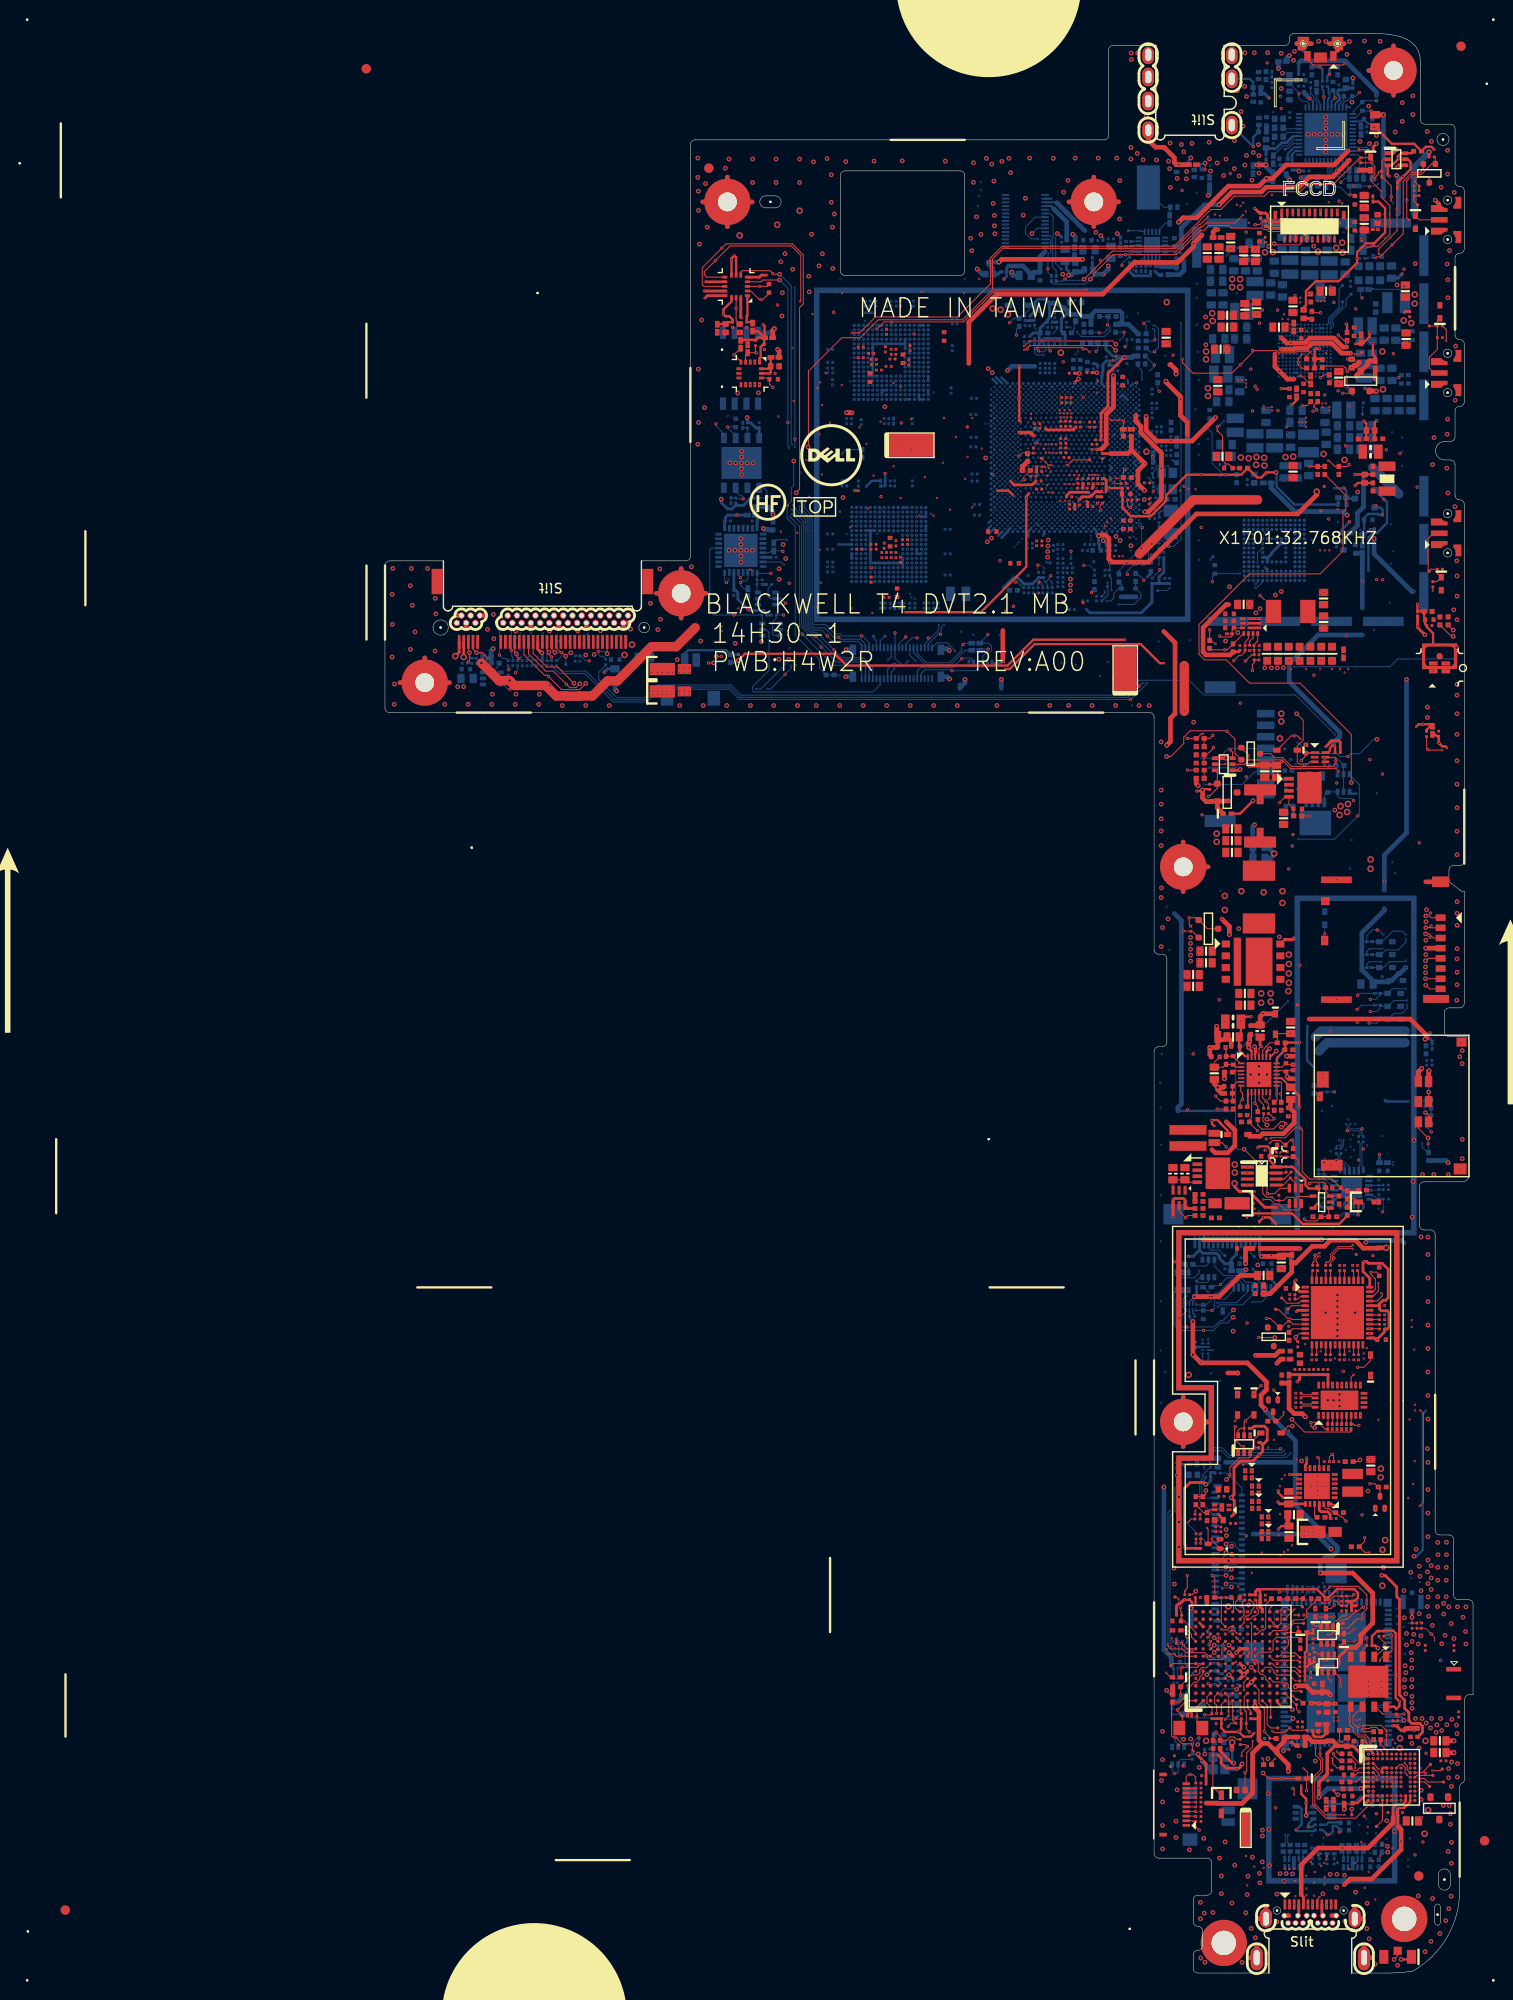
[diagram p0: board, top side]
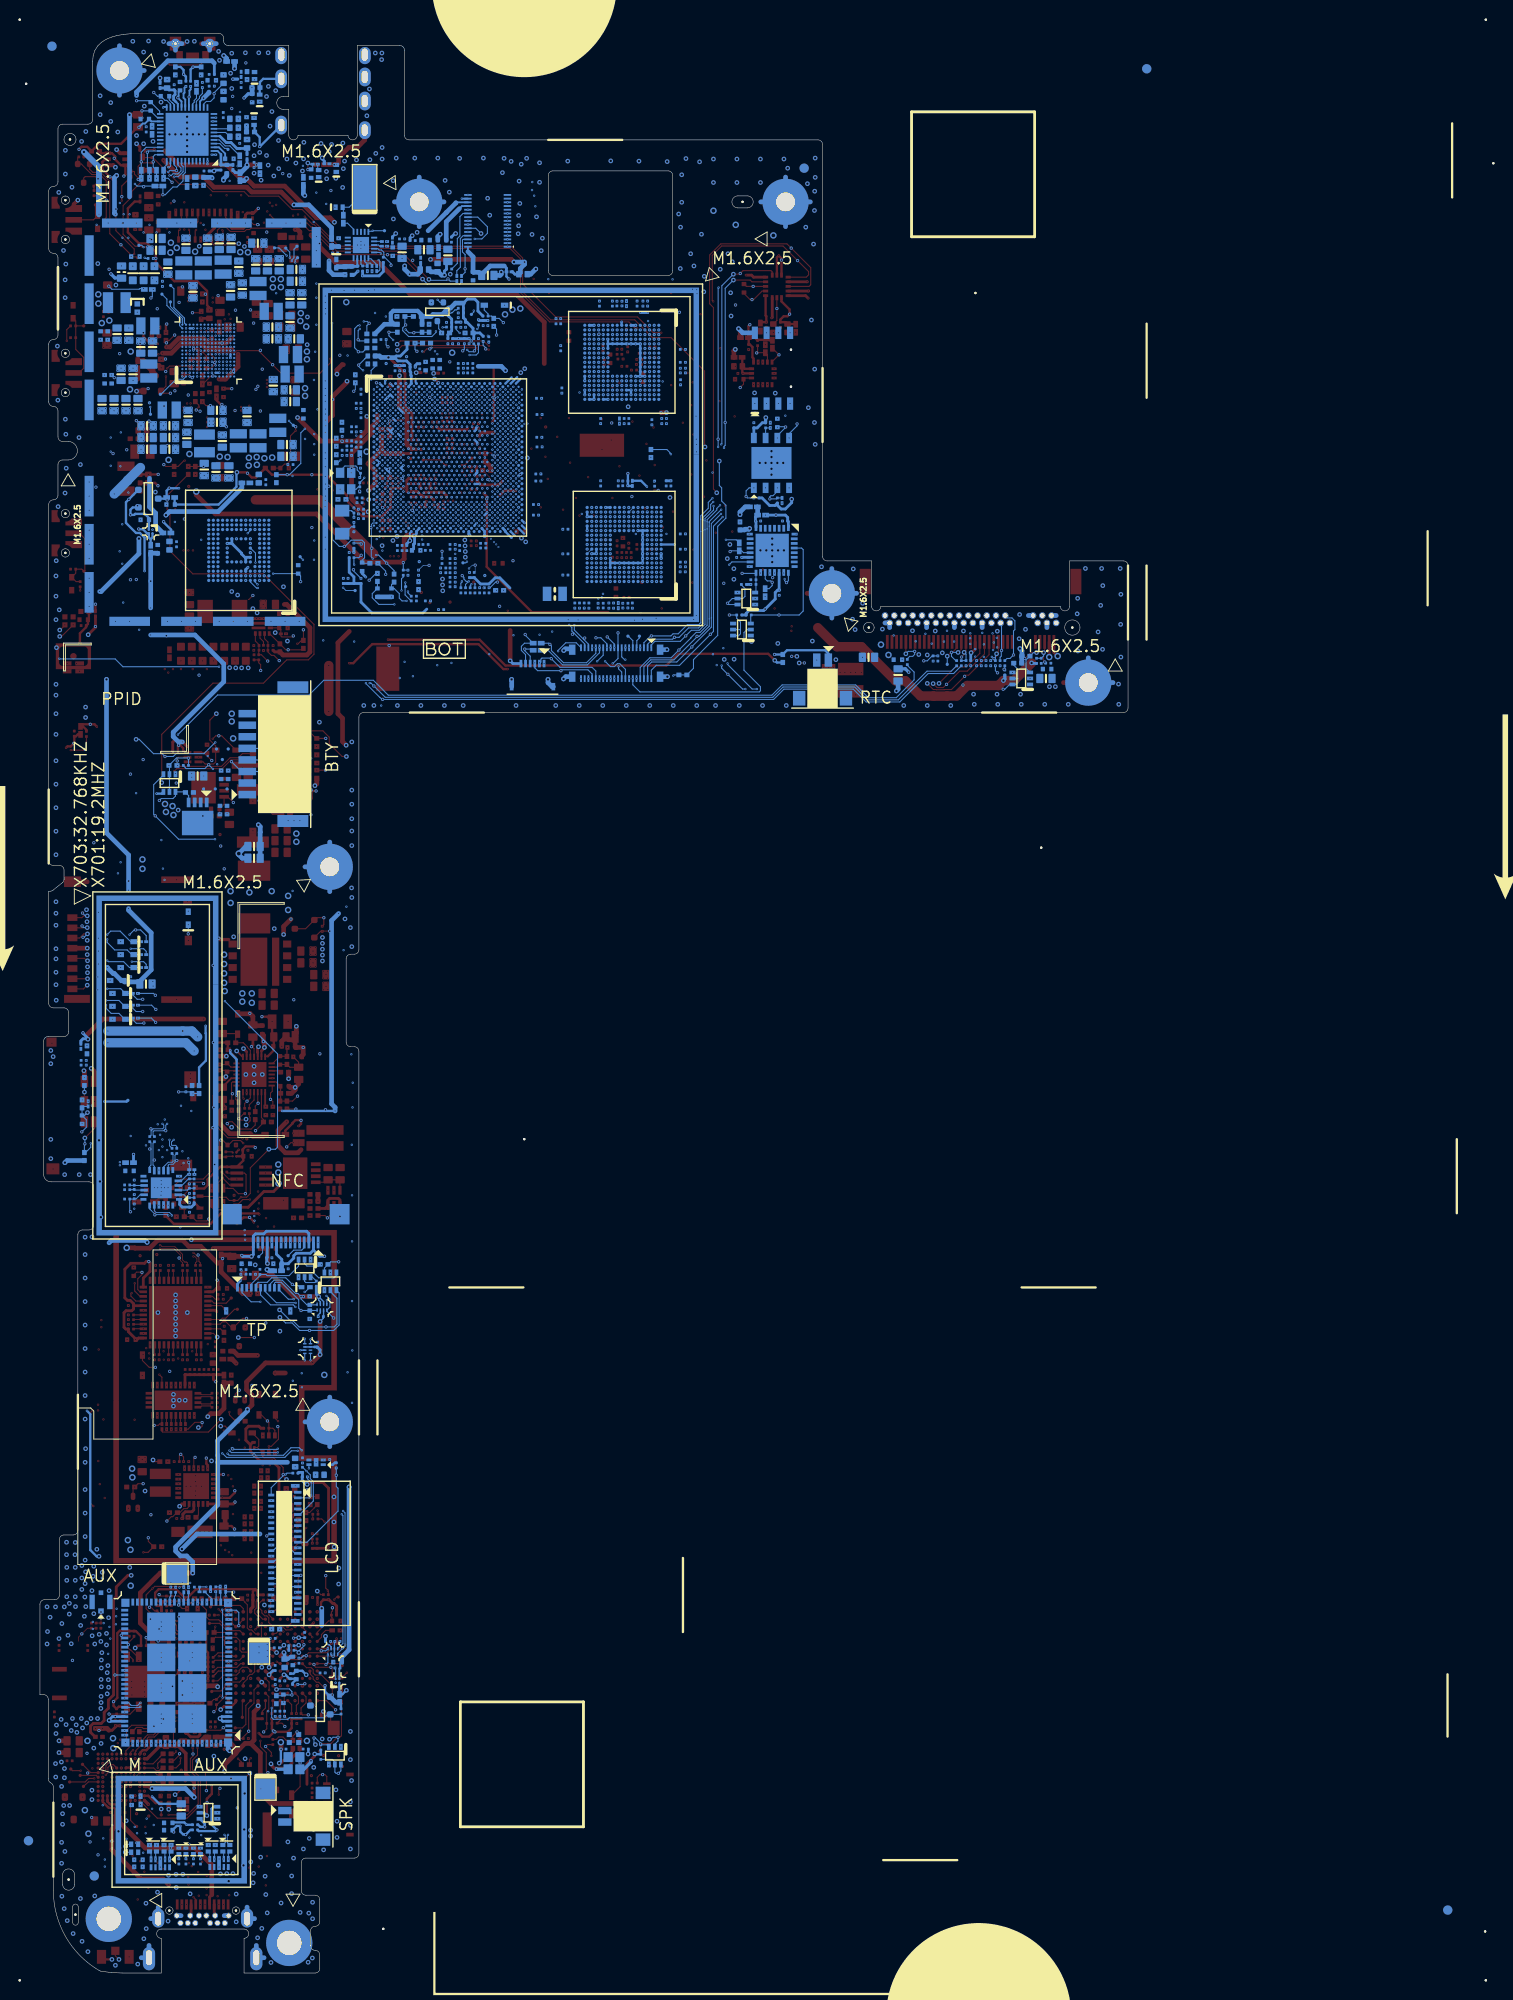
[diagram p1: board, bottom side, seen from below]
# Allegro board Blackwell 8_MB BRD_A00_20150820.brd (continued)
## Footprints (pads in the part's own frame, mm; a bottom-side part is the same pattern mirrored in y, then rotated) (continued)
QFN24G4-G2D8H32
  rect 0.305x0.635 smd: 1(1.25,1.93) 2(0.75,1.93) 3(0.25,1.93) 4(-0.25,1.93) 5(-0.75,1.93) 6(-1.25,1.93) 13(-1.25,-1.93) 14(-0.75,-1.93) 15(-0.25,-1.93) 16(0.25,-1.93) 17(0.75,-1.93) 18(1.25,-1.93)
  rect 0.635x0.305 smd: 7(-1.93,1.25) 8(-1.93,0.75) 9(-1.93,0.25) 10(-1.93,-0.25) 11(-1.93,-0.75) 12(-1.93,-1.25) 19(1.93,-1.25) 20(1.93,-0.75) 21(1.93,-0.25) 22(1.93,0.25) 23(1.93,0.75) 24(1.93,1.25)
  rect 2.794x2.794 smd: 25(0,0)
QFN28-G2D7H32
  rect 0.203x0.686 smd: 1(1.2,1.968) 2(0.8,1.968) 3(0.4,1.968) 4(0,1.968) 5(-0.4,1.968) 6(-0.8,1.968) 7(-1.2,1.968) 15(-1.2,-1.968) 16(-0.8,-1.968) 17(-0.4,-1.968) 18(0,-1.968) 19(0.4,-1.968) 20(0.8,-1.968) 21(1.2,-1.968)
  rect 0.686x0.203 smd: 8(-1.968,1.2) 9(-1.968,0.8) 10(-1.968,0.4) 11(-1.968,0) 12(-1.968,-0.4) 13(-1.968,-0.8) 14(-1.968,-1.2) 22(1.968,-1.2) 23(1.968,-0.8) 24(1.968,-0.4) 25(1.968,0) 26(1.968,0.4) 27(1.968,0.8) 28(1.968,1.2)
  rect 2.692x2.692 smd: 29(0,0)
QFN28-G4121H32
  rect 0.305x0.737 smd: 1(2.25,1.638) 2(1.75,1.638) 3(1.25,1.638) 4(0.75,1.638) 5(0.25,1.638) 6(-0.25,1.638) 7(-0.75,1.638) 8(-1.25,1.638) 9(-1.75,1.638) 10(-2.25,1.638) 15(-2.25,-1.638) 16(-1.75,-1.638) 17(-1.25,-1.638) 18(-0.75,-1.638) 19(-0.25,-1.638) 20(0.25,-1.638) 21(0.75,-1.638) 22(1.25,-1.638) 23(1.75,-1.638) 24(2.25,-1.638)
  rect 0.737x0.305 smd: 11(-2.642,0.75) 12(-2.642,0.25) 13(-2.642,-0.25) 14(-2.642,-0.75) 25(2.642,-0.75) 26(2.642,-0.25) 27(2.642,0.25) 28(2.642,0.75)
  rect 4.089x2.108 smd: 29(0,0)
QFN32G5-G3D6H32
  rect 0.305x0.66 smd: 1(1.75,2.487) 8(-1.75,2.487) 17(-1.75,-2.487) 24(1.75,-2.487)
  rect 0.305x0.737 smd: 2(1.25,2.449) 3(0.75,2.449) 4(0.25,2.449) 5(-0.25,2.449) 6(-0.75,2.449) 7(-1.25,2.449) 18(-1.25,-2.449) 19(-0.75,-2.449) 20(-0.25,-2.449) 21(0.25,-2.449) 22(0.75,-2.449) 23(1.25,-2.449)
  rect 0.66x0.305 smd: 9(-2.487,1.75) 16(-2.487,-1.75) 25(2.487,-1.75) 32(2.487,1.75)
  rect 0.737x0.305 smd: 10(-2.449,1.25) 11(-2.449,0.75) 12(-2.449,0.25) 13(-2.449,-0.25) 14(-2.449,-0.75) 15(-2.449,-1.25) 26(2.449,-1.25) 27(2.449,-0.75) 28(2.449,-0.25) 29(2.449,0.25) 30(2.449,0.75) 31(2.449,1.25)
  rect 3.607x3.607 smd: 33(0,0)
QFN48-G5D8H40
  rect 0.305x0.787 smd: 1(2.75,3.487) 2(2.25,3.487) 3(1.75,3.487) 4(1.25,3.487) 5(0.75,3.487) 6(0.25,3.487) 7(-0.25,3.487) 8(-0.75,3.487) 9(-1.25,3.487) 10(-1.75,3.487) 11(-2.25,3.487) 12(-2.75,3.487) 25(-2.75,-3.487) 26(-2.25,-3.487) 27(-1.75,-3.487) 28(-1.25,-3.487) 29(-0.75,-3.487) 30(-0.25,-3.487) 31(0.25,-3.487) 32(0.75,-3.487) 33(1.25,-3.487) 34(1.75,-3.487) 35(2.25,-3.487) 36(2.75,-3.487)
  rect 0.787x0.305 smd: 13(-3.487,2.75) 14(-3.487,2.25) 15(-3.487,1.75) 16(-3.487,1.25) 17(-3.487,0.75) 18(-3.487,0.25) 19(-3.487,-0.25) 20(-3.487,-0.75) 21(-3.487,-1.25) 22(-3.487,-1.75) 23(-3.487,-2.25) 24(-3.487,-2.75) 37(3.487,-2.75) 38(3.487,-2.25) 39(3.487,-1.75) 40(3.487,-1.25) 41(3.487,-0.75) 42(3.487,-0.25) 43(3.487,0.25) 44(3.487,0.75) 45(3.487,1.25) 46(3.487,1.75) 47(3.487,2.25) 48(3.487,2.75)
  rect 5.74x5.74 smd: 49(0,0)
QFN48J6-G465H40
  rect 0.203x0.711 smd: 1(2.2,2.962) 2(1.8,2.962) 3(1.4,2.962) 4(1,2.962) 5(0.6,2.962) 6(0.2,2.962) 7(-0.2,2.962) 8(-0.6,2.962) 9(-1,2.962) 10(-1.4,2.962) 11(-1.8,2.962) 12(-2.2,2.962) 25(-2.2,-2.962) 26(-1.8,-2.962) 27(-1.4,-2.962) 28(-1,-2.962) 29(-0.6,-2.962) 30(-0.2,-2.962) 31(0.2,-2.962) 32(0.6,-2.962) 33(1,-2.962) 34(1.4,-2.962) 35(1.8,-2.962) 36(2.2,-2.962)
  rect 0.711x0.203 smd: 13(-2.962,2.2) 14(-2.962,1.8) 15(-2.962,1.4) 16(-2.962,1) 17(-2.962,0.6) 18(-2.962,0.2) 19(-2.962,-0.2) 20(-2.962,-0.6) 21(-2.962,-1) 22(-2.962,-1.4) 23(-2.962,-1.8) 24(-2.962,-2.2) 37(2.962,-2.2) 38(2.962,-1.8) 39(2.962,-1.4) 40(2.962,-1) 41(2.962,-0.6) 42(2.962,-0.2) 43(2.962,0.2) 44(2.962,0.6) 45(2.962,1) 46(2.962,1.4) 47(2.962,1.8) 48(2.962,2.2)
  rect 4.648x4.648 smd: 49(0,0)
R0201H11
  custom 0.076x0.076 smd: 1(0,0.279) 2(0,-0.279)
R0201H12
  custom 0.076x0.076 smd: 1(0,0.279) 2(0,-0.279)
R402H14
  custom 0.127x0.127 smd: 1(0,0.432) 2(0,-0.432)
R402H16
  custom 0.127x0.127 smd: 1(0,0.432) 2(0,-0.432)
R603H22
  custom 0.197x0.197 smd: 1(0,0.66) 2(0,-0.66)
R805H24
  rect 1.549x0.94 smd: 1(0,0.838) 2(0,-0.838)
R1206H32
  rect 1.854x1.016 smd: 1(0,1.346) 2(0,-1.346)
R2512H32
  rect 3.454x1.219 smd: 1(0,2.819) 2(0,-2.819)
R3720H40
  rect 4.013x1.041 smd: 1(0,0.867) 2(0,-0.867)
S-OSC4-2520-3H40
  rect 1.092x0.914 smd: 1(-0.888,-0.6) 2(0.888,-0.6) 3(0.888,0.6) 4(-0.888,0.6)
SC70-5H44
  rect 0.356x0.762 smd: 1(0.65,0.935) 2(0,0.935) 3(-0.65,0.935) 4(-0.65,-0.935) 5(0.65,-0.935)
SC70-6H44
  rect 0.406x0.66 smd: 1(-0.65,-0.95) 2(0,-0.95) 3(0.65,-0.95) 4(0.65,0.95) 5(0,0.95) 6(-0.65,0.95)
SC75-1D6-312H24
  custom 0.127x0.127 smd: 1(-0.508,-0.648) 2(0.508,-0.648) 3(0,0.648)
SF56S006V4AR2000
  rect 1.194x0.813 smd: 1(2.66,-11.44) 2(0.47,-11.44) 3(-1.72,-11.44) 5(2.66,-10.34) 6(0.47,-10.34) 7(-1.72,-10.34)
  rect 1.194x1.397 smd: 8(-6.8,-14.85)
  rect 1.194x2.362 smd: 9(-6.4,-0.975)
  rect 0.991x0.66 smd: 10(1,0.325)
  rect 1.753x1.295 smd: 11(2.87,0)
  rect 0.991x1.092 smd: 12(6.9,-15)
SKRTLAE010-U
  round 0.254 hole 0.914 unplated: (-2.125,0) (2.125,0)
  custom 0.191x0.191 smd: 1(-1.225,0.902) 3(1.225,0.902)
  rect 0.61x1.803 smd: 2(0,0.902)
  custom 0.222x0.222 smd: 6(-1.85,-1.05) 7(1.85,-1.05)
SKT520X1447-24
  rect 0.025x0.025 smd: 1(-0.089,18.11) 2(6.299,10.173) 3(6.274,-10.033) 4(-6.312,-14.77) 5(-6.287,5.093)
SKT560X460-24
  rect 0.025x0.025 smd: 1(-3.518,5.524) 2(6.782,5.474) 3(6.731,-5.448) 4(-3.404,-5.55) 5(-6.82,1.232)
SKT951X1419-24-S
  rect 0.025x0.025 smd: 1(-11.748,17.604) 2(-8.343,-6.612) 3(-11.721,-17.712) 4(11.766,-17.658) 5(11.697,17.611)
SKT1603X1424-24
  rect 0.025x0.025 smd: 1(-19.988,17.725) 2(4.226,17.75) 3(19.988,2.138) 4(0.05,-17.8) 5(-20.087,2.138)
SKT-SOIC8-2-UH121
  round 0.254 hole 1.067 unplated: (-2,0)
  round 0.254 hole 0.864 unplated: (2,0)
  rect 1.346x0.66 smd: 1(3.825,-3.905) 2(3.825,-2.635) 3(3.825,-1.365) 4(3.825,-0.095) 5(-3.825,-0.095) 6(-3.825,-1.365) 7(-3.825,-2.635) 8(-3.825,-3.905)
SKT-USB30-118098-U1
  round 0.254 hole 0.813 unplated: (-3.6,5.1) (3.6,5.1)
  oval 1.321x2.057 hole 0.61x1.473: 13(-4.8,4.225) 14(4.8,4.225)
  oval 1.321x2.515 hole 0.61x1.6: 15(-5.8,0) 16(5.8,0)
  rect 0.305x1.092 smd: A1(-2.75,5.76) A2(-2.25,5.76) A3(-1.75,5.76) A4(-1.25,5.76) A5(-0.75,5.76) A6(-0.25,5.76) A7(0.25,5.76) A8(0.75,5.76) A9(1.25,5.76) A10(1.75,5.76) A11(2.25,5.76) A12(2.75,5.76)
  round 0.635 hole 0.406: B1(2.8,4.55) B2(2.4,3.75) B3(1.6,3.75) B4(1.35,4.55) B5(0.8,3.75) B6(0.4,4.55) B7(-0.4,4.55) B8(-0.8,3.75) B9(-1.35,4.55) B10(-1.6,3.75) B11(-2.4,3.75) B12(-2.8,4.55)
SKTDLDE010
  rect 0.711x1.092 smd: 1(-1.4,1.35) 2(1.4,1.35)
  rect 1.397x1.092 smd: 3(0,1.5)
  custom 0.311x0.311 hole 0.711: 4(-1.85,0) 5(1.85,0)
SMD49-3215-0713H36
  rect 1.549x1.295 smd: 1(0,1.244) 2(0,-1.244)
SOD123AK-3719-UH40
  rect 1.092x1.448 smd: A(0,1.52)
  rect 1.346x2.743 smd: K(0,-0.872)
SOD323-2513AKH36
  rect 0.559x1.041 smd: A(0,0.987) K(0,-0.987)
SOD323AKH38
  rect 0.559x0.813 smd: A(0,1.1) K(0,-1.1)
SOD882-10D6-1H20
  rect 0.61x0.457 smd: 1(0,0.457) 2(0,-0.457)
SOD923-10D6AKH16
  rect 0.457x0.61 smd: A(0,0.451) K(0,-0.451)
SOD-523-4H28
  rect 0.559x0.711 smd: 1(0,0.702) 2(0,-0.702)
SOT23-2D4-312H48
  custom 0.171x0.171 smd: 1(-0.95,-1.069) 2(0.95,-1.069) 3(0,1.069)
SOT23-2D8-123H52
  custom 0.171x0.171 smd: 1(0,1.21) 2(-0.95,-1.21) 3(0.95,-1.21)
SOT23DGS2D4H45
  custom 0.171x0.171 smd: D(0,1.069) G(-0.95,-1.069) S(0.95,-1.069)
SOT-23-10H44
  custom 0.165x0.165 smd: 1(-0.95,-1.054) 2(0.95,-1.054) 3(0,1.054)
SOT-323H44
  custom 0.152x0.152 smd: 1(-0.65,-1.011) 2(0.65,-1.011) 3(0,1.011)
SOT-363H44
  rect 0.356x0.965 smd: 1(-0.65,-0.826) 2(0,-0.826) 3(0.65,-0.826) 4(0.65,0.826) 5(0,0.826) 6(-0.65,0.826)
SPR4013-1H75
  rect 3.683x0.991 smd: 1(-1.181,0)
SPR5128H111
  rect 4.801x2.489 smd: 1(-1.397,0)
SPR260243H68
  rect 2.286x2.134 smd: 1(-0.8,0)
SSOIC8H44
  rect 0.356x1.397 smd: 1(-0.975,-1.555) 2(-0.325,-1.555) 3(0.325,-1.555) 4(0.975,-1.555) 5(0.975,1.555) 6(0.325,1.555) 7(-0.325,1.555) 8(-0.975,1.555)
SUL-1315A1M
  rect 4.394x0.991 smd: 1(0,0)
TPAD14-OP
  round 0.356 smd: 1(0,0)
unnamed
  round 0.254 hole 2.184 unplated: (0,0)
VARISTOR-402-H19
  rect 0.559x0.559 smd: 1(0,0.432) 2(0,-0.432)
WM7211IMS-RV
  rect 0.94x0.457 smd: 1(0.675,0.425) 2(-0.675,0.425) 3(-0.675,-0.425) 4(0.675,-0.425)
  custom 0.699x0.699 smd: 5(0,-1.199)
XSON8-1410H20
  rect 0.152x0.381 smd: 1(0.525,0.31) 2(0.175,0.31) 3(-0.175,0.31) 4(-0.525,0.31) 5(-0.525,-0.31) 6(-0.175,-0.31) 7(0.175,-0.31) 8(0.525,-0.31)

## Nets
3V3_EC_EN: D5411.2 R1723.2 U1703.A2
3V3_EC_VIN: C1701.1 D1706.K Q1703.S R1719.2 R1723.1 R5412.2 U1703.B2
3V3_EC_VIN_ON#: Q1703.G R1719.1 U1706.6
5V_COMP: C5228.1 R5216.2
5V_EN: R5211.2 R5217.2 U5202.7
5V_FB: R5216.1 R5218.1 R5219.2 U5202.10
5V_LBI: R5212.2 R5213.2 U5202.8
5V_LBO: R5215.1 U5202.9
5V_LX: L5202.2 U5202.2
5V_SVOUT: C5224.1 R5214.1 U5202.6
+AVDD_CAM_FRONT: C2511.1 C2512.1 C2513.1 CAMF1.2 R2515.2
+AVDD_CAM_REAR: C2503.1 C2504.1 C2506.1 CAMR1.19 R2514.2
+V1P2_FRONT: C2519.1 C2521.1 CAMF1.11 R2511.2
+V1P2_REAR: C2518.1 C2520.1 R2510.2 R2517.1
+V1P2A: C1140.1 C1142.1 C1143.1 CPU1.A9 CPU1.A11 CPU1.AA1 CPU1.AB2 CPU1.AF18 CPU1.B10 PC4902.1 PC4910.1 PMIC1.H12 PMIC1.J13
+V1P2SX: PC4913.1 PMIC1.H13 R2510.1 R2511.1
+V1P05A: C1117.1 C1118.1 C1119.1 C1120.1 C1121.1 C1122.1 C1141.1 C1165.1 C1166.1 C1167.1 C1168.1 C1169.1 C1170.1 C1181.1 C1184.1 C1185.1 C1200.1 C1201.1 CPU1.A41 CPU1.A43 CPU1.AA42 CPU1.AD29 CPU1.AE1 CPU1.AF24 CPU1.AF26 CPU1.AG1 CPU1.AK1 CPU1.AU18 CPU1.AW17 CPU1.AW19 CPU1.AW42 CPU1.B40 CPU1.BA16 CPU1.BA18 CPU1.BF2 CPU1.BG1 CPU1.BV40 CPU1.BW41 CPU1.BW43 PC4715.1 PC4716.1 PC4730.1 PC4906.1 PL4705.2 PMIC1.D13 PMIC1.N5 R802.1 R806.1
+V1P05A_PCIE_STAT: CPU1.AU1 CPU1.AW1 R802.2
+V1P8_CODEC: R2002.1 R2015.2 R2018.2 R2019.2 R2020.2
+V1P8_REAR: C2501.1 C2502.1 C2505.1 CAMR1.18 R2512.2
+V1P8A: BIOS1.8 BSKT1.8 C1127.1 C1128.1 C1129.1 C1130.1 C1131.1 C1132.1 C1136.1 C1137.1 C1183.1 C1709.1 C1723.1 C1803.1 C3408.1 C3409.1 C4308.1 CPU1.A15 CPU1.AC18 CPU1.B14 CPU1.BB17 CPU1.BD28 CPU1.BD31 CPU1.BF29 CPU1.BV22 CPU1.BV26 CPU1.BV32 CPU1.BW21 CPU1.BW23 CPU1.BW25 CPU1.BW27 CPU1.BW33 DB2.6 PC4804.1 PC4818.1 PC4837.1 PC4908.1 PC4912.1 PC5003.1 PL4803.2 PMIC1.C7 PMIC1.C10 PMIC1.G5 PMIC1.M8 PMIC1.N11 PR4907.1 PR4908.1 PR4909.1 PR5106.2 R408.1 R410.1 R411.1 R417.1 R507.1 R508.1 R509.1 R511.1 R514.2 R604.1 R624.2 R625.2 R626.2 R627.2 R628.2 R629.2 R630.2 R631.2 R632.2 R633.2 R634.2 R635.2 R636.2 R637.2 R645.2 R647.2 R666.2 R667.2 R704.2 R705.1 R707.2 R713.2 R719.2 R720.2 R724.1 R731.2 R732.2 R733.2 R734.1 R735.1 R736.1 R740.1 R742.1 R751.1 R753.1 R1502.1 R1602.1 R1803.1 R1804.1 R1805.1 R2015.1 R2104.1 R3904.1 R4005.1 R4018.2 R4101.1 R4104.1 R4106.1 R4201.1 R5401.1 U1702.3 U1702.6 U1707.3 U1707.6 U3403.3 U4301.3 WR3706.2
+V1P8A_DE303_VDDIO: C4203.1 ECOMP3.1 ECOMP3.7 ECOMP3.8 R4204.2
+V1P8A_EMMC_VCCQ: C1601.1 C1605.1 EMMC1.C6 EMMC1.M4 EMMC1.N4 EMMC1.P3 EMMC1.P5 R1602.2
+V1P8A_MEM: C1505.1 C1506.1 C1507.1 C1508.1 C1514.1 C1515.1 C1516.1 C1517.1 R1502.2 RAM1.A15 RAM1.A16 RAM1.B2 RAM1.R1 RAM1.T1 RAM1.T16 RAM2.A15 RAM2.A16 RAM2.B2 RAM2.R1 RAM2.T1 RAM2.T16
+V1P8A_SENSOR: C4206.1 GYRO1.1 R4201.2 R4204.1 R4207.1 R4209.2
+V1P8A_WIFI: WC3705.1 WR3703.1 WR3706.1 WR3708.1
+V1P8DVDD_FRONT: C2510.1 C2514.1 CAMF1.10 R2504.2 R2513.2
+V1P8SX: C2516.1 C2517.1 PC4909.1 PMIC1.C8 R2512.1 R2513.1
+V1P15: C1156.1 C1157.1 C1158.1 C1159.1 C1160.1 C1161.1 C1162.1 C1163.1 C1164.1 CPU1.A30 CPU1.A33 CPU1.A35 CPU1.A37 CPU1.AA25 CPU1.AD40 CPU1.B36 CPU1.BV36 CPU1.BW35 CPU1.BW37 CPU1.W24 CPU1.W39 PC4801.1 PC4802.1 PC4803.1 PC4836.1 PL4802.2 PMIC1.K13
+V2P8_CAM_VCM: C2508.1 C2509.1 CAMR1.30 R2509.2
+V2P8SX: C2507.1 C2515.1 PC4915.1 PMIC1.C4 R2509.1 R2514.1 R2515.1
+V2P85S_EMMC_VCC: C1602.1 C1603.1 EMMC1.E6 EMMC1.F5 EMMC1.J10 EMMC1.K9 R1601.2
+V3P3_EC: C1704.1 C1708.1 C1713.1 C1714.1 C1718.1 C1719.1 C1721.1 C1727.1 C1728.1 C1729.1 C1730.1 C1731.1 C1732.1 LED1.1 Q1702.D R421.1 R422.1 R423.1 R1701.1 R1705.2 R1706.2 R1707.2 R1708.2 R1710.2 R1713.2 R1716.2 R1717.2 R1718.2 R1720.2 R1724.2 R1725.2 R1726.2 R1729.1 R1730.1 R1732.2 R1733.2 R1734.2 R1735.2 R1736.1 R1738.2 R1740.2 R1741.1 R1743.1 R1745.2 R1746.2 R1747.1 R1748.2 R1752.1 R1757.1 R1759.1 R1761.1 R1763.2 R1764.2 R1765.2 R1767.2 R1769.2 R1775.1 R1776.1 R1777.1 R1778.1 R1779.1 R1780.1 R1786.1 R1789.1 R2924.1 U1702.7 U1704.G6 U1704.G8 U1704.H3 U1704.H8 U1704.J1 U1704.J4 U1704.K13 U1707.7
+V3P3_EC_L: Q1702.S R1721.2 R1742.1
+V3P3_EC_VBAT: C1702.1 C1705.1 C1726.1 R1702.2 R1721.1 R1781.1 R1782.1 R1783.1 R1784.1 R1785.1 R2925.2 U1703.B1 U1704.F4
+V3P3_G601A31: R5412.1 U5401.6
+V3P3_MUX: C3102.1 C3103.1 C3104.1 C3105.1 C3106.1 C3107.1 C3108.1 C3127.1 R3101.1 U3101.22
+V3P3_SAR: C4101.1 C4102.1 D1708.K R4102.2 U4101.11
+V3P3_TPM: C5704.1 C5705.1 C5706.1 R5706.2 R5707.2 R5717.2 R5720.1 R5725.2 R5726.1 U5702.8 U5702.14 U5702.22
+V3P3_TPM_VSB: C5703.1 R5705.2 R5707.1 U5702.1
+V3P3_TPS65982: C2913.1 R2922.1 R2924.2 R2925.1 R3101.2 U2901.B1 U2901.H1
+V3P3A: C1126.1 C1133.1 C1134.1 C1135.1 C1182.1 C1188.1 C1190.1 CPU1.AU14 CPU1.BD14 CPU1.BF25 CPU1.BV18 CPU1.BW17 CPU1.N1 CPU1.P2 PC4822.1 PC4823.1 PC4824.1 PC4825.1 PC4826.1 PC4827.1 PC5001.1 PMIC1.C1 PMIC1.C2 PMIC1.D12 PMIC1.E3 R1601.1 R1709.1 R2021.1 R2922.2 R3019.1 R3146.1 R3902.1 R4102.1 R4202.1 R4301.1 R5706.1 WC3703.1 WR3707.2
+V3P3A_DE303_VDD: C4201.1 C4202.1 ECOMP3.14 R4203.2
+V3P3A_SENSOR: C4207.1 C4208.1 GYRO1.15 GYRO1.16 R3807.1 R4202.2 R4203.1 R4205.2
+V3P3SX: C3401.1 C3402.1 PC4828.1 PC4829.1 PC4830.1 PC4832.1 PC4833.1 PC4834.1 PC4905.1 PC4916.1 PMIC1.A3 PMIC1.B3 PMIC1.C5 PMIC1.D4 PQ4901.S R3020.1 R4302.1 R5705.1 U3401.3
+V3P3SX_SD: PC4917.1 PMIC1.D3 PQ4901.D PR4913.1
+V3P3SX_SD_CONN: C2301.1 C2302.1 D2305.1 MSD1.4 PR4913.2
+V5P0_BOOST: C2903.1 C2904.1 C2905.1 CLED1.A PC4919.1 PMIC1.C13 R2027.1 R2923.1 R3905.1 R4801.2 U2901.A11 U2901.B11 U2901.C11 U2901.D11 U2901.H10
+V5P0_BOOST_PMIC: PC4813.1 PC4815.1 PC4817.1 PMIC1.A13 PMIC1.B13 R4801.1
+V5P0_BOOST_R: C5216.1 C5217.1 C5220.1 C5221.1 C5222.1 C5225.1 C5226.1 C5228.2 R2923.2 R5214.2 R5215.2 R5218.2 U5202.1
+VBATA_CHARGER: PC4714.1 PC4717.1 PC4718.1 PC4719.1 PC4720.1 PC4721.1 PC4722.1 PC4811.1 PMIC1.J1 PMIC1.K1 PMIC1.K14 PMIC1.K15 PMIC1.L14 PMIC1.L15 PMIC1.M1 PMIC1.P5 PMIC1.P10 PMIC1.P11 PMIC1.R4 PMIC1.R5 PMIC1.R10 PMIC1.R11 PR4901.2 PR4905.2
+VBATA_CHARGER_R: PC4812.1 PC4814.1 PC4816.1 PC4820.1 PC4831.1 PC4918.1 PL4801.2 PMIC1.A7 PMIC1.A8 PMIC1.B7 PMIC1.B8 PMIC1.E14 PMIC1.E15 PMIC1.G1 PMIC1.G2 PMIC1.H9 PMIC1.L3 PR4901.1 PR4903.2 PR4904.2 PR4906.2 PR5001.1 PR5002.1 PR5105.1
+VBATT_SW: D4001.A D4002.A PC4617.1 PC4628.1 PD4605.A PR4605.1 PR5110.1 PU4602.5 PU4602.6 PU4602.7 PU4602.8 Q4501.5 Q4501.6 Q4501.7 Q4501.8
+VBATTERY: BATT1.1 BATT1.2 D1706.A PC4501.1 PC4502.1 PC4503.1 PC4504.1 PC4505.1 PC5103.1 PR5114.1 Q4501.1 Q4501.2 Q4501.3 R4501.1 TP4501.1 TP4502.1 TP4503.1
+VCC0_CPU: C1101.1 C1102.1 C1103.1 C1104.1 C1105.1 C1106.1 C1192.1 C1193.1 C1194.1 C1195.1 CPU1.A19 CPU1.A21 CPU1.B18 CPU1.B22 CPU1.P32 CPU1.P34 CPU1.P36 CPU1.P38 CPU1.T31 CPU1.T33 CPU1.T35 CPU1.T37 CPU1.V32 CPU1.V34 CPU1.V36 CPU1.W33 CPU1.W35 CPU1.W37 PC4701.1 PC4702.1 PC4703.1 PC4707.1 PC4723.1 PL4706.2
+VCC1_CPU: C1115.1 C1116.1 C1152.1 C1153.1 C1154.1 C1155.1 CPU1.A23 CPU1.A25 CPU1.AD32 CPU1.AD34 CPU1.AD36 CPU1.AD38 CPU1.AF33 CPU1.AF35 CPU1.AF37 CPU1.AH32 CPU1.AH34 CPU1.AH36 CPU1.AH38 CPU1.AK33 CPU1.AK35 CPU1.AK37 CPU1.B24 CPU1.B26 CPU1.C23 CPU1.D24 CPU1.E23 CPU1.F24 CPU1.G23 CPU1.H24 CPU1.J23 CPU1.J25 CPU1.K24 CPU1.L23 CPU1.L25 CPU1.M24 CPU1.M26 CPU1.M28 CPU1.P25 CPU1.P27 PC4704.1 PC4705.1 PC4706.1 PC4724.1 PC4725.1 PL4707.2
+VDD3V3_WIFI: WC3701.1 WC3702.1 WC3704.1 WC3715.1 WC3716.1 WC3717.1 WC3718.1 WR3707.1 WU3701.4 WU3701.5 WU3701.72 WU3701.73
+VDDQ_PMIC: C1113.1 C1114.1 C1123.1 C1124.1 C1125.1 C1171.1 C1172.1 C1173.1 C1174.1 C1175.1 C1176.1 C1177.1 C1178.1 C1179.1 C1180.1 C1186.1 C1187.1 C1202.1 C1203.1 C1204.1 C1501.1 C1502.1 C1503.1 C1504.1 C1509.1 C1510.1 C1511.1 C1512.1 C1513.1 C1519.1 C1520.1 C1523.1 C1525.1 C1526.1 C1531.1 C1532.1 C1533.1 C1534.1 C1539.1 C1540.1 C1541.1 C1542.1 C1547.1 C1553.1 CPU1.AA59 CPU1.AC41 CPU1.AC59 CPU1.AD42 CPU1.AE59 CPU1.AF14 CPU1.AK28 CPU1.AK31 CPU1.AR59 CPU1.AT42 CPU1.AU41 CPU1.AU59 CPU1.AW59 CPU1.BA59 CPU1.BB2 CPU1.BC1 CPU1.BG59 CPU1.BJ1 CPU1.BJ59 CPU1.BL59 CPU1.BN59 CPU1.G1 CPU1.G59 CPU1.J1 CPU1.J59 CPU1.L1 CPU1.L59 CPU1.M2 CPU1.N59 CPU1.U1 CPU1.V2 CPU1.W1 CPU1.W31 CPU1.W59 PC4805.1 PC4806.1 PC4807.1 PC4808.1 PC4809.1 PC4810.1 PC4819.1 PC4821.1 PC4839.1 PC4840.1 PC4841.1 PC4842.1 PC4907.1 PL4804.2 PL4805.2 PMIC1.G12 PMIC1.J12 R805.2 R1324.1 R1326.1 R1424.1 R1426.1 RAM1.A6 RAM1.A7 RAM1.A9 RAM1.A11 RAM1.A13 RAM1.B9 RAM1.B12 RAM1.B17 RAM1.C3 RAM1.C12 RAM1.C17 RAM1.E1 RAM1.E17 RAM1.G2 RAM1.G12 RAM1.G17 RAM1.H1 RAM1.H16 RAM1.K1 RAM1.K12 RAM1.K17 RAM1.L1 RAM1.L17 RAM1.M2 RAM1.M3 RAM1.M7 RAM1.M10 RAM1.M12 RAM1.N1 RAM1.P17 RAM1.R15 RAM1.T8 RAM1.U2 RAM1.U3 RAM1.U5 RAM1.U7 RAM1.U10 RAM1.U11 RAM1.U14 RAM2.A6 RAM2.A7 RAM2.A9 RAM2.A11 RAM2.A13 RAM2.B9 RAM2.B12 RAM2.B17 RAM2.C3 RAM2.C12 RAM2.C17 RAM2.E1 RAM2.E17 RAM2.G2 RAM2.G12 RAM2.G17 RAM2.H1 RAM2.H16 RAM2.K1 RAM2.K12 RAM2.K17 RAM2.L1 RAM2.L17 RAM2.M2 RAM2.M3 RAM2.M7 RAM2.M10 RAM2.M12 RAM2.N1 RAM2.P17 RAM2.R15 RAM2.T8 RAM2.U2 RAM2.U3 RAM2.U5 RAM2.U7 RAM2.U10 RAM2.U11 RAM2.U14
+VDDQ_VTT: C1312.1 C1313.1 C1314.1 C1402.1 C1403.1 C1404.1 C1405.1 C1406.1 C1407.1 C1408.1 C1409.1 PC4901.1 PMIC1.E13 R1309.2 R1310.2 R1311.2 R1312.2 R1313.2 R1314.2 R1315.2 R1316.2 R1317.2 R1318.2 R1409.2 R1410.2 R1411.2 R1412.2 R1413.2 R1414.2 R1415.2 R1416.2 R1417.2 R1418.2
+VDDR3_M0_OCAVREF: R310.1 R1324.2 R1325.1 RAM1.A10 RAM1.J1
+VDDR3_M0_ODQVREF: R309.1 R1326.2 R1327.1 RAM1.H17 RAM1.U8
+VDDR3_M1_OCAVREF: R312.1 R1424.2 R1425.1 RAM2.A10 RAM2.J1
+VDDR3_M1_OCAVREF_R: CPU1.BD48 R312.2
+VDDR3_M1_ODQVREF: R311.1 R1426.2 R1427.1 RAM2.H17 RAM2.U8
+VDDR3_M1_ODQVREF_R: CPU1.BD50 R311.2
+VIN_5V_19V: PR4619.2 PR4626.2 PR4633.1 PU4604.5 PU4604.6 PU4604.7 PU4604.8 R1727.1 U2901.A6 U2901.A7 U2901.A8 U2901.B7
DVDD_REAR: CAMR1.17 R2517.2
GND: ANT1.2 ANT1.3 ANT1.4 BATT1.6 BATT1.7 BATT1.8 BATT1.9 BATT1.10 BIOS1.4 BIOS1.9 BSKT1.4 C501.2 C701.1 C702.1 C706.2 C707.2 C708.2 C709.2 C710.2 C711.2 C712.2 C1101.2 C1102.2 C1103.2 C1104.2 C1105.2 C1106.2 C1107.2 C1108.2 C1109.2 C1110.2 C1111.2 C1112.2 C1113.2 C1114.2 C1115.2 C1116.2 C1117.2 C1118.2 C1119.2 C1120.2 C1121.2 C1122.2 C1123.2 C1124.2 C1125.2 C1126.2 C1127.2 C1128.2 C1129.2 C1130.2 C1131.2 C1132.2 C1133.2 C1134.2 C1135.2 C1136.2 C1137.2 C1138.2 C1139.2 C1140.2 C1141.2 C1142.2 C1143.2 C1144.2 C1145.2 C1146.2 C1147.2 C1148.2 C1149.2 C1150.2 C1151.2 C1152.2 C1153.2 C1154.2 C1155.2 C1156.2 C1157.2 C1158.2 C1159.2 C1160.2 C1161.2 C1162.2 C1163.2 C1164.2 C1165.2 C1166.2 C1167.2 C1168.2 C1169.2 C1170.2 C1171.2 C1172.2 C1173.2 C1174.2 C1175.2 C1176.2 C1177.2 C1178.2 C1179.2 C1180.2 C1181.2 C1182.2 C1183.2 C1184.2 C1185.2 C1186.2 C1187.2 C1188.2 C1189.2 C1190.2 C1191.2 C1192.2 C1193.2 C1194.2 C1195.2 C1196.2 C1197.2 C1198.2 C1199.2 C1200.2 C1201.2 C1202.2 C1203.2 C1204.2 C1312.2 C1313.2 C1314.2 C1402.2 C1403.2 C1404.2 C1405.2 C1406.2 C1407.2 C1408.2 C1409.2 C1501.2 C1502.2 C1503.2 C1504.2 C1505.2 C1506.2 C1507.2 C1508.2 C1509.2 C1510.2 C1511.2 C1512.2 C1513.2 C1514.2 C1515.2 C1516.2 C1517.2 C1519.2 C1520.2 C1523.2 C1525.2 C1526.2 C1531.2 C1532.2 C1533.2 C1534.2 C1539.2 C1540.2 C1541.2 C1542.2 C1547.2 C1553.2 C1601.2 C1602.2 C1603.2 C1605.2 C1606.1 C1701.2 C1702.2 C1703.1 C1704.2 C1705.2 C1706.2 C1708.2 C1709.2 C1710.2 C1711.2 C1712.2 C1713.2 C1714.2 C1717.2 C1718.2 C1719.2 C1720.2 C1721.2 C1722.2 C1723.2 C1726.2 C1727.2 C1728.2 C1729.2 C1730.2 C1731.2 C1732.2 C1802.1 C1803.2 C2014.2 C2015.2 C2020.2 C2021.2 C2022.2 C2101.2 C2102.2 C2103.2 C2104.2 C2204.1 C2205.1 C2301.2 C2302.2 C2401.1 C2402.2 C2403.2 C2404.2 C2501.2 C2502.2 C2503.2 C2504.2 C2505.2 C2506.2 C2507.2 C2508.2 C2509.2 C2510.2 C2511.2 C2512.2 C2513.2 C2514.2 C2515.2 C2516.2 C2517.2 C2518.2 C2519.2 C2520.2 C2521.2 C2902.1 C2903.2 C2904.2 C2905.2 C2906.2 C2907.2 C2908.2 C2909.2 C2910.2 C2911.2 C2912.2 C2913.2 C2914.2 C2915.2 C2916.2 C2917.2 C2918.2 C3024.2 C3025.2 C3031.2 C3032.2 C3033.2 C3102.2 C3103.2 C3104.2 C3105.2 C3106.2 C3107.2 C3108.2 C3127.2 C3132.2 C3133.2 C3401.2 C3402.2 C3403.2 C3404.2 C3405.2 C3406.2 C3407.2 C3408.2 C3409.2 C3410.2 C3901.2 C3902.2 C3903.2 C3904.2 C3905.2 C4001.2 C4002.2 C4006.2 C4007.2 C4008.2 C4009.2 C4010.2 C4101.2 C4102.2 C4103.2 C4104.2 C4201.2 C4202.2 C4203.2 C4206.2 C4207.2 C4208.2 C4209.2 C4210.2 C4301.2 C4302.2 C4303.2 C4304.2 C4305.2 C4306.2 C4308.2 C4309.2 C4401.2 C4402.2 C4404.2 C4405.2 C4406.2 C5215.2 C5216.2 C5217.2 C5218.2 C5219.2 C5220.2 C5221.2 C5222.2 C5223.2 C5224.2 C5225.2 C5226.2 C5227.2 C5401.2 C5402.1 C5403.1 C5404.1 C5405.1 C5406.2 C5703.2 C5704.2 C5705.2 C5706.2 C5707.2 C5710.2 C5711.2 C5712.2 C5713.2 C5714.2 CABLE1.1 CABLE2.1 CABLE3.1 CAMF1.7 CAMF1.9 CAMF1.12 CAMF1.15 CAMF1.18 CAMF1.21 CAMF1.22 CAMF1.23 CAMR1.1 CAMR1.4 CAMR1.7 CAMR1.10 CAMR1.13 CAMR1.16 CAMR1.20 CAMR1.23 CAMR1.24 CAMR1.26 CAMR1.29 CN1.1 CN2.1 CN3.1 CN4.1 CN5.1 CN6.1 CN7.1 CN8.1 CN9.1 CN10.1 CN11.1 CN12.1 CN13.1 CN14.1 CN15.1 CN16.1 CPU1.A3 CPU1.A5 CPU1.A7 CPU1.A13 CPU1.A17 CPU1.A27 CPU1.A39 CPU1.A45 CPU1.A47 CPU1.A49 CPU1.A51 CPU1.A53 CPU1.A55 CPU1.A57 CPU1.AA3 CPU1.AA11 CPU1.AA15 CPU1.AA17 CPU1.AA32 CPU1.AA38 CPU1.AA40 CPU1.AA44 CPU1.AA46 CPU1.AA49 CPU1.AB6 CPU1.AB58 CPU1.AC1 CPU1.AC7 CPU1.AC9 CPU1.AC11 CPU1.AC14 CPU1.AC16 CPU1.AC22 CPU1.AC35 CPU1.AC37 CPU1.AC39 CPU1.AC43 CPU1.AC45 CPU1.AC49 CPU1.AC51 CPU1.AC53 CPU1.AD6 CPU1.AD8 CPU1.AD15 CPU1.AD17 CPU1.AD23 CPU1.AD46 CPU1.AD52 CPU1.AD54 CPU1.AD56 CPU1.AE7 CPU1.AF2 CPU1.AF6 CPU1.AF12 CPU1.AF16 CPU1.AF31 CPU1.AF43 CPU1.AF54 CPU1.AF58 CPU1.AG5 CPU1.AG7 CPU1.AG11 CPU1.AG49 CPU1.AG51 CPU1.AG53 CPU1.AG59 CPU1.AH6 CPU1.AH8 CPU1.AH10 CPU1.AH12 CPU1.AH15 CPU1.AH17 CPU1.AH29 CPU1.AH40 CPU1.AH42 CPU1.AH44 CPU1.AH52 CPU1.AH54 CPU1.AH56 CPU1.AH58 CPU1.AK7 CPU1.AK11 CPU1.AK14 CPU1.AK26 CPU1.AK43 CPU1.AK45 CPU1.AK53 CPU1.AK55 CPU1.AK57 CPU1.AK59 CPU1.AM2 CPU1.AM6 CPU1.AM12 CPU1.AM15 CPU1.AM17 CPU1.AM23 CPU1.AM29 CPU1.AM32 CPU1.AM42 CPU1.AM44 CPU1.AM52 CPU1.AM54 CPU1.AM56 CPU1.AM58 CPU1.AN1 CPU1.AN3 CPU1.AN49 CPU1.AN51 CPU1.AN53 CPU1.AN59 CPU1.AP2 CPU1.AP8 CPU1.AP12 CPU1.AP14 CPU1.AP16 CPU1.AP18 CPU1.AP41 CPU1.AP54 CPU1.AP58 CPU1.AR1 CPU1.AR5 CPU1.AR7 CPU1.AR11 CPU1.AT6 CPU1.AT12 CPU1.AT15 CPU1.AT17 CPU1.AT25 CPU1.AT27 CPU1.AT34 CPU1.AT36 CPU1.AT44 CPU1.AT46 CPU1.AT52 CPU1.AT54 CPU1.AT56 CPU1.AU7 CPU1.AU16 CPU1.AU20 CPU1.AU43 CPU1.AU45 CPU1.AU49 CPU1.AU51 CPU1.AU53 CPU1.AV2 CPU1.AV6 CPU1.AV8 CPU1.AV58 CPU1.AW5 CPU1.AW7 CPU1.AW9 CPU1.AW11 CPU1.AW15 CPU1.AW44 CPU1.AW46 CPU1.AW49 CPU1.AY6 CPU1.AY10 CPU1.AY56 CPU1.B2 CPU1.B4 CPU1.B8 CPU1.B32 CPU1.B44 CPU1.B48 CPU1.B52 CPU1.B58 CPU1.BA1 CPU1.BA7 CPU1.BA11 CPU1.BA14 CPU1.BA26 CPU1.BA28 CPU1.BA35 CPU1.BA37 CPU1.BA41 CPU1.BA43 CPU1.BA45 CPU1.BA53 CPU1.BB6 CPU1.BB8 CPU1.BB10 CPU1.BB19 CPU1.BB42 CPU1.BB44 CPU1.BB46 CPU1.BB52 CPU1.BB54 CPU1.BB58 CPU1.BC5 CPU1.BC7 CPU1.BC11 CPU1.BC49 CPU1.BC51 CPU1.BC53 CPU1.BC59 CPU1.BD6 CPU1.BD12 CPU1.BD16 CPU1.BD18 CPU1.BD24 CPU1.BD41 CPU1.BD43 CPU1.BD45 CPU1.BD56 CPU1.BE1 CPU1.BE5 CPU1.BE7 CPU1.BE9 CPU1.BE11 CPU1.BE57 CPU1.BE59 CPU1.BF6 CPU1.BF12 CPU1.BF15 CPU1.BF17 CPU1.BF19 CPU1.BF21 CPU1.BF27 CPU1.BF32 CPU1.BF34 CPU1.BF36 CPU1.BF40 CPU1.BF42 CPU1.BF44 CPU1.BF46 CPU1.BF52 CPU1.BF58 CPU1.BG5 CPU1.BG7 CPU1.BG49 CPU1.BG53 CPU1.BH2 CPU1.BH8 CPU1.BH12 CPU1.BH20 CPU1.BH38 CPU1.BH42 CPU1.BH52 CPU1.BH56 CPU1.BH58 CPU1.BJ11 CPU1.BJ13 CPU1.BJ17 CPU1.BJ23 CPU1.BJ27 CPU1.BJ35 CPU1.BJ39 CPU1.BJ41 CPU1.BJ45 CPU1.BK2 CPU1.BK6 CPU1.BK24 CPU1.BK48 CPU1.BK50 CPU1.BK54 CPU1.BK58 CPU1.BL5 CPU1.BL7 CPU1.BL13 CPU1.BL23 CPU1.BL30 CPU1.BL41 CPU1.BM10 CPU1.BM16 CPU1.BM18 CPU1.BM22 CPU1.BM26 CPU1.BM28 CPU1.BM34 CPU1.BM36 CPU1.BM40 CPU1.BM44 CPU1.BM46 CPU1.BM56 CPU1.BN7 CPU1.BN13 CPU1.BN17 CPU1.BN21 CPU1.BN23 CPU1.BN27 CPU1.BN30 CPU1.BN35 CPU1.BN39 CPU1.BN41 CPU1.BN45 CPU1.BN53 CPU1.BP6 CPU1.BP10 CPU1.BP18 CPU1.BP26 CPU1.BP32 CPU1.BP40 CPU1.BP48 CPU1.BP58 CPU1.BR1 CPU1.BR5 CPU1.BR41 CPU1.BR53 CPU1.BR59 CPU1.BT8 CPU1.BT12 CPU1.BT16 CPU1.BT20 CPU1.BT24 CPU1.BT28 CPU1.BT34 CPU1.BT38 CPU1.BT42 CPU1.BT46 CPU1.BT50 CPU1.BT54 CPU1.BT56 CPU1.BU1 CPU1.BU3 CPU1.BU41 CPU1.BU59 CPU1.BV2 CPU1.BV6 CPU1.BV8 CPU1.BV12 CPU1.BV16 CPU1.BV20 CPU1.BV44 CPU1.BV48 CPU1.BV52 CPU1.BV58 CPU1.BW3 CPU1.BW5 CPU1.BW7 CPU1.BW19 CPU1.BW30 CPU1.BW39 CPU1.BW45 CPU1.BW47 CPU1.BW49 CPU1.BW51 CPU1.BW53 CPU1.BW55 CPU1.BW57 CPU1.C1 CPU1.C25 CPU1.C41 CPU1.C59 CPU1.D20 CPU1.D22 CPU1.D28 CPU1.D34 CPU1.D38 CPU1.D42 CPU1.D46 CPU1.D50 CPU1.D54 CPU1.D56 CPU1.E1 CPU1.E7 CPU1.E11 CPU1.E15 CPU1.E19 CPU1.E41 CPU1.E53 CPU1.E59 CPU1.F2 CPU1.F6 CPU1.F8 CPU1.F10 CPU1.F14 CPU1.F16 CPU1.F18 CPU1.F40 CPU1.F48 CPU1.F58 CPU1.G5 CPU1.G13 CPU1.G17 CPU1.G21 CPU1.G25 CPU1.G30 CPU1.G35 CPU1.G41 CPU1.G45 CPU1.G53 CPU1.H12 CPU1.H28 CPU1.H36 CPU1.H40 CPU1.H44 CPU1.H46 CPU1.H56 CPU1.J13 CPU1.J41 CPU1.K2 CPU1.K6 CPU1.K10 CPU1.K48 CPU1.K50 CPU1.K54 CPU1.K58 CPU1.L3 CPU1.L7 CPU1.L11 CPU1.L13 CPU1.L15 CPU1.L17 CPU1.L19 CPU1.L27 CPU1.L30 CPU1.L33 CPU1.L35 CPU1.L39 CPU1.L41 CPU1.L45 CPU1.M12 CPU1.M14 CPU1.M16 CPU1.M18 CPU1.M20 CPU1.M22 CPU1.M32 CPU1.M34 CPU1.M36 CPU1.M38 CPU1.M42 CPU1.M52 CPU1.M56 CPU1.M58 CPU1.N3 CPU1.N7 CPU1.N49 CPU1.N53 CPU1.P6 CPU1.P8 CPU1.P12 CPU1.P15 CPU1.P17 CPU1.P19 CPU1.P21 CPU1.P23 CPU1.P29 CPU1.P40 CPU1.P42 CPU1.P44 CPU1.P46 CPU1.P52 CPU1.P58 CPU1.R1 CPU1.R7 CPU1.R9 CPU1.R11 CPU1.R57 CPU1.R59 CPU1.T6 CPU1.T12 CPU1.T16 CPU1.T18 CPU1.T20 CPU1.T22 CPU1.T24 CPU1.T26 CPU1.T28 CPU1.T39 CPU1.T41 CPU1.T43 CPU1.T45 CPU1.T56 CPU1.U5 CPU1.U49 CPU1.U51 CPU1.U53 CPU1.U59 CPU1.V6 CPU1.V8 CPU1.V15 CPU1.V17 CPU1.V19 CPU1.V29 CPU1.V42 CPU1.V44 CPU1.V46 CPU1.V52 CPU1.V54 CPU1.V58 CPU1.W7 CPU1.W14 CPU1.W16 CPU1.W18 CPU1.W41 CPU1.W43 CPU1.W45 CPU1.W53 CPU1.Y2 CPU1.Y8 CPU1.Y10 CPU1.Y12 CPU1.Y56 D1709.A D2101.1 D2102.1 D2103.1 D2106.1 D2107.1 D2301.2 D2302.2 D2303.2 D2304.2 D2305.2 D2306.2 D2307.2 D2308.2 D2401.1 D2402.1 D2403.1 D2404.1 D2405.1 D4101.1 D4501.2 D4502.2 D4503.2 D5401.2 D5402.2 D5403.2 D5404.2 D5413.2 D5414.2 D5415.2 D5416.2 D5417.2 D5418.2 DB2.1 DB2.7 DB2.8 ECDBG1.1 ECDBG1.11 ECDBG1.12 ECOMP3.5 ECOMP3.10 ECOMP3.12 ECOMP3.13 ECOMP3.16 EMMC1.A6 EMMC1.C4 EMMC1.E7 EMMC1.G5 EMMC1.H10 EMMC1.J5 EMMC1.K8 EMMC1.N2 EMMC1.N5 EMMC1.P4 EMMC1.P6 GYRO1.8 GYRO1.9 GYRO1.10 GYRO1.11 GYRO1.12 GYRO1.13 H1.1 H3.1 H4.1 H5.1 H6.1 H7.1 H8.1 H9.1 H10.1 HALL1.1 HKEY1.1 HKEY1.3 HKEY1.6 HKEY1.7 JUSBC1.13 JUSBC1.14 JUSBC1.15 JUSBC1.16 JUSBC1.A1 JUSBC1.A12 JUSBC1.B1 JUSBC1.B12 LCD1.8 LCD1.11 LCD1.18 LCD1.21 LCD1.24 LCD1.27 LCD1.30 LCD1.33 LCD1.36 LCD1.46 LCD1.47 MIC1.2 MIC1.5 MSD1.6 MSD1.9 MSD1.10 MSD1.11 MSD1.13 MSD1.14 MSIM1.5 MSIM1.8 MSIM1.9 MSIM1.11 MSIM1.12 NFC1.1 NFC1.7 NFC1.14 NFC1.16 NFC1.17 NGFF1.3 NGFF1.5 NGFF1.11 NGFF1.27 NGFF1.33 NGFF1.39 NGFF1.45 NGFF1.57 NGFF1.71 NGFF1.73 NGFF1.76 NGFF1.77 PC4501.2 PC4502.2 PC4503.2 PC4504.2 PC4505.2 PC4603.2 PC4604.2 PC4605.2 PC4606.2 PC4608.2 PC4610.2 PC4611.2 PC4614.2 PC4616.2 PC4618.2 PC4619.2 PC4622.2 PC4625.2 PC4626.2 PC4627.2 PC4628.2 PC4629.2 PC4630.2 PC4631.2 PC4701.2 PC4702.2 PC4703.2 PC4704.2 PC4705.2 PC4706.2 PC4707.2 PC4708.2 PC4709.2 PC4710.2 PC4711.2 PC4712.2 PC4713.2 PC4714.2 PC4715.2 PC4716.2 PC4717.2 PC4718.2 PC4719.2 PC4720.2 PC4721.2 PC4722.2 PC4723.2 PC4724.2 PC4725.2 PC4726.2 PC4727.2 PC4728.2 PC4729.2 PC4730.2 PC4732.2 PC4801.2 PC4802.2 PC4803.2 PC4804.2 PC4805.2 PC4806.2 PC4807.2 PC4808.2 PC4809.2 PC4810.2 PC4811.2 PC4812.2 PC4813.2 PC4814.2 PC4815.2 PC4816.2 PC4817.2 PC4818.2 PC4819.2 PC4820.2 PC4821.2 PC4822.2 PC4823.2 PC4824.2 PC4825.2 PC4826.2 PC4827.2 PC4828.2 PC4829.2 PC4830.2 PC4831.2 PC4832.2 PC4833.2 PC4834.2 PC4836.2 PC4837.2 PC4839.2 PC4840.2 PC4841.2 PC4842.2 PC4901.2 PC4902.2 PC4905.2 PC4906.2 PC4907.2 PC4908.2 PC4909.2 PC4910.2 PC4912.2 PC4913.2 PC4914.2 PC4915.2 PC4916.2 PC4917.2 PC4918.2 PC4919.2 PC5001.2 PC5003.2 PC5004.2 PC5101.2 PC5102.2 PC5103.2 PC5104.2 PD4604.A PD4801.A PG4605.2 PKEY1.1 PKEY1.3 PKEY1.4 PKEY1.5 PMIC1.A5 PMIC1.B5 PMIC1.B9 PMIC1.B10 PMIC1.B11 PMIC1.B12 PMIC1.C14 PMIC1.D14 PMIC1.E1 PMIC1.E2 PMIC1.F13 PMIC1.F14 PMIC1.G6 PMIC1.G13 PMIC1.G14 PMIC1.H2 PMIC1.H8 PMIC1.H14 PMIC1.J2 PMIC1.J9 PMIC1.J14 PMIC1.K2 PMIC1.L2 PMIC1.M2 PMIC1.M14 PMIC1.N2 PMIC1.N14 PMIC1.P3 PMIC1.P4 PMIC1.P6 PMIC1.P7 PMIC1.P8 PMIC1.P9 PMIC1.P12 PMIC1.P13 PQ4601.1 PQ4603.1 PQ4603.4 PR4620.2 PR4624.1 PR4625.2 PR4629.2 PR4630.1 PR4632.2 PR4636.2 PR4650.2 PR4912.2 PR4914.2 PR5003.1 PR5101.2 PR5111.1 PR5113.1 PR5115.2 PU4601.22 PU4603.5 PU4603.6 PU4603.7 Q501.2 Q3001.2 R301.2 R302.2 R307.2 R308.2 R403.1 R404.2 R412.1 R418.1 R501.1 R504.1 R640.1 R643.1 R644.1 R703.2 R711.2 R714.2 R715.1 R721.1 R729.1 R737.1 R738.1 R741.1 R749.1 R754.1 R758.1 R1305.2 R1306.2 R1307.2 R1308.2 R1325.2 R1327.2 R1405.2 R1406.2 R1407.2 R1408.2 R1425.2 R1427.2 R1722.2 R1728.2 R1739.1 R1744.1 R1750.2 R1754.2 R1758.2 R1770.2 R1787.2 R1788.2 R2016.1 R2017.1 R2023.1 R2205.1 R2206.1 R2503.1 R2518.1 R2903.2 R2905.2 R3001.2 R3002.2 R3017.2 R3021.1 R3162.2 R3164.2 R3166.2 R3169.2 R3172.2 R3173.2 R3403.2 R3405.2 R4003.2 R4009.2 R4014.1 R4103.2 R4107.2 R4208.1 R4401.1 R4402.1 R4403.1 R4404.2 R4405.2 R5212.1 R5219.1 R5410.2 R5722.2 RAM1.A2 RAM1.A3 RAM1.A4 RAM1.A5 RAM1.A8 RAM1.A12 RAM1.A14 RAM1.B1 RAM1.B3 RAM1.B4 RAM1.C1 RAM1.C2 RAM1.C4 RAM1.D1 RAM1.D2 RAM1.D3 RAM1.D4 RAM1.D12 RAM1.D17 RAM1.E5 RAM1.E6 RAM1.E7 RAM1.E8 RAM1.E9 RAM1.E10 RAM1.E11 RAM1.E12 RAM1.F1 RAM1.F5 RAM1.F12 RAM1.F17 RAM1.G1 RAM1.G5 RAM1.G15 RAM1.G16 RAM1.H5 RAM1.H12 RAM1.H15 RAM1.J5 RAM1.J17 RAM1.K5 RAM1.L5 RAM1.L12 RAM1.M1 RAM1.M4 RAM1.M5 RAM1.M6 RAM1.M8 RAM1.M11 RAM1.M17 RAM1.N13 RAM1.N17 RAM1.P1 RAM1.P14 RAM1.R7 RAM1.R8 RAM1.R16 RAM1.R17 RAM1.T7 RAM1.T15 RAM1.T17 RAM1.U4 RAM1.U6 RAM1.U9 RAM1.U12 RAM1.U13 RAM1.U15 RAM1.U16 RAM2.A2 RAM2.A3 RAM2.A4 RAM2.A5 RAM2.A8 RAM2.A12 RAM2.A14 RAM2.B1 RAM2.B3 RAM2.B4 RAM2.C1 RAM2.C2 RAM2.C4 RAM2.D1 RAM2.D2 RAM2.D3 RAM2.D4 RAM2.D12 RAM2.D17 RAM2.E5 RAM2.E6 RAM2.E7 RAM2.E8 RAM2.E9 RAM2.E10 RAM2.E11 RAM2.E12 RAM2.F1 RAM2.F5 RAM2.F12 RAM2.F17 RAM2.G1 RAM2.G5 RAM2.G15 RAM2.G16 RAM2.H5 RAM2.H12 RAM2.H15 RAM2.J5 RAM2.J17 RAM2.K5 RAM2.L5 RAM2.L12 RAM2.M1 RAM2.M4 RAM2.M5 RAM2.M6 RAM2.M8 RAM2.M11 RAM2.M17 RAM2.N13 RAM2.N17 RAM2.P1 RAM2.P14 RAM2.R7 RAM2.R8 RAM2.R16 RAM2.R17 RAM2.T7 RAM2.T15 RAM2.T17 RAM2.U4 RAM2.U6 RAM2.U9 RAM2.U12 RAM2.U13 RAM2.U15 RAM2.U16 RT5101.1 RT5102.1 RT5103.1 RTC1.2 RTC1.3 RTC1.4 SH1.1 SH1.2 SH1.3 SH1.4 SH1.5 SH2.1 SH2.2 SH2.3 SH2.4 SH2.5 SH4.1 SH4.2 SH4.3 SH4.4 SH4.5 SH5.1 SH5.2 SH5.3 SH5.4 SH5.5 SPK1.3 SPK1.4 SPR2.1 SPR3.1 SPR4.1 TP1.1 TP1.11 TP1.12 TP4504.1 TP4505.1 TP4506.1 TP5405.1 U701.1 U701.5 U1702.2 U1703.A1 U1704.A2 U1704.A3 U1704.F7 U1704.G4 U1704.G5 U1704.H5 U1704.K4 U1704.L5 U1704.N6 U1705.A1 U1706.1 U1706.4 U1707.2 U1708.1 U1708.4 U1709.1 U1709.4 U1710.1 U1710.4 U2001.30 U2001.31 U2001.32 U2001.33 U2001.46 U2001.49 U2501.1 U2501.4 U2901.A1 U2901.B8 U2901.D6 U2901.D8 U2901.E5 U2901.E6 U2901.E7 U2901.E8 U2901.F5 U2901.F6 U2901.F7 U2901.F8 U2901.G5 U2901.G6 U2901.G7 U2901.G8 U2901.H4 U2901.H5 U2901.H8 U2901.L1 U2903.4 U2903.9 U3101.29 U3102.18 U3102.24 U3102.31 U3102.49 U3401.2 U3401.5 U3402.1 U3402.4 U3403.2 U3403.5 U4002.1 U4002.4 U4101.6 U4101.20 U4101.21 U4301.2 U4302.1 U4302.4 U4401.3 U4401.4 U4401.10 U4401.11 U4401.15 U4401.24 U4401.25 U4501.1 U4501.4 U4602.1 U4602.2 U4602.4 U4603.2 U4901.1 U4901.4 U5101.A1 U5202.3 U5202.4 U5401.2 U5407.6 U5407.10 U5407.18 U5407.21 U5407.25 U5702.9 U5702.16 U5702.23 U5702.32 U5702.33 U5706.1 U5706.4 U5707.3 U5707.8 U5708.3 U5708.8 U5709.1 U5709.4 VDKEY1.1 VDKEY1.3 VDKEY1.6 VDKEY1.7 VUKEY1.1 VUKEY1.3 VUKEY1.6 VUKEY1.7 WC3701.2 WC3702.2 WC3703.2 WC3704.2 WC3705.2 WC3706.2 WC3707.2 WC3708.2 WC3709.1 WC3710.2 WC3715.2 WC3716.2 WC3717.2 WC3718.2 WR3705.2 WU3701.6 WU3701.17 WU3701.26 WU3701.32 WU3701.35 WU3701.38 WU3701.41 WU3701.62 WU3701.68 WU3701.71 WU3701.74 WU3701.75 WU3701.76 WU3701.77 WU3701.78 WU3701.79 WU3701.80 WU3701.81 WU3701.82 WU3701.83 WU3701.84 WU3701.85 WU3701.86 WU3701.87 WU3701.88 WU3701.89 WU3701.90 WU3701.91 WU3701.92 WU3701.93 WU3701.94 WU3701.95 WU3701.96 WU3701.G1 WU3701.G2 WU3701.G3 WU3701.G4 WU3701.G5 WU3701.G6 WU3701.G7 WU3701.G8 WU3701.G9 WU3701.G10 WU3701.G11 WU3701.G12 X701.2 X701.4 XDP1.7 XDP1.10 XDP1.20 XDP1.23 XDP1.30 XDP1.33 XDP1.36 XDP1.41 XDP1.42 XDP1.43 XDP1.44
GND_L: LCD1.40 LCD1.44 R3405.1
V1P05A_LX: PL4705.1 PMIC1.R6 PMIC1.R7
V1P8A_LX: PL4803.1 PMIC1.A9 PMIC1.A10
V1P15_LX: PL4802.1 PMIC1.H15 PMIC1.J15
V3P3_SD_EN: PMIC1.C3 PQ4901.G
V3P3A_LX1: PL4806.1 PMIC1.F1 PMIC1.F2
V3P3A_LX2: PL4806.2 PMIC1.D1 PMIC1.D2
V3P3SX_LX1: PL4807.1 PMIC1.A6 PMIC1.B6
V3P3SX_LX2: PL4807.2 PMIC1.A4 PMIC1.B4
V5P0A_LX: PD4801.K PL4801.1 PMIC1.A11 PMIC1.A12
VBATL: PMIC1.H4 PR5111.2
VCC0_LX: PL4706.1 PMIC1.R12 PMIC1.R13
VCC0_SENSE: CPU1.V40 PMIC1.N12
VCC1_LX: PL4707.1 PMIC1.M15 PMIC1.N15
VCC1_SENSE: CPU1.AF39 PMIC1.M13
VCC_VSSSENSE: CPU1.AF41 CPU1.V38 PMIC1.N13
VCCDSIPLL_1P24_1P35: CPU1.T14 R805.1 R806.2
VDD_3G_LTE_3P3: C4002.1 C4006.1 C4007.1 C4008.1 C4009.1 C4010.1 D4001.K D4002.K NGFF1.2 NGFF1.4 NGFF1.70 NGFF1.72 NGFF1.74 R4017.2 R4020.1
VDD_IO_NFC: C3902.1 C3903.1 NFC1.2 NFC1.10 R3904.2
VDD_NFC_3P3: C3901.1 NFC1.3 NFC1.15 R3902.2
VDD_TP_3V3: C4301.1 C4302.1 C4303.1 C4304.1 C4309.1 R4301.2 R4302.2 R4310.2 R4311.1 TP1.3 U4301.6 U4301.7
VDDD_DREG: C3024.1 U3102.2
VDDQ_LX0: PL4804.1 PMIC1.F15 PMIC1.G15
VDDQ_LX1: PL4805.1 PMIC1.C15 PMIC1.D15
2_4_LANE: CPU1.G39 R748.1
2_4_LANE_DET: D5412.A R733.1 R748.2
+VGG: C1107.1 C1108.1 C1109.1 C1110.1 C1111.1 C1112.1 C1196.1 C1197.1 C1198.1 C1199.1 CPU1.AK22 CPU1.AK24 CPU1.AM21 CPU1.AM25 CPU1.AM27 CPU1.AM36 CPU1.AM38 CPU1.AM40 CPU1.AP22 CPU1.AP24 CPU1.AP26 CPU1.AP28 CPU1.AP31 CPU1.AP33 CPU1.AP35 CPU1.AP37 CPU1.AP39 CPU1.AT23 CPU1.AT29 CPU1.AT38 CPU1.AT40 CPU1.AU24 CPU1.AU26 CPU1.AU28 CPU1.AU31 CPU1.AU33 CPU1.AU35 CPU1.AU37 CPU1.AU39 CPU1.AW23 CPU1.AW27 CPU1.AW29 CPU1.AW32 CPU1.AW34 CPU1.AW36 CPU1.AW38 CPU1.AW40 CPU1.BA22 CPU1.BA31 CPU1.BA33 CPU1.BA39 CPU1.BB23 CPU1.BB25 CPU1.BB27 CPU1.BB29 CPU1.BB32 CPU1.BB34 CPU1.BB36 CPU1.BB38 CPU1.BB40 CPU1.BD22 CPU1.BD26 CPU1.BD33 CPU1.BD35 CPU1.BD37 CPU1.BD39 CPU1.BV10 CPU1.BV14 CPU1.BW9 CPU1.BW11 CPU1.BW13 PC4709.1 PC4710.1 PC4711.1 PC4712.1 PC4713.1 PC4726.1 PC4727.1 PC4728.1 PC4729.1 PL4701.2 PL4702.2 PL4703.2 PL4704.2
+VNN: C1144.1 C1145.1 C1146.1 C1147.1 C1148.1 C1149.1 C1150.1 C1151.1 CPU1.AA19 CPU1.AA21 CPU1.AA23 CPU1.AA27 CPU1.AA29 CPU1.AA34 CPU1.AA36 CPU1.AC20 CPU1.AC31 CPU1.AC33 CPU1.AD19 CPU1.AD21 CPU1.AD25 CPU1.AD27 CPU1.AF20 CPU1.AF22 CPU1.AH19 CPU1.AH21 CPU1.AH23 CPU1.AH25 CPU1.AK20 CPU1.AM19 CPU1.AP20 CPU1.AT19 CPU1.AT21 CPU1.AU22 CPU1.AW21 CPU1.BA20 CPU1.BB21 CPU1.BD20 CPU1.BL1 CPU1.BN1 CPU1.BP2 CPU1.V21 CPU1.V23 CPU1.V25 CPU1.W20 CPU1.W22 CPU1.W26 CPU1.W28 PC4708.1 PC4732.1 PL4708.2
+VREFB: PMIC1.E8 PR5109.1
+VREFT: PMIC1.E9 PR5102.1 PR5103.1 PR5104.1
+VRTC: C1189.1 C1191.1 CPU1.BB15 PC5005.1 PC5101.1 PR5112.2 R739.1
+VRTC_BAT: PD5101.3 PMIC1.J4 PR5112.1
+VRTC_BAT_R: PR5114.2 U5101.A2 U5101.B2
+VRTC_L: PR5117.1 RTC1.1
+VRTC_R: PD5101.1 PR5117.2
+VSDIO: C1138.1 C1139.1 CPU1.BF23 CPU1.BW15 PC4914.1 PMIC1.C6
+VSYS: C4401.1 C5215.1 C5218.1 C5219.1 C5223.1 C5227.1 L4401.1 L5202.1 PC4603.1 PC4605.1 PC4606.1 PC4622.1 PC4629.1 PC4630.1 PG4604.2 PL4601.2 PR4622.1 PR4902.2 PR4906.1 R5211.1 R5213.1 U5202.5
+VUSB_5V_19V: C2906.1 C2907.1 C2908.1 C2909.1 C2910.1 JUSBC1.A4 JUSBC1.A9 JUSBC1.B4 JUSBC1.B9 PD4607.A PR4634.1 PR4636.1 PR4637.1 U2901.A10 U2901.B10 U2901.H11 U2901.J10 U2901.J11 U2901.K11
+VUSB_5V_19V_R: PQ4601.4 PQ4601.6 PR4637.2
AC_PRESENT: CPU1.BK4 R704.1 U701.4
ACPI_INT#: CPU1.F22 D1701.A R719.1
AMBER_LED: C5713.1 LED1.3 R4902.2
AMBER_LED_EC: U1704.F5 U4901.2
AMBER_LED_R: R4902.1 U4901.6
ANT1_GND: ANT2.2 WC3710.1
AUD_AGND: C2001.1 C2002.1 C2003.1 C2006.2 C2007.2 C2010.1 C2011.1 C2012.2 C2013.2 C2016.2 C2017.2 C2018.2 C2019.2 C2201.2 C2202.2 C2203.2 C2204.2 C2205.2 D2201.1 D2202.1 D2203.1 D2204.1 D2205.1 R2012.1 R2013.1 R2014.1 R2016.2 R2017.2 R2204.2 R2205.2 R2206.2 R2211.2 U2001.10 U2001.24
AUD_AGND_1: AUDIO1.5 R2204.1
AUDIO_CODEC_IRQ: R503.2 R652.1 U2001.41
AUDIO_CODEC_IRQ_L: CPU1.BU39 R503.1
AUDIO_CODEC_IRQ_R: CPU1.BM24 R652.2
BATDRV#: PC4617.2 PR4606.2 PU4602.4
BATPRES#: PR4610.1 PU4601.15
BIOS_HOLD#: BIOS1.7 BSKT1.7 R1802.2 R1805.2
BIOS_WP#: BIOS1.3 BSKT1.3 R1801.2 R1803.2
BL_CIN: C4402.1 U4401.19
BL_FSET: R4401.2 U4401.21
BL_ISET: R4402.2 U4401.23
BL_SW: D4401.A L4401.2 U4401.1 U4401.2
BOARD_ID: C1703.2 R1759.2 U1704.G3
BPTHERM0: PMIC1.D6 TP5104.1
BQ24770_AGND: PC4601.2 PC4602.1 PC4607.2 PC4609.2 PC4612.1 PC4613.1 PC4623.2 PC4624.2 PG4605.1 PR4608.1 PU4601.29
BRTC_EXTPAD: C706.1 CPU1.BG11
BT_DEV_EN: CPU1.B38 R703.1 WU3701.63
C_SBU1: D5417.1 JUSBC1.A8 U2901.K8
C_SBU2: D5418.1 JUSBC1.B8 U2901.L8
C_USB_B_N: L3104.1 U2901.L7
C_USB_B_P: L3104.4 U2901.K7
C_USB_T_N: L3103.4 U2901.L6
C_USB_T_P: L3103.1 U2901.K6
CAM_1_PWRDWN: CAMR1.22 CPU1.J27 R2508.1
CAM_2_LSM: CAMF1.3 R2504.1
CAM_2_PWRDWN: CAMF1.4 CPU1.C27 R2502.2
CAMERA_1_RESET#_R: R2508.2 U2501.2
CAMERA_LED_R: R2502.1 U2501.5
CAMERA_LED_R1: R2501.2 U2501.3 U2501.6
CAMERA_LED_R2: CLED1.K R2501.1
CAMF_AGND: CAMF1.1 R2503.2
CC1: C2911.1 JUSBC1.A5 U2901.K9 U2901.L9
CC2: C2912.1 JUSBC1.B5 U2901.K10 U2901.L10
CLK_I2S_MCLK: C710.1 R728.1 U2001.38
CLK_I2S_MCLK_1: CPU1.BU9 R728.2
CMP_7V+: PR4624.2 PR4626.1 U4603.1
CMP_7V-: PR4630.2 PR4631.2 U4603.3
COCO_ID: CPU1.H38 R734.2 R741.2
CODEC_AVDD: C2012.1 C2013.1 R2018.1 U2001.6
CODEC_CPN1: C2008.2 U2001.23
CODEC_CPN2: C2009.2 U2001.26
CODEC_CPP1: C2008.1 U2001.22
CODEC_CPP2: C2009.1 U2001.25
CODEC_CPVDD: C2016.1 C2017.1 R2020.1 U2001.21
CODEC_CPVEE: C2001.2 U2001.27
CODEC_CPVPP: C2002.2 U2001.20
CODEC_CPVREF: R2014.2 U2001.17
CODEC_DACREF: C2003.2 U2001.7
CODEC_DBVDD: C2014.1 C2015.1 R2019.1 U2001.2
CODEC_DCVDD: C2020.1 U2001.3
CODEC_DMIC_1_DATA: R2005.1 U2001.5
CODEC_DMIC_SCL: R2001.2 U2001.42
CODEC_IN2P: TP2001.1 U2001.4
CODEC_MICVDD: C2018.1 C2019.1 R2021.2 U2001.15
CODEC_SPKVDD: C2021.1 C2022.1 R2023.2 R2027.2 U2001.43 U2001.47
CODEC_VREF2: C2007.1 U2001.8
CORE_PWROK: CPU1.BG3 PMIC1.H10 PR5003.2 XDP1.25
CPU_USB_OC#: CPU1.BP22 D2901.A R604.2
DBG_JTAG_CLK: ECDBG1.7 R1763.1 U1704.C10
DBG_JTAG_RST#: C1722.1 R1769.1 U1704.A10
DBG_JTAG_TDI: ECDBG1.9 R1726.1 U1704.C11
DBG_JTAG_TDO: ECDBG1.6 R1764.1 U1704.A11
DBG_JTAG_TMS: ECDBG1.8 R1735.1 U1704.B10
DBG_MSCLK: ECDBG1.5 R1765.1 U1704.E10
DBG_MSDAT: ECDBG1.4 R1770.1 U1704.D10
DBG_PIN1: ECDBG1.10 R1701.2
DBG_RESETBTN#: CPU1.BH24 TP702.1
DBG_UART_TX: ECDBG1.3 R1767.1 U1704.F9
DCIN_DROP_DET#: PR4645.2 PU4601.14 U1704.H11
DCIN_OFF: PQ4601.2 PR4619.1 PR4620.1
DCIN_OFF#: PQ4601.5 PR4634.2
DCIN_ON: PQ4601.3 PR4613.1 PR4615.1 PU4604.4
DCIN_OP_VCC: C5712.1 PR4631.1 PR4642.1 PR4643.1 PR4645.1 U1705.B1 U4602.8 U4603.5
DDI0_AUXN: C3010.2 CPU1.R3
DDI0_AUXP: C3009.2 CPU1.T4
DDI0_HDP#: CPU1.C21 Q3001.3 R410.2
DDI0_PLLOBS_N: CPU1.P4 R406.1
DDI0_PLLOBS_P: CPU1.R5 R406.2
DDI0_TX0_DN: C3002.1 CPU1.N11
DDI0_TX0_DN_ST: C3002.2 U3102.39
DDI0_TX0_DP: C3001.1 CPU1.P10
DDI0_TX0_DP_ST: C3001.2 U3102.38
DDI0_TX1_DN: C3004.1 CPU1.U3
DDI0_TX1_DN_ST: C3004.2 U3102.42
DDI0_TX1_DP: C3003.1 CPU1.T2
DDI0_TX1_DP_ST: C3003.2 U3102.41
DDI0_TX2_DN: C3006.1 CPU1.T10
DDI0_TX2_DN_ST: C3006.2 U3102.45
DDI0_TX2_DP: C3005.1 CPU1.U11
DDI0_TX2_DP_ST: C3005.2 U3102.44
DDI0_TX3_DN: C3008.1 CPU1.W5
DDI0_TX3_DN_ST: C3008.2 U3102.48
DDI0_TX3_DP: C3007.1 CPU1.V4
DDI0_TX3_DP_ST: C3007.2 U3102.47
DDI1_RCOMP_N: CPU1.J7 R402.2
DDI1_RCOMP_P: CPU1.K8 R402.1
DDR3_DRAM_PWROK: CPU1.AK49 PMIC1.J11 R307.1
DDR3_M0_OCAVREF: CPU1.T48 R310.2
DDR3_M0_ODQVREF: CPU1.T50 R309.2
DDR3_M0_RCOMPPD: CPU1.AD44 R301.1
DDR3_M1_RCOMPPD: CPU1.AP43 R302.1
DDR3_VCCA_PWROK: CPU1.AK51 PMIC1.K12 R308.1
DE303_INT1: CPU1.BR3 ECOMP3.11
DE303_INT2: CPU1.BN5 ECOMP3.9
DEBUB_CS: PMIC1.A2 PR5101.1
DEBUG_I2C_1_SCL: TP5602.1 XDP1.11
DEBUG_I2C_1_SDA: TP5601.1 XDP1.9
DMIC1_VDD: C2101.1 C2102.1 D2103.2 MIC1.1 R2104.2
DMIC_1_DATA: D2106.2 MIC1.4 R2005.2
DMIC_SCL: D2107.2 MIC1.3 R2001.1
DN1_DP4_EC: C1715.2 C1716.2 Q1701.2 U1704.F13
DOCK_DETECT#: R1761.2 U1704.H1
DP1_DN4_EC: C1715.1 C1716.1 Q1701.1 Q1701.3 U1704.G13
DP_REDRIVER_ADDR_EQ: R3016.2 R3017.1 U3102.3
DP_REDRIVER_CAD_SNK: R3002.1 U3102.10
DP_REDRIVER_CAD_SRC: TP3003.1 U3102.8
DP_REDRIVER_EN_C: D3001.A U3102.26
DP_REDRIVER_RST: C3025.1 U3102.35
DP_REDRIVER_SCL_CTL: TP3005.1 U3102.4
DP_REDRIVER_SCL_DDC: TP3001.1 U3102.33
DP_REDRIVER_SDA_CTL: TP3006.1 U3102.5
DP_REDRIVER_SDA_DDC: TP3002.1 U3102.34
DPR#: NGFF1.25 R4021.1
DPR_HPD_IN: R2918.1 R3026.2 U3102.11
DPR_HPD_OUT: Q3001.1 R3001.1 U3102.9
EC5048_TX: ECDBG1.2 R1733.1
EC_AC_IN: R1715.2 R1749.2 R1750.1 U1704.E2
EC_AC_IN_R: D1709.K R1727.2 R1749.1
EC_BATT_PRES#: PR4610.2 R1746.1 R4504.1 U1704.N10
EC_BATT_PRES#_R: BATT1.5 D4503.1 R4504.2
EC_BIST#: D1710.K U1704.J7
EC_FG_ALERT: D1702.K U1704.A9
EC_GPIO002: TP1712.1 U1704.L10
EC_GPIO034: TP1720.1 U1704.F6
EC_GPIO036: TP1719.1 U1704.A6
EC_GPIO043: TP1711.1 U1704.A12
EC_GPIO047: D1701.K U1704.B6
EC_GPIO132: TP1707.1 U1704.L13
EC_GPIO201: TP1713.1 U1704.K1
EC_GPIO204: TP1715.1 U1704.L4
EC_GPIO212: TP1717.1 U1704.L1
EC_LAD0: R1777.2 U1704.M6
EC_LAD1: R1778.2 U1704.M7
EC_LAD2: R1779.2 U1704.L7
EC_LAD3: R1780.2 U1704.K7
EC_LCD_RST: D3404.K U1704.L3
EC_LFRAME#: R1776.2 U1704.L6
EC_PROCHOT: Q501.1 R1728.1 U1704.H13
EC_PWRBTN#: C1706.1 PD4606.A R1702.1 R1731.2 U1704.D2
EC_RESETI#: R1713.1 U1704.F1
EC_SER_IRQ: R1775.2 U1704.N5
EC_SLP_S3#: R1741.2 U1704.J2 U1709.3
EC_SLP_S4#: R1747.2 U1704.D6 U1710.3
EC_SMI#: CPU1.C39 D1707.A R731.1
EC_SMI#_R: D1707.K U1704.N7
EC_SMI_REV#: CPU1.H22 TP401.1
EC_SYS_PWR_EN: R5409.1 U1704.D1
EC_VCC_PWRGD: R1709.2 U1704.F3
EC_VCI_IN1#: R1781.2 U1704.G1
EC_VCI_IN2#: R1782.2 U1704.C2
EC_VCI_IN3#: R1783.2 U1704.E1
EC_VCI_IN4#: R1784.2 U1704.C3
EC_VCI_IN5#: R1785.2 U1704.H2
EC_VR_CAP: C1712.1 U1704.H4
EC_VREF_ADC: C1720.1 R1757.2 U1704.J3
EC_XTAL1: C1710.1 U1704.A1 X1701.2
EC_XTAL2: C1711.1 U1704.B1 X1701.1
ECOMPASS_C1: C5710.1 ECOMP3.15
ECOMPASS_SETC: C5709.1 ECOMP3.2
ECOMPASS_SETP: C5709.2 ECOMP3.3
EMMC__RCLK: CPU1.BU13 EMMC1.H5
EMMC_CLK: CPU1.BN15 EMMC1.M6
EMMC_CMD: CPU1.BJ15 EMMC1.M5 R507.2 TP1601.1
EMMC_DATA_0: CPU1.BM12 EMMC1.A3
EMMC_DATA_1: CPU1.BK14 EMMC1.A4
EMMC_DATA_2: CPU1.BM14 EMMC1.A5
EMMC_DATA_3: CPU1.BK12 EMMC1.B2
EMMC_DATA_4: CPU1.BR13 EMMC1.B3
EMMC_DATA_5: CPU1.BU15 EMMC1.B4
EMMC_DATA_6: CPU1.BP14 EMMC1.B5
EMMC_DATA_7: CPU1.BT14 EMMC1.B6
EMMC_RCOMP: CPU1.BH14 R501.2
EMMC_RESET#: CPU1.BV38 EMMC1.K5 TP1602.1
EMMC_VDDI: C1606.2 EMMC1.C2
EN_19V_IN: PQ4603.5 PR4650.1 PR4911.2 R1760.2 R5724.2 U4603.4
EN_19V_IN#: PQ4603.3 PR4643.2 U4602.7
EN_19V_IN_L: R1760.1 U1704.N2
EN_19V_IN_R: PQ4603.2 R5723.2 U4602.5
EN_19V_IN_R#: PQ4603.6 PR4623.1
EN_DCIN_OP_VCC: PR4640.1 U1705.A2
EN_V3P3_EC: Q1702.G R1742.2 U4501.3
FG_ALERT_EC: CPU1.BU5 D1702.A R732.1
FSIN_REAR: CAMR1.21 R2518.2
FST_SPI_SOCK_D2: CPU1.BJ25 R1801.1
FST_SPI_SOCK_D3: CPU1.BL25 R1802.1
G601A31U_MRDLY: C5401.1 U5401.1
GNSS0: NGFF1.40 R4006.1 R4009.1
GNSS1: NGFF1.42 R4007.1
GNSS_DISABLE#: CPU1.BP4 R4004.2
GNSS_DISABLE#_R: NGFF1.26 R4004.1
GNSS_I2C_IRQ: NGFF1.44 TP4002.1
GPIO133: R1711.2 U1704.A13
GPIO151: R1786.2 R1787.1 U1704.N12
GPIO152: R1788.1 R1789.2 U1704.M11
GPIO166: R1708.1 U1704.K5
GPIO222: R1722.1 U1704.M8
GPIO223: R1712.1 R1736.2 U1704.H7
GPIO224: R1714.1 R1752.2 U1704.G7
GPIO_RCOMP: CPU1.M40 R749.2
GPIO_SUS2_C: CPU1.J37 R711.1
GPIO_SUS3_C: CPU1.C37 R707.1
GPIO_SUS7: CPU1.K36 R758.2
GYRO_CAP: C4209.1 GYRO1.14
GYRO_CS: GYRO1.5 R4207.2
GYRO_INT1: CPU1.BM4 GYRO1.7
GYRO_INT2: CPU1.BK8 GYRO1.6
GYRO_SA0: GYRO1.4 R4208.2 R4209.1
HALL_INT#: HALL1.3 R3807.2 U1704.J5
HALL_VDD: C4210.1 HALL1.2 R4205.1
HOME_BTN_EC#: D5405.2 R1716.1 U1704.H12
HOME_BTN_SOC#: CPU1.BT40 D5405.1 R5401.2
HOME_KEY: C5405.2 D5403.1 HKEY1.2 R5406.2 TP5404.1
HOME_KEY_R: C5406.1 D5405.3 R5406.1
HP_OUT_L: C2005.1 C2202.1 R2209.1 U2001.18
HP_OUT_L_1: AUDIO1.1 D2202.2 R2209.2
HP_OUT_R: C2004.1 C2203.1 R2210.1 U2001.19
HP_OUT_R_1: AUDIO1.2 D2203.2 R2210.2
HP_RING: R2202.2 R2208.1 U2001.11
HP_RING_1: AUDIO1.3 D2201.2 R2208.2 R2211.1
HP_SLEEVE: R2201.2 R2207.1 U2001.12
HP_SLEEVE_1: AUDIO1.4 D2205.2 R2207.2
HPO_L_RC: C2005.2 R2013.2
HPO_R_RC: C2004.2 R2012.2
HW_RST1: D5411.3 U5401.5
I2C0_SCL: CPU1.BT36 R625.1
I2C0_SDA: CPU1.BU35 R624.1
I2C1_SCL: CPU1.BP36 R627.1 U2001.39 U4401.6
I2C1_SDA: CPU1.BR35 R626.1 U2001.40 U4401.5
I2C2_SCL: CPU1.BL35 R629.1 R4006.2 U1702.5
I2C2_SDA: CPU1.BH36 R628.1 R4007.2 U1702.4
I2C3_SCL: CAMF1.6 CPU1.BV34 R631.1 R2506.1
I2C3_SDA: CAMF1.5 CPU1.BU33 R630.1 R2505.1
I2C4_SCL: CPU1.BP34 R633.1 U1707.5
I2C4_SDA: CPU1.BT32 R632.1 U1707.4
I2C5_SCL: CPU1.BK34 R635.1 U4301.5
I2C5_SDA: CPU1.BR33 R634.1 U4301.4
I2C6_SCL: CPU1.BH34 PMIC1.L5 R637.1
I2C6_SDA: CPU1.BL33 PMIC1.L6 R636.1
I2C_0_SCL_EC: U1702.8 U1704.A7
I2C_0_SDA_EC: U1702.1 U1704.E7
I2C_1_SCL_CAM_R: CAMR1.28 R2506.2
I2C_1_SCL_EC: R1706.1 R2909.2 R2917.2 U1704.C8
I2C_1_SDA_CAM_R: CAMR1.27 R2505.2
I2C_1_SDA_EC: R1705.1 R2908.2 R2916.2 U1704.D8
I2C_4_SCL_EC: PR4601.1 R1724.1 U1704.A8
I2C_4_SDA_EC: PR4602.1 R1725.1 U1704.C9
I2C_5_SCL_3P3: C4305.1 TP1.8 U4301.8
I2C_5_SCL_EC: U1704.B9 U1707.8
I2C_5_SDA_3P3: C4306.1 TP1.9 U4301.1
I2C_5_SDA_EC: U1704.E9 U1707.1
I2C_7_SCL_EC: R1710.1 U1704.K11 U2901.L2
I2C_7_SDA_EC: R1707.1 U1704.L12 U2901.K2
I2C_SEC_NFC_SCL: CPU1.BJ33 NFC1.8 R667.1 XDP1.35
I2C_SEC_NFC_SDA: CPU1.BN33 NFC1.9 R666.1 XDP1.37
I2CM_CLK: PMIC1.K4 PR5002.2
I2CM_DATA: PMIC1.K5 PR5001.2
I2S_2_CLK: CPU1.BK38 R2025.1 R2025.2 U2001.37
I2S_2_FS: CPU1.BH40 R2026.1 R2026.2 U2001.36
I2S_2_RXD: CPU1.BL39 R2024.1 R2024.2 U2001.35
I2S_2_TXD: CPU1.BK40 R2022.1 R2022.2 U2001.34
ICLK_ICOMP: CPU1.AV12 R715.2
ICLK_RCOMP: CPU1.BB12 R721.2
IPLTSENSEN: PC4903.2 PMIC1.F7 PR4903.1
IPLTSENSEP: PC4903.1 PMIC1.F6 PR4902.1
ISH_GPIO8: CPU1.BL9 TP601.1
ISH_I2C0_SCL: CPU1.BT6 DB2.3 XDP1.34
ISH_I2C0_SDA: CPU1.BR7 DB2.2 XDP1.32
ISH_I2C1_SCL: CPU1.BN3 ECOMP3.4 GYRO1.2 R647.1 R4109.2
ISH_I2C1_SCL_L: R4109.1 U4101.14
ISH_I2C1_SDA: CPU1.BM8 ECOMP3.6 GYRO1.3 R645.1 R4110.2
ISH_I2C1_SDA_L: R4110.1 U4101.15
ISOCSENSEN: PC4904.2 PMIC1.D10 PR4905.1
ISOCSENSEP: PC4904.1 PMIC1.D9 PR4904.1
JACK_DET#: C2201.1 R2002.2 R2203.1 U2001.16
JACK_DET#_R: AUDIO1.6 D2204.2 R2203.2
LCD_BIST: D3401.2 D4402.2 D4403.2 U1704.N8
LCD_BIST#: D1710.A LCD1.10
LCDBL_LED_A: C4403.1 D4401.K LCD1.41 LCD1.42 LCD1.43 U4401.20
LCDBL_LED_A_R: C4403.2 C4406.1
LCDBL_LED_C1: LCD1.39 U4401.12 U4401.16
LCDBL_LED_C2: LCD1.38 U4401.13 U4401.17
LCDBL_LED_C3: LCD1.37 U4401.14 U4401.18
LCM_HSYNC: LCD1.4 TP1.2
LCM_ID1: LCD1.3 R422.2 U1704.G10
LCM_ID2: LCD1.2 R423.2 U1704.G9
LCM_ID3: LCD1.9 R421.2 U1704.F11
LCM_RST#: CPU1.K22 U3402.2
LCM_VDD: C3403.1 C3404.1 C3405.1 C3406.1 C4404.1 LCD1.14 LCD1.15 LCD1.16 LCD1.17 R3401.1 R3402.1 R3407.1 U3401.1 U4401.22
LCM_VDD_EN: R3407.2 R3408.2 U3403.4
LCM_VDD_V1P8A: C3407.1 C3410.1 LCD1.12 LCD1.13 R3404.1 U3403.1
LCM_XRES: D3403.K D3405.K LCD1.20 R3401.2 U3402.3
LCM_XRES1: D3403.A LCD1.19 R3404.2
LCM_XRES_R: D3404.A R3402.2 U3402.5 U3402.6
LPC_AD0: CPU1.BU19 U5702.24 XDP1.13
LPC_AD1: CPU1.BR19 U5702.21 XDP1.15
LPC_AD2: CPU1.BP20 U5702.18 XDP1.16
LPC_AD3: CPU1.BR21 U5702.15 XDP1.17
LPC_CLKOUT_0: CPU1.BK20 R5712.1 XDP1.19
LPC_CLKRUN#: CPU1.BL21 R5704.2
LPC_CLKRUN#_L: R5704.1 U5702.13
LPC_FRAME#: CPU1.BJ19 U5702.20 XDP1.18
LPC_RCOMP: CPU1.BH22 R644.2
LPDDR3_M0_CA0: CPU1.L49 R1309.1 RAM1.B5 RAM1.L2
LPDDR3_M0_CA1: CPU1.M50 R1310.1 RAM1.C5 RAM1.L3
LPDDR3_M0_CA2: CPU1.P48 R1311.1 RAM1.D5 RAM1.L4
LPDDR3_M0_CA3: CPU1.L51 R1312.1 RAM1.B6 RAM1.K2
LPDDR3_M0_CA4: CPU1.M54 R1313.1 RAM1.C6 RAM1.K3
LPDDR3_M0_CA5: CPU1.L55 R1314.1 RAM1.C9 RAM1.G3
LPDDR3_M0_CA6: CPU1.N51 R1315.1 RAM1.D9 RAM1.G4
LPDDR3_M0_CA7: CPU1.L57 R1316.1 RAM1.B10 RAM1.F2
LPDDR3_M0_CA8: CPU1.T52 R1317.1 RAM1.C10 RAM1.F3
LPDDR3_M0_CA9: CPU1.R53 R1318.1 RAM1.D10 RAM1.F4
LPDDR3_M0_CKE0_A: CPU1.H58 RAM1.C7
LPDDR3_M0_CKE0_B: CPU1.K56 RAM1.J3
LPDDR3_M0_CKE1_A: CPU1.C57 RAM1.D7
LPDDR3_M0_CKE1_B: CPU1.D58 RAM1.J4
LPDDR3_M0_CLK_DN_A: CPU1.N55 R1322.2 RAM1.C8
LPDDR3_M0_CLK_DN_B: CPU1.P54 R1323.2 RAM1.H2
LPDDR3_M0_CLK_DP_A: CPU1.N57 R1322.1 RAM1.B8
LPDDR3_M0_CLK_DP_B: CPU1.P56 R1323.1 RAM1.H3
LPDDR3_M0_CS0_B: CPU1.J57 RAM1.D6 RAM1.K4
LPDDR3_M0_CS1_B: CPU1.B56 RAM1.B7 RAM1.J2
LPDDR3_M0_D0_A: CPU1.K42 RAM1.N4
LPDDR3_M0_D0_B: CPU1.T54 RAM1.L15
LPDDR3_M0_D1_A: CPU1.L43 RAM1.T5
LPDDR3_M0_D1_B: CPU1.U57 RAM1.L16
LPDDR3_M0_D2_A: CPU1.H42 RAM1.R5
LPDDR3_M0_D2_B: CPU1.R55 RAM1.K13
LPDDR3_M0_D3_A: CPU1.G43 RAM1.P5
LPDDR3_M0_D3_B: CPU1.T58 RAM1.K14
LPDDR3_M0_D4_A: CPU1.J43 RAM1.N5
LPDDR3_M0_D4_B: CPU1.Y54 RAM1.K15
LPDDR3_M0_D5_A: CPU1.K44 RAM1.T6
LPDDR3_M0_D5_B: CPU1.W57 RAM1.K16
LPDDR3_M0_D6_A: CPU1.M44 RAM1.R6
LPDDR3_M0_D6_B: CPU1.Y58 RAM1.J15
LPDDR3_M0_D7_A: CPU1.J45 RAM1.P6
LPDDR3_M0_D7_B: CPU1.AA55 RAM1.J16
LPDDR3_M0_D8_A: CPU1.L47 RAM1.T9
LPDDR3_M0_D8_B: CPU1.AA57 RAM1.F14
LPDDR3_M0_D9_A: CPU1.H48 RAM1.R9
LPDDR3_M0_D9_B: CPU1.AB56 RAM1.F15
LPDDR3_M0_D10_A: CPU1.G49 RAM1.T10
LPDDR3_M0_D10_B: CPU1.AB54 RAM1.F16
LPDDR3_M0_D11_A: CPU1.H52 RAM1.R10
LPDDR3_M0_D11_B: CPU1.AG55 RAM1.E13
LPDDR3_M0_D12_A: CPU1.K52 RAM1.P10
LPDDR3_M0_D12_B: CPU1.AE55 RAM1.E14
LPDDR3_M0_D13_A: CPU1.J53 RAM1.N10
LPDDR3_M0_D13_B: CPU1.AC57 RAM1.E15
LPDDR3_M0_D14_A: CPU1.J49 RAM1.T11
LPDDR3_M0_D14_B: CPU1.AC55 RAM1.E16
LPDDR3_M0_D15_A: CPU1.J51 RAM1.R11
LPDDR3_M0_D15_B: CPU1.AG57 RAM1.D13
LPDDR3_M0_D16_A: CPU1.F44 RAM1.T2
LPDDR3_M0_D16_B: CPU1.W49 RAM1.P15
LPDDR3_M0_D17_A: CPU1.B42 RAM1.R2
LPDDR3_M0_D17_B: CPU1.V48 RAM1.P16
LPDDR3_M0_D18_A: CPU1.E43 RAM1.P2
LPDDR3_M0_D18_B: CPU1.AA51 RAM1.N14
LPDDR3_M0_D19_A: CPU1.F42 RAM1.N2
LPDDR3_M0_D19_B: CPU1.V50 RAM1.N15
LPDDR3_M0_D20_A: CPU1.E45 RAM1.T3
LPDDR3_M0_D20_B: CPU1.Y48 RAM1.N16
LPDDR3_M0_D21_A: CPU1.D44 RAM1.R3
LPDDR3_M0_D21_B: CPU1.AA53 RAM1.M13
LPDDR3_M0_D22_A: CPU1.C43 RAM1.P3
LPDDR3_M0_D22_B: CPU1.Y52 RAM1.M14
LPDDR3_M0_D23_A: CPU1.C45 RAM1.N3
LPDDR3_M0_D23_B: CPU1.AB52 RAM1.L13
LPDDR3_M0_D24_A: CPU1.E47 RAM1.N11
LPDDR3_M0_D24_B: CPU1.AH50 RAM1.C13
LPDDR3_M0_D25_A: CPU1.C49 RAM1.N12
LPDDR3_M0_D25_B: CPU1.AD48 RAM1.C14
LPDDR3_M0_D26_A: CPU1.D48 RAM1.P12
LPDDR3_M0_D26_B: CPU1.AD50 RAM1.C15
LPDDR3_M0_D27_A: CPU1.D52 RAM1.T13
LPDDR3_M0_D27_B: CPU1.AE53 RAM1.C16
LPDDR3_M0_D28_A: CPU1.F50 RAM1.R13
LPDDR3_M0_D28_B: CPU1.AH48 RAM1.B13
LPDDR3_M0_D29_A: CPU1.E51 RAM1.P13
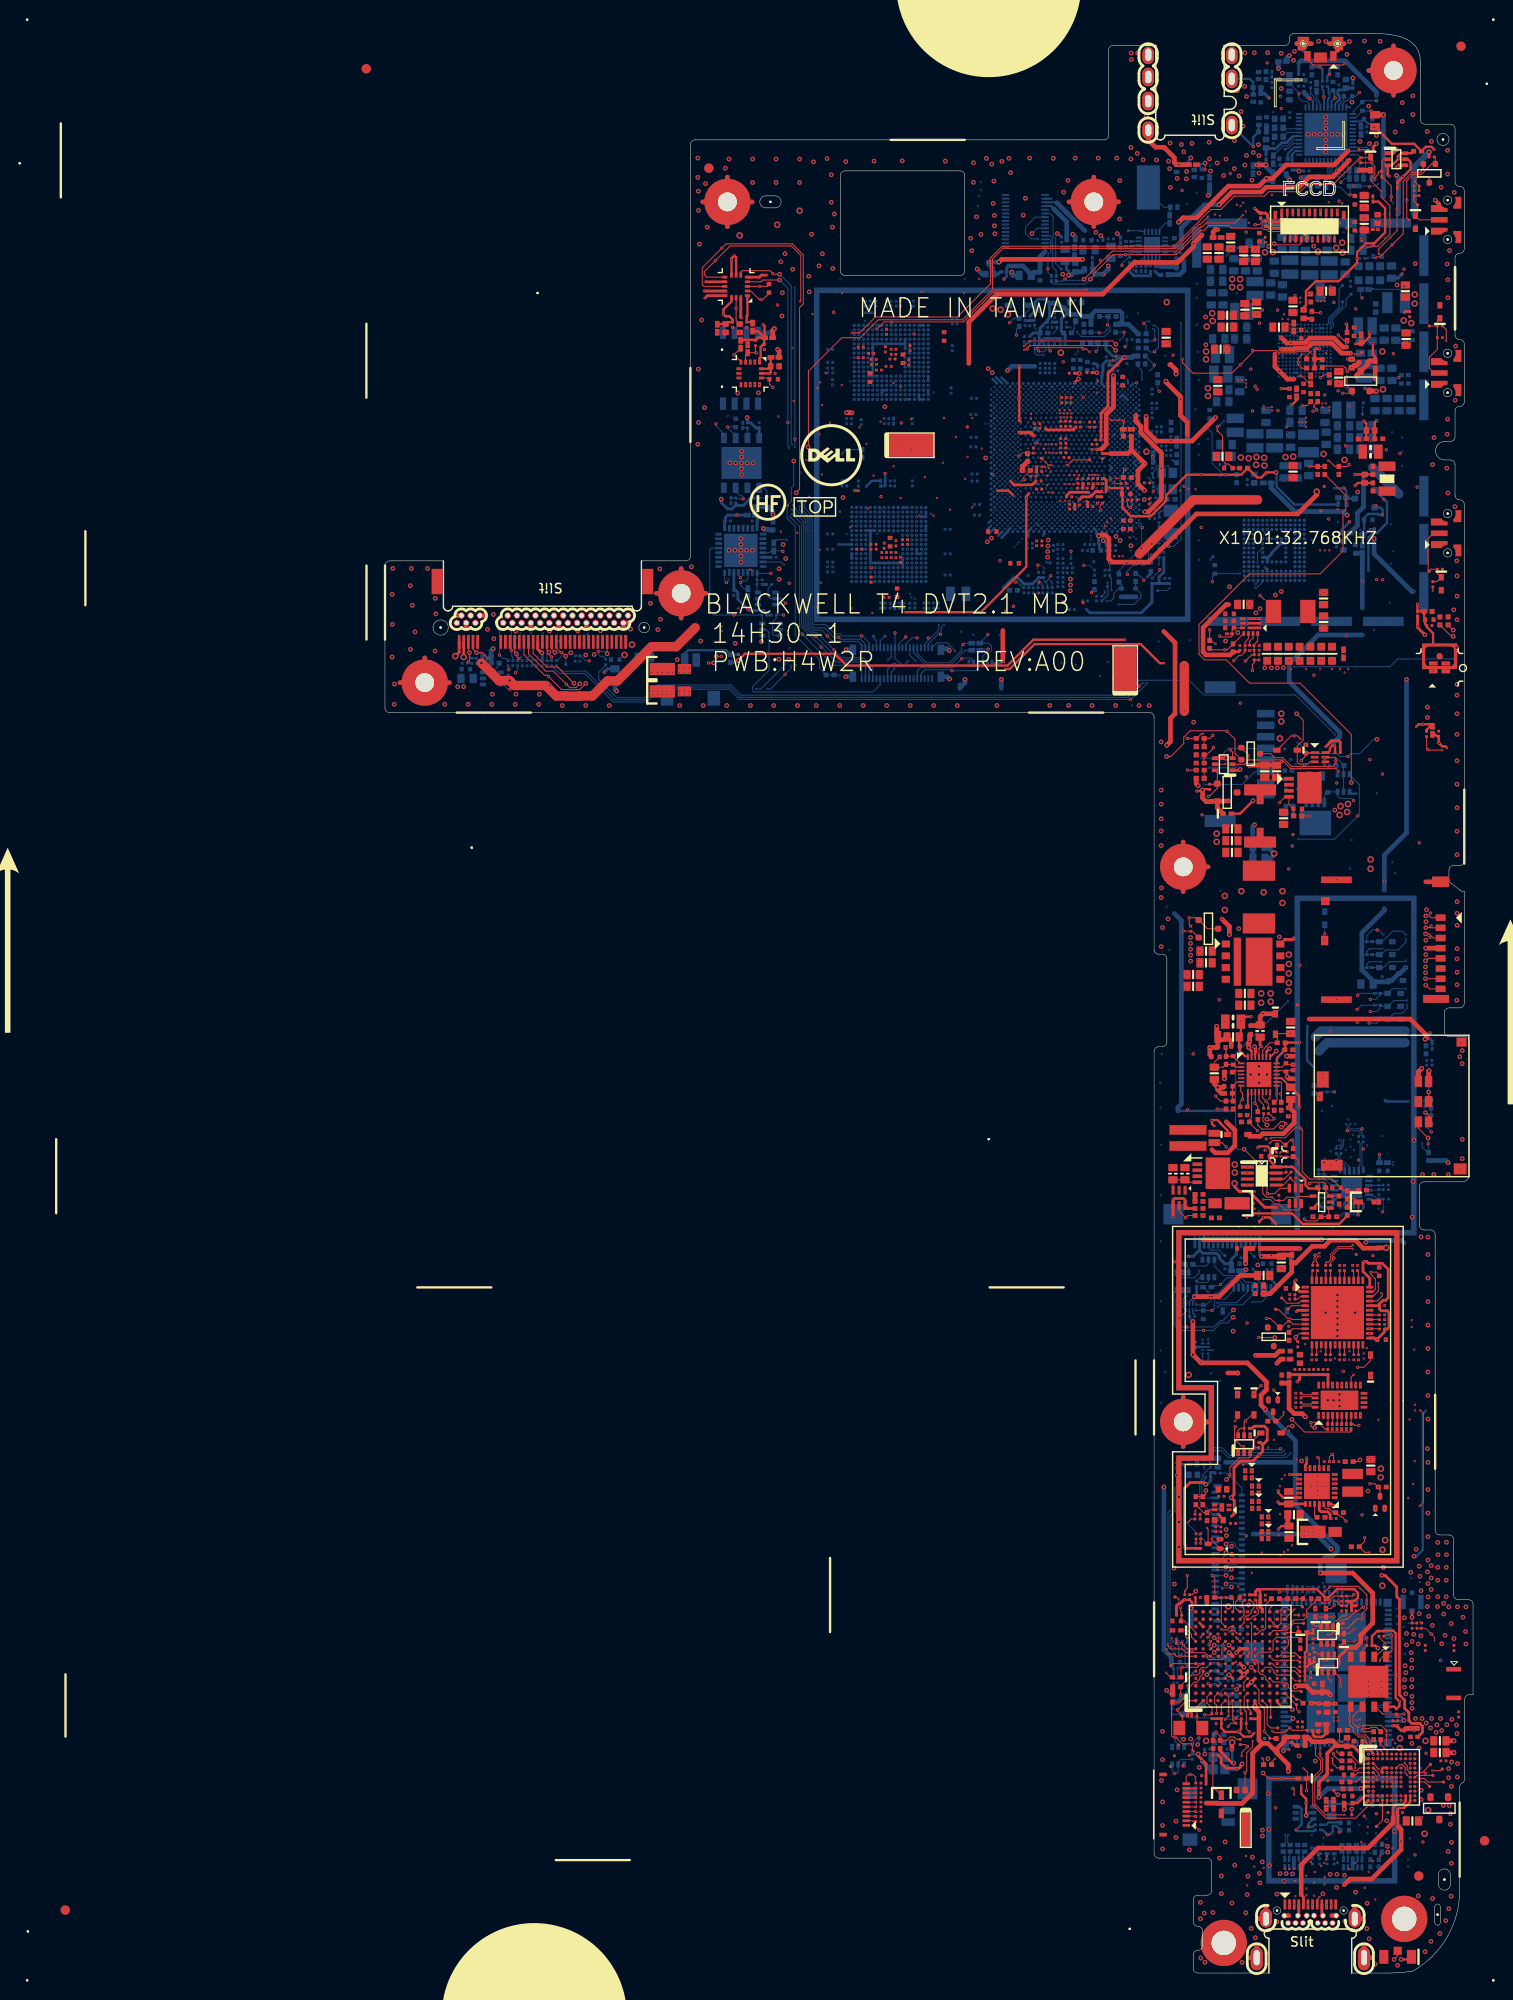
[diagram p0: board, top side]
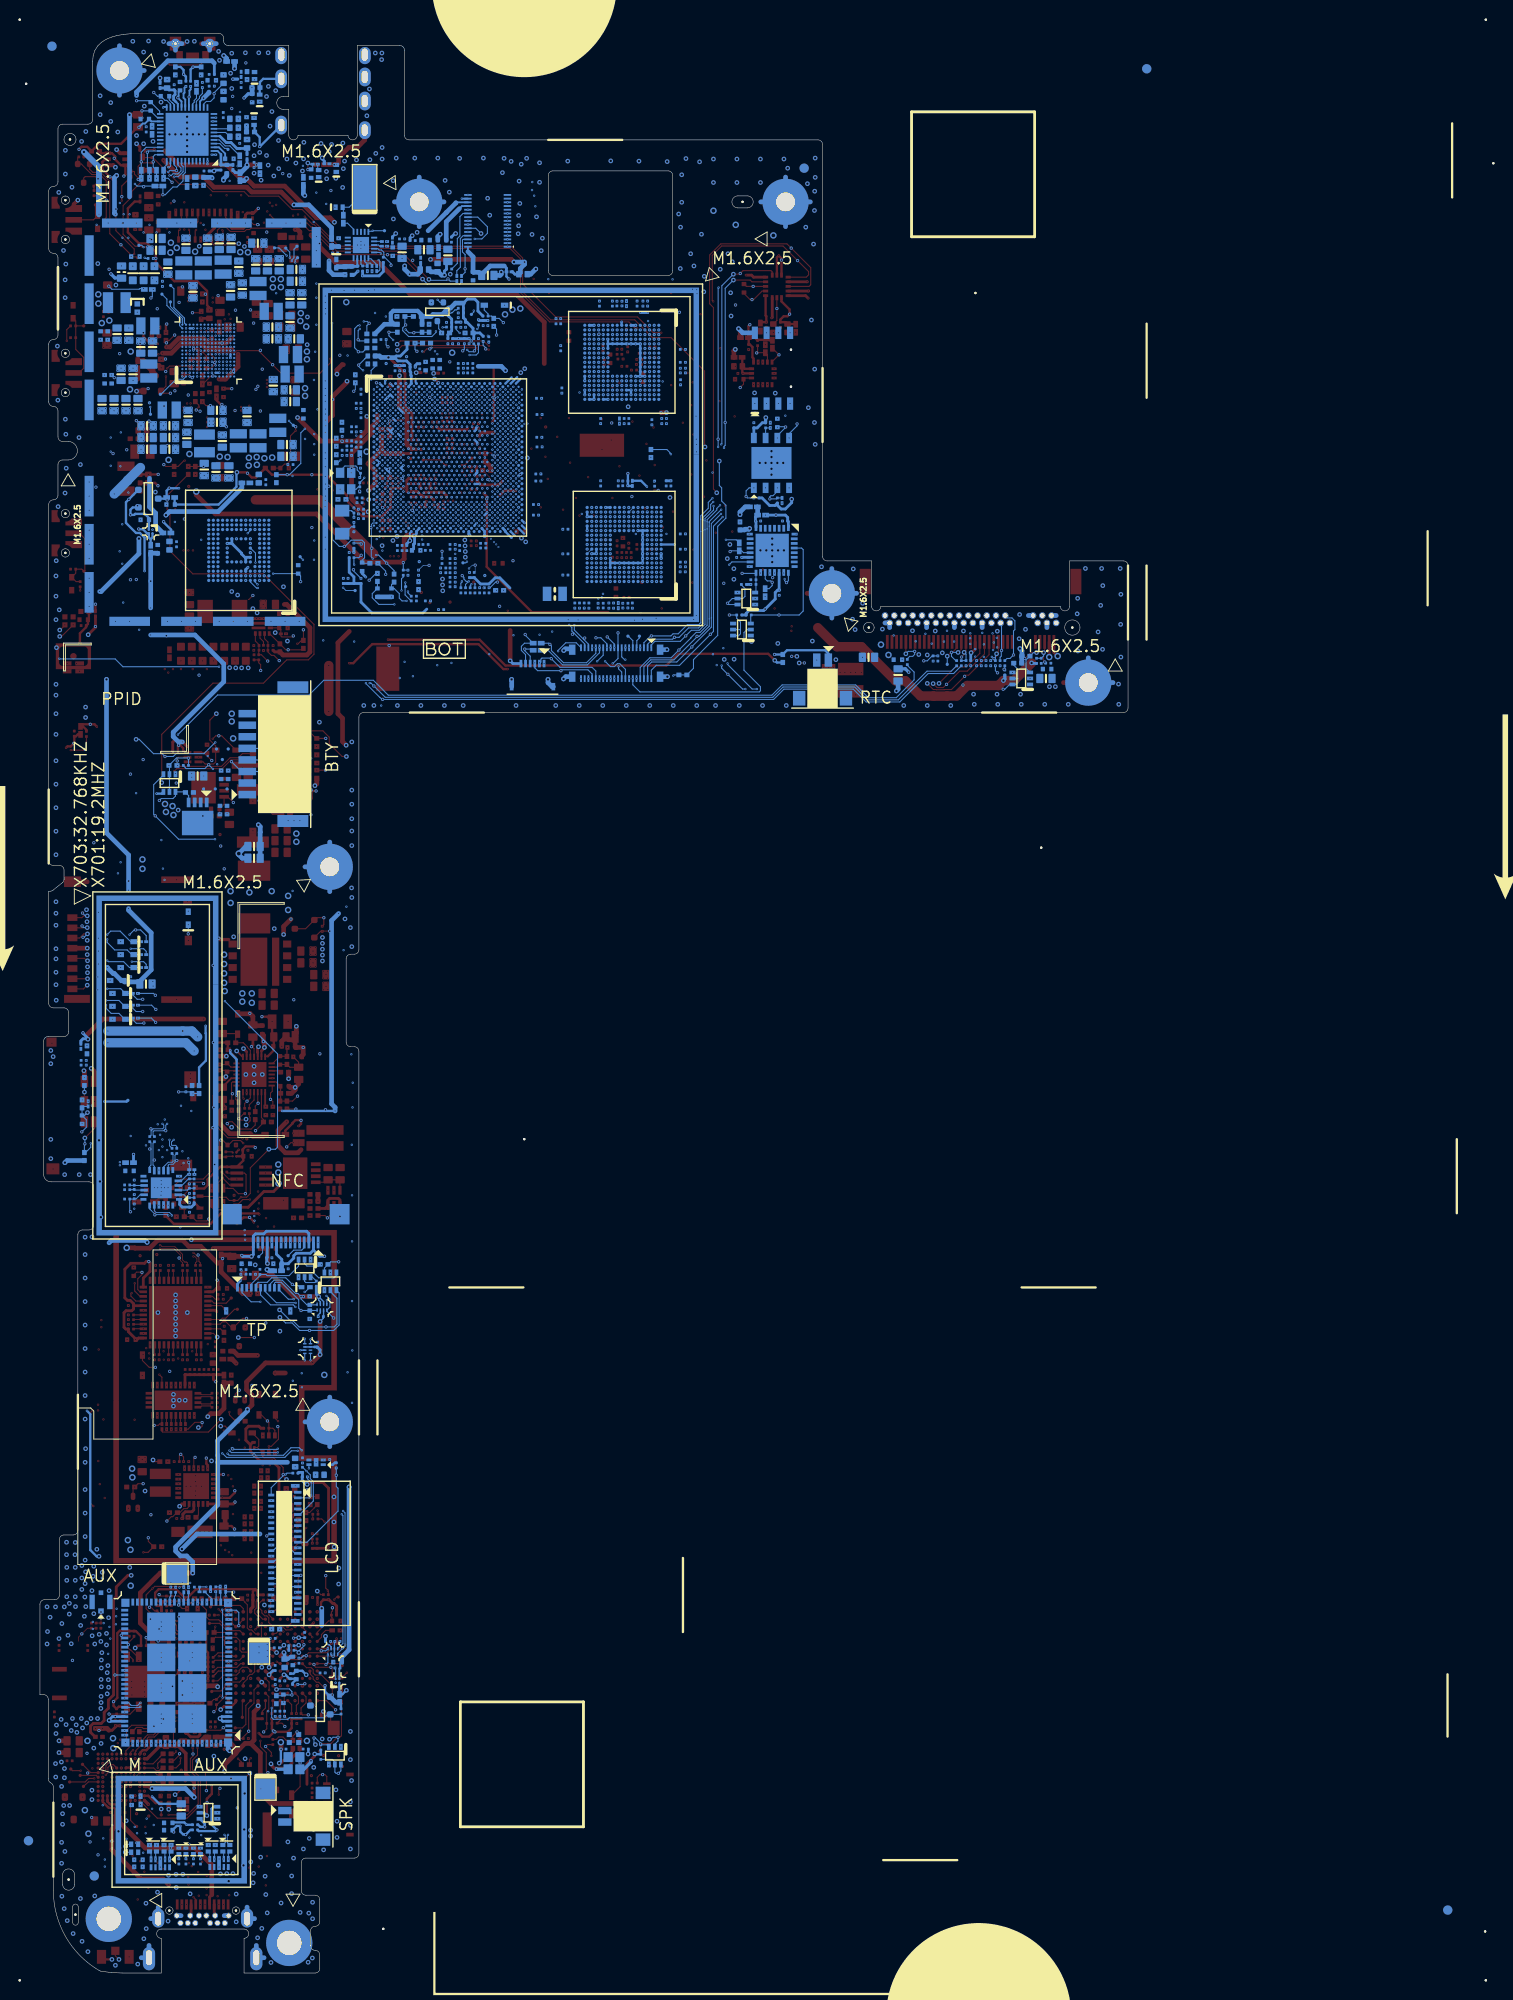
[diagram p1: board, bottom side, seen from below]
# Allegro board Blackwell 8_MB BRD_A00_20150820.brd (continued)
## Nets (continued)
LPDDR3_M0_D29_B: CPU1.AF48 RAM1.B14
LPDDR3_M0_D30_A: CPU1.C53 RAM1.T14
LPDDR3_M0_D30_B: CPU1.AE49 RAM1.B15
LPDDR3_M0_D31_A: CPU1.F52 RAM1.R14
LPDDR3_M0_D31_B: CPU1.AF52 RAM1.B16
LPDDR3_M0_DM0_A: CPU1.M46 RAM1.N6
LPDDR3_M0_DM0_B: CPU1.U55 RAM1.H14
LPDDR3_M0_DM1_A: CPU1.G47 RAM1.P8
LPDDR3_M0_DM1_B: CPU1.AF56 RAM1.F13
LPDDR3_M0_DM2_A: CPU1.F46 RAM1.P4
LPDDR3_M0_DM2_B: CPU1.AB50 RAM1.L14
LPDDR3_M0_DM3_A: CPU1.E49 RAM1.P11
LPDDR3_M0_DM3_B: CPU1.AB48 RAM1.D14
LPDDR3_M0_DQS0_N_A: CPU1.J47 RAM1.N7
LPDDR3_M0_DQS0_N_B: CPU1.V56 RAM1.J13
LPDDR3_M0_DQS0_P_A: CPU1.K46 RAM1.P7
LPDDR3_M0_DQS0_P_B: CPU1.W55 RAM1.J14
LPDDR3_M0_DQS1_N_A: CPU1.G51 RAM1.N9
LPDDR3_M0_DQS1_N_B: CPU1.AD58 RAM1.G13
LPDDR3_M0_DQS1_P_A: CPU1.H50 RAM1.P9
LPDDR3_M0_DQS1_P_B: CPU1.AE57 RAM1.G14
LPDDR3_M0_DQS2_N_A: CPU1.C47 RAM1.R4
LPDDR3_M0_DQS2_N_B: CPU1.W51 RAM1.M15
LPDDR3_M0_DQS2_P_A: CPU1.B46 RAM1.T4
LPDDR3_M0_DQS2_P_B: CPU1.Y50 RAM1.M16
LPDDR3_M0_DQS3_N_A: CPU1.C51 RAM1.R12
LPDDR3_M0_DQS3_N_B: CPU1.AE51 RAM1.D15
LPDDR3_M0_DQS3_P_A: CPU1.B50 RAM1.T12
LPDDR3_M0_DQS3_P_B: CPU1.AF50 RAM1.D16
LPDDR3_M0_ODT_A: CPU1.B54 RAM1.N8
LPDDR3_M0_ODT_B: CPU1.C55 RAM1.H13
LPDDR3_M1_CA0: CPU1.BJ49 R1409.1 RAM2.B5 RAM2.L2
LPDDR3_M1_CA1: CPU1.BH50 R1410.1 RAM2.C5 RAM2.L3
LPDDR3_M1_CA2: CPU1.BF48 R1411.1 RAM2.D5 RAM2.L4
LPDDR3_M1_CA3: CPU1.BJ51 R1412.1 RAM2.B6 RAM2.K2
LPDDR3_M1_CA4: CPU1.BH54 R1413.1 RAM2.C6 RAM2.K3
LPDDR3_M1_CA5: CPU1.BJ55 R1414.1 RAM2.C9 RAM2.G3
LPDDR3_M1_CA6: CPU1.BG51 R1415.1 RAM2.D9 RAM2.G4
LPDDR3_M1_CA7: CPU1.BJ57 R1416.1 RAM2.B10 RAM2.F2
LPDDR3_M1_CA8: CPU1.BD52 R1417.1 RAM2.C10 RAM2.F3
LPDDR3_M1_CA9: CPU1.BE53 R1418.1 RAM2.D10 RAM2.F4
LPDDR3_M1_CKE0_A: CPU1.BK56 RAM2.C7
LPDDR3_M1_CKE0_B: CPU1.BM58 RAM2.J3
LPDDR3_M1_CKE1_A: CPU1.BT58 RAM2.D7
LPDDR3_M1_CKE1_B: CPU1.BU57 RAM2.J4
LPDDR3_M1_CLK_DN_A: CPU1.BF54 R1422.2 RAM2.C8
LPDDR3_M1_CLK_DN_B: CPU1.BG55 R1423.2 RAM2.H2
LPDDR3_M1_CLK_DP_A: CPU1.BF56 R1422.1 RAM2.B8
LPDDR3_M1_CLK_DP_B: CPU1.BG57 R1423.1 RAM2.H3
LPDDR3_M1_CS0_B: CPU1.BL57 RAM2.D6 RAM2.K4
LPDDR3_M1_CS1_B: CPU1.BV56 RAM2.B7 RAM2.J2
LPDDR3_M1_D0_A: CPU1.AN57 RAM2.N4
LPDDR3_M1_D0_B: CPU1.BL51 RAM2.L15
LPDDR3_M1_D1_A: CPU1.AU55 RAM2.T5
LPDDR3_M1_D1_B: CPU1.BL49 RAM2.L16
LPDDR3_M1_D2_A: CPU1.AU57 RAM2.R5
LPDDR3_M1_D2_B: CPU1.BL53 RAM2.K13
LPDDR3_M1_D3_A: CPU1.AR55 RAM2.P5
LPDDR3_M1_D3_B: CPU1.BK52 RAM2.K14
LPDDR3_M1_D4_A: CPU1.AN55 RAM2.N5
LPDDR3_M1_D4_B: CPU1.BM52 RAM2.K15
LPDDR3_M1_D5_A: CPU1.AV54 RAM2.T6
LPDDR3_M1_D5_B: CPU1.BN49 RAM2.K16
LPDDR3_M1_D6_A: CPU1.AV56 RAM2.R6
LPDDR3_M1_D6_B: CPU1.BM48 RAM2.J15
LPDDR3_M1_D7_A: CPU1.AW57 RAM2.P6
LPDDR3_M1_D7_B: CPU1.BJ47 RAM2.J16
LPDDR3_M1_D8_A: CPU1.AW55 RAM2.T9
LPDDR3_M1_D8_B: CPU1.BL45 RAM2.F14
LPDDR3_M1_D9_A: CPU1.AY58 RAM2.R9
LPDDR3_M1_D9_B: CPU1.BH44 RAM2.F15
LPDDR3_M1_D10_A: CPU1.BA57 RAM2.T10
LPDDR3_M1_D10_B: CPU1.BK44 RAM2.F16
LPDDR3_M1_D11_A: CPU1.AY54 RAM2.R10
LPDDR3_M1_D11_B: CPU1.BL43 RAM2.E13
LPDDR3_M1_D12_A: CPU1.BD58 RAM2.P10
LPDDR3_M1_D12_B: CPU1.BN43 RAM2.E14
LPDDR3_M1_D13_A: CPU1.BE55 RAM2.N10
LPDDR3_M1_D13_B: CPU1.BM42 RAM2.E15
LPDDR3_M1_D14_A: CPU1.BC57 RAM2.T11
LPDDR3_M1_D14_B: CPU1.BJ43 RAM2.E16
LPDDR3_M1_D15_A: CPU1.BD54 RAM2.R11
LPDDR3_M1_D15_B: CPU1.BK42 RAM2.D13
LPDDR3_M1_D16_A: CPU1.AP52 RAM2.T2
LPDDR3_M1_D16_B: CPU1.BP52 RAM2.P15
LPDDR3_M1_D17_A: CPU1.AR49 RAM2.R2
LPDDR3_M1_D17_B: CPU1.BU53 RAM2.P16
LPDDR3_M1_D18_A: CPU1.AP48 RAM2.P2
LPDDR3_M1_D18_B: CPU1.BR51 RAM2.N14
LPDDR3_M1_D19_A: CPU1.AM48 RAM2.N2
LPDDR3_M1_D19_B: CPU1.BP50 RAM2.N15
LPDDR3_M1_D20_A: CPU1.AR53 RAM2.T3
LPDDR3_M1_D20_B: CPU1.BT52 RAM2.N16
LPDDR3_M1_D21_A: CPU1.AT50 RAM2.R3
LPDDR3_M1_D21_B: CPU1.BT48 RAM2.M13
LPDDR3_M1_D22_A: CPU1.AT48 RAM2.P3
LPDDR3_M1_D22_B: CPU1.BU49 RAM2.M14
LPDDR3_M1_D23_A: CPU1.AM50 RAM2.N3
LPDDR3_M1_D23_B: CPU1.BR47 RAM2.L13
LPDDR3_M1_D24_A: CPU1.AV52 RAM2.N11
LPDDR3_M1_D24_B: CPU1.BU45 RAM2.C13
LPDDR3_M1_D25_A: CPU1.AY52 RAM2.N12
LPDDR3_M1_D25_B: CPU1.BU43 RAM2.C14
LPDDR3_M1_D26_A: CPU1.AW53 RAM2.P12
LPDDR3_M1_D26_B: CPU1.BT44 RAM2.C15
LPDDR3_M1_D27_A: CPU1.AY48 RAM2.T13
LPDDR3_M1_D27_B: CPU1.BR45 RAM2.C16
LPDDR3_M1_D28_A: CPU1.BB50 RAM2.R13
LPDDR3_M1_D28_B: CPU1.BP42 RAM2.B13
LPDDR3_M1_D29_A: CPU1.AW51 RAM2.P13
LPDDR3_M1_D29_B: CPU1.BR43 RAM2.B14
LPDDR3_M1_D30_A: CPU1.BB48 RAM2.T14
LPDDR3_M1_D30_B: CPU1.BV42 RAM2.B15
LPDDR3_M1_D31_A: CPU1.BA49 RAM2.R14
LPDDR3_M1_D31_B: CPU1.BP44 RAM2.B16
LPDDR3_M1_DM0_A: CPU1.AP56 RAM2.N6
LPDDR3_M1_DM0_B: CPU1.BN47 RAM2.H14
LPDDR3_M1_DM1_A: CPU1.BC55 RAM2.P8
LPDDR3_M1_DM1_B: CPU1.BH46 RAM2.F13
LPDDR3_M1_DM2_A: CPU1.AV48 RAM2.P4
LPDDR3_M1_DM2_B: CPU1.BR49 RAM2.L14
LPDDR3_M1_DM3_A: CPU1.AV50 RAM2.P11
LPDDR3_M1_DM3_B: CPU1.BP46 RAM2.D14
LPDDR3_M1_DQS0_N_A: CPU1.AT58 RAM2.N7
LPDDR3_M1_DQS0_N_B: CPU1.BN51 RAM2.J13
LPDDR3_M1_DQS0_P_A: CPU1.AR57 RAM2.P7
LPDDR3_M1_DQS0_P_B: CPU1.BM50 RAM2.J14
LPDDR3_M1_DQS1_N_A: CPU1.BB56 RAM2.N9
LPDDR3_M1_DQS1_N_B: CPU1.BL47 RAM2.G13
LPDDR3_M1_DQS1_P_A: CPU1.BA55 RAM2.P9
LPDDR3_M1_DQS1_P_B: CPU1.BK46 RAM2.G14
LPDDR3_M1_DQS2_N_A: CPU1.AR51 RAM2.R4
LPDDR3_M1_DQS2_N_B: CPU1.BU51 RAM2.M15
LPDDR3_M1_DQS2_P_A: CPU1.AP50 RAM2.T4
LPDDR3_M1_DQS2_P_B: CPU1.BV50 RAM2.M16
LPDDR3_M1_DQS3_N_A: CPU1.BA51 RAM2.R12
LPDDR3_M1_DQS3_N_B: CPU1.BU47 RAM2.D15
LPDDR3_M1_DQS3_P_A: CPU1.AY50 RAM2.T12
LPDDR3_M1_DQS3_P_B: CPU1.BV46 RAM2.D16
LPDDR3_M1_ODT_A: CPU1.BU55 RAM2.N8
LPDDR3_M1_ODT_B: CPU1.BV54 RAM2.H13
LRESET#: R1739.2 U1704.M5
M0_ZQ0_A: R1306.1 RAM1.B11
M0_ZQ0_B: R1308.1 RAM1.E2
M0_ZQ1_A: R1305.1 RAM1.C11
M0_ZQ1_B: R1307.1 RAM1.E3
M1_ZQ0_A: R1406.1 RAM2.B11
M1_ZQ0_B: R1408.1 RAM2.E2
M1_ZQ1_A: R1405.1 RAM2.C11
M1_ZQ1_B: R1407.1 RAM2.E3
MC1CD#: D2308.1 MSD1.12 R510.2
MC1CK: CPU1.BL17 R2305.1
MC1CK_B: D2307.1 MSD1.5 R2305.2
MC1CM_B: D2306.1 MSD1.3 R2306.2
MC1CMD: CPU1.BR15 R2306.1
MC1DA0: CPU1.BK16 R2301.1
MC1DA0_B: D2301.1 MSD1.7 R2301.2
MC1DA1: CPU1.BP16 R2302.1
MC1DA1_B: D2302.1 MSD1.8 R2302.2
MC1DA2: CPU1.BH18 R2303.1
MC1DA2_B: D2303.1 MSD1.1 R2303.2
MC1DA3: CPU1.BL15 R2304.1
MC1DA3_B: D2304.1 MSD1.2 R2304.2
MCSI_1_CLK_DN: CAMR1.8 CPU1.D16
MCSI_1_CLK_DP: CAMR1.9 CPU1.C17
MCSI_1_DATA0_DN: CAMR1.5 CPU1.J19
MCSI_1_DATA0_DP: CAMR1.6 CPU1.H20
MCSI_1_DATA1_DN: CAMR1.2 CPU1.B20
MCSI_1_DATA1_DP: CAMR1.3 CPU1.C19
MCSI_2_CLK_DN: CAMF1.17 CPU1.J15
MCSI_2_CLK_DP: CAMF1.16 CPU1.H16
MCSI_2_DATA0_DN: CAMF1.14 CPU1.C15
MCSI_2_DATA0_DP: CAMF1.13 CPU1.B16
MCSI_2_DATA1_DN: CAMF1.20 CPU1.H14
MCSI_2_DATA1_DP: CAMF1.19 CPU1.G15
MCSI_COMP: CPU1.K18 R404.1
MDSI_A_CLKN_A: L3403.3 LCD1.29
MDSI_A_CLKP_A: L3403.2 LCD1.28
MDSI_A_DN_0_A: L3401.3 LCD1.23
MDSI_A_DN_1_A: L3402.3 LCD1.26
MDSI_A_DN_2_A: L3404.3 LCD1.32
MDSI_A_DN_3_A: L3405.3 LCD1.35
MDSI_A_DP_0_A: L3401.2 LCD1.22
MDSI_A_DP_1_A: L3402.2 LCD1.25
MDSI_A_DP_2_A: L3404.2 LCD1.31
MDSI_A_DP_3_A: L3405.2 LCD1.34
MDSI_C_CLK_DN: CPU1.C5 L3403.4
MDSI_C_CLK_DP: CPU1.B6 L3403.1
MDSI_C_DATA0_DN: CPU1.D8 L3401.4
MDSI_C_DATA0_DP: CPU1.C9 L3401.1
MDSI_C_DATA1_DN: CPU1.H6 L3402.4
MDSI_C_DATA1_DP: CPU1.G7 L3402.1
MDSI_C_DATA2_DN: CPU1.D6 L3404.4
MDSI_C_DATA2_DP: CPU1.C7 L3404.1
MDSI_C_DATA3_DN: CPU1.H8 L3405.4
MDSI_C_DATA3_DP: CPU1.J9 L3405.1
MDSI_COMP: CPU1.K14 R403.2
MIC_CAP: C2006.1 U2001.14
MICBIAS1: C2011.2 R2202.1 U2001.13
MICBIAS2: C2010.2 R2201.1 U2001.9
MIPI_BKLT_EN: PMIC1.E11 PR5108.2
MIPI_PANEL_EN: PMIC1.E10 PR5107.2
MODEM_PWR_ON: CPU1.D40 R4010.2
MODEM_PWR_ON_R: NGFF1.6 R4003.1 R4010.1 R4018.1
MODEM_SLPCLK: CPU1.D36 R754.2 XDP1.40
MUX_AUXN: R3022.2 U2901.J2 U3102.27
MUX_AUXN_ST: C3010.1 U3102.29
MUX_AUXP: R3021.2 U2901.J1 U3102.28
MUX_AUXP_ST: C3009.1 U3102.30
MUX_ML0N: C3012.1 U3101.15
MUX_ML0N_ST: C3012.2 U3102.22
MUX_ML0P: C3011.1 U3101.16
MUX_ML0P_ST: C3011.2 U3102.23
MUX_ML1N: C3014.1 U3101.18
MUX_ML1N_ST: C3014.2 U3102.19
MUX_ML1P: C3013.1 U3101.19
MUX_ML1P_ST: C3013.2 U3102.20
MUX_ML2N: C3016.1 U3101.20
MUX_ML2N_ST: C3016.2 U3102.16
MUX_ML2P: C3015.1 U3101.21
MUX_ML2P_ST: C3015.2 U3102.17
MUX_ML3N: C3018.1 U3101.23
MUX_ML3N_ST: C3018.2 U3102.13
MUX_ML3P: C3017.1 U3101.24
MUX_ML3P_ST: C3017.2 U3102.14
MUX_SSRXN: C3142.1 U3101.27
MUX_SSRXP: C3143.1 U3101.28
MUX_SSTXN: C3141.1 U3101.25
MUX_SSTXP: C3140.1 U3101.26
MUX_TX1N: R3126.1 U3101.5
MUX_TX1P: R3125.1 U3101.4
MUX_TX2N: R3128.1 U3101.7
MUX_TX2P: R3127.1 U3101.6
MUX_TYPE_C_RX1+: L3102.4 U3101.1
MUX_TYPE_C_RX1-: L3102.1 U3101.2
MUX_TYPE_C_RX2+: L3105.1 U3101.9
MUX_TYPE_C_RX2-: L3105.4 U3101.10
MUX_TYPE_C_TX1+: L3101.4 R3125.2
MUX_TYPE_C_TX1-: L3101.1 R3126.2
MUX_TYPE_C_TX2+: L3106.1 R3127.2
MUX_TYPE_C_TX2-: L3106.4 R3128.2
NCF_SIMVCC: NFC1.4 TP3902.1
NFC_DWL_REQ: CPU1.J35 NFC1.5 R705.2
NFC_EN_SEC: CPU1.K34 NFC1.6 R724.2
NFC_HOST_INT_SEC: CPU1.F36 NFC1.11 R729.2
NFC_SWP: NFC1.13 TP3901.1
NFC_VCC_BOOST: C3904.1 C3905.1 NFC1.12 R3905.2 TP3903.1
OTG_ID: D2902.K U2901.E10
P_RCOMP_N: CPU1.BA3 R502.1
P_RCOMP_P: CPU1.AY2 R502.2
PANEL_EN: D3401.1 PR5107.1 R1711.1 R4303.2
PANEL_EN_L: R4303.1 TP1.10
PANEL_EN_R: D3401.3 R3403.1 R3408.1 U3401.4
PCIE_CLKN0: CPU1.BB4 WU3701.33
PCIE_CLKP0: CPU1.BA5 WU3701.34
PCIE_CLKREQ0#: CPU1.BR39 WR3703.2 WU3701.30
PCIE_RXN0: CPU1.AW3 WR3713.2
PCIE_RXP0: CPU1.AY4 WR3712.2
PCIE_TXN0: CPU1.AV10 WC3713.1
PCIE_TXP0: CPU1.AU11 WC3714.1
PEWAKE#: WR3710.1 WU3701.29
PLT_CLK1_CAM1: C712.1 CAMR1.25 R723.1
PLT_CLK1_CAM1_1: CPU1.BP8 R723.2
PLT_CLK1_CAM2: C711.1 CAMF1.8 R722.1
PLT_CLK1_CAM2_1: CPU1.BR9 R722.2
PLTRST#: CPU1.BJ5 PMIC1.N6 U1706.5 U5706.2 WR3705.1 WR3711.2 XDP1.27
PLTRST_EC: R1748.1 U1704.N11 U1706.3
PLTRST_N_3P3: C5707.1 R5720.2 U5702.17 U5706.3
PLTRST_N_3P3_R: R5717.1 U5706.5 U5706.6
PMIC_5V_EN: PMIC1.D11 R5217.1
PMIC_AGND: PMIC1.C9 PMIC1.K3 PMIC1.L13 PMIC1.N7 PR5115.1
PMIC_BATID: PMIC1.D8 PR5109.2
PMIC_INT: CPU1.E37 PMIC1.L7
PMIC_LCM_BKLT_EN: C4405.1 D3405.A D4402.1 PR5108.1 R4403.2
PMIC_LCM_BKLT_EN_R: D4402.3 R4404.1 U4401.7
PMIC_PANEL_PWM0: D4403.1 PMIC1.E5
PMIC_PANEL_PWM0_R: D4403.3 R4405.1 U4401.9
PMIC_PWRBTN#: R1737.1 U1704.J10
PMIC_PWRBTN_R#: PMIC1.J5 R1731.1 R1737.2
PMIC_SYSTHERM0: PMIC1.D5 PR5102.2 RT5101.2
PMIC_SYSTHERM1: PMIC1.E6 PR5103.2 RT5102.2
PMIC_SYSTHERM2: PMIC1.E7 PR5104.2 RT5103.2
PMIC_VBATSENSE: PMIC1.F8 PR5110.2
PMIC_VBUS_IN: PMIC1.H6 PR4914.1
PMIC_VDCIN: PMIC1.H5 PR4911.1 PR4912.1
PMU_BATTLOW#: CPU1.BH4 PMIC1.N10
PMU_SLP_S0I3_N: CPU1.BH6 XDP1.14
POWER_BUTTON_N: C5404.2 D5404.1 PKEY1.2 R5403.2 R5603.1 R5603.2 TP5401.1 XDP1.24
PPMIC_DEBUG_I2C_CLK: PMIC1.A1 TP5101.1
PPMIC_DEBUG_I2C_DATA: PMIC1.B1 TP5102.1
PROCHOT#: CPU1.H32 PMIC1.K8 PR4627.1 Q501.3 R514.1
PROJECT_ID1: R1729.2 U1704.G11
PROJECT_ID2: R1744.2 U1704.G12
PROX_CX: R4105.2 U4101.5
PROX_CX_R: D4101.2 R4105.1 SPR1.1
PROX_DET#: CPU1.BT2 R4021.2
PS8713_3V3: C3132.1 C3133.1 R3146.2 R3161.1 R3163.1 R3167.1 R3168.1 R3170.1 R3171.1 U5407.1 U5407.13
PWR_AD: PG4603.1 PR4613.2 PR4615.2 PR4618.1 PR4621.1 PU4604.1 PU4604.2 PU4604.3
PWR_AD_B: PC4604.1 PC4608.1 PC4614.1 PC4618.1 PC4619.1 PC4625.1 PG4601.1 PR4618.2 PU4603.2 PU4603.3 PU4603.4 PU4603.10
PWR_BT_A: PC4610.1 PC4611.1 PG4602.2 PR4622.2 PU4602.1 PU4602.2 PU4602.3 Q1703.D
PWR_CHG_ACDET: PC4602.2 PR4608.2 PR4623.2 PR4633.2 PU4601.6
PWR_CHG_ACN: PC4612.2 PC4620.1 PG4601.2 PR4614.1 PU4601.1
PWR_CHG_ACOK: PR4642.2 PU4601.5 U701.3 U4602.6
PWR_CHG_ACP: PC4613.2 PC4620.2 PC4623.1 PG4603.2 PR4614.2 PU4601.2
PWR_CHG_BAT: PR4605.2 PU4601.17
PWR_CHG_BATDRV#: PR4606.1 PU4601.18
PWR_CHG_BTST: PR4617.1 PU4601.25
PWR_CHG_BTST_A: PC4615.1 PD4601.K PR4617.2
PWR_CHG_CELL: PR4625.1 PU4601.16
PWR_CHG_CLK: PR4601.2 PU4601.12
PWR_CHG_CMPIN: PC4631.1 PU4601.13 R5721.2 R5722.1
PWR_CHG_CMPIN_L: PD4604.K PR4646.2 R5721.1
PWR_CHG_CMSRC: PR4621.2 PU4601.3
PWR_CHG_DATA: PR4602.2 PU4601.11
PWR_CHG_HG: PU4601.26 PU4603.1
PWR_CHG_IADP: PC4626.1 PU4601.7 U1704.L2
PWR_CHG_IBAT: PC4627.1 PU4601.8 U1704.M1
PWR_CHG_ILIM: PR4628.2 PR4629.1 PU4601.21
PWR_CHG_LG: PU4601.23 PU4603.8
PWR_CHG_PH: PC4615.2 PL4601.1 PU4601.27 PU4603.9
PWR_CHG_PMON: PR4632.1 PU4601.9
PWR_CHG_PROCHOT#: PR4627.2 PU4601.10
PWR_CHG_REGN: C5711.1 PC4616.1 PD4601.A PR4628.1 PR4635.2 PU4601.24
PWR_CHG_REGN_R: PR4635.1 PR4640.2 U1705.B2
PWR_CHG_SRN: PC4609.1 PC4621.2 PG4602.1 PU4601.19
PWR_CHG_SRP: PC4601.1 PC4621.1 PG4604.1 PU4601.20
PWR_CHG_VCC: PC4607.1 PC4624.1 PR4603.2 PR4646.1 PU4601.28
PWR_CHG_VCC_A: PD4605.K PD4607.K PR4603.1
PWR_SW_IN#: PD4606.K R5403.1 U5401.3
R_OSC: R2903.1 U2901.G2
RF_LTE_SIM1_CLK: NGFF1.32 R2403.1
RF_LTE_SIM1_DATA: D2405.2 MSIM1.7 NGFF1.34
RF_LTE_SIM1_DET: C2401.2 D2402.2 MSIM1.10 PR5106.1 R4012.2
RF_LTE_SIM1_RST: D2403.2 MSIM1.2 NGFF1.30
RF_LTE_UIM_PWR: C4001.1 NGFF1.36 R2401.1
RF_W_DISABLE: R4017.1 U4002.5 U4002.6
RF_W_DISABLE#: NGFF1.8 R4020.2 U4002.3
RF_WIFI_ANT_AUX_1: ANT1.1 WC3706.1 WL3701.1
RF_WIFI_ANT_AUX_2: ANT2.1 WC3707.1 WC3709.2 WL3701.2
RF_WIFI_ANT_AUX_3: WC3708.1
RF_WWAN_DISABLE#_1P8: CPU1.J39 U4002.2 U4101.16
RSMRST#: CPU1.BE3 PMIC1.H11 R714.1 XDP1.21
RTC_CLK: WR3704.2 WU3701.27
RTC_XTAL_IN: C708.1 CPU1.BG9 R730.1 X703.1
RTC_XTAL_OUT: C707.1 CPU1.BF10 R730.2 X703.2
SAR_A0: R4107.1 U4101.19
SAR_A1: R4103.1 U4101.18
SAR_CSG: TP4101.1 U4101.1
SAR_INT: CPU1.BM2 R4108.1
SAR_INT_R: R4101.2 R4108.2 U4101.13
SAR_RST: R4106.2 U4101.17
SAR_SVDD_V1P8: C4103.1 C4104.1 D1708.A R4104.2 U4101.12
SD3_CD#: C501.1 CPU1.BU17 R510.1
SDIO3_RCOMP: CPU1.BH16 R504.2
SDIO_PWR_EN#: CPU1.BU23 PMIC1.L4
SDMMC3_1P8_EN: CPU1.BT22 PMIC1.K6
SIM1_CLK_C: C2404.1 D2404.2 MSIM1.3 R2403.2
SIM_DETECT: NGFF1.66 R4012.1
SLP_S0IX#: CPU1.BL3 PMIC1.M4 U1708.2 U5709.2 XDP1.12
SLP_S0IX#_EC: R1730.2 U1704.J11 U1708.3
SLP_S0IX#_EC_R: R1732.1 U1708.5 U1708.6
SLP_S3#: CPU1.BJ3 U1709.2
SLP_S3#_R: R1740.1 U1709.5 U1709.6
SLP_S4#: CPU1.BJ9 U1710.2
SLP_S4#_R: R1745.1 U1710.5 U1710.6
SMB3_CLK_BATT: R1717.1 R4502.1 U1704.F8
SMB3_CLK_BATT_R: BATT1.3 D4502.1 R4502.2
SMB3_DAT_BATT: R1718.1 R4503.1 U1704.D9
SMB3_DAT_BATT_R: BATT1.4 D4501.1 R4503.2
SND75DP130SS_3V3: C3031.1 C3032.1 C3033.1 R3016.1 R3019.2 R3020.2 R3022.1 R3026.1 U3102.1 U3102.6 U3102.12 U3102.25 U3102.32 U3102.36
SOC_PROJECT_ID1: CPU1.K32 R411.2 R412.2
SOC_PROJECT_ID2: CPU1.E30 R417.2 R418.2
SOC_PWRBTN#: CPU1.BH10 PMIC1.K7
SOC_RTEST#: CPU1.BD4 PC5004.1 PC5005.2 PMIC1.J6 XDP1.39
SOC_VBUSSNS: CPU1.T8 R408.2
SPI3_CS0_N: CPU1.BM38 R509.2
SPI_CLK: BIOS1.6 BSKT1.6 C1802.2 CPU1.BP24
SPI_CS#: BIOS1.1 BSKT1.1 CPU1.BU25 R1804.2
SPI_MISO: BIOS1.2 BSKT1.2 CPU1.BK26
SPI_MODE: CPU1.G37 R753.2
SPI_MOSI: BIOS1.5 BSKT1.5 CPU1.BN25
SPK_LN: C2104.1 D2102.2 R2108.1 U2001.48
SPK_LN_R: R2108.2 SPK1.2
SPK_LP: C2103.1 D2101.2 R2107.1 U2001.1
SPK_LP_R: R2107.2 SPK1.1
SRT_CRST#: C709.1 CPU1.BF4 R739.2 XDP1.22
SUS_CLK_WLAN: CPU1.BM6 WR3704.1
SUS_PWRDOWNACK: CPU1.BK22 PMIC1.L12
SVID_ALERT#: CPU1.C33 PMIC1.M5 PR4907.2
SVID_CLK: CPU1.F32 PMIC1.M7 PR4909.2
SVID_DATA: CPU1.D32 PMIC1.M6 PR4908.2
SX_OFF: PMIC1.F12 PR5113.2
SYS_PWR_ON: D5411.1 R5409.2 R5410.1 U1706.2 U4501.2 U4501.5
SYS_PWR_ON#: Q4501.4 R4501.2 U4501.6
T0: PMIC1.A14 TP5103.1
T1: PMIC1.A15 TP5105.1
T2: PMIC1.B14 TP5106.1
T3: PMIC1.B15 TP5107.1
T4: PMIC1.R14 TP5108.1
T5: PMIC1.R15 TP5109.1
T6: PMIC1.P14 TP5110.1
T7: PMIC1.P15 TP5111.1
T8: PMIC1.B2 TP5112.1
T9: PMIC1.P2 TP5113.1
TOUCH_INT#: CPU1.BJ21 D1705.A R713.1
TOUCH_INT#_3P3: D1705.K TP1.5
TOUCH_RESET#: CPU1.C35 R720.1 R750.1 U4302.2
TOUCH_RESET#_3P3: R4311.2 TP1.4 U4302.3
TOUCH_RESET#_R: R4310.1 U4302.5 U4302.6
TP_1P05_OBS: CPU1.BF38 TP801.1
TP_FUSE_PWRMON: CPU1.BF8 TP701.1
TP_ID1: R1712.2 TP1.7
TP_ID2: R1714.2 TP1.6
TP_VCCCORE2_OBS: CPU1.AM34 TP802.1
TP_VCCDDR_1P24_1P35_OBS: CPU1.L37 TP805.1
TP_VCCSRAMGEN_1P15_OBS: CPU1.AT32 TP804.1
TP_VCCSRAMSOC_1P15_OBS: CPU1.V27 TP803.1
TPM_GPIO0: R5726.2 U5702.29 U5709.3
TPM_GPIO0#: R5725.1 U5709.5 U5709.6
TPM_SCLK: R5712.2 U5702.19
TPS65982_DEBUG3: D5412.K R3130.1 U2901.L3
TPS65982_DEBUG3_R: R3130.2 U3101.8
TPS65982_DEBUG4: D3001.K R3129.1 R3165.1 U2901.K3
TPS65982_DEBUG4_R: R3129.2 R3165.2 U3101.17 U5407.5
TPS65982_GPIO0: R3131.1 U2901.B2
TPS65982_GPIO0_R: R3131.2 U3101.3
TPS65982_GPIO1: R5723.1 R5724.1 U2901.C2
TPS65982_GPIO2: R1715.1 U2901.D10
TPS65982_GPIO3: TP2913.1 U2901.G11
TPS65982_GPIO4_HPD: R2918.2 U2901.C10
TPS65982_GPIO6: TP2912.1 U2901.G10
TPS65982_GPIO7: TP2916.1 U2901.D7
TPS65982_GPIO8: D2901.K U2901.H6
TPS65982_I2C_ADDR: R2905.1 U2901.F1
TPS65982_I2C_IRQ1#: R2910.1 U2901.C1
TPS65982_I2C_IRQ2#: R2911.1 R2921.1 U2901.B6
TPS65982_I2C_IRQ2#_R: R1743.2 R2921.2 U1704.B5
TPS65982_I2C_SCL1: R2909.1 U2901.D2
TPS65982_I2C_SCL2: R2917.1 U2901.B5
TPS65982_I2C_SDA1: R2908.1 U2901.D1
TPS65982_I2C_SDA2: R2916.1 U2901.A5
TPS65982_LDO_1V8A: C2917.1 U2901.K1
TPS65982_LDO_1V8D: C2916.1 U2901.A2 U2901.F10
TPS65982_LDO_3V3: C2915.1 R2912.2 R2913.2 R2914.2 R2915.2 U2901.D5 U2901.E4 U2901.G1 U2903.8
TPS65982_LDO_BMC: C2918.1 U2901.E1
TPS65982_LSX_P2P: TP2905.1 U2901.L4
TPS65982_LSX_P2R: TP2906.1 U2901.K4
TPS65982_MRESET: TP2918.1 U2901.E11
TPS65982_RESET#: TP2919.1 U2901.F11
TPS65982_SPI_CLK: U2901.A3 U2903.6
TPS65982_SPI_HOLD: R2912.1 U2903.7
TPS65982_SPI_MISO: R2914.1 U2901.A4 U2903.2
TPS65982_SPI_MOSI: U2901.B4 U2903.5
TPS65982_SPI_SSZ: R2915.1 U2901.B3 U2903.1
TPS65982_SPI_WP: R2913.1 U2903.3
TPS65982_SS: C2902.2 U2901.H7
TPS65982_SWD_CLK: TP2908.1 U2901.G4
TPS65982_SWD_DATA: TP2907.1 U2901.F4
TPS65982_UART_RX: TP2910.1 U2901.F2
TPS65982_UART_TX: TP2909.1 U2901.E2
TPS65982_VOUT_3V3: C2914.1 U2901.H2
TXE_WP: U701.2 U1704.J6
TXE_WP#: R750.2 U701.6
TYPE_C_IRQ#: R1738.1 R2910.2 R2911.2 U1704.C6
TYPE_C_RX1+: JUSBC1.B11 L3102.3 U5707.4
TYPE_C_RX1-: JUSBC1.B10 L3102.2 U5707.5
TYPE_C_RX2+: JUSBC1.A11 L3105.2 U5708.5
TYPE_C_RX2-: JUSBC1.A10 L3105.3 U5708.4
TYPE_C_TX1+: JUSBC1.A2 L3101.3 U5707.1
TYPE_C_TX1-: JUSBC1.A3 L3101.2 U5707.2
TYPE_C_TX2+: JUSBC1.B2 L3106.2 U5708.2
TYPE_C_TX2-: JUSBC1.B3 L3106.3 U5708.1
UART0_DATAIN: CPU1.BJ37 R508.2
UART0_DBG_RXD: CPU1.F20 R5602.1 XDP1.31
UART0_DBG_TXD: CPU1.E21 R5601.1 XDP1.29
UART_3_RXD_R: DB2.5 R5602.2
UART_3_TXD_R: DB2.4 R5601.2
USB2_DEBUG_TYPE_A_DN: CPU1.V10 XDP1.28
USB2_DEBUG_TYPE_A_DP: CPU1.W9 XDP1.26
USB2_OTG_DN: CPU1.W11 R2920.2
USB2_OTG_DN_R: R2920.1 U2901.K5
USB2_OTG_DP: CPU1.V12 R2919.2
USB2_OTG_DP_R: R2919.1 U2901.L5
USB2_WIFI_DN: CPU1.AA5 WU3701.69
USB2_WIFI_DP: CPU1.Y6 WU3701.70
USB3_0_RX+: C3146.1 CPU1.AM8
USB3_0_RX+_L: C3146.2 NGFF1.37
USB3_0_RX-: C3145.1 CPU1.AN9
USB3_0_RX-_L: C3145.2 NGFF1.35
USB3_0_TX+: C3144.1 CPU1.AE5
USB3_0_TX+_L: C3144.2 NGFF1.31
USB3_0_TX-: C3147.1 CPU1.AF4
USB3_0_TX-_L: C3147.2 NGFF1.29
USB3_A_INN: C3139.1 U5407.8
USB3_A_INP: C3138.1 U5407.9
USB3_A_OUTN: C3141.2 U5407.23
USB3_A_OUTP: C3140.2 U5407.22
USB3_B_INN: C3142.2 U5407.20
USB3_B_INP: C3143.2 U5407.19
USB3_B_OUTN: C3149.1 U5407.11
USB3_B_OUTP: C3148.1 U5407.12
USB3_DE1: R3171.2 R3172.1 U5407.3
USB3_DE2: R3170.2 R3173.1 U5407.16
USB3_EQ1: R3161.2 R3162.1 U5407.2
USB3_EQ2: R3163.2 R3164.1 U5407.17
USB3_OS1: R3166.1 R3167.2 U5407.4
USB3_OS2: R3168.2 R3169.1 U5407.15
USB3_RCOMP_N: CPU1.AH4 R648.2
USB3_RCOMP_P: CPU1.AK3 R648.1
USB3_RXN0: C3149.2 CPU1.AP4
USB3_RXP0: C3148.2 CPU1.AN5
USB3_TXN0: C3139.2 CPU1.AP10
USB3_TXP0: C3138.2 CPU1.AN11
USB_B_N: D5416.1 JUSBC1.B7 L3104.2
USB_B_P: D5415.1 JUSBC1.B6 L3104.3
USB_HSIC_RCOMP: CPU1.AD12 R640.2
USB_MODEM_DN: CPU1.W3 NGFF1.9
USB_MODEM_DP: CPU1.Y4 NGFF1.7
USB_OTG_SOC_ID: CPU1.BR23 D2902.A R742.2
USB_RCOMP: CPU1.AB12 R643.2
USB_SSIC_RCOMP_N: CPU1.AG9 R603.1
USB_SSIC_RCOMP_P: CPU1.AF8 R603.2
USB_T_N: D5414.1 JUSBC1.A7 L3103.3
USB_T_P: D5413.1 JUSBC1.A6 L3103.2
VGG_LX0: PL4701.1 PMIC1.H1
VGG_LX1: PL4702.1 PMIC1.L1
VGG_LX2: PL4703.1 PMIC1.N1
VGG_LX3: PL4704.1 PMIC1.R3
VGG_SENSE: CPU1.AW25 PMIC1.N4
VGG_VSSSENSE: CPU1.BA24 PMIC1.N3
VNN_LX: PL4708.1 PMIC1.R8 PMIC1.R9
VNN_SENSE: CPU1.AC26 PMIC1.L9
VNN_VSSSENSE: CPU1.AC24 PMIC1.L10
VOLUME_DOWN: C5403.2 D5402.1 R5405.2 TP5403.1 VDKEY1.2
VOLUME_DOWN_EC_IN: R1734.1 R5405.1 U1704.E12
VOLUME_DOWN_EC_OUT: D1703.K U1704.H10
VOLUME_DOWN_SOC: CPU1.K40 D1703.A
VOLUME_UP: C5402.2 D5401.1 R5404.2 TP5402.1 VUKEY1.2
VOLUME_UP_EC_IN: R1720.1 R5404.1 U1704.D11
VOLUME_UP_EC_OUT: D1704.K U1704.H9
VOLUME_UP_SOC: CPU1.BP38 D1704.A
VOUT_3V3: PC5104.1 PD5101.2 U5101.B1
VPP: MSIM1.6 TP2401.1
VREF25: PC5102.1 PMIC1.M3
VREF_VTT: R1758.1 U1704.B11
VSET_EC: C1717.1 R1754.1 U1704.E11
VSIM1_PMU_R: C2402.1 C2403.1 D2401.2 MSIM1.1 R2401.2
VSYS_SENSE_PMIC: PMIC1.J3 PR5105.2
WHITE_LED: C5714.1 LED1.2 R4903.2
WHITE_LED_EC: U1704.A4 U4901.5
WHITE_LED_R: R4903.1 U4901.3
WIFI_HOST_WAKE#: CPU1.BJ7 WR3708.2 WR3710.2
WIFI_PCIE_RXN0: WR3713.1 WU3701.36
WIFI_PCIE_RXP0: WR3712.1 WU3701.37
WIFI_PCIE_TXN0: WC3713.2 WU3701.39
WIFI_PCIE_TXP0: WC3714.2 WU3701.40
WIFI_PERST#: WR3711.1 WU3701.31
WL_DEV_EN: CPU1.BU21 WU3701.28
WWAN_DETECT#: CPU1.BU37 R511.2 R4013.1
WWAN_DETECT#_L: NGFF1.51 R4013.2 R4014.2
WWAN_WAKE#: CPU1.BK10 R4005.2 R4008.1
WWAN_WAKE_HOST#: NGFF1.23 R4008.2
XDP_H_PRDY#: CPU1.G33 XDP1.8
XDP_H_PREQ#: CPU1.H34 R751.2 XDP1.6
XDP_H_TCK: CPU1.F34 R737.2 XDP1.5
XDP_H_TDI: CPU1.E33 R736.2 XDP1.1
XDP_H_TDO: CPU1.J33 R740.2 XDP1.2
XDP_H_TMS: CPU1.B34 R735.2 XDP1.3
XDP_H_TRST#: CPU1.E35 R738.2 XDP1.4
XTAL19_2_IN: C701.2 CPU1.AY8 R716.1 X701.1
XTAL19_2_OUT: C702.2 CPU1.BA9 R716.2 X701.3

Pads without a net: AUDIO1 MS; CAMR1 11 12 14 15; CPU1 AA7 AA9 AB4 AB8 AB10 AC3 AC5 AC28 AD2 AD4 AD10 AE3 AE9 AE11 AF10 AF28 AF45 AG3 AH2 AH27 AH46 AK5 AK9 AK16 AK18 AK39 AK41 AM4 AM10 AM46 AN7 AP6 AP45 AR3 AR9 AT2 AT4 AT8 AT10 AU3 AU5 AU9 AV4 AY12 B12 B28 BC3 BC9 BD2 BD8 BD10 BE49 BE51 BF50 BH26 BH28 BH32 BH48 BJ30 BJ53 BK18 BK28 BK32 BK36 BL11 BL19 BL27 BL37 BL55 BM20 BM32 BM54 BN9 BN11 BN19 BN37 BN55 BN57 BP12 BP28 BP54 BP56 BR11 BR17 BR25 BR27 BR30 BR37 BR55 BR57 BT4 BT10 BT18 BT26 BU7 BU11 BU27 BU30 BV4 BV24 BV28 C3 C11 C13 C30 D2 D4 D10 D12 D14 D18 D26 E3 E5 E9 E13 E17 E25 E27 E39 E55 E57 F4 F12 F26 F28 F38 F54 F56 G3 G9 G11 G19 G27 G55 G57 H2 H4 H10 H18 H26 H54 J3 J5 J11 J17 J21 J30 J55 K4 K12 K16 K20 K26 K28 K38 L5 L9 L21 L53 M4 M6 M8 M10 M48 N5 N9 P50 R49 R51 U7 U9; EMMC1 A1 A2 A7 A8 A9 A10 A11 A12 A13 A14 B1 B7 B8 B9 B10 B11 B12 B13 B14 C1 C3 C5 C7 C8 C9 C10 C11 C12 C13 C14 D1 D2 D3 D4 D12 D13 D14 E1 E2 E3 E5 E8 E9 E10 E12 E13 E14 F1 F2 F3 F10 F12 F13 F14 G1 G2 G3 G10 G12 G13 G14 H1 H2 H3 H12 H13 H14 J1 J2 J3 J12 J13 J14 K1 K2 K3 K6 K7 K10 K12 K13 K14 L1 L2 L3 L12 L13 L14 M1 M2 M3 M7 M8 M9 M10 M11 M12 M13 M14 N1 N3 N6 N7 N8 N9 N10 N11 N12 N13 N14 P1 P2 P7 P8 P9 P10 P11 P12 P13 P14; LCD1 1 5 6 7 45; NGFF1 1 10 20 21 22 24 28 38 41 43 46 47 48 49 50 52 53 54 55 56 58 59 60 61 62 63 64 65 67 68 69 75; PMIC1 C11 C12 D7 E4 E12 F3 F4 F5 F9 F10 F11 G3 G4 G8 G9 G10 G11 H3 H7 J7 J8 J10 K9 K10 K11 L8 L11 M9 M10 M11 M12 N8 N9 P1 R1 R2; PU4601 4; RAM1 A1 A17 D8 D11 E4 H4 J12 M9 U1 U17; RAM2 A1 A17 D8 D11 E4 H4 J12 M9 U1 U17; U1704 A5 B2 B3 B4 B7 B8 B12 B13 C1 C4 C5 C7 C12 C13 D3 D4 D5 D7 D12 D13 E3 E4 E5 E6 E8 E13 F2 F10 F12 G2 H6 J8 J9 J12 J13 K2 K3 K6 K8 K9 K10 K12 L8 L9 L11 M2 M3 M4 M9 M10 M12 M13 N1 N3 N4 N9 N13; U2001 28 29 44 45; U2901 A9 B9 L11; U3101 11 12 13 14; U3102 7 15 21 37 40 43 46; U4101 2 3 4 7 8 9 10; U4401 8; U4602 3; U5401 4; U5407 7 14 24; U5702 2 3 4 5 6 7 10 11 12 25 26 27 28 30 31; U5707 6 7 9 10; U5708 6 7 9 10; WU3701 1 2 3 7 8 9 10 11 12 13 14 15 16 18 19 20 21 22 23 24 25 42 43 44 45 46 47 48 49 50 51 52 53 54 55 56 57 58 59 60 61 64 65 66 67; XDP1 38

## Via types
v1: diameter 0.356, hole 0.178, TOP to BOTTOM, 493 vias
v2: diameter 0.508, hole 0.254, TOP to BOTTOM, 789 vias
v3: diameter 0.254, hole 0.102, L5 to L6SGND, 660 vias
v4: diameter 0.254, hole 0.102, L6SGND to L7, 1652 vias
v5: diameter 0.254, hole 0.102, L7 to BOTTOM, 1657 vias
v6: diameter 0.22, hole 0.102, L5 to L6SGND, 392 vias
v7: diameter 0.22, hole 0.102, L6SGND to L7, 897 vias
v8: diameter 0.22, hole 0.102, L7 to BOTTOM, 1308 vias
v9: diameter 0.254, hole 0.102, TOP to L2, 1222 vias
v10: diameter 0.254, hole 0.102, L2 to L3SGND, 1098 vias
v11: diameter 0.432, hole 0.203, L3SGND to L6SGND, 654 vias
v12: diameter 0.356, hole 0.102, TOP to L2, 19 vias
v13: diameter 0.711, hole 0.406, TOP to BOTTOM, 92 vias

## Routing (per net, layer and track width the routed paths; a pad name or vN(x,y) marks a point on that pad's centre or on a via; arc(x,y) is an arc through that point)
3V3_EC_EN: length 117.4
  TOP w0.114: D5411.2 91.88,131.81 91.88,133.32 v1(91.02,134.18) 90.96,134.24 87.03,134.24 86.35,133.55 86.35,132.86 84.95,131.47 v2(84.49,131.47)
  L7 w0.061: v5(85.71,32.96) 84.19,34.48 84.19,51.73 84.91,52.45 84.91,54.73 84.91,55.02 88.4,58.51 88.4,62.16 88.15,62.41 88.15,62.56 88.02,62.69 88.02,63.38 87.84,63.55 87.84,65.3 86.7,66.44 86.7,68.98 87.9,70.18 87.9,70.98 86.32,72.56 86.32,74.21 86.5,74.4 86.5,75.99 86.2,76.29 86.2,93.49 85.74,93.96 85.74,98.72 86.5,99.49 86.5,109.12 86.5,109.12 86.5,116.2 84.58,118.12 84.58,122.34 84.36,122.56 84.36,131.34 v2(84.49,131.47)
  BOTTOM w0.114: U1703.A2 85.66,32.83 85.74,32.91 R1723.2
3V3_EC_VIN: length 121.9
  TOP w0.254: v1(87.77,127.74) 88.28,127.74 v2(88.38,127.83) 88.48,127.93 89.11,127.93 R1719.2
  TOP w0.305: R5412.2 103.26,133.01 103.11,133.17 102.35,133.17 v9(101.71,132.53)
  TOP w0.508: Q1703.S 89.36,126.63 89.32,126.59 88.77,126.59 88.38,126.98 v2(88.38,127.83) ; Q1703.S v9(91.2,126.66) ; Q1703.S 89.98,125.91 D1706.K
  L2 w0.254: v9(91.2,126.66) 96.43,131.9 101.08,131.9 v9(101.71,132.53)
  L2 w0.508: v10(84.44,72.97) 84.44,57.32 84.26,57.14 84.26,55.85 84.2,55.79 v2(84.2,52.52) ; v10(85.58,105.63) 85.58,114.83 88.78,118.02 88.78,127.43 v2(88.38,127.83)
  L3SGND w0.508: v10(85.58,105.63) 85.58,105.61 85.3,105.33 85.3,100.07 83.9,98.67 83.9,73.51 v10(84.44,72.97)
  BOTTOM w0.203: C1701.1 85.18,33.42 R1723.1 85.26,32.88 U1703.B2
  BOTTOM w0.508: v2(84.2,52.52) 84.2,34.93 85,34.13 C1701.1
3V3_EC_VIN_ON#: length 4.3
  TOP w0.114: Q1703.G 89.91,128.47 R1719.1 ; Q1703.G 89.98,129.72 U1706.6 ; Q1703.G 89.98,128.03 89.09,127.15 v1(89,127.15)
5V_COMP: length 1.7
  TOP w0.114: v1(93.76,140.76) 93.76,141.4 93.97,141.6 R5216.2 C5228.1
5V_EN: length 4.5
  TOP w0.114: R5217.2 89.29,143 v1(90.79,143) 91.05,143 R5211.2 92.8,144.75 U5202.7
5V_FB: length 3.7
  TOP w0.114: U5202.10 94.34,143.95 93.94,143.56 R5219.2 R5218.1 93.97,142.92 R5216.1 93.69,142.46 v1(93,141.78)
5V_LBI: length 3.7
  TOP w0.114: v1(91.76,141.83) 92.32,142.39 92.59,142.39 92.98,142.77 R5213.2 R5212.2 92.98,143.84 93.34,144.19 U5202.8
5V_LBO: length 1.4
  TOP w0.114: U5202.9 93.83,144.26 93.46,143.89 R5215.1
5V_LX: length 0.7
  TOP w0.114: 95.08,148.43 95.03,148.43 v1(94.6,148.86)
5V_SVOUT: length 3.3
  TOP w0.114: U5202.6 91.76,145.36 C5224.1 91.58,145.18 R5214.1 91.58,144.5 91.47,144.39 90.34,144.39 v1(90.23,144.5)
+AVDD_CAM_FRONT:
  vias: v1(93.1,188.13)
+AVDD_CAM_REAR: length 5
  BOTTOM w0.203: 72.27,190.67 72,190.95 CAMR1.19
  BOTTOM w0.508: C2504.1 73.7,189.25 72.27,190.67
+V1P2_FRONT:
  vias: v1(104.76,193.11)
+V1P2A: length 26.7
  TOP w0.305: 77.46,164.69 v10(76.95,164.69)
  TOP w0.508: v2(85.51,172.79) 85.51,173.24 84.95,173.81 84.82,173.81 ; v2(78.75,172.61) 78.75,169.24 77.96,168.45 77.96,165.2 77.46,164.69
  L3SGND w0.254: v10(76.95,164.69) 76.95,164.35 v11(76.96,164.34)
  L5 w0.203: v8(99.03,177.33) 99.02,177.34 99.02,177.43 98.87,177.57 98.87,177.85
  L5 w0.508: 98.87,177.85 98.87,180.41 v11(99.25,180.79)
  L6SGND w0.06: 99.63,177.61 99.63,177.13 v8(99.43,176.93)
  L6SGND w0.127: v11(99.25,180.79) 99.25,180.33 99.83,179.75 99.83,178.68 99.68,178.53 99.68,177.67 99.63,177.61
  L6SGND w0.254: v11(76.96,164.34) 76.68,164.61 v8(76.68,164.73)
  L7 w0.305: v5(83.43,166.14) 83.5,166.14 84.38,167.01 84.38,168.03 84.96,168.61 84.96,172.24 v2(85.51,172.79)
  vias: v1(81.24,171.85) v1(85.2,174.82) v1(96.48,179.7) v9(98.94,181.05) v9(98.94,180.54) v10(98.94,181.05) v10(98.94,180.54)
+V1P2SX: length 64.9
  TOP w0.254: v10(99.3,179.73) 99.3,179.98 99.55,180.23 99.55,181.77 100.61,182.82 103.09,182.82 105.09,184.83 v1(105.09,185.29) 105.09,185.98 106.03,186.91 106.92,186.91 108.11,188.11 108.11,190.7 107.38,191.43 R2511.1
  L2 w0.254: v10(99.3,179.73) 99.3,182.4 96.66,185.04 96.66,187.07 96.23,187.5 90.73,187.5 90.5,187.27 89.56,187.27 89.5,187.32 88.09,187.32 87.94,187.47 82.21,187.47 80.78,186.05 80.03,186.05 79.34,185.36 76.93,185.36 74.47,182.9 73.23,182.9 72.76,183.38 72.76,184.16 75.74,187.14 78.4,187.14 79.16,187.9 v2(79.16,187.98)
  L3SGND w0.254: v11(99.4,179.37) 99.3,179.47 v10(99.3,179.73)
  L5 w0.203: v11(99.4,179.37) 99.4,178.99 99.43,178.96 v8(99.43,177.33)
  BOTTOM w0.254: R2510.1 79.51,187.62 v2(79.16,187.98)
+V1P05A: length 57.5
  TOP w0.305: v10(70.37,161.23) 69.96,160.83 68.01,160.83 v9(67.6,161.23)
  TOP w0.381: v10(70.14,166.11) 69.79,166.47 v9(68.57,166.47)
  TOP w1.016: 81.55,153.36 87.39,159.2 94.33,159.2
  L2 w0.635: v13(88.96,171.27) 88.35,171.88 88.35,172.51 89.88,174.04 89.88,176.09 90.61,176.83 90.61,179.75 90.99,180.13 93.05,180.13 93.88,180.96 96.47,180.96 99.12,178.31 100.52,178.31 v10(100.95,177.87)
  L3SGND w0.254: v10(70.37,161.23) 70.37,161.06 v11(70.55,160.88) ; v11(70.14,166.47) v10(70.14,166.11)
  L3SGND w0.432: v11(101.33,177.87) v10(100.95,177.87)
  L5 w0.229: v8(97.43,174.13) 97.06,174.13 96.78,173.85
  L5 w0.254: v11(70.55,160.88) 70.55,161.2 v5(70.36,161.39) ; 96.78,173.85 96.17,173.85 93.46,171.15 89.08,171.15 v13(88.96,171.27)
  L6SGND w0.203: v8(101.03,177.33) 101.03,177.57 v11(101.33,177.87)
  L6SGND w0.254: v11(70.14,166.47) 70.36,166.25 v5(70.36,166.16)
  BOTTOM w0.508: v2(67.3,173.17) 67.75,173.63 70.24,173.63
  vias: v1(82.99,163.85) v1(83.07,160.14) v2(71.64,153.61) v2(71.64,153) v2(82.08,159.23) v4(73.66,165.2) v4(74.48,164.72) v4(75.03,164.73) v4(76.68,160.92) v5(73.66,165.2) v5(74.48,164.72) v5(75.03,164.73) v5(76.68,160.92) v7(76.68,161.87) v7(77.23,160.92) v8(76.68,161.87) v8(77.23,160.92) v9(76.11,161.89) v9(76.41,161.89) v9(76.72,161.89) v9(77.02,161.89) v9(78.85,153.11) v9(79.36,153.11) v9(79.74,153.11) v9(80.68,166.82) v10(74.05,164.67) v10(74.54,164.64) v10(75.02,164.67) v10(76.11,161.89) v10(76.41,161.89) v10(76.72,161.89) v10(77.02,161.89) v11(74.1,165.12) v11(74.69,165.15) v11(76.49,161.44) v11(77.05,161.44) v13(82.31,164.41) v13(88.96,170.43)
+V1P8_CODEC: length 29.8
  TOP w0.508: v2(95.24,195.4) v1(94.22,195.4)
  L2 w0.508: v2(95.24,195.4) 95.74,195.91 101.72,195.91 104.52,198.7 106.16,198.7 107.17,199.72 107.17,203.58 105.96,204.8 v2(104.63,204.8)
  L5 w0.508: v2(104.63,204.8) 104.1,204.26 102.88,204.26 102.75,204.39 100.54,204.39 100.47,204.31 v5(100.06,204.31)
  BOTTOM w0.305: R2020.2 v2(104.63,204.8) ; R2015.2 96.51,194.56 R2019.2 ; v2(95.24,195.4) R2018.2
  BOTTOM w0.508: v2(95.24,195.4) 95.24,195.22 95.9,194.56 R2015.2
+V1P8_REAR: length 5.6
  BOTTOM w0.203: CAMR1.18 72.62,191.35 72.66,191.31
  BOTTOM w0.508: 72.66,191.31 72.66,191.28 73.7,190.24 73.7,190.24 75.66,188.29
  vias: v1(77.33,185.08)
+V1P8A: length 486.4
  TOP w0.305: C1128.1 73.67,159.66 74.03,160.02 76,160.02 v10(76.06,159.96) ; v9(103.14,33.45) 103.14,34.19 104.12,35.17 ; v2(79.95,174.59) 79.93,174.57 79.87,174.57 78.16,172.86 78.16,169.3 77.41,168.55 v10(77.41,165.68) C1183.1 ; v2(112.41,144.62) 111.62,145.41 v1(111.62,145.51) R2104.1 ; R5401.1 v2(112.86,196.79)
  TOP w0.508: v2(95.19,60.9) 94.7,61.39 94.7,62.45 95.29,63.04 95.29,63.88 93.23,65.93 88.23,65.93 v9(88.17,65.98) v2(87.34,66.82) v2(87.34,70.4) ; v10(96.89,175.46) 98.27,175.46 98.38,175.58 99.67,175.58 100.21,176.11 102.36,176.11 103.41,175.05 v9(104.38,175.05) ; 104.12,35.17 104.92,35.17 105.47,35.73 105.47,36.52 106.77,37.82 106.77,41.07 104.61,43.23 v2(101.1,43.23) ; v2(66.79,141.8) 66.79,145.08 ; v9(104.13,196.92) 102.6,195.4 97.42,195.4 95.95,193.92 v2(95.29,193.92) 94.47,193.1 91.17,193.1 87.74,189.68 86.27,189.68 v2(85.79,189.2) ; R4201.1 41.92,176.75 41.92,177.52 v2(42.1,177.69) ; v2(84.52,132.68) 84.91,133.08 84.91,135.59 85.41,136.09 85.41,143.76 84.19,144.98
  TOP w1.016: 33.54,145.38 31.48,143.33 28.82,143.33 25.13,139.64 24.07,139.64 22.43,138.01 21.04,138.01 21.02,137.99 19.59,137.99 19.58,138.01 18.52,138.01 17.39,139.14 14.01,139.14 v2(13.47,139.67) 12.33,139.67 v2(10.43,141.57)
  L2 w0.254: v9(88.17,65.98) 88.17,58.29 85.14,55.25 85.14,52.23 84.49,51.58 84.49,37.56 84.67,37.38 84.67,36.6 84.7,36.57 84.7,36.01 85.08,35.63 v10(85.08,35.61) ; v9(103.14,33.45) 103.14,33.4 103.06,33.33 102.8,33.06 102.8,32.79 101.68,31.68 101.68,31.66 v9(101.33,31.31)
  L2 w0.508: v2(112.86,196.79) 112.74,196.79 111.85,197.68 108.95,197.68 107.81,196.54 104.76,196.54 104.38,196.92 v9(104.13,196.92) ; v2(42.1,177.69) 42.1,176.35 41.57,175.81 41.57,175.03 42.15,174.44 42.71,174.44 42.99,174.16 42.99,171.42 39.71,168.14 39.15,168.14 v2(39.15,168.09) ; v2(87.34,70.4) 87.41,70.4 93.03,76.02 v2(93.08,76.02) ; v10(96.89,175.46) 98.61,173.73 v10(100.01,173.73)
  L3SGND w0.254: v11(85.63,35.4) 85.43,35.61 v10(85.08,35.61) ; v11(77.05,165.68) v10(77.41,165.68) ; v10(76.06,159.96) 76.11,160.02 v11(76.67,160.02)
  L3SGND w0.305: v11(100.47,173.73) v10(100.01,173.73)
  L3SGND w0.432: v11(96.38,175.46) v10(96.89,175.46)
  L5 w0.508: v2(84.52,132.68) 84.52,132.64 85.32,131.84 85.32,130.98 84.58,130.24 84.58,121.55 v4(84.14,121.1) ; v4(79.62,184.35) 79.54,184.27 79.54,182.31 79.95,181.9 v2(79.95,174.59) ; v11(96.18,176.53) 96.38,176.33 v11(96.38,175.46)
  L6SGND w0.203: v11(96.38,175.46) 96.51,175.33 v8(97.83,175.33) ; 102.27,175.03 102.17,174.93 v8(101.43,174.93) ; v13(110.12,178.58) 110.04,178.51 107.43,178.51 106.44,177.52 103.47,177.52 102.68,176.73 102.05,176.73 101.45,176.13 v8(101.43,176.13) ; v8(97.43,176.53) v11(96.18,176.53)
  L6SGND w0.254: v11(76.67,160.02) 76.69,160.04 76.69,160.17 v5(76.96,160.44) ; v11(77.05,165.68) v5(76.68,165.68) ; v11(100.47,173.73) 100.47,173.8 100.3,173.98 v7(100.3,174.13) ; v5(85.74,35.83) 85.74,35.5 v11(85.63,35.4)
  L6SGND w0.381: v5(108.01,177.77) 107.57,177.33 107.57,175.99 106.67,175.08 102.33,175.08 102.27,175.03
  L7 w0.254: v8(99.83,174.13) v7(100.3,174.13) ; v5(99.71,102.36) 99.68,102.36 v5(97.04,99.72) ; v5(91.45,93.16) 94.7,93.16 v5(96.35,94.81)
  L7 w0.508: v5(85.71,93.16) 85.71,71.24 86.55,70.4 v2(87.34,70.4) ; v2(112.41,144.62) 111.16,145.87 v5(111.16,149.29) ; v2(85.79,189.2) 86.5,188.49 86.5,185.16 v5(86.37,185.03) ; v5(85.33,114.5) 85.33,116.78 84.43,117.68 84.14,117.98 v4(84.14,121.1) ; v4(79.62,184.35) 80.1,184.35 81.24,183.21 81.27,183.21 81.27,183.2 82.2,183.2 82.2,183.21 82.56,183.21 v5(82.76,183.41) 84.52,183.41 v5(84.64,183.54)
  L7 w0.635: v5(111.24,190.06) 112.63,188.67 112.63,180.51 110.93,178.81 v13(110.93,178.3)
  BOTTOM w0.152: v2(87.34,70.4) 86.98,70.76 86.98,70.94 86.96,70.96 U4301.3 ; U1707.3 U1707.6 85.79,35.78 v5(85.74,35.83) ; 87.95,67.66 U1702.3 U1702.6
  BOTTOM w0.254: v5(96.35,94.81) 96.35,98.72 97.04,99.41 v5(97.04,99.72) ; v5(99.71,102.36) 99.71,101.56 99.68,101.53 99.68,98.6 100.42,97.86 PR5106.2 ; v5(85.71,93.16) v5(91.45,93.16) ; CPU1.A15 77.48,171.74 77.76,171.46 CPU1.B14
  BOTTOM w0.305: v2(87.34,66.82) 87.34,67.33 C1709.1 87.66,67.66 87.95,67.66 ; v2(10.43,141.57) 10.37,141.52 R4018.2 ; BIOS1.8 C1803.1 40.09,166.97 39.53,167.53 R1805.1 ; 74.09,179.27 73.66,179.27 73.41,179.01 73.39,179.01 73.11,178.73 R751.1 R740.1 73.11,177.46 R514.2 73.52,177.06 R735.1 ; 83.68,150.16 R732.2 82.92,148.15 81.75,146.98 76.21,146.98 75.81,147.39 ; 83.68,150.16 R645.2 R647.2 ; 83.68,150.16 83.68,150.87 84.19,151.38 R704.2 ; R511.1 R509.1 69.99,150.11 69.07,150.11 68.41,150.77 67.91,150.77 66.81,149.68 ; R720.2 70.73,177.16 R707.2 ; R720.2 70.06,177.24 R731.2 ; R720.2 70.8,177.74 71.47,178.4 R753.1 71.61,178.66 R724.1 R705.1 R736.1 71.84,180.46 71.41,180.89 70.61,180.89 70.28,180.56 70.28,179.61 R733.2 ; v2(36.36,159.28) 36.36,158.9 37.04,158.21 37.5,158.21 37.91,158.62 R1803.1 38.16,158.59 38.75,158.59 39.56,159.41 R1804.1 ; DB2.6 66.49,141.51 v2(66.79,141.8) ; CPU1.A15 77.48,172.61 77.53,172.66 77.53,172.97 77.61,173.07 C1137.1 77.61,173.83 77.99,174.21 78.93,174.21 79.28,174.57 79.11,174.75 78.65,174.75 77.94,175.46 R734.1 ; R4106.1 80.5,183.87 80.96,183.41 v5(82.76,183.41) 82.74,183.43 R4101.1
  BOTTOM w0.356: R1805.1 39.18,167.99 39.15,168.02 v2(39.15,168.09) ; R4005.1 13.32,139.82 v2(13.47,139.67)
  BOTTOM w0.457: R411.1 76.39,179.22 76.79,179.62 79.43,179.62 79.69,179.36 79.69,178.56 79.31,178.18
  BOTTOM w0.508: R408.1 80.91,174.75 80.76,174.59 v2(79.95,174.59) 79.93,174.57 79.28,174.57 ; v5(85.71,93.16) 85.71,93.54 86.09,93.92 86.09,113.74 v5(85.33,114.5) ; R410.1 80.38,178.18 PR4909.1 ; v2(42.1,177.69) 41.66,177.25 BSKT1.8 ; v5(86.37,185.03) 86.37,183.99 85.91,183.54 v5(84.64,183.54) ; R3904.1 92.87,75.89 93,76.02 v2(93.08,76.02) ; v2(104,157.55) 103.62,157.93 98.35,157.93 95.79,160.48 R1602.1 ; v5(111.16,149.29) 111,149.29 106.92,153.38 v2(106.92,155.01) ; 90.87,55.19 98.4,55.19 ; 98.4,55.19 98.4,55.92 98.42,55.94 98.42,57.52 95.19,60.75 v2(95.19,60.9) ; 98.4,55.19 98.4,50.59 102.95,46.04 102.95,45.6 102.42,45.07 101.75,45.07 101.1,44.42 v2(101.1,43.23) ; v2(95.29,193.92) 95.52,193.7 R2015.1 ; 71.84,180.46 72.71,180.46 73.24,179.93 73.45,179.93 73.75,179.63 73.75,179.61 74.12,179.23 75.12,179.23 75.35,179.01 R411.1 76.31,178.94 R417.1
  BOTTOM w0.635: v2(112.86,196.79) 111.24,195.17 v5(111.24,190.06)
  vias: v2(74.1,150.64) v2(74.1,150.01) v2(74.08,149.37) v7(73.38,159.96) v7(73.93,159.96) v8(73.38,159.96) v8(73.66,159.49) v8(73.93,159.96) v9(36.36,145.54) v9(36.39,145.04) v9(72.96,159.1) v9(73.49,159.1) v9(74,159.1) v9(101.08,153.74) v9(101.59,153.74) v9(102.09,153.74) v10(72.96,159.1) v10(73.49,159.1) v10(74,159.1) v11(73.19,159.51) v11(73.72,159.48)
+V1P8A_DE303_VDDIO: length 21.3
  TOP w0.254: R4204.2 39.64,178.4 v9(39.1,178.4) 39.1,179.04 39.18,179.12 ECOMP3.1 ; ECOMP3.7 37.96,185.39 v9(37.76,185.59) 37.46,185.3 v1(37.46,185.11) ECOMP3.8
  L2 w0.254: v9(39.1,178.4) 41.34,178.4 41.94,179.01 41.94,184.68 41.03,185.59 v9(37.76,185.59)
+V1P8A_EMMC_VCCQ: length 6.5
  L7 w0.457: v5(93.88,156.99) 93.88,156.49 v5(94.37,155.99) 93.96,155.58 93.96,153.71 94.8,152.87 94.8,152.24 v5(95.13,151.91)
  BOTTOM w0.305: v5(95.13,151.91) 95.37,151.67 EMMC1.C6
  vias: v1(95.19,162.07)
+V1P8A_MEM: length 40.6
  TOP w0.508: v2(49.9,168.63) v1(50.48,168.63)
  L2 w0.508: v10(58.46,169.51) 55.98,169.51 55.94,169.55 55.28,169.55 54.38,168.65 49.92,168.65 v2(49.9,168.63) ; v2(49.52,159.46) 52.7,159.46 53.71,158.45 v10(58.58,158.45)
  L3SGND w0.508: v11(58.58,159) v10(58.58,158.45) ; v11(58.46,170.05) v10(58.46,169.51)
  L5 w0.254: v5(51.22,177.56) 51.22,178.4 51.72,178.91 52.68,178.91 52.74,178.96 55.77,178.96 55.82,178.91 ; v11(58.58,159) 57.98,158.4 v8(57.98,157.87)
  L5 w0.305: v5(58.23,170.55) 58.23,170.27 v11(58.46,170.05) ; v5(57.72,178.06) 56.88,178.91 55.82,178.91
  L5 w0.508: v5(51.22,177.56) 49.55,175.89 49.55,169.35
  L7 w0.508: v5(50.41,167.99) v5(49.9,167.99) v2(49.9,168.63)
  BOTTOM w0.305: v5(57.72,178.06) RAM1.T1
  vias: v3(50.97,150.88) v3(55.99,149.68) v3(55.99,149.3) v4(50.97,150.88) v4(55.99,149.68) v4(55.99,149.3) v5(50.97,150.88) v5(56.76,149.04) v5(56.88,148.66) v5(57.26,148.53)
+V1P8A_SENSOR: length 8.8
  TOP w0.254: R4201.2 40.35,176.73 R4209.2 39.97,176.5 38.84,176.5 38.79,176.45 R4207.1 ; R4201.2 40.32,177.44 R4204.1 ; R4201.2 41.01,176.7 C4206.1 40.88,175.99 40.6,175.71 40.6,174.59 40.48,174.48 GYRO1.1 ; R4201.2 41.03,177.97 v1(40.88,178.13)
+V1P8A_WIFI: length 15.4
  TOP w0.508: v2(98.41,30.93) 98.51,31.03 99.58,31.03 100.27,30.35 WC3705.1 101.31,30.35 WR3706.1 101.89,30.37 v1(102.22,30.04)
  L7 w0.254: v2(98.41,30.93) 98.79,31.31 98.79,40.46 99.17,40.84 v5(99.17,41.22)
  BOTTOM w0.305: WR3708.1 v5(99.17,41.22)
+V1P8DVDD_FRONT: length 11.9
  TOP w0.305: CAMF1.10 99.64,187.69 98.75,188.58 v10(98.75,189.17) 97.5,189.17 96.86,188.54 95.64,188.54 95.41,188.77 R2504.2
  L3SGND w0.508: v10(103.9,188.54) v11(103.9,189.17) ; v11(99.2,189.17) v10(98.75,189.17)
  L5 w0.508: v11(99.2,189.17) v11(103.9,189.17)
  vias: v1(105.56,187.33)
+V1P8SX: length 70.6
  L2 w0.508: v2(73.27,183.59) 73.27,183.95 75.82,186.51 78.81,186.51 82.14,189.83 88.02,189.83 88.56,189.3 92.82,189.3 93.18,189.66 94.32,189.66 94.45,189.53 94.58,189.53 94.61,189.5 97.61,189.5 99.68,187.43 99.68,185.62 100.37,184.93 103.85,184.93 v9(107.33,188.41) 107.33,186.74 110.68,183.38 110.68,181.89 110.58,181.79 110.58,181.76 109.78,180.97 108.56,180.97 104.76,177.17 v10(104.76,176.91)
  L3SGND w0.305: v11(104.62,176.59) 104.62,176.77 v10(104.76,176.91)
  L6SGND w0.203: v8(101.43,175.33) 101.53,175.43 101.69,175.43
  L6SGND w0.381: 101.69,175.43 102.17,175.92 103.44,175.92 103.59,176.07 103.85,176.07 104.37,176.59 v11(104.62,176.59)
  L7 w0.508: v2(73.27,183.59) 73.27,183.84 73.9,184.48 v2(78.19,184.48)
  BOTTOM w0.305: R2512.1 76.47,184.14 C2516.1
  BOTTOM w0.508: v2(78.19,184.48) 78.19,184.12 v1(77.66,183.59) 76.77,183.59 76.52,183.84 C2516.1
+V1P15: length 16.3
  TOP w0.305: v10(74.66,167.05) 74.38,166.77 71.54,166.77 71.39,166.92
  L3SGND w0.254: v11(74.69,166.52) 74.66,166.54 v10(74.66,167.05) ; v11(70.78,166.39) v10(70.78,166.92)
  L5 w0.203: v5(96.13,185.01) 97.78,183.36 97.78,180.92 v3(97.65,180.79)
  L5 w0.254: v11(70.78,166.39) 71.05,166.12 71.05,165.62 70.91,165.47 v5(70.91,165.2)
  L6SGND w0.203: v3(97.65,180.79) 98.16,180.79 98.63,180.32 v8(98.63,177.33)
  L6SGND w0.254: v5(71.18,166.63) 71.01,166.63 v11(70.78,166.39) ; v5(75.03,166.63) 74.8,166.63 v11(74.69,166.52) 74.69,166.23 v5(74.76,166.16)
  vias: v1(73.32,174.11) v2(71.69,154.86) v2(71.66,154.22) v2(95.52,186.58) v9(69.84,168.47) v9(69.84,167.97) v13(73.06,175.1) v13(95.13,185.95) v13(95.97,185.97)
+V2P8_CAM_VCM: length 8.6
  BOTTOM w0.203: 71.36,186.02 CAMR1.30
  BOTTOM w0.254: v1(66.92,183.06) 67.19,183.34 R2509.2
  BOTTOM w0.305: R2509.2 67.19,184.25 67.42,184.48
  BOTTOM w0.508: 71.36,186.02 70.8,185.47 C2508.1 70.75,183.79 70.19,183.79 C2509.1 69.86,183.56 68.95,184.48 67.42,184.48
+V2P8SX: length 69.4
  TOP w0.508: R2515.1 89.52,188.16 89.78,188.41 v9(90.03,188.41) ; v2(66.38,184.9) 66.66,185.19 v2(75.4,185.19)
  L2 w0.508: v10(103.11,173.07) 103.11,177.02 107.79,181.71 109.62,181.71 109.94,182.03 109.94,182.05 110.04,182.15 110.04,182.68 110.02,182.71 110.02,182.78 108.96,183.84 99.78,183.84 97.85,185.77 97.85,187.5 96.71,188.64 90.26,188.64 v9(90.03,188.41) 89.85,188.59 86.08,188.59 86.05,188.56 85.52,188.56 85.5,188.59 81.79,188.59 79.07,185.87 76.08,185.87 v2(75.4,185.19)
  L3SGND w0.508: v10(103.11,173.07) 102.93,173.25 v11(102.93,173.55)
  L6SGND w0.203: v8(101.43,173.73) 102.75,173.73 v11(102.93,173.55)
  BOTTOM w0.305: C2507.1 66.28,183.59 66.53,183.84 R2509.1
  BOTTOM w0.508: C2507.1 65.7,183.74 65.7,184.2 65.24,184.65 v1(65.24,184.9) v2(66.38,184.9)
+V2P85S_EMMC_VCC: length 8.7
  L7 w0.457: v5(97.37,154.49) 97.77,154.88
  L7 w0.508: 97.77,154.88 v5(100.19,154.88)
  BOTTOM w0.254: v1(104.25,156.84) 104.25,156.79 103.44,155.98 103.44,155.62
  BOTTOM w0.305: 95.37,152.9 95.29,152.99 EMMC1.F5 ; 95.37,152.9 95.82,153.35 95.82,153.44 96.88,154.49 ; 95.37,152.9 EMMC1.E6 ; 96.88,154.49 EMMC1.K9 ; 96.88,154.49 v5(97.37,154.49)
+V3P3_EC: length 165
  TOP w0.254: 100.04,33.47 99.94,33.57 R1780.1 ; 100.04,33.47 99.66,33.09 R1777.1 ; 100.04,33.47 100.17,33.47 100.32,33.62 R1747.1 R1745.2 ; 104.18,40.18 104.79,40.18 105.17,40.56 105.17,41.09 104.79,41.47 102.9,41.47 101.88,40.46 v9(101.76,40.46) 100.75,41.47 94.35,41.47 94.6,41.22 C1730.1 ; 104.18,40.18 R1786.1 ; 104.18,40.18 104.48,39.87 R1789.1 ; v2(87.16,39.42) 87.24,39.49 87.24,40.08 R1734.2 v9(86.45,40.33) ; v9(99.45,31.57) v9(99.45,32.08) R1776.1 R1777.1 ; R1724.2 v9(85.56,36.14) ; R1777.1 R1779.1 R1778.1 99.45,34.62 99.66,34.82 R1746.2 99.76,36.7 R1732.2 v9(100.32,37.16)
  TOP w0.305: R1761.1 94.45,27.48 94.47,27.5 ; 94.35,41.47 94.09,41.22 R1716.2 R1729.1 ; R1707.2 R1789.1 104.51,39.7 104.96,39.7 ; v2(88.73,52.8) 88.53,53 87.03,53 86.42,52.4 86.42,46.38 86.47,46.32 v9(86.47,45.97) 86.55,45.89 R1752.1 R1736.1 ; R1769.2 85.56,39.25 85.55,39.27 85.55,39.66 85.84,39.95 85.98,39.95 86.36,40.33 v9(86.45,40.33) ; v2(87.92,23.67) 87.92,23.44 88.76,22.6 88.76,20.39
  TOP w0.356: v2(92.04,34.63) 92.44,35.03 U1704.G8 92.71,35.03 92.72,35.05 93.08,35.05 93.09,35.03 U1704.H8 ; U1704.J1 94.04,28.88 v2(94.04,28.88) ; U1704.G6 92.84,33.04 92.85,33.04 v2(92.85,33.04) ; C1730.1 C1704.1 94.6,39.57 94.84,39.33 U1704.K13 ; U1704.H3 93.25,31.03 v2(93.65,31.43) 94.04,31.82 U1704.J4
  TOP w0.508: 94.83,24.81 93.79,23.77 93.79,19.45 92.65,18.32 89.97,18.32 89.93,18.36 88.76,18.36 ; 94.83,24.81 95.44,24.81 96.33,23.92 96.43,23.92 ; 94.83,24.81 94.47,25.17 94.47,28.22 94.04,28.66 v2(94.04,28.88) ; v9(85.15,30.93) 85.13,30.91 R1743.1 ; R2924.1 97.34,25.5 R1757.1 97.19,25.01 96.43,24.25 96.43,23.92 ; 96.43,23.92 96.43,23.74 97.65,22.52 v2(97.65,21.81)
  L2 w0.254: v9(101.76,40.46) 102.09,40.13 102.09,38.88 101.27,38.06 101.27,37.5 100.9,37.13 100.34,37.13 v9(100.32,37.16) ; v9(99.45,32.08) v9(99.45,31.57) 99.33,31.44 98.2,31.44 98.19,31.43 v2(93.65,31.43)
  L2 w0.305: v9(85.56,36.14) 85.81,36.39 v2(86.75,36.39) ; v9(86.45,40.33) 85.86,40.91 85.86,45.15 86.47,45.76 v9(86.47,45.97)
  L2 w0.508: v9(107.97,1.75) v10(107.97,4.73) ; v9(85.15,30.93) 85.15,31.54 85.76,32.15 85.76,33.77 86.75,34.77 v2(86.75,36.39)
  L3SGND w0.254: v10(91.98,27.53) 92.7,27.5 v11(92.95,27.76)
  L3SGND w0.508: v10(107.97,4.73) v11(107.97,5.1)
  L5 w0.508: v11(107.97,5.1) 107.97,8.9 113.57,14.5 113.57,19.98 111.9,21.66 110.63,21.66 110.54,21.75 110.01,21.75 v11(107.71,24.05)
  L6SGND w0.254: v5(92.95,28.29) v11(92.95,27.76)
  L6SGND w0.305: v11(107.71,24.05) 107.78,23.97 107.78,23.57 v4(107.76,23.54)
  L7 w0.305: v2(88.73,52.8) 88.73,53.06 89.11,53.45 89.11,53.87 89.62,54.38 89.62,54.87 90.16,55.41 90.16,59.96 89.22,60.9 89.22,62.28 88.81,62.68 88.81,62.83 88.68,62.96 88.68,63.22 88.68,63.65 88.5,63.83 88.5,65.14 89.16,65.8 89.47,66.11 v5(89.47,67.31)
  L7 w0.508: v4(107.76,23.54) 106.23,23.54 104.51,21.81 v2(97.65,21.81)
  BOTTOM w0.152: U1707.7 86.14,35.26 86.36,35.48 86.46,35.48 86.75,35.78 C1721.1 ; U1702.7 v5(89.47,67.31)
  BOTTOM w0.254: R1705.2 R1706.2 ; v2(87.92,23.67) 87.9,23.67 87.87,23.64 R1740.2 R1741.1
  BOTTOM w0.305: R423.1 89.65,54.1 R421.1 89.24,53.64 R422.1 89.27,53.21 88.86,52.8 v2(88.73,52.8) ; v2(86.75,36.39) C1721.1
  BOTTOM w0.508: 87.16,37.56 v2(87.16,39.42)
  vias: v1(88,33.35)
+V3P3_EC_L: length 3.5
  BOTTOM w0.254: R1742.1 85.08,29.1 R1721.2 ; Q1702.S 86.8,30.41 v1(86.8,31.06)
  BOTTOM w0.508: R1721.2 85.65,29.26 Q1702.S
+V3P3_EC_VBAT: length 31.1
  TOP w0.254: v1(92.22,26.06) 92.31,26.06 92.82,25.55 93.59,25.55 v9(93.97,25.93) ; v1(92.22,26.06) 92.54,26.38 R1785.1 92.54,27.45 v9(92.57,27.48) ; v1(92.22,26.06) 90.81,26.06 90.41,26.46 C1726.1 R1783.1 R1702.2 R1782.1 ; v2(91.24,32.23) 91.63,31.83 U1704.F4 ; v9(97.8,24.91) 98.08,24.91 98.41,24.58 R2925.2
  L2 w0.254: v9(92.57,27.48) 92.57,27.96 91.24,29.29 v2(91.24,32.23) ; v9(93.97,25.93) 95.24,24.66 97.55,24.66 v9(97.8,24.91)
  L5 w0.254: v2(84.49,30.55) 84.57,30.55 86.01,31.99 87.78,31.99 88.05,31.72 90.73,31.72 v2(91.24,32.23)
  BOTTOM w0.254: v2(91.24,32.23) 91.23,32.23 91.23,32.22 91.07,32.22 90.64,31.8 C1702.1 89.95,31.8 C1705.1 90.31,31.34 R1784.1 ; U1703.B1 85.26,30.15 R1721.1 84.92,30.12 v2(84.49,30.55)
+V3P3_G601A31: length 2.3
  TOP w0.254: U5401.6 101.93,131.89 102.14,132.1 102.14,132.37 102.46,132.68 v1(102.63,132.68) 102.7,132.61 R5412.1
+V3P3_MUX: length 6.2
  TOP w0.305: U3101.22 101.94,64.64 C3127.1 C3108.1 C3107.1 C3106.1 C3105.1 C3104.1 C3103.1 ; R3101.1 97.78,64.66 C3102.1 C3103.1 ; C3103.1 98.87,64.16 v1(98.61,63.9)
+V3P3_SAR: length 0.8
  BOTTOM w0.508: R4102.2 85.36,186.58 C4101.1
+V3P3_TPM: length 22.9
  L5 w0.508: v5(40.27,156.92) 41.21,156.92 41.74,156.38 v5(41.74,152.98) 40.78,152.01 v5(40.78,150.06) 40.17,149.45 v5(37.71,149.45)
  BOTTOM w0.305: R5725.2 R5726.1 41.29,146.92 40.97,147.24 39.38,147.24 v1(39.22,147.4) 38.14,148.48 38.14,149.18 37.87,149.45 v5(37.71,149.45) 37.72,149.46 U5702.22 ; U5702.14 41.73,152.99 v5(41.74,152.98) ; R5717.2 v5(40.78,150.06) ; U5702.8 40.22,156.86 v5(40.27,156.92) 40.27,157.32 R5707.2
  BOTTOM w0.508: R5707.2 40.04,158.41 R5706.2
+V3P3_TPM_VSB: length 6.7
  L7 w0.508: v5(39.18,157.55) 40.63,157.55 41.36,156.81 v5(41.95,156.81)
  BOTTOM w0.305: U5702.1 36.72,156.84 C5703.1 36.79,157.3 37.04,157.55 v1(38.06,157.55) v5(39.18,157.55)
+V3P3_TPS65982: length 69
  TOP w0.356: v2(105.5,19.93) 105.66,19.93 105.88,20.15 U2901.H1 ; C2913.1 104.68,24.51 106.03,23.15 U2901.B1
  TOP w0.381: C2913.1 103.97,24.53 102.65,24.53 101.85,23.73 101.85,21.5 100.95,20.59 v1(100.95,19.98) v2(100.95,18.99)
  TOP w0.508: v2(99.48,60.12) 99.15,60.45 98.28,60.45 97.73,61.01 R3101.2 R2922.1 ; R2925.1 99.48,25.47 R2924.2 99.76,25.5 100.27,24.99 101.74,24.99 101.84,25.09 v9(102.17,25.09) 102.43,25.09 102.99,24.53
  L2 w0.508: v2(107.91,43.84) 108.57,43.17 108.57,40.56 106.01,37.99 106.01,33.02 103.79,30.81 103.79,29.45 102.91,28.57 102.76,28.57 101.98,27.79 101.98,27.08 102.55,26.51 102.55,25.47 v9(102.17,25.09)
  L7 w0.508: v2(107.91,43.84) 106.62,45.13 106.62,50.69 99.48,57.83 v2(99.48,60.12)
  BOTTOM w0.508: v2(105.5,19.93) 101.89,19.93 v2(100.95,18.99)
+V3P3A: length 435.7
  TOP w0.305: v10(77.48,160.09) 76.82,160.09 76.41,159.68 76.35,159.68 76.2,159.53 75.37,159.53 v10(75.04,159.2) ; R1709.1 100.33,26.12 100.33,25.71 100.52,25.52 101.33,25.52 v9(101.79,25.98) ; 77.96,160.09 77.96,160.3 77.95,160.31 77.95,160.59 77.96,160.6 77.96,161.31 77.76,161.51 v10(77.56,161.51)
  TOP w0.508: WR3707.2 101.76,26 v9(101.79,25.98) ; v2(42.45,175.46) 42.61,175.31 42.61,174.62 R4202.1 ; v2(90.16,191.08) 91.55,192.47 94.73,192.47 95.25,192.98 98.81,192.98 99.92,194.1 102.45,194.1 v9(104.25,195.91) ; v2(89.78,168.09) 87.24,165.55 v1(84.97,165.55) 83.43,165.55 82.28,166.7 v2(82.28,168.22) ; v9(94.86,73.43) R4301.1 95.69,73.43 98.03,75.76 R3902.1 98.44,76.73 100.24,78.53 101.54,78.53 102.19,79.19 104.89,79.19 105.75,78.33 107.34,78.33 107.38,78.37 v13(108.24,78.37) ; R3019.1 96.86,66.34 v9(96.4,65.88) ; v2(77.16,155.29) 77.21,155.34 77.33,155.34 77.38,155.4 77.89,155.4 78.24,155.04 78.24,152.83 78.6,152.47 v9(81.27,152.47) 82.51,152.47 87.72,157.68 98.66,157.68 100.72,159.74 v13(100.72,160.09)
  L2 w0.508: v2(42.45,175.46) 43.06,175.46 43.81,174.71 43.81,171.08 43.8,171.07 43.8,170.38 41.77,168.35 41.77,161.57 41.23,161.03 41.23,158.32 v2(41.95,157.6) 41.87,157.52 41.87,147.17 44.12,144.91 67.13,144.91 69.18,146.96 69.18,149.48 71.4,151.71 80.5,151.71 v9(81.27,152.47) ; v2(109.41,182.42) 109.38,182.44 105.14,182.44 v10(104,181.3) 102.54,179.84 102.54,174.2 101.65,173.32 101.65,171.96 103.49,170.12 103.49,163.75 v13(103.72,163.52) ; v2(109.33,194.25) 107.68,195.91 v9(104.25,195.91) ; v9(96.94,64.61) 96.94,65.35 v9(96.4,65.88) 94.86,67.43 v9(94.86,73.43)
  L2 w0.762: v9(101.79,25.98) 101.59,26.18 101.59,26.39 101.21,26.77 101.21,28.11 101.84,28.74 101.84,29.44 103.03,30.64 103.03,31.12 104.28,32.37 104.28,32.45 104.72,32.89 105.07,33.24 105.07,38.13 107.81,40.87 v13(107.81,41.85)
  L3SGND w0.254: v10(77.48,160.09) v11(77.91,159.66) ; v11(77.91,161.54) 77.89,161.51 v10(77.56,161.51) ; v10(75.04,159.2) v11(74.54,159.2)
  L3SGND w0.305: v11(104,181.68) v10(104,181.3)
  L5 w0.203: v13(103.72,163.52) 103.72,163.55 104,163.82 104,164.85 103.49,165.36 103.49,169.17 104.03,169.71 104.03,170.65 103.55,171.14 v3(102.83,171.14)
  L6SGND w0.203: v8(100.63,173.33) 102.74,171.22 102.75,171.22 v3(102.83,171.14) ; v5(104.38,182.27) 104,181.88 v11(104,181.68) 104,181.13 102.14,179.28 102.14,177.64 101.43,176.93 v8(101.03,176.93)
  L6SGND w0.254: v11(74.54,159.2) 74.76,159.42 74.76,159.48 v5(74.76,159.49) ; v8(77.78,159.96) 77.78,159.89 77.91,159.76 v11(77.91,159.66) ; v5(77.78,161.87) 77.91,161.74 v11(77.91,161.54)
  L7 w0.508: v5(107.17,202.89) 107.3,202.76 107.3,199.97 108.06,199.21 108.06,195.52 v2(109.33,194.25) ; v2(89.78,168.09) 89.78,167.58 90.21,167.15 90.21,166.99 92.39,164.82 92.4,164.82 92.6,164.61 98.49,164.61 100.09,163.01 103.19,163.01 103.69,163.52 v13(103.72,163.52) ; v5(109.46,190.06) 109.69,189.83 109.69,182.67 109.43,182.42 v2(109.41,182.42)
  L7 w0.762: v13(107.81,41.85) 108.67,42.72 108.67,45 109.08,45.41 109.08,51.59 110.01,52.52 110.01,75.83 108.24,77.6 v13(108.24,78.37)
  L7 w1.016: 108.98,86.43 108.98,79.11 v13(108.24,78.37) ; 111.44,88.89 112.67,88.89 113.99,90.21 113.99,98.34 112.87,99.46 112.22,99.46 111.54,100.14 111.54,101.93 112.1,102.48 112.1,105.01 113.47,106.39 113.47,115.52 112.43,116.56 112.43,120.61 112.72,120.89 112.72,131.99 111.54,133.17 111.54,137.46 113.6,139.52 113.6,142.11 110.22,145.49 110.22,146.5 109.76,146.96 109.76,159.66 v5(109.59,159.84)
  BOTTOM w0.254: CPU1.BV18 76.63,156.09 76.91,155.8 CPU1.BW17 76.91,155.54 v2(77.16,155.29)
  BOTTOM w0.305: R2021.1 98.77,206.4 ; v2(77.16,155.29) 77.13,155.25 77.13,154.48 C1133.1 77.23,153.92 C1188.1
  BOTTOM w0.508: v2(109.33,194.25) 109.56,194.03 109.56,190.16 v5(109.46,190.06) ; R4102.1 86.09,188.61 88.56,191.08 v2(90.16,191.08) ; R5706.1 41.39,158.44 41.95,157.88 v2(41.95,157.6) ; 98.77,206.4 99.02,206.65 103.8,206.65 107.17,203.27 v5(107.17,202.89) ; 105.78,161.53 105.78,158.43 105.12,157.77 105.12,156.41 R1601.1
  BOTTOM w1.016: v5(109.59,159.84) 108.14,161.29 108.14,161.31 106.76,162.69
  vias: v5(101.43,172.93) v5(101.43,172.53) v5(104.02,167.58) v5(104.02,166.82) v5(104.28,167.2) v5(104.53,167.58) v5(104.53,166.82) v5(105.12,167.58) v5(105.12,166.82) v5(105.37,167.2) v5(105.62,167.58) v5(105.62,166.82) v5(108.98,87.62) v5(108.98,87.29)
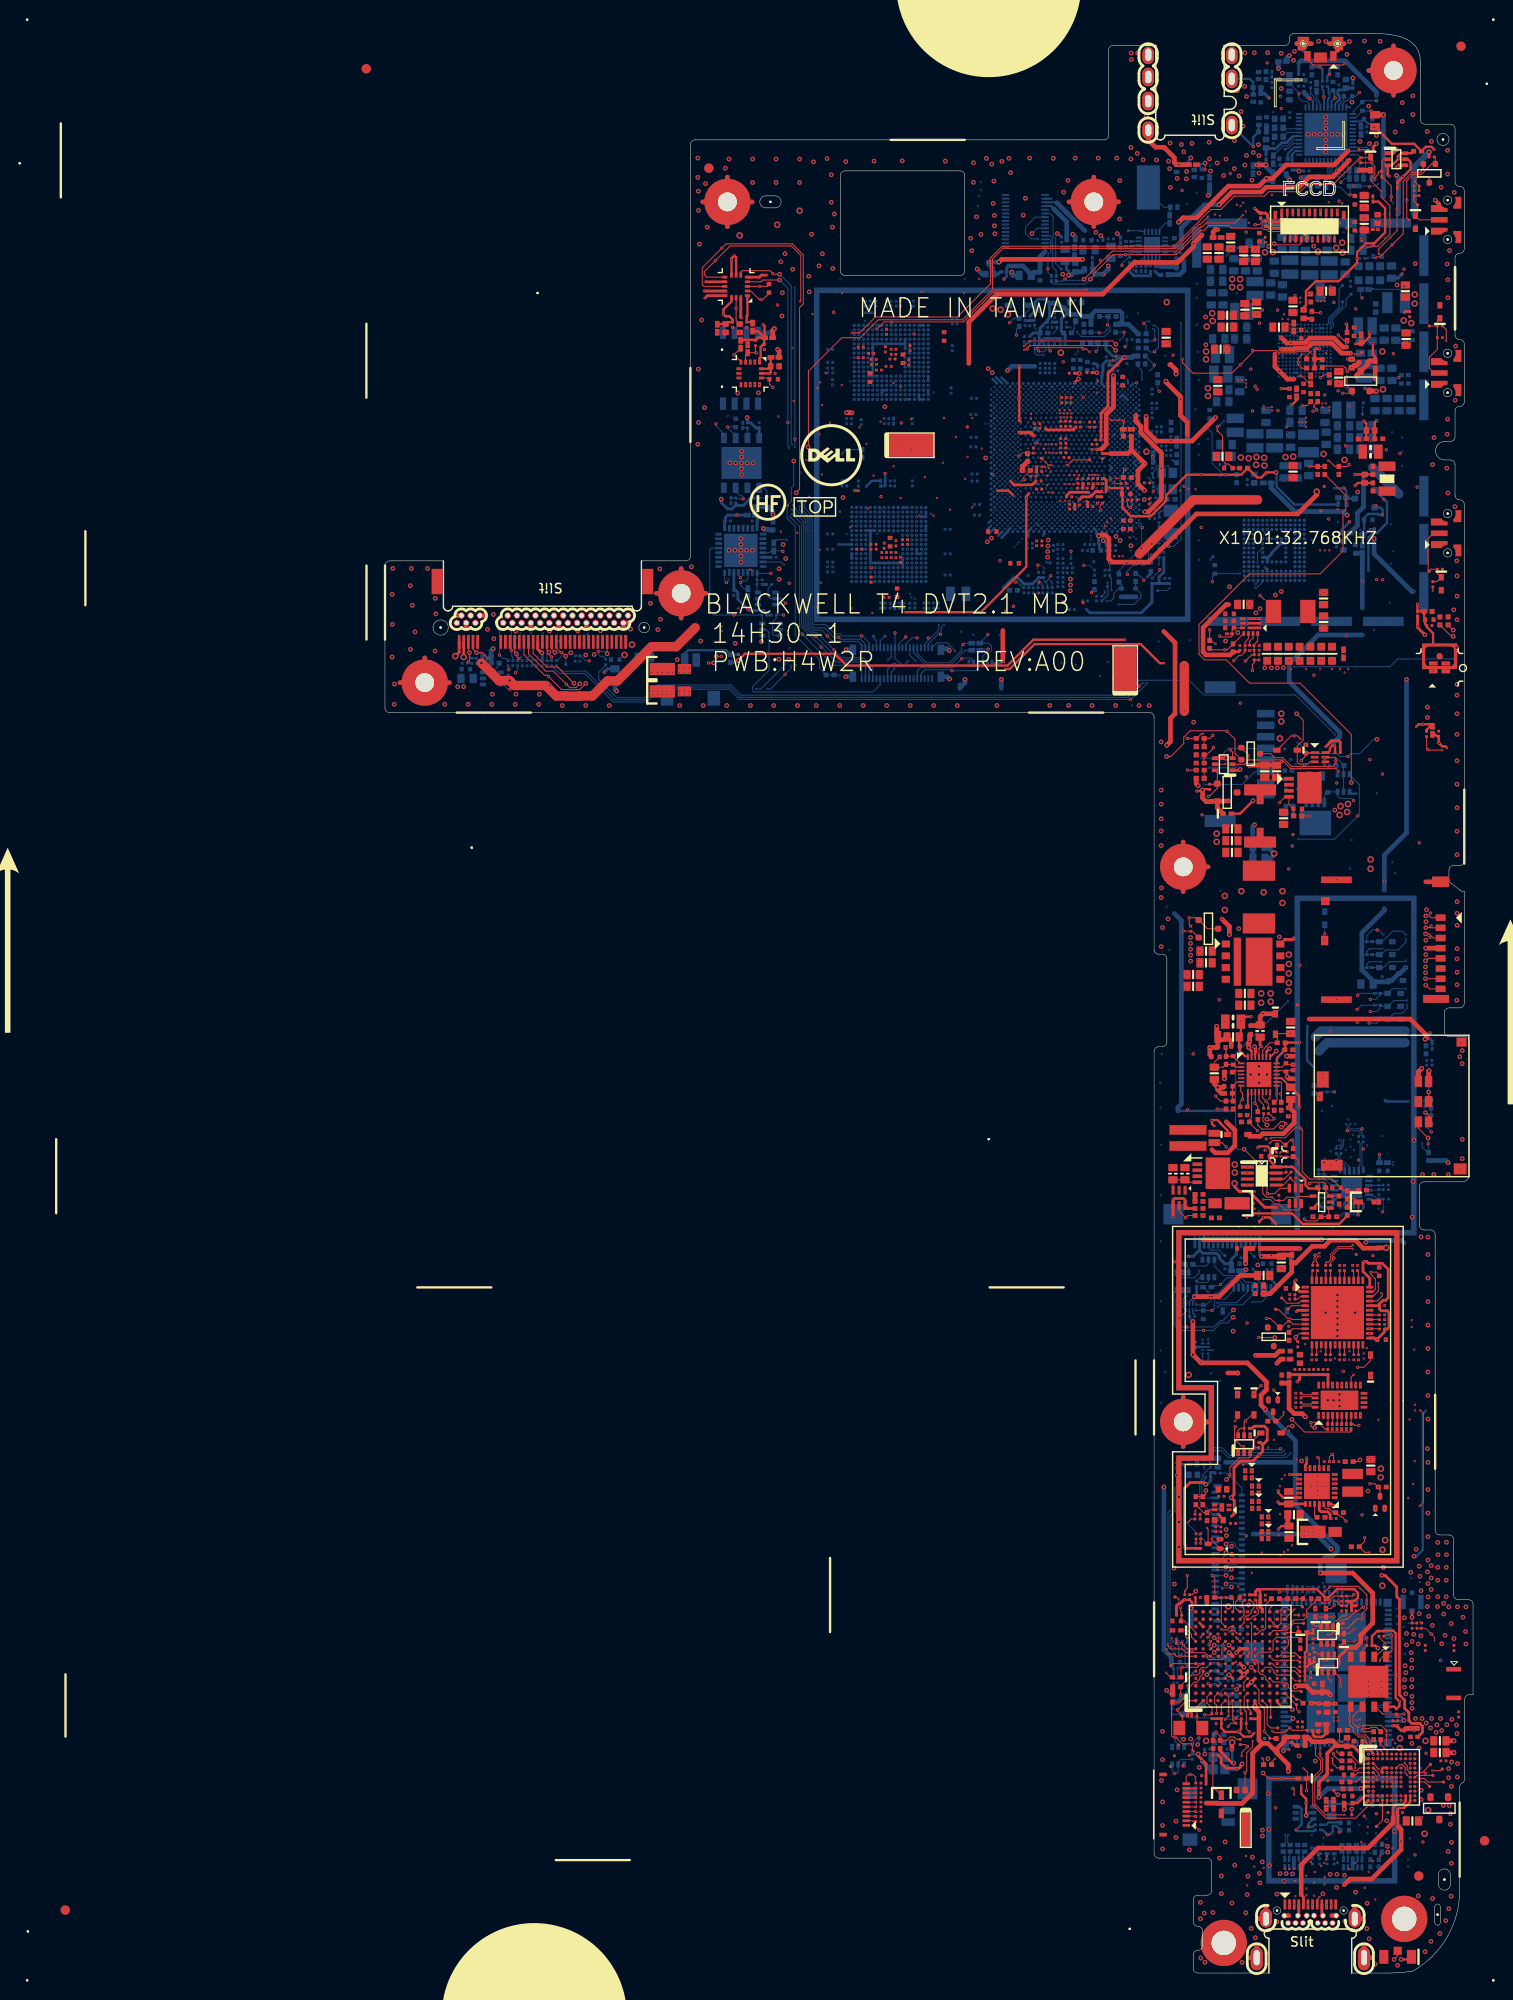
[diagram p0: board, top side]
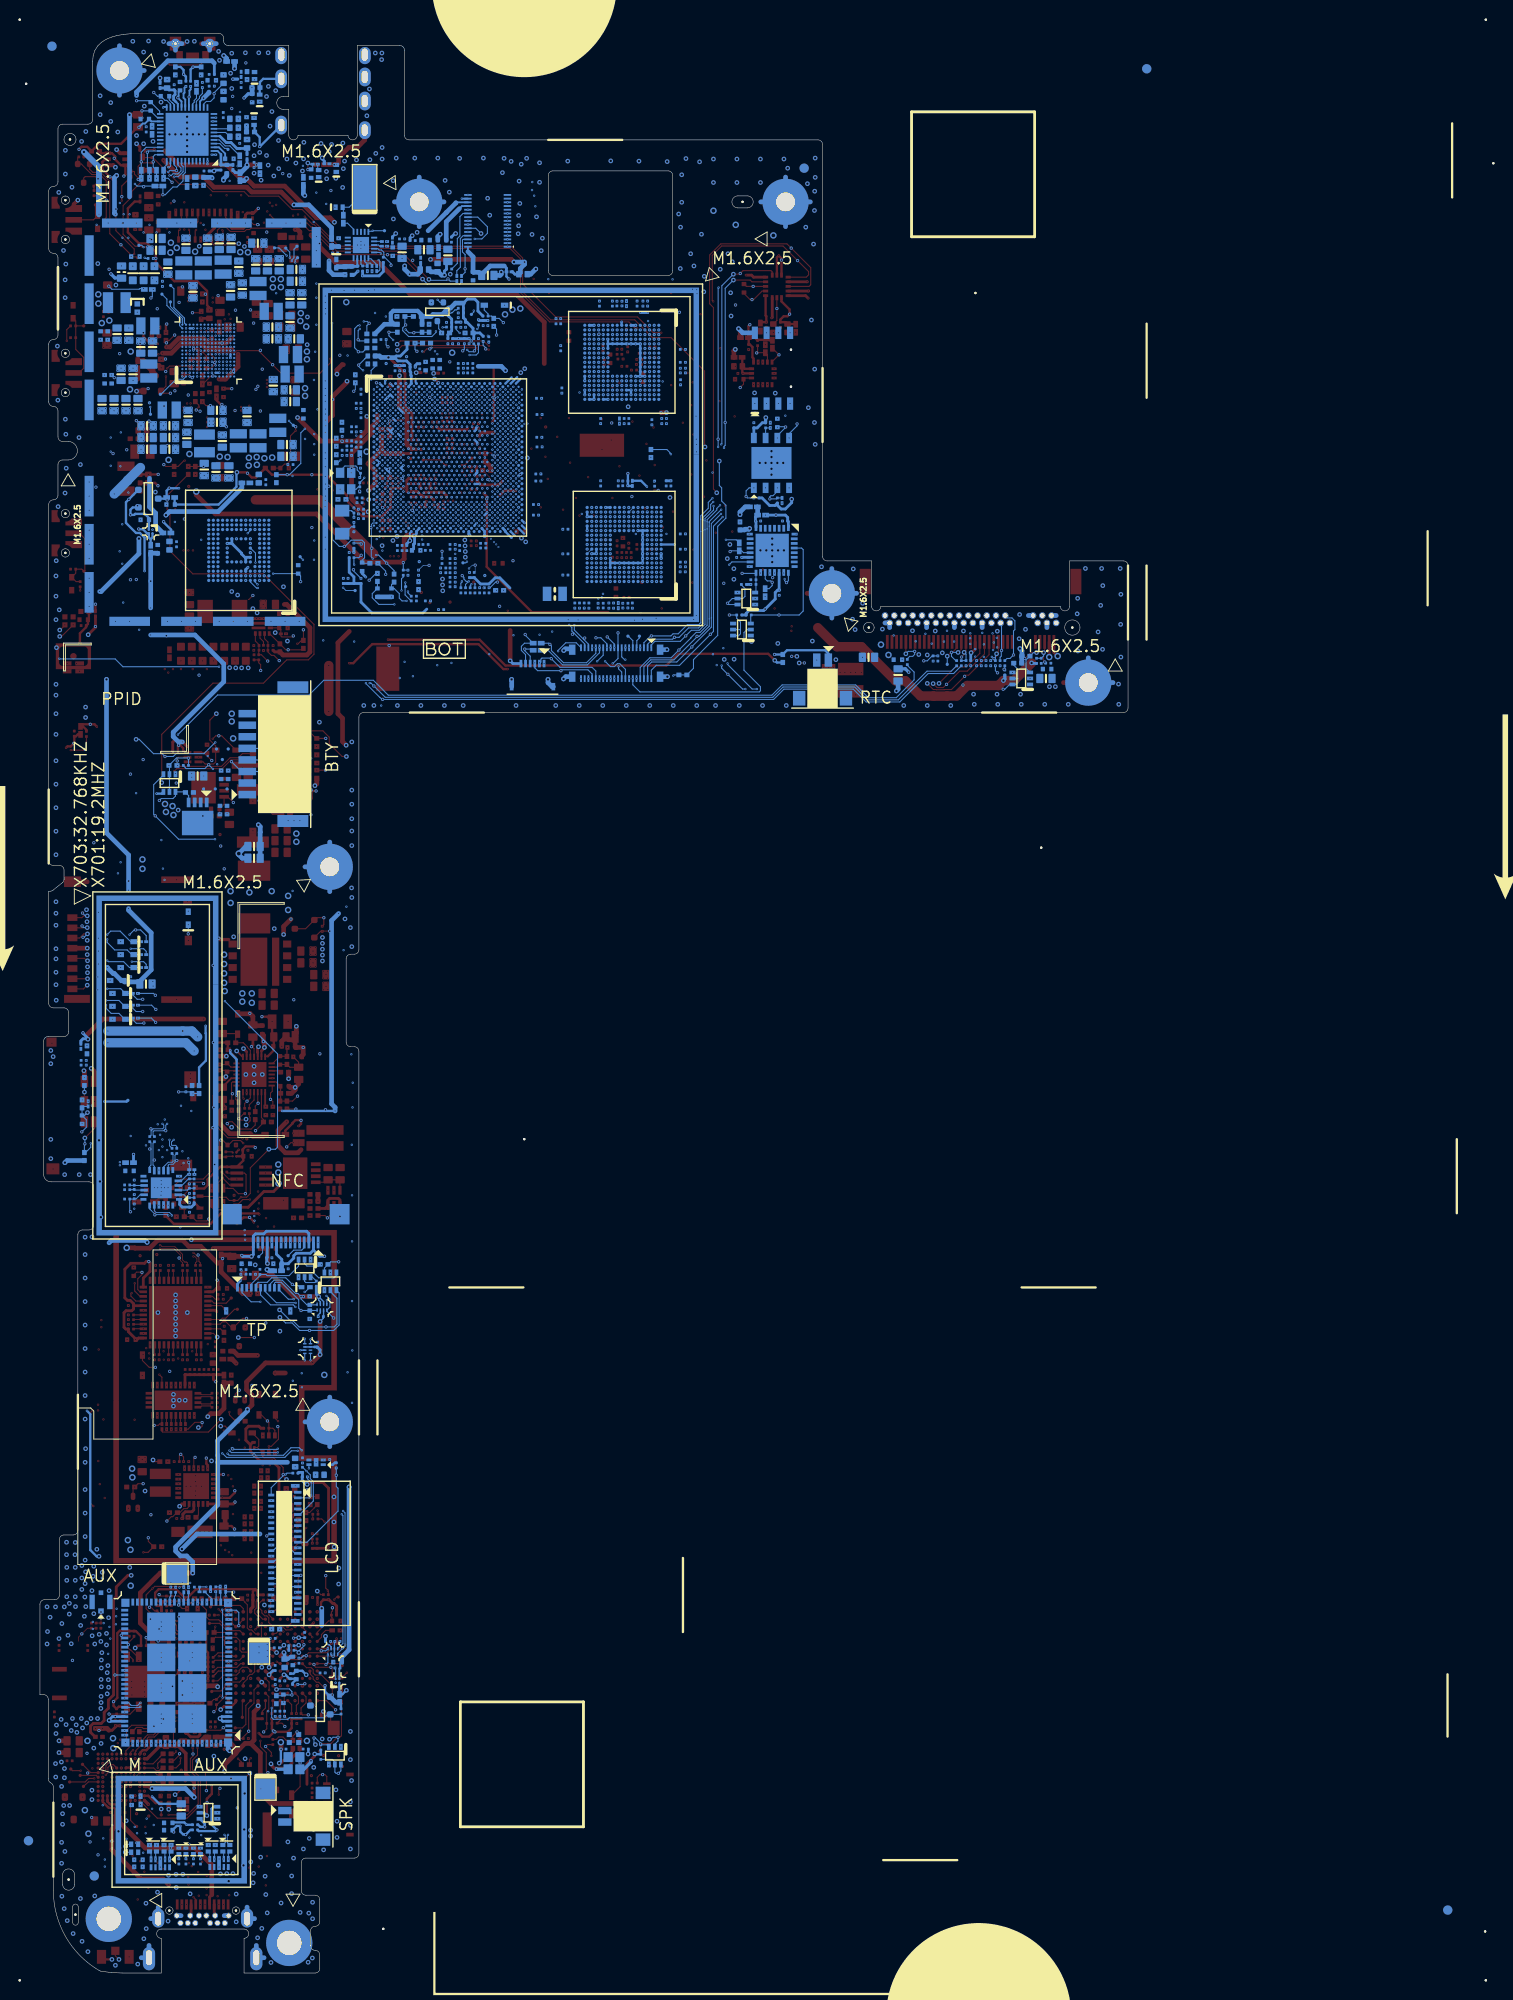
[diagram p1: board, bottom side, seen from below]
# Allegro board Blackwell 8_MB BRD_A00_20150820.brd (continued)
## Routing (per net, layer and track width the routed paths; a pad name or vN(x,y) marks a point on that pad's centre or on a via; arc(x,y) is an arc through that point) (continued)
+V3P3A_DE303_VDD: length 5.4
  TOP w0.254: R4203.2 35.95,178.2 C4201.1 37.02,178.4 C4202.1 37.58,178.68 37.22,179.04 36.82,179.04 v1(36.59,179.27) 36.59,179.78 37.46,180.65 ECOMP3.14
+V3P3A_SENSOR: length 127.9
  TOP w0.254: GYRO1.16 41.43,173.37 C4207.1 ; C4207.1 41.69,172.94 v9(41.62,172.87) GYRO1.15 ; C4207.1 41.69,174.57 R4202.2 ; v9(111.47,134.69) 111.72,134.95 v1(112.18,134.95) 113,134.95 R4205.2 112.97,134.72 112.6,134.35 R3807.1 ; v9(67.04,140.91) 67.52,140.91 70.22,143.61 81.7,143.61 83.76,141.55 v9(84.19,141.55)
  L2 w0.254: v9(35.93,177.31) 36.33,176.91 37.12,176.91 38.74,175.28 38.74,173.45 39.33,172.87 ; 39.33,172.87 v9(41.62,172.87) ; 39.33,172.87 35.83,169.36 35.83,144.9 36.12,144.61 42.41,144.61 43.49,143.53 65.95,143.53 67.3,142.18 67.3,141.42 67.04,141.17 v9(67.04,140.91) ; v9(84.19,141.55) 85.2,140.53 102.73,140.53 108.57,134.69 v9(111.47,134.69)
+V3P3SX: length 168.5
  TOP w0.508: R3020.1 96.68,67.2 96.22,66.75 v9(94.09,66.75) ; 91.1,64.84 92.16,64.84 92.17,64.83 v9(92.21,64.83) ; v2(107.17,170.94) 107.12,170.94 107.1,170.96 PQ4901.S
  TOP w1.016: v9(86.4,136.34) v9(86.4,141.3)
  L2 w0.508: v9(94.09,73.43) v9(94.09,66.75) 94.09,66.72 v9(92.21,64.83) ; 86.63,142.26 78.8,142.26 76.95,140.41 72.73,140.41 72.67,140.35 71.8,140.35 71.74,140.41 69.33,140.41 68.84,140.9 68.84,141.08 68.16,141.75 68.16,142.54 66.66,144.04 43.7,144.04 40.91,146.83 v2(40.91,156.1)
  L2 w1.016: v9(86.4,136.34) 86.4,123.03 84.44,121.08 84.44,118.56 84.87,118.13 84.87,115.36 84.64,115.13 v2(84.64,113.91)
  L6SGND w0.06: v8(101.03,173.73) 101.23,173.53 102.37,173.53 102.83,173.07
  L6SGND w0.203: v2(107.17,170.94) 107.12,170.94 106.79,171.27 106.44,171.27 104.63,173.07 102.83,173.07 ; v8(101.43,174.13) 103.83,174.13 104.43,173.54 104.98,173.54 106.75,171.78 107.22,171.78 v5(107.56,172.11)
  L7 w1.016: v13(86.88,64.64) 84.82,66.7 84.82,98.8 85.84,99.82 85.84,108.84 85.83,108.85 85.83,112.73 v2(84.64,113.91)
  BOTTOM w0.508: R5705.1 41.45,155.95 41.38,156.02 40.98,156.02 v2(40.91,156.1)
  vias: v1(105.93,171.22) v13(107.89,171.14)
+V3P3SX_SD: length 9.4
  TOP w0.254: PR4913.1 107.05,174.67 106.79,174.92 v1(106.79,176.09)
  TOP w0.508: PR4913.1 106.41,174.24 PC4917.1 106.23,173.86 PQ4901.D 105.02,172.64 v10(105.02,172.54)
  L3SGND w0.508: v11(104.51,172.54) v10(105.02,172.54)
  L6SGND w0.06: v8(101.03,173.33) 101.23,173.13 102.33,173.13 103.23,172.23 104.2,172.23 v11(104.51,172.54)
+V3P3SX_SD_CONN: length 80.4
  TOP w0.508: PR4913.2 107.05,172.28 v9(107.12,172.21) ; v2(112.51,110.75) MSD1.4
  L2 w0.508: v2(110.43,139.8) 109.25,140.97 109.25,171.76 108.73,172.28 107.37,172.28 107.3,172.21 v9(107.12,172.21)
  L5 w0.508: v5(110.35,108.66) 111.87,110.18 111.87,110.32 112.31,110.75 v2(112.51,110.75)
  L7 w0.508: v5(108.04,117.01) v5(108.04,115.03)
  BOTTOM w0.508: v2(110.43,139.8) 110.43,123.21 108.04,120.82 v1(108.04,118) v5(108.04,117.01) ; v5(110.35,108.66) 110.32,108.66 110.32,108.63 109.71,108.02 109.59,108.02 108.83,107.26 D2305.1 108.48,107.11 C2302.1 107.05,107.11 C2301.1 106.82,107.18 105.59,108.41 105.59,112.41 108.04,114.85 v5(108.04,115.03)
+V5P0_BOOST: length 220.6
  TOP w0.508: CLED1.A v2(107.94,200.81) ; R3905.1 v9(98.89,78.3)
  L2 w0.254: v9(110.83,20.15) 110.97,20.3 111.56,20.3 112.13,20.87 112.13,21.93 v9(111.95,22.12)
  L2 w0.508: v2(106.03,78.96) 106.01,78.96 105.57,79.4 102.78,79.4 101.94,78.56 100.65,78.56 100.39,78.3 v9(98.89,78.3)
  L5 w0.508: v4(104.89,185.87) 104.6,185.58 104.6,183.1 103.14,181.64 103.14,178.53 102.25,177.65 102.25,177.56 102,177.31 101.65,177.31 101.63,177.33 v8(101.43,177.33)
  L7 w0.508: v5(107.76,185.49) 107.25,186 105.02,186 v4(104.89,185.87)
  L7 w1.016: v5(108.8,184.48) 108.8,183.21 108.49,182.9 108.49,181.6 109.09,181.01 109.09,178.21 110.01,177.29 111.5,177.29 112.38,176.41 112.38,168.25 110.98,166.86 110.98,153.11 112.34,151.76 112.34,151.76 113.4,150.7 113.4,145.1 114.75,143.76 114.75,138.86 v2(112.69,136.8) v2(112.69,135.68) 112.69,134.02 113.86,132.85 113.86,120.42 113.58,120.14 113.58,117.04 114.62,116 114.62,105.91 113.24,104.54 113.24,101.35 113.32,101.28 113.32,100.88 115.13,99.07 115.13,89.74 113.15,87.75 112.07,87.75 110.15,85.83 v5(110.15,78.91) 111.37,77.69 111.37,48.84 110.22,47.7 110.22,45.03 109.69,44.5 109.69,42.21 108.32,40.84 108.32,33.98 105.65,31.31 105.65,27.88 106.54,27 108.83,27 109.46,26.36 111.21,26.36 v13(112.48,25.09)
  BOTTOM w0.508: v2(106.03,78.96) 106.23,79.17 109.89,79.17 v5(110.15,78.91) ; v2(107.94,200.81) 107.94,191.94
  vias: v1(103.14,191.49) v5(107.94,190.06) v5(108.06,187.52) v5(108.57,190.06) v5(108.7,187.52) v9(103.24,140.91) v9(103.75,140.53) v9(104.13,140.91)
+V5P0_BOOST_PMIC: length 0.8
  BOTTOM w0.356: v1(109.94,183.61) 109.51,183.18 109.36,183.18
  vias: v5(105.02,182.77) v5(105.45,183.15) v8(101.83,177.33) v8(102.23,177.33)
+V5P0_BOOST_R: length 4.8
  L2 w0.305: v9(94.5,142.95) 94.47,142.92 v9(93.46,142.92) 92.09,142.92 91.82,143.19 91.82,144.08 91.17,144.72 v9(91.02,144.72)
  vias: v1(103.95,144.52)
+VBATA_CHARGER:
  vias: v1(94.07,171.47) v1(97.47,167.1) v1(103.85,165.04) v4(92.06,172.08) v4(92.32,172.46) v4(92.57,172.08) v4(92.7,172.46) v4(92.9,178.25) v4(92.9,177.49) v4(92.9,176.98) v4(92.9,176.22) v4(93.41,178.25) v4(93.41,177.49) v4(93.41,176.98) v4(93.41,176.22) v4(95.24,169.08) v4(95.36,181.58) v4(95.36,181.07) v4(95.62,169.06) v4(96.13,181.58) v4(96.13,181.07) v4(98.89,167.71) v4(98.89,167.33) v4(99.3,167.71) v4(99.3,167.33) v5(92.06,172.08) v5(92.32,172.46) v5(92.57,172.08) v5(92.7,172.46) v5(92.9,178.25) v5(92.9,177.49) v5(92.9,176.98) v5(92.9,176.22) v5(93.41,178.25) v5(93.41,177.49) v5(93.41,176.98) v5(93.41,176.22) v5(95.24,169.08) v5(95.36,181.58) v5(95.36,181.07) v5(95.62,169.06) v5(96.13,181.58) v5(96.13,181.07) v5(98.89,167.71) v5(98.89,167.33) v5(99.3,167.71) v5(99.3,167.33) v9(92.19,172.16) v9(92.57,172.16) v9(93.08,172.16) v9(93.08,171.78) v9(93.08,171.39) v9(94.98,169.36) v9(94.98,168.98) v9(95.87,169.24) v9(95.87,168.85) v9(98.79,167.58) v9(99.17,167.58) v9(99.55,168.09) v9(99.55,167.58) v9(99.55,167.08) v10(92.19,172.16) v10(92.57,172.16) v10(92.95,177.49) v10(92.95,177.11) v10(93.08,172.16) v10(93.08,171.78) v10(93.08,171.39) v10(93.33,176.98) v10(93.59,177.36) v10(93.71,176.98) v10(94.98,169.36) v10(94.98,168.98) v10(95.11,180.28) v10(95.19,179.95) v10(95.46,180.13) v10(95.79,180) v10(95.87,169.24) v10(95.87,168.85) v10(98.79,167.58) v10(99.17,167.58) v10(99.55,168.09) v10(99.55,167.58) v10(99.55,167.08) v11(91.5,171.62) v11(92.06,171.62) v11(92.62,171.62) v11(92.95,177.87) v11(92.95,176.6) v11(93.53,177.85) v11(93.59,176.58) v11(95.44,169.44) v11(95.41,168.73) v11(95.64,180.56) v11(95.74,181.22) v11(99.12,168.07) v11(99.1,166.97)
+VBATA_CHARGER_R: length 6.1
  L3SGND w0.305: v11(98.94,171.04) 99.14,170.84 99.29,170.84 v10(99.3,170.84)
  L5 w0.203: v8(98.23,173.33) 98.08,173.48 98.08,174.19 98.79,174.9 98.79,175.1 v8(99.43,175.73)
  L5 w0.229: 98.23,173.05 v8(98.23,173.33)
  L5 w0.305: 98.23,173.05 98.21,173.03 98.21,172.05 98.51,171.75
  L5 w0.406: v11(98.94,171.04) 98.51,171.47 98.51,171.75
  vias: v1(102.58,180.54) v1(104.2,169.34) v1(109.59,172.41) v1(109.71,164.21) v4(100.7,181.27) v4(100.7,180.77) v4(101.23,169.13) v4(101.26,168.65) v4(101.43,181.27) v4(101.46,180.79) v4(101.97,169.13) v4(101.97,168.65) v5(100.7,181.27) v5(100.7,180.77) v5(101.23,169.13) v5(101.26,168.65) v5(101.43,181.27) v5(101.46,180.79) v5(101.97,169.13) v5(101.97,168.65) v9(100.82,180.67) v9(101.21,180.67) v9(101.33,169.62) v9(101.33,169.24) v9(101.59,181.05) v9(101.59,180.67) v9(101.71,169.62) v9(102.09,169.24) v9(102.09,168.85) v10(100.82,180.67) v10(101.21,180.67) v10(101.33,169.62) v10(101.33,169.24) v10(101.59,181.05) v10(101.59,180.67) v10(101.71,169.62) v10(102.09,169.24) v10(102.09,168.85) v11(101.08,181.6) v11(101.08,181.05) v11(101.61,168.85) v11(101.61,168.27) v13(107.81,175.23) v13(111.31,181.4) v13(111.3,180.41)
+VBATT_SW: length 104.6
  TOP w0.508: PR4605.1 97.9,93.75 v9(97.65,93.49) 97.83,93.49 98.28,93.04 98.28,91.89 97.1,90.7 94.89,90.7 94.6,90.42 93.49,90.42 PD4605.A
  L2 w0.508: v13(103.19,125.14) 100.57,122.52 100.57,103.68 100.75,103.49 100.75,102.34 100.57,102.16 100.57,97.99 97.65,95.07 v9(97.65,93.49) ; v10(105.88,134.01) 112.03,134.01 113.52,135.5 113.52,137.66 109.97,141.22 109.97,174.16 111.87,176.06 111.87,178.69 110.55,180 108.49,180 v9(105.52,177.03)
  vias: v1(102.88,128.6) v2(102.68,125.67) v9(31.86,141.04) v9(31.86,140.53) v9(31.86,138.5) v9(31.86,138.12) v9(32.37,141.04) v9(32.37,140.53) v9(32.37,138.5) v9(32.37,138.12) v9(32.88,141.04) v9(32.87,140.53) v9(32.87,138.5) v9(32.87,138.12) v10(31.86,141.04) v10(31.86,140.53) v10(31.86,138.5) v10(31.86,138.12) v10(32.37,141.04) v10(32.37,140.53) v10(32.37,138.5) v10(32.37,138.12) v10(32.88,141.04) v10(32.87,140.53) v10(32.87,138.5) v10(32.87,138.12) v13(103.29,126.11) v13(104,125.47) v13(104.1,126.33)
+VBATTERY: length 37.7
  TOP w0.254: D1706.A 92.44,125.29 v2(93.84,126.69)
  L7 w0.508: v5(105.65,147.52) v5(105.65,144.6) ; v5(102.22,133.04) 102.22,132.28 99.91,129.97 v5(99.91,129.36)
  BOTTOM w0.508: v5(105.65,144.6) 100.87,144.6 97.75,141.48 97.75,139.54 103.21,134.08 103.21,133.62 102.63,133.04 v5(102.22,133.04) ; v5(105.65,147.52) v1(105.65,150.41) PR5114.1 104.91,153.44 PC5103.1
+VCC0_CPU: length 0.5
  TOP w0.305: C1193.1 v2(76.95,172.94)
  vias: v1(75.47,170.28) v2(88.71,178.96) v4(71.73,166.63) v4(72.01,168.06) v4(72.01,167.11) v4(72.28,166.63) v4(72.55,168.07) v4(73.11,168.06) v4(73.11,167.11) v5(71.73,167.59) v5(71.73,166.63) v5(72.01,168.06) v5(72.01,167.11) v5(72.28,167.59) v5(72.28,166.63) v5(72.55,168.07) v5(72.56,167.11) v5(72.83,167.59) v5(73.11,168.06) v5(73.11,167.11) v7(72.83,166.63) v8(72.83,166.63) v9(72.93,168.91) v9(72.99,168.55) v9(73.01,168.12) v9(73.39,168.53) v9(73.39,168.12) v9(73.47,168.91) v9(73.65,169.69) v9(73.77,168.53) v9(73.77,168.12) v9(73.97,168.91) v9(74.15,169.69) v9(74.15,168.53) v9(74.15,168.12) v9(76.95,170.78) v9(77.08,172.03) v9(78.35,173.93) v9(78.73,174.32) v9(78.98,174.7) v9(79.74,172.49) v10(72.93,168.91) v10(72.99,168.55) v10(73.01,168.12) v10(73.39,168.53) v10(73.39,168.12) v10(73.47,168.91) v10(73.77,168.53) v10(73.77,168.12) v10(73.97,168.91) v10(74.15,168.53) v10(74.15,168.12) v11(71.72,167.63) v11(72.25,167.63) v11(72.58,167.1) v11(72.78,167.66) v11(73.32,167.63) v13(88.84,177.92) v13(89.42,179.37) v13(89.47,178.53)
+VCC1_CPU: length 1.1
  TOP w0.254: v1(74.54,171.85) 74.94,172.26 v2(74.97,172.26)
  TOP w0.305: C1115.1 75.04,172.89 v2(75.07,172.87)
  vias: v4(71.46,165.2) v4(71.46,164.25) v4(72.01,165.2) v4(72.01,164.25) v4(72.56,165.2) v4(72.56,164.25) v4(73.11,165.2) v4(73.11,164.25) v5(71.46,165.2) v5(71.46,164.25) v5(72.01,165.2) v5(72.01,164.25) v5(72.56,165.2) v5(72.56,164.25) v5(73.11,165.2) v5(73.11,164.25) v5(73.8,168.58) v5(74.21,168.06) v5(74.37,168.58) v5(74.65,169.43) v5(74.65,168.87) v5(74.76,168.06) v5(74.93,170.28) v5(74.93,169.72) v5(74.93,169.15) v5(74.93,168.58) v5(75.22,171.77) v5(75.22,171.13) v5(75.22,170.57) v5(75.22,170) v5(75.22,169.43) v5(75.22,168.87) v8(71.73,164.73) v8(71.73,163.77) v8(72.28,164.73) v8(72.28,163.77) v8(72.83,164.73) v8(72.83,163.77) v9(71.26,164.69) v9(71.36,165.18) v9(71.44,164.33) v9(71.74,165.2) v9(71.82,164.31) v9(72.15,165.2) v9(72.22,164.29) v9(72.55,165.18) v9(72.6,164.26) v9(73.04,165.32) v9(73.04,164.31) v10(71.26,164.69) v10(71.36,165.18) v10(71.44,164.33) v10(71.74,165.2) v10(71.82,164.31) v10(72.15,165.2) v10(72.22,164.29) v10(72.55,165.18) v10(72.6,164.26) v10(73.04,165.32) v10(73.04,164.31) v11(71.69,164.74) v11(71.74,163.82) v11(72.27,164.76) v11(72.33,163.9) v11(72.86,164.76) v11(72.86,163.82) v13(91.58,183.05) v13(91.58,182.19) v13(92.44,183.05) v13(92.44,182.16)
+VDD3V3_WIFI: length 5.8
  BOTTOM w0.305: WU3701.4 97.86,27.21 v2(98.16,27.5) 97.95,27.71 WU3701.5 ; WU3701.72 v1(109.47,27.71) 109.79,27.71 110.1,27.4 110.1,27.35 v2(110.15,27.3) 110.15,27.33 110.02,27.21 WU3701.73
  vias: v9(102.6,27.63) v9(102.6,27.25) v9(102.98,27.63) v9(102.98,27.25) v9(105.02,27.38) v9(105.4,27.38)
+VDDQ_PMIC: length 72.1
  TOP w0.305: v10(77.56,164.21) 78.47,164.21
  TOP w0.508: v2(84.43,172.02) 84.43,171.91 85.99,170.35 v1(85.99,170.05) 85.99,168.32 86.73,167.58 v9(86.73,166.19) ; 78.47,164.21 80.3,164.21 80.68,164.59 ; 80.68,164.59 v9(82.16,163.11) 81.39,162.35 81.39,160.93 v2(82.1,160.22) ; 80.68,164.59 R805.2
  L2 w0.508: v9(82.16,163.11) 82.51,163.11 84.57,165.17 85.71,165.17 v9(86.73,166.19)
  L3SGND w0.254: v11(70.42,162.28) 70.37,162.23 v10(70.37,161.74) ; v10(77.56,164.21) 77.74,164.21 v11(77.94,164.41)
  L3SGND w0.305: v10(99.05,176.65) 98.73,176.65 v11(98.59,176.51)
  L5 w0.203: v8(99.83,176.93) 99.94,177.05 99.95,177.05 100.44,177.54 100.44,177.64 100.44,178.27 101.92,179.75 101.92,181.53 103.91,183.52 103.91,185.71 103.69,185.92 v13(103.52,185.92)
  L5 w0.254: v5(51.73,177.06) 51.88,177.21 v5(51.88,178.53) ; v8(58.74,171.52) 57.8,171.52 56.7,172.62 55.41,172.62 55.36,172.56 v8(55.22,172.56)
  L5 w0.305: v5(50.48,152.39) 50.48,152.37 51.45,151.4 v8(51.47,151.4)
  L5 w0.508: v13(100.85,186.02) 100.65,185.82 100.65,182.93 99.05,181.34 98.99,181.34 98.3,180.65 98.3,180.62 97.65,179.96 97.65,177.74 98.16,177.24
  L6SGND w0.254: v11(77.94,164.41) 77.94,164.57 v5(77.78,164.73) ; v11(70.42,162.28) 70.63,162.07 v8(70.63,161.87) ; v11(70.54,165.68) 70.54,165.39 v8(70.36,165.2) 70.34,165.2 69.99,165.55 v11(69.99,165.66) ; v8(73.38,166.63) 73.38,166.53 73.57,166.34 v11(73.57,166.31) ; v8(73.38,163.77) 73.38,164.05 v11(73.62,164.29) 73.65,164.29 73.93,164 v8(73.93,163.77)
  L7 w0.127: v5(57.72,171.06) 57.83,171.06 58.07,170.81 58.94,170.81 58.94,170.8 v5(59.3,170.8)
  L7 w0.203: v5(53.72,172.56) 53.49,172.79 51.99,172.79 51.83,172.63 51.24,172.63 50.6,172 v5(50.31,172)
  L7 w0.254: v5(53.2,155.51) 52.87,155.51 52.71,155.67 50.77,155.67 50.54,155.44 49.98,155.44 v5(49.9,155.52) ; v5(59.04,157.68) 58.61,157.68 58.6,157.69 58.34,157.69 58.01,157.37 57.47,157.37 v5(57.47,157.37) ; v8(55.97,153.38) 55.66,153.06 55.66,151.69 v8(55.97,151.38)
  BOTTOM w0.076: RAM2.U7 RAM2.T8 ; RAM2.G17 RAM2.H16
  BOTTOM w0.254: v8(70.36,165.2) 70.36,165.41 CPU1.AC41 ; v8(70.63,161.87) 70.47,162.02 70.47,162.03 70.36,162.15 CPU1.AT42
  vias: v2(100.39,186.61) v6(99.03,176.93) v7(99.03,176.93) v8(99.03,176.93) v9(70.09,164.82) v9(70.24,165.3) v9(70.6,165.3) v9(73.39,163.77) v9(73.6,165.83) v10(70.24,165.3) v10(70.6,165.3) v10(73.52,165.38) v10(73.52,164.87) v10(73.6,165.83) v13(65.7,179.88) v13(66.55,179.75) v13(67.35,179.24) v13(84.51,180.56) v13(102.83,186.43) v13(103.47,186.99)
+VDDQ_VTT: length 56.9
  TOP w0.508: 63.11,173.93 63.11,178.4 66.13,181.43 77.58,181.43 81.01,184.86 85.69,184.86 87.4,186.57 v1(87.4,186.9) 88.3,187.8 v9(88.3,187.83)
  L2 w0.508: v10(102.37,182.06) 101.61,182.82 100.52,182.82 100.14,183.21 99.52,183.21 97.22,185.51 97.22,186.13 97.17,186.18 97.17,187.28 96.44,188.01 90.52,188.01 90.29,187.78 89.77,187.78 89.72,187.83 v9(88.3,187.83)
  L3SGND w0.508: v10(102.37,182.06) v11(102.37,181.45)
  L5 w0.203: 100.79,177.5 v8(100.63,177.33)
  L5 w0.381: v11(102.37,181.45) 102.37,179.62 100.79,178.04 100.79,177.5
  vias: v1(52.59,151.86) v1(57.19,177.11) v1(65.7,161.95) v1(66.48,152.62)
+VDDR3_M0_OCAVREF: length 13.3
  L7 w0.254: v8(50.72,173.56) 50.41,173.87 50.41,179.04 50.79,179.42 v5(51.9,179.42) ; v5(52.72,179.42) 52.96,179.42 54.06,180.51 54.06,180.51 v5(54.22,180.67) 54.23,180.65 54.71,180.65 v5(54.72,180.67) v5(54.72,180.16) 54.6,180.03 54.6,178.68 54.72,178.55 v8(54.72,178.44)
  BOTTOM w0.254: v8(54.72,178.44) 54.75,178.41 54.75,178.08 RAM1.J1 ; v5(52.72,179.42) v5(51.9,179.42)
+VDDR3_M0_ODQVREF: length 18.3
  L2 w0.254: v2(54.04,169.26) 51,172.3 51,172.92 50.83,173.09 50.83,175.84 51.65,176.66 56.67,176.66 58.26,175.07 v10(59.22,175.07)
  L3SGND w0.254: v11(59.22,174.64) v10(59.22,175.07)
  L6SGND w0.254: v11(59.22,174.64) 58.8,174.64 v5(58.72,174.56)
  vias: v1(55.82,167.51)
+VDDR3_M1_OCAVREF: length 18.5
  L7 w0.254: v5(54.6,148.03) 54.6,147.52 v5(54.57,147.49) ; v5(54.6,148.03) 53.17,148.03 52.84,147.7 50.65,147.7 47.32,151.03 47.32,154.05 47.64,154.38 v5(49.01,154.38) ; v5(54.6,148.03) 55.08,148.03 v5(55.1,148.05) 54.97,148.19 v8(54.97,150.38)
  BOTTOM w0.254: v5(49.01,154.38) RAM2.J1
+VDDR3_M1_OCAVREF_R: length 25.5
  TOP w0.254: v10(69.64,159.9) 69.33,159.58 v1(69.33,159.3) 69.33,151.96 64.42,147.06 v10(56.2,147.06)
  L3SGND w0.254: v11(55.73,147.06) v10(56.2,147.06) ; v11(69.09,159.9) v10(69.64,159.9)
  L6SGND w0.254: v8(68.71,160.1) 68.87,160.1 69.07,159.9 v11(69.09,159.9) ; v11(55.73,147.06) 55.52,147.06 55.12,147.46 v5(55.12,147.52)
+VDDR3_M1_ODQVREF: length 23.3
  L2 w0.254: v10(53.62,157.85) 53.54,157.85 50.33,154.63 50.33,154.11 52.6,151.84 54.34,151.84 54.47,151.71 v10(59.68,151.71)
  L3SGND w0.254: v11(53.99,157.85) v10(53.62,157.85) ; v11(59.68,152.45) v10(59.68,151.71)
  L5 w0.254: v11(53.99,157.85) 53.97,157.87 v5(53.97,158.38)
  L6SGND w0.254: v4(59.36,152.79) 59.42,152.73 59.42,152.7 v11(59.68,152.45)
  L7 w0.254: v8(58.47,153.88) 58.47,153.65 59.33,152.79 v4(59.36,152.79) ; v5(53.97,158.38) 54.03,158.44 54.03,158.56 54.14,158.66 54.14,160.29 54.09,160.34 v5(54.09,160.73)
  BOTTOM w0.254: R311.1 54.04,160.7 R1426.2 R1427.1 v1(54.06,162.05)
+VDDR3_M1_ODQVREF_R: length 21.1
  TOP w0.254: v9(66.18,160.19) 67.4,160.19 v10(67.91,159.69) ; v10(51.22,160.19) 50.81,160.19 v1(50.79,160.22)
  L2 w0.254: v10(51.22,160.19) v9(66.18,160.19)
  L3SGND w0.254: v11(68.31,159.69) v10(67.91,159.69) ; v10(51.22,160.19) 51.62,160.19 51.68,160.24 v11(51.68,160.24)
  L6SGND w0.254: v8(68.14,160.1) 68.31,159.93 v11(68.31,159.69) ; v11(51.68,160.24) 51.68,160.3 v5(52.01,160.62)
  BOTTOM w0.254: R311.2 52.64,161.26 v5(52.01,160.62)
+VIN_5V_19V: length 42.7
  TOP w0.305: v9(96.35,82.72) 96.33,82.75 95.11,82.75 93.41,84.45 92.37,84.45 91.83,84.98 v13(91.83,85.34) ; v2(92.65,22.6) 92.52,22.47 92.52,22.35 92.32,22.14 90.92,22.14 90.38,22.68 90.38,23.24 R1727.1
  L2 w0.305: v9(102.88,81.73) 102.17,81.73 101.74,82.16 96.79,82.16 96.35,82.6 v9(96.35,82.72)
  L2 w0.508: v13(91.86,87.37) 91.86,88.34 91.35,88.84 91.35,89.66 91.68,89.99 v9(91.68,93.37)
  L7 w0.305: v2(92.65,22.6) 92.52,22.47 92.52,21.97 93.59,20.9 95.97,20.9 97.45,22.37 104.28,22.37 105.98,24.07 109.47,24.07 v13(109.69,24.3)
  vias: v1(97.88,77.21) v5(94.45,81.81) v5(94.42,81.3) v5(94.47,82.34) v5(95.44,79.24) v5(95.49,80.28) v5(95.46,79.75) v9(108.95,25.22) v9(108.95,24.33) v9(109.21,24.84) v10(108.95,25.22) v10(108.95,24.33) v10(109.21,24.84) v13(91.86,86.51) v13(107.83,45.74) v13(108.11,46.78) v13(109.72,25.37)
DVDD_REAR: length 9
  L7 w0.508: v5(72.02,191.75) 74.59,189.17 76.95,189.17 78.19,187.93 78.19,187.46 v5(78.19,187.4)
  BOTTOM w0.203: CAMR1.17 v5(72.02,191.75)
GND: length 1106.2
  TOP w0.203: v2(96.35,99.64) 95.78,99.07 PU4601.22 ; v10(96.13,88.97) 96.38,88.71 U1705.A1
  TOP w0.254: C1710.2 86.75,28.04 v2(86.98,28.27) 87.21,28.04 C1711.2
  TOP w0.305: v10(41.29,183.48) 40.7,183.48 40.48,183.27 ECOMP3.5 ; C5404.1 106.82,197.33 v2(107.17,197.68) ; U1706.1 92.35,129.98 v2(92.44,130.07) ; 110.17,26.23 109.82,26.23 109.46,26.59 v9(109.46,26.72) v9(108.95,26.72) ; v10(76.54,160.95) 76.54,160.55 C1148.2 ; ECOMP3.10 34.69,182.77 v10(34.68,182.77) ; ECOMP3.13 34.85,181.27 v10(34.58,181) ; PC5003.2 110.3,179.55 v10(110.2,179.45) ; C1136.2 v10(74.56,158.21) ; v10(100.11,29.15) 100.9,29.15 v10(100.95,29.1) WC3702.2 v10(102.73,29.1) ; v2(91.76,22.68) 91.58,22.68 90.46,23.8 90.46,23.82 90.28,24 R1750.2 ; U4401.24 102.27,50.69 v2(102.53,50.44) ; C1135.2 v10(76.97,159.53) ; ECOMP3.16 38.46,178.92 v10(38.52,178.86) ; C1108.2 v10(75.45,160.98) ; C1199.2 v10(70.45,162.76) ; v10(34.53,181.78) 34.55,181.77 ECOMP3.12 ; PC4913.2 100.14,178.81 v10(100.19,178.86)
  TOP w0.356: U1704.G4 92.45,31.83 v2(92.85,32.23) ; v2(91.25,34.64) 91.48,34.4 91.48,34.4 91.64,34.24 U1704.F7 ; v10(105.91,18.22) 105.91,18.24 U2901.L1 ; v2(92.85,32.23) 93.24,32.62 U1704.H5 ; v2(92.85,32.23) U1704.G5
  TOP w0.406: U2501.4 109.72,195.36 109.7,195.38 v2(109.46,195.14) ; U2501.1 108.94,196.66 v2(109.33,197.05) ; v2(90.9,131.28) U1706.4 ; v2(113.52,191.59) 113.97,191.14 HKEY1.3
  TOP w0.508: 76.62,188.73 H9.1 ; H9.1 73.95,191.4 ; H9.1 76.62,194.07 ; H9.1 79.29,191.4 ; MSIM1.5 111.71,97.39 v2(112.08,97.76) ; 105.83,2.98 JUSBC1.16 106.66,1.65 ; 104.83,7.11 JUSBC1.14 105.64,5.88 ; H10.1 37.02,194.07 ; H10.1 37.02,188.73 ; H10.1 34.35,191.4 ; H10.1 39.69,191.4 ; H7.1 34.69,149.1 ; H7.1 32.02,151.77 ; H7.1 32.02,146.43 ; H7.1 29.35,149.1 ; 102.97,207.77 PKEY1.4 ; PKEY1.4 103.68,208.5 ; PKEY1.4 102.09,208.5 ; H8.1 4.3,142.12 ; H8.1 1.63,139.45 ; H8.1 6.97,139.45 ; 8.77,145.4 NGFF1.5 ; 25.77,145.4 NGFF1.73 26.27,145.9 ; JUSBC1.B12 97.69,6.2 ; v10(68.9,162.38) 68.9,162.78 R301.2 ; 21.77,145.4 NGFF1.57 ; R1754.2 v10(88.84,40) ; C2904.2 v2(115.56,25.09) ; 100.15,208.5 PKEY1.5 98.56,208.5 ; v10(111.62,26.44) v10(110.86,26.44) 110.37,26.44 110.17,26.23 ; 94.42,5.88 JUSBC1.13 95.23,7.11 ; v2(93.43,130.53) PC4610.2 PC4611.2 ; 94.23,2.98 JUSBC1.15 93.4,1.65 ; 86.29,56.89 H5.1 ; H5.1 88.96,59.56 ; H5.1 86.29,62.23 ; H1.1 109.02,208.27 ; H1.1 109.02,202.93 ; H1.1 106.35,205.6 ; D5404.2 105.33,194.82 v10(105.27,194.76) ; 15.77,145.4 NGFF1.33 ; C2903.2 v2(115.56,23.82) ; H6.1 88.96,119.54 ; H6.1 86.29,122.21 ; H6.1 86.29,116.87 ; PG4605.2 89.9,101.59 v2(89.9,102.31) ; v2(87.9,128.32) 87.69,128.52 D4502.2 ; NGFF1.11 10.77,146.7 ; MSD1.9 112.51,117.93 ; v2(103.69,17.7) 103.69,18.33 C2917.2 ; v10(104.51,173.48) 104.76,173.73 104.99,173.73 PC4917.2 ; 18.77,145.4 NGFF1.45 ; 7.77,146.7 NGFF1.3 ; 102.37,6.2 JUSBC1.B1
  L2 w0.076: NGFF1.39 17.27,145.47 ; NGFF1.27 14.27,145.43
  L2 w0.508: H6.1 86.29,120.92 ; H6.1 87.67,119.54 ; H6.1 86.29,118.16 ; H8.1 4.3,140.83 ; H8.1 4.3,138.07 ; H8.1 2.92,139.45 ; H8.1 5.68,139.45 ; 86.29,58.18 H5.1 86.29,60.94 ; NGFF1.73 25.64,146.03 25.64,146.33 NGFF1.71 ; NGFF1.73 26.27,145.9 ; NGFF1.73 25.77,145.4 ; 7.77,146.7 NGFF1.3 ; 104.83,7.11 JUSBC1.14 105.64,5.88 ; H10.1 38.4,191.4 ; H10.1 37.02,190.02 ; H10.1 35.64,191.4 ; H10.1 37.02,192.78 ; NGFF1.11 10.77,146.7 ; 93.4,1.65 JUSBC1.15 94.23,2.98 ; 106.66,1.65 JUSBC1.16 105.83,2.98 ; 18.77,145.4 NGFF1.45 ; 15.77,145.4 NGFF1.33 ; H1.1 109.02,206.98 ; H1.1 110.4,205.6 ; H1.1 107.64,205.6 ; H1.1 109.02,204.22 ; 102.37,6.2 JUSBC1.B1 ; 8.77,145.4 NGFF1.5 ; 21.77,145.4 NGFF1.57 ; 98.56,208.5 PKEY1.5 ; PKEY1.5 99.98,208.5 ; PKEY1.5 99.27,207.79 ; 76.62,190.02 H9.1 ; H9.1 75.24,191.4 ; H9.1 76.62,192.78 ; H9.1 78,191.4 ; 95.23,7.11 JUSBC1.13 94.42,5.88 ; H7.1 33.4,149.1 ; H7.1 32.02,150.48 ; H7.1 30.64,149.1 ; H7.1 32.02,147.72 ; 102.97,207.79 PKEY1.4 ; PKEY1.4 103.68,208.5 ; PKEY1.4 102.26,208.5 ; JUSBC1.B12 97.69,6.2
  L3SGND w0.061: 70.62,141.12 70.6,141.14 v11(70.19,141.14) ; v11(73.01,141.14) 73.44,141.14
  L3SGND w0.508: 7.77,146.7 NGFF1.3 ; 86.29,118.16 H6.1 ; H6.1 87.67,119.54 ; H6.1 86.29,120.92 ; H6.1 84.91,119.54 ; H10.1 38.4,191.4 ; H10.1 37.02,192.78 ; H10.1 35.64,191.4 ; H10.1 37.02,190.02 ; 75.24,191.4 H9.1 ; H9.1 76.62,192.78 ; H9.1 76.62,190.02 ; H9.1 78,191.4 ; H5.1 87.67,59.56 ; H5.1 86.29,58.18 ; H5.1 86.29,60.94 ; H5.1 84.91,59.56 ; H1.1 109.02,206.98 ; H1.1 109.02,204.22 ; H1.1 110.4,205.6 ; H1.1 107.64,205.6 ; PKEY1.5 99.98,208.5 ; PKEY1.5 98.56,208.5 ; PKEY1.5 99.27,207.79 ; 102.26,208.5 PKEY1.4 ; PKEY1.4 103.68,208.5 ; PKEY1.4 102.97,207.79 ; 95.23,7.11 JUSBC1.13 94.42,5.88 ; 104.83,7.11 JUSBC1.14 105.64,5.88 ; 4.3,138.07 H8.1 ; H8.1 4.3,140.83 ; H8.1 5.68,139.45 ; H8.1 2.92,139.45 ; 25.77,145.4 NGFF1.73 26.27,145.9 ; H7.1 33.4,149.1 ; H7.1 32.02,147.72 ; H7.1 30.64,149.1 ; H7.1 32.02,150.48 ; NGFF1.11 10.77,146.7 ; JUSBC1.B12 97.69,6.2 ; 94.23,2.98 JUSBC1.15 93.4,1.65 ; 102.37,6.2 JUSBC1.B1 ; 15.77,145.4 NGFF1.33 ; 8.77,145.4 NGFF1.5 ; 21.77,145.4 NGFF1.57 ; 18.77,145.4 NGFF1.45 ; 106.66,1.65 JUSBC1.16 105.83,2.98
  L4SGND w0.508: 35.64,191.4 H10.1 ; H10.1 37.02,192.78 ; H10.1 38.4,191.4 ; H10.1 37.02,190.02 ; H5.1 86.29,60.94 ; H5.1 86.29,58.18 ; H5.1 87.67,59.56 ; H5.1 84.91,59.56 ; 32.02,147.72 H7.1 ; H7.1 33.4,149.1 ; H7.1 32.02,150.48 ; H7.1 30.64,149.1 ; 2.92,139.45 H8.1 ; H8.1 5.68,139.45 ; H8.1 4.3,140.83 ; H8.1 4.3,138.07 ; 26.27,145.9 NGFF1.73 25.77,145.4 ; 18.77,145.4 NGFF1.45 ; 109.02,204.22 H1.1 ; H1.1 109.02,206.98 ; H1.1 110.4,205.6 ; H1.1 107.64,205.6 ; 99.27,207.79 PKEY1.5 ; PKEY1.5 99.98,208.5 ; PKEY1.5 98.56,208.5 ; NGFF1.11 10.77,146.7 ; H9.1 76.62,192.78 ; H9.1 78,191.4 ; H9.1 75.24,191.4 ; H9.1 76.62,190.02 ; 94.23,2.98 JUSBC1.15 93.4,1.65 ; 106.66,1.65 JUSBC1.16 105.83,2.98 ; 8.77,145.4 NGFF1.5 ; 102.97,207.79 PKEY1.4 ; PKEY1.4 103.68,208.5 ; PKEY1.4 102.26,208.5 ; 86.29,118.16 H6.1 ; H6.1 86.29,120.92 ; H6.1 84.91,119.54 ; H6.1 87.67,119.54 ; 15.77,145.4 NGFF1.33 ; 104.83,7.11 JUSBC1.14 105.64,5.88 ; 21.77,145.4 NGFF1.57 ; 94.42,5.88 JUSBC1.13 95.23,7.11 ; 7.77,146.7 NGFF1.3 ; JUSBC1.B12 97.69,6.2 ; 102.37,6.2 JUSBC1.B1
  L5 w0.06: 77.2,172.61 77.2,172.6 77,172.39 v8(77,172.29)
  L5 w0.076: NGFF1.27 14.27,145.43 ; 77.2,172.61 77.44,172.85 77.44,172.88 v3(78.29,173.74) ; NGFF1.39 17.27,145.47 ; v3(77.56,171.88) 78.04,171.88 v3(78.32,172.16)
  L5 w0.127: v3(43.01,168.35) v3(42.28,167.61) 42.28,159.53 v3(41.96,159.21) ; 38.49,158.87 39.34,159.72 40.15,159.72 41.03,160.6 41.03,168.42 v3(41.24,168.63) 41.24,169.54 ; v3(69.58,181.43) v3(68.64,182.37) 67.09,182.37 66.84,182.11 v3(62.62,182.11) v3(57.31,182.11) v3(51.55,182.11) 48.73,182.11 48.63,182.01 v3(48.58,182.01)
  L5 w0.203: v5(17,141.27) v5(17.51,141.27) v3(21.37,141.27) v3(26.83,141.27) ; v8(99.83,177.33) 99.83,178.07 101.54,179.78 101.54,181.96 v5(103.41,183.84)
  L5 w0.254: 75.31,164.65 v8(75.31,165.2) ; v3(48.58,182.01) v3(46.1,179.53) v3(44.08,177.52) v3(44.08,169.41) v3(43.01,168.35) ; 13.73,141.98 v3(13.73,141.35) v3(14.72,140.36) v3(21.2,140.36) v3(27.27,140.36) v3(31.9,144.99) v3(36.13,149.22) v3(36.13,154.66) v3(39.74,158.26) v3(41.01,158.26) v3(41.96,159.21)
  L5 w0.305: v11(67.68,177.11) 67.65,177.08 67.39,177.08 65.95,178.52 65.91,178.52 65.91,178.52 64.77,178.52 64.66,178.63 v11(64.25,178.63)
  L5 w0.508: H9.1 76.62,192.78 ; H9.1 76.62,190.02 ; H9.1 75.24,191.4 ; H9.1 78,191.4 ; H5.1 86.29,60.94 ; H5.1 84.91,59.56 ; H5.1 86.29,58.18 ; H5.1 87.67,59.56 ; 18.77,145.4 NGFF1.45 ; 104.83,7.11 JUSBC1.14 105.64,5.88 ; 94.42,5.88 JUSBC1.13 95.23,7.11 ; 15.77,145.4 NGFF1.33 ; 30.64,149.1 H7.1 ; H7.1 33.4,149.1 ; H7.1 32.02,147.72 ; H7.1 32.02,150.48 ; 98.56,208.5 PKEY1.5 ; PKEY1.5 99.98,208.5 ; PKEY1.5 99.27,207.79 ; H6.1 86.29,120.92 ; H6.1 84.91,119.54 ; H6.1 86.29,118.16 ; H6.1 87.67,119.54 ; 94.23,2.98 JUSBC1.15 93.4,1.65 ; 37.02,190.02 H10.1 ; H10.1 38.4,191.4 ; H10.1 35.64,191.4 ; H10.1 37.02,192.78 ; 48.88,168.85 v11(48.88,168.85) 48.88,168.85 ; 48.88,168.85 48.88,166.44 v11(48.88,166.44) v11(48.88,163.65) 48.88,162.24 48.88,162.24 48.88,161.19 48.88,161.19 v11(48.88,160.98) 48.17,160.27 48.17,159.04 v11(48.17,158.77) v11(48.17,156.18) 48.17,155.39 48.2,155.36 v11(48.2,153.16) 48.2,151.76 v11(48.88,151.07) v11(50.53,149.42) 51.17,148.79 v11(52.44,148.79) v11(54.6,148.79) 56.48,148.79 v11(56.76,148.51) 56.81,148.56 58.89,148.56 v11(58.99,148.46) 59.18,148.64 61.04,148.64 v11(61.25,148.43) 61.46,148.64 63.28,148.64 v11(63.44,148.48) 63.59,148.64 66.44,148.64 v11(67.14,149.35) 69,151.2 v11(69.07,151.2) v11(70.34,152.47) ; 48.88,168.85 48.88,172.82 v11(48.88,172.82) 48.88,174.74 48.92,174.78 48.92,176.39 v11(49.01,176.47) 49.01,176.98 51.47,179.45 52.08,179.45 v11(52.13,179.5) v11(54.49,179.5) 57.47,179.5 v11(57.54,179.42) 59.8,179.42 v11(59.83,179.45) 62.72,179.45 v11(62.77,179.5) 63.51,178.76 64.12,178.76 v11(64.25,178.63) ; H8.1 4.3,140.83 ; H8.1 5.68,139.45 ; H8.1 4.3,138.07 ; H8.1 2.92,139.45 ; 109.02,204.22 H1.1 ; H1.1 109.02,206.98 ; H1.1 107.64,205.6 ; H1.1 110.4,205.6 ; 106.66,1.65 JUSBC1.16 105.83,2.98 ; 21.77,145.4 NGFF1.57 ; 8.77,145.4 NGFF1.5 ; 7.77,146.7 NGFF1.3 ; 102.97,207.79 PKEY1.4 ; PKEY1.4 102.26,208.5 ; PKEY1.4 103.68,208.5 ; v11(67.68,177.11) 67.8,177.11 v11(68.57,176.35) v11(70.22,174.7) ; 26.27,145.9 NGFF1.73 25.77,145.4 ; NGFF1.11 10.77,146.7 ; JUSBC1.B1 103.04,5.72 ; 97.02,5.72 JUSBC1.B12
  L6SGND w0.089: 103.17,49.61 v4(102.73,49.61)
  L6SGND w0.254: 103.01,56.64 v4(103.01,56.13) ; v8(74.48,160.92) v8(73.93,160.92) ; 100.44,128.72 99.96,129.2 99.81,129.2
  L6SGND w0.508: H5.1 86.29,60.94 ; H5.1 84.91,59.56 ; H5.1 86.29,58.18 ; H5.1 87.67,59.56 ; 99.27,207.79 PKEY1.5 ; PKEY1.5 98.56,208.5 ; PKEY1.5 99.98,208.5 ; 94.42,5.88 JUSBC1.13 95.23,7.11 ; NGFF1.11 10.77,146.7 ; 76.62,190.02 H9.1 ; H9.1 76.62,192.78 ; H9.1 75.24,191.4 ; H9.1 78,191.4 ; 105.64,5.88 JUSBC1.14 104.83,7.11 ; 7.77,146.7 NGFF1.3 ; 4.3,138.07 H8.1 ; H8.1 2.92,139.45 ; H8.1 4.3,140.83 ; H8.1 5.68,139.45 ; 102.26,208.5 PKEY1.4 ; PKEY1.4 102.97,207.79 ; PKEY1.4 103.68,208.5 ; 102.37,6.2 JUSBC1.B1 ; H10.1 38.4,191.4 ; H10.1 35.64,191.4 ; H10.1 37.02,192.78 ; H10.1 37.02,190.02 ; H6.1 87.67,119.54 ; H6.1 86.29,118.16 ; H6.1 86.29,120.92 ; H6.1 84.91,119.54 ; H7.1 33.4,149.1 ; H7.1 32.02,150.48 ; H7.1 32.02,147.72 ; H7.1 30.64,149.1 ; 106.66,1.65 JUSBC1.16 105.83,2.98 ; H1.1 110.4,205.6 ; H1.1 107.64,205.6 ; H1.1 109.02,206.98 ; H1.1 109.02,204.22 ; 93.4,1.65 JUSBC1.15 94.23,2.98 ; 26.27,145.9 NGFF1.73 25.77,145.4 ; JUSBC1.B12 97.69,6.2 ; 21.77,145.4 NGFF1.57 ; 15.77,145.4 NGFF1.33 ; 8.77,145.4 NGFF1.5 ; 18.77,145.4 NGFF1.45
  L7 w0.076: NGFF1.27 14.27,145.42 ; NGFF1.39 17.27,145.24
  L7 w0.102: v4(22.26,139.49) 22.34,139.57 42.09,139.57 44.06,137.6 44.38,137.6 77.94,137.6 80.7,140.36 81.66,140.36 81.94,140.63 82.23,140.63 84.73,143.13 110.89,143.13 112.55,141.47 112.55,140.49 112.55,139.95 109.96,137.36 109.96,137.07 109.96,137.07 109.96,133.27 110.18,133.04 111.57,131.66 111.57,121.43 111.21,121.07 111.21,115.15 111.3,115.06 v5(111.3,114.63) v4(111.3,113.23) v5(111.3,111.83) v5(111.3,110.43) v5(111.3,109.04) 111.31,109.03 111.31,108.29 111.37,108.24 v5(111.37,107.64) 111.37,106.94 111.31,106.88 111.31,106.4 111.37,106.35 v5(111.37,106.24) 111.19,106.07 111.19,105.96 111.05,105.82 111.05,104.24 110.4,103.58 110.4,103.26 110.4,102.43 109.84,101.87 109.84,98.82 111.28,97.38 111.28,96.09 112.41,94.97 v4(112.41,94.79) 112.71,94.48 112.71,94.08 112.38,93.75 v5(112,93.75)
  L7 w0.127: 81.84,139.93 82.11,140.21 82.41,140.21 84.91,142.7 110.54,142.7 112.12,141.12 112.12,140.13 109.53,137.53 109.53,133.09 111.08,131.54 v4(111.08,129.53) 111.08,129.45 111.1,129.42 111.1,121.66 v4(111.08,121.64) 110.8,121.36 110.8,121.27 110.78,121.25 110.78,114.97 110.75,114.94 110.75,114.56 v4(110.74,114.55) 110.74,106.81 110.7,106.78 v4(110.7,106.6) 110.7,106.14 109.41,104.85 109.41,98.62 110.73,97.3 v4(110.73,97.12) 110.73,95.4 112,94.13 v5(112,93.75) ; 73.47,167.03 73.31,166.87 73.26,166.87 73.11,166.71 v8(73.11,166.16) ; 43.85,137.14 41.86,139.14 22.8,139.14 22.26,138.6 20.33,138.6 19.8,139.14 v4(19.8,139.52)
  L7 w0.203: v8(78.33,168.02) v8(78.61,167.74)
  L7 w0.22: v8(73.38,164.73) 73.66,164.45 v5(73.66,164.25) ; v8(73.11,163.3) v8(73.66,163.3) ; v5(71.73,165.68) v8(72.28,165.68) ; v8(74.21,162.34) v8(74.76,162.34)
  L7 w0.305: v4(64.5,180.08) 64.53,180.06 64.58,180.06 65.8,178.84 66.48,178.84 67.3,178.02 v4(67.4,178.02)
  L7 w0.508: 86.29,58.18 H5.1 ; H5.1 84.91,59.56 ; H5.1 86.29,60.94 ; H5.1 87.67,59.56 ; H1.1 109.02,206.98 ; H1.1 107.64,205.6 ; H1.1 109.02,204.22 ; H1.1 110.4,205.6 ; 15.77,145.4 NGFF1.33 ; 4.3,138.07 H8.1 ; H8.1 2.92,139.45 ; H8.1 4.3,140.83 ; H8.1 5.68,139.45 ; 76.62,190.02 H9.1 ; H9.1 75.24,191.4 ; H9.1 76.62,192.78 ; H9.1 78,191.4 ; v4(55.1,179.6) 55.59,180.08 v4(56.53,180.08) v4(58.96,180.08) 61.5,180.08 v4(61.53,180.06) 64.48,180.06 v4(64.5,180.08) ; PKEY1.5 99.98,208.5 ; PKEY1.5 98.56,208.5 ; PKEY1.5 99.27,207.79 ; 35.64,191.4 H10.1 ; H10.1 38.4,191.4 ; H10.1 37.02,190.02 ; H10.1 37.02,192.78 ; H7.1 32.02,150.48 ; H7.1 32.02,147.72 ; H7.1 30.64,149.1 ; H7.1 33.4,149.1 ; 102.26,208.5 PKEY1.4 ; PKEY1.4 103.68,208.5 ; PKEY1.4 102.97,207.79 ; 8.77,145.4 NGFF1.5 ; 105.83,2.98 JUSBC1.16 106.66,1.65 ; 94.42,5.88 JUSBC1.13 95.23,7.11 ; 25.77,145.4 NGFF1.73 26.27,145.9 ; 105.64,5.88 JUSBC1.14 104.83,7.11 ; v4(67.4,178.02) v4(68.31,177.11) v4(68.74,176.68) ; 21.77,145.4 NGFF1.57 ; NGFF1.11 10.77,146.7 ; 7.77,146.7 NGFF1.3 ; 18.77,145.4 NGFF1.45 ; JUSBC1.B12 97.6,6.57 ; JUSBC1.B1 103.04,5.72 ; 94.23,2.98 JUSBC1.15 93.4,1.65
  BOTTOM w0.152: U4301.2 87.31,71.35 87.54,71.11 v5(87.54,70.94)
  BOTTOM w0.203: v8(70.41,156.7) 70.65,156.45 CPU1.BU41 ; CPU1.A17 77,171.86 v8(77,172.29) ; CPU1.AP2 80.91,163.17 CPU1.AN3 81.16,163.49 CPU1.AM2 ; v8(79.74,171.77) CPU1.B8
  BOTTOM w0.229: v8(80.03,166.89) CPU1.W7
  BOTTOM w0.241: v8(79.74,162.08) CPU1.AT6 ; CPU1.AT6 v8(79.74,162.64) ; CPU1.AT6 v8(80.31,162.64) ; v8(78.33,162.36) CPU1.AR11 v8(78.33,162.93) ; CPU1.A5 80.31,172.07 v8(80.22,172.16) ; CPU1.V8 CPU1.W7 79.46,166.32 v8(79.46,166.32) ; CPU1.R9 v8(79.46,168.02) ; v8(78.9,169.15) CPU1.L11 v8(78.33,168.58)
  BOTTOM w0.25: CPU1.BR59 v5(65.24,156.7) ; CPU1.A55 66.04,172.46 ; CPU1.B4 v8(80.88,171.77) ; 65.19,156.08 CPU1.BU59 ; CPU1.A53 66.63,172.43 ; CPU1.A57 65.67,172.26 ; 66.63,155.11 66.66,155.11 67.29,155.75 CPU1.BW53 ; CPU1.BV58 65.29,155.55
  BOTTOM w0.254: v5(57.97,153.38) v5(57.47,153.38) RAM2.H15 ; CPU1.G5 v8(80.03,170.28) CPU1.E7 CPU1.F8 ; v2(92.85,32.23) 92.85,32.28 92.44,32.68 C1728.2 ; v2(88.63,23.67) 88.61,23.69 C2104.2 ; CPU1.BV52 67.39,155.95 67.39,155.9 67.29,155.81 CPU1.BW53 ; RAM1.M5 RAM1.L5 RAM1.K5 RAM1.J5 RAM1.H5 RAM1.G5 RAM1.F5 RAM1.E5 52.72,176.04 ; RAM1.M5 RAM1.M6 ; RAM1.M5 RAM1.M4 ; RAM2.T17 v5(58.47,157.38) RAM2.R16 ; v8(69.56,155.19) 69.56,155.42 69.56,155.42 CPU1.BW45 69.56,155.8 69.84,156.09 CPU1.BV44 ; RAM2.U12 v5(56.47,158.38) ; v8(70.36,167.11) 70.47,166.99 70.47,166.79 CPU1.W41 ; RAM1.U16 v5(58.72,171.06) ; v5(55.97,152.88) RAM2.E12 ; RAM2.E12 RAM2.D12 ; RAM2.E12 RAM2.E11 RAM2.E10 RAM2.E9 RAM2.E8 RAM2.E7 RAM2.E6 RAM2.E5 RAM2.F5 RAM2.G5 RAM2.H5 RAM2.J5 RAM2.K5 RAM2.L5 RAM2.M5 ; v5(58.47,155.88) RAM2.N17 ; v2(91.76,22.68) 91.58,22.86 C2103.2 ; RAM2.M5 RAM2.M4 ; RAM2.M5 RAM2.M6 ; v8(78.61,166.04) CPU1.Y10 ; RAM1.T17 v5(57.72,170.06) RAM1.R16 ; RAM1.U12 RAM1.U13 ; RAM1.M17 RAM1.N17 ; 52.72,176.04 v5(52.72,176.04) ; 52.72,176.04 RAM1.E6 RAM1.E7 RAM1.E8 RAM1.E9 RAM1.E10 RAM1.E11 RAM1.E12 ; TP1.1 96.27,74.48 v5(95.9,74.85) ; RAM1.D12 RAM1.E12 ; RAM1.E12 RAM1.F12 ; v5(105.02,127.45) 104.46,127.45 U4501.4 ; RAM1.G16 RAM1.G15 RAM1.H15 ; v8(97.03,174.53) PMIC1.P7 ; v8(69.27,157.83) CPU1.BN45 ; v2(88.84,32.23) 89.27,32.66 C1705.2 90.21,32.35 C1702.2 ; CPU1.BW55 66.73,155.77 66.28,155.32 ; v8(70.08,160.92) CPU1.BA41 ; PMIC1.C14 v8(101.03,177.73) ; PMIC1.K2 v8(98.23,172.93)
  BOTTOM w0.305: C2505.2 77.61,187.52 v2(77.38,187.75) ; v5(53.22,178.06) RAM1.G1 ; C2015.2 98.69,194.84 v2(98.79,194.74) C2021.2 ; C4103.2 83.65,183.51 v5(83.25,183.92) ; v5(82.4,150.86) 82.79,151.25 C711.2 ; C2503.2 73.67,184.81 R2518.1 73.9,183.92 v2(73.9,183.48) ; v5(69.2,178.58) R307.2 70.14,178.58 v5(70.22,178.66) ; v5(50.47,152.88) RAM2.G1 ; C2506.2 72.76,187.98 v2(72.68,187.98) ; C706.2 v5(83.68,153.51) ; R404.2 v5(78.73,173.71) v5(79.23,173.71) ; v5(77.05,173.55) 77.05,173.71 76.85,173.91 C1192.2 ; v5(71.23,176.63) R754.1 v5(72.38,176.63) R737.1 ; C1505.2 C1506.2 ; R758.1 v5(72.12,178.4) ; CPU1.BW39 71.26,155.5 71.16,155.4 v8(71.16,155.37)
  BOTTOM w0.381: v2(91.25,34.64) 91.17,34.56 C1719.2 90.79,33.93 90.54,34.18 C1713.2
  BOTTOM w0.508: v2(67.75,183.81) 67.75,183.59 67.88,183.46 C2509.2 ; H5.1 88.96,59.56 ; H5.1 86.29,56.89 ; H5.1 86.29,62.23 ; C710.2 v5(79.62,148.71) ; 105.64,5.88 JUSBC1.14 104.83,7.11 ; R2017.1 89.14,192.25 v2(88.99,192.1) ; 105.83,2.98 JUSBC1.16 106.66,1.65 ; v2(73.9,183.48) 74.2,183.48 74.56,183.84 C2515.2 75.35,183.84 C2516.2 ; H6.1 86.29,122.21 ; H6.1 88.96,119.54 ; H6.1 86.29,116.87 ; 76.62,188.73 H9.1 ; H9.1 79.29,191.4 ; H9.1 73.95,191.4 ; H9.1 76.62,194.07 ; v2(61,142.92) 60.82,143.1 60.17,143.1 XDP1.43 ; D2405.1 114.69,87.8 v2(114.92,87.57) ; 106.35,205.6 H1.1 ; H1.1 109.02,202.93 ; H1.1 109.02,208.27 ; R2205.1 97.45,206.9 v2(97.75,207.21) ; H10.1 39.69,191.4 ; H10.1 37.02,188.73 ; H10.1 37.02,194.07 ; H10.1 34.35,191.4 ; 102.26,208.5 PKEY1.4 ; PKEY1.4 103.68,208.5 ; PKEY1.4 102.97,207.79 ; 26.27,145.9 NGFF1.73 25.77,145.4 ; 93.4,1.65 JUSBC1.15 94.23,2.98 ; C2507.2 64.58,183.59 v2(64.02,184.14) ; 95.23,7.11 JUSBC1.13 94.42,5.88 ; NGFF1.11 10.77,146.7 ; 99.27,207.79 PKEY1.5 ; PKEY1.5 99.98,208.5 ; PKEY1.5 98.56,208.5 ; v2(25.03,138.55) 24.85,138.73 C4006.2 ; XDP1.42 v2(49.8,140.09) ; 1.63,139.45 H8.1 4.3,142.12 ; v2(62.7,139.8) 62.7,139.44 62.27,139.01 DB2.7 ; C2504.2 74.61,187.65 v2(74.36,187.9) ; 32.02,146.43 H7.1 ; H7.1 29.35,149.1 ; H7.1 32.02,151.77 ; WU3701.G1 97.28,24.19 v2(97.12,24.02) ; XDP1.41 v2(49.85,143.01) ; v2(61.02,139.85) 60.78,140.09 XDP1.44 ; PC4629.2 PC4630.2 93.81,123.29 93.8,123.3 93.8,123.88 v2(94.01,124.09) ; v2(66.64,139.8) 66.64,139.67 66.62,139.66 DB2.8 ; JUSBC1.B12 97.69,6.2 ; v2(97.78,193.75) 97.78,193.87 97.42,194.23 C2014.2 ; 8.77,145.4 NGFF1.5 ; 102.37,6.2 JUSBC1.B1 ; 15.77,145.4 NGFF1.33 ; 21.77,145.4 NGFF1.57 ; 7.77,146.7 NGFF1.3 ; 18.77,145.4 NGFF1.45
  vias: v1(13.4,140.89) v1(17.84,139.19) v1(38.42,150.79) v1(42.43,180.26) v1(43.7,150.19) v1(48.5,179.47) v1(53.63,159.56) v1(67.93,147.7) v1(79.87,143.45) v1(86.17,192.63) v1(88.33,125.17) v1(92.39,26.16) v1(92.47,137.23) v1(93.1,47.24) v1(93.2,70.25) v1(96.28,17.85) v1(96.79,56.64) v1(97.7,119.32) v1(98.89,108.88) v1(100.42,140.25) v1(103.16,15.23) v1(103.59,65.02) v1(107.2,150.59) v1(107.83,129.56) v1(108.24,164.61) v1(109,175) v1(109.59,196.11) v1(110.15,184.12) v1(111.24,26.21) v1(111.57,160.57) v2(0.85,151.79) v2(0.77,148.99) v2(0.8,145.74) v2(0.77,142.21) v2(1.03,139.29) v2(1,137.1) v2(2.73,149.93) v2(2.75,143.05) v2(2.86,151.79) v2(2.96,147.8) v2(3.24,144.93) v2(4.61,151.79) v2(5.45,148.56) v2(5.42,142.87) v2(5.5,146.88) v2(6.46,137.1) v2(9,137.1) v2(11.09,145.21) v2(11.54,137.1) v2(11.62,138.2) v2(11.72,146.81) v2(11.77,144.19) v2(14.13,145) v2(14.08,137.1) v2(14.16,138.2) v2(16.62,137.1) v2(16.7,138.2) v2(17.79,145.03) v2(19.16,136.98) v2(20.08,142.67) v2(20.84,145.03) v2(21.7,142.44) v2(21.7,136.98) v2(22.62,142.49) v2(23.3,145.05) v2(24.24,136.98) v2(26.55,145.23) v2(28.69,148.03) v2(29.5,145.18) v2(29.7,151.73) v2(29.78,146.3) v2(31.58,141.93) v2(31.86,136.98) v2(33.13,151.96) v2(33.82,196.13) v2(33.82,194.05) v2(33.82,165.2) v2(33.87,192.55) v2(33.9,190.47) v2(33.87,173.32) v2(33.9,167.56) v2(34,186.84) v2(34.12,143.94) v2(34.23,178.63) v2(34.4,136.98) v2(34.56,169.16) v2(34.66,193.37) v2(34.83,188.67) v2(36.79,195.04) v2(36.94,136.98) v2(37.2,196.03) v2(37.2,153.74) v2(37.27,163.19) v2(37.83,153.74) v2(37.91,163.19) v2(37.86,143.68) v2(38.14,170.73) v2(38.54,164.46) v2(38.54,163.82) v2(38.54,163.19) v2(38.54,162.55) v2(38.54,161.92) v2(38.47,155.01) v2(38.47,154.38) v2(38.47,153.74) v2(38.47,153.11) v2(38.47,152.47) v2(39.1,153.74) v2(39.18,163.19) v2(39.51,136.98) v2(39.74,196.03) v2(39.74,193.49) v2(39.74,153.74) v2(39.81,163.19) v2(40.37,170.76) v2(40.7,143.89) v2(42.02,136.98) v2(42.28,196.03) v2(42.28,193.49) v2(42.61,151.76) v2(42.61,150.62) v2(42.58,141.98) v2(42.79,184.93) v2(42.91,179.06) v2(42.96,181.58) v2(43.04,154.38) v2(43.24,185.8) v2(43.32,152.85) v2(43.65,141.96) v2(44.08,184.12) v2(44.59,136.98) v2(44.82,196.03) v2(44.82,193.49) v2(45.81,183.36) v2(45.86,181.68) v2(46.11,187.9) v2(46.32,195.73) v2(46.62,136.98) v2(46.93,184.48) v2(47.28,185.8) v2(47.79,196.08) v2(48.25,194.33) v2(48.25,191.36) v2(48.37,188.67) v2(48.4,184.2) v2(48.58,190.09) v2(49.16,136.98) v2(49.82,195.75) v2(51.7,136.98) v2(52.87,195.8) v2(54.24,136.98) v2(55.92,195.83) v2(56.78,136.98) v2(59.32,136.98) v2(60.57,195.8) v2(61.86,136.98) v2(63.31,187.47) v2(63.43,186.13) v2(63.61,195.63) v2(63.61,193.52) v2(63.94,189.78) v2(64.43,187.88) v2(64.93,163.73) v2(65.01,196.11) v2(65.11,154.66) v2(65.21,173.38) v2(65.59,195.47) v2(65.65,172.94) v2(65.57,155.06) v2(65.75,191.23) v2(65.82,193.64) v2(65.87,189.94) v2(65.87,188.82) v2(65.92,187.95) v2(66.15,136.98) v2(66.69,195.78) v2(67.45,196.11) v2(67.63,194.56) v2(69,189.96) v2(69.23,191.79) v2(69.68,196.13) v2(71.87,136.98) v2(72.25,196.11) v2(73.37,192.45) v2(73.82,193.72) v2(73.9,136.98) v2(74.61,196.13) v2(76.44,136.98) v2(76.85,188.11) v2(77.1,196.13) v2(78.98,136.98) v2(79.11,196.13) v2(79.44,193.7) v2(79.41,189.56) v2(80.63,196.03) v2(80.63,154.25) v2(81.52,136.98) v2(82.61,136.98) v2(83.91,133.04) v2(83.91,127.83) v2(83.91,126.31) v2(83.91,124.73) v2(83.91,123.41) v2(83.91,121.84) v2(83.93,117.27) v2(83.91,116.23) v2(83.91,110.92) v2(83.93,20.8) v2(84.06,112.97) v2(84.06,26.11) v2(84.06,23.06) v2(84.06,18.49) v2(84.06,15.95) v2(84.06,13.41) v2(84.9,192.96) v2(85.3,43.76) v2(85.33,42.03) v2(85.51,16.4) v2(85.51,14.65) v2(85.62,19.8) v2(85.84,51.46) v2(85.84,48.74) v2(85.81,46.05) v2(86.96,13.31) v2(87.08,111.91) v2(87.08,111.27) v2(87.08,110.64) v2(87.08,110) v2(87.08,109.37) v2(87.11,25.29) v2(87.41,135.17) v2(88.02,22.22) v2(88.15,7.64) v2(88.15,5.86) v2(88.17,1.62) v2(88.51,14.55) v2(88.56,6.47) v2(88.63,1.16) v2(89.14,13.41) v2(89.5,6.55) v2(90.21,12.42) v2(90.41,10.49) v2(90.41,8.58) v2(90.82,14.17) v2(91.2,44.55) v2(91.3,149.81) v2(91.55,7.56) v2(91.86,11.65) v2(92.19,144.85) v2(92.65,1.14) v2(93.05,6.5) v2(93.2,8.48) v2(93.28,10.46) v2(93.64,4.82) v2(93.71,193.75) v2(93.76,12.52) v2(94.14,146.98) v2(94.09,3.8) v2(94.47,194.51) v2(94.52,10.76) v2(94.6,147.44) v2(94.58,9.75) v2(94.83,12.01) v2(95.11,141.04) v2(95.49,19.4) v2(95.54,15.51) v2(95.62,11.63) v2(95.82,141.04) v2(96.25,148.92) v2(96.4,8.53) v2(96.4,5.53) v2(96.46,141.04) v2(96.76,10.74) v2(96.89,207.46) v2(96.89,149.3) v2(97.12,141.07) v2(97.22,9.93) v2(98.21,206.7) v2(98.31,207.67) v2(99.81,198.7) v2(100.44,198.7) v2(100.56,22.91) v2(100.93,208.76) v2(101.08,198.7) v2(101.38,8.55) v2(101.71,208.73) v2(101.71,200.6) v2(101.71,199.97) v2(101.71,199.33) v2(101.71,198.7) v2(101.71,198.06) v2(101.71,197.43) v2(101.71,196.79) v2(101.69,71.37) v2(101.92,61.89) v2(102.35,198.7) v2(102.55,61.89) v2(102.88,9.24) v2(102.98,198.7) v2(102.96,73.27) v2(102.96,72.64) v2(102.96,72) v2(102.96,71.37) v2(102.96,70.73) v2(102.96,70.1) v2(102.96,69.46) v2(102.96,68.83) v2(103.19,62.53) v2(103.19,61.89) v2(103.19,61.26) v2(103.62,198.7) v2(103.72,10.56) v2(103.77,5.61) v2(104,207.34) v2(104.25,208.73) v2(104.86,71.37) v2(104.91,8.73) v2(105.14,160.04) v2(105.4,197.94) v2(105.88,208.78) v2(106.13,4.8) v2(106.16,7.54) v2(106.26,52.09) v2(106.41,207.59) v2(106.41,197.68) v2(106.39,3.7) v2(107.05,0.96) v2(107.17,198.57) v2(107.58,208.76) v2(108.29,16.45) v2(109.13,15.31) v2(109.21,198.95) v2(109.46,0.83) v2(109.97,202.13) v2(109.97,200.1) v2(110.15,41.32) v2(110.2,38.4) v2(110.22,31.69) v2(110.2,30.88) v2(110.27,33.22) v2(110.35,32.46) v2(110.35,30.17) v2(110.43,36.7) v2(110.43,35.45) v2(110.88,43.3) v2(110.93,34.62) v2(111.03,81.68) v2(111.03,35.83) v2(110.98,33.83) v2(110.98,32.96) v2(111.01,31.72) v2(110.98,30.93) v2(111.01,29.89) v2(111.01,29.23) v2(111.03,28.6) v2(111.11,202.86) v2(111.11,200.83) v2(111.14,85.54) v2(111.24,89.99) v2(111.21,36.6) v2(111.37,184.73) v2(111.39,27.5) v2(111.47,45.79) v2(111.7,35.55) v2(111.7,8.33) v2(111.8,43.96) v2(111.8,38.83) v2(111.87,42.87) v2(112,79.55) v2(112,41.32) v2(111.97,36.44) v2(112.1,27.5) v2(112.15,86.28) v2(112.43,2.31) v2(112.53,113.61) v2(112.51,111.6) v2(112.51,110.05) v2(112.47,108.73) v2(112.48,108.1) v2(112.58,114.9) v2(112.56,27.02) v2(112.66,199) v2(112.74,79.52) v2(112.74,77.64) v2(112.74,75.1) v2(112.74,72.56) v2(112.74,70.02) v2(112.74,67.48) v2(112.74,64.94) v2(112.74,62.4) v2(112.74,59.86) v2(112.69,56.66) v2(112.74,55.19) v2(112.74,52.24) v2(112.74,49.7) v2(112.74,47.16) v2(112.74,44.62) v2(112.69,43.35) v2(112.74,42.08) v2(112.66,39.59) v2(112.76,40.63) v2(112.81,38.55) v2(113.02,26.49) v2(113.12,197.94) v2(113.09,44.04) v2(113.09,42.69) v2(113.09,41.45) v2(113.14,27.5) v2(113.07,3.42) v2(113.24,163.01) v2(113.22,37.56) v2(113.24,8.05) v2(113.4,165.93) v2(113.37,86.28) v2(113.63,26) v2(113.7,26.82) v2(113.8,46.53) v2(113.83,45.21) v2(113.8,43.84) v2(113.8,42.44) v2(113.8,40.66) v2(113.78,39.59) v2(114.03,4.26) v2(114.11,27.5) v2(114.16,192.98) v2(114.24,35.58) v2(114.24,26.21) v2(114.44,39.95) v2(114.45,38.79) v2(114.41,18.11) v2(114.59,36.49) v2(114.74,46.55) v2(114.74,45.21) v2(114.72,43.84) v2(114.72,42.44) v2(114.72,40.66) v2(114.67,5.66) v2(114.82,184.68) v2(114.82,166.29) v2(114.78,162.62) v2(114.79,26.84) v2(114.87,196.97) v2(114.87,194.41) v2(114.9,182.98) v2(114.9,181.05) v2(114.87,167.91) v2(114.91,159.94) v2(114.95,86.28) v2(114.92,13.14) v2(114.99,39.57) v2(114.97,22.09) v2(114.97,21.1) v2(115.05,18.11) v2(115,6.95) v2(115.07,186.15) v2(115.18,17.22) v2(115.18,16.07) v2(115.25,37.76) v2(115.33,27.41) v2(115.3,22.8) v2(115.28,20.17) v2(115.28,14.12) v2(115.28,11.86) v2(115.25,8.3) v2(115.53,147.31) v2(115.58,192.43) v2(115.56,36.14) v2(115.73,175.81) v2(115.68,169.97) v2(115.66,158.47) v2(115.84,143.23) v2(115.83,26.79) v2(115.86,152.62) v2(115.89,150.97) v2(115.89,148.79) v2(115.89,146.25) v2(115.89,139.26) v2(115.89,138.09) v2(115.89,136.09) v2(115.89,133.85) v2(115.89,131.01) v2(115.89,128.47) v2(115.89,125.93) v2(115.89,123.39) v2(115.89,120.85) v2(115.89,115.77) v2(115.89,114.52) v2(115.89,113.23) v2(115.89,110.69) v2(115.89,109.6) v2(115.89,108.15) v2(115.89,106.8) v2(115.86,105.13) v2(115.94,39.57) v2(115.89,25.88) v2(115.94,22.63) v2(115.91,21.18) v2(116.19,99.03) v2(116.45,99.69) v2(116.45,98.27) v2(116.45,90.09) v2(116.45,88.01) v2(116.52,38.45) v2(116.8,36.9) v2(116.85,39.57) v2(116.85,35.55) v3(14.18,144.29) v3(14.16,143.25) v3(14.51,143.78) v3(14.64,144.77) v3(14.59,142.97) v3(14.72,142.23) v3(15.58,143.58) v3(15.58,142.23) v3(15.76,144.83) v3(16.52,143.07) v3(16.52,142.26) v3(17.05,144.77) v3(17.08,144.24) v3(17.05,143.63) v3(18.81,143.89) v3(19.57,145.05) v3(19.9,143.89) v3(21.22,143.66) v3(21.91,144.72) v3(22.95,143.91) v3(25.34,144.55) v3(31.18,146.6) v3(34.81,155.52) v3(34.76,153.49) v3(34.76,152.85) v3(39.74,139.52) v3(71.73,160.92) v3(72.01,162.34) v3(72.28,160.92) v3(72.56,162.34) v3(74.48,163.77) v3(75.03,159.96) v3(75.31,163.3) v3(80.73,136.97) v3(95.69,14.19) v3(96.13,10.49) v3(96.4,14.42) v3(96.35,12.34) v3(96.58,22.93) v3(96.66,9.19) v3(96.94,11.65) v3(97.15,15.39) v3(97.19,20.87) v3(97.29,12.97) v3(97.57,13.84) v3(97.93,8.55) v3(98.03,20.31) v3(98.16,14.83) v3(98.23,12.8) v3(98.28,11.63) v3(98.41,9.65) v3(98.53,6.85) v3(98.72,19.81) v3(98.67,7.69) v3(99.07,13) v3(99.33,15.72) v3(99.43,9.34) v3(99.4,7.87) v3(99.48,10.38) v3(99.6,26.23) v3(99.55,6.93) v3(99.73,12.39) v3(99.73,12.03) v3(99.83,34.34) v3(99.76,19.45) v3(99.86,13.25) v3(99.91,11.09) v3(100.19,14.9) v3(100.29,9.82) v3(100.34,8.15) v3(100.42,25.34) v3(100.47,60.42) v3(100.65,34.01) v3(100.57,16.2) v3(100.62,13.61) v3(100.67,13.18) v3(100.75,12.77) v3(100.85,57.75) v3(100.77,11.68) v3(100.77,7.46) v3(100.87,6.78) v3(101.21,23.9) v3(101.15,9.24) v3(101.38,42.16) v3(101.43,33.73) v3(101.43,29.66) v3(101.41,13.2) v3(101.46,14.63) v3(101.46,10.36) v3(101.51,6.83) v3(101.87,59.23) v3(101.94,57.81) v3(102.14,55.6) v3(102.2,51.99) v3(102.2,42.16) v3(102.25,33.35) v3(102.22,29.48) v3(102.22,13.2) v3(102.27,12.57) v3(102.54,41.65) v3(102.68,8.02) v3(103.11,48.05) v3(103.11,45.82) v3(103.14,12.77) v3(103.16,14.32) v3(103.19,12.06) v3(103.29,58.67) v3(103.31,30.25) v3(103.29,26.13) v3(103.31,23.16) v3(103.47,53.84) v3(103.47,42.16) v3(103.57,57.98) v3(103.62,44.14) v3(103.62,33.85) v3(103.8,15.44) v3(103.87,12.69) v3(104.08,11.42) v3(104.2,50.44) v3(104.15,48.84) v3(104.2,38.91) v3(104.28,60.4) v3(104.3,47.49) v3(104.25,42.03) v3(104.43,56.54) v3(104.35,51.99) v3(104.38,45.71) v3(104.35,43.2) v3(104.41,12.77) v3(104.38,11.91) v3(104.48,10.69) v3(104.66,11.45) v3(104.79,38.43) v3(104.86,42.72) v3(104.86,14.47) v3(105.12,59) v3(105.07,9.9) v3(105.29,50.21) v3(105.35,48.36) v3(105.32,16) v3(105.35,12.64) v3(105.42,46.98) v3(105.4,37.87) v3(105.55,56.21) v3(105.47,52.52) v3(105.55,10.79) v3(105.83,60.02) v3(105.88,37.33) v3(105.85,12.77) v3(105.9,11.88) v3(106.08,16.68) v3(106.18,50.08) v3(106.16,47.77) v3(106.18,15.11) v3(106.31,36.72) v3(106.46,13) v3(106.51,12.24) v3(106.51,11.48) v3(106.67,56.54) v3(106.95,47.65) v3(107.12,15.11) v3(107.22,52.14) v3(107.22,14.07) v3(107.3,50.06) v3(107.25,48.2) v3(107.38,15.79) v3(108.27,14.5) v3(109.82,16) v3(109.84,13.43) v3(110.83,18.13) v3(110.78,14.55) v4(14.18,144.29) v4(14.16,143.25) v4(14.51,143.78) v4(14.64,144.77) v4(14.59,142.97) v4(14.72,142.23) v4(15.58,143.58) v4(15.58,142.23) v4(15.76,144.83) v4(15.78,140.38) v4(16.4,140.38) v4(16.52,143.07) v4(16.52,142.26) v4(17.05,144.77) v4(17.08,144.24) v4(17.05,143.63) v4(18.81,143.89) v4(19.57,145.05) v4(19.9,143.89) v4(21.22,143.66) v4(21.91,144.72) v4(22.95,143.91) v4(25.34,144.55) v4(33.65,141.88) v4(35.88,155.49) v4(36.53,169.6) v4(36.64,160.49) v4(37.22,151.29) v4(37.35,156.92) v4(37.71,148.89) v4(37.91,167.97) v4(39.71,156.92) v4(40.31,147.88) v4(40.45,167.53) v4(40.95,155.49) v4(40.95,151.99) v4(42.21,149.18) v4(42.3,152.98) v4(42.86,162.73) v4(44.92,162.15) v4(46.62,181.91) v4(46.6,181.48) v4(46.65,165.2) v4(46.65,164.38) v4(46.7,168.24) v4(46.67,165.76) v4(46.67,146.71) v4(46.95,146.27) v4(47.08,181.96) v4(47.84,152.48) v4(47.84,151.96) v4(47.87,175.46) v4(47.86,174.07) v4(47.86,173.43) v4(47.86,172.92) v4(47.85,155.53) v4(47.85,153.87) v4(47.86,151.42) v4(48.37,171.65) v4(48.5,178.89) v4(48.5,176.47) v4(48.5,173.93) v4(48.5,170.89) v4(48.5,168.35) v4(48.5,165.68) v4(48.5,163.14) v4(48.5,160.6) v4(48.5,158.06) v4(48.5,155.14) v4(48.88,150.31) v4(49.24,183.03) v4(49.42,161.25) v4(49.89,167.44) v4(50.38,167.43) v4(50.47,156.88) v4(50.47,155.88) v4(50.48,153.38) v4(50.47,151.88) v4(50.51,151.37) v4(50.47,150.88) v4(50.53,148.79) v4(50.72,177.56) v4(50.72,177.06) v4(50.72,176.56) v4(50.72,176.06) v4(50.72,174.56) v4(50.71,172.56) v4(50.71,171.57) v4(50.97,151.88) v4(50.97,151.38) v4(50.97,150.38) v4(51.01,146.4) v4(51.22,178.06) v4(51.22,177.06) v4(51.22,176.56) v4(51.23,161.18) v4(51.46,167.3) v4(51.47,151.88) v4(51.47,150.88) v4(51.47,150.38) v4(51.58,163.79) v4(51.72,178.06) v4(51.72,177.56) v4(51.72,176.56) v4(51.93,180.67) v4(52.01,158.39) v4(51.97,151.88) v4(51.97,151.38) v4(51.97,150.88) v4(51.97,150.38) v4(52.22,178.06) v4(52.22,177.56) v4(52.22,177.06) v4(52.22,176.56) v4(52.24,172.51) v4(52.24,170.04) v4(52.44,180.67) v4(52.44,155.36) v4(52.47,154.85) v4(52.49,153.38) v4(52.49,152.85) v4(52.49,152.36) v4(52.47,150.38) v4(52.49,146.3) v4(52.75,172.51) v4(52.73,143.22) v4(52.97,158.38) v4(53,155.89) v4(53.07,180.67) v4(53.07,148.79) v4(53.13,139.88) v4(53.23,176.04) v4(53.23,172.51) v4(53.23,170.04) v4(53.35,146.2) v4(53.51,157.9) v4(53.46,157.42) v4(53.59,147.51) v4(53.74,176.04) v4(53.73,171.09) v4(53.73,170.56) v4(53.93,155.95) v4(53.99,157.37) v4(53.97,150.38) v4(54.12,176.04) v4(54.07,147.51) v4(54.23,172.52) v4(54.47,167.43) v4(54.47,158.38) v4(54.59,161.23) v4(54.67,170.05) v4(54.95,152.36) v4(55.11,161.23) v4(55.13,139.85) v4(55.23,180.67) v4(55.47,155.88) v4(55.6,147.51) v4(55.74,180.67) v4(55.72,172.56) v4(55.93,143.22) v4(55.97,155.38) v4(55.96,153.89) v4(55.97,150.38) v4(56.12,147.5) v4(56.22,178.06) v4(56.22,173.06) v4(56.2,170.04) v4(56.31,176.57) v4(56.25,174.54) v4(56.48,156.38) v4(56.66,172.01) v4(57,167.46) v4(56.99,161.25) v4(56.99,156.86) v4(56.97,150.38) v4(57.14,180.67) v4(57.13,139.88) v4(57.22,178.06) v4(57.24,171.54) v4(57.25,147.5) v4(57.29,148.03) v4(57.47,158.38) v4(57.47,157.88) v4(57.72,175.06) v4(57.72,174.56) v4(57.77,148.28) v4(57.93,143.22) v4(57.97,158.38) v4(58.22,175.06) v4(58.22,171.06) v4(58.27,147.51) v4(58.33,139.88) v4(58.47,154.38) v4(58.47,152.88) v4(58.47,151.88) v4(58.72,176.56) v4(58.72,175.56) v4(58.72,174.06) v4(58.71,172.1) v4(58.71,170.52) v4(58.77,147.53) v4(59.3,147.52) v4(59.45,146.22) v4(59.68,148.56) v4(59.8,147.52) v4(60.51,146.25) v4(61.1,156) v4(61.1,153.36) v4(61.08,151.06) v4(61.2,170.73) v4(61.33,178.79) v4(61.33,175.86) v4(61.84,178.79) v4(62.04,148.53) v4(62.67,183.05) v4(63.13,141.51) v4(63.33,164.94) v4(63.41,170.17) v4(63.36,168.42) v4(63.38,165.96) v4(63.49,162.02) v4(63.49,161.23) v4(63.71,158.69) v4(63.71,157.55) v4(64.07,190.93) v4(64.2,192.07) v4(64.25,148.61) v4(64.4,193.54) v4(64.43,192.68) v4(66.53,148.79) v4(67.08,191.35) v4(67.08,190.15) v4(67.08,188.95) v4(67.08,187.75) v4(67.08,186.55) v4(67.93,150.82) v4(69.33,152.22) v4(70.22,176.63) v4(70.27,153.18) v4(71.36,192.15) v4(71.36,190.55) v4(71.36,189.35) v4(71.36,188.95) v4(71.36,188.15) v4(71.36,186.95) v4(71.84,173.93) v4(71.84,173.43) v4(71.84,172.92) v4(72.73,154.38) v4(72.73,153.87) v4(72.73,153.36) v4(74.66,174.95) v4(74.92,175.25) v4(75.31,180.53) v4(75.3,175.64) v4(75.55,178.18) v4(75.93,174.11) v4(76.3,175.25) v4(76.31,155.34) v4(76.31,154.91) v4(76.49,153.74) v4(76.69,151.05) v4(77.84,151.05) v4(78.47,185.29) v4(79.03,179.01) v4(79.49,185.57) v4(80.12,187.09) v4(80.12,186.61) v4(80.61,153.72) v4(80.73,136.97) v4(80.88,166.04) v4(80.91,163.25) v4(80.91,155.21) v4(81.14,164.62) v4(81.16,169.16) v4(81.23,166.32) v4(81.16,161.79) v4(81.22,154.96) v4(81.47,181.88) v4(81.52,165.48) v4(81.52,160.94) v4(81.52,159.81) v4(82.1,181.83) v4(82.54,186.74) v4(82.92,187.12) v4(82.92,186.74) v4(82.92,186.35) v4(82.92,171.17) v4(82.92,169.08) v4(82.92,168.63) v4(82.92,166.59) v4(82.97,162.63) v4(83.04,160.09) v4(83.2,158.19) v4(83.2,157.68) v4(83.2,157.17) v4(83.3,186.74) v4(83.35,158.87) v4(83.43,169.08) v4(83.43,166.54) v4(83.6,181.86) v4(83.68,158.29) v4(83.68,155.75) v4(83.81,96.21) v4(83.83,93.54) v4(83.93,164) v4(83.91,89.5) v4(83.88,84.04) v4(83.88,79.07) v4(83.88,72.61) v4(83.86,67.28) v4(83.88,61.62) v4(83.97,162.12) v4(83.96,99.28) v4(84.44,165.58) v4(84.44,164) v4(84.36,64.92) v4(84.49,115.23) v4(84.75,181.83) v4(84.8,110.54) v4(84.95,164) v4(84.97,167.58) v4(85.09,24.44) v4(85.17,160.35) v4(85.2,35.83) v4(85.33,187.47) v4(85.58,164.99) v4(85.74,190.83) v4(85.66,31.37) v4(85.84,33.6) v4(85.99,185.87) v4(86.09,181.86) v4(86.14,34.51) v4(86.22,75.7) v4(86.19,35.83) v4(86.3,55.49) v4(86.39,22.54) v4(86.73,167.2) v4(86.78,181.22) v4(86.78,180.54) v4(86.75,179.88) v4(86.75,179.29) v4(86.78,172.05) v4(86.78,171.24) v4(86.78,170.48) v4(86.78,169.85) v4(86.75,169.01) v4(86.75,168.47) v4(86.75,167.81) v4(86.78,166.49) v4(86.78,164.28) v4(86.78,163.65) v4(86.78,162.78) v4(86.78,161.72) v4(86.75,160.9) v4(86.75,160.37) v4(86.75,159.61) v4(86.78,159.13) v4(86.8,158.49) v4(86.78,155.16) v4(86.78,153.87) v4(86.8,32.43) v4(86.87,73.8) v4(86.99,55.44) v4(87.55,78.95) v4(87.62,168.98) v4(87.74,187.65) v4(87.74,186.13) v4(87.74,184.6) v4(87.74,182.57) v4(87.74,181.05) v4(87.74,178.13) v4(87.77,55.19) v4(87.82,53.84) v4(87.87,175.2) v4(88.02,189.22) v4(88,172.16) v4(87.97,166.31) v4(87.97,165.22) v4(87.97,164.08) v4(87.97,154.81) v4(88,152.73) v4(88.36,77.09) v4(88.45,73.12) v4(88.45,70.68) v4(88.94,181.83) v4(88.94,181.33) v4(88.99,184.48) v4(88.99,183.71) v4(88.99,183.21) v4(88.99,182.44) v4(89.24,184.09) v4(89.24,182.82) v4(89.24,55.11) v4(89.32,181.58) v4(89.5,189.11) v4(89.5,184.48) v4(89.5,183.71) v4(89.5,183.21) v4(89.5,182.44) v4(89.52,124.53) v4(89.6,146.07) v4(89.67,181.83) v4(89.67,181.33) v4(89.66,75.19) v4(89.74,48.95) v4(89.74,45.95) v4(89.74,44.15) v4(89.74,42.35) v4(90,165.55) v4(90,164.79) v4(90,164.28) v4(90,163.52) v4(90.03,54.71) v4(90.02,52.65) v4(90.02,38.05) v4(90.21,181.83) v4(90.21,181.33) v4(90.21,178.02) v4(90.21,177.52) v4(90.16,124.53) v4(90.26,165.17) v4(90.26,163.9) v4(90.32,161.78) v4(90.54,176.98) v4(90.54,176.25) v4(90.51,165.55) v4(90.51,164.79) v4(90.51,164.28) v4(90.51,163.52) v4(90.55,78.95) v4(90.59,181.58) v4(90.59,177.77) v4(90.56,71.55) v4(90.79,176.6) v4(90.79,124.53) v4(90.79,76.09) v4(90.94,181.83) v4(90.94,178.02) v4(90.94,177.52) v4(91.02,189.11) v4(91.05,176.98) v4(91.05,176.25) v4(90.97,171.47) v4(90.97,170.73) v4(90.97,170.2) v4(90.97,169.46) v4(91.12,146.07) v4(91.22,171.09) v4(91.22,169.82) v4(91.17,31.57) v4(91.17,27.76) v4(91.3,29.28) v4(91.4,185.52) v4(91.4,185.01) v4(91.48,170.73) v4(91.58,178.25) v4(91.58,177.52) v4(91.58,176.98) v4(91.58,176.25) v4(91.71,37.16) v4(91.68,27.76) v4(91.76,185.26) v4(91.83,177.87) v4(91.83,176.6) v4(92.01,171.14) v4(92.01,170.63) v4(92.14,185.52) v4(92.14,185.01) v4(92.09,178.25) v4(92.09,177.52) v4(92.09,176.98) v4(92.09,176.25) v4(92.19,31.19) v4(92.19,27.76) v4(92.39,170.89) v4(92.39,76.65) v4(92.44,41.45) v4(92.54,189.11) v4(92.54,77.29) v4(92.65,185.52) v4(92.65,185.01) v4(92.64,146.07) v4(92.62,49.85) v4(92.62,46.85) v4(92.62,45.05) v4(92.62,43.25) v4(92.72,161.78) v4(92.72,36.16) v4(92.77,171.14) v4(93.03,185.26) v4(93.05,35.49) v4(93.05,34.85) v4(93.05,34.22) v4(93.15,187.32) v4(93.15,186.58) v4(93.41,186.94) v4(93.38,185.52) v4(93.38,185.01) v4(93.37,156.49) v4(93.52,161.78) v4(93.66,187.32) v4(93.66,186.58) v4(93.74,19.9) v4(93.84,194.46) v4(93.92,185.52) v4(93.92,185.01) v4(93.94,35.24) v4(93.94,34.6) v4(93.97,188.92) v4(94.05,78.95) v4(94.3,185.26) v4(94.32,161.78) v4(94.32,75.51) v4(94.37,156.99) v4(94.37,151.49) v4(94.47,195.12) v4(94.65,185.52) v4(94.65,185.01) v4(94.72,161.78) v4(94.86,167.81) v4(94.86,167.3) v4(94.88,156.49) v4(94.88,154.49) v4(94.88,153.49) v4(95.24,167.56) v4(95.2,146.07) v4(95.4,189.11) v4(95.36,182.9) v4(95.36,182.39) v4(95.37,156.99) v4(95.37,150.49) v4(95.59,167.81) v4(95.59,167.3) v4(95.74,183.94) v4(95.74,183.43) v4(95.74,182.65) v4(95.67,76.55) v4(95.69,14.19) v4(95.85,75.92) v4(95.88,152.49) v4(95.9,75.51) v4(96.13,183.69) v4(96.1,182.9) v4(96.1,182.39) v4(96.13,10.49) v4(96.37,154.99) v4(96.35,12.34) v4(96.48,183.94) v4(96.48,183.43) v4(96.58,187.88) v4(96.58,187.37) v4(96.63,182.7) v4(96.63,182.19) v4(96.68,196.06) v4(96.72,146.07) v4(96.81,161.82) v4(96.81,161.31) v4(96.92,189.11) v4(96.96,187.62) v4(97.01,182.44) v4(97.19,161.56) v4(97.21,38.21) v4(97.21,33.71) v4(97.21,28.21) v4(97.24,13.86) v4(97.32,187.88) v4(97.32,187.37) v4(97.27,129.94) v4(97.28,40.01) v4(97.29,12.97) v4(97.37,182.7) v4(97.37,182.19) v4(97.37,153.99) v4(97.4,125.29) v4(97.49,71.55) v4(97.57,161.82) v4(97.57,161.31) v4(97.85,187.88) v4(97.85,187.37) v4(98.03,129.94) v4(98.08,24.83) v4(98.23,187.62) v4(98.21,161.82) v4(98.21,161.31) v4(98.24,146.07) v4(98.16,125.29) v4(98.44,189.11) v4(98.41,9.65) v4(98.46,130.63) v4(98.45,16.67) v4(98.59,187.88) v4(98.59,187.37) v4(98.59,161.56) v4(98.58,24.83) v4(98.97,161.82) v4(98.97,161.31) v4(99.12,187.74) v4(99.12,187.23) v4(99.08,24.83) v4(99.07,13) v4(99.25,133.17) v4(99.5,187.49) v4(99.48,162.07) v4(99.48,161.56) v4(99.48,132.28) v4(99.48,131.52) v4(99.58,40.08) v4(99.58,24.83) v4(99.94,193.21) v4(99.94,188.92) v4(99.86,187.74) v4(99.86,187.23) v4(99.86,161.82) v4(99.86,13.25) v4(100.08,24.83) v4(100.24,162.07) v4(100.24,161.56) v4(100.19,14.9) v4(100.31,195.74) v4(100.35,17.97) v4(100.58,24.83) v4(100.7,182.6) v4(100.7,182.09) v4(100.75,12.77) v4(100.77,193.16) v4(100.8,146.07) v4(101.08,182.34) v4(101.08,40.08) v4(101.08,24.83) v4(101.23,167.81) v4(101.23,167.3) v4(101.21,129.61) v4(101.21,129.23) v4(101.16,37.94) v4(101.16,37.43) v4(101.16,36.92) v4(101.16,34.61) v4(101.16,34.11) v4(101.16,31.31) v4(101.16,30.81) v4(101.16,30.3) v4(101.16,27.99) v4(101.16,27.48) v4(101.16,26.97) v4(101.32,189.14) v4(101.36,166.77) v4(101.36,166.26) v4(101.38,42.16) v4(101.43,33.73) v4(101.43,13.89) v4(101.41,13.2) v4(101.46,187.74) v4(101.46,187.23) v4(101.46,182.6) v4(101.46,182.09) v4(101.46,85.3) v4(101.46,84.26) v4(101.46,83.27) v4(101.46,82.23) v4(101.46,14.63) v4(101.61,167.56) v4(101.59,114.75) v4(101.59,88.04) v4(101.58,24.83) v4(101.74,166.52) v4(101.84,187.49) v4(101.97,167.81) v4(101.97,167.3) v4(102.09,166.77) v4(102.09,166.26) v4(102.09,87.53) v4(102.08,24.83) v4(102.2,187.74) v4(102.2,187.23) v4(102.22,88.8) v4(102.2,42.16) v4(102.22,13.2) v4(102.32,146.07) v4(102.45,80.59) v4(102.53,86.11) v4(102.54,41.65) v4(102.58,40.08) v4(102.58,24.83) v4(102.7,167.58) v4(102.7,166.85) v4(102.7,166.31) v4(102.7,165.58) v4(102.7,165.04) v4(102.7,164.31) v4(102.73,130.5) v4(102.82,189.11) v4(102.91,159.33) v4(102.91,158.26) v4(102.96,167.2) v4(102.96,165.93) v4(102.96,164.66) v4(102.98,129.61) v4(103.08,24.83) v4(103.14,12.77) v4(103.21,167.58) v4(103.21,166.85) v4(103.21,166.31) v4(103.21,165.58) v4(103.21,165.04) v4(103.21,164.31) v4(103.41,183.33) v4(103.47,42.16) v4(103.62,188.1) v4(103.58,24.83) v4(103.8,183.59) v4(103.84,146.07) v4(103.77,84.87) v4(103.95,158.69) v4(103.87,88.93) v4(103.87,12.69) v4(104.13,92.23) v4(104.08,40.08) v4(104.08,24.83) v4(104.15,183.84) v4(104.15,183.33) v4(104.15,84.87) v4(104.38,90.07) v4(104.38,89.31) v4(104.38,88.17) v4(104.41,12.77) v4(104.51,85.63) v4(104.51,85.25) v4(104.51,84.87) v4(104.51,84.46) v4(104.53,84.05) v4(104.51,37.94) v4(104.51,37.43) v4(104.51,36.92) v4(104.51,34.61) v4(104.51,34.11) v4(104.51,33.6) v4(104.51,31.31) v4(104.51,30.81) v4(104.51,30.3) v4(104.51,27.99) v4(104.51,27.48) v4(104.51,26.97) v4(104.63,90.58) v4(104.58,24.83) v4(104.76,88.93) v4(104.76,86.77) v4(104.76,82.96) v4(104.89,91.73) v4(104.89,84.87) v4(105.02,188.1) v4(105.07,176.63) v4(105.07,176.12) v4(105.08,24.83) v4(105.17,186.76) v4(105.24,84.87) v4(105.32,16) v4(105.35,12.64) v4(105.45,176.37) v4(105.41,107.16) v4(105.39,106.65) v4(105.45,155.97) v4(105.5,17.75) v4(105.58,24.83) v4(105.73,187.45) v4(105.78,188.92) v4(105.8,176.63) v4(105.8,176.12) v4(105.85,12.77) v4(106.08,24.83) v4(106.08,16.68) v4(106.16,89.44) v4(106.18,15.11) v4(106.34,176.63) v4(106.34,176.12) v4(106.42,188.1) v4(106.44,167.58) v4(106.44,166.85) v4(106.44,165.58) v4(106.44,165.04) v4(106.44,164.31) v4(106.46,13) v4(106.51,12.24) v4(106.51,11.48) v4(106.64,169.08) v4(106.64,168.57) v4(106.58,24.83) v4(106.72,176.37) v4(106.69,167.2) v4(106.69,164.66) v4(106.74,157.04) v4(106.72,153.49) v4(106.84,185.49) v4(106.95,167.58) v4(106.95,166.85) v4(106.95,165.58) v4(106.95,165.04) v4(106.95,164.31) v4(107.02,168.83) v4(107.1,179.48) v4(107.07,176.63) v4(107.07,176.12) v4(107.08,24.83) v4(107.12,15.11) v4(107.2,189.11) v4(107.17,173.68) v4(107.17,173.17) v4(107.22,14.07) v4(107.38,169.08) v4(107.38,168.57) v4(107.4,85.68) v4(107.4,84.16) v4(107.43,83.1) v4(107.43,82.6) v4(107.38,15.79) v4(107.56,173.43) v4(107.58,24.83) v4(107.71,18.16) v4(107.8,107.64) v4(107.81,90.46) v4(107.91,173.68) v4(107.91,173.17) v4(107.94,169.08) v4(107.94,168.57) v4(107.92,146.07) v4(108.01,176.45) v4(108.32,168.83) v4(108.27,14.5) v4(108.37,176.7) v4(108.37,176.19) v4(108.38,24.91) v4(108.47,173.68) v4(108.47,173.17) v4(108.46,32.71) v4(108.46,29.71) v4(108.46,28.21) v4(108.46,26.21) v4(108.46,25.71) v4(108.72,189.11) v4(108.67,169.08) v4(108.67,168.57) v4(108.9,176.7) v4(108.9,176.19) v4(108.85,173.43) v4(108.89,111.45) v4(108.89,110.05) v4(108.89,108.66) v4(109.21,173.68) v4(109.21,173.17) v4(109.23,169.08) v4(109.23,168.57) v4(109.28,176.45) v4(109.33,39.36) v4(109.33,21.1) v4(109.44,146.07) v4(109.38,38.55) v4(109.64,176.19) v4(109.61,168.83) v4(109.76,105.86) v4(109.78,104.47) v4(109.78,103.07) v4(109.82,16) v4(109.84,13.43) v4(109.87,172.69) v4(109.97,169.08) v4(110.02,168.55) v4(109.97,165.93) v4(109.97,164.41) v4(109.97,162.89) v4(110.03,107.28) v4(110.02,36.14) v4(110.07,175.53) v4(110.11,37.4) v4(110.24,189.11) v4(110.25,34.49) v4(110.3,176.5) v4(110.53,169.08) v4(110.53,168.57) v4(110.63,172.69) v4(110.73,37.82) v4(110.83,18.13) v4(110.78,14.55) v4(110.91,168.83) v4(110.93,42.7) v4(111.06,176.5) v4(111.26,169.08) v4(111.26,168.57) v4(111.49,188.92) v4(111.85,42.26) v4(111.9,37.94) v4(111.9,37.18) v4(112.3,161.12) v4(112.3,159.6) v4(112.3,158.08) v4(112.3,155.92) v4(112.3,154.4) v4(112.3,152.88) v4(112.3,150.72) v4(112.3,149.2) v4(112.3,147.68) v4(112.53,100.22) v4(112.64,98.62) v4(112.64,98.12) v4(112.81,96.77) v4(113.04,94.36) v4(113.07,91.82) v5(12.49,140.55) v5(14.18,144.29) v5(14.16,143.25) v5(14.51,143.78) v5(14.64,144.77) v5(14.59,142.97) v5(14.72,142.23) v5(15.58,143.58) v5(15.58,142.23) v5(15.76,144.83) v5(16.52,143.07) v5(16.52,142.26) v5(17.05,144.77) v5(17.08,144.24) v5(17.05,143.63) v5(18.81,143.89) v5(19.57,145.05) v5(19.9,143.89) v5(21.22,143.66) v5(21.91,144.72) v5(22.95,143.91) v5(24.42,141.93) v5(25.34,144.55) v5(28.71,142.18) v5(33.65,141.88) v5(35.88,155.49) v5(36.53,169.6) v5(36.64,160.49) v5(37.22,151.29) v5(37.35,156.92) v5(37.71,148.89) v5(37.91,167.97) v5(39.71,156.92) v5(40.31,147.88) v5(40.45,167.53) v5(40.95,155.49) v5(40.95,151.99) v5(42.21,149.18) v5(42.3,152.98) v5(44.92,162.15) v5(46.62,181.91) v5(46.6,181.48) v5(46.65,165.2) v5(46.65,164.38) v5(46.7,168.24) v5(46.67,165.76) v5(46.67,146.71) v5(46.95,146.27) v5(47.08,181.96) v5(47.84,152.48) v5(47.84,151.96) v5(47.87,175.46) v5(47.86,174.07) v5(47.86,173.43) v5(47.86,172.92) v5(47.85,155.53) v5(47.85,153.87) v5(47.86,151.42) v5(48.37,171.65) v5(49.24,183.03) v5(49.42,161.25) v5(49.89,167.44) v5(50.38,167.43) v5(50.47,156.88) v5(50.47,155.88) v5(50.48,153.38) v5(50.47,151.88) v5(50.51,151.37) v5(50.47,150.88) v5(50.72,177.56) v5(50.72,177.06) v5(50.72,176.56) v5(50.72,176.06) v5(50.72,174.56) v5(50.71,172.56) v5(50.71,171.57) v5(50.97,151.88) v5(50.97,151.38) v5(50.97,150.38) v5(51.01,146.4) v5(51.22,178.06) v5(51.22,177.06) v5(51.22,176.56) v5(51.23,161.18) v5(51.46,167.3) v5(51.47,151.88) v5(51.47,150.88) v5(51.47,150.38) v5(51.58,163.79) v5(51.72,178.06) v5(51.72,177.56) v5(51.72,176.56) v5(51.93,180.67) v5(52.01,158.39) v5(51.97,151.88) v5(51.97,151.38) v5(51.97,150.88) v5(51.97,150.38) v5(52.22,178.06) v5(52.22,177.56) v5(52.22,177.06) v5(52.22,176.56) v5(52.24,172.51) v5(52.24,170.04) v5(52.44,180.67) v5(52.44,155.36) v5(52.47,154.85) v5(52.49,153.38) v5(52.49,152.85) v5(52.49,152.36) v5(52.47,150.38) v5(52.49,146.3) v5(52.75,172.51) v5(52.73,143.22) v5(52.97,158.38) v5(53,155.89) v5(53.07,180.67) v5(53.13,139.88) v5(53.23,176.04) v5(53.23,172.51) v5(53.23,170.04) v5(53.35,146.2) v5(53.51,157.9) v5(53.46,157.42) v5(53.59,147.51) v5(53.74,176.04) v5(53.73,171.09) v5(53.73,170.56) v5(53.93,155.95) v5(53.99,157.37) v5(53.97,150.38) v5(54.12,176.04) v5(54.07,147.51) v5(54.23,172.52) v5(54.47,167.43) v5(54.47,158.38) v5(54.59,161.23) v5(54.67,170.05) v5(54.95,152.36) v5(55.11,161.23) v5(55.13,139.85) v5(55.23,180.67) v5(55.47,155.88) v5(55.6,147.51) v5(55.74,180.67) v5(55.72,172.56) v5(55.93,143.22) v5(55.97,155.38) v5(55.96,153.89) v5(55.97,150.38) v5(56.12,147.5) v5(56.22,178.06) v5(56.22,173.06) v5(56.2,170.04) v5(56.31,176.57) v5(56.25,174.54) v5(56.48,156.38) v5(56.66,172.01) v5(57,167.46) v5(56.99,161.25) v5(56.99,156.86) v5(56.97,150.38) v5(57.14,180.67) v5(57.13,139.88) v5(57.22,178.06) v5(57.24,171.54) v5(57.25,147.5) v5(57.29,148.03) v5(57.47,158.38) v5(57.47,157.88) v5(57.72,175.06) v5(57.72,174.56) v5(57.93,143.22) v5(57.97,158.38) v5(58.22,175.06) v5(58.22,171.06) v5(58.27,147.51) v5(58.33,139.88) v5(58.47,154.38) v5(58.47,152.88) v5(58.47,151.88) v5(58.72,176.56) v5(58.72,175.56) v5(58.72,174.06) v5(58.71,172.1) v5(58.71,170.52) v5(58.77,147.53) v5(59.3,147.52) v5(59.45,146.22) v5(59.8,147.52) v5(60.51,146.25) v5(61.1,156) v5(61.1,153.36) v5(61.08,151.06) v5(61.2,170.73) v5(61.33,178.79) v5(61.33,175.86) v5(61.84,178.79) v5(62.67,183.05) v5(63.13,141.51) v5(63.33,164.94) v5(63.41,170.17) v5(63.36,168.42) v5(63.38,165.96) v5(63.49,162.02) v5(63.49,161.23) v5(63.71,158.69) v5(63.71,157.55) v5(64.07,190.93) v5(64.2,192.07) v5(64.4,193.54) v5(64.43,192.68) v5(67.08,191.35) v5(67.08,190.15) v5(67.08,188.95) v5(67.08,187.75) v5(67.08,186.55) v5(70.08,166.63) v5(70.08,165.68) v5(70.22,176.63) v5(70.63,159.96) v5(70.91,166.16) v5(71.36,192.15) v5(71.36,190.55) v5(71.36,189.35) v5(71.36,188.95) v5(71.36,188.15) v5(71.36,186.95) v5(71.84,173.93) v5(71.84,173.43) v5(71.84,172.92) v5(72.73,154.38) v5(72.73,153.87) v5(72.73,153.36) v5(73.11,159.49) v5(74.66,174.95) v5(74.92,175.25) v5(75.31,180.53) v5(75.3,175.64) v5(75.55,178.18) v5(75.93,174.11) v5(76.3,175.25) v5(76.31,155.34) v5(76.31,154.91) v5(76.41,160.44) v5(76.49,153.74) v5(76.69,151.05) v5(76.96,164.25) v5(77.23,165.68) v5(77.23,161.87) v5(77.23,159.96) v5(77.84,151.05) v5(78.47,185.29) v5(79.03,179.01) v5(79.49,185.57) v5(80.12,187.09) v5(80.12,186.61) v5(80.61,153.72) v5(80.73,136.97) v5(80.88,166.04) v5(80.91,163.25) v5(80.91,155.21) v5(81.14,164.62) v5(81.16,169.16) v5(81.23,166.32) v5(81.16,161.79) v5(81.22,154.96) v5(81.47,181.88) v5(81.52,165.48) v5(81.52,160.94) v5(81.52,159.81) v5(82.1,181.83) v5(82.54,186.74) v5(82.92,187.12) v5(82.92,186.74) v5(82.92,186.35) v5(82.92,171.17) v5(82.92,169.08) v5(82.92,168.63) v5(82.92,166.59) v5(82.97,162.63) v5(83.04,160.09) v5(83.2,158.19) v5(83.2,157.68) v5(83.2,157.17) v5(83.3,186.74) v5(83.35,158.87) v5(83.43,169.08) v5(83.43,166.54) v5(83.6,181.86) v5(83.68,158.29) v5(83.68,155.75) v5(83.81,96.21) v5(83.83,93.54) v5(83.93,164) v5(83.91,89.5) v5(83.88,84.04) v5(83.88,79.07) v5(83.88,72.61) v5(83.86,67.28) v5(83.88,61.62) v5(83.97,162.12) v5(83.96,99.28) v5(84.44,165.58) v5(84.44,164) v5(84.36,64.92) v5(84.49,115.23) v5(84.75,181.83) v5(84.8,110.54) v5(84.95,164) v5(84.97,167.58) v5(85.09,24.44) v5(85.17,160.35) v5(85.2,35.83) v5(85.33,187.47) v5(85.58,164.99) v5(85.74,190.83) v5(85.66,31.37) v5(85.84,33.6) v5(85.99,185.87) v5(86.09,181.86) v5(86.14,34.51) v5(86.22,75.7) v5(86.19,35.83) v5(86.3,55.49) v5(86.39,22.54) v5(86.73,167.2) v5(86.78,181.22) v5(86.78,180.54) v5(86.75,179.88) v5(86.75,179.29) v5(86.78,172.05) v5(86.78,171.24) v5(86.78,170.48) v5(86.78,169.85) v5(86.75,169.01) v5(86.75,168.47) v5(86.75,167.81) v5(86.78,166.49) v5(86.78,164.28) v5(86.78,163.65) v5(86.78,162.78) v5(86.78,161.72) v5(86.75,160.9) v5(86.75,160.37) v5(86.75,159.61) v5(86.78,159.13) v5(86.8,158.49) v5(86.78,155.16) v5(86.78,153.87) v5(86.8,32.43) v5(86.87,73.8) v5(86.99,55.44) v5(87.55,78.95) v5(87.62,168.98) v5(87.74,187.65) v5(87.74,186.13) v5(87.74,184.6) v5(87.74,182.57) v5(87.74,181.05) v5(87.74,178.13) v5(87.77,55.19) v5(87.82,53.84) v5(87.87,175.2) v5(88.02,189.22) v5(88,172.16) v5(87.97,166.31) v5(87.97,165.22) v5(87.97,164.08) v5(87.97,154.81) v5(88,152.73) v5(88.36,77.09) v5(88.45,73.12) v5(88.45,70.68) v5(88.94,181.83) v5(88.94,181.33) v5(88.99,184.48) v5(88.99,183.71) v5(88.99,183.21) v5(88.99,182.44) v5(89.24,184.09) v5(89.24,182.82) v5(89.24,55.11) v5(89.32,181.58) v5(89.5,189.11) v5(89.5,184.48) v5(89.5,183.71) v5(89.5,183.21) v5(89.5,182.44) v5(89.52,124.53) v5(89.6,146.07) v5(89.67,181.83) v5(89.67,181.33) v5(89.66,75.19) v5(89.74,48.95) v5(89.74,45.95) v5(89.74,44.15) v5(89.74,42.35) v5(90,165.55) v5(90,164.79) v5(90,164.28) v5(90,163.52) v5(90.03,54.71) v5(90.02,52.65) v5(90.02,38.05) v5(90.21,181.83) v5(90.21,181.33) v5(90.21,178.02) v5(90.21,177.52) v5(90.16,124.53) v5(90.26,165.17) v5(90.26,163.9) v5(90.32,161.78) v5(90.54,176.98) v5(90.54,176.25) v5(90.51,165.55) v5(90.51,164.79) v5(90.51,164.28) v5(90.51,163.52) v5(90.55,78.95) v5(90.59,181.58) v5(90.59,177.77) v5(90.56,71.55) v5(90.79,176.6) v5(90.79,124.53) v5(90.79,76.09) v5(90.94,181.83) v5(90.94,178.02) v5(90.94,177.52) v5(91.02,189.11) v5(91.05,176.98) v5(91.05,176.25) v5(90.97,171.47) v5(90.97,170.73) v5(90.97,170.2) v5(90.97,169.46) v5(91.12,146.07) v5(91.22,171.09) v5(91.22,169.82) v5(91.17,31.57) v5(91.17,27.76) v5(91.3,29.28) v5(91.4,185.52) v5(91.4,185.01) v5(91.48,170.73) v5(91.48,170.2) v5(91.58,178.25) v5(91.58,177.52) v5(91.58,176.98) v5(91.58,176.25) v5(91.71,37.16) v5(91.68,27.76) v5(91.76,185.26) v5(91.83,177.87) v5(91.83,176.6) v5(92.01,171.14) v5(92.01,170.63) v5(92.14,185.52) v5(92.14,185.01) v5(92.09,178.25) v5(92.09,177.52) v5(92.09,176.98) v5(92.09,176.25) v5(92.19,31.19) v5(92.19,27.76) v5(92.39,170.89) v5(92.39,76.65) v5(92.44,41.45) v5(92.54,189.11) v5(92.54,77.29) v5(92.65,185.52) v5(92.65,185.01) v5(92.64,146.07) v5(92.62,49.85) v5(92.62,46.85) v5(92.62,45.05) v5(92.62,43.25) v5(92.72,36.16) v5(92.77,171.14) v5(93.03,185.26) v5(93.05,35.49) v5(93.05,34.85) v5(93.05,34.22) v5(93.15,187.32) v5(93.15,186.58) v5(93.41,186.94) v5(93.38,185.52) v5(93.38,185.01) v5(93.37,156.49) v5(93.66,187.32) v5(93.66,186.58) v5(93.74,19.9) v5(93.84,194.46) v5(93.92,185.52) v5(93.92,185.01) v5(93.94,35.24) v5(93.94,34.6) v5(93.97,188.92) v5(94.05,78.95) v5(94.3,185.26) v5(94.32,75.51) v5(94.37,156.99) v5(94.37,151.49) v5(94.47,195.12) v5(94.65,185.52) v5(94.65,185.01) v5(94.86,167.81) v5(94.86,167.3) v5(94.88,156.49) v5(94.88,154.49) v5(94.88,153.49) v5(95.24,167.56) v5(95.2,146.07) v5(95.4,189.11) v5(95.36,182.9) v5(95.36,182.39) v5(95.37,156.99) v5(95.37,150.49) v5(95.59,167.81) v5(95.59,167.3) v5(95.74,183.94) v5(95.74,183.43) v5(95.74,182.65) v5(95.67,76.55) v5(95.85,75.92) v5(95.88,152.49) v5(95.9,75.51) v5(96.13,183.69) v5(96.1,182.9) v5(96.1,182.39) v5(96.37,154.99) v5(96.48,183.94) v5(96.48,183.43) v5(96.58,187.88) v5(96.58,187.37) v5(96.63,182.7) v5(96.63,182.19) v5(96.68,196.06) v5(96.72,146.07) v5(96.81,161.82) v5(96.81,161.31) v5(96.92,189.11) v5(96.96,187.62) v5(97.01,182.44) v5(97.03,175.73) v5(97.03,175.33) v5(97.19,161.56) v5(97.21,38.21) v5(97.21,33.71) v5(97.21,28.21) v5(97.32,187.88) v5(97.32,187.37) v5(97.27,129.94) v5(97.28,40.01) v5(97.37,182.7) v5(97.37,182.19) v5(97.37,153.99) v5(97.4,125.29) v5(97.55,166.47) v5(97.52,165.96) v5(97.49,71.55) v5(97.57,169.26) v5(97.57,168.52) v5(97.57,167.97) v5(97.57,167.23) v5(97.57,161.82) v5(97.57,161.31) v5(97.83,168.88) v5(97.83,167.58) v5(97.85,187.88) v5(97.85,187.37) v5(97.9,166.21) v5(98.03,129.94) v5(98.08,169.24) v5(98.08,168.52) v5(98.08,167.94) v5(98.08,167.23) v5(98.08,24.83) v5(98.23,187.62) v5(98.21,161.82) v5(98.21,161.31) v5(98.24,146.07) v5(98.16,125.29) v5(98.26,166.47) v5(98.26,165.96) v5(98.26,12.32) v5(98.26,11.45) v5(98.44,189.11) v5(98.46,130.63) v5(98.45,16.67) v5(98.59,187.88) v5(98.59,187.37) v5(98.59,161.56) v5(98.58,24.83) v5(99.03,172.93) v5(98.97,161.82) v5(98.97,161.31) v5(99.12,187.74) v5(99.12,187.23) v5(99.08,24.83) v5(99.43,177.73) v5(99.5,187.49) v5(99.48,162.07) v5(99.48,161.56) v5(99.48,131.52) v5(99.58,40.08) v5(99.58,24.83) v5(99.94,193.21) v5(99.94,188.92) v5(99.86,187.74) v5(99.86,187.23) v5(99.86,161.82) v5(100.08,24.83) v5(100.24,162.07) v5(100.24,161.56) v5(100.19,14.9) v5(100.31,195.74) v5(100.35,17.97) v5(100.58,24.83) v5(100.7,182.6) v5(100.7,182.09) v5(100.77,193.16) v5(100.8,146.07) v5(101.08,182.34) v5(101.08,40.08) v5(101.08,24.83) v5(101.23,167.81) v5(101.23,167.3) v5(101.21,129.61) v5(101.21,129.23) v5(101.16,37.94) v5(101.16,37.43) v5(101.16,36.92) v5(101.16,34.61) v5(101.16,34.11) v5(101.16,31.31) v5(101.16,30.81) v5(101.16,30.3) v5(101.16,27.99) v5(101.16,27.48) v5(101.16,26.97) v5(101.32,189.14) v5(101.36,166.77) v5(101.36,166.26) v5(101.38,42.16) v5(101.43,33.73) v5(101.43,13.89) v5(101.46,187.74) v5(101.46,187.23) v5(101.46,182.6) v5(101.46,182.09) v5(101.46,85.3) v5(101.46,84.26) v5(101.46,83.27) v5(101.46,82.23) v5(101.46,14.63) v5(101.61,167.56) v5(101.59,114.75) v5(101.59,88.04) v5(101.58,24.83) v5(101.74,166.52) v5(101.84,187.49) v5(101.83,175.73) v5(101.97,167.81) v5(101.97,167.3) v5(102.09,166.77) v5(102.09,166.26) v5(102.09,87.53) v5(102.08,24.83) v5(102.2,187.74) v5(102.2,187.23) v5(102.22,88.8) v5(102.2,42.16) v5(102.32,146.07) v5(102.45,80.59) v5(102.53,86.11) v5(102.54,41.65) v5(102.58,40.08) v5(102.58,24.83) v5(102.7,167.58) v5(102.7,166.85) v5(102.7,166.31) v5(102.7,165.58) v5(102.7,165.04) v5(102.7,164.31) v5(102.73,130.5) v5(102.82,189.11) v5(102.96,167.2) v5(102.96,165.93) v5(102.96,164.66) v5(102.98,129.61) v5(103.08,24.83) v5(103.21,167.58) v5(103.21,166.85) v5(103.21,166.31) v5(103.21,165.58) v5(103.21,165.04) v5(103.21,164.31) v5(103.41,183.33) v5(103.47,42.16) v5(103.62,188.1) v5(103.58,24.83) v5(103.8,183.59) v5(103.84,146.07) v5(103.77,84.87) v5(103.95,158.69) v5(103.87,88.93) v5(104.13,92.23) v5(104.08,40.08) v5(104.08,24.83) v5(104.15,183.84) v5(104.15,183.33) v5(104.15,84.87) v5(104.38,182.82) v5(104.38,90.07) v5(104.38,89.31) v5(104.38,88.17) v5(104.51,85.63) v5(104.51,85.25) v5(104.51,84.87) v5(104.51,84.46) v5(104.53,84.05) v5(104.51,37.94) v5(104.51,37.43) v5(104.51,36.92) v5(104.51,34.61) v5(104.51,34.11) v5(104.51,33.6) v5(104.51,31.31) v5(104.51,30.81) v5(104.51,30.3) v5(104.51,27.99) v5(104.51,27.48) v5(104.51,26.97) v5(104.63,90.58) v5(104.58,24.83) v5(104.61,12.32) v5(104.61,11.45) v5(104.76,88.93) v5(104.76,86.77) v5(104.76,82.96) v5(104.89,91.73) v5(104.89,84.87) v5(105.02,188.1) v5(105.07,176.63) v5(105.07,176.12) v5(105.08,24.83) v5(105.24,184.45) v5(105.24,84.87) v5(105.32,16) v5(105.45,176.37) v5(105.41,107.16) v5(105.39,106.65) v5(105.5,186.56) v5(105.45,155.97) v5(105.5,17.75) v5(105.58,24.83) v5(105.73,187.45) v5(105.78,188.92) v5(105.8,176.63) v5(105.8,176.12) v5(105.98,186.56) v5(106.08,24.83) v5(106.08,16.68) v5(106.16,89.44) v5(106.18,15.11) v5(106.34,176.63) v5(106.34,176.12) v5(106.42,188.1) v5(106.41,184.45) v5(106.44,167.58) v5(106.44,166.85) v5(106.44,166.31) v5(106.44,165.58) v5(106.44,165.04) v5(106.44,164.31) v5(106.46,13) v5(106.51,12.24) v5(106.51,11.48) v5(106.64,169.08) v5(106.64,168.57) v5(106.58,24.83) v5(106.72,176.37) v5(106.69,167.2) v5(106.69,165.93) v5(106.69,164.66) v5(106.74,157.04) v5(106.84,185.49) v5(106.95,167.58) v5(106.95,166.85) v5(106.95,166.31) v5(106.95,165.58) v5(106.95,165.04) v5(106.95,164.31) v5(106.89,145.16) v5(107.02,168.83) v5(107.1,179.48) v5(107.07,176.63) v5(107.07,176.12) v5(107.08,24.83) v5(107.12,15.11) v5(107.2,189.11) v5(107.17,173.68) v5(107.17,173.17) v5(107.22,14.07) v5(107.38,169.08) v5(107.38,168.57) v5(107.4,85.68) v5(107.4,84.16) v5(107.43,83.1) v5(107.43,82.6) v5(107.38,15.79) v5(107.58,184.45) v5(107.56,173.43) v5(107.58,24.83) v5(107.68,176.7) v5(107.71,18.16) v5(107.8,107.64) v5(107.81,90.46) v5(107.91,173.68) v5(107.91,173.17) v5(107.94,169.08) v5(107.94,168.57) v5(107.92,146.07) v5(108.01,176.45) v5(108.06,159.99) v5(108.32,168.83) v5(108.27,14.5) v5(108.37,176.7) v5(108.37,176.19) v5(108.38,24.91) v5(108.47,173.68) v5(108.47,173.17) v5(108.46,32.71) v5(108.46,29.71) v5(108.46,28.21) v5(108.46,26.21) v5(108.46,25.71) v5(108.62,148.1) v5(108.72,189.11) v5(108.67,169.08) v5(108.67,168.57) v5(108.72,156.56) v5(108.72,152.29) v5(108.9,176.7) v5(108.9,176.19) v5(108.85,173.43) v5(108.88,166.49) v5(108.93,162.83) v5(108.89,111.45) v5(108.89,110.05) v5(108.89,108.66) v5(109.21,173.68) v5(109.21,173.17) v5(109.23,169.08) v5(109.23,168.57) v5(109.28,176.45) v5(109.33,39.36) v5(109.44,146.07) v5(109.38,38.55) v5(109.41,37.69) v5(109.64,176.19) v5(109.61,168.83) v5(109.76,105.86) v5(109.78,104.47) v5(109.78,103.07) v5(109.82,16) v5(109.84,13.43) v5(109.87,172.69) v5(109.97,169.08) v5(109.97,165.93) v5(109.97,164.41) v5(109.97,162.89) v5(110.03,107.28) v5(110.02,36.14) v5(110.11,37.4) v5(110.24,189.11) v5(110.25,34.49) v5(110.3,176.5) v5(110.53,169.08) v5(110.53,168.57) v5(110.63,172.69) v5(110.73,37.82) v5(110.83,18.13) v5(110.78,14.55) v5(110.91,168.83) v5(110.93,42.7) v5(111.06,176.5) v5(111.26,169.08) v5(111.26,168.57) v5(111.49,188.92) v5(111.85,42.26) v5(111.9,37.94) v5(111.9,37.18) v5(112.3,161.12) v5(112.3,159.6) v5(112.3,158.08) v5(112.3,155.92) v5(112.3,154.4) v5(112.3,152.88) v5(112.3,150.72) v5(112.3,149.2) v5(112.3,147.68) v5(112.53,100.22) v5(112.64,98.62) v5(112.64,98.12) v5(112.81,96.77) v5(113.04,94.36) v5(113.07,91.82) v7(64.91,167.44) v7(65.26,167.41) v7(65.52,171.13) v7(65.52,163.78) v7(65.83,165.8) v7(65.84,161.75) v7(65.8,158.96) v7(65.88,170.28) v7(65.88,169.15) v7(65.88,158.4) v7(65.88,157.27) v7(66.16,163.77) v7(66.45,170.85) v7(66.45,169.72) v7(66.45,168.58) v7(66.45,167.45) v7(66.45,166.32) v7(66.45,165.19) v7(66.45,164.06) v7(66.45,162.36) v7(66.45,161.23) v7(66.45,160.1) v7(66.45,158.96) v7(66.45,157.83) v7(66.45,156.7) v7(66.45,163.49) v7(66.73,163.77) v7(67.01,170.85) v7(67.01,169.15) v7(67.01,166.89) v7(67.01,165.18) v7(67.01,164.62) v7(67.01,164.06) v7(67.01,163.49) v7(67.01,162.93) v7(67.01,162.36) v7(67.01,160.66) v7(67.01,158.4) v7(67.01,156.7) v7(67.29,170.57) v7(67.29,170) v7(67.29,168.3) v7(67.29,167.17) v7(67.29,166.6) v7(67.3,165.47) v7(67.29,164.34) v7(67.29,163.77) v7(67.29,163.21) v7(67.3,162.08) v7(67.29,160.94) v7(67.29,160.38) v7(67.29,159.25) v7(67.29,157.55) v7(67.29,156.98) v7(67.58,168.58) v7(67.58,168.02) v7(67.58,166.89) v7(67.58,165.19) v7(67.58,164.06) v7(67.58,163.49) v7(67.58,162.36) v7(67.58,160.66) v7(67.58,159.53) v7(67.58,158.96) v7(67.86,167.17) v7(67.86,165.47) v7(67.86,164.34) v7(67.86,163.21) v7(67.86,162.08) v7(67.86,160.38) v7(68.14,170.85) v7(68.14,169.15) v7(68.14,158.4) v7(68.14,156.7) v7(68.06,154.1) v7(68.3,154.39) v7(68.43,168.3) v7(68.43,167.17) v7(68.43,166.04) v7(68.43,165.47) v7(68.43,164.34) v7(68.43,163.21) v7(68.43,162.08) v7(68.43,161.51) v7(68.43,160.38) v7(68.43,159.25) v7(68.54,154.63) v7(68.71,170.28) v7(68.71,169.15) v7(68.71,158.4) v7(68.71,157.27) v7(68.87,154.99) v7(69.27,170.85) v7(69.27,169.72) v7(69.25,168.06) v7(69.25,167.11) v7(69.25,166.16) v7(69.25,165.2) v7(69.25,162.34) v7(69.25,161.39) v7(69.25,160.44) v7(69.25,159.49) v7(69.28,156.7) v7(69.53,167.59) v7(69.53,166.63) v7(69.53,165.68) v7(69.53,163.77) v7(69.53,161.87) v7(69.53,160.92) v7(69.53,159.96) v7(69.56,170) v7(69.56,168.87) v7(69.56,158.68) v7(69.84,169.72) v7(69.81,168.06) v7(69.81,167.11) v7(69.81,166.16) v7(69.81,164.25) v7(69.81,163.3) v7(69.81,162.34) v7(69.81,161.39) v7(69.81,160.44) v7(69.81,159.49) v7(69.84,157.83) v7(70.08,167.59) v7(70.08,164.73) v7(70.08,163.77) v7(70.08,161.87) v7(70.08,159.96) v7(70.41,170.85) v7(70.41,168.58) v7(70.36,168.06) v7(70.36,164.25) v7(70.36,163.3) v7(70.36,160.44) v7(70.36,159.49) v7(70.41,158.96) v7(70.63,167.59) v7(70.63,162.82) v7(70.65,171.17) v7(70.69,170.57) v7(70.69,170) v7(70.69,169.43) v7(70.69,168.87) v7(70.69,158.68) v7(70.69,158.12) v7(70.69,157.55) v7(70.69,156.98) v7(70.91,168.06) v7(70.91,164.25) v7(70.91,159.49) v7(70.97,170.28) v7(70.97,169.72) v7(70.97,157.83) v7(70.97,157.27) v7(71.18,167.59) v7(71.18,165.68) v7(71.26,168.87) v7(71.26,158.68) v7(71.26,157.55) v7(71.54,170.85) v7(71.54,169.15) v7(71.54,168.58) v7(71.46,166.16) v7(71.54,158.96) v7(71.54,156.7) v7(71.73,160.92) v7(72.01,162.34) v7(72.01,159.49) v7(72.1,169.72) v7(72.1,168.58) v7(72.1,158.4) v7(72.1,157.83) v7(72.28,160.92) v7(72.39,170) v7(72.39,168.87) v7(72.39,158.68) v7(72.39,157.55) v7(72.56,162.34) v7(72.55,159.49) v7(72.67,170.85) v7(72.67,168.58) v7(72.67,157.83) v7(72.67,156.7) v7(72.95,168.87) v7(73.24,168.58) v7(73.24,158.96) v7(73.24,158.4) v7(73.24,157.83) v7(73.24,157.27) v7(73.27,171.47) v7(73.52,170) v7(73.52,168.87) v7(73.52,158.68) v7(73.52,158.12) v7(73.52,157.55) v7(73.52,155.78) v7(73.66,168.06) v7(73.66,167.11) v7(73.8,170.85) v7(73.8,169.72) v7(73.8,157.83) v7(73.8,156.7) v7(73.93,167.59) v7(74.08,171.77) v7(74.08,168.87) v7(74.12,158.12) v7(74.08,157.55) v7(74.37,157.83) v7(74.37,157.27) v7(74.48,167.59) v7(74.48,163.77) v7(74.69,171.17) v7(74.65,170) v7(74.93,158.4) v7(74.93,156.7) v7(75.03,167.59) v7(75.03,159.96) v7(75.22,158.68) v7(75.22,158.12) v7(75.22,157.55) v7(75.31,168.06) v7(75.31,163.3) v7(75.5,170.85) v7(75.5,168.58) v7(75.5,157.83) v7(75.58,167.59) v7(75.58,165.68) v7(75.78,170) v7(75.78,157.55) v7(75.86,168.06) v7(76.07,170.85) v7(76.07,168.58) v7(76.13,167.59) v7(76.07,158.96) v7(76.07,156.7) v7(76.35,170.57) v7(76.35,168.87) v7(76.41,168.06) v7(76.41,167.11) v7(76.41,159.49) v7(76.63,170.28) v7(76.63,168.58) v7(76.63,157.83) v7(76.63,157.27) v7(76.91,170) v7(76.91,168.87) v7(76.91,158.68) v7(76.91,157.55) v7(76.96,168.06) v7(76.96,166.16) v7(76.96,165.2) v7(76.96,163.3) v7(76.96,162.34) v7(76.96,159.49) v7(77.2,170.28) v7(77.2,168.58) v7(77.23,167.59) v7(77.23,164.73) v7(77.23,162.82) v7(77.2,157.83) v7(77.2,156.7) v7(77.2,156.06) v7(77.48,170.57) v7(77.48,168.87) v7(77.51,168.06) v7(77.51,167.11) v7(77.51,166.16) v7(77.51,165.2) v7(77.51,164.25) v7(77.51,163.3) v7(77.51,162.34) v7(77.51,161.39) v7(77.76,170.28) v7(77.76,168.58) v7(77.78,166.63) v7(77.79,165.68) v7(77.78,163.77) v7(77.78,162.82) v7(77.78,160.92) v7(78.05,171.77) v7(78.05,170) v7(78.05,169.43) v7(78.05,168.87) v7(78.05,158.68) v7(78.05,158.12) v7(78.05,157.55) v7(78.33,169.72) v7(78.33,167.45) v7(78.33,166.32) v7(78.33,164.62) v7(78.33,164.06) v7(78.33,163.49) v7(78.33,160.1) v7(78.33,159.53) v7(78.33,158.96) v7(78.33,156.7) v7(78.33,156.06) v7(78.61,170.57) v7(78.61,165.47) v7(78.61,164.34) v7(78.61,163.77) v7(78.61,160.38) v7(78.61,159.81) v7(78.61,158.68) v7(78.9,170.28) v7(78.9,164.06) v7(78.9,161.23) v7(78.9,160.66) v7(78.9,157.83) v7(78.9,157.27) v7(79.18,165.47) v7(79.18,161.51) v7(79.18,159.81) v7(79.46,165.19) v7(79.46,164.06) v7(79.46,162.93) v7(79.46,161.79) v7(79.46,160.66) v7(79.46,160.1) v7(79.46,158.96) v7(79.46,156.7) v7(79.74,168.87) v7(79.74,168.3) v7(79.74,167.74) v7(79.74,165.47) v7(79.74,164.91) v7(79.74,164.34) v7(79.74,163.77) v7(79.74,161.51) v7(79.74,160.94) v7(79.74,160.38) v7(79.74,159.81) v7(79.74,159.25) v7(79.74,158.12) v7(79.74,157.55) v7(80.03,169.15) v7(80.03,168.02) v7(80.03,167.45) v7(80.03,165.75) v7(80.03,165.19) v7(80.03,164.62) v7(80.03,164.06) v7(80.03,163.49) v7(80.03,161.79) v7(80.03,161.23) v7(80.03,160.66) v7(80.03,160.1) v7(80.03,159.53) v7(80.03,158.4) v7(80.03,157.27) v7(80.31,167.17) v7(80.31,164.34) v7(80.31,161.51) v7(80.31,160.38) v7(80.31,159.25) v7(80.31,158.12) v7(80.31,156.98) v7(80.91,168.83) v7(80.88,168.3) v7(80.88,156.42) v7(81.16,171.41) v7(81.16,170.28) v7(81.23,158.96) v7(81.16,158.39) v7(81.16,156.13) v7(81.52,171.13) v7(81.52,170.57) v7(81.52,167.74) v7(81.52,163.21) v7(81.52,162.64) v7(81.52,156.98) v7(99.83,174.53) v8(64.91,167.44) v8(65.26,167.41) v8(65.52,171.13) v8(65.52,163.78) v8(65.83,165.8) v8(65.84,161.75) v8(65.8,158.96) v8(65.88,170.28) v8(65.88,169.15) v8(65.88,158.4) v8(65.88,157.27) v8(66.16,163.77) v8(66.45,170.85) v8(66.45,169.72) v8(66.45,168.58) v8(66.45,167.45) v8(66.45,166.32) v8(66.45,165.19) v8(66.45,164.06) v8(66.45,162.36) v8(66.45,161.23) v8(66.45,160.1) v8(66.45,158.96) v8(66.45,157.83) v8(66.45,156.7) v8(66.45,163.49) v8(66.73,163.77) v8(67.01,170.85) v8(67.01,169.15) v8(67.01,166.89) v8(67.01,165.18) v8(67.01,164.62) v8(67.01,164.06) v8(67.01,163.49) v8(67.01,162.93) v8(67.01,162.36) v8(67.01,160.66) v8(67.01,158.4) v8(67.01,156.7) v8(67.29,170.57) v8(67.29,170) v8(67.29,168.3) v8(67.29,167.17) v8(67.29,166.6) v8(67.3,165.47) v8(67.29,164.34) v8(67.29,163.77) v8(67.29,163.21) v8(67.3,162.08) v8(67.29,160.94) v8(67.29,160.38) v8(67.29,159.25) v8(67.29,157.55) v8(67.29,156.98) v8(67.58,168.58) v8(67.58,168.02) v8(67.58,166.89) v8(67.58,165.19) v8(67.58,164.06) v8(67.58,163.49) v8(67.58,162.36) v8(67.58,160.66) v8(67.58,159.53) v8(67.58,158.96) v8(67.86,167.17) v8(67.86,165.47) v8(67.86,164.34) v8(67.86,163.21) v8(67.86,162.08) v8(67.86,160.38) v8(68.14,170.85) v8(68.14,169.15) v8(68.14,158.4) v8(68.14,156.7) v8(68.06,154.1) v8(68.3,154.39) v8(68.43,168.3) v8(68.43,167.17) v8(68.43,166.04) v8(68.43,165.47) v8(68.43,164.34) v8(68.43,163.21) v8(68.43,162.08) v8(68.43,161.51) v8(68.43,160.38) v8(68.43,159.25) v8(68.54,154.63) v8(68.71,170.28) v8(68.71,169.15) v8(68.71,158.4) v8(68.71,157.27) v8(68.87,154.99) v8(69.27,170.85) v8(69.27,169.72) v8(69.25,168.06) v8(69.25,167.11) v8(69.25,166.16) v8(69.25,165.2) v8(69.25,162.34) v8(69.25,161.39) v8(69.25,160.44) v8(69.25,159.49) v8(69.28,156.7) v8(69.53,167.59) v8(69.53,166.63) v8(69.53,165.68) v8(69.53,163.77) v8(69.53,161.87) v8(69.53,160.92) v8(69.53,159.96) v8(69.56,170) v8(69.56,168.87) v8(69.56,158.68) v8(69.84,169.72) v8(69.81,168.06) v8(69.81,167.11) v8(69.81,166.16) v8(69.81,164.25) v8(69.81,163.3) v8(69.81,162.34) v8(69.81,161.39) v8(69.81,160.44) v8(69.81,159.49) v8(69.84,157.83) v8(70.08,167.59) v8(70.08,164.73) v8(70.08,163.77) v8(70.08,161.87) v8(70.08,159.96) v8(70.41,170.85) v8(70.41,168.58) v8(70.36,168.06) v8(70.36,164.25) v8(70.36,163.3) v8(70.36,160.44) v8(70.36,159.49) v8(70.41,158.96) v8(70.63,167.59) v8(70.63,162.82) v8(70.65,171.17) v8(70.69,170.57) v8(70.69,170) v8(70.69,169.43) v8(70.69,168.87) v8(70.69,158.68) v8(70.69,158.12) v8(70.69,157.55) v8(70.69,156.98) v8(70.91,168.06) v8(70.91,164.25) v8(70.91,159.49) v8(70.97,170.28) v8(70.97,169.72) v8(70.97,157.83) v8(70.97,157.27) v8(71.18,167.59) v8(71.18,165.68) v8(71.26,168.87) v8(71.26,158.68) v8(71.26,157.55) v8(71.54,170.85) v8(71.54,168.58) v8(71.46,166.16) v8(71.54,158.96) v8(71.54,156.7) v8(71.73,160.92) v8(72.01,162.34) v8(72.01,159.49) v8(72.1,169.72) v8(72.1,168.58) v8(72.1,157.83) v8(72.28,160.92) v8(72.39,170) v8(72.39,168.87) v8(72.39,158.68) v8(72.39,157.55) v8(72.56,162.34) v8(72.55,159.49) v8(72.67,170.85) v8(72.67,168.58) v8(72.67,157.83) v8(72.67,156.7) v8(72.95,168.87) v8(73.24,168.58) v8(73.24,157.27) v8(73.27,171.47) v8(73.52,170) v8(73.52,168.87) v8(73.52,158.12) v8(73.52,157.55) v8(73.52,155.78) v8(73.66,168.06) v8(73.66,167.11) v8(73.8,170.85) v8(73.8,169.72) v8(73.8,157.83) v8(73.8,156.7) v8(73.93,167.59) v8(74.08,171.77) v8(74.08,168.87) v8(74.08,158.68) v8(74.08,157.55) v8(74.21,159.49) v8(74.37,157.83) v8(74.37,157.27) v8(74.48,167.59) v8(74.48,163.77) v8(74.69,171.17) v8(74.65,170) v8(74.93,158.4) v8(74.93,156.7) v8(75.03,167.59) v8(75.03,159.96) v8(75.22,158.68) v8(75.22,158.12) v8(75.22,157.55) v8(75.31,168.06) v8(75.31,163.3) v8(75.5,170.85) v8(75.5,168.58) v8(75.5,157.83) v8(75.58,167.59) v8(75.58,165.68) v8(75.78,170) v8(75.78,157.55) v8(75.86,168.06) v8(75.86,159.49) v8(76.07,170.85) v8(76.07,168.58) v8(76.13,167.59) v8(76.13,161.87) v8(76.07,158.96) v8(76.07,156.7) v8(76.35,170.57) v8(76.35,168.87) v8(76.41,168.06) v8(76.41,167.11) v8(76.41,159.49) v8(76.63,170.28) v8(76.63,168.58) v8(76.63,157.83) v8(76.63,157.27) v8(76.68,166.63) v8(76.68,162.82) v8(76.68,159.96) v8(76.91,170) v8(76.91,168.87) v8(76.91,158.68) v8(76.91,157.55) v8(76.96,168.06) v8(76.96,166.16) v8(76.96,165.2) v8(76.96,163.3) v8(76.96,162.34) v8(76.96,159.49) v8(77.2,170.28) v8(77.2,168.58) v8(77.23,167.59) v8(77.23,164.73) v8(77.23,162.82) v8(77.2,157.83) v8(77.2,156.7) v8(77.2,156.06) v8(77.48,170.57) v8(77.48,168.87) v8(77.51,168.06) v8(77.51,167.11) v8(77.51,166.16) v8(77.51,165.2) v8(77.51,164.25) v8(77.51,163.3) v8(77.51,162.34) v8(77.51,161.39) v8(77.51,159.49) v8(77.76,170.28) v8(77.76,168.58) v8(77.78,166.63) v8(77.79,165.68) v8(77.78,163.77) v8(77.78,162.82) v8(77.78,160.92) v8(78.05,171.77) v8(78.05,170) v8(78.05,169.43) v8(78.05,168.87) v8(78.05,158.68) v8(78.05,158.12) v8(78.05,157.55) v8(78.33,169.72) v8(78.33,167.45) v8(78.33,166.32) v8(78.33,164.62) v8(78.33,164.06) v8(78.33,163.49) v8(78.33,160.1) v8(78.33,159.53) v8(78.33,158.96) v8(78.33,156.7) v8(78.33,156.06) v8(78.61,170.57) v8(78.61,165.47) v8(78.61,164.34) v8(78.61,163.77) v8(78.61,161.51) v8(78.61,160.94) v8(78.61,160.38) v8(78.61,159.81) v8(78.61,158.68) v8(78.9,170.28) v8(78.9,164.06) v8(78.9,161.23) v8(78.9,160.66) v8(78.9,157.83) v8(78.9,157.27) v8(79.18,165.47) v8(79.18,161.51) v8(79.18,159.81) v8(79.46,165.19) v8(79.46,164.06) v8(79.46,162.93) v8(79.46,161.79) v8(79.46,160.66) v8(79.46,158.96) v8(79.46,156.7) v8(79.74,168.87) v8(79.74,168.3) v8(79.74,167.74) v8(79.74,165.47) v8(79.74,164.91) v8(79.74,164.34) v8(79.74,163.77) v8(79.74,161.51) v8(79.74,160.94) v8(79.74,160.38) v8(79.74,159.81) v8(79.74,159.25) v8(79.74,158.12) v8(79.74,157.55) v8(80.03,169.15) v8(80.03,168.02) v8(80.03,167.45) v8(80.03,165.75) v8(80.03,165.19) v8(80.03,164.62) v8(80.03,164.06) v8(80.03,163.49) v8(80.03,161.79) v8(80.03,161.23) v8(80.03,160.66) v8(80.03,160.1) v8(80.03,159.53) v8(80.03,158.4) v8(80.03,157.27) v8(80.31,167.17) v8(80.31,164.34) v8(80.31,161.51) v8(80.31,160.38) v8(80.31,159.81) v8(80.31,159.25) v8(80.31,158.12) v8(80.31,156.98) v8(80.91,168.83) v8(80.88,168.3) v8(80.88,156.42) v8(81.16,171.41) v8(81.16,170.28) v8(81.23,158.96) v8(81.16,158.39) v8(81.16,156.13) v8(81.52,171.13) v8(81.52,170.57) v8(81.52,167.74) v8(81.52,163.21) v8(81.52,162.64) v8(81.52,156.98) v8(97.03,177.33) v8(97.03,176.93) v8(97.03,173.73) v8(97.03,173.33) v8(97.43,177.73) v8(97.43,172.93) v8(97.83,177.73) v8(97.83,172.93) v8(99.03,177.73) v8(99.03,175.73) v8(99.43,175.33) v8(99.43,172.93) v8(99.83,177.73) v8(99.83,174.53) v8(100.23,177.73) v8(100.23,177.33) v8(100.63,172.93) v8(100.63,172.53) v8(101.83,176.93) v8(101.83,176.53) v8(101.83,176.13) v8(101.83,174.13) v8(102.23,174.13) v9(36.82,177.29) v9(37.58,177.85) v9(38.21,147.47) v9(38.34,177.29) v9(38.26,172.37) v9(38.98,171.65) v9(39.1,177.85) v9(39.18,175.97) v9(39.48,171.65) v9(39.48,151.66) v9(39.98,171.65) v9(40.48,171.65) v9(41.03,175.46) v9(42.18,172.87) v9(42.45,173.63) v9(42.48,172.23) v9(42.53,168.22) v9(42.79,155.77) v9(43.55,158.57) v9(44.06,175.59) v9(44.18,169.87) v9(44.56,155.65) v9(45.58,163.47) v9(45.83,159.53) v9(46.21,179.27) v9(46.75,171.27) v9(46.72,147.59) v9(46.98,166.26) v9(46.98,153.82) v9(47.05,171.9) v9(47.1,150.26) v9(47.23,169.44) v9(47.23,161.95) v9(47.64,172.92) v9(48.12,167.53) v9(49.19,157.93) v9(49.39,181.55) v9(49.39,171.6) v9(50.28,156.23) v9(50.41,147.47) v9(51.14,175.71) v9(51.17,162.96) v9(51.29,167.03) v9(52.06,165.25) v9(52.18,158.26) v9(52.56,150.29) v9(52.69,146.96) v9(52.82,161.82) v9(53.58,167.66) v9(54.62,155.01) v9(54.98,171.85) v9(54.98,162.83) v9(55.23,154.78) v9(55.36,148.71) v9(55.74,171.42) v9(55.74,159.41) v9(55.86,165.66) v9(56.08,174.02) v9(56.76,175.31) v9(56.88,167.91) v9(56.86,164.66) v9(57.77,157.5) v9(58.03,181.68) v9(58.36,161.66) v9(59.3,157.5) v9(59.68,159.41) v9(60.31,163.22) v9(60.44,177.31) v9(60.44,168.04) v9(61.07,158.14) v9(61.71,166.01) v9(62.6,181.55) v9(62.72,161.46) v9(62.98,163.85) v9(63.49,168.04) v9(63.49,158.39) v9(64.25,183.08) v9(64.5,164.74) v9(67.04,147.21) v9(68.52,152.34) v9(69.81,161.74) v9(70.09,164.26) v9(70.22,167.43) v9(70.22,166.92) v9(70.45,160.35) v9(70.45,154.76) v9(70.45,154.25) v9(70.73,149.12) v9(70.93,161.23) v9(73.14,170.25) v9(73.65,170.25) v9(74.15,170.25) v9(74.23,159.53) v9(74.66,167.61) v9(75.04,158.64) v9(75.17,167.61) v9(75.42,161.51) v9(76.03,160.95) v9(76.18,167.59) v9(76.52,158.47) v9(77.05,160.95) v9(77,158.85) v9(77.56,160.95) v9(79.74,171.57) v9(79.82,156.97) v9(80.58,156.97) v9(82.1,161.03) v9(82.61,158.74) v9(84.44,176.07) v9(84.49,35) v9(84.82,176.32) v9(84.82,175.81) v9(85.13,38.04) v9(85.08,36.16) v9(86.55,108.28) v9(86.55,107.51) v9(86.5,107.01) v9(86.5,106.27) v9(86.49,84.59) v9(86.7,107.89) v9(86.7,106.62) v9(86.96,108.28) v9(86.96,107.51) v9(86.96,107.01) v9(86.96,106.24) v9(87.64,31.03) v9(87.64,30.23) v9(87.72,132.56) v9(87.72,131.62) v9(87.84,110.82) v9(87.84,110.05) v9(87.84,109.55) v9(87.84,108.78) v9(88.1,110.43) v9(88.1,109.16) v9(88.15,40.58) v9(88.2,17.44) v9(88.35,110.82) v9(88.35,110.05) v9(88.35,109.55) v9(88.35,108.78) v9(88.43,83.38) v9(88.86,48.89) v9(89.43,45.25) v9(89.65,171.93) v9(89.72,190.04) v9(89.7,48.94) v9(89.8,48.2) v9(89.8,47.7) v9(89.86,163.88) v9(89.85,26.94) v9(90.03,172.18) v9(90.01,43.58) v9(90.21,81.61) v9(90.26,189.91) v9(90.41,172.38) v9(90.41,171.93) v9(90.46,50.31) v9(90.53,41.51) v9(90.74,175.84) v9(90.74,175.13) v9(90.71,162.63) v9(90.69,51.51) v9(90.84,146.88) v9(90.84,146.12) v9(90.84,145.36) v9(90.87,40.63) v9(90.99,175.48) v9(90.99,52.27) v9(91.25,175.84) v9(91.25,175.13) v9(91.24,50.56) v9(91.43,186.35) v9(91.45,179.52) v9(91.45,178.76) v9(91.45,178.23) v9(91.45,177.52) v9(91.71,179.14) v9(91.71,177.87) v9(91.96,178.23) v9(91.96,177.52) v9(92.09,191.08) v9(92.06,19.78) v9(92.22,56.19) v9(92.23,41.76) v9(92.32,80.67) v9(92.42,143.45) v9(92.44,92.78) v9(92.49,190.95) v9(92.65,91.97) v9(92.71,146.36) v9(92.77,191.31) v9(92.82,186.28) v9(92.77,54.89) v9(92.95,179.09) v9(92.95,40.84) v9(93.05,190.37) v9(93.08,12.64) v9(93.23,148.28) v9(93.23,147.52) v9(93.2,92.78) v9(93.22,87.1) v9(93.22,86.45) v9(93.22,85.15) v9(93.18,81.58) v9(93.2,9.47) v9(93.33,179.34) v9(93.33,178.84) v9(93.41,189.15) v9(93.48,147.9) v9(93.46,146.38) v9(93.52,58.09) v9(93.54,54.88) v9(93.74,148.28) v9(93.74,147.52) v9(93.7,43.24) v9(93.84,179.5) v9(93.84,178.99) v9(93.84,146.38) v9(93.94,83.18) v9(94.04,84.45) v9(94.02,82.6) v9(93.97,11.5) v9(94.09,186.28) v9(94.07,80.67) v9(94.22,179.24) v9(94.22,146.38) v9(94.52,187.12) v9(94.5,143.45) v9(94.6,179.5) v9(94.6,146.38) v9(94.73,88.26) v9(94.79,45.43) v9(94.84,31.83) v9(94.98,11.37) v9(95.11,25.34) v9(95.16,187.02) v9(95.16,40.84) v9(95.16,40.3) v9(95.42,69.76) v9(95.47,56.77) v9(95.64,75.38) v9(95.64,32.63) v9(95.69,190.29) v9(95.87,192.12) v9(96.1,57.63) v9(96.24,190.21) v9(96.43,89.48) v9(96.53,141.8) v9(96.59,47.29) v9(96.75,49.59) v9(96.76,52.6) v9(96.84,45.16) v9(96.89,93.24) v9(96.89,76.12) v9(96.94,53.39) v9(97.01,178.76) v9(97.14,125.45) v9(97.19,179.24) v9(97.19,45.49) v9(97.24,33.43) v9(97.17,8.4) v9(97.27,178.13) v9(97.27,53.79) v9(97.32,11.27) v9(97.45,192.12) v9(97.4,73.99) v9(97.65,178.71) v9(97.65,92.65) v9(97.6,45.71) v9(97.7,141.8) v9(97.7,69.9) v9(97.73,68.37) v9(97.73,58.62) v9(97.78,170.3) v9(97.78,161.84) v9(97.78,161.34) v9(97.76,83.17) v9(97.8,72.82) v9(97.78,11.25) v9(97.93,140.91) v9(98.06,46.22) v9(98.23,177.44) v9(98.16,161.59) v9(98.16,99.77) v9(98.26,11.3) v9(98.39,9.95) v9(98.41,8.3) v9(98.54,179.7) v9(98.54,161.84) v9(98.54,161.34) v9(98.55,55.5) v9(98.67,26.56) v9(98.81,52.87) v9(98.87,141.8) v9(99.05,177.57) v9(99.15,192.12) v9(99.06,84.82) v9(99.17,26.56) v9(99.34,190.51) v9(99.3,171.75) v9(99.33,38.68) v9(99.35,190.16) v9(99.63,177.44) v9(99.58,140.91) v9(99.55,132.74) v9(99.58,10.51) v9(99.6,9.14) v9(99.6,8.43) v9(99.73,188.39) v9(100.04,141.8) v9(99.99,54.55) v9(100.06,181.45) v9(100.06,172.59) v9(100.14,40.46) v9(100.06,31.9) v9(100.09,12.01) v9(100.24,189.12) v9(100.24,187.34) v9(100.24,177.49) v9(100.16,52.6) v9(100.32,81.73) v9(100.32,35.1) v9(100.44,31.26) v9(100.44,9.77) v9(100.44,8.35) v9(100.49,131.39) v9(100.49,54.55) v9(100.52,10.92) v9(100.74,52.62) v9(100.82,161.95) v9(100.8,53.74) v9(100.8,53.11) v9(100.8,52.09) v9(100.8,51.58) v9(100.85,12.72) v9(100.98,188.69) v9(100.95,25.93) v9(101.14,190.51) v9(101.05,182.06) v9(101.08,149.45) v9(101.08,148.94) v9(101.08,145.51) v9(101.08,145.13) v9(101.1,140.91) v9(101.21,141.8) v9(101.16,67.2) v9(101.19,35.44) v9(101.21,11.55) v9(101.33,97.18) v9(101.33,96.67) v9(101.31,52.6) v9(101.32,32.52) v9(101.46,149.19) v9(101.46,145.33) v9(101.54,55.27) v9(101.54,11.88) v9(101.61,49.25) v9(101.59,10.38) v9(101.56,9.57) v9(101.65,115.84) v9(101.74,12.26) v9(101.84,149.45) v9(101.84,148.94) v9(101.84,145.51) v9(101.84,145.13) v9(101.81,52.6) v9(101.79,12.62) v9(102.02,191.36) v9(102.02,188.41) v9(102.04,187.34) v9(102.22,172.03) v9(102.19,83.31) v9(102.35,87.27) v9(102.37,141.8) v9(102.37,140.91) v9(102.4,84.86) v9(102.49,37.34) v9(102.62,34.42) v9(102.71,67.88) v9(102.68,66.41) v9(102.67,52.87) v9(102.67,52.37) v9(102.85,118.14) v9(102.85,105.2) v9(102.83,49.12) v9(102.94,190.51) v9(102.96,11.93) v9(103.11,171.75) v9(103.11,161.95) v9(103.14,83.1) v9(103.11,55.27) v9(103.21,189.12) v9(103.41,40.18) v9(103.41,39.14) v9(103.44,20.65) v9(103.47,191.26) v9(103.64,190.21) v9(103.62,49.75) v9(103.57,19.88) v9(103.67,21.41) v9(103.67,19.12) v9(103.8,55.27) v9(104,25.34) v9(104.23,66.28) v9(104.26,67.2) v9(104.25,11.22) v9(104.39,34.17) v9(104.84,191.18) v9(104.76,177.82) v9(104.84,25.06) v9(104.86,189.15) v9(104.89,11.91) v9(105.52,14.17) v9(105.71,67.88) v9(105.75,190.77) v9(105.81,66.97) v9(105.81,66.41) v9(105.85,189.61) v9(105.9,9.22) v9(106.11,84.6) v9(106.13,67.53) v9(106.23,55.24) v9(106.23,15.79) v9(106.26,55.72) v9(106.3,31.48) v9(106.31,30.93) v9(106.31,30.37) v9(106.31,29.89) v9(106.32,23.65) v9(106.34,10.94) v9(106.45,71.62) v9(106.56,55.49) v9(106.79,12.09) v9(106.89,55.72) v9(106.92,55.24) v9(107.05,7.95) v9(107.17,83.33) v9(107.3,190.01) v9(107.39,59.79) v9(107.48,76.25) v9(107.61,12.67) v9(107.71,31.52) v9(107.71,30.86) v9(107.68,30.04) v9(107.83,20.15) v9(107.78,13.86) v9(108.06,72.13) v9(108.06,70.1) v9(108.19,68.47) v9(108.32,21.65) v9(108.32,21.15) v9(108.32,20.65) v9(108.32,20.15) v9(108.83,22.15) v9(108.83,21.65) v9(108.83,21.15) v9(108.83,20.65) v9(108.9,13.51) v9(109.33,21.65) v9(109.33,21.15) v9(109.33,20.65) v9(109.83,23.15) v9(109.83,22.15) v9(109.83,21.65) v9(109.83,21.15) v9(109.83,20.65) v9(109.83,20.15) v9(110.02,175.66) v9(109.97,17.34) v9(110.37,175.92) v9(110.61,51.34) v9(110.73,176.17) v9(110.73,175.66) v9(110.76,59.82) v9(110.98,70.56) v9(110.98,69.79) v9(111.15,52.83) v9(111.24,193.11) v9(111.26,192.63) v9(111.26,67.38) v9(111.34,61.41) v9(111.34,60.8) v9(111.31,55.33) v9(116.19,86.89) v9(116.32,100.48) v10(36.82,177.29) v10(37.58,177.85) v10(38.21,147.47) v10(38.34,177.29) v10(38.26,172.37) v10(38.98,171.65) v10(39.1,177.85) v10(39.18,175.97) v10(39.48,171.65) v10(39.48,151.66) v10(39.98,171.65) v10(40.48,171.65) v10(41.03,175.46) v10(42.18,172.87) v10(42.45,173.63) v10(42.48,172.23) v10(42.53,168.22) v10(42.79,155.77) v10(43.55,158.57) v10(44.06,175.59) v10(44.18,169.87) v10(44.56,155.65) v10(45.58,163.47) v10(45.83,159.53) v10(46.21,179.27) v10(46.75,171.27) v10(46.72,147.59) v10(46.98,166.26) v10(46.98,153.82) v10(47.05,171.9) v10(47.1,150.26) v10(47.23,169.44) v10(47.23,161.95) v10(47.64,172.92) v10(48.12,167.53) v10(49.19,157.93) v10(49.39,181.55) v10(49.39,171.6) v10(50.28,156.23) v10(50.41,147.47) v10(51.14,175.71) v10(51.17,162.96) v10(51.29,167.03) v10(52.06,165.25) v10(52.18,158.26) v10(52.56,150.29) v10(52.69,146.96) v10(52.82,161.82) v10(53.58,167.66) v10(54.62,155.01) v10(54.98,171.85) v10(54.98,162.83) v10(55.23,154.78) v10(55.36,148.71) v10(55.74,171.42) v10(55.74,159.41) v10(55.86,165.66) v10(56.08,174.02) v10(56.76,175.31) v10(56.88,167.91) v10(56.86,164.66) v10(57.77,157.5) v10(58.03,181.68) v10(58.36,161.66) v10(59.3,157.5) v10(59.68,159.41) v10(60.31,163.22) v10(60.44,177.31) v10(60.44,168.04) v10(61.07,158.14) v10(61.71,166.01) v10(62.6,181.55) v10(62.72,161.46) v10(62.98,163.85) v10(63.49,168.04) v10(63.49,158.39) v10(64.25,183.08) v10(64.5,164.74) v10(67.04,147.21) v10(68.52,152.34) v10(69.81,161.74) v10(70.09,164.26) v10(70.22,167.43) v10(70.22,166.92) v10(70.45,160.35) v10(70.45,154.76) v10(70.45,154.25) v10(70.73,149.12) v10(70.93,161.23) v10(73.14,170.25) v10(73.65,170.25) v10(74.15,170.25) v10(74.23,159.53) v10(74.66,167.61) v10(75.04,158.64) v10(75.17,167.61) v10(75.42,161.51) v10(76.03,160.95) v10(76.18,167.59) v10(76.52,158.47) v10(77.05,160.95) v10(77,158.85) v10(77.56,160.95) v10(79.74,171.57) v10(79.82,156.97) v10(80.58,156.97) v10(82.1,161.03) v10(82.61,158.74) v10(84.44,176.07) v10(84.49,35) v10(84.82,176.32) v10(84.82,175.81) v10(85.13,38.04) v10(85.08,36.16) v10(86.55,108.28) v10(86.55,107.51) v10(86.5,107.01) v10(86.5,106.27) v10(86.49,84.59) v10(86.7,107.89) v10(86.7,106.62) v10(86.96,108.28) v10(86.96,107.51) v10(86.96,107.01) v10(86.96,106.24) v10(87.64,31.03) v10(87.64,30.23) v10(87.72,132.56) v10(87.72,131.62) v10(87.84,110.82) v10(87.84,110.05) v10(87.84,109.55) v10(87.84,108.78) v10(88.1,110.43) v10(88.1,109.16) v10(88.15,40.58) v10(88.2,17.44) v10(88.35,110.82) v10(88.35,110.05) v10(88.35,109.55) v10(88.35,108.78) v10(88.43,83.38) v10(88.86,48.89) v10(89.43,45.25) v10(89.65,171.93) v10(89.72,190.04) v10(89.7,48.94) v10(89.8,48.2) v10(89.8,47.7) v10(89.86,163.88) v10(89.85,26.94) v10(90.03,172.18) v10(90.01,43.58) v10(90.21,81.61) v10(90.26,189.91) v10(90.41,172.38) v10(90.41,171.93) v10(90.46,50.31) v10(90.53,41.51) v10(90.74,175.84) v10(90.74,175.13) v10(90.71,162.63) v10(90.69,51.51) v10(90.84,146.88) v10(90.84,146.12) v10(90.84,145.36) v10(90.87,40.63) v10(90.99,175.48) v10(90.99,52.27) v10(91.25,175.84) v10(91.25,175.13) v10(91.24,50.56) v10(91.43,186.35) v10(91.45,179.52) v10(91.45,178.76) v10(91.45,178.23) v10(91.45,177.52) v10(91.71,179.14) v10(91.71,177.87) v10(91.96,178.23) v10(91.96,177.52) v10(92.09,191.08) v10(92.06,19.78) v10(92.22,56.19) v10(92.23,41.76) v10(92.32,80.67) v10(92.42,143.45) v10(92.44,92.78) v10(92.49,190.95) v10(92.65,91.97) v10(92.71,146.36) v10(92.77,191.31) v10(92.82,186.28) v10(92.77,54.89) v10(92.95,179.09) v10(92.95,40.84) v10(93.05,190.37) v10(93.08,12.64) v10(93.23,148.28) v10(93.23,147.52) v10(93.2,92.78) v10(93.22,87.1) v10(93.22,86.45) v10(93.22,85.15) v10(93.18,81.58) v10(93.2,9.47) v10(93.33,179.34) v10(93.33,178.84) v10(93.41,189.15) v10(93.48,147.9) v10(93.46,146.38) v10(93.52,58.09) v10(93.54,54.88) v10(93.74,148.28) v10(93.74,147.52) v10(93.7,43.24) v10(93.84,179.5) v10(93.84,178.99) v10(93.84,146.38) v10(93.94,83.18) v10(94.04,84.45) v10(94.02,82.6) v10(93.97,11.5) v10(94.09,186.28) v10(94.07,80.67) v10(94.22,179.24) v10(94.22,146.38) v10(94.52,187.12) v10(94.5,143.45) v10(94.6,179.5) v10(94.6,146.38) v10(94.73,88.26) v10(94.79,45.43) v10(94.84,31.83) v10(94.98,11.37) v10(95.11,25.34) v10(95.16,187.02) v10(95.16,40.84) v10(95.16,40.3) v10(95.42,69.76) v10(95.47,56.77) v10(95.64,75.38) v10(95.64,32.63) v10(95.69,190.29) v10(95.87,192.12) v10(96.13,61.59) v10(96.1,57.63) v10(96.24,190.21) v10(96.53,141.8) v10(96.59,47.29) v10(96.75,49.59) v10(96.76,52.6) v10(96.84,45.16) v10(96.89,93.24) v10(96.89,90.7) v10(96.89,76.12) v10(96.94,53.39) v10(97.01,178.76) v10(97.14,125.45) v10(97.19,179.24) v10(97.19,45.49) v10(97.24,33.43) v10(97.17,8.4) v10(97.27,178.13) v10(97.27,53.79) v10(97.32,11.27) v10(97.45,192.12) v10(97.4,73.99) v10(97.65,178.71) v10(97.65,92.65) v10(97.6,45.71) v10(97.7,141.8) v10(97.7,69.9) v10(97.73,68.37) v10(97.73,58.62) v10(97.78,170.3) v10(97.78,161.84) v10(97.78,161.34) v10(97.76,83.17) v10(97.8,72.82) v10(97.78,11.25) v10(97.93,140.91) v10(98.03,87.78) v10(98.06,46.22) v10(98.23,177.44) v10(98.16,161.59) v10(98.16,99.77) v10(98.28,65.76) v10(98.26,11.3) v10(98.39,9.95) v10(98.41,8.3) v10(98.54,179.7) v10(98.54,161.84) v10(98.54,161.34) v10(98.55,55.5) v10(98.67,26.56) v10(98.79,65.5) v10(98.81,52.87) v10(98.87,141.8) v10(99.05,177.57) v10(99.15,192.12) v10(99.06,84.82) v10(99.17,26.56) v10(99.34,190.51) v10(99.3,171.75) v10(99.33,38.68) v10(99.35,190.16) v10(99.63,177.44) v10(99.58,140.91) v10(99.55,132.74) v10(99.58,10.51) v10(99.6,9.14) v10(99.6,8.43) v10(99.73,188.39) v10(100.04,141.8) v10(99.99,54.55) v10(100.06,181.45) v10(100.06,172.59) v10(100.14,40.46) v10(100.06,31.9) v10(100.09,12.01) v10(100.24,189.12) v10(100.24,187.34) v10(100.24,177.49) v10(100.16,52.6) v10(100.32,81.73) v10(100.32,35.1) v10(100.44,31.26) v10(100.42,13.84) v10(100.44,9.77) v10(100.44,8.35) v10(100.49,131.39) v10(100.49,54.55) v10(100.52,10.92) v10(100.74,52.62) v10(100.82,161.95) v10(100.8,53.74) v10(100.8,53.11) v10(100.8,52.09) v10(100.8,51.58) v10(100.85,12.72) v10(100.98,188.69) v10(100.95,25.93) v10(101.14,190.51) v10(101.05,182.06) v10(101.08,149.45) v10(101.08,148.94) v10(101.08,145.51) v10(101.08,145.13) v10(101.1,140.91) v10(101.21,141.8) v10(101.16,67.2) v10(101.19,35.44) v10(101.21,11.55) v10(101.33,97.18) v10(101.33,96.67) v10(101.31,52.6) v10(101.32,32.52) v10(101.46,149.19) v10(101.46,145.33) v10(101.54,55.27) v10(101.54,11.88) v10(101.61,49.25) v10(101.59,10.38) v10(101.56,9.57) v10(101.65,115.84) v10(101.74,12.26) v10(101.84,149.45) v10(101.84,148.94) v10(101.84,145.51) v10(101.84,145.13) v10(101.81,52.6) v10(101.79,12.62) v10(102.02,191.36) v10(102.02,188.41) v10(102.04,187.34) v10(102.22,172.03) v10(102.19,83.31) v10(102.16,77.18) v10(102.35,87.27) v10(102.37,141.8) v10(102.37,140.91) v10(102.4,84.86) v10(102.49,37.34) v10(102.62,34.42) v10(102.71,67.88) v10(102.68,66.41) v10(102.67,52.87) v10(102.67,52.37) v10(102.85,118.14) v10(102.85,105.2) v10(102.83,49.12) v10(102.94,190.51) v10(102.88,74.49) v10(102.96,11.93) v10(103.11,171.75) v10(103.11,161.95) v10(103.14,83.1) v10(103.11,55.27) v10(103.21,189.12) v10(103.41,40.18) v10(103.41,39.14) v10(103.44,20.65) v10(103.47,191.26) v10(103.64,190.21) v10(103.62,49.75) v10(103.57,19.88) v10(103.67,21.41) v10(103.67,19.12) v10(103.81,75.87) v10(103.8,55.27) v10(104,25.34) v10(104.23,66.28) v10(104.26,67.2) v10(104.25,11.22) v10(104.39,34.17) v10(104.84,191.18) v10(104.76,177.82) v10(104.76,30.42) v10(104.76,29.92) v10(104.76,29.41) v10(104.84,25.06) v10(104.86,189.15) v10(104.89,11.91) v10(105.27,30.68) v10(105.27,30.17) v10(105.27,29.66) v10(105.27,29.15) v10(105.27,28.65) v10(105.52,14.17) v10(105.71,67.88) v10(105.75,190.77) v10(105.8,75.76) v10(105.81,66.97) v10(105.81,66.41) v10(105.85,189.61) v10(105.9,9.22) v10(106.11,84.6) v10(106.13,67.53) v10(106.23,55.24) v10(106.23,15.79) v10(106.26,55.72) v10(106.32,23.65) v10(106.34,10.94) v10(106.45,71.62) v10(106.56,55.49) v10(106.79,12.09) v10(106.89,55.72) v10(106.92,55.24) v10(107.05,7.95) v10(107.17,83.33) v10(107.3,190.01) v10(107.33,73.73) v10(107.33,73.1) v10(107.39,59.79) v10(107.48,76.25) v10(107.61,12.67) v10(107.83,20.15) v10(107.78,13.86) v10(107.99,63.06) v10(108.06,72.13) v10(108.06,70.1) v10(108.19,68.47) v10(108.32,66.75) v10(108.32,21.65) v10(108.32,21.15) v10(108.32,20.65) v10(108.32,20.15) v10(108.44,67.38) v10(108.83,22.15) v10(108.83,21.65) v10(108.83,21.15) v10(108.83,20.65) v10(108.9,13.51) v10(109.1,76.02) v10(109.21,66.7) v10(109.33,21.65) v10(109.33,21.15) v10(109.33,20.65) v10(109.49,74.24) v10(109.49,73.73) v10(109.49,73.22) v10(109.61,68.73) v10(109.61,63.57) v10(109.61,63.06) v10(109.82,71.65) v10(109.83,23.15) v10(109.83,22.15) v10(109.83,21.65) v10(109.83,21.15) v10(109.83,20.65) v10(110.02,175.66) v10(109.97,17.34) v10(110.37,175.92) v10(110.61,51.34) v10(110.73,176.17) v10(110.73,175.66) v10(110.76,59.82) v10(110.98,70.56) v10(110.98,69.79) v10(111.01,62.94) v10(111.15,52.83) v10(111.24,193.11) v10(111.26,192.63) v10(111.26,67.38) v10(111.31,55.33) v10(116.19,86.89) v10(116.32,100.48) v11(49.52,178.79) v11(50.79,175.27) v11(52.44,151.91) v11(52.47,151.32) v11(53.02,151.37) v11(55.59,150.81) v11(67.85,153.34) v11(68.35,153.6) v11(68.85,168.2) v11(69.1,160.98) v11(69.33,163.32) v11(70.55,163.78) v11(70.52,159.94) v11(70.87,140.71) v11(71.92,155.73) v11(72.12,140.58) v11(74.59,168.66) v11(74.92,169.62) v11(75.14,168.86) v11(75.17,170.13) v11(75.96,169.1) v11(76.67,169.11) v11(77.3,163.75) v11(77.51,173.56) v11(77.91,174.04) v11(79.26,162.41) v11(82.31,173.71) v11(89.55,141.24) v11(89.85,172.99) v11(90.71,173.5) v11(90.71,141.09) v11(90.94,143.17) v11(90.94,142.03) v11(91.02,151.07) v11(91.32,170.28) v11(91.55,147.54) v11(91.65,151.79) v11(92.47,137.33) v11(92.65,141.14) v11(92.75,168.75) v11(92.92,140.63) v11(93,155.67) v11(93.1,173.55) v11(93.2,150.59) v11(93.25,142.39) v11(93.36,169.36) v11(93.38,136.24) v11(93.46,175.33) v11(93.74,151.79) v11(93.84,168.86) v11(93.81,149.65) v11(93.79,135.58) v11(93.97,169.57) v11(94.15,170.17) v11(94.25,144.67) v11(94.3,173.68) v11(94.35,141.17) v11(94.4,168.83) v11(94.78,173.91) v11(94.93,168.19) v11(94.93,151.15) v11(95.19,170.28) v11(95.41,142.36) v11(95.54,148.05) v11(95.57,137.33) v11(95.66,178.12) v11(95.82,144.27) v11(95.87,135.61) v11(96.2,178.15) v11(96.18,170.1) v11(96.28,149.8) v11(96.68,168.93) v11(96.94,170.56) v11(96.89,137.05) v11(97.04,147.92) v11(96.99,144.98) v11(96.99,142.97) v11(98.92,63.39) v11(98.94,60.57) v11(99.48,61.95) v11(99.89,67.24) v11(100.55,64.48) v11(101.22,61.26) v11(101.33,66.75) v11(101.94,65.3) v11(101.91,64.39) v11(101.92,63.75) v11(102.65,59.79) v11(102.75,67.13) v11(103.13,169.3) v11(103.11,64.77) v11(103.85,59.76) v11(103.86,179.3) v11(104.41,63.88) v11(104.63,181.05) v11(104.92,171.82) v11(105.2,61.2) v11(105.88,65.43) v11(105.92,64.5) v11(107.15,17.91) v11(107.45,19.04) v11(107.78,174.44) v11(109.26,34.69) v11(109.28,32.35) v11(109.36,37.49) v11(109.41,36.19) v11(109.41,33.65) v11(109.46,30.02) v11(109.49,28.52) v11(110.1,28.9) v11(110.2,18.03) v11(110.43,28.11) v11(110.76,25.8) v11(110.81,18.99) v11(111.42,55.67) v11(111.44,54.96) v11(111.92,56.48) v11(112.3,52.99) v13(38.34,187.78) v13(42.4,188.92) v13(44.82,190.44) v13(89.9,123.13) v13(89.9,122.25) v13(90.79,116.4) v13(90.79,114.88) v13(92.57,116.91) v13(94.72,105.86) v13(94.72,104.85) v13(94.98,116.78) v13(95.74,105.86) v13(95.74,104.97) v13(96.73,133.42) v13(96.88,136.09) v13(96.89,135.25) v13(97.01,116.91) v13(97.01,115.64) v13(97.65,106.12) v13(97.71,110.05) v13(97.71,109.04) v13(97.71,108.02) v13(97.71,107.01)
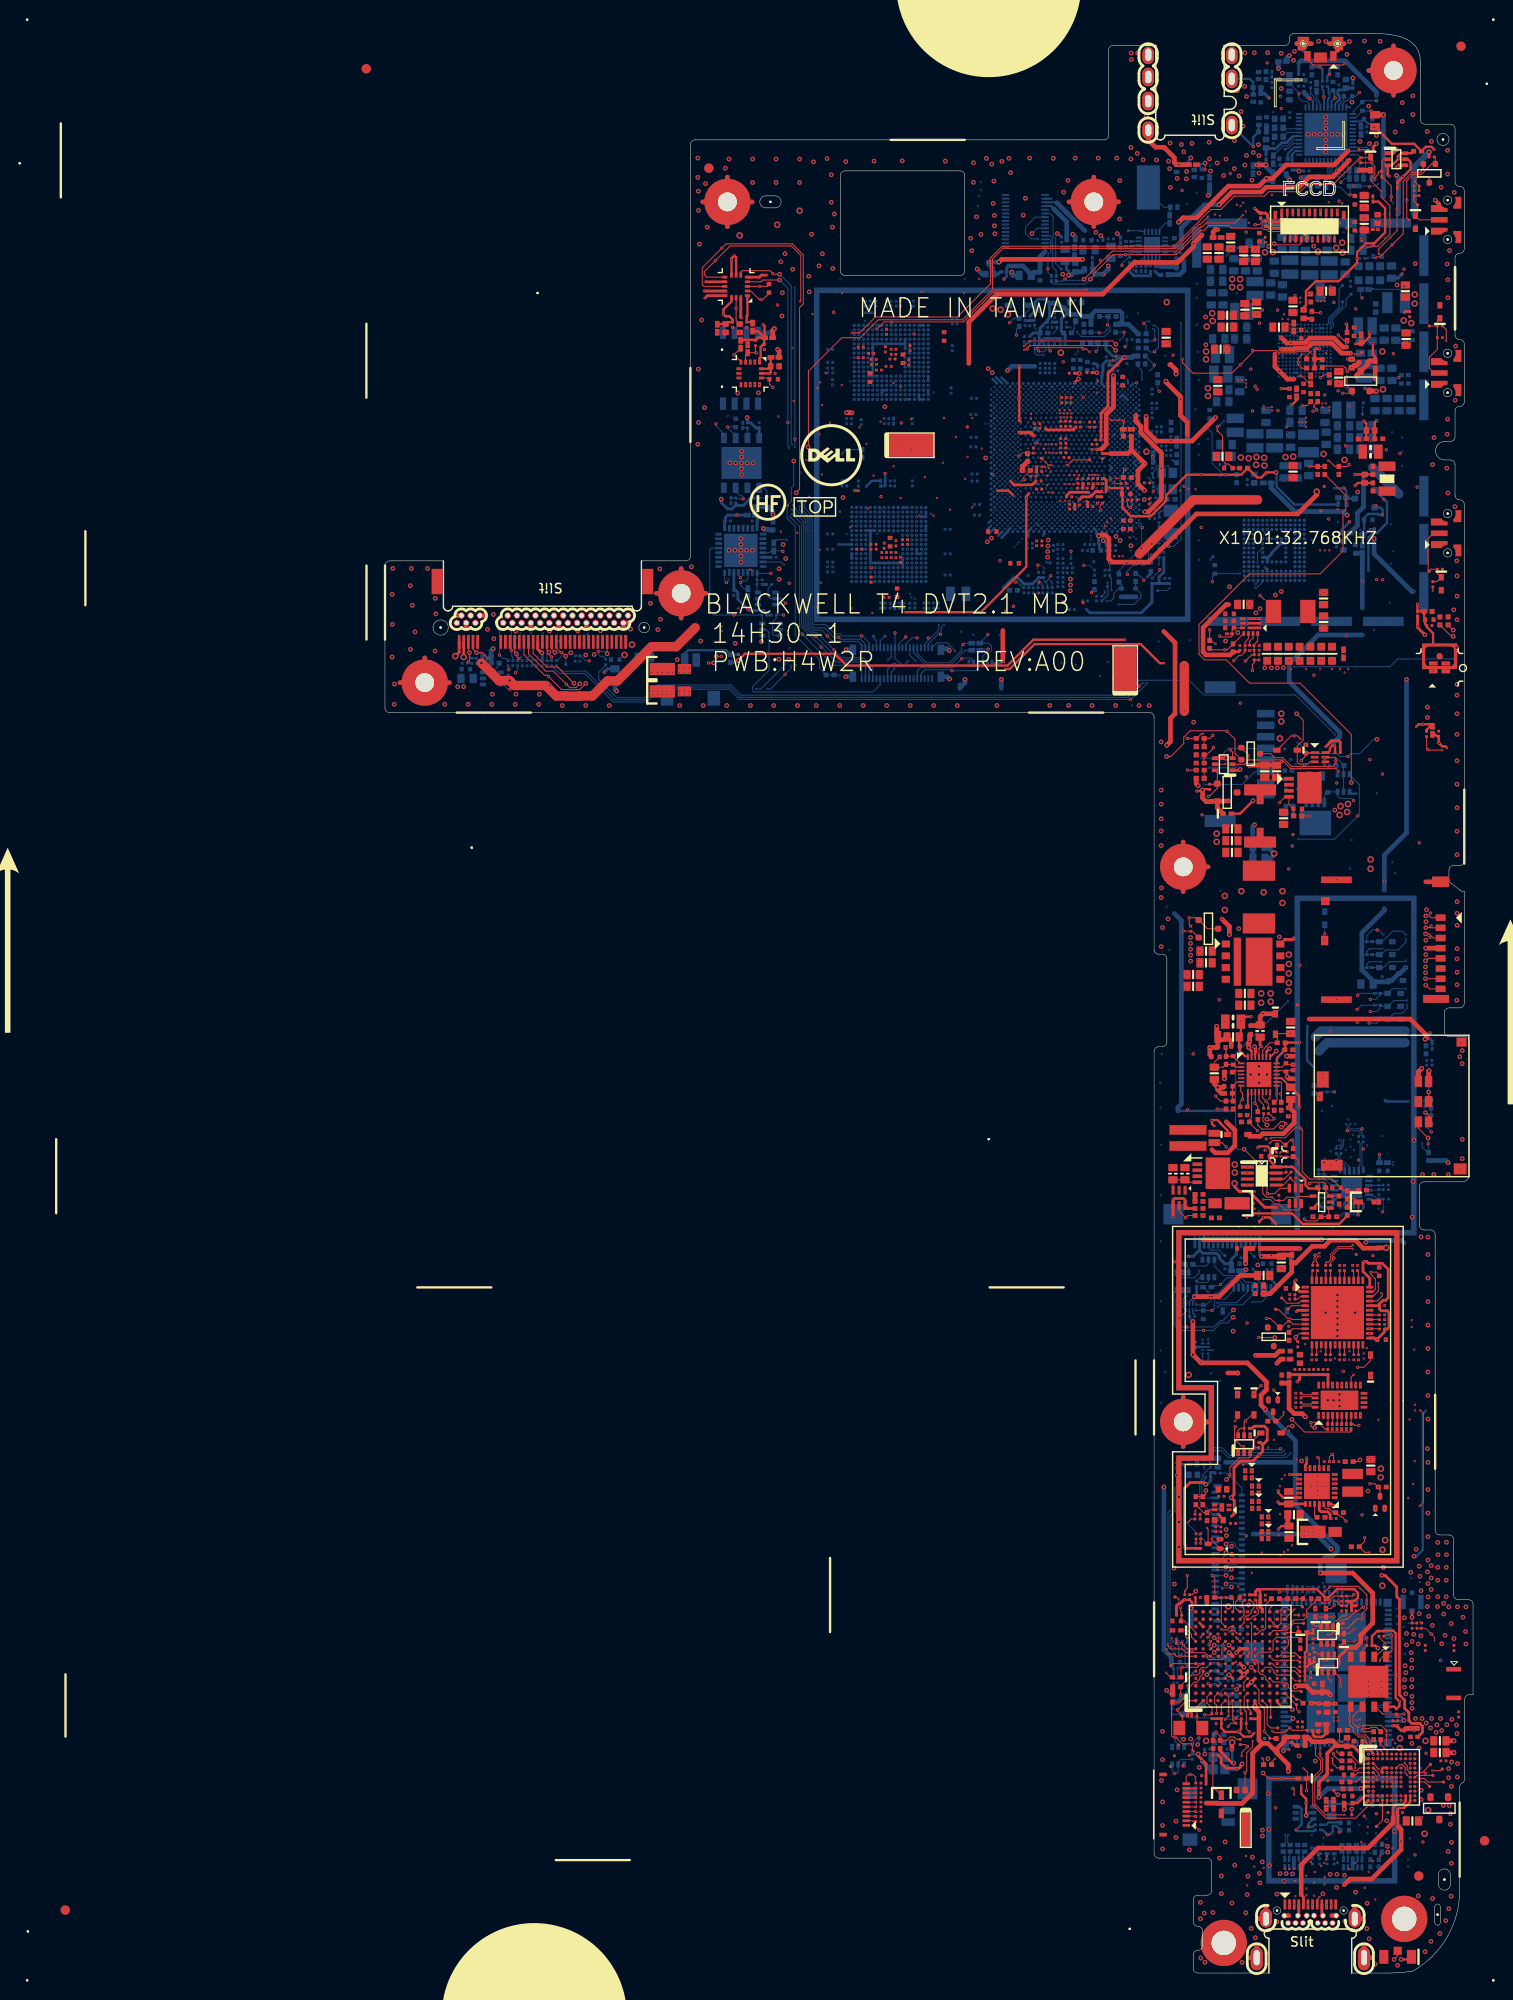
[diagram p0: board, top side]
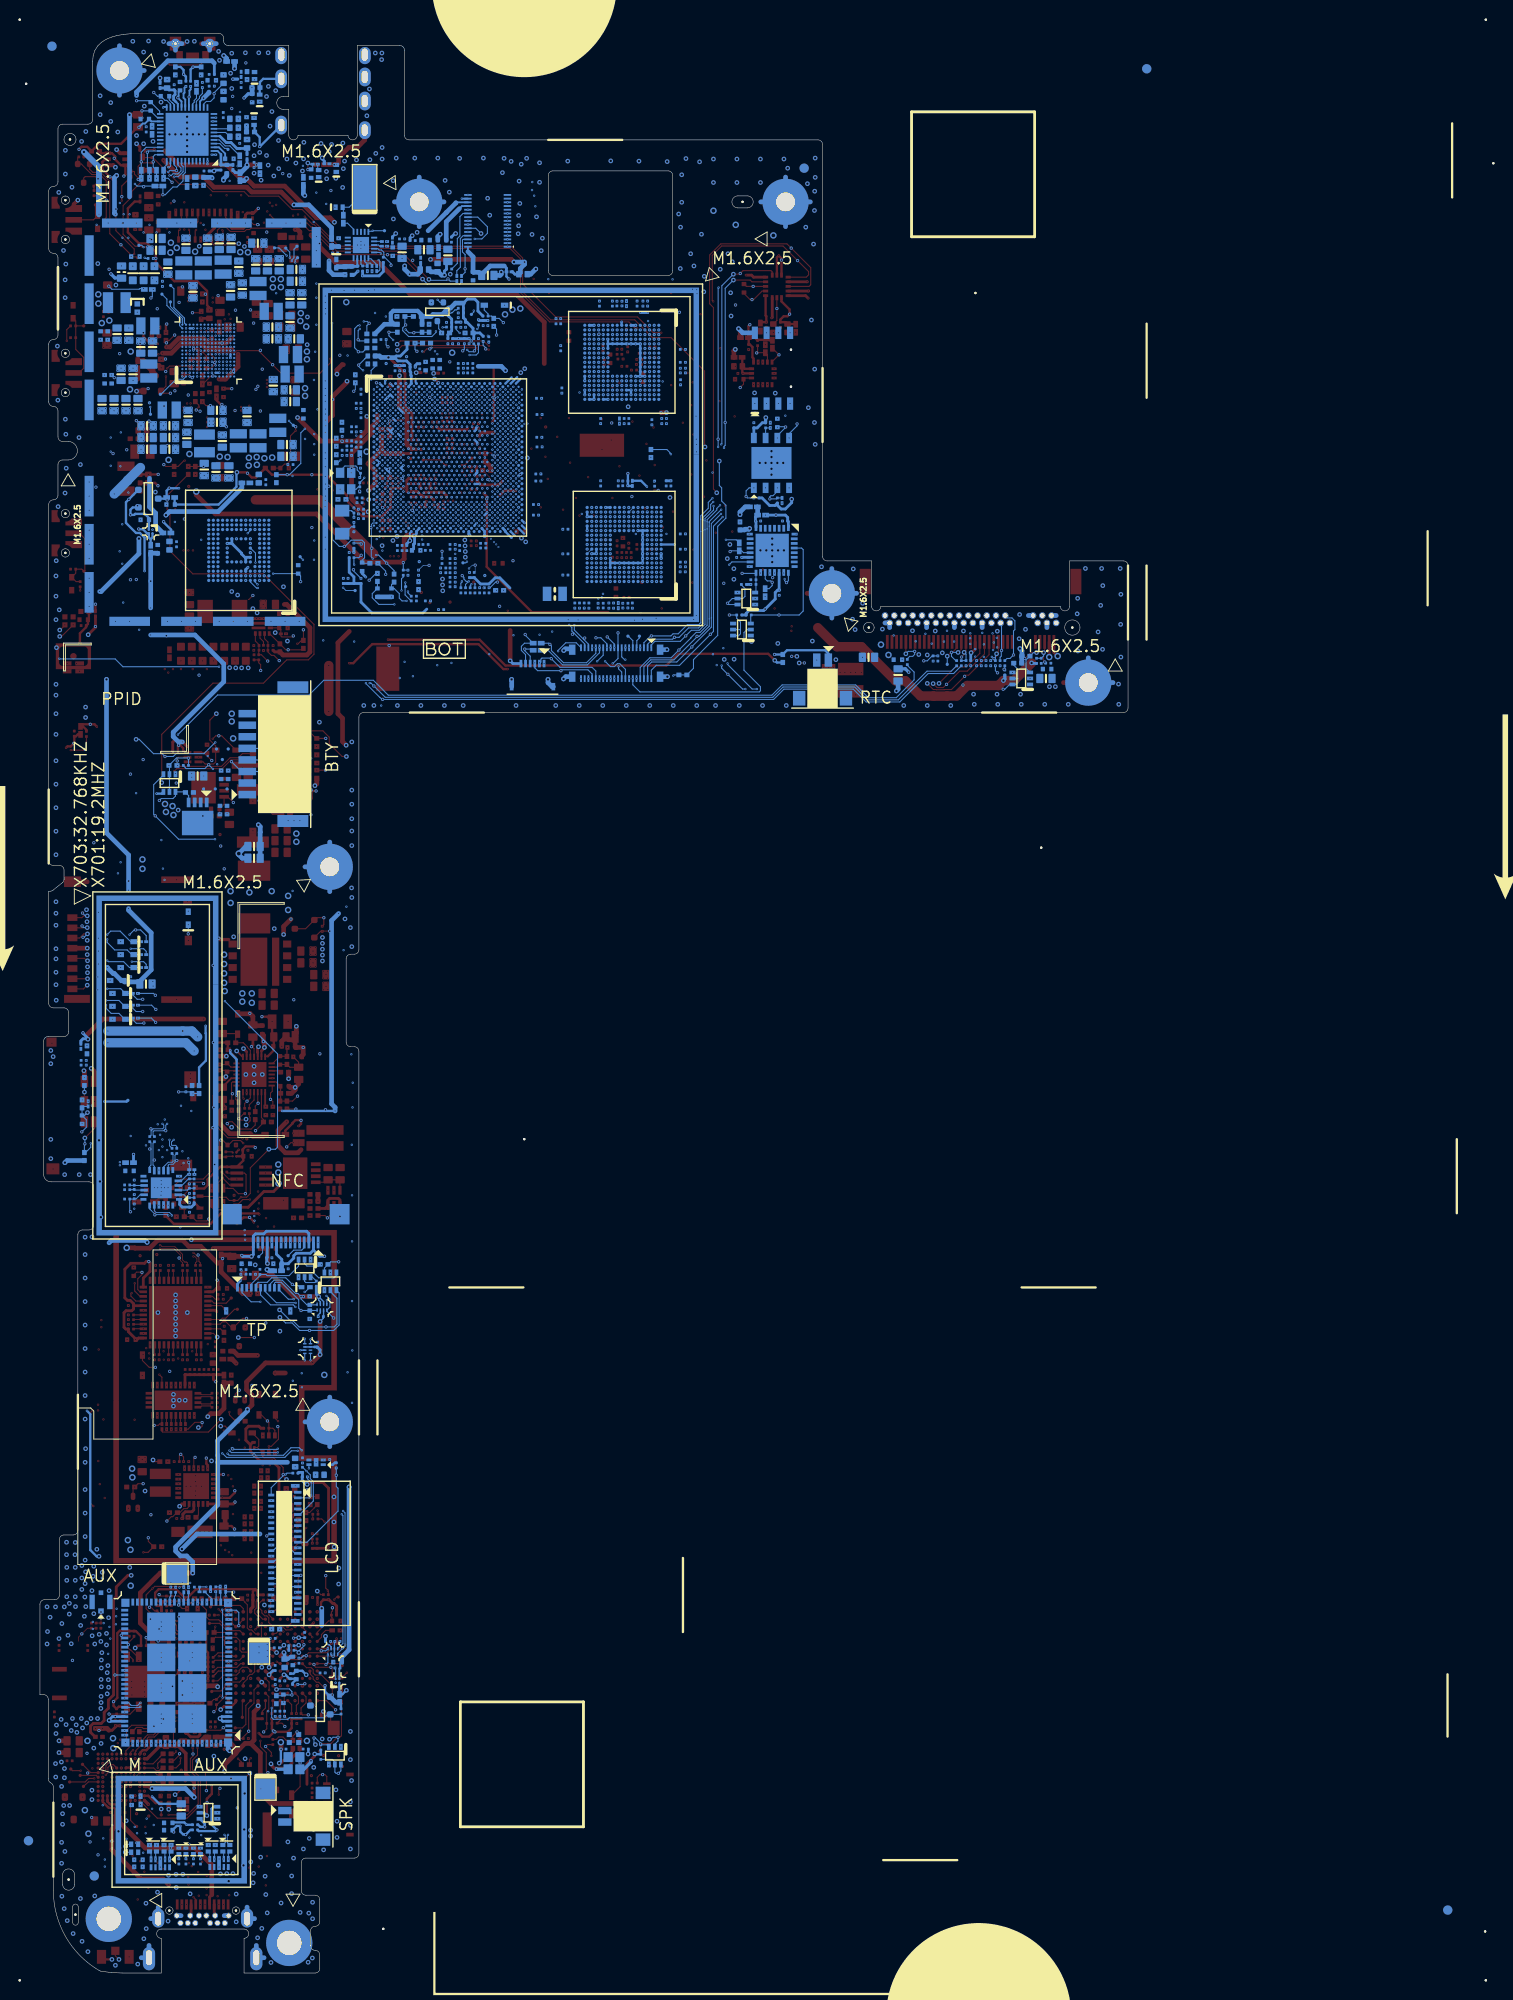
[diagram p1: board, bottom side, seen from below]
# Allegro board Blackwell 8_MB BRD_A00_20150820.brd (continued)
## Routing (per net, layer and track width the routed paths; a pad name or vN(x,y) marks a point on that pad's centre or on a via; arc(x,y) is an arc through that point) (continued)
GND_L:
  vias: v5(92.62,40.25) v5(92.62,39.05) v5(92.57,37.16)
V1P05A_LX:
  vias: v1(93.59,173.32)
V1P8A_LX:
  vias: v1(103.95,176.17)
V1P15_LX:
  vias: v1(98.36,181.27)
V3P3_SD_EN: length 5.8
  TOP w0.114: v1(103.52,170.72) 104.28,170.72 PQ4901.G 104,171.48 v10(104,172.54)
  L3SGND w0.127: v11(103.62,172.54) v10(104,172.54)
  L6SGND w0.06: v11(103.62,172.54) 103.09,172.54 102.3,173.33 v8(101.43,173.33)
V3P3A_LX1:
  vias: v1(101.59,170.53)
V3P3A_LX2:
  vias: v1(103.03,170.99)
V3P3SX_LX1:
  vias: v1(104.05,174.42)
V3P3SX_LX2:
  vias: v1(104.02,173.07)
V5P0A_LX:
  vias: v1(104.94,179.85)
VBATL: length 4
  TOP w0.114: v10(100.06,171.72) 99.99,171.72 99.12,172.59 v1(98.92,172.59)
  L3SGND w0.127: v10(100.06,171.72) 100.06,171.78 v11(100.32,172.03)
  L5 w0.076: v11(100.32,172.03) 100.32,172.67 99.47,173.51 99.47,173.68 v8(99.43,173.73)
VCC0_LX:
  vias: v1(94.52,178.3)
VCC0_SENSE: length 39.7
  L5 w0.076: v8(70.91,167.11) 71.11,167.32 71.86,167.32 72.39,166.79 73.08,166.79 73.53,167.23 76.5,167.23 v4(76.64,167.38)
  L6SGND w0.127: v8(97.43,176.93) 96.66,176.93 96.06,177.53 95.48,177.53 95.11,177.9 95.11,178.68 92.9,180.89 v4(92.69,180.89)
  L7 w0.06: v4(76.64,167.38) 76.83,167.57 76.83,167.63 77.16,167.96 77.16,168 77.55,168.38 77.85,168.38 78.32,168.86 78.32,169.01
  L7 w0.061: 78.32,169.01 78.32,169.43 78.53,169.63 78.53,170.19 78.29,170.43 78.29,170.7 78.41,170.82 78.41,171.07 80.9,173.56 80.9,174.7 81.87,175.66 84.28,175.66 84.54,175.41 85.76,175.41 86.11,175.05 86.35,175.05 86.51,175.22 86.51,175.24 86.68,175.41 86.68,178.16 89.54,181.02 90.69,181.02 91.27,181.6 92.01,181.6 v5(92.09,181.53) 92.69,180.93 v4(92.69,180.89)
VCC1_LX:
  vias: v1(94.86,179.73)
VCC1_SENSE: length 41.8
  L5 w0.076: v8(71.18,164.73) 71.18,164.91 71.69,165.42 71.69,165.62 72.45,166.38 73.07,166.38 73.66,166.96 76.96,166.96 v4(76.97,166.95)
  L6SGND w0.06: v8(97.83,177.33) 97.71,177.45 97.71,177.94 96.47,179.18 95.23,179.18 93.02,181.38 91.93,181.38 91.6,181.05 v4(91.53,181.05)
  L7 w0.06: v4(76.97,166.95) 77.33,167.31 77.84,167.31 77.89,167.25 78.41,167.25 78.81,167.65 78.81,167.82 78.7,167.94 78.7,168.1 78.71,168.11 78.87,168.27 78.87,168.49
  L7 w0.061: v4(91.53,181.05) 91.22,181.05 90.74,180.56 89.58,180.56 87.03,178.01 87.03,174.41 86.42,173.81 85.36,173.81 v5(84.36,174.8) 83.85,175.31 82.61,175.31 81.14,173.84 81.14,173.45 79.01,171.33 79.01,170.45 79.1,170.37 79.1,170.19 78.94,170.03 78.94,169.93 78.77,169.77 78.77,169.53 78.57,169.33 78.57,168.93 78.87,168.64 78.87,168.49
VCC_VSSSENSE: length 41.6
  L5 w0.076: v8(70.63,164.73) 70.88,164.98 71,164.98 71.46,165.44 v8(71.46,167.11) 71.86,167.11 72.32,166.65 73.13,166.65 73.58,167.1 76.79,167.1 v4(77,167.3)
  L6SGND w0.06: v4(92.04,181.05) 92.19,181.2 92.95,181.2 95.13,179.01 96.43,179.01 97.43,178.02 v8(97.43,177.33)
  L7 w0.06: v4(77,167.3) 77,167.64 77.17,167.8 77.83,167.8 78.53,168.5 78.53,168.81 78.45,168.88 78.45,168.91
  L7 w0.061: v4(92.04,181.05) 91.75,181.33 91.25,181.33 90.71,180.79 89.56,180.79 86.85,178.08 86.85,175.31 86.42,174.88 85.89,174.88 85.69,175.08 84.62,175.08 84.21,175.49 82.54,175.49 81.02,173.97 81.02,173.5 78.61,171.09 78.61,170.84 78.41,170.65 78.41,170.48 78.65,170.24 78.65,169.58 78.45,169.39 78.45,168.91 78.45,168.91
VCCDSIPLL_1P24_1P35: length 3.8
  TOP w0.114: R805.1 R806.2 v1(79.82,167.71) 79.72,167.81 v10(78.45,167.81)
  L3SGND w0.127: v11(78.1,167.81) 78.45,167.81 v10(78.45,167.81)
  L6SGND w0.127: v11(78.1,167.81) 77.87,167.59 v5(77.78,167.59)
VDD_3G_LTE_3P3: length 6.3
  TOP w0.305: NGFF1.4 v13(8.52,142.21) ; NGFF1.2 8.02,142.73 v13(7.61,142.31)
  BOTTOM w0.356: v1(23.71,140.58) 24.07,140.94 C4006.1
  BOTTOM w0.508: v2(11.7,143.12) 11.47,142.9 R4020.1 11.49,142.29 R4017.2
  vias: v2(7.86,139.01) v2(8.5,139.01) v9(28.83,140.53) v9(28.96,138.5) v9(28.96,138.12) v9(29.47,140.53) v9(29.47,138.5) v9(29.47,138.12) v9(29.97,140.53) v9(29.97,138.5) v9(29.97,138.12) v9(30.48,138.5) v9(30.48,138.12) v9(30.61,140.53) v9(30.99,138.5) v9(30.99,138.12) v9(31.12,140.53) v10(28.83,140.53) v10(28.96,138.5) v10(28.96,138.12) v10(29.47,140.53) v10(29.47,138.5) v10(29.47,138.12) v10(29.97,140.53) v10(29.97,138.5) v10(29.97,138.12) v10(30.48,138.5) v10(30.48,138.12) v10(30.61,140.53) v10(30.99,138.5) v10(30.99,138.12) v10(31.12,140.53) v13(25.89,142.44) v13(26.71,143.56)
VDD_IO_NFC: length 9.8
  BOTTOM w0.305: NFC1.2 88.05,78.12 ; 88.05,78.12 87.38,77.46 v1(86.85,77.46) ; 88.05,78.12 88.39,77.78 89.92,77.78 90.18,77.52 90.18,77.26 C3903.1 C3902.1 91.48,77.11 92.05,77.68 NFC1.10
  BOTTOM w0.508: C3902.1 91.5,76.63 R3904.2
VDD_NFC_3P3: length 14
  TOP w0.508: v2(94.75,77.44) C3901.1 97.04,77.59 R3902.2
  BOTTOM w0.305: v1(95.79,77.54) 95.69,77.44 v2(94.75,77.44) 94.55,77.64 NFC1.15 94.55,79.65 94.32,79.88 93.43,79.88 93.15,80.16 88.78,80.16 88.55,79.92 NFC1.3
VDD_TP_3V3: length 11
  TOP w0.508: C4301.1 92.44,75.38 90.16,73.1 v1(89.14,73.1) v2(87.49,73.1)
  BOTTOM w0.152: U4301.7 87.31,72.53 87.49,72.72 v2(87.49,73.1) 86.96,72.57 U4301.6
  BOTTOM w0.305: v2(87.49,73.1) 87.74,73.35 R4310.2
  vias: v2(94.35,76.53)
VDDD_DREG: length 2.3
  TOP w0.254: C3024.1 98.31,74.72 v1(98.46,74.87)
  TOP w0.305: U3102.2 98.9,73.62 98.54,73.99 C3024.1
VDDQ_LX0:
  vias: v1(99.73,181.43)
VDDQ_LX1:
  vias: v1(102.22,182.21)
2_4_LANE: length 10.5
  L7 w0.06: v8(71.26,170) 71.2,170.05 71.2,170.33 71.06,170.48 71.06,170.65 71.17,170.76 71.17,170.93 71.09,171.01 71.09,174.05 70.75,174.39 70.74,174.39 70.55,174.59 70.55,174.9 69.41,176.05 69.41,176.58 69.56,176.73 69.56,177.13 68.74,177.95 v5(68.57,177.95)
  BOTTOM w0.114: v5(68.57,177.95) 68.26,177.64 v1(68.26,177.01)
2_4_LANE_DET: length 3.3
  BOTTOM w0.114: v1(67.52,178.35) 67.98,178.81 R748.2 68.82,179.06 R733.1 69.18,179.29 69.59,179.71 D5412.A
+VGG:
  vias: v1(81.85,156.2) v1(86.4,160.68) v2(79.02,155.25) v2(79.46,154.81) v4(70.91,162.34) v4(71.18,162.82) v4(71.18,161.87) v4(71.73,162.82) v4(71.73,161.87) v4(72.28,162.82) v4(72.28,161.87) v4(72.28,159.96) v4(72.83,162.82) v4(72.83,161.87) v4(72.83,160.92) v4(72.83,159.96) v4(73.38,161.87) v4(73.38,160.92) v4(73.66,162.34) v4(73.93,162.82) v4(73.93,161.87) v4(74.48,162.82) v4(74.48,161.87) v4(75.03,162.82) v4(75.03,161.87) v4(75.31,161.39) v4(75.58,162.82) v4(75.58,160.92) v4(75.86,163.3) v5(70.91,162.34) v5(71.18,162.82) v5(71.18,161.87) v5(71.73,162.82) v5(71.73,161.87) v5(72.28,162.82) v5(72.28,161.87) v5(72.28,159.96) v5(72.83,162.82) v5(72.83,161.87) v5(72.83,160.92) v5(72.83,159.96) v5(73.38,161.87) v5(73.38,160.92) v5(73.66,162.34) v5(73.93,162.82) v5(73.93,161.87) v5(74.48,162.82) v5(74.48,161.87) v5(75.03,162.82) v5(75.03,161.87) v5(75.31,161.39) v5(75.58,162.82) v5(75.58,160.92) v5(75.86,163.3) v7(70.91,161.39) v7(70.91,160.44) v7(71.18,160.92) v7(71.18,159.96) v7(71.73,159.96) v7(72.01,161.39) v7(74.48,159.96) v7(75.58,159.96) v8(70.91,163.3) v8(70.91,161.39) v8(70.91,160.44) v8(71.18,160.92) v8(71.18,159.96) v8(71.46,163.3) v8(71.46,161.39) v8(71.46,160.44) v8(71.73,159.96) v8(72.01,163.3) v8(72.01,161.39) v8(72.56,161.39) v8(72.56,160.44) v8(73.11,161.39) v8(73.11,160.44) v8(73.38,162.82) v8(73.66,161.39) v8(73.66,160.44) v8(74.21,163.3) v8(74.21,161.39) v8(74.21,160.44) v8(74.48,159.96) v8(74.76,163.3) v8(74.76,160.44) v8(75.03,163.77) v8(75.31,162.34) v8(75.31,160.44) v8(75.58,163.77) v8(75.58,159.96) v9(71,162.76) v9(71.36,162.76) v9(71.56,161.8) v9(71.56,160.78) v9(71.74,162.63) v9(71.72,160.01) v9(71.94,162.2) v9(72.1,159.99) v9(73.57,160.88) v9(74,160.91) v9(74.05,161.87) v9(74.43,160.88) v9(74.51,161.87) v9(74.79,162.25) v9(74.89,161.49) v9(74.89,160.98) v9(74.99,161.85) v9(77.84,156.41) v9(78.07,156.81) v9(78.47,157.17) v9(79.82,156.05) v9(80.5,155.14) v9(80.58,156.05) v9(85.97,160.22) v9(86.85,160.35) v9(87.62,160.35) v10(71,162.76) v10(71.36,162.76) v10(71.56,161.8) v10(71.56,160.78) v10(71.74,162.63) v10(71.72,160.01) v10(71.94,162.2) v10(71.94,160.98) v10(72.07,161.82) v10(72.1,159.99) v10(72.33,160.86) v10(72.38,162.63) v10(72.48,161.85) v10(72.48,159.99) v10(72.76,162.89) v10(72.76,162.38) v10(72.76,160.86) v10(72.88,161.87) v10(72.93,160.01) v10(73.19,160.86) v10(73.29,161.85) v10(73.27,159.99) v10(73.57,160.88) v10(73.72,162.33) v10(73.67,161.87) v10(73.67,159.99) v10(74,160.91) v10(74.05,161.87) v10(74.18,162.81) v10(74.26,159.99) v10(74.43,160.88) v10(74.54,162.66) v10(74.51,161.87) v10(74.79,162.25) v10(74.89,161.49) v10(74.89,160.98) v10(74.99,161.85) v11(71,163.24) v11(71.44,162.3) v11(71.44,161.34) v11(71.44,160.32) v11(71.54,163.24) v11(72.1,160.4) v11(72.48,161.39) v11(72.66,160.37) v11(73.04,161.39) v11(73.06,163.27) v11(73.29,160.4) v11(73.62,161.39) v11(74,160.4) v11(74.15,163.29) v11(74.18,162.3) v11(74.18,161.41) v11(74.61,160.4) v11(74.79,163.29) v11(75.25,160.42) v11(75.27,162.33) v13(92.52,163.77) v13(93.36,163.7) v13(94.19,163.82) v13(94.17,162.99) v13(95.03,163.75) v13(95.06,162.91) v13(97.34,163.82) v13(98.18,163.88) v13(101.46,164.16)
+VNN: length 13
  TOP w0.508: v2(82.14,157.91) 82.54,157.91 83.81,159.18 83.81,159.26 83.93,159.39 v1(83.93,162.61) 83.93,164.24 81.71,166.46 81.71,167.14 81.16,167.69 v9(81.16,168.35)
  L3SGND w0.254: v11(76.31,160.48) 76.31,160.47 v10(75.91,160.47)
  vias: v2(88.73,175.97) v4(76.13,164.73) v5(74.21,165.2) v5(74.76,165.2) v5(76.13,164.73) v7(72.01,166.16) v7(72.56,166.16) v7(72.83,165.68) v7(73.38,165.68) v7(74.21,166.16) v7(74.76,167.11) v7(74.76,164.25) v7(75.31,167.11) v7(75.31,166.16) v7(75.31,164.25) v7(75.58,164.73) v7(75.58,161.87) v7(75.86,167.11) v7(75.86,166.16) v7(75.86,164.25) v7(75.86,162.34) v7(75.86,160.44) v7(76.13,160.92) v7(76.13,159.96) v7(76.41,166.16) v7(76.41,164.25) v7(76.41,163.3) v7(76.41,162.34) v8(72.01,166.16) v8(72.56,166.16) v8(72.83,165.68) v8(73.38,165.68) v8(73.93,166.63) v8(74.21,166.16) v8(74.48,166.63) v8(74.76,167.11) v8(74.76,164.25) v8(75.31,167.11) v8(75.31,166.16) v8(75.31,164.25) v8(75.58,166.63) v8(75.58,164.73) v8(75.58,161.87) v8(75.86,167.11) v8(75.86,166.16) v8(75.86,164.25) v8(75.86,162.34) v8(75.86,161.39) v8(75.86,160.44) v8(76.13,166.63) v8(76.13,165.68) v8(76.13,163.77) v8(76.13,162.82) v8(76.13,160.92) v8(76.13,159.96) v8(76.41,166.16) v8(76.41,164.25) v8(76.41,163.3) v8(76.41,162.34) v9(75.17,167.05) v9(76.19,167.05) v9(76.44,164.64) v9(76.69,167.05) v10(72.76,166.31) v10(73.02,166.69) v10(74.18,166.17) v10(75.17,167.05) v10(75.17,166.19) v10(75.5,165.61) v10(75.55,164.72) v10(75.68,167.08) v10(75.7,166.19) v10(75.93,165.66) v10(75.93,164.28) v10(75.88,163.37) v10(76.03,164.69) v10(76.19,167.05) v10(76.26,166.19) v10(76.41,165.68) v10(76.44,164.64) v10(76.39,163.34) v10(76.69,167.05) v10(76.67,163.8) v10(76.97,163.34) v11(72.3,165.79) v11(73.04,166.06) v11(74,166.64) v11(75.04,163.88) v11(75.48,166.62) v11(75.63,163.83) v11(75.81,165.18) v11(76.06,166.65) v11(76.08,162.91) v11(76.19,163.85) v11(76.36,165.15) v11(76.62,166.59) v11(76.64,162.91) v13(88.76,175.23) v13(88.76,174.39)
+VREFB: length 5.1
  TOP w0.254: v1(103.91,178.2) 104,178.12 v10(104,177.29)
  L3SGND w0.254: v11(103.62,177.13) 103.77,177.29 v10(104,177.29)
  L6SGND w0.06: 102.23,176.42 102.02,176.42 101.12,175.53 100.83,175.53 v8(100.63,175.33)
  L6SGND w0.254: v11(103.62,177.13) 103.54,177.13 102.83,176.42 102.23,176.42
+VREFT: length 4.2
  TOP w0.254: PR5102.1 101.26,174.44 PR5104.1 ; 100.49,175.53 v10(100.49,175.53) ; 100.49,175.53 v1(101,175.53) ; 100.49,175.53 PR5104.1 ; PR5104.1 PR5103.1
  L3SGND w0.254: v11(100.27,175.79) 100.27,175.76 v10(100.49,175.53)
  L5 w0.254: v8(100.63,175.73) 100.32,175.73 v11(100.27,175.79)
+VRTC: length 34.3
  TOP w0.254: v10(78.29,160.45) 78.32,160.47 C1191.1 79.67,160.42 C1189.1 79.72,159.79 R739.1 79.72,158.34 80.63,157.42 82.77,157.42 84.31,158.97 84.31,159.05 84.44,159.18 84.44,159.69 86.67,161.92 v1(88.23,161.92) 92.54,161.92 PC5005.1 94.27,161.62 94.73,161.62 95.29,162.17 v2(96.33,162.17)
  L3SGND w0.254: v10(78.29,160.45) 78.19,160.45 78.18,160.44 v11(77.86,160.44)
  L5 w0.254: v11(77.86,160.44) v5(77.51,160.44)
  BOTTOM w0.254: v2(96.33,162.17) 96.38,162.12 96.38,160.62 98.3,158.69 PC5101.1 103.06,158.72 PR5112.2
+VRTC_BAT: length 17.9
  L5 w0.203: 99.3,173.3 99.03,173.57 v8(99.03,173.73)
  L5 w0.254: 99.3,173.3 99.81,172.79 99.81,171.46 100.46,170.8 100.46,163.32 102.59,161.2 v5(102.59,160.46)
  BOTTOM w0.254: v5(102.59,160.46) 103.63,160.46 v1(103.64,160.47) 103.92,160.19 PR5112.1 104.05,159.33 PD5101.3
+VRTC_BAT_R: length 3.4
  BOTTOM w0.254: v1(106.95,156.06) 106.92,156.03 106.49,156.03 106.03,155.57 U5101.B2 105.85,155.14 105.65,154.94 ; PR5114.2 105.65,154.94 ; 105.65,154.94 105.45,155.14 U5101.A2
+VRTC_L: length 6.9
  BOTTOM w0.254: RTC1.1 32.39,142.59 32.75,142.95 36.87,142.95 PR5117.1 v1(38.21,142.49)
+VRTC_R: length 88.8
  TOP w0.254: v9(80,144.09) 70.09,144.09 67.3,141.3 49.9,141.3 48.63,142.57 38.9,142.57 v2(38.19,141.85)
  L2 w0.254: v2(90.87,143.94) 90.71,144.09 v9(80,144.09)
  L7 w0.254: v5(106.31,151.51) 106.29,151.48 106.29,144.39 105.85,143.96 90.89,143.96 v2(90.87,143.94)
  BOTTOM w0.254: v5(106.31,151.51) 106.31,155.12 106.81,155.62 107.23,155.62 108.32,156.71 108.32,158.95 v1(108.01,159.25) 106.99,160.28 PD5101.1 ; PR5117.2 37.96,141.63 v2(38.19,141.85)
+VSDIO: length 6.3
  TOP w0.305: v10(75.86,159.05) 75.96,158.95 C1138.1
  L3SGND w0.254: v10(75.86,159.05) 75.86,159.18 v11(75.68,159.35)
  L3SGND w0.508: v11(104.1,174.57) 104.33,174.57 v10(104.51,174.39)
  L6SGND w0.203: 102.69,174.62 101.52,174.62 v8(101.43,174.53)
  L6SGND w0.254: v11(75.68,159.35) 75.55,159.49 v5(75.31,159.49)
  L6SGND w0.381: 102.69,174.62 104.05,174.62 v11(104.1,174.57)
  BOTTOM w0.203: v2(77.63,154.79) 77.63,155.62 CPU1.BW15
  BOTTOM w0.305: v2(77.63,154.79) 77.96,154.46 C1139.1
  vias: v1(88.23,156.2) v1(102,157.13) v9(101.71,175.08) v9(102.98,158.19)
+VSYS: length 13.3
  TOP w0.305: R5211.1 92.24,142.77 R5213.1
  TOP w0.508: R5211.1 91.35,142.44 88.76,142.44 88.44,142.76 88.44,145.39 90.94,147.9 91.2,147.9
  BOTTOM w0.508: PC4629.1 95.74,120.47 96.13,120.85 v13(96.13,120.98) 95.36,121.74 PC4630.1
  vias: v1(98.08,121.79) v1(106.46,131.14) v1(107.07,158.57) v1(107.83,150.57) v1(111.8,122.14) v13(106.54,120.34) v13(106.54,119.32) v13(107.63,53.56) v13(107.66,54.5)
+VUSB_5V_19V: length 81.3
  TOP w0.305: C2910.1 111.66,25.52 112.15,26.02 112.15,26.67 111.86,26.97 111,26.97 110.68,27.29 110.68,28.15 110.22,28.61 110.22,29.48 109.66,30.04 109.66,40.38 109.37,40.67 109.37,41.71 108.11,42.97 v2(107.76,42.97) ; JUSBC1.B9 98.78,6.3 JUSBC1.A4 ; JUSBC1.B4 101.28,6.3 JUSBC1.A9
  TOP w0.508: v2(101.26,79.24) v9(88.45,79.24)
  L2 w0.508: v9(88.43,81.86) 88.07,81.5 88.07,79.62 v9(88.45,79.24)
  L7 w0.305: v2(107.76,42.97) 107.56,42.97 106.63,43.9 106.63,43.98 106.08,44.52 106.08,50.47 98.9,57.66 98.9,66.8 99,66.9 99,69.34 101.15,71.5 101.15,79.14 v2(101.26,79.24)
  L7 w0.508: 101.84,6.2 JUSBC1.B4 101.38,6.66 ; 98.22,6.2 JUSBC1.B9 98.68,6.66
  vias: v1(111.34,12.77) v1(112.03,16.81) v1(112.2,14.17) v1(112.53,23.74) v1(112.46,21.61) v2(111.01,24.81) v2(111.8,24.3) v2(112,19.76) v2(112,18.74) v5(107.43,12.24) v5(107.43,11.48) v5(110.6,12.26) v5(110.6,11.5) v9(110.83,23.65) v9(110.83,23.15) v13(112.38,15.06) v13(112.76,17.6)
+VUSB_5V_19V_R: length 5
  TOP w0.305: PQ4601.4 85.19,83.54 85.35,83.7 86.31,83.7 86.49,83.52 PQ4601.6 86.81,82.62 PR4637.2
  TOP w0.356: PQ4601.4 v1(85.19,81.76)
AC_PRESENT: length 106.2
  L5 w0.076: v4(88.02,144.01) 88.58,144.57 88.94,144.57 89.52,145.15 v4(89.52,149.17) ; v4(84.64,139.11) 84.4,139.11 84.11,139.4 84.11,139.42 83.86,139.68 83.86,140.15 82.49,141.51 80.18,141.51 79.94,141.75 v4(79.87,141.75)
  L7 w0.06: 81.13,158.19 81.08,158.19 81,158.28 80.71,158.28 v8(80.59,158.4)
  L7 w0.061: v4(79.87,141.75) 80.02,141.9 80.02,141.92 80.23,142.14 81.62,142.14 82.83,143.35 83.54,143.35 84.36,144.17 85.81,144.17 85.97,144.01 v5(86.99,144.01) v4(88.02,144.01) ; v5(88,75.89) 88,76.67 87.8,76.86 87.8,77.5 87.46,77.84 86.95,78.35 86.95,78.64 86.95,79.54 86.95,80.31 86.9,80.35 86.9,93.79 86.44,94.25 86.44,98.17 86.44,98.17 86.44,98.32 87.33,99.21 87.33,108.25 87.9,108.81 87.9,108.95 87.9,109.37 87.9,120.29 85.06,123.12 85.06,123.75 85.06,129.88 85.06,130.71 85.29,130.94 85.4,131.04 85.76,131.4 85.76,135.53 85.72,135.57 85.72,136.92 84.8,137.84 84.8,137.92 84.78,137.94 84.78,138.44 84.64,138.58 v4(84.64,139.11) ; v4(89.52,149.17) 89.52,149.32 88.87,149.97 88.72,149.97 85.94,152.75 85.93,152.75 85.66,153.02 85.66,153.03 85.18,153.51 85.02,153.51 84.86,153.36 84.63,153.36 84.47,153.51 v5(84.19,153.51) 84.56,153.89 84.56,154.23 84.4,154.4 84.33,154.4 84.32,154.41 84.04,154.41 83.87,154.24 83.56,154.24 83.26,154.55 83.26,155.18 82.89,155.54 82.89,156.3 82.5,156.69 82.5,156.87 82.5,156.97 81.75,157.72 81.75,157.77 81.33,158.19 81.13,158.19
  BOTTOM w0.114: U701.4 85.57,75.4 85.84,75.13 87.49,75.13 88,75.64 v5(88,75.89)
ACPI_INT#: length 238.3
  TOP w0.114: v9(84.44,32.46) 84.95,31.95 D1701.A
  L2 w0.061: v10(84.49,74.23) 84.49,73.55 84.85,73.19 84.85,52.35 84.21,51.7 84.21,32.69 v9(84.44,32.46) ; v10(89.24,133.01) 89.19,132.97 89.19,117.8 86.02,114.63 86.02,105.38 85.84,105.2 v10(85.84,105.13)
  L3SGND w0.127: v10(89.24,133.01) 89.24,133.35 v11(89.17,133.42) ; v10(85.84,105.13) 85.79,105.07 85.79,99.92 84.39,98.52 84.35,98.48 84.35,75.26 84.35,75.26 84.35,74.37 v10(84.49,74.23)
  L5 w0.076: v4(83.7,140.99) 84.07,140.62 84.07,140.58 84.47,140.19 84.73,140.19 86.22,138.7 86.22,137.24 87.84,135.61 87.84,134.51 88.93,133.42 v11(89.17,133.42) ; v4(83.15,176.47) 83.15,176.82 83.56,177.24 83.56,178.88 84.22,179.53 84.46,179.53 84.84,179.16 85.14,179.16 85.84,179.86 85.84,180.46 91.46,186.08 92.26,186.08 95.97,189.78 105.45,189.78 105.93,189.3 106,189.3 106.56,188.74 106.81,188.74 108.57,186.98 108.57,178.04 109.36,177.25 109.36,152.93 111.1,151.19 111.1,141.27 111.03,141.21 v4(111.03,140.25)
  L7 w0.06: 79.89,176.6 79.72,176.78 78.73,176.78 78.12,176.17 77.96,176.17 76.29,174.49 76.29,174.06 76.27,174.04 76.27,173.97 75.96,173.66 75.96,172.07 75.96,172.06 75.96,172 75.58,171.63 75.58,171.05 75.7,170.93 75.7,170.76 75.5,170.57 v8(75.5,170.28)
  L7 w0.061: 79.89,176.6 79.97,176.52 v5(80.2,176.52) 83.09,176.52 v4(83.15,176.47) ; v4(111.03,140.25) 110.83,140.46 109.1,140.46 108.71,140.07 87.14,140.07 86.02,141.19 85.57,141.19 85.08,141.67 84.41,141.67 83.92,141.19 83.9,141.19 v4(83.7,140.99)
  BOTTOM w0.114: v5(80.2,176.52) 80.2,175.95 v1(80,175.74)
AMBER_LED: length 23.4
  TOP w0.254: LED1.3 110.68,1.47 v2(109.84,1.47)
  L5 w0.254: v2(109.84,1.47) 108.08,3.23 107.94,3.23 107.43,3.75 107.43,13.26 104.33,16.35 102.09,16.35 v5(101.81,16.07)
  BOTTOM w0.254: R4902.2 101.76,16.02 v5(101.81,16.07) 102.02,16.28 103.24,16.28 C5713.1
AMBER_LED_EC: length 22.7
  L2 w0.254: v9(91.64,32.63) 91.54,32.74 91.03,32.74 90.66,32.37 90.66,29.34 89.47,28.14 89.47,26.03 v10(89.65,25.85)
  L3SGND w0.254: v11(90.28,25.6) 90.03,25.85 v10(89.65,25.85)
  L5 w0.254: v4(95.24,17.22) 95.24,17.8 90.28,22.75 v11(90.28,25.6)
  L7 w0.254: v5(98.45,17.32) 95.34,17.32 v4(95.24,17.22)
AMBER_LED_R: length 2
  BOTTOM w0.254: U4901.6 99.81,16.13 v1(99.81,15.79) 100.29,15.79 100.52,16.02 R4902.1
AUD_AGND: length 1.2
  BOTTOM w0.203: U2001.24 104.24,201.66 v5(104.3,201.59)
  BOTTOM w0.508: R2205.2 v2(96.58,205.81)
  vias: v1(91.38,194.46) v2(80.63,197.28) v2(80.66,207.49) v2(80.68,206.78) v2(81.32,196.64) v2(81.37,207.49) v2(82,203.6) v2(81.95,195.96) v2(82.28,200.71) v2(83.4,195.93) v2(84.7,195.8) v2(84.82,194.99) v2(84.87,197.76) v2(85.63,193.95) v2(86.09,197.61) v2(86.35,196.82) v2(86.63,193.9) v2(86.65,194.69) v2(87.24,197.71) v2(89.09,197.84) v2(89.12,196.05) v2(89.24,194.74) v2(89.95,195.6) v2(90.66,194.25) v2(90.92,196.03) v2(91.83,198.04) v2(91.81,194.99) v2(92.14,203.42) v2(92.34,194.2) v2(92.54,201.16) v2(92.75,199.59) v2(92.92,203.88) v2(92.95,207.51) v2(92.95,195.37) v2(93.13,202.79) v2(93.13,196.41) v2(93.86,196.74) v2(93.97,207.51) v2(94.42,197.58) v2(94.47,196.39) v2(95.41,207.51) v2(96.89,203.65) v2(97.01,205.3) v2(104.53,202.18) v2(106.34,201.75) v4(93.84,200.55) v4(94.42,204.59) v4(94.47,201.24) v4(95.24,204.62) v4(95.24,198.14) v4(95.36,201.24) v4(96.02,197.73) v4(96.18,200.38) v4(96.18,199.41) v4(96.18,198.45) v4(97.78,205.13) v4(97.78,203.35) v4(98.59,204.54) v4(98.77,203.91) v4(100.27,205.05) v4(100.7,204.21) v4(102.48,204.36) v4(102.91,205.05) v4(103.11,204.06) v4(103.87,204.62) v4(105.5,199.56) v4(106.13,199.51) v4(106.54,200.48) v5(93.84,202.26) v5(94.42,204.59) v5(94.47,200.55) v5(94.73,202.26) v5(95.24,204.62) v5(95.24,198.14) v5(95.29,200.55) v5(96.02,197.73) v5(96.18,200.38) v5(96.18,199.41) v5(96.18,198.45) v5(97.78,205.13) v5(97.78,203.35) v5(98.59,204.54) v5(98.77,203.91) v5(98.92,200.1) v5(100.27,205.05) v5(100.7,204.21) v5(102.48,204.36) v5(102.91,205.05) v5(103.11,204.06) v5(103.87,204.62) v5(105.5,199.56) v5(106.13,199.51) v5(106.54,200.48) v11(92.8,200.43) v11(93.13,205.38) v11(93.1,201.75) v11(93.25,206.42) v11(93.97,201.24) v11(94.7,206.5) v11(94.96,201.52) v11(95.06,205.46) v11(95.11,197.18) v11(95.46,206.4) v11(96.99,198.06) v11(97.4,203.14) v11(97.5,199.31) v11(98.03,204.03) v11(98.64,199.56) v11(98.72,198.72) v11(99.63,201.59) v11(100.42,202.38) v11(101.18,201.62) v11(101.48,205.18) v11(102.22,202.31) v11(102.83,201.67) v11(102.96,203.27) v11(103.57,202.61) v11(104.35,203.55) v11(104.51,201.21) v11(104.53,200.43) v11(104.53,199.66) v11(105.93,200.07) v11(106.06,200.99)
AUD_AGND_1: length 6.8
  TOP w0.508: R2204.1 v1(85.81,195.42) 85.55,195.42 85.33,195.65 85.33,196.18 84.21,197.3 83.3,197.3 82.52,198.08 AUDIO1.5
AUDIO_CODEC_IRQ: length 136.5
  L5 w0.076: v4(87.03,191.49) 86.16,191.49 83.59,188.92 83.59,188.48 80.34,185.23 80.34,182.83 80.17,182.66 80.14,182.66 v4(80.05,182.57) ; v4(68.41,148.03) 68.21,148.03 v4(66.67,146.49) 65.94,145.75 65.79,145.75 65.41,145.37 62.54,145.37 61.59,146.32 55.01,146.32 54.14,147.19 50.56,147.19 46.47,151.28 46.47,158.45 45.86,159.06 45.86,160.43 46.77,161.34 46.77,166.58 45.89,167.46 v4(45.86,167.46)
  L7 w0.061: v4(66.67,146.49) 66.72,146.49 67.17,146.04 68.19,146.04 68.86,146.72 74.7,146.72 76.32,148.34 76.69,148.71 v5(76.69,149.5) ; v4(80.05,182.57) 79.82,182.57 79.58,182.32 70.35,182.32 70.35,182.32 70.06,182.32 68.86,181.12 68.17,181.12 68.16,181.12 68.02,181.12 67.75,181.39 67.75,181.42 67.34,181.83 67.24,181.93 67.24,181.93 67.14,182.03 62.61,182.03 62.32,182.03 62.03,182.03 49.25,182.03 45.86,178.65 45.86,178.35 v4(45.86,167.46) ; v5(103.11,194.13) 102.95,193.97 99.45,193.97 99.15,193.97 98.3,193.11 88.46,193.11 v5(87.74,192.4) 87.03,191.69 v4(87.03,191.49) ; v5(67.5,149.42) 67.5,148.55 68.03,148.03 v4(68.41,148.03)
  BOTTOM w0.114: U2001.41 102.31,195.39 102.14,195.22 102.14,194.66 102.67,194.13 v5(103.11,194.13)
AUDIO_CODEC_IRQ_L: length 8.2
  L7 w0.061: v8(71.29,156.38) 71.29,155.79 71.07,155.57 70.96,155.45 70.96,155.27 70.95,155.27 70.95,152.95 70.37,152.37 70.37,152.29 69.5,151.41 69.5,151.39 69.25,151.14 69.25,151.07 68.26,150.08 v5(68.26,149.42)
AUDIO_CODEC_IRQ_R: length 8.2
  L5 w0.06: 74.93,157.79 75.26,157.46 75.26,155.2
  L5 w0.076: v8(74.93,157.83) 74.93,157.79 ; v5(76.69,150.36) 76.69,150.5 76.73,150.54 76.73,151.15 76.4,151.49 76.26,151.63 76.26,152.98 75.26,153.98 75.26,155.2
BATDRV#: length 3.6
  TOP w0.114: PR4606.2 98.23,125.78 PC4617.2 97.71,126.29 PU4602.4 97.31,127.11 96.71,126.51 v1(96.71,126.49)
BATPRES#: length 1.9
  TOP w0.114: PR4610.1 96.44,94.42 PU4601.15
BIOS_HOLD#: length 13.6
  L7 w0.061: v5(38.67,166.97) 38.49,166.97 37.17,168.3 v5(37.04,168.3) 37.04,168.52 37.37,168.85 37.37,169.79 37.68,170.1 37.68,175.86 v5(39.07,177.25)
  BOTTOM w0.114: BIOS1.7 R1805.2 v5(38.67,166.97)
BIOS_WP#: length 15.1
  L5 w0.076: v5(37.8,169.6) 38.41,169.6 40.42,167.59 40.42,162.15 38.76,160.49 v5(37.91,160.49)
  BOTTOM w0.114: v5(37.91,160.49) 37.91,160.12 38.38,159.65 38.61,159.65 38.72,159.53 v1(38.72,159.3) 38.01,159.3 R1803.2 R1801.2
BL_CIN: length 3
  TOP w0.305: v1(96.53,50.9) 96.73,50.69 C4402.1 97.7,50.69 U4401.19
BL_FSET: length 1.6
  TOP w0.114: R4401.2 100.49,49.5 U4401.21
BL_ISET: length 3.3
  TOP w0.114: v1(103.9,48.84) 103.42,49.32 103.26,49.32 102.82,49.75 R4402.2 102.5,49.75 102.07,50.19 101.71,50.19 101.49,50.41 U4401.23
BL_SW:
  vias: v1(105.62,49.52)
BOARD_ID: length 4.5
  TOP w0.114: v2(92.05,30.64) U1704.G3
  BOTTOM w0.114: R1759.2 91.43,29.97 C1703.2 91.25,30.04 v1(90.38,30.04) 90.38,30.42 90.66,30.7 91.98,30.7 v2(92.05,30.64)
BPTHERM0: length 6
  TOP w0.114: TP5104.1 105.42,174.95 104.82,174.95 v10(104.81,174.94)
  L3SGND w0.127: v11(104.89,173.93) 104.88,173.94 104.88,174.55 104.81,174.63 v10(104.81,174.94)
  L6SGND w0.06: v11(104.89,173.93) 104.3,173.93 103.91,174.33 101.23,174.33 v8(101.03,174.53)
BQ24770_AGND: length 13.3
  TOP w0.508: PC4602.1 90.59,95.7 v2(90.03,95.7) ; PC4623.2 89.65,96.08 v2(90.03,95.7) ; PC4609.2 97.73,96.64 97.52,96.85 v2(97.52,96.87) ; PC4601.2 v2(97.47,99.08) ; v2(90.03,95.7) 90.03,95.45 90.41,95.07 PR4608.1 ; PC4613.1 89.32,99.11 89.16,99.26 v1(89.16,100.02) PC4612.1 90.03,100.1 PG4605.1 90.71,100.86 PC4607.2 91.48,100.71 v9(91.48,100.15)
  L2 w0.508: v2(93.59,97.1) 91.48,99.21 v9(91.48,100.15)
  vias: v2(94.47,97.99) v2(94.47,97.1) v2(94.47,96.21) v2(95.36,97.1)
BRTC_EXTPAD: length 8.3
  L5 w0.06: v5(83.68,154.53) 83.57,154.64 83.57,155.12 83.2,155.49 83.2,155.66 81.23,157.63 81.15,157.63 81.03,157.75 81.03,157.84 79.88,159 79.14,159 78.9,159.25 v8(78.61,159.25)
  BOTTOM w0.114: v5(83.68,154.53) 82.99,154.53 v1(82.89,154.43)
BT_DEV_EN: length 238.6
  L5 w0.076: v4(100.54,136.24) 100.54,136.46 100.3,136.7 100.3,136.95 100.32,136.96 v4(100.32,141.73) ; v4(107.3,34.11) 107.3,33.36 v5(108.46,32.21) ; v4(85.02,179.45) 85.65,180.08 85.65,180.55 91.36,186.27 92.18,186.27 96.06,190.15 105.35,190.15 105.46,190.04 106.01,189.49 106.08,189.49 106.64,188.93 106.9,188.93 108.76,187.07 108.76,186.74 108.91,186.59 108.91,183.45 108.85,183.39 108.85,178.19 108.85,178.03 109.55,177.33 109.55,153.01 111.3,151.26 111.3,141.4 111.42,141.29 v4(111.42,141.12)
  L7 w0.06: v8(71.54,171.49) 71.49,171.54 71.49,174.34 71.33,174.5 71.33,174.71 v5(71.18,174.85) 71.18,175.01 70.98,175.22 70.98,175.48 70.6,175.86 70.6,177.05 70.68,177.12 70.68,178.94 71.89,180.15
  L7 w0.061: v4(85.02,179.45) 84.86,179.45 84.43,179.88 84.02,179.88 83.85,180.05 79.21,180.05 79.17,180.01 76.74,180.01 76.28,179.55 74.35,179.55 73.74,180.15 71.89,180.15 ; v4(100.32,141.73) 100.42,141.83 109.13,141.83 109.27,141.7 109.5,141.7 109.63,141.83 110.5,141.83 110.91,141.42 111.25,141.42 111.42,141.25 v4(111.42,141.12) ; v4(100.54,136.24) 100.59,136.24 100.65,136.17 103.65,136.17 105.74,134.09 105.74,132.68 106.79,131.63 106.79,123.38 103.46,120.05 103.46,93.3 102.08,91.92 102.08,91.87 101.95,91.74 101.95,90.24 99.68,87.97 99.68,87.68 99.68,87.68 99.68,85.53 99.83,85.38 99.83,79.94 99.83,79.78 99.83,73.97 99.83,73.97 99.83,73.38 99.83,73.24 99.83,71.92 97.93,70.02 96.97,69.05 96.97,62.26 96.65,61.94 96.65,57.41 96.24,56.99 96.24,55.75 99.58,52.4 99.58,46.64 105.2,41.03 105.2,36.12 106.81,34.5 106.81,34.47 107.17,34.11 v4(107.3,34.11)
  BOTTOM w0.114: v5(71.18,174.85) 70.47,174.85 70.22,175.1 R703.1 ; v5(108.46,32.21) v1(109.51,32.21)
C_SBU1: length 21.1
  TOP w0.102: JUSBC1.A8 100.78,7.95 v9(101.02,8.19)
  L2 w0.061: v9(101.02,8.19) 100.96,8.26 100.96,10.54 102.79,12.37 106.57,12.37 107.46,13.25 108.19,13.25 v2(108.39,13.05)
  L3SGND w0.127: v11(110.35,19.38) 110.13,19.15 v10(109.83,19.15)
  L6SGND w0.127: v4(109.84,19.38) v11(110.35,19.38)
  L7 w0.061: v4(109.84,19.38) 110.03,19.19 110.37,18.84 110.37,14.89 110.37,14.72 108.91,13.26 108.6,13.26 v2(108.39,13.05)
  BOTTOM w0.102: D5417.1 v2(108.39,13.05)
C_SBU2: length 23.5
  L2 w0.061: JUSBC1.B8 99.15,5.48 99.15,6.4 99.43,6.68 100.29,6.68 100.76,7.15 100.76,10.62 102.7,12.57 106.49,12.57 107.37,13.45 108.14,13.45 v2(108.37,13.69)
  L3SGND w0.127: v10(109.83,18.65) 109.87,18.61 v11(110.17,18.61)
  L6SGND w0.127: v4(109.91,18.9) 109.93,18.9 110.18,18.65 110.13,18.65 110.09,18.61 110.13,18.61 110.13,18.61 v11(110.17,18.61)
  L7 w0.061: v4(109.91,18.9) 110.17,18.64 110.17,14.81 108.83,13.46 108.6,13.46 v2(108.37,13.69)
  BOTTOM w0.102: v2(108.37,13.69) 108.14,13.91 D5418.1
C_USB_B_N: length 12.7
  L3SGND w0.127: v11(109.54,18.21) 109.54,18.44 109.33,18.65 v10(109.32,18.65)
  L6SGND w0.127: v11(109.54,18.21) 109.61,18.28 109.61,18.63 109.52,18.72 v4(109.33,18.72)
  L7 w0.061: v4(109.33,18.72) 109.33,16.42 107.56,14.65 102.55,14.65 102.34,14.44 102.34,13.82 102.02,13.51 101.85,13.51 v5(101.84,13.49)
C_USB_B_P: length 12.6
  L3SGND w0.127: v10(109.32,19.15) 109.45,19.29 v11(109.45,19.64)
  L6SGND w0.127: v4(109.45,19.13) v11(109.45,19.64)
  L7 w0.061: v5(102.6,13.49) 102.54,13.56 102.54,14.36 102.63,14.45 107.65,14.45 109.53,16.34 109.53,18.4 109.62,18.49 109.62,18.96 v4(109.45,19.13)
C_USB_T_N: length 12.9
  L3SGND w0.127: v10(108.83,18.65) v11(108.83,18.21)
  L6SGND w0.127: v4(108.83,18.64) v11(108.83,18.21)
  L7 w0.061: v4(108.83,18.64) 108.61,18.85 108.44,18.85 108.33,18.75 108.33,18.01 105.51,15.18 101.35,15.18 100.63,14.47 100.63,13.51 100.75,13.39 100.92,13.39 v5(101.03,13.49)
C_USB_T_P: length 12.8
  L3SGND w0.127: v10(108.83,19.15) 108.88,19.2 v11(108.88,19.6)
  L6SGND w0.127: v4(108.88,19.15) v11(108.88,19.6)
  L7 w0.061: v5(100.26,13.49) 100.43,13.66 100.43,14.55 101.26,15.38 105.43,15.38 108.13,18.09 108.13,18.83 108.35,19.05 108.78,19.05 v4(108.88,19.15)
CAM_1_PWRDWN: length 76.9
  TOP w0.114: R2508.1 108.77,193.11 v1(108.77,191.97) v9(108.77,191.53)
  L2 w0.061: v10(71.49,187.07) 71.49,187.65 72.6,188.77 80.09,188.77 81.87,190.54 87.43,190.54 87.49,190.6 88.4,190.6 88.81,191.01 88.81,191.23 90.18,192.6 104.8,192.6 104.95,192.45 105.71,191.68 106.44,191.68 106.59,191.53 v9(108.77,191.53)
  L3SGND w0.127: v10(71.49,187.07) 71.27,187.07 v11(71,187.33)
  L5 w0.076: v4(79.31,177.24) 79.31,181.5 79.08,181.73 79.08,184.45 78.19,185.34 76.41,185.34 76.03,185.72 73.93,185.72 72.1,187.55 71.22,187.55 v11(71,187.33)
  L6SGND w0.127: v5(70.62,187.4) 70.94,187.4 v11(71,187.33)
  L7 w0.06: v4(79.31,177.24) 79.16,177.08 78.46,177.08 78.35,176.98 78.35,176.98 77.89,176.53 77.89,176.34 76.15,174.6 76.15,174.02 76.02,173.9 75.42,173.9 74.58,173.05 74.58,171.59 74.49,171.5 74.49,170.58 74.31,170.4 74.31,169.77 74.08,169.55 v8(74.08,169.43)
  BOTTOM w0.114: CAMR1.22 70.29,189.75 69.25,188.72 69.25,188 69.85,187.4 v5(70.62,187.4)
CAM_2_LSM: length 4.7
  TOP w0.114: CAMF1.3 97.54,189.7 96.71,188.87 95.78,188.87 95.33,189.33 R2504.1 94.91,189.33 94.52,188.95 v1(94.09,188.95)
CAM_2_PWRDWN: length 58.7
  TOP w0.114: v9(107.43,185.77) 107.43,186.3 109.41,188.29 v1(109.41,190.62) 109.41,192.91 R2502.2 ; CAMF1.4 97.84,188.27 v9(97.9,188.34)
  L2 w0.061: v9(107.43,185.77) 107.37,185.71 107.37,185.21 106.93,184.78 104.52,184.78 104.09,184.35 100.12,184.35 99.09,185.38 99.09,185.73 98.89,185.94 98.89,187.45 98,188.34 v9(97.9,188.34) 97.59,188.34 96.85,189.08 94.19,189.08 94.19,189.07 v10(94.11,189.15)
  L3SGND w0.127: v10(94.11,189.15) 93.98,189.28 v11(93.98,189.48)
  L5 w0.076: v11(93.98,189.48) 93.98,189.15 91.67,186.84 90.11,186.84 89.53,186.26 88.42,186.26 84.39,182.23 84.19,182.23 84.02,182.06 84.02,181.86 83.86,181.7 83.86,179.88 83.23,179.25 83.23,177.55 83.27,177.51 v4(83.27,177.36)
  L7 w0.061: v4(83.27,177.36) 80.62,177.36 80.21,177.77 78.64,177.77 78.21,177.33 78.14,177.33 77.46,176.65 77.05,176.65 73.88,173.48 73.88,171.69 74.05,171.53 v8(74.05,171.17)
CAMERA_1_RESET#_R: length 3.2
  TOP w0.114: U2501.2 107.94,196.01 107.76,195.83 R2508.2 107.45,194.69 107.4,194.64 107.4,194.41 107,194 v1(107,193.82)
CAMERA_LED_R: length 3.5
  TOP w0.254: R2502.1 v1(110.05,194.11) 110.87,194.92 110.87,195.72 110.58,196.01 U2501.5
CAMERA_LED_R1: length 4.9
  TOP w0.254: R2501.2 110.97,196.66 U2501.6 109.83,196.66 109.49,196.31 109.49,195.98 108.86,195.36 U2501.3 108.38,194.35 v1(108.55,194.19)
CAMERA_LED_R2: length 7.8
  TOP w0.254: v1(113.4,197.07) 113.12,197.35 112.51,197.35 112.05,196.9 R2501.1 111.24,197.68 108.84,197.68 CLED1.K
CAMF_AGND: length 4.5
  TOP w0.305: v1(94.02,190.7) 94.52,190.19 R2503.2 95.21,190.19 95.41,189.99 95.41,189.72 95.92,189.21 96.57,189.21 96.94,189.58 CAMF1.1
CC1: length 20.1
  TOP w0.254: C2911.1 108.95,17.5 108.95,17.85 109.32,18.22 110,18.22 110.09,18.31 110.11,18.31 110.33,18.52 U2901.L9 U2901.K9
  TOP w0.305: 99.05,8.45 99.28,8.22 JUSBC1.A5 ; C2911.1 108.98,16.84
  TOP w0.508: 99.05,8.45 99.05,11.69 100.87,13.51 v1(103.52,13.51) 106.24,13.51 108.98,16.24 108.98,16.84
CC2: length 26.9
  TOP w0.254: C2912.1 109.46,17.5 109.46,17.7 109.6,17.84 110.16,17.84 110.25,17.93 110.27,17.93 110.83,18.48 U2901.L10 U2901.K10
  TOP w0.305: 109.51,15.83 109.51,17.06 109.43,17.13 C2912.1
  TOP w0.508: 109.51,15.83 109.76,15.57 109.76,15.57 109.84,15.49 v1(109.84,14.24) 109.84,13.33 106.67,10.15 104.3,10.15 v10(103.69,9.55)
  L2 w0.099: JUSBC1.B5 100.9,5.47 100.9,6.55
  L2 w0.254: 102.87,8.36 102.87,7.12 102.55,6.8 101.15,6.8 100.9,6.55
  L2 w0.508: 102.87,8.36 103.69,9.19 v10(103.69,9.55)
  L3SGND w0.099: JUSBC1.B5 100.9,5.47 100.9,6.55
  L3SGND w0.254: 102.87,8.36 102.87,7.12 102.55,6.8 101.15,6.8 100.9,6.55
  L3SGND w0.508: v10(103.69,9.55) 103.69,9.19 102.87,8.36
CLK_I2S_MCLK: length 139.5
  L5 w0.076: v4(80.05,182.95) 80.07,182.98 80.07,185.23 83.4,188.56 83.4,189 86.17,191.76 86.57,191.76 v4(86.63,191.82) ; v4(45.48,167.15) 45.48,166.09 46.21,165.35 46.21,161.32 45.48,160.58 45.48,158.9 46.09,158.29 46.09,151.12 50.4,146.81 53.99,146.81 55.17,145.63 55.19,145.63 55.46,145.36 61.12,145.36 61.13,145.37 62,145.37 62.39,144.99 63.55,144.99 v4(65.14,143.4)
  L7 w0.061: v4(45.48,167.15) 45.48,178.51 49.18,182.21 62.1,182.21 67.21,182.21 67.41,182 67.52,181.9 67.93,181.49 67.93,181.46 68.09,181.3 68.79,181.3 69.99,182.5 70.43,182.5 79.5,182.5 79.86,182.85 79.95,182.85 v4(80.05,182.95) ; v5(103.75,195.14) 103.02,194.41 99.33,194.41 99.08,194.16 97.6,194.16 v5(97.12,193.67) 97.12,193.67 96.74,193.29 88.1,193.29 v4(86.63,191.82) ; v5(79.31,147.9) 78.77,147.36 78.16,147.36 77.77,146.97 76.89,146.97 74.89,144.97 68.51,144.97 68.4,144.86 67.43,144.86 65.98,143.4 v4(65.14,143.4)
  BOTTOM w0.114: v5(103.75,195.14) 103.62,195.14 103.51,195.25 U2001.38 ; v5(79.31,147.9) 80.98,147.9 81.7,148.62 81.7,149.07 C710.1 R728.1
CLK_I2S_MCLK_1: length 7.4
  L7 w0.061: v8(79.22,156.38) 79.22,156.37 79.3,156.37 80.57,155.1 80.57,155.07 81.14,154.51 81.14,153.39 81.07,153.32 81.07,152.76 81.37,152.46 81.37,152.23 81.14,151.99 v5(81.14,151.25)
  BOTTOM w0.114: v1(82.03,150.52) 81.29,151.25 v5(81.14,151.25)
CMP_7V+: length 3.9
  TOP w0.114: U4603.1 102.02,82.48 PR4626.1 PR4624.2 100.72,81.27 99.58,81.27 v1(99.38,81.48)
CMP_7V-: length 4.4
  TOP w0.114: v1(99.94,85.31) 100.09,85.47 101.51,85.47 101.69,85.29 PR4631.2 101.69,84.46 U4603.3 103.13,83.96 PR4630.2
COCO_ID: length 12.1
  L7 w0.06: v8(71.54,169.72) 71.62,169.8 71.9,169.8 72.02,169.92 72.19,169.92 72.3,169.8 72.47,169.8 72.59,169.92 72.75,169.92 72.87,169.8 73.04,169.8 73.15,169.92 73.32,169.92 73.44,169.8 73.6,169.8 73.72,169.92 73.72,170.25 74.25,170.78 74.25,171.65 74.34,171.75 74.34,173.28 74.48,173.43
  L7 w0.061: 74.48,173.43 74.48,173.83 76.79,176.14 v5(77.08,176.14)
  BOTTOM w0.114: v1(76.87,175.25) 77.08,175.46 v5(77.08,176.14) R741.2
CODEC_AVDD: length 4.7
  BOTTOM w0.203: 98.16,198.5 U2001.6
  BOTTOM w0.305: R2018.1 C2013.1 95.29,197.18 C2012.1 96.33,197.18 96.96,197.81 97.47,197.81 98.16,198.5
CODEC_CPN1: length 2.6
  BOTTOM w0.114: v1(105.32,203.22) 104.91,202.81 C2008.2 104.36,202.62 104.35,202.62 104.11,202.38 103.91,202.38 103.51,201.98 U2001.23
CODEC_CPN2: length 2.3
  BOTTOM w0.114: v1(106.59,201.24) 105.68,201.24 C2009.2 105.65,201.22 104.93,200.5 U2001.26
CODEC_CPP1: length 1.4
  BOTTOM w0.114: U2001.22 103.11,201.9 103.23,202.02 103.23,202.03 103.34,202.14 103.35,202.14 103.64,202.43 C2008.1
CODEC_CPP2: length 3.3
  BOTTOM w0.114: U2001.25 104.67,201.2 C2009.1 105.8,202.33 v1(107.17,202.33)
CODEC_CPVDD: length 3.7
  BOTTOM w0.203: U2001.21 102.71,202 102.92,202.21
  BOTTOM w0.305: R2020.1 C2017.1 103.67,203.5 C2016.1 103.01,203.4 103.01,203 103.17,202.84 103.17,202.46 102.92,202.21
CODEC_CPVEE: length 2.7
  BOTTOM w0.203: U2001.27 105.58,200.1 C2001.2 105.83,200.3 106.26,199.87 106.51,199.87 v1(106.92,199.46)
CODEC_CPVPP: length 2.1
  BOTTOM w0.203: U2001.20 102.31,202.26 102.71,202.65 v1(102.71,202.65) 102.71,202.76 102.63,202.85 102.63,203.3 C2002.2
CODEC_CPVREF: length 1.9
  BOTTOM w0.114: R2014.2 100.7,202.6 100.94,202.36 100.94,202.16 101.11,201.99 U2001.17
CODEC_DACREF: length 1.8
  BOTTOM w0.114: C2003.2 97.54,198.9 U2001.7
CODEC_DBVDD: length 3.3
  BOTTOM w0.203: 98.06,196.54 98.41,196.9 U2001.2
  BOTTOM w0.305: 98.06,196.54 C2015.1 C2014.1 R2019.1
CODEC_DCVDD: length 2
  BOTTOM w0.203: C2020.1 97.6,196.62 98.28,197.3 U2001.3
CODEC_DMIC_1_DATA: length 3.4
  BOTTOM w0.114: R2005.1 97.09,197.45 97.6,197.45 98.24,198.1 U2001.5
CODEC_DMIC_SCL: length 5.9
  BOTTOM w0.114: R2001.2 v1(104.33,192.17) 104.07,192.17 103.24,193.01 102.81,193.01 102.15,193.66 102.15,194.32 101.91,194.56 U2001.42
CODEC_IN2P: length 1.7
  BOTTOM w0.114: U2001.4 98.17,197.7 97.66,197.18 97.4,197.18 TP2001.1
CODEC_MICVDD: length 2
  BOTTOM w0.203: U2001.15 100.31,202.26 99.96,202.61 v1(99.94,202.61)
  BOTTOM w0.508: v1(99.94,202.61) 99.35,203.19 99.35,203.27
CODEC_SPKVDD: length 1
  BOTTOM w0.508: v1(99,193.98) 99.06,194.05 R2023.2
CODEC_VREF2: length 1.7
  BOTTOM w0.114: C2007.1 97.2,199.3 U2001.8
CORE_PWROK: length 87.5
  L2 w0.061: v10(88.39,155.13) 88.38,155.11 88.31,155.11 86.27,153.07 86.27,152.99 82.93,149.65 80.45,149.65 75.87,145.07 74.66,145.07 v10(72.73,143.15)
  L3SGND w0.127: v11(88.07,155.34) 88.19,155.23 88.29,155.23 v10(88.39,155.13) ; v11(72.68,142.69) 72.68,143.1 v10(72.73,143.15) ; v11(100.06,180.14) v10(100.06,180.59)
  L5 w0.076: v8(99.43,176.13) 99.13,176.13 97.9,174.9 97.32,174.9 96.64,174.22 95.11,174.22 94.97,174.36 94.34,174.36 93.42,173.44 93.42,173.42 93.23,173.24 91.72,173.24 90.79,172.31 88.38,172.31 86.98,170.91 86.98,169.88 88.39,168.47 88.39,168.43 88.56,168.26 88.73,168.26 88.95,168.03 88.95,168 89.21,167.74 v4(89.24,167.74) ; v4(87.18,157.6) 87.18,157.02 87.69,156.51 87.69,155.87 87.73,155.84 87.73,155.69 v11(88.07,155.34) ; v5(56.32,143.23) 56.77,143.67 62.49,143.67 62.98,143.19 64.47,143.19 64.74,142.92 65.69,142.92 66.18,143.42 67.06,143.42 69.15,143.42 69.16,143.42 69.21,143.42 69.46,143.67 71.7,143.67 v11(72.68,142.69)
  L6SGND w0.06: v11(100.06,180.14) 100.06,180.03 100.03,180 100.03,178.49 99.92,178.39 99.92,177.53 100.03,177.42 100.03,176.73 v8(99.43,176.13)
  L6SGND w0.127: v4(87.9,155.65) 87.92,155.65 88.11,155.46 88.11,155.38 v11(88.07,155.34)
  L7 w0.06: v8(80.88,159.25) 80.91,159.28 81.37,159.28 81.57,159.08 81.57,159.02 81.87,158.72 82.71,158.72 82.87,158.57 83.56,158.57 83.56,158.57 83.8,158.57 83.8,158.57 83.81,158.57 84.11,158.26 85.13,158.26 85.53,157.86 85.55,157.86 86.2,157.21 86.2,157.19 86.78,156.62 86.8,156.62 86.88,156.54 87.18,156.54 87.87,155.84 87.87,155.67 v4(87.9,155.65)
  L7 w0.061: v4(87.18,157.6) 87.36,157.78 87.36,162.22 88.27,163.13 88.27,163.13 89.29,164.15 89.29,167.69 v4(89.24,167.74)
  BOTTOM w0.114: v1(57.52,144.29) 56.98,144.29 56.33,143.64 XDP1.25
CPU_USB_OC#: length 176.1
  L5 w0.076: v4(107.2,34.49) 107.01,34.3 107.01,31.28 107.75,30.55 107.75,26.83 106.44,25.53 106.44,24.01 107.81,22.65 107.81,20.26 106.74,19.2 v5(106.74,19.11) ; v4(88.58,134.97) 88.45,135.1 88.45,135.35 86.41,137.39 86.41,138.78 84.81,140.38 84.55,140.38 84.26,140.66 84.26,141.17 83.72,141.71 83.13,141.71 81.76,143.09 79.67,143.09 77.05,145.71 77.05,146.55 75.47,148.12 75.47,148.2 v5(75.4,148.28)
  L7 w0.06: v8(75.5,157.27) 75.5,156.98 75.3,156.78 75.3,156.62 75.42,156.5 75.42,156.28 75.34,156.2 75.34,155.9 75.23,155.79
  L7 w0.061: v4(107.2,34.49) 105.37,36.32 105.37,41.11 99.76,46.72 99.76,51.36 99.76,52.48 96.41,55.82 96.41,56.92 96.83,57.34 96.83,61.87 97.14,62.19 97.25,62.29 97.25,69.09 98,69.84 98,69.84 100,71.84 100,73.31 100,73.46 100,73.89 100,79.12 100,80.01 100,80.01 100,85.46 99.86,85.6 99.86,85.6 99.86,87.9 102.13,90.17 102.13,91.67 102.26,91.79 102.26,91.85 103.64,93.23 103.64,119.98 107.22,123.57 v5(107.22,127.5) 107.22,131.44 105.91,132.75 105.91,134.16 103.72,136.35 100.84,136.35 100.65,136.54 100.48,136.54 99.89,137.13 90.59,137.13 88.58,135.12 v4(88.58,134.97) ; 75.23,155.79 75.23,153.56 75.63,153.15 75.63,148.93 75.4,148.69 v5(75.4,148.28)
DBG_JTAG_CLK: length 22.1
  TOP w0.114: U1704.C10 89.24,36.63 v9(88.88,36.27) ; ECDBG1.7 87.63,18.96 v9(87.64,18.97)
  L2 w0.061: v9(87.64,18.97) 88.1,19.43 88.1,20.71 86.55,22.26 86.55,22.62 86.39,22.78 86.03,22.78 v12(85.33,23.48) 85.1,23.71 85.1,28.57 85.1,28.72 85.1,29.01 85.1,29.11 86.75,30.76 86.75,31.34 86.75,32.16 86.85,32.27 86.95,32.37 86.96,32.37 88.88,34.3 v9(88.88,36.27)
DBG_JTAG_RST#: length 3.8
  TOP w0.114: U1704.A10 87.64,36.82 86.42,38.04 C1722.1 86.04,38.4 86.12,38.48 R1769.1 86.12,39.01 86,39.12 v1(86,39.47)
DBG_JTAG_TDI: length 22.2
  TOP w0.114: ECDBG1.9 87.61,19.96 v9(87.64,19.98) ; U1704.C11 88.86,36.91 v9(88.86,36.9)
  L2 w0.061: v9(88.86,36.9) 88.38,36.9 87.89,36.41 87.89,36.18 87.89,36.17 87.89,33.8 86.81,32.72 86.71,32.62 86.71,32.62 86.4,32.31 86.35,32.26 86.35,31.25 86.4,31.2 86.4,30.9 84.75,29.25 84.75,29.15 84.75,29.15 84.75,28.57 84.75,28.43 84.75,28.42 84.75,23.83 84.75,22.5 v12(84.92,22.32) 84.92,22.05 86.13,20.85 86.57,20.85 87.44,19.98 v9(87.64,19.98)
DBG_JTAG_TDO: length 26.6
  TOP w0.114: v9(87.64,18.46) 87.64,18.46 ECDBG1.6
  L2 w0.061: v9(87.64,18.46) 88.28,19.1 v12(88.28,21.33) 87.73,21.33 86.83,22.22 86.83,22.77 85.27,24.33 85.27,29.04 86.93,30.69 86.93,32.02 88.99,34.08 89.67,34.08 90.05,34.46 90.05,34.7 90.33,34.98 90.33,36.75 90.1,36.97 90.04,36.97 89.58,37.43 v9(87.64,37.43)
DBG_JTAG_TMS: length 21.4
  TOP w0.114: ECDBG1.8 87.62,19.46 v9(87.64,19.48) ; U1704.B10 88.18,36.32 v9(88.18,36.29)
  L2 w0.061: v9(87.64,19.48) 87.64,19.58 87.93,19.87 87.93,20.64 87.63,20.93 87.43,20.93 86.27,22.09 v12(86.27,22.4) 86.17,22.5 85.61,22.5 84.92,23.19 84.92,28.5 84.92,28.64 84.92,29.08 84.92,29.18 86.57,30.83 86.57,31.27 86.57,32.24 86.57,32.24 86.78,32.44 86.88,32.55 88.07,33.73 88.07,36.18 v9(88.18,36.29)
DBG_MSCLK: length 24.8
  TOP w0.114: ECDBG1.5 87.64,17.96 v9(87.64,17.95)
  L2 w0.061: v9(90.84,36.63) 90.84,35.85 90.66,35.67 90.66,35.06 90.4,34.79 90.39,34.79 90.22,34.63 90.22,34.39 89.74,33.9 89.06,33.9 87.1,31.94 87.1,30.61 85.45,28.96 85.45,24.41 86.3,23.55 86.9,23.55 v12(86.94,23.52) 86.94,23.18 87.06,23.06 87.06,22.25 87.67,21.63 88.38,21.63 88.56,21.45 88.56,20.96 88.45,20.85 88.45,20.56 88.45,18.76 v9(87.64,17.95)
DBG_MSDAT: length 25.8
  TOP w0.114: ECDBG1.4 87.63,17.46 v9(87.64,17.44)
  L2 w0.061: v9(90.04,36.63) 89.49,37.19 88.42,37.19 87.72,36.48 87.72,33.88 86.17,32.33 86.17,31.69 85.69,31.21 85.69,30.89 84.95,30.15 84.95,29.7 84.57,29.33 84.57,29.22 84.57,29.22 84.57,28.5 84.57,28.35 84.57,28.35 84.57,23.9 84.57,23.9 84.57,23.61 84.57,23.61 84.57,23.18 84.57,23.18 84.57,22.6 84.57,22.46 84.57,22.45 84.57,22.15 86.14,20.58 86.44,20.58 86.59,20.58 86.88,20.3 86.88,18.21 v9(87.64,17.44)
DBG_PIN1: length 2.7
  TOP w0.114: ECDBG1.10 86.61,21.24 86.81,21.44 v1(87.06,21.44) 87.35,21.44 87.64,21.15 R1701.2
DBG_RESETBTN#: length 7.1
  L5 w0.06: v5(76.62,152.52) 76.62,152.93 75.39,154.15 75.39,157.54 75.13,157.8 75.13,158.6 74.93,158.8 v8(74.93,158.96)
DBG_UART_TX: length 26.3
  TOP w0.114: ECDBG1.3 87.6,16.96 v9(87.64,16.91)
  L2 w0.061: v9(87.64,16.91) 88.12,16.91 88.51,17.29 88.51,18.47 88.63,18.59 88.63,20.49 88.63,20.49 88.63,20.78 88.74,20.89 88.74,21.52 88.45,21.81 87.75,21.81 87.29,22.27 87.29,22.78 87.28,22.79 87.28,23.02 87.29,23.03 87.29,23.7 87.15,23.83 87.15,23.85 86.61,24.39 86.03,24.39 v12(85.79,24.63) 85.79,24.7 85.62,24.86 85.62,28.89 87.28,30.54 87.28,31.87 89.12,33.72 90.28,33.72 90.84,34.27 90.84,35.6 91.12,35.89 91.59,35.89 v9(91.64,35.83)
DCIN_DROP_DET#: length 67.7
  TOP w0.114: PU4601.14 95.67,94.57 v9(95.59,94.48)
  L2 w0.061: v9(95.59,94.48) 95.59,94.32 95.31,94.05 95.31,92.9 95.75,92.47 95.75,91.14 95.26,90.65 v12(95.26,90.14) 95.26,89.05 v9(95.13,88.92) 95.13,88.75 96.62,87.27 96.62,85.3 95.4,84.08 95.4,80.55 95.43,80.52 95.43,76.67 92.47,73.71 92.47,70.73 91.27,69.53 91.27,68.96 91.62,68.61 91.62,62.01 92.24,61.39 92.24,57.79 90.72,56.27 90.72,54.06 89.15,52.48 89.15,51.84 88.94,51.63 88.73,51.63 87.9,50.8 87.9,49.86 87.77,49.73 87.77,48.28 88.46,47.59 88.46,45.82 87.24,44.6 87.24,42.76 88.11,41.88 88.36,41.88 89.77,40.46 89.77,39.79 89.85,39.72 89.85,39.7 90.7,38.85 90.86,38.69 91.03,38.69 91.1,38.63 92.12,38.63 92.49,38.25 92.66,38.25 93.24,37.67 v9(93.24,37.43)
DCIN_OFF: length 3.3
  TOP w0.508: PR4619.1 v9(87.57,83.38)
  L2 w0.305: v9(85.84,84.59) 85.84,84.02 86.47,83.38 v9(87.57,83.38)
DCIN_OFF#: length 2.7
  TOP w0.114: PQ4601.5 85.84,82.32 v1(86.55,81.61) 86.8,81.86 PR4634.2
DCIN_ON: length 3.9
  TOP w0.114: PU4604.4 86.74,85.46 PR4615.1 PR4613.1 85.19,85.71 PQ4601.3
DCIN_OP_VCC: length 12.9
  TOP w0.254: C5712.1 95.69,88.31 PR4645.1 95.69,89.02 95.39,89.33 94.47,89.33 v1(94.35,89.2) ; C5712.1 95.64,87.79 U4602.8 96.35,87.12 PR4643.1 PR4642.1 98.13,87.12 99.5,85.75 99.5,85.13 99.86,84.78 100.72,84.78 PR4631.1 100.96,84.75 100.96,83.29 U4603.5 ; C5712.1 96.38,88.26 U1705.B1
DDI0_AUXN: length 118.5
  L3SGND w0.127: v11(108.53,70.71) 108.42,70.61 v10(108.06,70.61)
  L5 w0.066: v8(80.88,167.74) 80.8,167.66 80.59,167.66 80.49,167.76 80.49,167.98 80.69,168.18 81.41,168.18 81.99,167.59 83.21,167.59 92.95,157.85 94.37,157.85 97.01,157.85 105.58,149.27 105.58,138.04 108.27,135.35 108.27,135.02 108.8,134.5 109.05,134.24 109.05,133.41 109.05,131.96 109.05,131.96 109.05,123.4 108.05,122.4 108.05,115.51 106.26,113.73 106.26,93.67 106.62,93.32 106.62,80.94 104.1,78.42 104.1,75.02 104.1,74.91 107.87,71.13 108.11,71.13 v11(108.53,70.71)
DDI0_AUXP: length 118.5
  L3SGND w0.127: v10(108.06,71.11) 108.36,71.11 v11(108.52,71.27)
  L5 w0.066: v8(80.59,167.45) 80.35,167.7 80.35,168.04 80.63,168.32 81.47,168.32 82.05,167.74 83.26,167.74 93.01,157.99 94.31,157.99 97.07,157.99 105.72,149.33 105.72,138.09 108.41,135.41 108.41,135.08 108.85,134.64 109.19,134.3 109.19,133.47 109.19,123.34 108.19,122.34 108.19,115.46 106.4,113.67 106.4,93.73 106.76,93.38 106.76,80.88 104.24,78.36 104.24,74.97 107.93,71.27 v11(108.52,71.27)
DDI0_HDP#: length 185.9
  L3SGND w0.127: v10(96.07,67.74) v11(96.51,67.74)
  L5 w0.076: v4(99.83,135.88) 99.8,135.92 99.8,136.38 99.73,136.45 99.73,136.58 99.72,136.59 99.72,137.34 99.73,137.35 99.73,141.2 99.4,141.54 99.39,141.54 v4(99.25,141.68) ; v4(83.4,176.19) 83.89,176.68 83.89,177.03 83.95,177.08 83.95,177.1 84.59,177.74 85.12,177.74 85.35,177.97 85.6,177.97 86.78,179.15 86.78,179.25 87.12,179.59 87.12,179.73 89.46,182.07 89.46,182.36 89.46,182.83 91.92,185.29 92.82,185.29 95.36,187.83 95.37,187.84 95.42,187.89 95.9,187.89 96.01,187.89 96.01,187.89 96.17,187.89 96.17,187.89 96.32,187.89 96.48,187.89 97.11,187.89 97.12,187.89 97.86,187.89 98.08,188.11 106.12,188.11 106.25,187.98 106.44,187.98 107.8,186.63 107.8,177.46 108.56,176.7 108.56,171.47 108.6,171.44 108.6,170.85 108.28,170.53 108.28,152.92 110.29,150.91 110.29,150.68 110.29,142.75 110.22,142.69 110.22,141.66 110.02,141.46 v4(110.02,141.12)
  L6SGND w0.127: v4(96.51,68.19) v11(96.51,67.74)
  L7 w0.061: v4(96.51,68.19) 96.51,68.3 96.61,68.4 96.61,69.19 97.78,70.37 99.48,72.06 99.48,73.09 99.48,73.24 99.48,74.11 99.48,79.34 99.48,79.63 99.48,85.24 99.33,85.38 99.33,88.11 101.6,90.39 101.6,91.89 101.73,92.01 101.73,92.07 101.94,92.27 102.04,92.38 102.04,92.38 103.03,93.37 103.03,120.13 106.44,123.54 106.44,131.48 105.39,132.53 105.39,133.94 103.65,135.68 103.55,135.78 99.94,135.78 v4(99.83,135.88) ; v4(99.25,141.68) 99.55,141.38 109.76,141.38 v4(110.02,141.12) ; v8(75.78,171.13) 75.78,171.24 75.75,171.28 75.75,171.62 76.08,171.95 76.08,172.01 76.08,172.02 76.08,173.6 77.02,174.54 77.02,174.87 77.87,175.71 78.06,175.71 78.37,176.02 78.43,176.02 78.83,176.43 79.24,176.43 79.28,176.47 v5(79.44,176.47) 79.59,176.47 79.85,176.22 80.3,176.22 80.45,176.07 82.4,176.07 82.52,176.19 v4(83.4,176.19)
  BOTTOM w0.114: R410.2 v1(79.89,177.31) 79.89,176.93 v5(79.44,176.47)
DDI0_PLLOBS_N: length 6.1
  L7 w0.061: v5(83.53,172.71) 83.24,172.43 83.24,170.6 82.31,169.67 82.31,169.43 80.98,168.1 80.67,168.1 v8(80.59,168.02)
DDI0_PLLOBS_P: length 6.8
  L7 w0.06: 81.09,167.93 80.97,167.93 80.96,167.94 80.79,167.94 80.59,167.74 v8(80.31,167.74)
  L7 w0.061: v5(83.53,171.85) 83.44,171.77 83.44,170.52 82.51,169.59 82.51,169.35 81.09,167.93
  BOTTOM w0.102: v1(83.7,170.94) 83.53,171.11 v5(83.53,171.85)
DDI0_TX0_DN: length 117.3
  L3SGND w0.127: v10(104.61,76.47) 104.71,76.58 v11(104.71,76.98)
  L5 w0.066: v8(78.61,168.3) 78.61,168.79 79.02,169.2 79.98,169.2 80.3,169.52 82.71,169.52 93.38,158.86 97.43,158.86 106.6,149.69 106.6,138.46 108.73,136.32 108.87,136.32 109.23,136.32 109.73,135.83 110.07,135.49 110.07,133.83 110.07,122.91 109.1,121.94 109.1,115.02 107.28,113.19 107.28,94.15 107.63,93.8 107.63,77.24 106.29,75.9 105.18,75.9 104.71,76.37 v11(104.71,76.98)
DDI0_TX0_DN_ST: length 1.1
  TOP w0.102: U3102.39 104.71,75.82 C3002.2
DDI0_TX0_DP: length 117.2
  L3SGND w0.127: v10(105.12,76.47) 105.07,76.52 105.07,76.72 105.07,76.72 105.07,76.78 v11(105.27,76.98)
  L5 w0.066: v8(78.9,168.02) 79.01,168.13 79.01,168.37 78.92,168.46 78.81,168.46 78.75,168.52 78.75,168.73 79.08,169.06 80.03,169.06 80.36,169.38 82.65,169.38 93.32,158.72 97.37,158.72 106.46,149.63 106.46,138.4 108.67,136.18 108.93,136.18 108.93,136.18 109.18,136.18 109.67,135.69 109.93,135.43 109.93,133.77 109.93,131.6 109.93,131.6 109.93,122.96 108.96,122 108.96,115.08 107.14,113.25 107.14,94.09 107.49,93.74 107.49,77.3 106.24,76.04 105.24,76.04 104.85,76.43 104.85,76.57 104.94,76.65 105.19,76.65 105.27,76.73 v11(105.27,76.98)
DDI0_TX0_DP_ST: length 1.1
  TOP w0.102: U3102.38 105.21,75.82 C3001.2
DDI0_TX1_DN: length 108.3
  L3SGND w0.127: v10(103.21,76.47) 103.21,76.91 v11(103.16,76.96)
  L5 w0.066: v11(103.16,76.96) 103.37,77.17 103.37,78.36 106.15,81.14 106.15,93.12 105.83,93.45 105.83,114.03 107.54,115.75 107.54,122.51 108.61,123.58 108.61,132.14 108.61,134.06 107.83,134.84 107.83,135.17 105.1,137.91 105.1,149.14 96.83,157.41 92.77,157.41 83.11,167.08 81.32,167.08 81.19,167.21 v8(80.91,167.21)
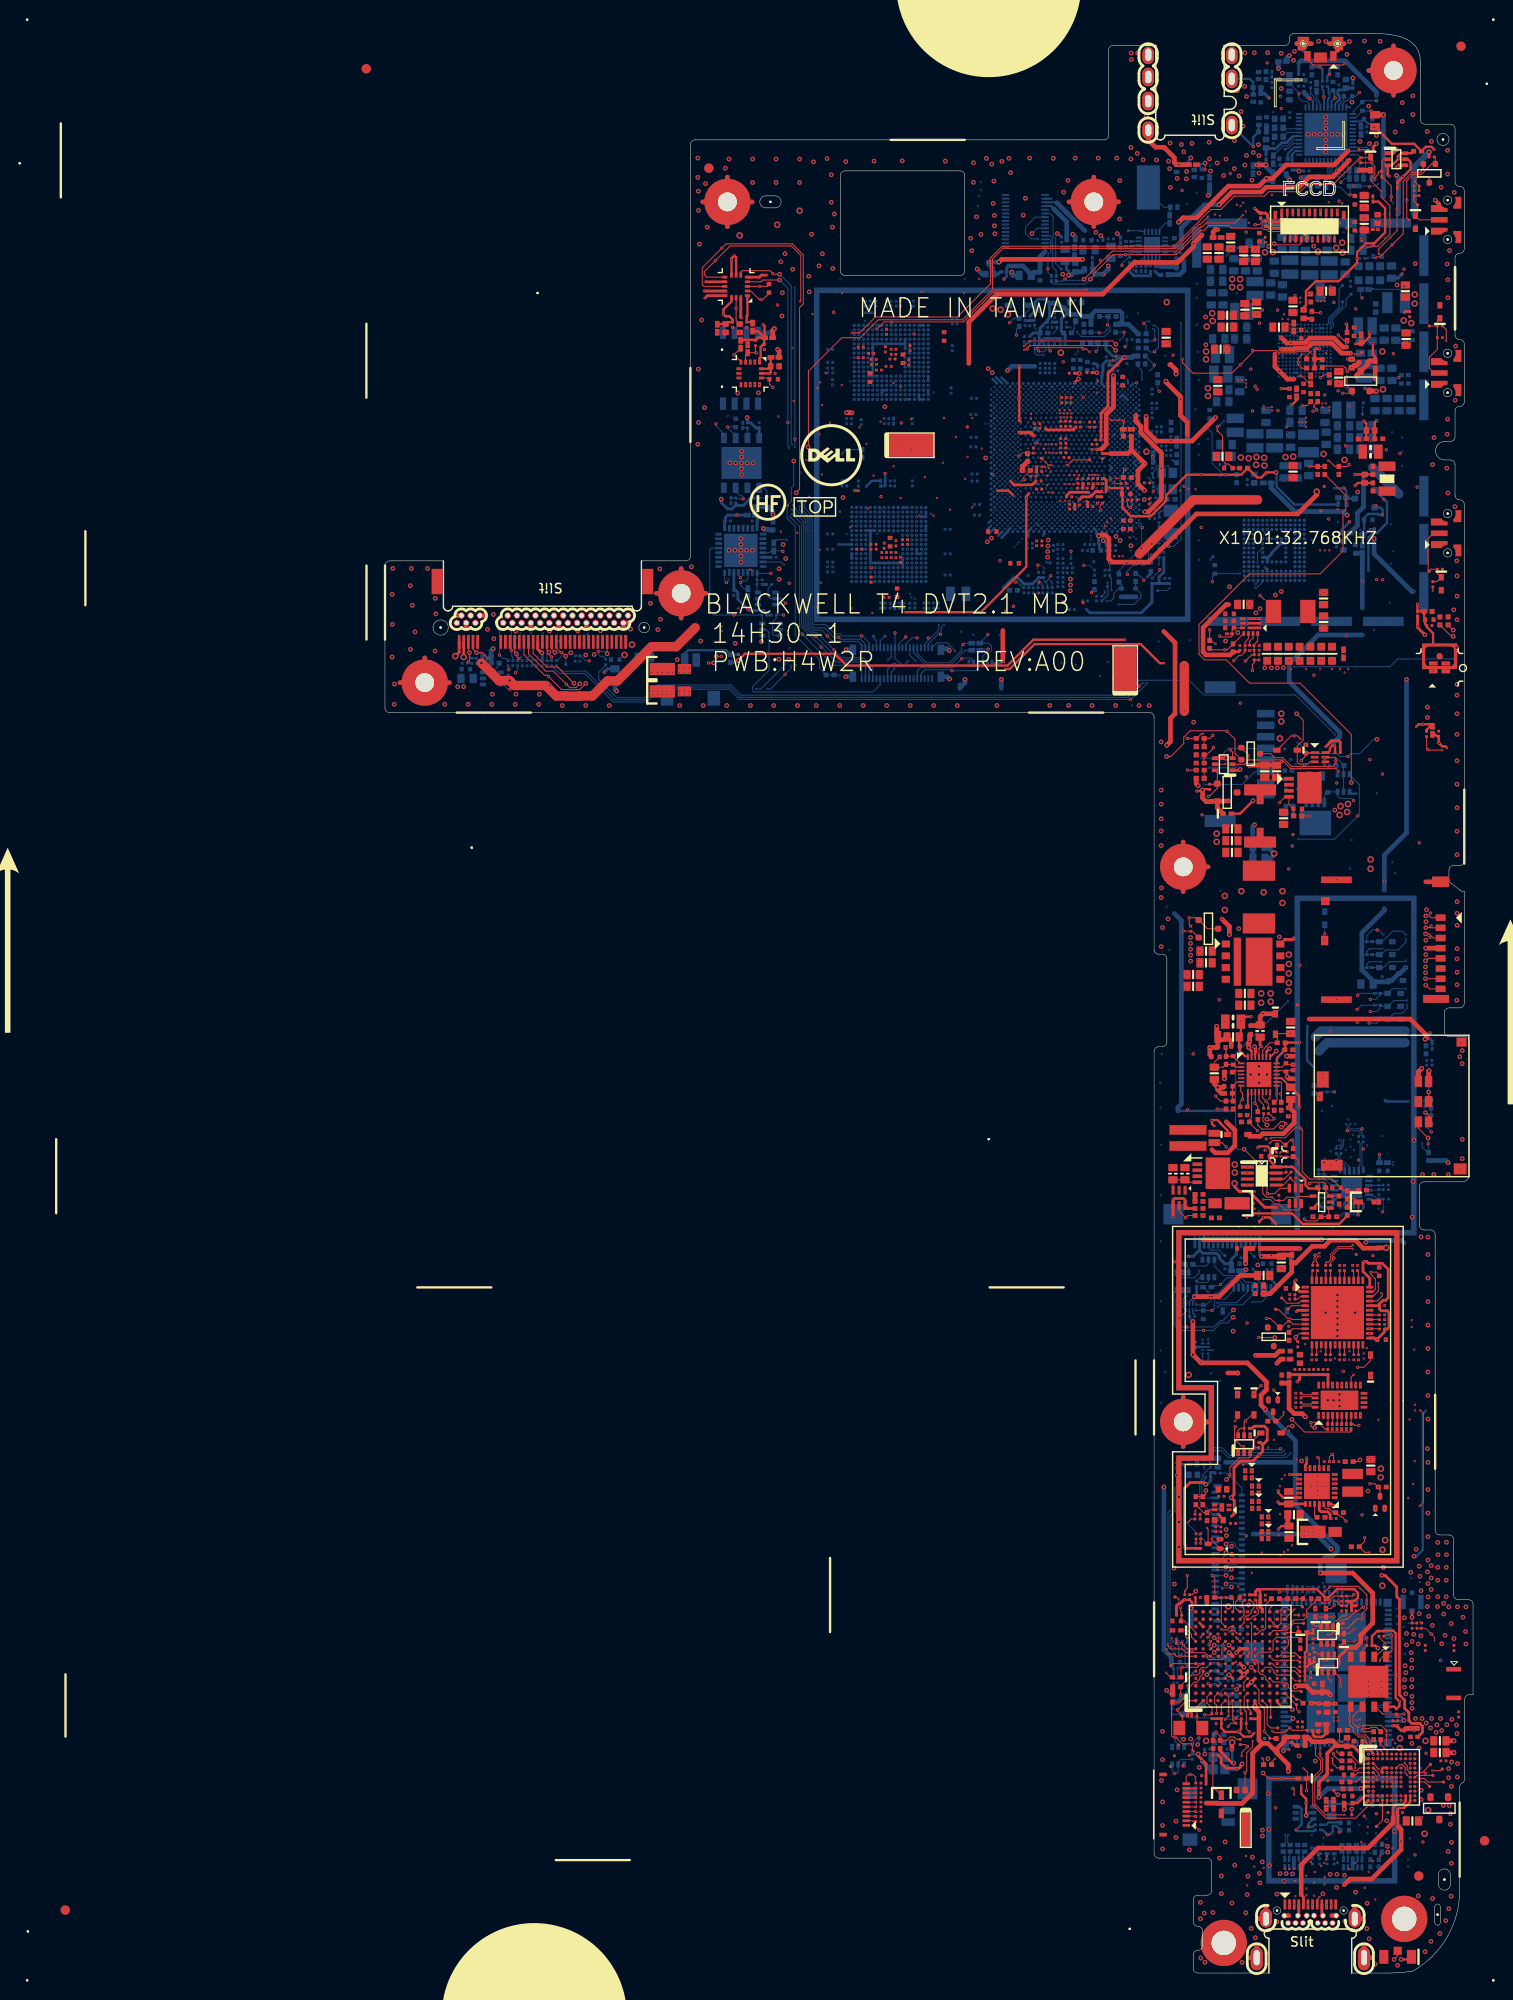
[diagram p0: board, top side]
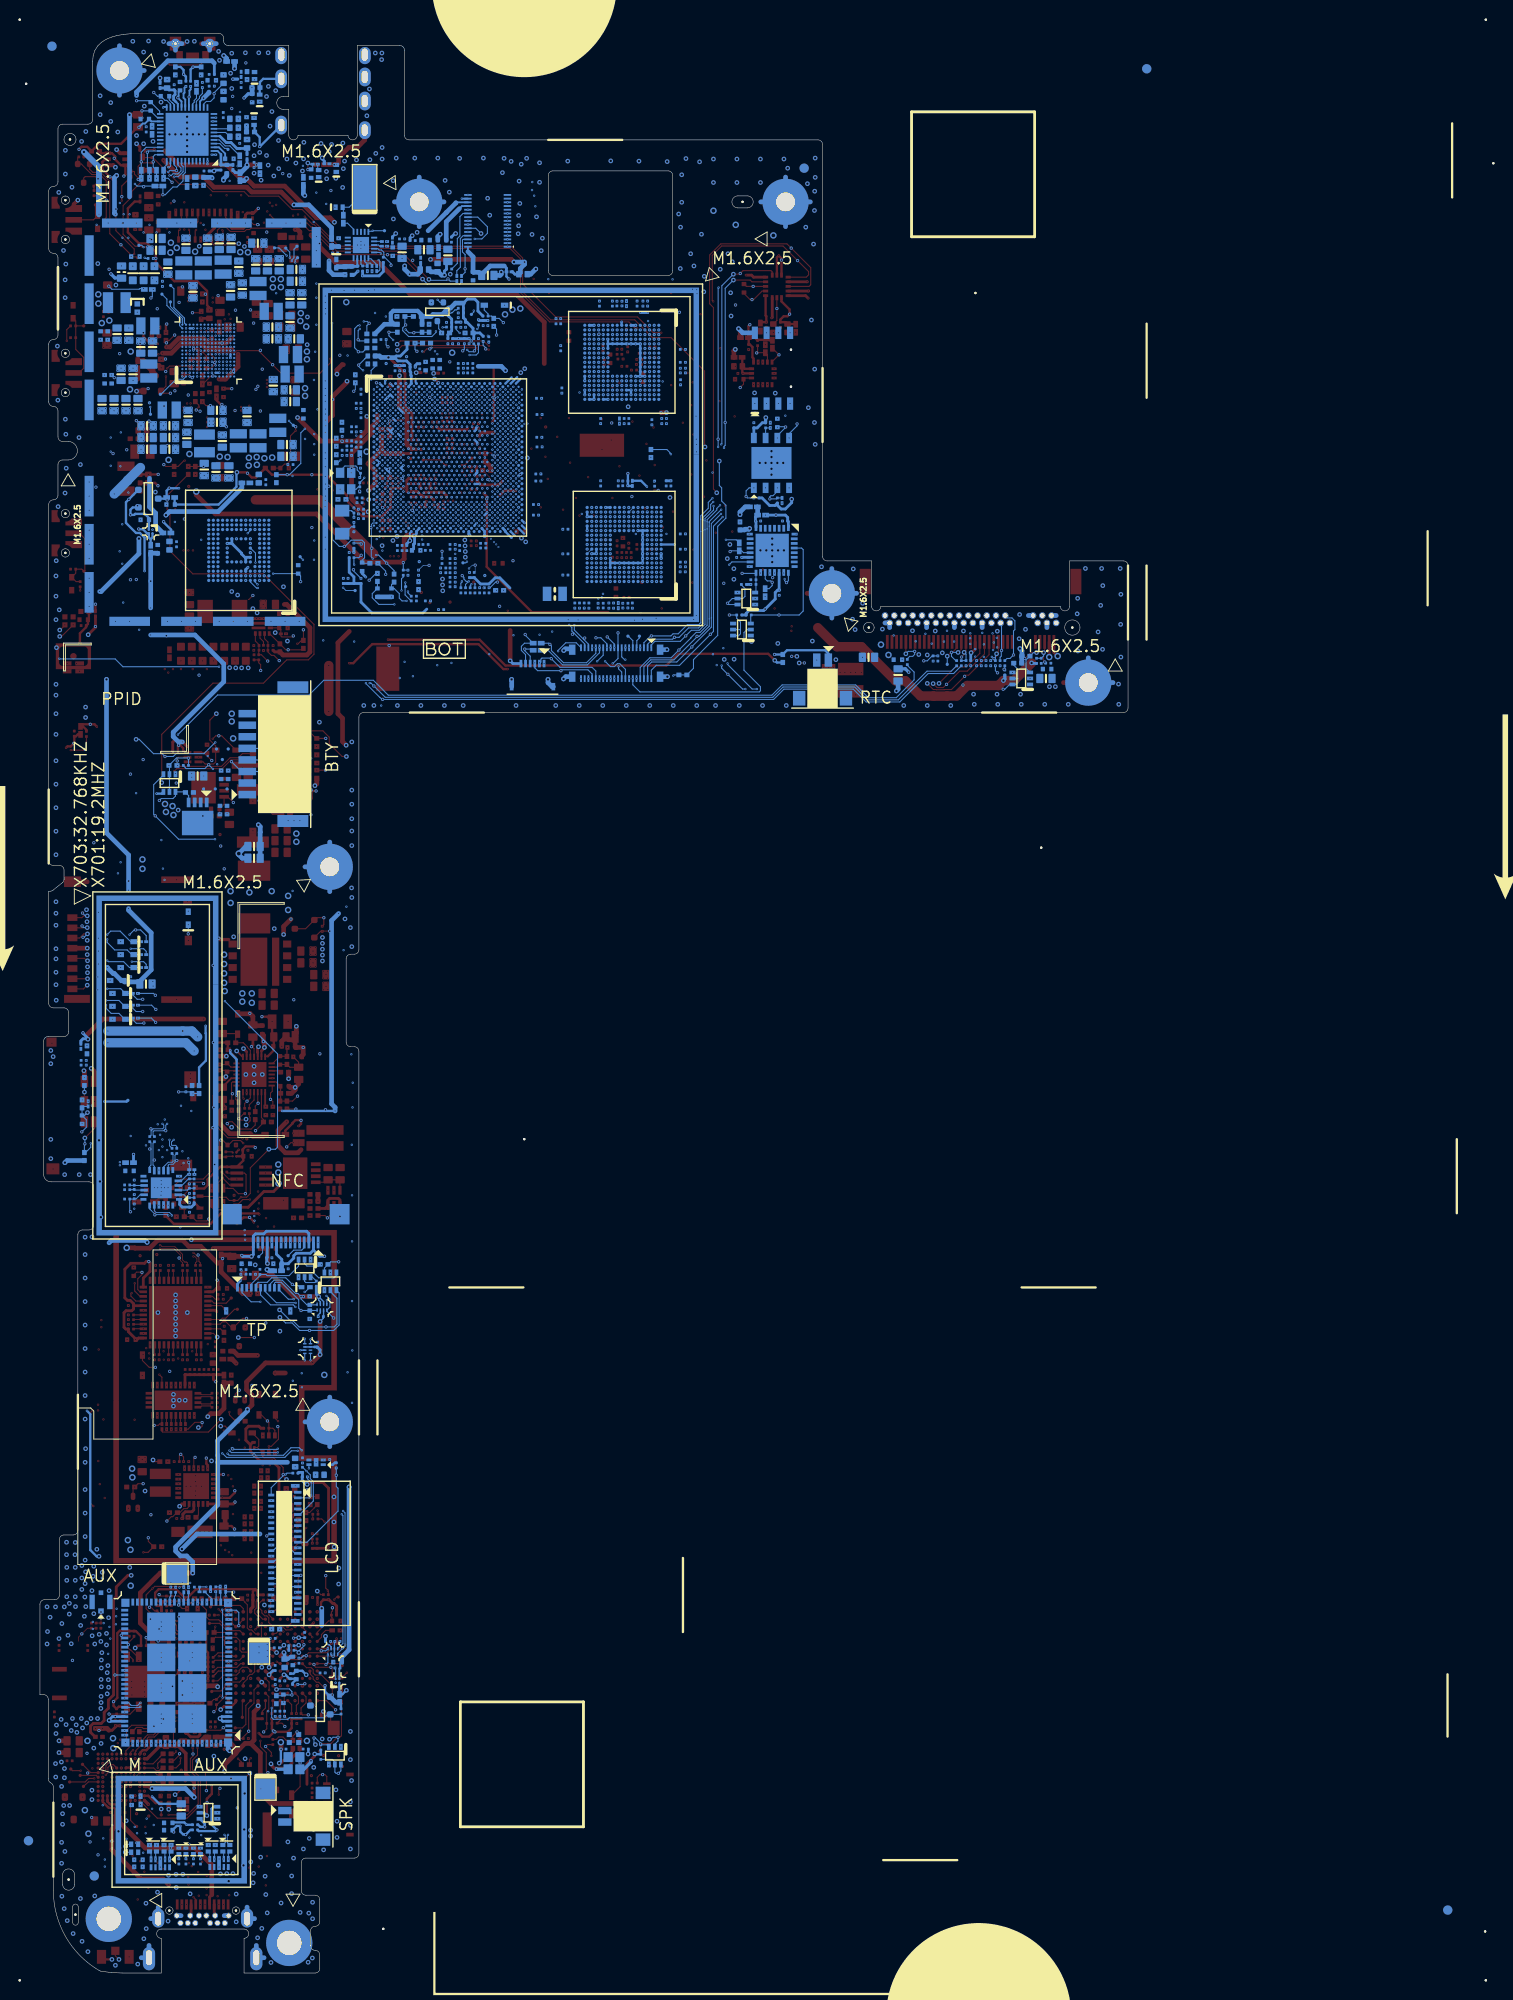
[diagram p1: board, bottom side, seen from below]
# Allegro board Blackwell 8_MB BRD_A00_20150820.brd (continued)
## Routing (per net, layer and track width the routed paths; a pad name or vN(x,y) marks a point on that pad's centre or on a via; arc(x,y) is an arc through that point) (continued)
DDI0_TX1_DN_ST: length 1.1
  TOP w0.102: U3102.42 103.21,75.91 C3004.2
DDI0_TX1_DP: length 108.3
  L3SGND w0.127: v10(103.72,76.47) v11(103.72,76.96)
  L5 w0.066: v8(81.23,167.45) 81.23,167.36 81.38,167.22 83.16,167.22 92.83,157.55 96.89,157.55 105.24,149.2 105.24,137.96 107.97,135.23 107.97,134.9 108.67,134.2 108.76,134.12 108.76,133.29 108.76,132.11 108.76,132.11 108.76,123.53 107.68,122.45 107.68,115.69 105.97,113.97 105.97,93.51 106.29,93.18 106.29,81.08 103.52,78.3 103.52,77.16 v11(103.72,76.96)
DDI0_TX1_DP_ST: length 1.1
  TOP w0.102: U3102.41 103.71,75.9 C3003.2
DDI0_TX2_DN: length 116.9
  TOP w0.102: C3006.1 101.69,76.75 101.77,76.83 101.97,76.83 102.21,77.07 102.21,77.66 103.04,78.49 104.42,78.49 104.58,78.66 v10(104.63,78.66)
  L3SGND w0.127: v11(105.09,78.66) 105.06,78.63 105.06,78.63 104.66,78.63 v10(104.63,78.66)
  L5 w0.066: v11(105.09,78.66) 105.19,78.66 105.47,78.38 105.47,78.1 105.56,78.01 106.1,78.01 107.05,78.97 107.05,93.54 106.7,93.89 106.7,113.43 107.04,113.77 108.53,115.26 108.53,120.29 108.53,122.18 109.49,123.15 109.49,131.78 109.49,135.25 108.99,135.74 108.49,135.74 106.02,138.22 106.02,149.45 97.19,158.28 94.19,158.28 93.14,158.28 82.61,168.81 80.58,168.81 79.45,167.67 79.03,167.67 78.9,167.54 v8(78.9,167.45)
DDI0_TX2_DN_ST: length 1.1
  TOP w0.102: C3006.2 101.71,75.9 U3102.45
DDI0_TX2_DP: length 117.1
  TOP w0.102: 102.42,77.26 102.42,77.57 103.13,78.28 v10(104.63,78.28) ; 102.42,77.26 v1(102.58,77.26) ; 102.42,77.26 102.42,76.98 102.2,76.75 C3005.1
  L3SGND w0.127: v11(105.09,78.1) 104.91,78.28 v10(104.63,78.28)
  L5 w0.066: v8(78.61,167.17) 78.61,167.46 78.97,167.82 79.39,167.82 80.52,168.95 82.67,168.95 93.19,158.42 94.13,158.42 94.13,158.43 97.25,158.43 106.16,149.51 106.16,138.28 108.55,135.88 109.05,135.88 109.55,135.39 109.63,135.31 109.63,133.65 109.63,123.09 108.67,122.12 108.67,120.35 108.67,115.2 107.1,113.63 107.1,113.63 106.84,113.37 106.84,93.95 107.19,93.6 107.19,78.91 106.16,77.87 105.5,77.87 105.27,78.1 v11(105.09,78.1)
DDI0_TX2_DP_ST: length 1.1
  TOP w0.102: U3102.44 102.21,75.9 C3005.2
DDI0_TX3_DN: length 110.1
  TOP w0.102: v1(100.52,77.59) 100.63,77.48 ; 100.63,77.48 100.44,77.29 100.44,76.9 100.29,76.75 C3008.1 ; 100.63,77.48 100.92,77.77 100.98,77.77 v10(101.03,77.82)
  L3SGND w0.127: v11(101.43,77.97) 101.28,77.82 v10(101.03,77.82)
  L5 w0.066: v11(101.43,77.97) 101.64,77.77 102.04,77.77 102.31,78.03 102.31,78.26 104.84,80.79 105.64,81.6 105.64,92.92 105.39,93.17 105.39,114.21 105.73,114.55 107.1,115.93 107.1,122.69 108.18,123.77 108.18,132.32 108.18,133.86 106.74,135.29 106.74,135.64 104.61,137.77 104.61,149.01 96.65,156.97 92.59,156.97 83.2,166.36 80.66,166.36 80.42,166.6 v8(80.31,166.6)
DDI0_TX3_DN_ST: length 1.1
  TOP w0.102: U3102.48 100.21,75.83 C3008.2
DDI0_TX3_DP: length 109.9
  TOP w0.102: C3007.1 100.8,76.75 100.65,76.9 100.65,77.2 100.89,77.44 v10(101.03,77.44)
  L3SGND w0.127: v11(101.43,77.41) 101.36,77.49 101.08,77.49 v10(101.03,77.44)
  L5 w0.066: v11(101.43,77.41) 101.65,77.63 102.1,77.63 102.45,77.97 102.45,78.09 102.45,78.2 104.94,80.69 105.78,81.54 105.78,92.98 105.53,93.23 105.53,114.16 105.79,114.41 107.25,115.87 107.25,122.63 108.32,123.71 108.32,132.26 108.32,133.92 108.24,134 106.88,135.35 106.88,135.7 104.75,137.83 104.75,149.07 96.71,157.11 92.65,157.11 83.26,166.51 80.72,166.51 80.59,166.63 v8(80.59,166.89)
DDI0_TX3_DP_ST: length 1.1
  TOP w0.102: C3007.2 100.71,75.82 U3102.47
DDI1_RCOMP_N: length 5.9
  L7 w0.06: v8(79.74,169.43) 80.03,169.43 81.2,170.6 81.2,170.7 81.38,170.88 81.55,170.88 81.72,171.05 81.72,171.82 81.48,172.06 81.48,172.34 81.72,172.58 81.72,172.89
  L7 w0.061: 81.72,172.89 82.18,173.35 v5(82.18,173.88)
DDI1_RCOMP_P: length 8.8
  L7 w0.06: v5(82.69,173.2) 82.36,173.2 82.08,172.92 82.08,172.77 81.6,172.29 81.6,172.11 81.84,171.87 81.84,171 81.6,170.76 81.43,170.76 81.32,170.65 81.32,170.48 81.36,170.44 81.36,170.2 80.11,168.95 79.94,168.95 79.74,169.15 v8(79.46,169.15)
  BOTTOM w0.114: R402.1 82.2,174.75 82.48,174.46 82.48,174.45 v1(83.17,173.76) 83.17,173.63 82.74,173.2 v5(82.69,173.2)
DDR3_DRAM_PWROK: length 60.5
  L5 w0.076: v4(85.81,177.11) 85.82,177.11 87.54,178.83 87.54,178.83 87.54,178.94 87.88,179.28 87.88,179.41 90.23,181.76 90.23,182.51 92.24,184.53 94.73,184.53 97.4,181.86 v3(97.4,181.17) ; v8(68.43,163.77) 68.72,163.77 69.18,164.23 69.18,166.49 70.76,168.08 70.76,169.24 71,169.47 71,171.1 70.99,171.11 70.89,171.2 70.89,174.28 70.83,174.34 70.83,174.95 70.69,175.09 70.69,175.09 70,175.77 70,176.44 69.9,176.54 69.9,176.79 69.85,176.84 69.85,177.32 69.76,177.41 69.76,177.97 v5(69.71,178.02)
  L6SGND w0.06: v3(97.4,181.17) 98.05,181.17 98.83,180.39 98.83,176.85 99.03,176.65 v8(99.03,176.53)
  L7 w0.061: v5(69.71,178.02) 69.71,178.55 70.17,179.01 70.17,179.49 70.7,180.03 71.18,180.5 73.89,180.5 74.49,179.9 76.13,179.9 76.39,180.16 76.59,180.36 76.62,180.39 79.05,180.39 79.06,180.4 83.48,180.4 84.16,181.08 84.72,181.08 85.36,180.43 85.36,177.82 85.81,177.36 v4(85.81,177.11)
DDR3_M0_OCAVREF: length 27.1
  TOP w0.254: v10(68.72,167.64) 68.57,167.8 68.57,170.17 v1(68.52,170.22) 68.57,170.27 v9(68.57,173.68)
  L2 w0.254: v9(68.57,173.68) 68.57,173.71 64.4,177.87 59.9,177.87 59.55,178.23 53.29,178.23 v10(53.22,178.15)
  L3SGND w0.254: v11(69.1,167.64) v10(68.72,167.64) ; v11(53.22,178.51) v10(53.22,178.15)
  L5 w0.254: v11(53.22,178.51) 53.25,178.51 53.28,178.53 53.63,178.53 53.68,178.58 v4(53.99,178.58)
  L6SGND w0.254: v8(68.71,167.45) 68.9,167.64 v11(69.1,167.64)
  L7 w0.254: v4(53.99,178.58) 53.99,178.68 54.22,178.91 v5(54.22,180.13)
DDR3_M0_ODQVREF: length 14.2
  L2 w0.254: v10(66.39,167.95) 65.96,167.95 65.09,167.08 v12(62.95,167.08) v10(55.84,167.08)
  L3SGND w0.254: v11(55.33,167.08) v10(55.84,167.08) ; v11(68.17,167.95) v10(66.39,167.95)
  L6SGND w0.254: v5(54.98,167.43) v11(55.33,167.08) ; v8(68.14,167.45) 68.14,167.89 68.17,167.92 v11(68.17,167.95)
DDR3_M0_RCOMPPD: length 2.2
  TOP w0.076: v10(69.46,164.28) 68.87,164.28 v1(68.52,163.93)
  L3SGND w0.114: v11(69.58,164.79) 69.58,164.41 v10(69.46,164.28)
  L6SGND w0.114: v5(69.81,165.2) 69.81,165.07 69.58,164.84 v11(69.58,164.79)
DDR3_M1_RCOMPPD: length 2.3
  TOP w0.076: v1(69.05,161.36) 69.05,161.69 69.73,162.38 v10(69.76,162.38)
  L3SGND w0.114: v10(69.76,162.38) 69.76,162.67 v11(69.61,162.82)
  L6SGND w0.114: v8(70.08,162.82) 70.04,162.86 69.65,162.86 v11(69.61,162.82)
DDR3_VCCA_PWROK: length 56.8
  L5 w0.076: v7(68.9,164.33) 69.03,164.46 69.03,166.53 70.61,168.12 70.61,169.28 70.62,169.29 70.86,169.53 70.86,171.04 70.72,171.19 70.72,174.26 70.66,174.31 70.66,174.32 70.64,174.34 70.64,174.87 70.5,175.01 69.09,176.42 69.09,177.91 v5(69.2,178.02) ; v11(94.07,181.5) 93.92,181.5 93.57,181.15 93.25,181.15 92.94,181.45 90.46,181.45 88.26,179.26 88.26,179.12 87.92,178.78 87.92,178.67 87.92,178.67 87.92,177.92 87.46,177.45 86.69,177.45 v4(86.12,176.88)
  L6SGND w0.06: v8(98.63,176.93) 98.43,177.13 98.43,177.56 96.39,179.6 95.82,179.6 94.07,181.35 v11(94.07,181.5)
  L7 w0.06: v8(67.86,163.77) 68.14,163.77 68.7,164.33 v7(68.9,164.33)
  L7 w0.061: v4(86.12,176.88) 86.12,177.54 85.54,178.13 85.54,180.51 84.79,181.25 84.09,181.25 83.43,180.59 76.5,180.59 75.98,180.07 74.57,180.07 73.96,180.68 71.1,180.68 69.99,179.56 69.99,179.18 69.49,178.67 69.49,178.46 69.2,178.18 v5(69.2,178.02)
DE303_INT1: length 118.9
  TOP w0.114: v2(44.46,159.96) 44.46,160.01 44.82,160.37 44.82,179.98 45.22,180.39 45.22,185.66 44.02,186.86 36.87,186.86 v1(36.41,186.41) 34.3,184.3 34.3,182.44 34.48,182.27 ECOMP3.11
  L5 w0.076: v4(87.95,145.38) 87.95,146.05 87.87,146.13 v4(87.87,148.79)
  L7 w0.061: v4(87.87,148.79) 87.43,148.79 87.28,148.94 84.32,148.94 84.29,148.96 84.22,148.96 84.05,149.13 84.05,149.36 84.26,149.57 84.26,149.75 83.55,150.46 83.55,151.62 83.35,151.82 82.9,152.27 82.9,152.67 82.62,152.96 82.62,153.37 82.38,153.61 82.38,154.96 82.17,155.17 82.17,155.69 v8(80.88,156.98) ; v2(44.46,159.96) 44.61,159.81 44.61,159.26 44.51,159.16 44.51,156.35 44.57,156.3 44.57,153.92 44.32,153.67 44.32,153.67 44.11,153.46 44.11,150.16 51.86,142.41 52.33,142.41 52.33,142.41 52.76,142.41 52.76,142.41 65.48,142.41 65.78,142.7 66.27,142.7 67.7,144.14 75.05,144.14 75.13,144.22 77.18,146.27 78.32,146.27 78.55,146.5 80.53,146.5 81.24,145.79 84.29,145.79 84.46,145.62 87.28,145.62 87.51,145.38 v4(87.95,145.38)
DE303_INT2: length 119.4
  TOP w0.114: ECOMP3.9 34.78,183.27 34.53,183.52 34.53,183.87 v1(35.72,185.06) 37.3,186.63 43.93,186.63 44.94,185.62 44.94,180.74 v9(44.84,180.64)
  L2 w0.061: v9(44.84,180.64) 44.84,178.48 42.02,175.66 42.02,175.2 42.3,174.92 42.81,174.92 43.39,174.35 43.39,174.34 43.4,174.33 43.4,171.25 43.39,171.24 43.39,170.78 41.45,168.84 41.45,168.61 41.36,168.52 41.36,161.74 40.68,161.06 40.68,157.5 41.45,156.72 41.45,147 43.95,144.5 66.78,144.5 69.25,142.03 69.25,141.08 69.5,140.82 71.91,140.82 71.97,140.76 72.5,140.76 72.96,141.22 74.84,141.22 80.3,146.68 81.73,146.68 86.3,151.25 v10(86.83,151.25)
  L3SGND w0.127: v11(86.68,151.58) 86.68,151.4 v10(86.83,151.25)
  L5 w0.076: v8(80.31,157.55) 82.59,155.27 82.59,154.38 82.59,154.38 84.67,152.31 85.65,152.31 86.37,151.58 v11(86.68,151.58)
DEBUB_CS: length 2.1
  TOP w0.114: v10(102.09,172.71) 101.46,172.71 v1(101.15,172.41)
  L3SGND w0.127: v11(101.71,172.79) 101.79,172.71 v10(102.09,172.71)
  L6SGND w0.114: v8(102.23,172.93) 101.85,172.93 v11(101.71,172.79)
DEBUG_I2C_1_SCL: length 1.5
  BOTTOM w0.114: XDP1.11 53.53,143.99 54.02,144.47 TP5602.1
DEBUG_I2C_1_SDA: length 1.4
  BOTTOM w0.114: TP5601.1 52.82,144.28 53.1,144 53.1,143.25 XDP1.9
DMIC1_VDD: length 8.4
  TOP w0.254: v9(113.3,143.58) 113.3,144.77 112.64,145.44 112.64,145.59 C2101.1 112.43,145.79 C2102.1 112.33,146.35 D2103.2 112.3,147.16 R2104.2 v1(111.62,147.92)
  L2 w0.254: v9(113.33,140.68) 113.33,141.34 113.3,141.37 113.3,142.7 113.3,142.7 113.3,143.58 v9(113.3,143.58)
DMIC_1_DATA: length 73.4
  TOP w0.114: v9(114.03,145.69) 115.28,144.44 v2(115.48,144.44)
  L2 w0.061: v9(113.68,141.52) 113.68,145.33 v9(114.03,145.69)
  L7 w0.061: v5(96.25,195.27) 96.32,195.2 100.75,195.2 100.98,195.43 105.59,195.43 107.07,193.95 107.07,193.22 108.98,191.31 v5(108.98,191.28) 110.69,191.28 113.11,188.87 113.11,168.04 111.65,166.59 111.65,162.74 113.4,160.99 113.4,151.92 114.14,151.18 114.14,145.79 v2(115.48,144.44)
  BOTTOM w0.114: R2005.2 96.25,195.3 v5(96.25,195.27)
DMIC_SCL: length 61.1
  TOP w0.114: v2(115.48,145.13) 115.38,145.23 115.33,145.23 114.92,145.64 v9(114.92,145.69)
  L2 w0.061: v9(114.92,145.69) 114.67,145.44 v9(114.67,141.52)
  L7 w0.061: v5(107.35,193.34) 109.23,191.46 110.76,191.46 113.28,188.94 113.28,167.97 111.82,166.51 111.82,162.81 111.93,162.71 113.58,161.06 113.58,151.99 114.31,151.26 114.31,146.3 v2(115.48,145.13)
  BOTTOM w0.114: R2001.1 106.34,193.11 v1(106.41,193.03) 106.49,193.11 107.12,193.11 v5(107.35,193.34)
DN1_DP4_EC: length 82.2
  TOP w0.102: v9(91.45,40.69) C1715.2 91.72,40.34 91.72,39.11 U1704.F13 ; C1716.2 87.29,112.57 Q1701.2 ; v10(87.11,112.59) v1(86.3,112.59)
  L2 w0.061: v9(91.45,40.69) 91.45,40.71 91.34,40.83 91.14,40.83 91.02,40.94 90.25,40.94 88.55,42.64 v10(88.25,42.64)
  L3SGND w0.127: v10(88.25,42.64) 88.2,42.64 88.02,42.46 88.01,42.46 87.99,42.44 v11(87.79,42.44) ; v11(86.6,112.47) 86.73,112.59 v10(87.11,112.59)
  L5 w0.066: v11(87.79,42.44) 87.58,42.65 87.35,42.65 86.67,43.34 86.67,54.67 87.13,55.14 88.91,56.92 88.91,67.52 88.91,67.52 88.91,73.84 88.91,75.48 88.91,75.8 88.91,76.48 88.91,76.49 88.91,79.37 88.38,79.91 88.38,111.7 87.31,112.78 86.91,112.78 v11(86.6,112.47)
DOCK_DETECT#: length 1.5
  TOP w0.127: R1761.2 93.59,28.29 93.24,28.63 U1704.H1
DP1_DN4_EC: length 86.2
  TOP w0.102: Q1701.3 88.91,112.85 Q1701.1 87.72,114.04 v1(86.93,114.04) 86.93,113.3 v10(87.11,113.13) ; U1704.G13 92.43,39.03 92.33,39.14 92.25,39.14 91.93,39.45 91.93,40.08 92.37,40.51 v9(92.37,40.71)
  L2 w0.061: v10(88.24,43.02) 88.45,43.02 90.33,41.14 91.1,41.14 91.22,41.03 91.51,41.03 91.51,41.03 91.83,40.71 v9(92.37,40.71)
  L3SGND w0.127: v11(86.6,113.23) 86.7,113.13 v10(87.11,113.13) ; v10(88.24,43.02) v11(87.77,43.02)
  L5 w0.066: v11(86.6,113.23) 86.91,112.92 87.37,112.92 88.52,111.76 88.52,79.97 89.06,79.43 89.06,76.42 89.06,75.85 89.06,75.54 89.06,75.38 89.06,67.58 89.06,67.46 89.06,56.86 86.81,54.61 86.81,43.4 87.41,42.79 87.54,42.79 v11(87.77,43.02)
DP_REDRIVER_ADDR_EQ: length 1.7
  TOP w0.114: U3102.3 98.97,73.12 98.67,72.82 R3017.1 R3016.2
DP_REDRIVER_CAD_SNK: length 1.9
  TOP w0.114: R3002.1 98.11,69.62 U3102.10
DP_REDRIVER_CAD_SRC: length 3.7
  TOP w0.114: U3102.8 98.04,70.62 98.04,70.63 97.9,70.77 97.54,70.77 96.58,71.72 TP3003.1
DP_REDRIVER_EN_C: length 4.6
  TOP w0.114: v1(105.14,65.45) 105.8,65.45 106.54,66.19 D3001.A
  L2 w0.061: v9(106.46,66.85) 106.46,69.1 v9(106.45,69.12)
DP_REDRIVER_RST: length 3.9
  TOP w0.114: U3102.35 106.81,73.62 107.05,73.86 107.05,75.03 106.59,75.48 v1(106.59,75.71) 106.62,75.74 107.17,75.74 107.48,75.43 C3025.1
DP_REDRIVER_SCL_CTL: length 2.9
  TOP w0.114: U3102.4 99.03,72.62 98.79,72.38 97.5,72.38 TP3005.1
DP_REDRIVER_SCL_DDC: length 6.3
  TOP w0.114: U3102.33 107.26,72.62 107.78,73.15 107.78,73.4 v9(107.71,73.48)
  L2 w0.061: v9(106.79,77.52) 106.79,76.09 107.71,75.18 v9(107.71,73.48)
DP_REDRIVER_SDA_CTL: length 2
  TOP w0.114: TP3006.1 97.99,72.12 U3102.5
DP_REDRIVER_SDA_DDC: length 6.1
  TOP w0.114: U3102.34 106.79,73.12 107.38,73.71 v9(107.38,74.54)
  L2 w0.061: v9(107.38,74.54) 107.38,75.26 v9(104.99,77.64)
DPR#: length 4.2
  BOTTOM w0.114: NGFF1.25 13.68,145.81 v1(13.68,142.92) 13.7,142.9 13.7,142.31 13.83,142.18 R4021.1
DPR_HPD_IN: length 27.7
  TOP w0.114: U3102.11 98.85,69.12 v2(98.46,68.73) 98.46,68.42 R3026.2
  L3SGND w0.127: v10(104.35,46.05) 104.35,46.1 v11(104.02,46.43)
  L5 w0.076: v4(104.05,46.07) 104.05,46.4 v11(104.02,46.43)
  L7 w0.061: v2(98.46,68.73) 98.31,68.57 98.31,61.44 98.59,61.16 98.59,57.45 103.08,52.95 103.08,51.99 104.05,51.02 v4(104.05,46.07)
DPR_HPD_OUT: length 5
  TOP w0.114: U3102.9 98.14,70.12 97.81,70.45 R3001.1 97.6,70.45 96.91,69.76 Q3001.1 96.69,69.76 95.71,70.74 v1(95.29,70.74)
EC5048_TX: length 2.2
  TOP w0.114: ECDBG1.2 87.28,16.46 87.36,16.38 R1733.1 87.64,15.82 v1(88.02,15.44)
EC_AC_IN: length 10.2
  TOP w0.114: U1704.E2 91.2,29.87 91.2,27.81 90.82,27.43 v9(90.82,27.38) ; R1715.2 92.07,25.24 91.81,25.5 91.34,25.5 90.99,25.15 90.99,25.14 v9(90.28,25.14) 90.28,25.6 v1(89.83,26.06) 89.52,25.75 R1749.2
  L2 w0.061: v9(90.28,25.14) 90.28,25.98 90.79,26.48 90.79,27.35 v9(90.82,27.38)
EC_AC_IN_R: length 5.4
  TOP w0.114: D1709.K 89.5,20.13 v1(89.5,22.7) R1727.2 89.52,23.59 R1749.1
EC_BATT_PRES#: length 132.8
  TOP w0.114: U1704.N10 97.38,36.77 97.51,36.77 97.54,36.8 R1746.1 v9(98.67,37.43) ; v10(88.43,133.93) 88.27,133.93 87.76,133.42 R4504.1 v1(86.73,133.42)
  L2 w0.061: v10(100.95,92.4) 100.8,92.25 97.12,92.25 v9(96.13,93.24) ; v9(98.67,37.43) 99.12,36.97 99.51,36.97 99.64,36.85 101.02,36.85 101.56,37.38 101.56,37.46 102.4,38.3 102.4,39 102.86,39.46 102.86,40.35 99.7,43.51 v10(98.67,43.51)
  L3SGND w0.127: v10(98.67,43.51) 98.67,43.76 v11(98.41,44.01) ; v10(100.95,92.4) 101.05,92.4 v11(101.28,92.63) ; v11(88.81,134.08) 88.58,134.08 v10(88.43,133.93)
  L5 w0.076: v4(100.75,134.54) 100.75,134.44 101.59,133.6 101.59,118.82 101.84,118.56 101.84,105.3 101.83,105.29 101.83,98.31 101.84,98.3 101.84,95.23 101.08,94.46 101.08,92.83 v11(101.28,92.63) 101.49,92.42 101.49,91.12 97.32,86.95 97.32,75.5 97.32,75.5 97.32,74.71 97.32,74.29 97.26,74.24 95.27,72.26 95.09,72.08 94.46,71.45 94.46,61.3 94.37,61.21 94.37,60.7 94.5,60.58 94.5,56.89 94.5,55.81 97.05,53.26 97.05,45.66 98.41,44.3 v11(98.41,44.01) ; v11(88.81,134.08) 89.17,134.08 89.83,133.42 95.32,133.42 95.9,134 v4(95.9,134.26)
  L7 w0.061: v4(95.9,134.26) 95.94,134.21 97.67,134.21 98.04,134.58 98.23,134.58 98.72,135.07 99.25,135.07 99.42,134.9 99.98,134.9 99.98,134.9 100.36,134.9 100.48,134.9 100.75,134.64 v4(100.75,134.54)
EC_BATT_PRES#_R: length 10.8
  TOP w0.114: v1(89.5,133.75) 89.17,133.42 R4504.2 D4503.1
  L3SGND w0.127: v10(88.58,132.51) 88.58,131.87 88.38,131.67 v11(88.25,131.67)
  L6SGND w0.127: v5(88.3,131.26) 88.3,131.62 v11(88.25,131.67)
  BOTTOM w0.114: BATT1.5 95.2,132.34 91.18,132.34 90.11,131.26 v5(88.3,131.26)
EC_BIST#: length 6.5
  TOP w0.114: U1704.J7 94.48,34.67 95.79,34.67 96,34.88 96,35.91 96.37,36.27 97.48,36.27 97.54,36.33 97.8,36.33 97.85,36.27 98.61,36.27 98.62,36.28 98.64,36.28 D1710.K
EC_FG_ALERT: length 2.3
  TOP w0.114: U1704.A9 87.19,36.29 87.19,36.57 86.74,37.03 D1702.K
EC_GPIO002: length 4.1
  TOP w0.114: U1704.L10 96,37 97.41,37 98.21,37.79 TP1712.1
EC_GPIO034: length 15.1
  TOP w0.114: U1704.F6 91.75,33.43 91.93,33.62 91.93,33.65 v9(92.02,33.65) ; v9(102.79,36.64) 102.83,36.64 103.08,36.89 103.08,36.95 103.11,36.97 103.11,37.48 103.41,37.79 TP1720.1
  L2 w0.061: v9(102.79,36.64) 103.14,36.28 103.14,36.02 101.91,34.79 98.17,34.79 97.72,34.34 96.39,34.34 96.21,34.52 94.48,34.52 93.68,33.73 92.1,33.73 v9(92.02,33.65)
EC_GPIO036: length 2.8
  TOP w0.114: TP1719.1 85.16,33.43 U1704.A6
EC_GPIO043: length 3.7
  TOP w0.114: v9(85.81,40.36) 85.53,40.63 TP1711.1
  L2 w0.061: v9(85.81,40.36) 85.81,40.33 86.02,40.13 86.02,39.47 87.25,38.23 v9(87.64,38.23)
EC_GPIO047: length 3.6
  TOP w0.114: D1701.K 86.03,32.89 86.17,33.02 v1(86.17,33.04) 87.82,33.04 88.21,33.43 U1704.B6
EC_GPIO132: length 4.1
  TOP w0.114: U1704.L13 95.64,39.39 95.97,39.72 99.02,39.72 TP1707.1
EC_GPIO201: length 4.1
  TOP w0.114: TP1713.1 95.74,26.49 95.36,26.87 95.36,28.91 U1704.K1
EC_GPIO204: length 4.2
  TOP w0.114: TP1715.1 99,30.47 98.05,30.47 97.63,30.89 97.63,31.19 97.4,31.42 97.08,31.42 97.06,31.44 96.04,31.44 U1704.L4
EC_GPIO212: length 1.8
  TOP w0.114: U1704.L1 95.74,29.33 TP1717.1
EC_LAD0: length 2.8
  L2 w0.061: v9(96.44,33.43) 96.84,33.43 97.12,33.72 98.27,33.72 v9(98.89,33.09)
EC_LAD1: length 2.8
  TOP w0.114: U1704.M7 96.73,34.23 97.09,34.6 98.37,34.6 98.69,34.28 98.72,34.28 R1778.2
EC_LAD2: length 3.5
  TOP w0.114: R1779.2 98.7,33.8 96.06,33.8 95.64,34.21 U1704.L7
EC_LAD3: length 5.5
  L2 w0.061: v9(99.94,34.44) 99.76,34.62 98.24,34.62 97.79,34.17 96.31,34.17 96.14,34.34 94.95,34.34 v9(94.84,34.23)
EC_LCD_RST: length 40.8
  TOP w0.114: v1(94.7,63.49) 93.94,62.73 v9(93.94,62.51) ; U1704.L3 95.64,31.32 95.2,31.76 95.2,31.98 94.92,32.27 94.69,32.27 94.4,32.56 94.4,33.58 94.19,33.8 93.79,33.8 93.66,33.93 93.66,34.43 93.74,34.51 93.74,34.82 93.68,34.88 93.68,37.75 v9(93.64,37.79)
  L2 w0.061: v9(93.94,62.51) 93.94,61.97 92.8,60.83 92.8,57.6 91.38,56.18 91.38,53.16 91.14,52.92 90.71,52.92 90.67,52.9 90.65,52.89 90.65,52.89 89.88,52.12 89.88,50.22 90.39,49.7 90.39,49.4 90.16,49.17 90.16,47.21 89.93,46.98 89.93,46.81 87.78,44.66 87.78,42.47 88.19,42.06 88.43,42.06 89.95,40.54 89.95,39.87 90.95,38.87 91.11,38.87 91.17,38.8 92.44,38.8 93.46,37.79 v9(93.64,37.79)
EC_LFRAME#: length 3.6
  TOP w0.114: U1704.L6 95.93,33.43 96.33,33.03 98.41,33.03 98.69,32.75 98.72,32.75 R1776.2
EC_PROCHOT: length 218.8
  TOP w0.114: R1728.1 v10(98.31,38.68)
  L2 w0.061: v10(98.31,38.68) 98.1,38.68 98.02,38.76 97.61,38.76 97.56,38.8 94.45,38.8 94.33,38.68 93.48,38.68 93.24,38.92 v9(93.24,39.03)
  L3SGND w0.127: v11(98.77,39.24) 98.77,39.14 v10(98.31,38.68)
  L5 w0.076: v4(85.24,182.53) 85.28,182.57 86.22,182.57 90.29,186.65 91.75,186.65 95.64,190.53 105.58,190.53 106.8,189.31 107.06,189.31 109.14,187.23 109.14,186.9 109.88,186.16 109.88,183.44 110.46,182.85 110.46,182.06 109.6,181.2 109.6,178.09 109.8,177.88 109.93,177.76 109.93,153.26 110.06,153.13 110.06,153.13 111.78,151.41 111.78,141.46 111.8,141.44 111.8,141.42 111.9,141.32 111.9,140.92 111.78,140.8 111.78,140.5 v4(111.62,140.34) ; v4(98.28,140.36) 98.28,140 98.13,139.85 98.13,136.27 98.13,135.84 98.68,135.29 98.68,134.9 99.31,134.26 99.31,134.18 100.26,133.23 100.26,129.61 99.87,129.23 99.87,128.22 100.13,127.96 100.13,111.59 100.51,111.21 100.51,110.58 100.51,110.58 100.51,95.51 99.94,94.94 99.94,91.66 99.94,91.19 95.97,87.22 95.97,83.79 95.57,83.39 95.57,81.62 95.57,81.46 95.57,81.3 95.57,79.25 95.57,79.09 95.57,78.93 95.57,75.81 95.6,75.77 95.6,75.3 95.59,75.28 95.59,74.89 92.92,72.22 92.92,68.62 92.42,68.12 92.42,67.8 92.42,56 93.15,55.26 93.15,55.25 94.84,53.56 94.84,52.3 94.84,52.14 94.84,50.87 95.5,50.21 95.5,44.48 97.2,42.78 97.2,40.85 97.72,40.33 98.32,40.33 98.54,40.11 98.54,39.47 v11(98.77,39.24)
  L7 w0.061: v4(85.24,182.53) 84.86,182.14 84.54,182.14 83.79,181.4 82.73,181.4 82.1,180.77 76.4,180.77 76.06,180.44 75.81,180.44 75.43,180.82 75.19,180.82 v5(74.64,180.82) ; v4(111.62,140.34) 111.35,140.34 111.06,140.63 109.03,140.63 108.73,140.33 99,140.33 98.98,140.36 v4(98.28,140.36)
  BOTTOM w0.114: v5(74.64,180.82) 74.36,180.54 Q501.1
EC_PWRBTN#: length 133.6
  TOP w0.114: v10(98.94,133.37) 98.61,133.7 v1(98.28,133.7) 97.97,133.7 PD4606.A ; v9(89.9,28.04) 89.9,28.93 89.68,29.15 89.68,29.87 U1704.D2 ; v10(98.46,40.46) C1706.1
  L2 w0.061: v9(89.9,28.04) 90.56,28.04 91.14,27.45 91.14,27.33 93.77,24.7 93.83,24.7 94.07,24.46 v10(94.47,24.46)
  L3SGND w0.127: v10(98.46,40.46) 98.46,40.25 v11(98.16,39.95) ; v10(98.94,133.37) 99.58,133.37 v11(99.83,133.12) ; v10(94.47,24.46) v11(94.47,24.96)
  L5 w0.076: v11(99.83,133.12) 99.83,133.09 99.88,133.05 99.88,129.5 99.68,129.31 99.68,128.14 99.93,127.88 99.93,111.51 100.32,111.13 100.32,110.66 100.32,110.66 100.32,95.59 99.74,95.02 99.74,91.58 99.74,91.27 95.78,87.3 95.78,83.87 95.38,83.47 95.38,81.7 95.38,81.7 95.38,81.38 95.38,81.22 95.38,79.33 95.38,79.32 95.38,79.01 95.38,78.85 95.38,75.73 95.41,75.69 95.41,75.38 95.4,75.36 95.4,74.97 92.73,72.3 92.73,68.7 92.23,68.2 92.23,67.72 92.23,56.39 92.23,56.39 92.23,56.23 92.23,55.92 92.96,55.18 92.96,55.17 94.65,53.48 94.65,52.38 94.65,52.22 94.65,50.8 95.31,50.13 95.31,44.4 97.01,42.7 97.01,40.77 97.83,39.95 v11(98.16,39.95) 98.16,39.45 98.22,39.38 98.22,39.14 97.67,38.59 94.84,38.59 93.8,37.56 93.8,36.95 95.03,35.73 95.03,27.28 94.47,26.73 v11(94.47,24.96)
EC_RESETI#: length 3.6
  TOP w0.114: v1(91.15,26.64) 91.15,26.69 91.45,27 R1713.1 91.79,27.19 91.79,27.19 91.64,27.34 U1704.F1
EC_SER_IRQ: length 1.9
  TOP w0.114: R1775.2 98.72,32.25 98.69,32.25 98.58,32.35 98.58,32.39 98.33,32.63 U1704.N5
EC_SLP_S3#: length 16.7
  L2 w0.061: v9(94.04,30.23) 93.62,29.82 93.62,25.81 94.76,24.68 94.76,24.34 94.59,24.17 94.11,24.17 93.76,24.53 91.89,24.53 91.79,24.42 91.37,24.42 91.36,24.43 88.1,24.43 v2(87.84,24.68)
  BOTTOM w0.114: U1709.3 86.61,24.66 R1741.2 87.26,24.81 87.84,25.39 v1(88,25.39) 88,24.84 v2(87.84,24.68)
EC_SLP_S4#: length 16.1
  TOP w0.114: v1(103.29,30.98) 103.29,31.85 U1710.3 102.62,33.08 102.48,33.22 101.48,33.22 101.33,33.07 v9(100.44,33.07)
  L2 w0.061: v9(90.04,33.43) 90.37,33.11 90.75,33.11 90.94,33.3 91.63,33.3 91.82,33.11 91.85,33.11 91.91,33.17 92.34,33.17 92.73,33.55 93.76,33.55 93.93,33.73 96.76,33.73 96.96,33.93 99.35,33.93 100.21,33.07 v9(100.44,33.07)
EC_SMI#: length 236.9
  TOP w0.114: v1(104.74,37.18) 104.25,36.69 D1707.A 103.41,36.69 v9(102.86,36.14)
  L2 w0.061: v9(102.86,36.14) 102.66,35.94 98.24,35.94 97.85,35.55 93.12,35.55 92.96,35.72 92.96,37.55 v10(92.9,37.61) ; v10(46.58,175.15) 46.66,175.23 46.84,175.23 48.29,176.68 48.29,176.72 48.46,176.89 48.5,176.89 48.6,176.99 50.54,178.92 64.49,178.92 65.49,177.93 66.47,177.93 67.7,176.7 v10(69.25,176.7)
  L3SGND w0.127: v11(46.57,175.56) 46.57,175.17 v10(46.58,175.15) ; v11(69.47,177.16) 69.47,176.92 v10(69.25,176.7) ; v10(92.9,37.61) v11(92.55,37.61)
  L5 w0.076: v11(69.47,177.16) 69.47,176.89 69.71,176.65 v5(69.71,176.32) ; v4(81.55,139.19) 80.99,139.75 78.85,139.75 71.59,147 v4(71.59,147.24) ; v11(46.57,175.56) 46.57,170.04 46.41,169.88 46.41,168.55 45.07,167.2 45.07,164.87 v4(45.45,164.49)
  L6SGND w0.127: v4(92.11,37.59) 92.14,37.61 v11(92.55,37.61)
  L7 w0.061: v4(81.55,139.19) 81.55,139.36 81.9,139.71 82.92,139.71 83.63,140.42 84.11,140.9 84.11,141.13 84.48,141.5 85.01,141.5 85.38,141.13 85.38,141.11 85.48,141 85.48,138.23 86.44,137.27 86.44,135.84 86.46,135.82 86.46,131.11 86.43,131.08 85.76,130.41 85.76,123.41 88.19,120.99 88.29,120.89 88.39,120.79 88.6,120.58 88.6,120.58 88.6,109.63 88.6,109.44 88.6,109.42 88.6,109.14 88.6,109.14 88.6,109.1 88.6,109.02 88.6,108.89 88.6,108.89 88.6,108.52 88.03,107.96 88.03,98.92 87.86,98.75 87.68,98.57 87.68,98.28 87.68,98.27 87.68,94.7 87.65,94.68 87.65,81.89 87.65,81.89 87.65,81.74 87.65,81.74 87.65,80.85 87.96,80.54 88.22,80.28 88.22,80.13 88.22,80.13 88.22,79.99 88.22,78.58 88.32,78.47 88.32,78.47 89.14,77.66 89.14,77.37 89.13,77.37 89.13,76.52 90.14,75.52 90.14,73.51 89.75,73.12 89.75,72.84 89.52,72.6 89.52,72.45 89.41,72.33 89.41,72.28 89.37,72.22 89.37,71.72 89.57,71.51 89.57,71.14 89.57,71.14 89.57,68.29 89.9,67.97 89.9,66.11 89.71,65.91 89.71,65.91 89.29,65.49 89.29,65.49 88.81,65.02 88.81,63.96 88.99,63.78 88.99,63.09 89.12,62.96 89.12,62.81 89.57,62.36 89.57,61.33 90.69,60.22 90.69,54.88 89.42,53.62 89.42,53.32 89.19,53.08 89.19,51.63 88.86,51.3 87.69,51.3 87.36,50.97 87.36,50.59 87.67,50.28 87.67,41.84 90.83,38.68 91.45,38.68 92.11,38.01 v4(92.11,37.59) ; v5(69.71,176.32) 69.71,176.1 70.63,175.18 70.63,175.07 70.73,174.98 70.73,174.66 71.22,174.17 71.22,171.24 v8(71.29,171.17) ; v4(45.45,164.49) 45.45,163.72 45.56,163.62 45.56,162.3 46.29,161.57 46.29,153.67 45.47,152.85 45.47,151 50.8,145.67 52.26,145.67 53.17,146.58 58.54,146.58 59.16,145.96 59.16,145.95 59.96,145.16 60.97,145.16 62.9,147.08 65.45,147.08 65.49,147.04 71.39,147.04 v4(71.59,147.24)
  BOTTOM w0.114: v5(69.71,176.32) 69.71,175.92 69.43,175.64 v1(69.43,175.51)
EC_SMI#_R: length 8.3
  TOP w0.114: v9(103.01,35.15) 103.65,35.79 D1707.K 104.74,35.79 v1(104.84,35.89) ; U1704.N7 v9(98.28,34.23)
  L2 w0.061: v9(98.28,34.23) 99.74,34.23 99.82,34.15 100.05,34.15 100.13,34.23 100.65,34.23 101.03,34.62 101.98,34.62 102.19,34.82 102.37,34.82 102.43,34.88 102.74,34.88 v9(103.01,35.15)
EC_SMI_REV#: length 6.2
  L7 w0.06: v8(75.5,169.72) 75.78,169.72 76.66,170.6 76.66,172.23 76.99,172.56 77.11,172.56 77.48,172.93 77.48,174 77.51,174.02 77.51,174.19 v5(77.99,174.67)
EC_SYS_PWR_EN: length 119.7
  L3SGND w0.127: v11(89.72,29.09) 90.04,29.42 v10(90.04,29.43)
  L5 w0.076: v4(96.43,129.51) 97.32,128.62 97.32,123.18 97.26,123.12 97.26,121.89 97.97,121.17 97.97,110.71 98.32,110.36 98.32,96.38 93.69,91.74 93.69,88.17 93.69,88.17 93.69,84.74 93.28,84.34 93.28,82.56 93.28,80.51 93.28,80.35 93.28,80.19 93.28,80.04 90.84,77.6 90.17,76.93 89.83,76.59 89.55,76.3 89.55,76.22 89.55,76.06 89.55,75.74 89.55,75.58 89.55,72.63 89.55,67.78 89.55,67.78 89.55,67.26 89.55,67.25 89.55,56.66 89.26,56.37 88.01,55.12 88.01,51.79 87.3,51.08 87.3,46.94 88.7,45.54 88.7,37.46 87.02,35.78 86.81,35.78 86.2,35.17 86.2,34.25 86.9,33.55 89.2,33.55 90.13,32.61 91.03,32.61 91.06,32.65 91.41,32.65 91.66,32.4 91.66,32.05 90.13,30.53 90.13,29.87 89.72,29.45 v11(89.72,29.09)
  L7 w0.061: v5(98.92,130.12) 98.31,129.51 v4(96.43,129.51)
  BOTTOM w0.114: R5409.1 101.92,130.3 101.92,130.27 101.81,130.16 99.79,130.16 v1(99.38,130.58) v5(98.92,130.12)
EC_VCC_PWRGD: length 12
  TOP w0.114: v9(95.92,26.16) 96.1,25.98 97.27,25.98 v1(97.8,26.51) 98.08,26.23 R1709.2
  L2 w0.061: v9(91.64,31.03) 91.86,31.03 91.88,31.05 93.06,31.05 93.51,30.6 94.08,30.6 94.83,29.85 94.83,27.25 v9(95.92,26.16)
EC_VCI_IN1#: length 1.5
  TOP w0.114: U1704.G1 92.44,28.16 R1781.2
EC_VCI_IN2#: length 3.4
  TOP w0.114: U1704.C2 88.85,29.85 88.85,29.19 89.39,28.65 R1782.2 89.25,27.9 v1(88.61,27.9)
EC_VCI_IN3#: length 1.6
  TOP w0.114: R1783.2 90.41,29 U1704.E1
EC_VCI_IN4#: length 1.9
  L3SGND w0.127: v11(89.75,30.7) 89.42,31.03 v10(89.24,31.03)
  L6SGND w0.127: v5(89.75,31.19) v11(89.75,30.7)
  BOTTOM w0.114: v5(89.75,31.19) 89.06,31.19 v1(88.99,31.26)
EC_VCI_IN5#: length 4.6
  TOP w0.114: U1704.H2 92.88,29.87 92.88,28.51 93.1,28.29 R1785.2 93.1,26.39 v1(93.44,26.05)
EC_VR_CAP: length 13
  TOP w0.114: v9(93.79,25.09) 93.79,24.46 93.15,23.82 93.15,21.84 v1(92.98,21.66) C1712.1 ; v9(92.85,30.58) 92.85,31.44 U1704.H4
  L2 w0.061: v9(92.85,30.58) 93.18,30.25 93.18,25.62 93.71,25.09 v9(93.79,25.09)
EC_VREF_ADC: length 7
  TOP w0.114: U1704.J3 94.48,30.6 94.48,29.15 95.06,28.57 v1(95.06,26.13) 95.08,26.11 95.08,26.06 95.64,25.5 C1720.1 R1757.2
EC_XTAL1: length 4.7
  TOP w0.114: X1701.2 86.19,26.82 C1710.1 85.66,28.29 v1(85.66,28.44) 86.65,29.43 U1704.A1
EC_XTAL2: length 3.5
  TOP w0.114: X1701.1 87.77,27.07 C1711.1 87.77,28.76 U1704.B1
ECOMPASS_C1: length 3
  TOP w0.114: C5710.1 37.96,178.58 v1(37.96,179.88) ECOMP3.15
ECOMPASS_SETC: length 3.1
  TOP w0.114: ECOMP3.2 39.55,181.77 40.47,180.84 v1(40.65,180.84) 40.85,180.84 41.52,181.5 C5709.1
ECOMPASS_SETP: length 2.4
  TOP w0.114: C5709.2 41.26,182.27 v1(40.52,182.27) ECOMP3.3
EMMC__RCLK: length 35.5
  L7 w0.06: 77.97,156.07 77.97,156.15 78.05,156.23 v8(78.05,156.42)
  L7 w0.061: 77.97,156.07 77.97,155.85 78.5,155.32 78.5,155.05 79.35,154.21 79.35,150.72 80.73,149.33 82.18,147.88 86.85,147.88 87.11,147.63 87.23,147.5 89.49,147.5 90.99,148.99 93.13,148.99 93.19,148.93 93.19,148.36 93.25,148.3 93.37,148.3 93.44,148.36 93.44,148.93 93.5,148.99 94.07,148.99 94.6,149.52 94.6,150.39 94.12,150.87 94.12,151.71 94.06,151.77 92.72,151.77 92.66,151.83 92.66,152.51 92.72,152.57 92.84,152.57 92.9,152.51 92.9,152.07 92.96,152.01 93.08,152.01 93.14,152.07 93.14,152.51 93.2,152.57 93.33,152.57 93.39,152.51 93.39,152.07 93.45,152.01 93.57,152.01 93.63,152.07 93.63,152.41 93.69,152.47 93.81,152.47 93.87,152.41 93.87,152.07 93.94,152.01 94.06,152.01 94.12,152.07 94.12,152.22 v5(94.32,152.42)
  BOTTOM w0.114: v5(94.32,152.42) 94.32,153.45 94.86,153.99 EMMC1.H5
EMMC_CLK: length 36.4
  L7 w0.06: 78.63,154.24 78.02,154.85 78.02,155.12 77.43,155.71 77.43,156.18 77.28,156.33 77.28,156.5 77.4,156.62 77.4,156.78 77.28,156.9 77.28,157.07 77.48,157.27 v8(77.48,157.55)
  L7 w0.061: v5(95.37,155.99) 94.92,155.99 94.35,155.42 94.35,154.23 94.58,154 94.77,154 95.19,153.58 95.19,152.42 96.01,151.6 96.01,149.94 92.85,146.78 86.96,146.78 86.56,147.18 81.89,147.18 80.44,148.63 78.3,150.77 78.3,153.33 78.48,153.52 78.57,153.52 78.63,153.58 78.63,153.7 78.57,153.76 78.36,153.76 78.3,153.82 78.3,153.94 78.36,154 78.57,154 78.63,154.06 78.63,154.24
EMMC_CMD: length 39.9
  L7 w0.06: 78.12,152.64 78.12,153.61 76.78,154.95 76.78,155.45 77,155.67 77,156.14 77.15,156.3 77.15,156.46 77,156.62 77,157.35 77.4,157.75 77.4,157.92 77.28,158.03 77.28,158.2 77.48,158.4 v8(77.48,158.68)
  L7 w0.061: v5(95.16,155.6) 95.08,155.6 94.59,155.11 94.59,154.37 94.79,154.17 94.84,154.17 96.19,152.83 96.19,149.87 96.1,149.78 92.93,146.61 86.88,146.61 86.49,147.01 81.72,147.01 78.49,150.24 78.15,150.24 v5(78.12,150.27) 78.12,150.67 78.12,152.64
  BOTTOM w0.114: v5(78.12,150.27) 78.12,149.86 TP1601.1 78.15,149.77 78.15,148.92 77.5,148.28 R507.2 ; EMMC1.M5 94.88,155.88 v5(95.16,155.6)
EMMC_DATA_0: length 33.5
  L7 w0.06: v8(78.33,157.83) 78.43,157.93 78.53,157.93 78.7,157.77 78.7,157.59 78.64,157.53 78.5,157.53 78.44,157.47 78.44,157.35 78.5,157.29 78.64,157.29 78.7,157.23 78.7,157.1 78.78,157.02 78.78,156.56
  L7 w0.061: v5(93.88,150.49) 93.88,150.71 93.82,150.77 92.23,150.77 91.96,151.04 91.96,151.7 92.02,151.76 92.24,151.76 92.3,151.82 92.3,151.94 92.24,152 92.02,152 91.96,152.06 91.96,152.19 92.02,152.25 92.24,152.25 92.3,152.31 92.3,152.43 92.24,152.49 92.02,152.49 91.96,152.55 91.96,152.87 91.91,152.92 91.13,152.92 91.07,152.98 91.07,153.1 91.13,153.16 92.24,153.16 92.3,153.23 92.3,153.35 92.24,153.41 90.79,153.41 90.75,153.37 90.75,150.26 89.98,149.49 89.98,148.98 89.2,148.2 87.52,148.2 87.4,148.33 87.14,148.58 82.77,148.58 81.2,150.16 81.2,150.54 80.54,151.21 80.54,153.28 80.09,153.73 80.09,155.07 79.95,155.2 79.65,155.51 79.65,155.51 79.28,155.88 79.09,155.88 78.77,156.2 78.77,156.56 78.78,156.56
EMMC_DATA_1: length 34.2
  L7 w0.06: v8(77.76,158.4) 77.76,158.12 78.32,157.56 78.32,157.17 78.65,156.84 78.65,156.62
  L7 w0.061: v5(94.09,150.06) 94,150.06 93.47,150.59 92.15,150.59 91.95,150.79 91.28,150.79 91.22,150.86 91.22,150.98 91.28,151.04 91.71,151.04 91.78,151.1 91.78,151.22 91.71,151.28 91.28,151.28 91.22,151.34 91.22,151.47 91.28,151.53 91.71,151.53 91.78,151.59 91.78,151.71 91.71,151.77 91.26,151.77 91.2,151.83 91.2,151.95 91.26,152.01 91.71,152.01 91.78,152.07 91.78,152.2 91.71,152.26 91.26,152.26 91.2,152.32 91.2,152.44 91.26,152.5 91.72,152.5 91.78,152.56 91.78,152.68 91.72,152.75 91.01,152.75 90.93,152.66 90.93,150.19 90.16,149.41 90.16,148.91 89.28,148.03 87.45,148.03 87.32,148.15 87.07,148.41 82.7,148.41 81.02,150.09 81.02,150.47 80.36,151.13 80.36,153.29 79.97,153.68 79.97,155.02 79.53,155.46 79.53,155.46 79.23,155.76 79.04,155.76 78.65,156.15 78.65,156.61 78.65,156.62
  BOTTOM w0.114: v5(94.09,150.06) 94.37,150.34 EMMC1.A4
EMMC_DATA_2: length 33.9
  L7 w0.06: 78.78,155.85 78.53,156.1 78.53,156.78 77.76,157.55 v8(77.76,157.83)
  L7 w0.061: v5(94.07,149.68) 93.85,149.9 93.6,149.9 93.54,149.96 93.54,150.35 93.48,150.41 93.35,150.41 93.29,150.35 93.29,149.96 93.23,149.9 93.11,149.9 93.05,149.96 93.05,150.36 92.99,150.42 92.87,150.42 92.8,150.36 92.8,149.96 92.74,149.9 92.62,149.9 92.56,149.96 92.56,150.36 92.5,150.42 92.38,150.42 92.32,150.36 92.32,149.96 92.26,149.9 92.12,149.9 92.06,149.96 92.06,150.44 91.93,150.57 91.16,150.57 91.1,150.51 91.1,150.35 91.16,150.29 91.71,150.29 91.78,150.21 91.78,149.41 91.72,149.34 90.71,149.34 90.59,149.47 90.5,149.47 90.42,149.38 90.42,149.29 90.56,149.15 90.56,149.06 89.35,147.85 87.38,147.85 87.25,147.98 87.25,147.98 86.99,148.23 82.63,148.23 82.49,148.37 82.41,148.37 82.34,148.31 82.25,148.31 82.17,148.39 82.17,148.48 82.23,148.54 82.23,148.63 82.15,148.72 82.06,148.72 82,148.65 81.91,148.65 81.82,148.74 81.82,148.82 81.89,148.89 81.89,148.98 81.8,149.06 81.72,149.06 81.65,149 81.56,149 81.48,149.08 81.48,149.17 81.54,149.23 81.54,149.32 81.46,149.41 81.37,149.41 81.31,149.34 81.22,149.34 81.13,149.43 81.13,149.51 81.2,149.58 81.2,149.66 81.11,149.75 81.03,149.75 80.96,149.68 80.87,149.68 80.79,149.77 80.79,149.86 80.85,149.92 80.85,150.01 80.73,150.13 80.55,150.13 80.48,150.21 80.48,150.31 80.66,150.49 80.66,150.59 80.57,150.68 80.48,150.68 80.22,150.42 80.14,150.42 80.05,150.51 80.05,150.59 80.31,150.85 80.31,150.94 80.18,151.06 80.18,153.29 79.85,153.63 79.85,154.97 79.41,155.41 79.41,155.41 79.18,155.64 78.99,155.64 78.78,155.85
  BOTTOM w0.114: v5(94.07,149.68) 94.22,149.68 94.88,150.33 EMMC1.A5
EMMC_DATA_3: length 34
  L7 w0.06: 78.9,156.51 78.9,156.98 79.1,157.18 79.1,157.91 78.98,158.03 78.7,158.03 v8(78.33,158.4)
  L7 w0.061: v5(93.37,150.99) 93.33,150.94 92.3,150.94 92.13,151.11 92.13,151.34 92.48,151.69 92.48,152.75 92.54,152.81 93.39,152.81 93.46,152.87 93.46,153.63 93.39,153.69 93.27,153.69 93.21,153.63 93.21,153.11 93.15,153.05 93.03,153.05 92.97,153.11 92.97,153.63 92.91,153.69 92.78,153.69 92.72,153.63 92.72,153.11 92.66,153.05 92.54,153.05 92.48,153.11 92.48,153.42 92.32,153.58 90.72,153.58 90.58,153.44 90.58,150.33 89.81,149.56 89.81,149.05 89.13,148.38 87.6,148.38 87.47,148.5 87.21,148.76 82.85,148.76 81.37,150.23 81.37,150.62 80.71,151.28 80.71,153.28 80.22,153.77 80.22,155.11 79.85,155.48 79.77,155.56 79.77,155.56 79.33,156 79.14,156 78.89,156.25 78.89,156.51 78.9,156.51
EMMC_DATA_4: length 33.1
  L7 w0.06: v8(78.05,156.98) 78.05,156.87 78.08,156.83 78.08,156.66 78.25,156.5 78.25,156.26 78.13,156.14 78.13,155.86 78.62,155.37 78.62,155.1 79.07,154.65
  L7 w0.061: v5(93.88,150.99) 93.88,150.89 94.4,150.36 94.4,149.57 94,149.17 93.75,149.17 93.69,149.23 93.69,149.62 93.63,149.68 93.5,149.68 93.44,149.62 93.44,149.23 93.38,149.17 93.26,149.17 93.2,149.23 93.2,149.64 93.14,149.7 93.02,149.7 92.96,149.64 92.96,149.23 92.9,149.17 92.77,149.17 92.71,149.23 92.71,149.64 92.65,149.7 92.53,149.7 92.47,149.64 92.47,149.23 92.41,149.17 92.29,149.17 92.22,149.23 92.22,149.66 92.16,149.72 92.04,149.72 91.98,149.66 91.98,149.23 91.92,149.17 90.91,149.17 89.42,147.68 87.31,147.68 87.18,147.8 86.92,148.06 82.25,148.06 80.8,149.51 79.52,150.79 79.52,150.97 79.58,151.03 79.95,151.03 80.01,151.09 80.01,151.21 79.95,151.27 79.58,151.27 79.52,151.33 79.52,151.45 79.58,151.51 79.95,151.51 80.01,151.58 80.01,151.7 79.95,151.76 79.58,151.76 79.52,151.82 79.52,151.99 79.58,152.06 79.91,152.06 79.97,152.12 79.97,152.24 79.91,152.3 79.58,152.3 79.52,152.36 79.52,152.48 79.58,152.54 79.91,152.54 79.97,152.6 79.97,152.73 79.91,152.79 79.58,152.79 79.52,152.85 79.52,152.97 79.58,153.03 79.91,153.03 79.97,153.09 79.97,153.21 79.91,153.27 79.58,153.27 79.52,153.34 79.52,154.2 79.07,154.65 79.07,154.65
EMMC_DATA_5: length 33.3
  L7 w0.06: v8(77.48,156.42) 77.48,156.3 77.55,156.23 77.55,155.76
  L7 w0.061: 77.55,155.76 78.14,155.17 78.14,154.9 78.8,154.23 78.8,153.29 78.74,153.23 78.53,153.23 78.47,153.17 78.47,153.05 78.53,152.99 78.74,152.99 78.8,152.93 78.8,152.81 78.74,152.75 78.53,152.75 78.47,152.68 78.47,152.56 78.53,152.5 78.74,152.5 78.8,152.44 78.8,152.32 78.74,152.26 78.53,152.26 78.47,152.2 78.47,152.08 78.53,152.01 78.74,152.01 78.8,151.95 78.8,151.83 78.74,151.77 78.53,151.77 78.47,151.71 78.47,151.59 78.53,151.53 78.74,151.53 78.8,151.47 78.8,151.29 78.74,151.23 78.53,151.23 78.47,151.17 78.47,151.05 78.53,150.99 78.74,150.99 78.8,150.92 78.8,150.51 80.51,148.81 81.96,147.36 86.63,147.36 87.03,146.96 90.05,146.96 90.11,147.02 90.11,147.25 90.17,147.31 90.3,147.31 90.36,147.25 90.36,147.02 90.42,146.96 92.78,146.96 95.83,150.01 95.83,151.52 95.62,151.73 95.5,151.73 95.21,151.45 95.21,151.34 95.15,151.28 95.03,151.28 94.97,151.34 94.97,151.47 94.88,151.56 94.75,151.56 94.37,151.18 v5(94.37,150.99)
EMMC_DATA_6: length 33.5
  L7 w0.06: v8(77.76,157.27) 77.76,156.98 77.96,156.78 77.96,156.62 77.85,156.5 77.85,155.94
  L7 w0.061: v5(94.88,150.99) 94.88,149.55 93.35,148.02 93.02,148.02 92.96,148.08 92.96,148.76 92.89,148.82 92.77,148.82 92.71,148.76 92.71,148.08 92.65,148.02 92.53,148.02 92.47,148.08 92.47,148.76 92.41,148.82 92.28,148.82 92.22,148.76 92.22,148.08 92.16,148.02 92.04,148.02 91.98,148.08 91.98,148.76 91.92,148.82 91.8,148.82 91.74,148.76 91.74,148.08 91.67,148.02 91.55,148.02 91.49,148.08 91.49,148.76 91.43,148.82 91.31,148.82 91.25,148.76 91.25,148.08 91.19,148.02 91.07,148.02 91,148.08 91,148.52 90.94,148.58 90.82,148.58 90.76,148.52 90.76,148.08 90.7,148.02 90.27,148.02 89.57,147.33 87.16,147.33 86.78,147.71 82.11,147.71 80.66,149.16 79.17,150.65 79.17,154.21 78.38,155 78.38,155.27 77.85,155.8 77.85,155.94
EMMC_DATA_7: length 33.8
  L7 w0.06: 77.71,155.9 77.71,156.53 77.76,156.59 v8(77.76,156.7)
  L7 w0.061: v5(95.37,150.99) 95.38,151 95.38,151.29 95.45,151.35 95.57,151.35 95.66,151.26 95.66,150.09 93.06,147.49 92.85,147.49 92.78,147.43 92.78,147.21 92.72,147.15 92.6,147.15 92.54,147.21 92.54,147.71 92.48,147.77 92.36,147.77 92.3,147.71 92.3,147.2 92.24,147.13 92.11,147.13 92.05,147.2 92.05,147.74 91.99,147.8 91.87,147.8 91.81,147.74 91.81,147.2 91.75,147.13 91.63,147.13 91.57,147.2 91.57,147.76 91.5,147.82 91.38,147.82 91.32,147.76 91.32,147.2 91.26,147.13 91.14,147.13 91.08,147.2 91.08,147.79 91.02,147.85 90.89,147.85 90.83,147.79 90.83,147.2 90.77,147.13 90.65,147.13 90.59,147.2 90.59,147.79 90.53,147.85 90.39,147.85 90.33,147.79 90.33,147.55 90.27,147.49 89.98,147.49 89.64,147.15 87.09,147.15 86.71,147.53 82.04,147.53 80.59,148.98 78.98,150.59 78.98,154.23 78.26,154.95 78.26,155.22 77.71,155.77 77.71,155.9
EMMC_RCOMP: length 11
  L5 w0.06: v5(83.65,152.19) 80.27,155.58 80.27,155.67 78.77,157.16 78.77,158.24 78.05,158.96 v8(77.76,158.96)
  BOTTOM w0.114: v5(83.65,152.19) 83.68,152.22 R501.2 83.15,152.95 v1(82.89,153.21)
EMMC_RESET#: length 47.4
  L5 w0.076: v4(69.02,148.28) 69.04,148.26 69.04,147.17 70.22,145.99 v4(70.22,145.64)
  L7 w0.061: v4(69.02,148.28) 68.61,148.69 68.61,150.11 v5(69.53,151.02) 69.65,151.18 69.67,151.2 69.67,151.34 70.5,152.17 70.5,152.29 71.07,152.87 71.07,155 71.54,155.46 v8(71.54,156.06) ; v4(70.22,145.64) 75.31,145.64 76.82,147.15 77.34,147.15 78.38,148.18 79.85,148.18 81.21,146.83 86.42,146.83 86.81,146.43 93,146.43 96.17,149.61 96.28,149.71 96.38,149.81 96.38,153.49 v5(94.88,154.99)
EMMC_VDDI: length 4.8
  L7 w0.061: v5(92.42,151.23) 92.68,151.49 v5(93.37,151.49)
  BOTTOM w0.114: v5(92.42,151.23) C1606.2 89.44,150.97 v1(89.44,150.36)
EN_19V_IN: length 175.5
  TOP w0.114: PR4650.1 98.84,29.56 R1760.2 98.12,29.98 v10(98.1,29.98) ; v2(92.87,89.02) 94.88,87.02 94.88,84.24 95.28,83.84 v9(95.89,83.84) 96.24,83.48 R5724.2 97.14,83.48 97.49,83.83 98.24,83.83 98.41,83.66 ; v2(104.46,128.65) 104.46,133.85 98.92,139.39 93.46,139.39 90.94,141.9 88.61,141.9 88,142.51 88,145.74 93.46,151.2 101.08,151.2 103.56,153.68 103.56,157.87 103.87,158.19 v1(103.87,159.18) 103.87,159.66 PR4911.2 ; 98.41,83.66 PQ4603.5 ; 98.41,83.66 98.67,83.92 100.28,83.92 U4603.4
  L2 w0.061: v10(95.59,76.09) 95.59,76.14 95.82,76.37 95.82,80.62 95.75,80.69 95.75,83.7 v9(95.89,83.84)
  L3SGND w0.127: v11(95.03,75.53) v10(95.59,76.09) ; v11(97.85,30.22) v10(98.1,29.98)
  L5 w0.076: v11(95.03,75.53) 95.03,75.51 94.98,75.46 94.98,74.82 92.54,72.38 92.54,68.78 92.04,68.27 92.04,67.96 92.04,67.64 92.04,56.31 92.04,55.84 92.77,55.1 92.77,55.09 94.46,53.4 94.46,52.46 94.46,52.3 94.46,50.35 94.98,49.83 94.98,44.22 95.59,43.61 95.59,41.65 97.93,39.31 v5(97.93,39.26)
  L6SGND w0.127: v5(97.88,29.77) 97.88,30.19 v11(97.85,30.22)
  L7 w0.061: v5(97.62,105.02) 97.64,105.04 97.92,105.04 100.52,107.64 100.52,120.34 104.92,124.74 104.92,125.96 104.95,125.99 104.95,126.87 104.46,127.36 v2(104.46,128.65)
  BOTTOM w0.114: v5(97.93,39.26) 97.88,39.21 v5(97.88,29.77) ; v5(97.62,105.02) 91.93,99.33 91.93,89.25 92.16,89.02 v2(92.87,89.02)
EN_19V_IN#: length 6.9
  TOP w0.114: PQ4603.3 97.33,84.82 97.3,84.79 96.74,84.79 96.18,84.22 v1(95.41,84.22) 95.34,84.3 95.34,86.28 95.51,86.45 U4602.7 97.31,86.45 PR4643.2
EN_19V_IN_L: length 2.7
  TOP w0.114: U1704.N2 98.47,29 R1760.1 98.54,28.52 v1(98.82,28.24)
EN_19V_IN_R: length 3.2
  TOP w0.114: PQ4603.2 98.41,85.36 97.88,85.89 R5723.2 97.11,85.15 U4602.5
EN_19V_IN_R#: length 20.7
  TOP w0.114: v9(94.93,83.59) 95.69,83.59 96.18,83.1 96.66,83.1 97.29,82.47 98.77,82.47 99.06,82.76 PQ4603.6 ; v9(90.92,93.37) v1(89.95,93.37)
  L2 w0.061: v9(94.93,83.59) 95.01,83.67 95.01,84.2 96.05,85.24 96.05,87.34 94.55,88.84 94.55,92.75 93.4,93.9 91.46,93.9 v9(90.92,93.37)
EN_DCIN_OP_VCC: length 0.8
  TOP w0.114: U1705.A2 96.86,88.74 PR4640.1
EN_V3P3_EC: length 121.4
  L5 w0.076: v5(98.69,122.52) 98.69,122.34 99.31,121.71 99.31,111.33 99.74,110.89 99.74,95.88 99.17,95.31 99.17,91.64 95.41,87.88 95.41,87.74 95.21,87.54 95.21,84.11 94.8,83.7 94.8,81.93 94.8,81.14 94.8,80.98 94.8,79.56 94.8,78.77 94.8,78.61 94.8,78.46 93.71,77.37 93.71,75.26 91.24,72.78 91.24,71.45 91.07,71.28 91.07,68.41 91.24,68.25 91.24,55.55 92.01,54.78 92.01,54.78 93.7,53.09 93.7,52.77 93.7,52.62 93.7,49.99 94.08,49.61 94.11,49.58 94.11,42.71 94.28,42.53 94.28,38.95 92.99,37.66 92.99,33.77 92.43,33.21 92.43,31.42 92.57,31.28 v5(92.57,28.65)
  BOTTOM w0.114: v5(98.69,122.52) 102.63,122.52 v1(105.15,125.05) 105.33,125.22 105.33,128.41 104.27,129.47 U4501.3 ; R1742.2 85.11,27.95 Q1702.G 86.53,27.95 86.9,27.58 90.66,27.58 90.82,27.42 92.39,27.42 92.57,27.6 v5(92.57,28.65)
FG_ALERT_EC: length 131.8
  L2 w0.061: v9(85.13,37.03) 84.95,37.21 84.95,37.5 84.77,37.68 84.77,51.47 85.42,52.11 85.42,55.13 88.46,58.17 88.46,66.41 85.18,69.7 v10(85.18,75.89) ; v10(90.41,133.04) 90.16,133.04 89.39,132.27 89.39,117.65 86.19,114.46 86.19,105.61 v10(86.35,105.46)
  L3SGND w0.127: v10(90.41,133.04) 90.41,134.23 90.44,134.26 v11(90.44,134.45) ; v10(85.18,75.89) 85.15,75.89 84.7,76.35 84.7,79.68 84.68,79.69 84.68,80.06 84.7,80.07 84.7,98.37 86.24,99.92 86.24,105.35 v10(86.35,105.46)
  L5 w0.076: v11(90.44,134.45) 90.3,134.59 90.3,135.33 88.39,137.24 88.39,137.66 88.19,137.86 88.19,139.69 86.23,141.65 86.23,141.74 86.21,141.77 86.21,148.35 86.21,149.16 84.65,150.72 v5(82.92,150.72)
  L7 w0.061: v8(80.31,156.42) 81.03,155.69 81.13,155.69 81.99,154.83 81.99,153.48 82.25,153.22 82.25,152.79 82.32,152.73 82.32,151.34 82.68,150.98 82.68,150.95 v5(82.92,150.72)
  BOTTOM w0.114: v5(82.92,150.72) 83.73,151.53 v1(83.73,151.66)
FSIN_REAR: length 7
  BOTTOM w0.114: CAMR1.21 71.88,190.15 72.22,189.81 72.22,187.72 72.5,187.44 72.5,184.75 R2518.2
FST_SPI_SOCK_D2: length 95.8
  L5 w0.06: 74.86,157.62 74.73,157.75 74.73,157.92 74.85,158.03 74.85,158.48 v8(74.65,158.68)
  L5 w0.076: v4(82.87,143.63) 82.65,143.85 79.99,143.85 77.88,145.96 77.88,148.57 75.93,150.52 75.93,152.99 74.86,154.06 74.86,157.62
  L7 w0.061: v5(37.4,158.85) 36.25,157.69 36.25,155.38 36.07,155.2 36.07,147.62 43.56,140.13 46.74,140.13 47.83,139.04 67.39,139.04 68.5,140.14 68.68,140.14 68.74,140.08 68.74,139.66 68.8,139.6 68.92,139.6 68.98,139.66 68.98,140.08 69.04,140.14 69.17,140.14 69.23,140.08 69.23,139.66 69.29,139.6 69.41,139.6 69.47,139.66 69.47,140.08 69.53,140.14 69.65,140.14 69.71,140.08 69.71,139.66 69.78,139.6 69.9,139.6 69.96,139.66 69.96,140.08 70.02,140.14 70.14,140.14 70.2,140.08 70.2,139.66 70.26,139.6 70.39,139.6 70.45,139.66 70.45,140.08 70.51,140.14 70.63,140.14 70.69,140.08 70.69,139.66 70.75,139.6 70.87,139.6 70.93,139.66 70.93,140.08 71,140.14 71.12,140.14 71.18,140.08 71.18,139.66 71.24,139.6 71.36,139.6 71.42,139.66 71.42,140.08 71.48,140.14 71.6,140.14 71.67,140.08 71.67,139.66 71.73,139.6 71.85,139.6 71.91,139.66 71.91,140.08 71.97,140.14 72.09,140.14 72.15,140.08 72.15,139.66 72.21,139.6 72.34,139.6 72.4,139.66 72.4,140.08 72.46,140.14 v5(77.3,140.14) 77.83,140.14 80,142.31 80.34,142.31 80.4,142.37 80.4,143.34 80.46,143.4 80.58,143.4 80.64,143.34 80.64,142.37 80.7,142.31 80.82,142.31 80.88,142.37 80.88,143.34 80.95,143.4 81.07,143.4 81.13,143.34 81.13,142.37 81.19,142.31 81.55,142.31 v4(82.87,143.63)
FST_SPI_SOCK_D3: length 98.4
  L5 w0.076: v4(82.89,142.64) 82.89,142.67 82.09,143.47 79.83,143.47 77.49,145.81 77.49,148.16 75.47,150.17 75.47,152.8 74.44,153.83 74.44,157.91 v8(74.65,158.12) ; v4(35.88,166.34) 37.07,167.53 v5(38.67,167.53)
  L7 w0.061: v4(35.88,166.34) 34.07,164.54 34.07,161.77 34.38,161.46 34.38,145.98 34.95,145.41 37.29,145.41 43.27,139.43 46.41,139.43 47.5,138.34 77.11,138.34 v5(78.73,139.95) 79.87,141.1 81.35,141.1 v4(82.89,142.64)
G601A31U_MRDLY: length 2
  TOP w0.114: U5401.1 99.62,131.89 C5401.1 99.55,131.54 v1(99.05,131.03)
GNSS0: length 3.3
  TOP w0.114: v1(17.99,142.21) 17.72,142.49 17.72,142.72 ; 17.72,142.72 v2(17.72,142.72) ; 17.72,142.72 17.52,142.91 NGFF1.40
  BOTTOM w0.114: v2(17.72,142.72) 17.51,142.52 R4009.1 R4006.1
GNSS1: length 3.2
  TOP w0.114: v2(18.37,142.71) 18.02,143.06 NGFF1.42
  BOTTOM w0.114: R4007.1 18.63,141.83 19.09,142.29 v1(19.09,142.72) 18.38,142.72 v2(18.37,142.71)
GNSS_DISABLE#: length 90.2
  L5 w0.076: v4(84.34,149.25) 84.24,149.14 84.24,147.98 84.54,147.67 v4(84.54,143.89)
  L7 w0.061: v8(80.59,157.27) 80.68,157.18 80.96,157.18 81.29,156.86 81.29,156.82 82.29,155.81 82.29,155.22 82.52,154.99 82.52,153.64 82.74,153.42 82.74,153.01 82.97,152.77 83.19,152.55 83.19,152.22 83.42,152 83.42,152 83.73,151.69 83.73,151.59 83.73,151.59 83.73,151.45 83.73,151.3 83.73,150.53 84.44,149.82 84.44,149.32 84.34,149.22 v4(84.34,149.25) ; v4(84.54,143.89) 84.54,143.74 82,141.19 81.7,141.19 81.43,140.92 80.13,140.92 77.37,138.16 44.29,138.16 42.32,140.13 16.55,140.13 16.52,140.1 15.51,140.1 v5(14.34,141.27)
  BOTTOM w0.114: v5(14.34,141.27) 14.34,140.74 v1(14.11,140.51)
GNSS_DISABLE#_R: length 2.8
  TOP w0.114: v1(14.49,142.03) 14.21,142.31 v2(14.21,142.57) 14.02,142.76 NGFF1.26
  BOTTOM w0.114: v2(14.21,142.57) 14.34,142.44 R4004.1
GNSS_I2C_IRQ: length 2.9
  TOP w0.114: NGFF1.44 18.52,143.18 19.02,142.68 19.18,142.68 v2(19.54,142.31)
  BOTTOM w0.114: TP4002.1 v2(19.54,142.31)
GPIO133: length 11.9
  TOP w0.114: v9(86.85,48.76) 87.16,49.07 R1711.2
  L2 w0.061: v9(86.85,48.76) 86.85,48.34 86.81,48.3 86.81,48.3 86.81,45.66 86.18,45.03 86.18,41.03 86.76,40.46 86.76,40.2 86.76,39.6 86.75,39.59 86.75,39.25 86.99,39 87.33,39 87.36,39.03 v9(87.64,39.03)
GPIO151: length 8.7
  TOP w0.114: v1(104.74,40.89) 104.58,40.74 R1786.2 R1787.1 102.6,40.74 102.23,40.37 102.23,40.15 102.05,39.97 v9(101.28,39.97) ; U1704.N12 97.7,38.69 97.7,38.7 97.9,38.91 97.93,38.91 98.11,39.09 98.11,39.11 v9(98.31,39.31)
  L2 w0.061: v9(98.31,39.31) 98.61,39.31 99.27,39.97 v9(101.28,39.97)
GPIO152: length 10.4
  TOP w0.114: R1789.2 103.9,39.7 103.34,39.7 102.83,40.2 v9(102.58,40.2) ; v9(97.8,39.22) 97.78,39.22 97.51,39.49 97.06,39.49 96.85,39.28 96.85,37.81 96.48,37.43 U1704.M11
  L2 w0.061: v9(102.58,40.2) 102.04,40.74 99.32,40.74 v9(97.8,39.22)
GPIO166: length 5
  TOP w0.114: U1704.K5 94.84,32.7 95.19,33.04 95.75,33.04 96.08,32.71 96.08,32.48 96.36,32.2 97.75,32.2 98.39,31.57 R1708.1
GPIO222: length 4.1
  L2 w0.061: v9(96.44,35.03) 97.76,35.03 98.39,35.66 v9(100.32,35.66)
GPIO223: length 16.5
  TOP w0.114: U1704.H7 93.43,34.42 v9(93.43,34.64) ; R1712.1 v9(88.17,46.45)
  L2 w0.061: v9(93.43,34.64) 93.43,34.72 92.52,35.63 92.52,37.66 91.73,38.45 91.03,38.45 90.96,38.52 90.79,38.52 90.68,38.62 90.58,38.73 89.68,39.63 89.68,39.64 89.6,39.72 89.6,40.39 88.28,41.71 88.04,41.71 87.06,42.69 87.06,44.67 87.95,45.56 87.95,46.22 v9(88.17,46.45)
GPIO224: length 16.7
  TOP w0.114: v9(92.9,34.62) 92.52,34.23 U1704.G7 ; R1714.1 v9(87.67,46.45)
  L2 w0.061: v9(92.9,34.62) 92.9,35 92.34,35.56 92.34,37.59 91.98,37.95 90.67,37.95 90.51,38.11 90.51,38.55 89.5,39.55 89.5,39.57 89.42,39.65 89.42,40.32 88.21,41.53 87.97,41.53 86.88,42.62 86.88,44.74 87.43,45.29 87.77,45.63 87.77,46.35 v9(87.67,46.45)
GPIO_RCOMP: length 10.1
  L5 w0.06: 71.28,171.13 71.28,169.18 70.97,168.87 v8(70.97,168.58)
  L5 w0.089: v5(70.34,177.67) 70.34,176.65 70.39,176.6 70.39,175.94 71.21,175.11 71.21,174.35 71.28,174.29 71.28,171.14 71.28,171.13
  BOTTOM w0.076: R749.2 70.22,177.79 v5(70.34,177.67)
GPIO_SUS2_C: length 8.6
  L5 w0.06: v8(71.82,169.43) 71.89,169.5 71.89,169.78 72.02,169.92 72.02,172.54
  L5 w0.076: 72.02,172.54 71.98,172.59 71.98,174.44 71.97,174.45 71.97,175.42 71.96,175.43 71.96,177.68 v5(72.12,177.85)
GPIO_SUS3_C: length 6.4
  L7 w0.06: v5(71.44,175.41) 71.67,175.17 71.67,174.53 72.06,174.14 72.06,172.73 71.87,172.54 71.87,171.18 v8(71.82,171.13)
  BOTTOM w0.114: R707.1 70.55,175.89 70.55,175.41 v1(70.65,175.31) 70.75,175.2 71.23,175.2 v5(71.44,175.41)
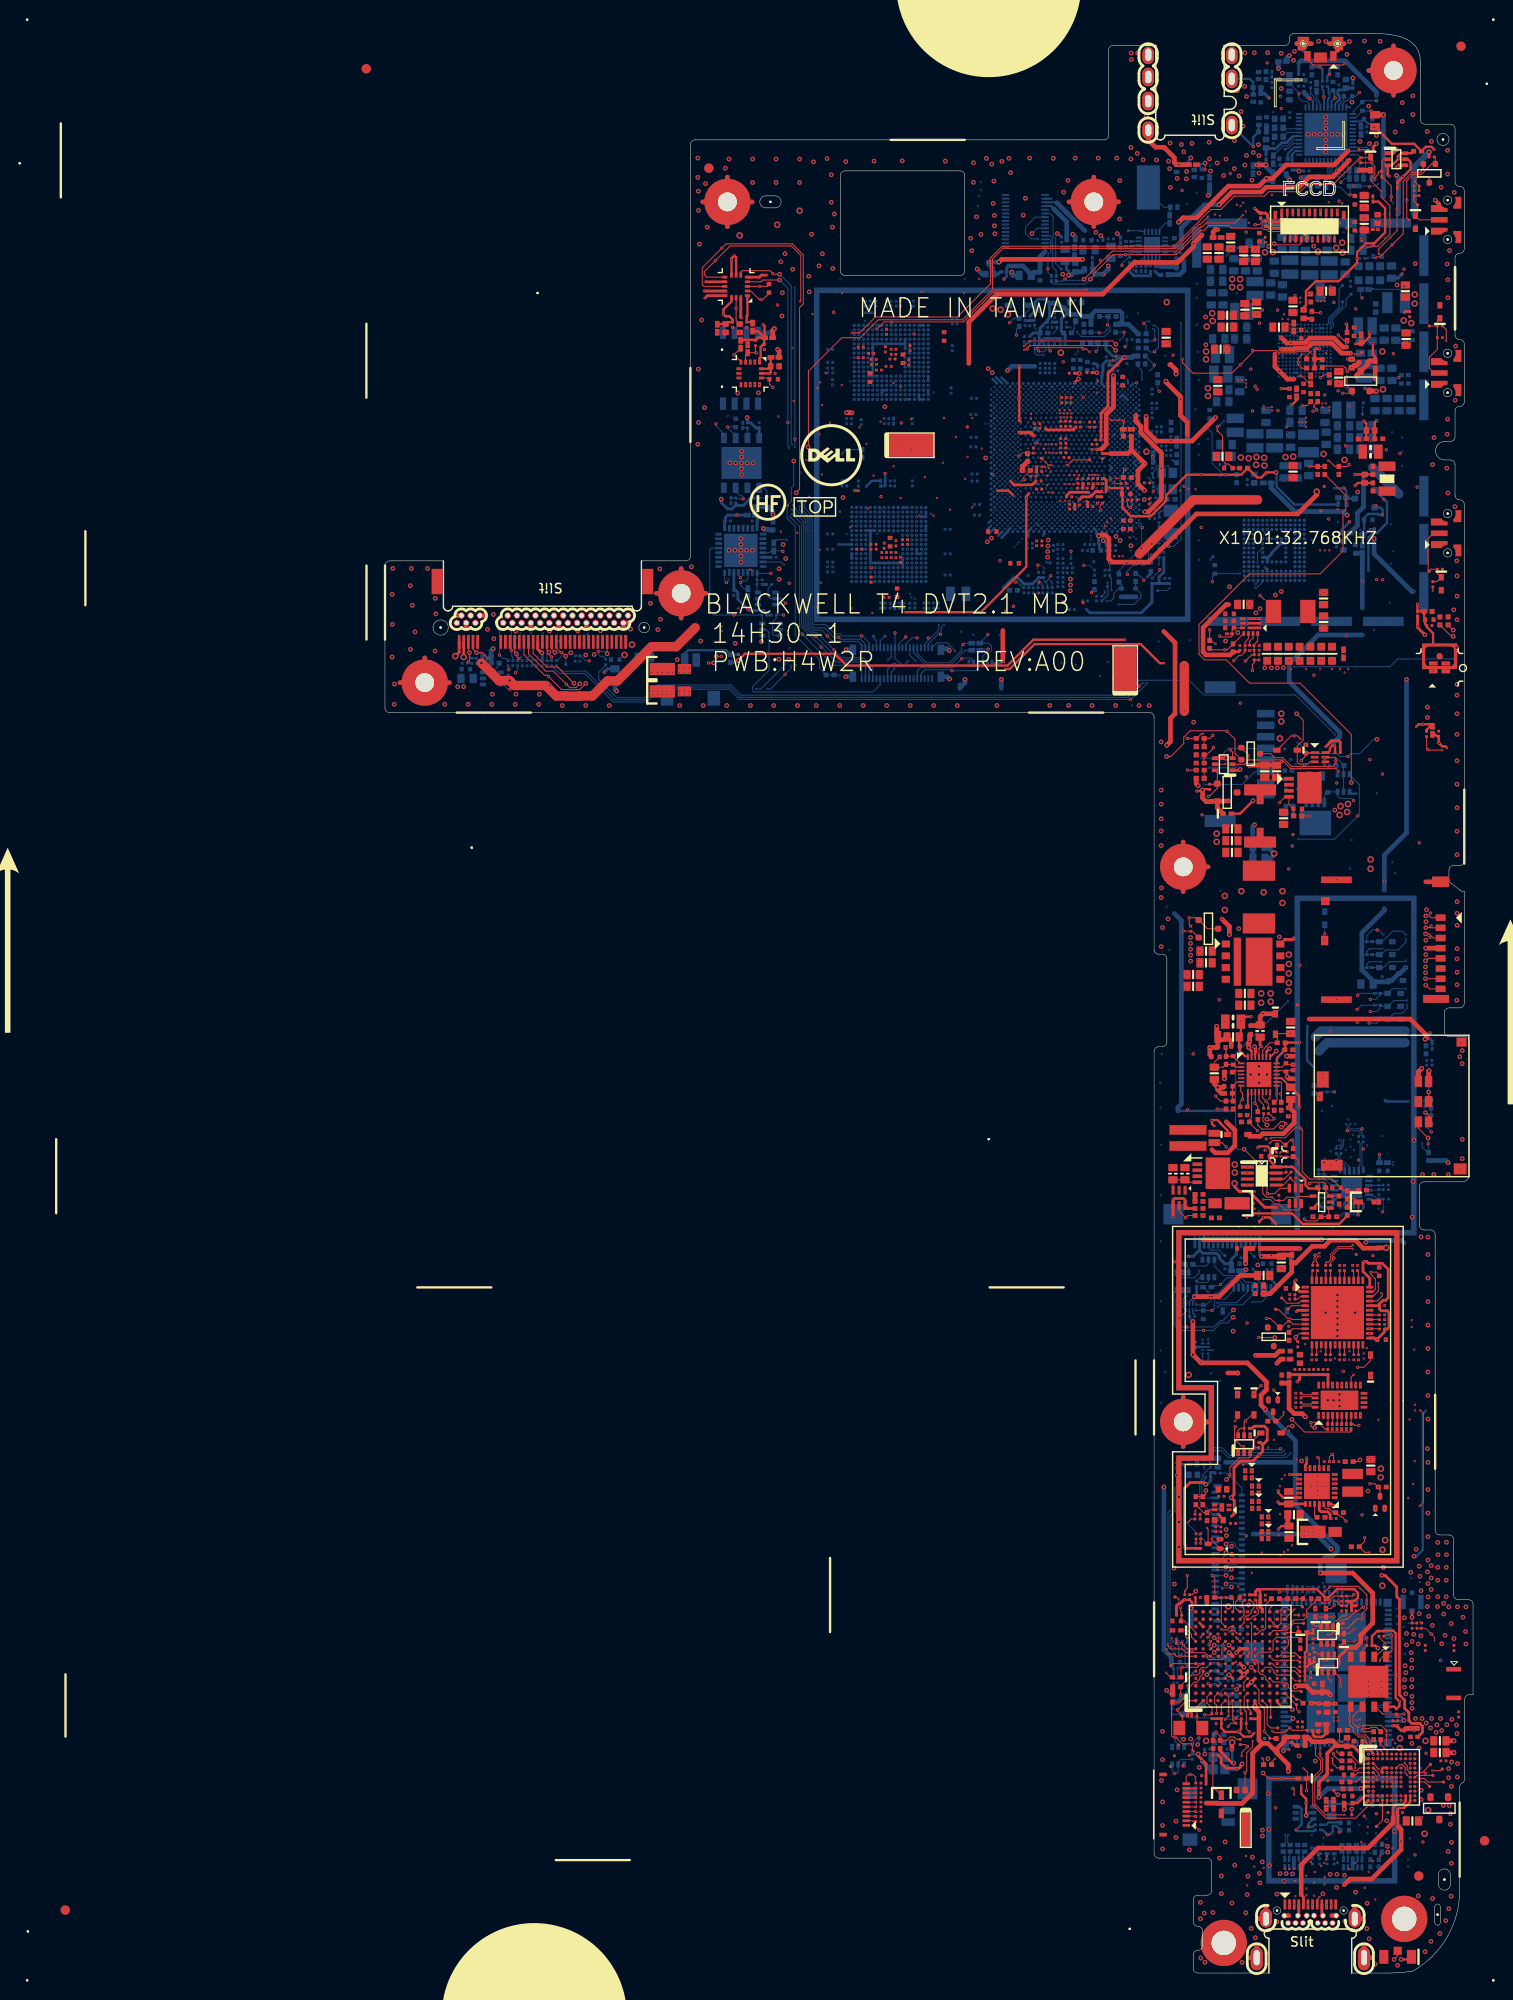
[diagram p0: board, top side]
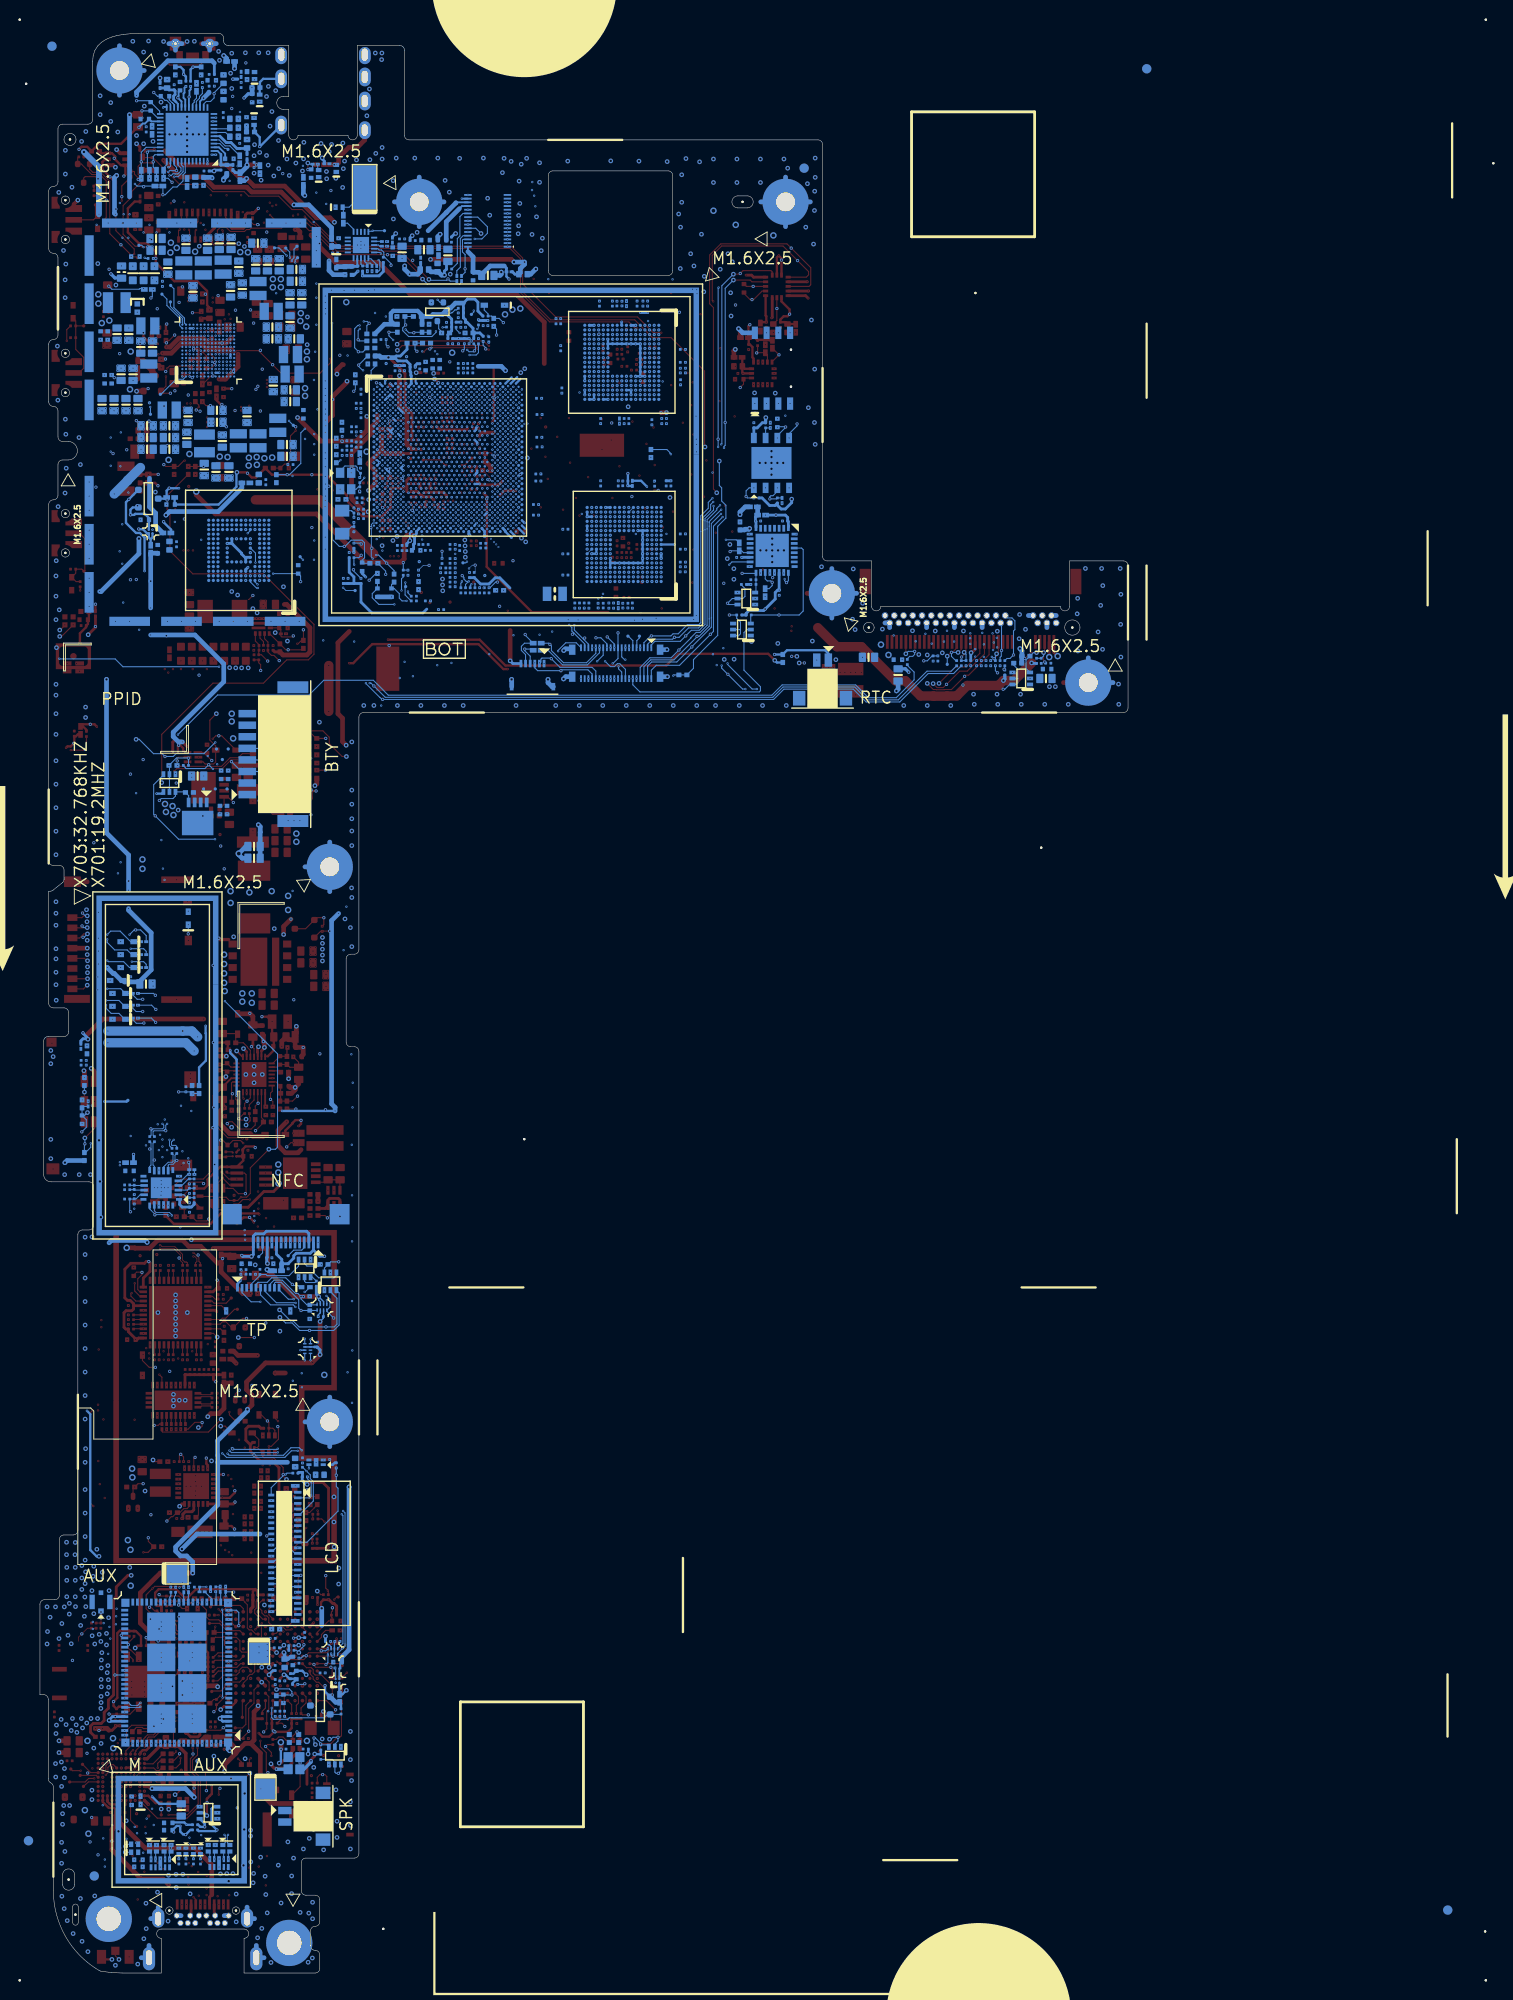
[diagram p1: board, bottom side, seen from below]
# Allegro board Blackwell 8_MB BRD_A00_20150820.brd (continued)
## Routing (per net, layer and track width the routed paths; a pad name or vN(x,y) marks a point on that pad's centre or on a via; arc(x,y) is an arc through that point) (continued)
GPIO_SUS7: length 8.9
  L5 w0.06: v5(72.1,169.15) 72.1,169.73 72.16,169.79 72.16,174.52 72.15,174.53 72.15,175.68 72.16,175.69 72.16,176.87 72.25,176.96 v5(72.25,177.24)
  BOTTOM w0.114: R758.2 72.63,177.62 v5(72.25,177.24)
GYRO_CAP: length 2
  TOP w0.114: GYRO1.14 41.43,172.37 C4209.1 41.57,171.7 v1(41.92,171.34)
GYRO_CS: length 2.1
  TOP w0.114: R4207.2 v1(37.73,174.87) 38.48,174.12 GYRO1.5
GYRO_INT1: length 102.7
  TOP w0.114: v2(35.55,141.57) v1(34.99,141.57)
  L2 w0.061: v9(38.26,172.87) 36.76,172.87 35.52,171.63 35.52,143.15 36.21,142.46 36.21,142.12 35.67,141.57 v2(35.55,141.57) ; v10(86.42,150.34) 86.42,149.41 82.98,145.97 80.73,145.97 v10(75.98,141.22)
  L3SGND w0.127: v10(75.98,141.22) 75.68,140.91 75.68,140.86 v11(75.6,140.79) ; v10(86.42,150.34) 86.27,150.49 v11(85.99,150.49)
  L5 w0.076: v4(85.08,151.63) 85.08,151.4 v11(85.99,150.49) ; v2(35.55,141.57) 36.16,141.57 38.84,138.89 73.15,138.89 74.84,140.58 75.18,140.58 75.38,140.79 v11(75.6,140.79)
  L7 w0.06: 82.23,156.9 81.6,157.52 81.25,157.52 80.94,157.83 v8(80.59,157.83)
  L7 w0.061: 82.23,156.9 82.23,156.62 82.65,156.2 82.65,155.96 82.65,155.95 82.65,155.38 82.94,155.09 82.94,153.81 83.15,153.6 83.15,153.39 83.54,153 84.13,153 84.66,152.46 84.66,151.85 84.88,151.63 v4(85.08,151.63)
GYRO_INT2: length 102.8
  TOP w0.114: v2(35.8,142.29) v1(36.36,142.29)
  L2 w0.061: v9(38.26,173.37) 38.04,173.15 36.79,173.15 35.34,171.7 35.34,142.74 v2(35.8,142.29) ; v10(75.4,141.22) 80.58,146.4 83.16,146.4 85.43,148.67 85.43,150.11 85.99,150.67 86.65,150.67 v10(86.7,150.72)
  L3SGND w0.127: v10(75.4,141.22) 75.14,140.96 v11(75.02,140.96) ; v10(86.7,150.72) 86.5,150.92 v11(86.37,150.92)
  L5 w0.076: v11(75.02,140.96) 74.88,140.83 74.82,140.83 73.07,139.09 39,139.09 v2(35.8,142.29) ; v11(86.37,150.92) 86.21,150.92 85.21,151.93 84.78,151.93 82.45,154.25 82.45,155.01 79.46,158 v8(79.46,158.4)
GYRO_SA0: length 2.8
  TOP w0.114: 40.12,175.1 v1(40.14,175.08) ; 40.12,175.1 R4208.2 38.98,174.88 GYRO1.4 ; 40.12,175.1 40.04,175.18 R4209.1
HALL_INT#: length 163.4
  TOP w0.114: U1704.J5 94.04,32.66 93.66,33.04 v2(93.64,33.04) ; v9(111.85,50.46) 112.25,50.87 112.25,56.47 112.25,56.48 112.25,56.84 112.25,56.85 112.25,60.47 v9(111.92,60.8) ; R3807.2 112.6,132.37 v1(112.74,132.23) 112.81,132.15 v9(114.29,132.15)
  L2 w0.061: v2(94.86,14.8) 95.49,14.8 96.22,14.07 98.49,14.07 98.87,14.45 103.67,14.45 105.88,16.66 107.29,16.66 108.81,18.18 112.35,18.18 113.02,18.85 v9(113.02,19.01) ; v2(93.64,33.04) 98.54,33.04 98.8,32.78 101.17,32.78 101.2,32.81 101.52,32.81 102.33,33.62 102.33,34.54 102.5,34.71 103.04,34.71 103.77,35.44 103.77,37.46 103.19,38.04 103.19,38.37 103.03,38.52 102.74,38.52 102.57,38.69 102.57,38.92 102.74,39.09 102.78,39.09 103.9,40.2 104.51,40.2 105.78,41.47 105.78,45.84 110.4,50.46 v9(111.85,50.46) ; v9(114.29,132.15) 114.29,131.79 114.13,131.63 114.13,131.49 113.98,131.34 113.98,121.6 113.49,121.11 113.49,116.69 113.98,116.2 113.98,106.06 112.99,105.07 112.99,101.53 113.39,101.12 113.39,90.28 109.43,86.32 109.43,79.6 111.7,77.34 111.7,61.03 v9(111.92,60.8)
  L5 w0.076: v2(94.86,14.8) 94.73,14.8 94.35,15.18 94.35,15.82 95.53,17 95.53,18.2 92.94,20.79 92.94,22.09 93.33,22.48 93.33,30.52 94.07,31.26 94.07,32.51 93.64,32.94 v2(93.64,33.04)
HALL_VDD: length 126.8
  TOP w0.254: R4205.1 113.52,133.85 113.73,133.65 C4210.1 113.91,132.94 v1(113.96,132.89) 114.29,132.56 114.64,132.56 v9(114.79,132.41)
  L2 w0.254: v2(111.24,45.03) 110.73,45.03 109.21,43.51 109.21,40.43 108.24,39.47 108.24,27.96 109.08,27.12 109.61,27.12 109.94,26.79 110.36,26.79 110.43,26.87 111.82,26.87 113.27,25.42 113.27,22.5 113.78,21.99 113.78,20.15 v9(114.92,19.01) ; v9(114.79,132.41) 114.79,131.9 114.41,131.52 114.41,131.37 114.27,131.22 114.27,121.49 114.27,121.34 113.78,120.85 113.78,116.91 114.27,116.42 114.27,105.95 113.27,104.95 113.27,101.65 113.68,101.24 113.68,90.16 109.71,86.2 109.71,79.78 110.53,78.96 112,77.49 v10(112,61.26)
  L3SGND w0.254: v11(112.56,61.26) v10(112,61.26)
  L6SGND w0.254: v11(112.56,61.26) 112.56,60.78 v5(112.53,60.75)
  BOTTOM w0.254: v2(111.24,45.03) 111.49,45.03 112.18,45.71 112.18,60.4 v5(112.53,60.75)
HOME_BTN_EC#: length 196.9
  TOP w0.114: v10(94.09,40.33) R1716.1 94.24,40.16 94.24,39.42 94.4,39.25 94.4,38.88 94.12,38.6 93.89,38.6 93.53,38.23 U1704.H12 ; v9(107.08,185.33) 107.21,185.46 107.56,185.46 v1(108.87,186.76) 110.07,187.97 110.07,193.61 111.04,194.58 111.9,194.58 112.24,194.92 D5405.2
  L2 w0.061: v9(107.08,185.33) 106.83,185.33 106.46,184.95 104.45,184.95 104.02,184.52 100.2,184.52 99.27,185.45 99.27,185.79 99.27,186.11 99.17,186.2 v10(99.17,187.04)
  L3SGND w0.127: v10(99.17,187.04) 99.35,187.04 v11(99.5,186.89) ; v11(93.52,40.78) 93.65,40.78 v10(94.09,40.33)
  L5 w0.076: v4(98.51,149.68) 97.8,148.97 97.8,140.06 97.75,140.01 97.75,136.43 97.75,135.68 97.8,135.63 97.8,133.77 98.11,133.47 98.11,123.24 98.08,123.22 98.08,122.87 98.02,122.8 98.02,122.2 98.73,121.49 98.73,111.03 99.17,110.58 99.17,110.11 99.17,110.11 99.17,96.15 97.27,94.24 97.27,91.65 97.33,91.58 97.33,91.24 97.09,90.99 97.08,90.99 97.07,90.98 96.68,90.98 94.66,88.97 94.66,87.8 94.64,87.78 94.64,84.35 94.23,83.94 94.23,82.17 94.23,82.17 94.23,80.91 94.23,80.75 94.23,79.8 94.23,79.8 94.23,79.5 90.96,76.23 90.96,76.07 90.96,74.59 90.5,74.14 90.5,73.18 90.5,72.47 90.5,72.47 90.5,71.52 90.5,71.52 90.5,68.17 90.5,68.17 90.5,66.86 90.5,66.86 90.5,57.43 90.5,57.43 90.5,55.48 90.92,55.06 91.44,54.54 91.44,54.54 93.13,52.85 93.13,41.72 93.39,41.46 93.39,41.44 93.41,41.41 93.41,40.89 v11(93.52,40.78) ; v4(91.55,164.26) 91.39,164.42 91.36,164.42 89.34,166.43 89.34,166.94 86.6,169.68 86.6,171.5 89.71,174.61 90.06,174.61 90.06,174.61 93.18,174.61 95.96,177.39 96.98,177.39 97.24,177.65 97.24,180.05 97.95,180.76 97.95,180.79 98.66,181.54 99.55,182.43 99.55,186.84 v11(99.5,186.89)
  L7 w0.061: v4(98.51,149.68) 98.75,149.91 98.75,150.22 100.19,151.66 100.92,152.4 101.02,152.5 101.02,156.18 99.98,157.22 98.99,157.22 96.03,157.22 92.14,161.11 92.14,163.18 91.83,163.49 91.83,163.98 v4(91.55,164.26)
HOME_BTN_SOC#: length 140.4
  TOP w0.114: R5401.2 113.54,196.14 D5405.1 113.15,195.49 112.01,194.36 111.14,194.36 110.45,193.67 v1(110.45,191.59) 110.45,189.71 v9(110.73,189.43) ; v9(88.99,189.81) 88.15,188.97 87.99,188.97 85.4,186.38 66.81,186.38 65.67,185.24 65.67,181.91 62.42,178.66 53.33,178.66 51.4,176.73 49.39,176.73 45.78,173.11 45.78,164.96 v2(45.73,164.92)
  L2 w0.061: v9(110.73,189.43) 109.08,191.08 106.8,191.08 106.37,191.51 105.64,191.51 104.72,192.43 90.26,192.43 88.99,191.16 v9(88.99,189.81)
  L7 w0.06: v8(70.97,156.7) 70.97,155.83 70.73,155.58
  L7 w0.061: 70.73,155.58 70.69,155.55 70.69,153.1 67.21,149.63 67.21,148.99 66.4,148.18 62.38,148.18 61.41,147.21 50.74,147.21 46.47,151.48 46.47,161.64 45.74,162.37 45.74,164.6 45.73,164.61 v2(45.73,164.92)
HOME_KEY: length 5.7
  TOP w0.114: R5406.2 C5405.2 111.26,191.43 TP5404.1 111.62,190.13 D5403.1 111.83,189.46 HKEY1.2
HOME_KEY_R: length 3.7
  TOP w0.114: R5406.1 111.77,192.91 111.8,192.93 C5406.1 111.8,193.11 111.34,193.57 v1(111.34,193.9) 111.39,193.9 111.62,194.13 112.74,194.13 112.89,193.97 D5405.3
HP_OUT_L: length 11.2
  L2 w0.254: v10(96.02,199.26) 96.23,199.26 100.49,203.53 v10(100.85,203.53)
  L3SGND w0.254: v10(96.02,199.26) v11(95.66,199.26) ; v11(101.21,203.53) v10(100.85,203.53)
  L5 w0.254: v11(101.21,203.53) 101.33,203.65 v5(101.33,203.88) ; v11(95.66,199.26) 95.66,199.27 v5(95.29,199.64)
  BOTTOM w0.203: v5(101.33,203.88) 101.33,203.55 101.46,203.42 101.46,202.77 v1(101.49,202.74) 101.51,202.72 U2001.18
  BOTTOM w0.508: v5(95.29,199.64) R2209.1
HP_OUT_L_1: length 5.8
  BOTTOM w0.254: AUDIO1.1 93.84,197.38 v1(93.86,197.38) 93.86,198.39 R2209.2 94.42,199.59 D2202.2
HP_OUT_R: length 12.5
  L2 w0.254: v10(95.36,203.93) 95.81,204.38 101.34,204.38 v5(101.84,203.88)
  L3SGND w0.254: v11(95.06,203.75) 95.19,203.75 v10(95.36,203.93) ; v11(101.84,203.53) v5(101.84,203.88)
  L5 w0.254: v5(101.84,203.88) v11(101.84,203.53)
  L6SGND w0.254: v11(95.06,203.75) v5(94.7,203.75)
  BOTTOM w0.203: v5(101.84,203.88) 101.99,203.73 101.99,203.2 102.09,203.1 102.09,202.64 101.91,202.46 U2001.19
  BOTTOM w0.356: C2203.1 95.12,203.07 v1(95.55,202.64)
  BOTTOM w0.508: v5(94.7,203.75) 94.68,203.73 C2203.1
HP_OUT_R_1: length 3.8
  BOTTOM w0.254: D2203.2 93.86,203.73 R2210.2 93.84,204.34 93.48,204.7 AUDIO1.2
HP_RING: length 5.5
  L5 w1.016: v5(95.87,204.31) 96,204.19 96,203.19 98.61,200.57 v5(98.61,200.5)
  BOTTOM w0.356: 96.25,204.67 v1(96.76,204.67)
HP_RING_1:
  vias: v1(95.36,206.42)
HP_SLEEVE: length 12.2
  L5 w1.016: v5(96,201.11) 95.49,200.6 95.16,200.6 94.47,199.92 94.47,199.09 92.33,196.95 87.89,196.95 87.11,196.17 v2(87.11,196.16)
  BOTTOM w0.305: R2207.1 86.88,195.8 87.11,196.03 v2(87.11,196.16)
  vias: v1(96.89,201.49)
HP_SLEEVE_1: length 15.6
  L5 w1.016: v5(85.58,195.47) 85.58,196.24 85,196.82 82.7,196.82 81.11,198.4 81.11,205.89 AUDIO1.4
HPO_L_RC: length 2.5
  BOTTOM w0.254: R2013.2 101.05,205.99 v1(101.08,205.96) 101.33,205.71 C2005.2
HPO_R_RC: length 2.4
  BOTTOM w0.254: C2004.2 101.84,204.94 v1(102.09,205.19) 102.09,205.66 102.42,205.99 R2012.2
HW_RST1: length 10.6
  TOP w0.114: U5401.5 102.68,131.39 102.78,131.29 v1(102.78,130.98) 102.78,130.73 102.45,130.4 97.99,130.4 97.06,131.33 96.18,131.33 95.74,131.77 D5411.3
I2C0_SCL: length 9.7
  L7 w0.06: v8(72.1,156.7) 72.06,156.66 72.06,155.25 72.08,155.24
  L7 w0.061: v5(69.07,149.7) 69.07,149.73 70.02,150.68 70.02,151.2 71.1,152.27 71.61,152.27 71.92,152.58 71.92,152.6 72.08,152.76 72.08,155.24
  BOTTOM w0.114: v1(68.16,150.31) 68.36,150.31 68.97,149.7 v5(69.07,149.7)
I2C0_SDA: length 7.9
  L7 w0.06: v8(72.39,156.42) 72.35,156.38 72.35,152.61 72.27,152.53 72.27,152.47 72.27,152.47
  L7 w0.061: 72.27,152.47 72.27,152.3 71.92,151.94 71.92,151.68 71.16,150.92 70.79,150.92 70.09,150.23 v5(70.09,149.7)
I2C1_SCL: length 252.1
  L3SGND w0.061: v10(102.67,53.87) v11(102.2,53.87)
  L5 w0.076: v4(46.54,167.84) 46.98,167.41 46.98,161.28 46.05,160.35 46.05,159.14 46.66,158.52 46.66,151.36 50.64,147.38 54.22,147.38 55.09,146.51 61.67,146.51 62.62,145.56 65.33,145.56 66.55,146.78 66.62,146.78 69.51,149.68 v5(69.66,149.68) 69.66,149.47 69.54,149.36 69.54,148.77 69.71,148.6 69.75,148.6 70.42,147.93 70.42,147.77 70.42,147.46 70.42,147.46 70.42,147.37 79.7,138.08 82.31,138.08 82.63,138.08 82.64,138.08 82.79,138.08 82.89,138.08 84.5,136.47 84.5,134.15 84.77,133.88 84.77,133.61 86.51,131.87 86.51,131.35 86.68,131.19 v4(86.68,130.42) ; v4(80.43,182.14) 80.47,182.14 80.75,182.41 80.75,185.1 83.97,188.32 83.97,188.54 86.29,190.85 87.57,190.85 v4(87.77,191.05)
  L6SGND w0.089: v11(102.2,53.87) v4(101.76,53.87)
  L7 w0.06: 72.2,155.53 72.18,155.54 72.18,156.5 72.3,156.62 72.3,156.78 72.11,156.98 72.11,157.26 v8(72.1,157.27)
  L7 w0.061: v5(103.75,194.64) 103.9,194.48 103.9,194.14 103.39,193.62 99.3,193.62 98.44,192.76 88.77,192.76 87.77,191.76 v4(87.77,191.05) ; v5(69.66,149.68) 69.66,150.06 70.27,150.67 70.27,151.18 71.22,152.13 71.86,152.13 72.1,152.37 72.1,152.61 72.13,152.64 72.2,152.71 72.2,155.53 ; v4(86.68,130.42) 86.6,130.42 86.3,130.12 86.3,123.38 88.33,121.34 88.33,121.34 88.43,121.24 88.54,121.14 88.95,120.73 88.95,120.72 88.95,109.77 88.95,109.18 88.95,109.1 88.95,109.02 88.95,108.86 88.95,108.38 88.38,107.81 88.38,98.78 88.21,98.6 88.21,98.6 88.03,98.42 88.03,94.56 88,94.53 88,80.99 88.1,80.89 88.57,80.42 88.57,79.99 88.57,79.84 88.57,79.84 88.57,79.11 88.57,78.72 89.49,77.81 89.49,77.23 89.49,76.67 90.89,75.26 90.89,61.25 91.57,60.58 91.57,56.6 91.79,56.38 91.79,56.38 v5(91.91,56.26) ; v4(80.43,182.14) 80.26,181.97 70.21,181.97 69.21,180.97 69.01,180.77 68.31,180.77 68.31,180.77 67.87,180.77 67.4,181.24 67.4,181.27 66.99,181.68 62.76,181.68 62.76,181.68 62.47,181.68 62.18,181.68 61.89,181.68 61.89,181.68 49.4,181.68 46.21,178.5 46.21,168.17 v4(46.54,167.84) ; v5(97.14,56.46) 97.06,56.38 97.06,56.01 98.16,54.91 100.73,54.91 v4(101.76,53.87)
  BOTTOM w0.114: v5(91.91,56.26) 91.93,56.24 96.92,56.24 v5(97.14,56.46) ; U2001.39 103.11,195.4 102.85,195.14 v1(102.85,194.78) 103.6,194.78 v5(103.75,194.64)
I2C1_SDA: length 252.9
  L3SGND w0.061: v10(102.67,53.37) 102.25,53.37 v11(102.2,53.31)
  L5 w0.076: v4(80.45,182.53) 80.55,182.63 80.55,185.18 83.78,188.4 83.78,188.62 86.27,191.1 86.6,191.1 v5(86.68,191.18) ; v4(46.09,166.85) 46.58,166.35 46.58,161.42 45.67,160.5 45.67,158.98 46.28,158.37 46.28,151.2 50.48,147 54.06,147 54.93,146.13 61.51,146.13 62.46,145.18 65.49,145.18 65.87,145.56 66.02,145.56 66.49,146.03 67,146.03 68.72,147.75 68.72,148.41 68.95,148.64 69.3,148.64 v4(69.61,148.33) 69.61,147.91 79.62,137.89 82.38,137.89 82.82,137.89 84.31,136.39 84.31,134.07 84.58,133.8 84.58,133.54 86.32,131.8 86.32,130.27 86.57,130.02 v4(86.6,130.02)
  L6SGND w0.089: v11(102.2,53.31) v4(101.79,53.31)
  L7 w0.06: v8(72.39,156.98) 72.47,156.9 72.47,156.62 72.59,156.5 72.59,156.28 72.47,156.16 72.47,155.67 72.98,155.16
  L7 w0.061: v4(80.45,182.53) 80.41,182.53 80.02,182.15 70.28,182.15 70.14,182.15 69.04,181.05 69.04,181.05 68.93,180.94 68.24,180.94 67.95,180.94 67.58,181.32 67.58,181.34 67.17,181.75 67.06,181.86 62.69,181.86 62.68,181.86 62.39,181.86 61.96,181.86 49.32,181.86 46.04,178.57 46.04,178.43 46.04,168.1 46.15,167.99 46.15,166.91 v4(46.09,166.85) ; v4(69.61,148.33) 70.03,148.33 70.37,148.67 70.37,149.88 70.31,149.94 70.31,150.2 70.86,150.75 71.31,150.75 72.09,151.54 72.09,151.68 72.09,151.87 72.45,152.22 72.45,152.46 72.73,152.75 v5(72.73,152.85) 72.98,153.1 72.98,155.16 ; v4(86.6,130.02) 86.52,129.94 86.52,123.4 88.4,121.52 88.51,121.42 88.61,121.31 89.12,120.8 89.12,120.8 89.12,109.85 89.12,109.43 89.12,109.28 89.12,109.24 89.12,109.16 89.12,109.02 89.12,108.84 89.12,108.31 88.56,107.74 88.56,98.7 88.38,98.52 88.38,95.1 88.38,94.66 88.2,94.49 88.2,94.48 88.17,94.46 88.17,81.07 88.75,80.49 88.75,79.91 88.75,79.77 88.75,78.89 88.75,78.89 88.75,78.79 89.66,77.88 89.66,77.15 89.66,76.74 91.4,75 91.4,72.3 91.07,71.97 91.07,61.33 91.74,60.65 91.74,56.83 v5(91.91,56.66) ; v5(103.62,194.25) 103.62,194.23 103.18,193.79 99.23,193.79 98.37,192.94 88.7,192.94 87.44,191.68 87.44,191.49 87.13,191.18 v5(86.68,191.18) ; v4(101.79,53.31) 100.37,54.73 98.09,54.73 96.86,55.97 96.86,56.68 96.87,56.7 v5(96.87,56.73)
  BOTTOM w0.114: v5(103.62,194.25) 103.42,194.25 103.24,194.44 103.02,194.44 103,194.42 102.7,194.42 102.37,194.75 102.37,195.06 102.71,195.41 U2001.40 ; v5(91.91,56.66) 91.98,56.59 96.73,56.59 v5(96.87,56.73)
I2C2_SCL: length 174.9
  L5 w0.076: v5(82.38,139.39) 82.38,139.64 81.89,140.13 79,140.13 72.07,147.06 72.07,147.7 70.98,148.79 v5(70.98,150.08) 70.98,150.26 70.97,150.27 70.97,150.51 71.14,150.68 71.59,150.68 72.72,151.81 72.72,152.43 72.72,152.43 72.72,156.35 72.39,156.68 72.39,158.11 v8(72.39,158.12)
  L7 w0.061: v5(82.38,139.39) 82.85,139.39 83.81,140.35 83.91,140.45 83.91,140.45 84.29,140.83 84.29,141.05 84.56,141.32 84.94,141.32 85.21,141.05 85.21,141.03 85.31,140.93 85.31,138.16 86.26,137.2 86.26,135.77 86.29,135.74 86.29,131.18 86.26,131.15 85.92,130.82 85.59,130.49 85.59,123.34 88.11,120.82 88.22,120.72 88.32,120.61 88.42,120.51 88.42,120.51 88.42,109.56 88.42,109.45 88.42,109.42 88.42,109.14 88.42,109 88.42,108.91 88.42,108.6 87.86,108.03 87.86,98.99 87.68,98.82 87.5,98.64 87.5,98.2 87.5,94.78 87.47,94.75 87.47,81.96 87.47,80.78 87.88,80.37 88.05,80.2 88.05,80.06 88.05,78.5 88.25,78.3 88.96,77.59 88.96,77.44 88.96,77.44 88.96,76.45 89.22,76.19 89.22,76.05 89.22,74.8 89.6,74.42 89.6,73.5 89.6,73.35 89.16,72.92 89.16,69.33 88.94,69.11 88.94,68.6 v5(88.99,68.54)
  BOTTOM w0.114: U1702.5 v5(88.99,68.54) ; v5(82.38,139.39) 82.38,139.36 80.88,137.85 80.87,137.85 80.66,137.64 v1(80.58,137.64) 80.57,137.63 38.31,137.63 37.2,138.74 29.69,138.74 28.31,137.36 24.68,137.36 21.6,140.43 18.86,140.43 18.02,141.27 R4006.2 ; v5(70.98,150.08) 70.98,150.06 71.11,149.93 R629.1
I2C2_SDA: length 174.9
  L5 w0.076: v8(72.1,158.96) 72.1,158.02 72.13,158 72.13,156.64 72.58,156.19 72.58,152.57 72.59,152.57 72.53,152.51 72.53,152.35 72.53,152.35 72.53,151.89 71.51,150.87 71.03,150.87 70.6,150.44 v5(70.6,150.08) 70.6,148.9 71.88,147.62 71.88,146.98 78.93,139.94 81.43,139.94 v5(81.98,139.39)
  L7 w0.061: v5(88.37,68.47) 88.73,68.83 88.73,69.21 88.99,69.46 88.99,72.99 89.42,73.42 89.42,74.34 89.04,74.73 89.04,76.12 88.78,76.38 88.78,77.52 88.18,78.12 87.87,78.43 87.87,80.13 87.81,80.19 87.3,80.7 87.3,81.6 87.3,82.03 87.3,82.03 87.3,94.82 87.33,94.85 87.33,98.13 87.33,98.71 87.68,99.07 87.68,108.11 88.25,108.67 88.25,108.94 88.25,109.03 88.25,109.14 88.25,109.42 88.25,109.48 88.25,109.48 88.25,120.43 88.25,120.44 88.14,120.54 88.04,120.64 85.41,123.27 85.41,123.6 85.41,123.6 85.41,129.3 85.41,130.56 85.85,131 85.98,131.12 86.08,131.23 86.11,131.26 86.11,135.67 86.09,135.69 86.09,137.13 85.34,137.88 85.34,137.88 85.13,138.08 85.13,140.86 85.03,140.96 85.03,140.98 84.86,141.15 84.63,141.15 84.46,140.98 84.46,140.76 82.81,139.11 82.26,139.11 v5(81.98,139.39)
  BOTTOM w0.114: v5(81.98,139.39) 81.83,139.39 v1(81.52,139.08) 81.51,139.08 80.29,137.86 38.4,137.86 37.29,138.97 29.54,138.97 28.15,137.59 24.83,137.59 21.73,140.69 19.11,140.69 R4007.2 ; U1702.4 v5(88.37,68.47) ; R628.1 v5(70.6,150.08)
I2C3_SCL: length 129.2
  TOP w0.114: v2(76.26,183.05) 76.64,183.43 76.64,183.64 78.7,185.69 v1(80.05,185.69) 85.53,185.69 88.12,188.29 88.51,188.29 89.07,188.85 91.22,188.85 91.5,188.56 94.8,188.56 94.96,188.41 95.29,188.41 95.5,188.2 97.03,188.2 97.48,188.65 98.13,188.65 98.44,188.33 CAMF1.6
  L2 w0.061: v10(45.58,152.85) 45.58,157.9 43.24,160.24 43.24,167.48 45.17,169.4 45.17,176.86 48.72,180.41 73.62,180.41 v2(76.26,183.05)
  L3SGND w0.061: v10(45.58,152.85) v11(45.58,152.47)
  L6SGND w0.127: v4(45.96,152.22) 45.71,152.47 v11(45.58,152.47)
  L7 w0.06: 72.67,156 v8(72.67,156.06)
  L7 w0.061: v4(45.96,152.22) 46.04,152.14 46.04,150.93 50.85,146.12 51.29,146.12 52.12,146.95 61.77,146.95 62.2,147.37 62.61,147.78 65.74,147.78 65.78,147.74 70.31,147.74 71.55,148.98 71.55,150.74 72.27,151.46 72.27,151.78 72.73,152.24 v5(72.73,152.34) 72.73,152.45 73.1,152.82 73.1,155.57 72.67,156
  BOTTOM w0.114: v2(76.26,183.05) 75.73,182.52 72.25,182.52 72.05,182.72 R2506.1
I2C3_SDA: length 128.2
  TOP w0.114: v9(92.75,189.99) 91.88,189.12 88.76,189.12 88.34,188.7 88.16,188.7 85.53,186.08 78.62,186.08 v2(75.58,183.03)
  L2 w0.061: v10(45.07,152.22) 45.25,152.39 45.25,157.98 43.06,160.17 43.06,167.55 44.99,169.48 44.99,176.93 48.71,180.65 73.2,180.65 v2(75.58,183.03) ; v9(98.13,189.99) 97.57,189.99 97.5,189.91 94.78,189.91 94.62,190.07 92.83,190.07 v9(92.75,189.99)
  L3SGND w0.061: v10(45.07,152.22) 45.07,152.09 v11(45.42,151.73)
  L6SGND w0.089: v11(45.42,151.73) 45.45,151.71 45.68,151.71 v4(45.75,151.63)
  L7 w0.061: v8(72.92,156.38) 72.99,156.31 72.99,156.02 73.47,155.55 73.47,152.83 73.3,152.67 73.3,151.89 v5(72.73,151.33) 72.29,150.89 72.29,148.92 70.94,147.56 65.71,147.56 65.67,147.61 62.68,147.61 62.37,147.3 61.85,146.77 52.19,146.77 51.36,145.94 50.78,145.94 45.71,151.01 45.71,151.59 v4(45.75,151.63)
  BOTTOM w0.114: v2(75.58,183.03) 75.47,182.93 73.66,182.93 v1(73.51,183.08) 73.27,182.84 R2505.1
I2C4_SCL: length 171.6
  L5 w0.076: v5(72.73,150.31) 72.73,150.29 72.45,150.01 72.45,149.24 72.71,148.98 72.71,148.14 72.83,148.02 72.83,147.38 75.3,144.91 79.32,140.89 82.21,140.89 83.26,139.84 83.26,139.68 83.26,139.37 84.23,138.41 84.23,138.4 84.62,138.01 84.62,138.01 86.14,136.49 86.14,134.91 87.38,133.68 v4(88.1,133.68)
  L7 w0.06: 73.87,153.08 73.87,156.34 73.02,157.2 72.74,157.2 v8(72.67,157.27)
  L7 w0.061: v5(89.75,56.43) 89.75,56.21 85.15,51.61 85.15,49.73 v5(85,49.58) ; v4(88.1,133.68) 87.99,133.78 87.99,134.93 88,134.93 88,135.19 90.29,137.48 98.41,137.48 100.59,137.48 100.69,137.38 100.69,137.38 101.19,136.88 103.52,136.88 103.95,136.88 106.03,134.8 106.03,134.8 106.44,134.39 106.44,134.38 106.44,132.97 107.93,131.47 107.93,123.51 104.32,119.9 v5(104.32,119.35) 104.43,119.24 104.43,93.23 102.66,91.45 102.66,89.95 100.38,87.68 100.38,85.82 100.53,85.67 100.53,80.24 100.53,80.24 100.53,80.07 100.53,73.67 100.53,71.62 98.22,69.31 97.88,68.97 97.88,60.83 97.44,60.4 97.44,57.05 97.75,56.74 97.75,56.32 v5(97.91,56.15) ; v5(72.73,150.31) 73.19,150.77 73.19,150.97 73.65,151.43 73.65,152.65 73.87,152.87 73.87,153.08
  BOTTOM w0.114: v5(97.91,56.15) 97.88,56.15 97.45,55.72 91.14,55.72 90.44,56.43 v5(89.75,56.43) ; U1707.5 84.87,35.63 84.87,49.44 v5(85,49.58)
I2C4_SDA: length 171.6
  L5 w0.076: v5(72.73,150.82) 72.73,150.73 72.71,150.7 72.26,150.26 72.26,149.16 72.52,148.91 72.52,148.22 72.52,148.06 72.64,147.94 72.64,147.3 73.44,146.5 75.11,144.83 79.24,140.7 82.13,140.7 83.07,139.76 83.07,139.29 84.03,138.33 84.03,138.32 84.54,137.82 84.55,137.82 85.95,136.41 85.95,134.84 87.3,133.48 87.88,133.48 88.02,133.34 v4(88.3,133.34)
  L7 w0.06: 73.72,154.86 73.72,156.22 v8(73.24,156.7)
  L7 w0.061: v4(88.3,133.34) 88.38,133.43 88.38,133.79 88.17,134.01 88.17,134.85 88.17,134.86 88.17,135.12 90.36,137.3 98.49,137.3 100.52,137.3 101.12,136.7 103.59,136.7 103.88,136.7 105.96,134.62 106.26,134.32 106.26,134.3 106.26,133.58 106.26,133.58 106.26,132.9 107.76,131.4 107.76,123.58 104.03,119.85 104.03,119.56 104.03,118.33 104.15,118.21 v5(104.15,118.13) 104.15,93.19 102.48,91.52 102.48,90.02 100.21,87.75 100.21,85.75 100.35,85.6 100.35,80.17 100.35,79.99 100.35,73.75 100.35,73.6 100.35,73.46 100.35,71.7 98.15,69.49 97.7,69.04 97.7,60.9 97.27,60.47 97.27,56.97 97.58,56.67 97.58,56.36 v5(97.34,56.13) ; 73.72,154.86 73.72,152.89 73.47,152.64 73.47,151.56 v5(72.73,150.82) ; v5(89.32,56.49) 89.32,56.03 84.97,51.68 84.97,50.06 v5(84.85,49.93)
  BOTTOM w0.114: v5(84.85,49.93) 84.64,49.72 84.64,35.33 85.44,34.52 U1707.4 ; v5(89.32,56.49) 89.59,56.76 90.49,56.76 91.3,55.95 97.17,55.95 v5(97.34,56.13)
I2C5_SCL: length 99.8
  L5 w0.06: v5(71.26,150.39) 71.3,150.42 71.6,150.42 72.9,151.73 72.9,152.67 72.91,152.67 72.9,152.68 72.9,156.36 72.51,156.75 72.51,157.92 72.6,158.01 72.6,158.33 v8(72.67,158.4)
  L5 w0.076: v5(71.26,150.39) 71.39,150.27 71.39,149.5 72.13,148.75 72.13,148.18 72.45,147.86 72.45,147.22 75.11,144.56 79.16,140.51 82.05,140.51 82.88,139.68 82.88,139.21 83.84,138.25 83.84,138.24 84.46,137.62 84.47,137.62 85.43,136.66 v4(85.43,135.61)
  L7 w0.061: v5(86.6,72.72) 86.94,73.05 86.94,73.21 87.63,73.9 87.63,76.79 87.63,77.43 87.21,77.84 86.77,78.28 86.73,78.33 86.73,93.71 86.36,94.07 86.26,94.18 86.26,98.1 86.26,98.51 86.82,99.06 87.16,99.4 87.16,108.32 87.72,108.89 87.72,109.37 87.72,120.21 87.72,120.22 84.89,123.05 84.89,123.82 84.89,123.82 84.89,129.08 84.89,130.78 84.91,130.8 85.12,131.01 85.22,131.11 85.58,131.47 85.58,135.45 v4(85.43,135.61)
  BOTTOM w0.114: v1(71.97,151.01) 71.79,150.83 71.79,150.64 71.54,150.39 71.28,150.39 ; U4301.5 86.61,72.71 v5(86.6,72.72) ; 71.28,150.39 71.61,150.06 R635.1 ; 71.28,150.39 v5(71.26,150.39)
I2C5_SDA: length 98.2
  L5 w0.076: v4(71.66,148.69) 71.66,148.38 72.26,147.78 72.26,147.14 79.08,140.32 81.97,140.32 82.69,139.6 82.69,139.13 83.65,138.17 83.65,138.16 84.38,137.43 84.39,137.43 85.13,136.7 85.13,135.4 v4(85.28,135.25)
  L7 w0.06: 73.29,154.52 73.29,155.55 72.87,155.97 72.87,156.14 72.72,156.3 72.72,156.46 72.87,156.62 72.95,156.7 v8(72.95,156.98)
  L7 w0.061: v5(86.65,73.17) 87.45,73.97 87.45,76.72 87.45,77.35 87.04,77.77 86.55,78.25 86.55,93.64 86.29,93.9 86.09,94.1 86.09,98.03 86.09,98.58 86.98,99.47 86.98,108.58 87.51,109.11 87.51,116.39 86.8,117.1 84.93,118.97 84.93,120.11 84.95,120.13 84.95,120.66 84.95,120.66 84.95,122.46 84.95,122.47 84.71,122.7 84.71,122.87 84.71,129.01 84.71,129.01 84.71,130.85 84.74,130.88 84.94,131.08 85.05,131.18 85.15,131.29 85.26,131.4 85.26,133.48 85.4,133.62 85.4,133.85 85.26,134 85.26,135.23 v4(85.28,135.25) ; 73.29,154.52 73.29,152.83 73.12,152.67 73.12,152.23 v5(72.73,151.84) 72.45,151.55 72.45,151.39 71.72,150.67 71.72,148.75 v4(71.66,148.69)
  BOTTOM w0.114: v1(85.87,70.78) 86.61,71.52 U4301.4 86.58,71.64 86.27,71.95 86.27,72.83 86.47,73.03 86.51,73.03 v5(86.65,73.17)
I2C6_SCL: length 65.3
  L2 w0.061: v10(71.87,149.58) v12(73.29,148.15) 74.38,147.06 75.71,147.06 76.8,148.16 76.8,150.12 77.2,150.52 77.76,150.52 77.77,150.52 82.35,150.52 88.49,156.65 98.56,156.65 v10(101.18,159.27)
  L3SGND w0.061: v11(71.87,149.96) v10(71.87,149.58) ; v10(101.18,159.27) 101.19,159.28 101.33,159.28 v11(101.54,159.48)
  L5 w0.06: v5(72.01,150.41) 72,150.42 72,150.49 73.08,151.57 73.08,152.67 73.02,152.72 73.02,156.45 72.63,156.84 72.63,157.74 72.75,157.86 72.75,158.19 72.87,158.31 72.87,158.48 72.67,158.68 v8(72.67,158.96)
  L5 w0.076: v11(71.87,149.96) 72,150.08 72,150.39 v5(72.01,150.41) ; v11(101.54,159.48) 101.86,159.8 101.86,160.57 101.63,160.79 101.12,160.79 100.65,161.26 100.65,161.34 100.43,161.56 100.43,162 99.68,162.75 99.68,164.54 98.31,165.91 98.31,168.4 99,169.08 v11(99,169.25)
  L6SGND w0.06: v8(98.23,174.13) 98.43,173.93 98.43,173.09
  L6SGND w0.089: v11(99,169.25) 98.32,169.93 98.32,172.99 98.43,173.09
  BOTTOM w0.114: R637.1 72.12,150.19 72.01,150.3 v5(72.01,150.41)
I2C6_SDA: length 62.6
  L2 w0.061: v10(72.91,149.09) 74.7,147.3 75.61,147.3 76.39,148.09 v12(76.39,149.19) 76.39,150.05 77.1,150.76 77.1,150.76 77.11,150.77 82.27,150.77 88.39,156.89 98.4,156.89 101.5,159.99 v10(101.52,159.99)
  L3SGND w0.061: v11(72.91,149.45) v10(72.91,149.09) ; v10(101.52,159.99) 101.51,159.99 101.47,159.99 101.43,160.03 101.43,160.36 v11(101.47,160.41)
  L5 w0.06: v5(72.74,149.89) 72.76,149.9 72.76,149.91 73.25,150.4 73.25,152.67 73.14,152.78 73.14,156.56 72.75,156.95 72.75,157.63 72.91,157.79 72.91,158.07 v8(72.95,158.12)
  L5 w0.076: v5(72.74,149.89) 72.76,149.88 72.76,149.78 72.91,149.63 v11(72.91,149.45) ; v11(98.97,169.78) 98.97,169.66 98.12,168.82 98.12,165.59 99.49,164.22 99.49,162.67 100.24,161.93 100.24,161.48 100.46,161.26 100.46,161.18 101.23,160.41 v11(101.47,160.41)
  L6SGND w0.06: v8(98.23,174.53) 98.43,174.33 98.71,174.33 98.83,174.21 98.83,173.11
  L6SGND w0.089: v11(98.97,169.78) 98.97,169.82 98.62,170.17 98.62,171.4 98.96,171.74 98.96,172.98 98.83,173.11
I2C_0_SCL_EC: length 39
  TOP w0.114: v10(84.67,34.49) 85.28,34.49 85.53,34.23 85.93,34.23 v1(85.93,34.24) 85.94,34.23 U1704.A7
  L3SGND w0.061: v11(84.29,34.49) v10(84.67,34.49)
  L6SGND w0.089: v4(84.77,34.49) v11(84.29,34.49)
  L7 w0.061: v5(88.99,66.21) 88.56,65.77 88.56,65.64 88.19,65.27 88.19,63.7 88.37,63.52 88.37,62.83 88.5,62.7 88.5,62.56 88.86,62.19 88.86,58.48 85.26,54.88 85.26,52.31 84.54,51.59 84.54,35.95 84.75,35.75 84.75,35.12 84.83,35.04 84.83,34.8 84.77,34.75 v4(84.77,34.49)
  BOTTOM w0.114: U1702.8 v5(88.99,66.21)
I2C_0_SDA_EC: length 42.7
  TOP w0.114: U1704.E7 90.48,33.87 89.09,33.87 88.84,34.13 88.84,34.35 88.57,34.61 86.6,34.61 86.19,35.02 85.02,35.02 v1(84.9,35.15) 84.62,35.43 v10(84.62,35.5)
  L3SGND w0.061: v10(84.62,35.5) v11(84.21,35.5)
  L6SGND w0.089: v11(84.21,35.5) 84.21,35.25 v4(84.54,34.92)
  L7 w0.061: v4(84.54,34.92) 84.54,35.15 84.37,35.33 84.37,51.66 85.09,52.38 85.09,54.95 88.69,58.55 88.69,62.12 88.32,62.48 88.32,62.63 88.19,62.76 88.19,63.45 88.02,63.63 88.02,65.35 88.37,65.7 v5(88.37,66.22)
  BOTTOM w0.114: U1702.1 v5(88.37,66.22)
I2C_1_SCL_CAM_R: length 4.8
  BOTTOM w0.114: CAMR1.28 71.86,187.35 71.95,187.27 71.95,185.99 71.66,185.71 v1(71.66,184.17) 71.66,183.78 R2506.2
I2C_1_SCL_EC: length 34.3
  TOP w0.114: U1704.C8 89.25,35.03 89.65,35.43 v2(89.65,35.43) ; v9(103.44,22.93) 103.17,22.93 102.53,23.57 v1(102.53,23.69) ; v9(105.91,26.06) 105.93,26.08 R2917.2
  L2 w0.061: v10(93.46,23.38) 93.46,23.2 94.36,22.3 96.78,22.3 98.61,24.13 99.21,24.13 99.99,23.34 100.93,23.34 101.32,22.95 102.54,22.95 102.59,22.99 103.11,22.99 103.18,22.93 v9(103.44,22.93) 105.91,25.4 v9(105.91,26.06)
  L3SGND w0.061: v11(92.95,23.52) 93.08,23.38 v10(93.46,23.38)
  L5 w0.076: v2(89.65,35.43) 89.65,35.21 90.68,34.18 90.68,33.92 92.04,32.56 92.04,31.9 90.68,30.54 90.68,28.65 91.39,27.93 92.1,27.23 92.35,26.97 92.35,25.8 92.8,25.35 92.8,23.67 v11(92.95,23.52)
  BOTTOM w0.114: R1706.1 89.7,35.38 v2(89.65,35.43)
I2C_1_SDA_CAM_R: length 5.1
  BOTTOM w0.114: CAMR1.27 71.87,187.75 72.18,187.44 72.18,184.35 72.56,183.97 R2505.2
I2C_1_SDA_EC: length 37.7
  TOP w0.114: v2(89.64,34.63) 89.65,34.64 89.65,34.69 89.99,35.03 U1704.D8 ; R2916.2 107.31,26.4 107.31,26.44 107.2,26.54 106.56,26.54 106.43,26.41 105.73,26.41 v9(105.6,26.28) ; R2908.2 102.91,22.17 102.45,22.63 102.45,22.88 102.42,22.91 v9(102.42,23.24)
  L2 w0.061: v9(105.6,26.28) 105.6,25.42 103.84,23.66 102.85,23.66 v9(102.42,23.24) 101.28,23.24 101,23.52 100.07,23.52 99.29,24.3 98.54,24.3 96.79,22.55 94.75,22.55 94.61,22.55 94.59,22.58 94.57,22.58 94.19,22.95 94.19,22.97 93.74,23.42 93.74,23.5 93.58,23.67 93.56,23.67 93.43,23.79 92.34,23.79 v10(91.83,23.29)
  L3SGND w0.061: v11(92.16,23.72) 91.83,23.39 v10(91.83,23.29)
  L5 w0.076: v2(89.64,34.63) 90.01,34.26 90.26,34.26 90.49,34.04 90.49,33.84 91.85,32.48 91.85,31.98 90.49,30.61 90.49,28.57 92.16,26.89 v11(92.16,23.72)
  BOTTOM w0.114: v1(89.09,35.48) 89.09,35.35 89.64,34.8 v2(89.64,34.63) 89.88,34.87 R1705.1
I2C_4_SCL_EC: length 66.7
  TOP w0.114: R1724.1 86.71,35.03 U1704.A8 ; v2(95.34,92.27) 95.44,92.17 96,92.17 96.13,92.3 v1(96.13,92.32) 95.57,92.88 PR4601.1
  L3SGND w0.061: v11(87.06,35.4) 87.06,35.45 86.89,35.62 86.6,35.62 86.59,35.63 v10(86.09,35.63)
  L5 w0.076: v2(95.34,92.27) 95.34,92.23 93.88,90.77 93.88,88.09 93.88,88.09 93.88,84.66 93.47,84.26 93.47,82.49 93.47,82.48 93.47,80.59 93.47,80.43 93.47,80.12 93.47,80.11 93.47,79.96 90.98,77.46 90.31,76.79 89.97,76.45 89.74,76.22 89.74,76.14 89.74,75.66 89.74,75.66 89.74,73.5 89.74,72.15 89.74,72.15 89.74,71.84 89.74,71.84 89.74,67.86 89.74,67.86 89.74,67.18 89.74,67.18 89.74,57.11 89.74,57.11 89.74,56.58 89.74,56.58 88.2,55.04 88.2,51.94 88.38,51.76 88.38,50.19 87.49,49.3 87.49,47.76 87.87,47.38 88.19,47.38 88.41,47.15 88.41,46.84 88.19,46.61 88.19,46.32 88.95,45.56 88.95,37.36 87.29,35.69 87.25,35.69 87.06,35.5 v11(87.06,35.4)
I2C_4_SDA_EC: length 63.5
  TOP w0.114: v2(95.34,91.64) 95.34,91.65 94.9,92.09 94.9,92.45 94.98,92.54 PR4602.1
  L3SGND w0.061: v10(89.24,35.83) 89.01,35.6 v11(89.01,35.38)
  L5 w0.076: v2(95.34,91.64) 95.34,91.49 94.07,90.22 94.07,88.02 94.07,88.01 94.07,84.58 93.66,84.18 93.66,82.41 93.66,82.41 93.66,80.67 93.66,80.51 93.66,80.51 93.66,80.04 93.66,80.04 93.66,79.79 89.93,76.06 89.93,75.74 89.93,72.79 89.93,72.23 89.93,71.76 89.93,67.94 89.93,67.94 89.93,67.1 89.93,67.1 89.93,57.19 89.93,56.5 89.37,55.94 89.37,54.33 89.01,53.98 89.01,53.66 89.15,53.52 89.15,36.53 89.01,36.39 v11(89.01,35.38) 89.01,34.62 89.6,34.03 v5(89.62,34.03)
  BOTTOM w0.114: v1(88.84,34.28) 89.14,34.28 89.39,34.03 v5(89.62,34.03)
I2C_5_SCL_3P3: length 6.9
  BOTTOM w0.114: U4301.8 87.71,72.21 C4305.1 88.76,72.21 89.39,72.84 v1(89.39,73.1) 89.74,73.44 89.99,73.44 91.43,74.87 92.32,74.87 92.77,74.42 TP1.8
I2C_5_SCL_EC: length 3.1
  L3SGND w0.061: v10(88.44,35.83) 88.2,35.83 v11(87.97,35.61)
  L5 w0.076: v5(86.49,35.05) 86.87,35.05 86.9,35.02 87.22,35.02 87.25,35.05 87.42,35.05 v11(87.97,35.61)
  BOTTOM w0.114: v5(86.49,35.05) 86.49,35.05 86.73,34.82 v1(87.21,34.82)
I2C_5_SDA_3P3: length 6.9
  BOTTOM w0.114: TP1.9 92.27,74.54 92.17,74.64 91.54,74.64 89.65,72.75 89.65,71.85 v1(89.39,71.6) C4306.1 87.7,71.6 U4301.1
I2C_5_SDA_EC: length 7.4
  TOP w0.114: U1704.E9 90.46,35.45 90.46,34.56 90.51,34.51 v10(90.51,34.51)
  L3SGND w0.061: v10(90.51,34.51) 90.54,34.51 90.54,34.49 90.46,34.41 90.46,34.28 90.11,33.93 v11(90.11,33.88)
  L5 w0.076: v5(86.5,34.36) 88.66,34.36 89.28,33.74 89.97,33.74 v11(90.11,33.88)
  BOTTOM w0.114: U1707.1 86.49,33.56 v1(86.7,33.35)
I2C_7_SCL_EC: length 43.5
  TOP w0.114: v9(101.97,36.57) 102.25,36.57 102.63,36.96 102.77,36.96 102.88,37.06 102.88,37.58 102.95,37.65 102.95,37.7 103.4,38.15 103.78,38.15 v9(103.9,38.27) 104.1,38.27 104.79,38.96 104.79,38.96 R1710.1 105.22,39.14 105.6,39.52 v1(105.78,39.52) ; U2901.L2 106.83,18.63 104.93,16.73 101.72,16.73 100.28,18.17 100.28,21.11 101.14,21.96 101.14,23 100.59,23.55 100.59,24.32 v9(100.6,24.33)
  L2 w0.061: v9(103.9,38.27) 104.25,37.92 104.25,37.72 104.3,37.68 104.3,35.22 104.25,35.17 104.25,34.88 103.8,34.43 103.8,33.12 103.46,32.78 103.46,32.56 102.32,31.42 102.32,31.15 100.43,29.26 100.43,29.02 100.34,28.93 100.34,25.45 100.6,25.19 v9(100.6,24.33) ; v9(94.84,37.43) 97.68,37.43 98.49,36.62 99.36,36.62 99.49,36.49 101.11,36.49 101.21,36.39 101.79,36.39 v9(101.97,36.57)
I2C_7_SDA_EC: length 41.4
  TOP w0.114: v9(96.05,37.79) 95.64,38.2 U1704.L12 ; v9(101.13,24.33) 101.08,24.28 v1(101.08,23.67) 101.08,23.44 101.36,23.15 101.36,21.82 100.51,20.97 100.51,18.26 101.69,17.09 v9(103.72,17.09) ; v9(102.83,38.04) 102.91,38.04 103.47,38.6 103.8,38.6 v9(103.91,38.72) 103.92,38.73 R1707.1
  L2 w0.061: v9(103.72,17.09) 103.91,17.28 104.69,17.28 105.59,18.18 105.59,18.35 105.78,18.54 106.21,18.54 v9(106.83,19.15) ; v9(103.91,38.72) 103.9,38.72 103.9,38.73 103.92,38.73 104.49,38.16 104.49,34.78 104.04,34.33 104.04,33.02 103.7,32.68 103.7,32.56 102.49,31.35 102.49,30.95 101.27,29.73 101.27,28.97 100.58,28.29 100.58,25.71 101.15,25.14 101.15,24.35 v9(101.13,24.33) ; v9(102.83,38.04) 102.45,37.66 102.36,37.66 102.17,37.47 102.17,37.23 101.58,36.63 101.22,36.63 101.18,36.67 99.57,36.67 99.44,36.8 98.56,36.8 97.9,37.46 97.9,37.69 97.82,37.77 97.76,37.77 97.75,37.79 v9(96.05,37.79)
I2C_SEC_NFC_SCL: length 111.8
  L5 w0.06: v8(72.95,158.68) 72.95,158.65 73.52,158.08 73.52,153.36
  L5 w0.076: 73.52,153.36 73.52,153.07 74.06,152.53 74.06,152.52 74.6,151.98 74.6,151.62 v5(74.31,151.33) 74.2,151.33 73.63,150.76 73.63,149.23 73.33,148.93 73.33,147.56 79.62,141.27 82.47,141.27 83.67,140.07 83.67,139.5 84.61,138.56 84.61,138.56 84.78,138.39 84.78,138.39 87.06,136.11 87.06,135.41 86.99,135.35 86.99,135 87.3,134.69 87.31,134.69 v4(87.33,134.67)
  L7 w0.061: v5(91.05,78.95) 91.05,82.36 90.69,82.72 90.69,93.77 89.24,95.22 89.14,95.32 89.03,95.43 89.03,98.43 89.08,98.49 89.08,107.52 89.65,108.09 89.65,109.04 89.65,109.11 89.65,109.23 89.65,109.32 89.65,109.76 89.65,110.07 89.65,110.07 89.65,121.02 89.55,121.12 88.83,121.84 88.83,121.84 88.72,121.94 88.62,122.05 87.13,123.53 87.13,123.82 87.13,129.1 87.31,129.28 87.31,132.02 87.18,132.16 87.18,134.52 v4(87.33,134.67) ; v5(59.85,145.66) 60.11,145.4 60.97,145.4 62.82,147.26 65.52,147.26 65.57,147.21 71.08,147.21 73.54,149.67 73.54,150.67 74.21,151.33 v5(74.31,151.33)
  BOTTOM w0.114: v1(58.74,144.27) 58.86,144.14 ; 58.86,144.14 59.85,145.13 v5(59.85,145.66) ; 58.86,144.14 58.33,143.61 XDP1.35
I2C_SEC_NFC_SDA: length 110.2
  L5 w0.06: v8(72.95,157.55) 73.26,157.24 73.26,152.98 74.03,152.22
  L5 w0.076: v4(87.46,134.31) 87.28,134.31 86.8,134.79 86.8,136.1 84.7,138.2 84.7,138.2 84.42,138.48 84.42,138.49 83.48,139.43 83.48,139.89 82.29,141.08 79.54,141.08 73.14,147.48 73.14,149.01 73.44,149.3 73.44,150.97 v5(74.31,151.84) 74.31,151.94 74.03,152.22
  L7 w0.061: v4(87.46,134.31) 87.49,134.28 87.49,132.27 87.48,132.27 87.48,132.1 87.49,132.09 87.49,129.21 87.31,129.03 87.31,123.61 88.69,122.22 88.8,122.12 88.9,122.02 89.52,121.4 89.72,121.2 89.82,121.09 89.82,110.14 89.82,109.88 89.83,109.88 89.83,109.32 89.82,109.23 89.82,109.11 89.82,109.07 89.82,108.42 89.82,108.42 89.82,108.02 89.26,107.45 89.26,98.41 89.21,98.36 89.21,95.5 89.31,95.4 89.31,95.4 90.87,93.84 90.87,82.8 91.55,82.11 v5(91.55,78.95) ; v5(60.41,145.69) 61.01,145.69 62.55,147.23 62.75,147.43 65.59,147.43 65.64,147.39 71.01,147.39 73.37,149.74 73.37,150.9 v5(74.31,151.84)
  BOTTOM w0.114: v1(60.06,144.67) 59.92,144.81 ; 59.92,144.81 58.73,143.63 XDP1.37 ; 59.92,144.81 60.12,145.02 60.12,145.4 v5(60.41,145.69)
I2CM_CLK: length 5.6
  TOP w0.114: v1(99.19,169.39) 99.67,169.39 v10(100.06,169.78)
  L3SGND w0.061: v11(100.06,170.12) v10(100.06,169.78)
  L5 w0.076: v11(100.06,170.12) 100.06,170.35 99.58,170.84 99.58,172.68 98.63,173.64 v8(98.63,173.73)
I2CM_DATA: length 7.2
  TOP w0.114: PR5001.2 100.44,169.44 v10(100.44,169.24) 100.72,168.96 v1(100.72,168.9)
  L3SGND w0.061: v11(100.06,169.24) v10(100.44,169.24)
  L5 w0.076: v11(100.06,169.24) 99.4,169.9 99.4,172.66 98.42,173.65 98.42,173.87 98.63,174.07 v8(98.63,174.13)
I2S_2_CLK: length 135.5
  L5 w0.076: v8(71.54,158.4) 72,157.94 72,156.59 72.45,156.13 72.45,152.63 72.39,152.57 72.39,152.38 72.34,152.33 72.34,152 71.44,151.1 71.34,151.1 71.3,151.06 70.89,151.06 69.8,149.97 69.53,149.97 66.55,146.98 66.48,146.98 65.26,145.77 63.69,145.77 62.47,146.98 56.83,146.98 56.02,147.8 50.76,147.8 47.18,151.37 47.18,160.89 47.89,161.6 47.89,167.76 46.9,168.75 v4(46.9,168.78) ; v4(80.84,182.09) 80.84,182.09 80.94,182.19 80.94,185.02 85.18,189.26 85.18,189.47 86.33,190.62 87.82,190.62 v4(88.15,190.95)
  L7 w0.061: v4(46.9,168.78) 46.9,168.75 46.6,169.06 46.6,178.53 48.63,180.56 48.63,180.67 49.47,181.51 61.81,181.51 61.81,181.51 62.25,181.51 62.25,181.51 62.54,181.51 62.83,181.51 66.53,181.51 66.63,181.4 66.92,181.4 68.17,180.14 68.96,180.14 70.61,181.8 80.55,181.8 v4(80.84,182.09) ; v5(104.25,193.95) 102.89,192.59 88.9,192.59 88.15,191.84 v4(88.15,190.95)
  BOTTOM w0.114: v1(103.34,193.52) 103.77,193.95 v5(104.25,193.95) R2025.1 104.25,195.08 103.91,195.42 U2001.37
I2S_2_FS: length 130.6
  L5 w0.06: 71.11,157.97 71.11,157.98 71.06,158.03 71.06,158.2 71.17,158.31 71.17,158.63 70.97,158.83 v8(70.97,158.96)
  L5 w0.076: v4(68.59,178.89) 68.24,178.53 66.66,178.53 66.16,179.03 66.12,179.03 64.98,179.03 63.9,180.11 50.28,180.11 48.27,178.1 48.27,161.44 47.56,160.73 47.56,151.53 50.91,148.18 56.17,148.18 56.53,147.82 66.56,147.82 70.97,152.23 70.97,152.24 70.97,155.11 71.07,155.21 71.07,156.26 71.11,156.3 71.11,157.97 ; v4(88.2,190.49) 88.14,190.43 86.41,190.43 85.37,189.39 85.37,189.18 81.14,184.95 81.14,181.94 v4(80.91,181.71)
  L7 w0.061: v4(68.59,178.89) 68.67,178.96 68.67,179.45 70.84,181.62 80.82,181.62 v4(80.91,181.71) ; v4(88.2,190.49) 90.12,192.41 103.48,192.41 v5(105.02,193.95)
  BOTTOM w0.114: U2001.36 105.18,196.5 105.37,196.31 v1(105.37,195.73) 105.37,195.17 R2026.1 v5(105.02,193.95)
I2S_2_RXD: length 132.1
  L5 w0.06: v8(71.26,158.12) 71.26,156.25 71.2,156.2 71.2,155.14 71.11,155.05
  L5 w0.076: v4(69.02,179.32) 68.61,179.32 68.01,178.72 66.74,178.72 66.24,179.22 65.06,179.22 63.98,180.3 50.2,180.3 48.08,178.18 48.08,161.52 47.37,160.81 47.37,151.45 50.84,147.99 56.09,147.99 56.45,147.63 66.64,147.63 71.11,152.1 71.11,155.05 ; v4(81.35,181.52) 81.37,181.54 81.37,184.91 85.24,188.78 86.05,188.78 87.41,190.14 v4(87.49,190.14)
  L7 w0.061: v4(69.02,179.32) 71,181.3 81.12,181.3 v4(81.35,181.52) ; v5(105.78,193.95) 104.07,192.24 90.45,192.24 88.35,190.14 v4(87.49,190.14)
  BOTTOM w0.114: v5(105.78,193.95) R2024.1 106.01,195.04 v1(106.01,196.77) 105.88,196.9 U2001.35
I2S_2_TXD: length 132.1
  L5 w0.06: v8(70.97,158.4) 70.97,158.28 70.94,158.25 70.94,157.97 70.94,157.96
  L5 w0.076: v4(81.77,181.25) 81.77,185.05 85.32,188.59 86.13,188.59 87.23,189.68 v4(87.51,189.68) ; v4(69.4,179.24) 68.5,178.34 66.58,178.34 66.08,178.84 66.04,178.84 64.9,178.84 63.82,179.92 51.31,179.92 48.46,177.07 48.46,161.36 47.75,160.65 47.75,151.61 50.99,148.37 56.25,148.37 56.61,148.01 66.48,148.01 70.78,152.31 70.78,152.68 70.79,152.69 70.79,153.36 70.82,153.4 70.82,155.15 70.94,155.26 70.94,156.32 70.94,156.33 70.94,157.96
  L7 w0.061: v4(87.51,189.68) 88.14,189.68 90.52,192.06 104.78,192.06 v5(106.67,193.95) ; v4(81.77,181.25) 81.65,181.12 71.08,181.12 69.4,179.45 v4(69.4,179.24)
  BOTTOM w0.114: v5(106.67,193.95) R2022.1 v1(106.67,195.73) 106.67,196.77 106.14,197.3 U2001.34
ICLK_ICOMP: length 2.6
  TOP w0.076: v10(78.98,161.54) 79.74,161.54 R715.2 79.82,162.38 v1(79.95,162.5)
  L3SGND w0.076: v11(78.55,161.54) v10(78.98,161.54)
  L6SGND w0.076: v11(78.55,161.54) 78.33,161.76 v5(78.33,161.79)
ICLK_RCOMP: length 2.2
  TOP w0.076: R721.2 v10(78.85,160.98) 78.83,160.98 78.42,161.39 v1(78.42,161.51)
  L3SGND w0.076: v11(78.45,160.98) v10(78.85,160.98)
  L6SGND w0.076: v11(78.45,160.98) 78.45,160.83 78.33,160.71 v5(78.33,160.66)
IPLTSENSEN: length 18.7
  TOP w0.254: PR4903.1 v10(105.9,161.95) v1(104.84,161.95)
  L3SGND w0.254: v11(106.31,161.95) v10(105.9,161.95)
  L5 w0.254: v11(106.31,161.95) 106.27,161.99 105.93,161.99 105.32,162.6 105.32,165.4 104.81,165.91 104.81,169.16 104.95,169.3 104.95,170.87 103.88,171.95 103.61,171.95 102.53,173.02 102.53,173.19 100.79,174.93 v8(100.23,174.93)
IPLTSENSEP: length 19.1
  TOP w0.254: v1(104.86,160.73) 105.17,161.03 v10(105.9,161.03) PR4902.1
  L3SGND w0.254: v11(106.35,161.03) v10(105.9,161.03)
  L5 w0.254: v8(100.23,174.53) 100.65,174.53 102.15,173.03 102.15,172.86 103.45,171.57 103.72,171.57 104.57,170.72 104.57,169.46 104.43,169.32 104.43,165.75 104.94,165.24 104.94,162.44 v11(106.35,161.03)
ISH_GPIO8: length 12.2
  L5 w0.076: v8(79.18,158.12) 79.18,157.99 82.31,154.85 82.31,154.06 83.95,152.43 83.95,151.67 v4(84.01,151.6)
  L7 w0.102: v5(84.85,149.71) 84.01,150.54 84.01,150.85 84.01,150.85 v4(84.01,151.6)
  BOTTOM w0.102: v5(84.85,149.71) 84.54,149.4 83.56,149.4 TP601.1
ISH_I2C0_SCL: length 41.7
  L5 w0.076: v5(64.13,141.58) 64.33,141.38 67.35,141.38 67.79,141.82 72.13,141.82 72.25,141.94 73.48,141.94 v4(73.77,142.23) ; v4(83.32,145.11) 83.45,145.23 83.45,146.2 83.65,146.4 v4(83.65,149.09)
  L7 w0.061: v4(73.77,142.23) 75.27,142.23 77.35,144.32 81.47,144.32 81.67,144.52 82.74,144.52 v4(83.32,145.11) ; v4(83.65,149.09) 83.65,149.22 83.47,149.4 83.47,149.4 83.47,149.41 83.47,149.63 83.2,149.9 83.2,151.48 82.55,152.13 82.55,152.67 82.37,152.84 82.37,153.27 82.13,153.52 82.13,154.87 80.56,156.44 80.56,156.46 80.31,156.7 v8(80.03,156.7)
  BOTTOM w0.114: XDP1.34 57.93,140.38 58.38,140.83 61.21,140.83 v1(61.3,140.74) 63.82,140.74 64.13,141.05 DB2.3
ISH_I2C0_SDA: length 42.6
  L5 w0.076: v4(82.69,145) 82.97,145.28 82.97,146.2 83.25,146.48 v4(83.25,149.12) ; v4(72.38,141.65) 72.25,141.65 72.23,141.63 67.86,141.63 67.28,141.04 64.17,141.04 v5(63.63,141.58)
  L7 w0.06: v8(79.74,156.98) 79.74,156.87 79.82,156.79 79.82,156.61 80.54,155.89
  L7 w0.061: 80.54,155.89 80.59,155.89 81.86,154.62 81.86,153.45 82.11,153.19 82.11,150.74 83.27,149.58 83.27,149.42 83.25,149.4 v4(83.25,149.12) ; v4(82.69,145) 81.37,145 81.22,144.85 80.28,144.85 79.92,144.49 77.28,144.49 75.31,142.52 73.24,142.52 v4(72.38,141.65)
  BOTTOM w0.114: DB2.2 63.46,141.67 63.46,141.99 63.35,142.1 62.41,142.1 v1(62.34,142.03) 61.41,141.1 57.93,141.1 57.53,140.7 XDP1.32
ISH_I2C1_SCL: length 158.5
  TOP w0.114: ECOMP3.4 40.66,182.77 40.85,182.95 v2(42.66,182.95)
  L2 w0.061: v9(39.98,174.09) 39.98,176.86 41.07,177.94 41.53,177.94 42.4,178.82 42.4,179.28 42.43,179.3 42.43,182.72 v2(42.66,182.95)
  L5 w0.076: v4(89.01,149.3) 89.01,149.06 89.23,148.84 89.23,145.42 88.94,145.12 v4(88.94,144.98)
  L7 w0.06: v8(80.88,157.55) 81,157.42 81.06,157.42 81.08,157.4 81.55,157.4 82.11,156.85 82.11,156.57 82.53,156.15 82.53,155.91 82.53,155.63
  L7 w0.061: v2(42.66,182.95) 43.05,182.56 66.58,182.56 67.01,182.56 67.01,182.56 67.68,182.56 68.79,183.66 72.25,183.66 74.35,185.77 78.88,185.77 79.37,185.28 80.34,185.28 81.05,184.57 81.07,184.57 v5(81.72,183.92) ; v5(43.67,164.82) 43.42,164.56 43.42,161.6 45.22,159.8 45.22,154.33 44.29,153.39 44.29,151.27 44.29,151.27 44.29,150.69 52.4,142.58 52.69,142.58 58.2,142.58 58.95,143.33 64.12,143.33 64.58,142.87 64.68,142.77 65.11,142.77 65.59,142.77 65.7,142.88 66.19,142.88 67.65,144.34 68.62,144.34 68.68,144.39 75.06,144.39 77.11,146.45 78.06,146.45 78.29,146.68 80.6,146.68 81.03,146.25 84.36,146.25 84.82,145.8 87.34,145.8 87.47,145.67 88.06,145.67 88.22,145.52 88.52,145.52 88.69,145.35 88.69,145.23 v4(88.94,144.98) ; v4(89.01,149.3) 88.93,149.38 88.93,149.55 88.76,149.72 88.36,149.72 87.36,150.72 v5(84.82,150.72) 84.51,151.03 84.51,151.38 84.49,151.4 84.49,152.39 84.06,152.82 83.47,152.82 82.98,153.32 82.98,153.52 82.76,153.74 82.76,155.09 82.53,155.32 82.53,155.63
  BOTTOM w0.114: v5(43.67,164.82) 43.67,164.97 43.55,165.09 v1(43.55,167.56) 43.55,182.06 v2(42.66,182.95)
ISH_I2C1_SCL_L: length 1.4
  BOTTOM w0.114: U4101.14 82.52,184.96 82.34,184.79 81.91,184.79 81.72,184.6 R4109.1
ISH_I2C1_SDA: length 162.7
  TOP w0.114: v2(42.66,183.59) 42,183.59 v1(41.92,183.66) 41.62,183.97 38.59,183.97 38.46,183.83 ECOMP3.6
  L2 w0.061: v2(42.66,183.59) 42.23,183.15 42.23,178.89 41.46,178.12 41,178.12 39.74,176.86 39.74,174.34 v9(39.48,174.09)
  L5 w0.076: v4(88.64,149.43) 88.64,149.16 88.86,148.94 88.86,145.61 v4(88.94,145.54)
  L7 w0.06: v8(79.46,157.83) 79.74,157.83 79.94,158.03 80.11,158.03 80.84,157.3 81.01,157.3 81.09,157.22 81.56,157.22 81.99,156.8 81.99,156.29 82.41,155.87 82.41,155.27 82.64,155.04 82.64,153.69 82.86,153.47 82.86,153.19 83.4,152.65 83.98,152.65 84.31,152.32 v5(84.31,150.72)
  L7 w0.061: v4(88.94,145.54) 88.5,145.97 86.1,145.97 85.64,146.42 81.12,146.42 80.58,146.96 78.32,146.96 77.99,146.62 77.03,146.62 74.98,144.57 68.6,144.57 68.54,144.51 67.58,144.51 66.12,143.05 65.63,143.05 65.52,142.94 65.33,142.94 64.75,142.94 63.79,143.91 59.27,143.91 58.12,142.76 52.47,142.76 44.47,150.76 44.47,151.2 44.47,153.32 45.4,154.25 45.4,159.87 43.6,161.67 43.6,164.33 43.96,164.7 43.96,165.18 v5(43.98,165.2) ; v2(42.66,183.59) 43.51,182.73 66.5,182.73 67.61,182.73 68.72,183.84 72.17,183.84 74.28,185.95 80.05,185.95 80.67,185.33 80.68,185.31 80.69,185.3 80.8,185.2 80.92,185.2 v5(81.01,185.11) ; v5(84.31,150.72) 84.42,150.72 84.75,150.39 87.03,150.39 87.98,149.43 v4(88.64,149.43)
  BOTTOM w0.114: R4110.2 81.01,183.92 80.88,184.04 80.88,184.98 v5(81.01,185.11) ; v2(42.66,183.59) 43.91,182.34 43.91,165.27 v5(43.98,165.2)
ISH_I2C1_SDA_L: length 1.3
  BOTTOM w0.114: U4101.15 81.84,185.25 81.22,184.63 R4110.1
ISOCSENSEN: length 21.7
  TOP w0.254: PR4905.1 v10(106.08,166.7) 106.08,167.46 v1(105.83,167.71)
  L3SGND w0.254: v10(106.08,166.7) v11(106.08,166.26)
  L5 w0.254: v11(106.08,166.26) 106.29,166.47 106.29,169.2 105.6,169.89 105.6,176.66 105.42,176.83 105.42,179.27 105.4,179.29 v3(105.4,179.32)
  L6SGND w0.06: v8(101.03,176.13) 101.03,176.24 101.88,177.09 102.53,177.09 103.35,177.91 103.99,177.91 v3(105.4,179.32)
ISOCSENSEP: length 22.4
  TOP w0.254: PR4904.1 v10(107,166.7) 107,167.56 v1(107.2,167.76)
  L3SGND w0.254: v10(107,166.7) v11(107,166.26)
  L5 w0.254: v11(107,166.26) 106.67,166.59 106.67,169.36 105.98,170.05 105.98,176.81 105.8,176.99 v3(105.8,179.27)
  L6SGND w0.06: v3(105.8,179.27) 104.28,177.75 103.42,177.75 102.6,176.93 101.94,176.93 101.23,176.21 101.23,175.93 v8(101.03,175.73)
JACK_DET#: length 19.6
  TOP w0.114: v2(88.66,195.6) v1(88.66,194.89)
  L2 w0.061: v10(99.71,203.4) 96.05,199.74 95.51,199.74 90.96,195.19 89.07,195.19 v2(88.66,195.6)
  L3SGND w0.127: v10(99.71,203.4) v11(99.71,203.75)
  L5 w0.076: v5(100.06,203.75) v11(99.71,203.75)
  BOTTOM w0.114: v2(88.66,195.6) 88.56,195.6 88.43,195.47 R2203.1 88.15,195.07 C2201.1 ; v5(100.06,203.75) 100.06,203.1 100.37,202.79 100.37,202.6 100.71,202.26 U2001.16
JACK_DET#_R: length 16.9
  L7 w0.061: v5(89.19,195.3) 89.06,195.17 88.02,195.17 87.72,195.47 v5(87.59,195.47) 86.9,195.47 85.46,196.92 82.76,196.92 81.27,198.42 81.27,203.65 AUDIO1.6
  BOTTOM w0.114: D2204.2 87.59,195.02 v5(87.59,195.47)
LCD_BIST: length 71.6
  TOP w0.114: v9(101.56,41.24) 101.66,41.24 102.2,41.78 105.21,41.78 v9(105.45,41.55) 106.14,40.86 106.14,39.37 105.68,38.9 v1(105.68,38.25) 105.07,38.25 104.1,37.28 v9(103.44,37.28) ; v9(97.67,36.02) 97.67,35.46 U1704.N8
  L2 w0.061: v9(95.49,61.93) 94.16,61.93 92.98,60.75 92.98,57.5 91.56,56.08 91.56,53.03 91.12,52.6 90.64,52.6 90.05,52.01 90.05,50.29 90.57,49.78 90.57,49.33 90.44,49.2 90.44,47.05 v9(90.27,46.88) 90.27,46.87 87.95,44.55 87.95,42.54 88.14,42.35 88.38,42.35 88.5,42.23 90.13,40.61 90.13,39.94 91.02,39.04 91.18,39.04 91.24,38.98 92.52,38.98 92.99,38.5 94.4,38.5 94.5,38.6 97.52,38.6 97.53,38.58 97.95,38.58 98.06,38.48 98.11,38.48 98.19,38.39 98.43,38.39 98.59,38.56 98.59,38.8 98.43,38.96 98.19,38.96 98.16,38.93 97.68,38.93 97.51,39.1 97.51,39.91 98.85,41.24 v9(101.56,41.24) ; v9(97.67,36.02) 98.07,36.02 98.22,36.16 101.96,36.16 102.25,36.45 102.25,36.5 102.78,37.03 103.19,37.03 v9(103.44,37.28) ; v9(108.06,50.22) 108.06,48.43 105.6,45.97 105.6,41.7 v9(105.45,41.55)
LCD_BIST#: length 24.6
  L2 w0.061: v10(91.43,36.36) 91.52,36.36 92.14,35.74 92.14,35.51 92.45,35.2 92.45,34.46 92.44,34.45 92.44,34.18 92.67,33.95 93.51,33.95 94.25,34.69 96.28,34.69 96.46,34.52 97.65,34.52 98.38,35.25 v9(98.94,35.25)
  L3SGND w0.127: v11(91.27,36.8) 91.27,36.53 91.36,36.44 91.36,36.43 v10(91.43,36.36)
  L5 w0.076: v5(92.62,49.25) 92.65,49.22 92.65,41.45 92.62,41.43 92.62,41.11 92.65,41.09 92.65,40.25 90.26,37.87 90.26,37.28 90.73,36.8 v11(91.27,36.8)
LCDBL_LED_A:
  vias: v2(93.36,39.77) v9(99.38,47.7) v9(99.38,47.29) v9(99.83,47.67) v9(99.83,47.29) v9(100.31,47.67) v9(100.29,47.29) v13(91.17,39.62)
LCDBL_LED_A_R: length 2.6
  TOP w0.254: C4406.1 96.91,48.31 v1(96.58,47.98)
  TOP w0.508: C4406.1 97.6,48.43 C4403.2
LCDBL_LED_C1: length 25.9
  TOP w0.254: v9(99.49,54.55) 99.49,54.9 99.63,55.04 v1(99.63,55.65)
  L2 w0.254: v10(92.42,41.12) 92.42,41.33 93.07,41.98 93.08,41.98 95.24,44.14 95.24,45.36 97.14,47.26 97.14,52.95 98.46,54.27 99.21,54.27 v9(99.49,54.55) 99.49,54.44 99.7,54.23 99.7,52.19 99.01,51.49 98.65,51.49 98.43,51.71 98.43,52.03 98.77,52.37 v9(98.81,52.37)
  L3SGND w0.254: v10(92.42,41.12) 92.37,41.07 v11(92.06,41.07)
  L6SGND w0.254: v5(91.65,40.53) 92.06,40.94 v11(92.06,41.07)
  BOTTOM w0.254: LCD1.39 91.64,40.55 v5(91.65,40.53)
LCDBL_LED_C2: length 19.1
  TOP w0.254: v9(98.81,53.87) v1(97.8,53.87)
  L2 w0.254: v9(98.81,51.87) 98.85,51.87 99.22,52.25 99.22,53.5 98.85,53.87 v9(98.81,53.87) 98.73,53.79 98.52,53.79 97.52,52.8 97.52,47.11 95.62,45.2 95.62,43.97 93.24,41.6 v10(93.23,41.6)
  L3SGND w0.254: v10(93.23,41.6) 93.23,41.53 v11(93.01,41.3)
  L6SGND w0.254: v5(92.62,40.85) 93,41.23 93,41.3 v11(93.01,41.3)
LCDBL_LED_C3: length 21.8
  TOP w0.254: U4401.18 98.32,51.37 98.3,51.35 v9(97.9,51.35) 97.12,51.35 96.56,51.91 v1(96.56,52.12)
  L2 w0.254: v9(98.81,53.37) 98.64,53.37 97.9,52.64 v9(97.9,51.35) 97.9,46.91 96,45 96,43.76 93.36,41.12 93.36,40.71 92.9,40.25 90.71,40.25 90.49,40.47 90.49,40.5 v10(90.41,40.58)
  L3SGND w0.254: v10(90.41,40.58) v11(90.41,40.94)
  L6SGND w0.254: v11(90.41,40.94) 90.21,41.14 v5(90.02,41.14)
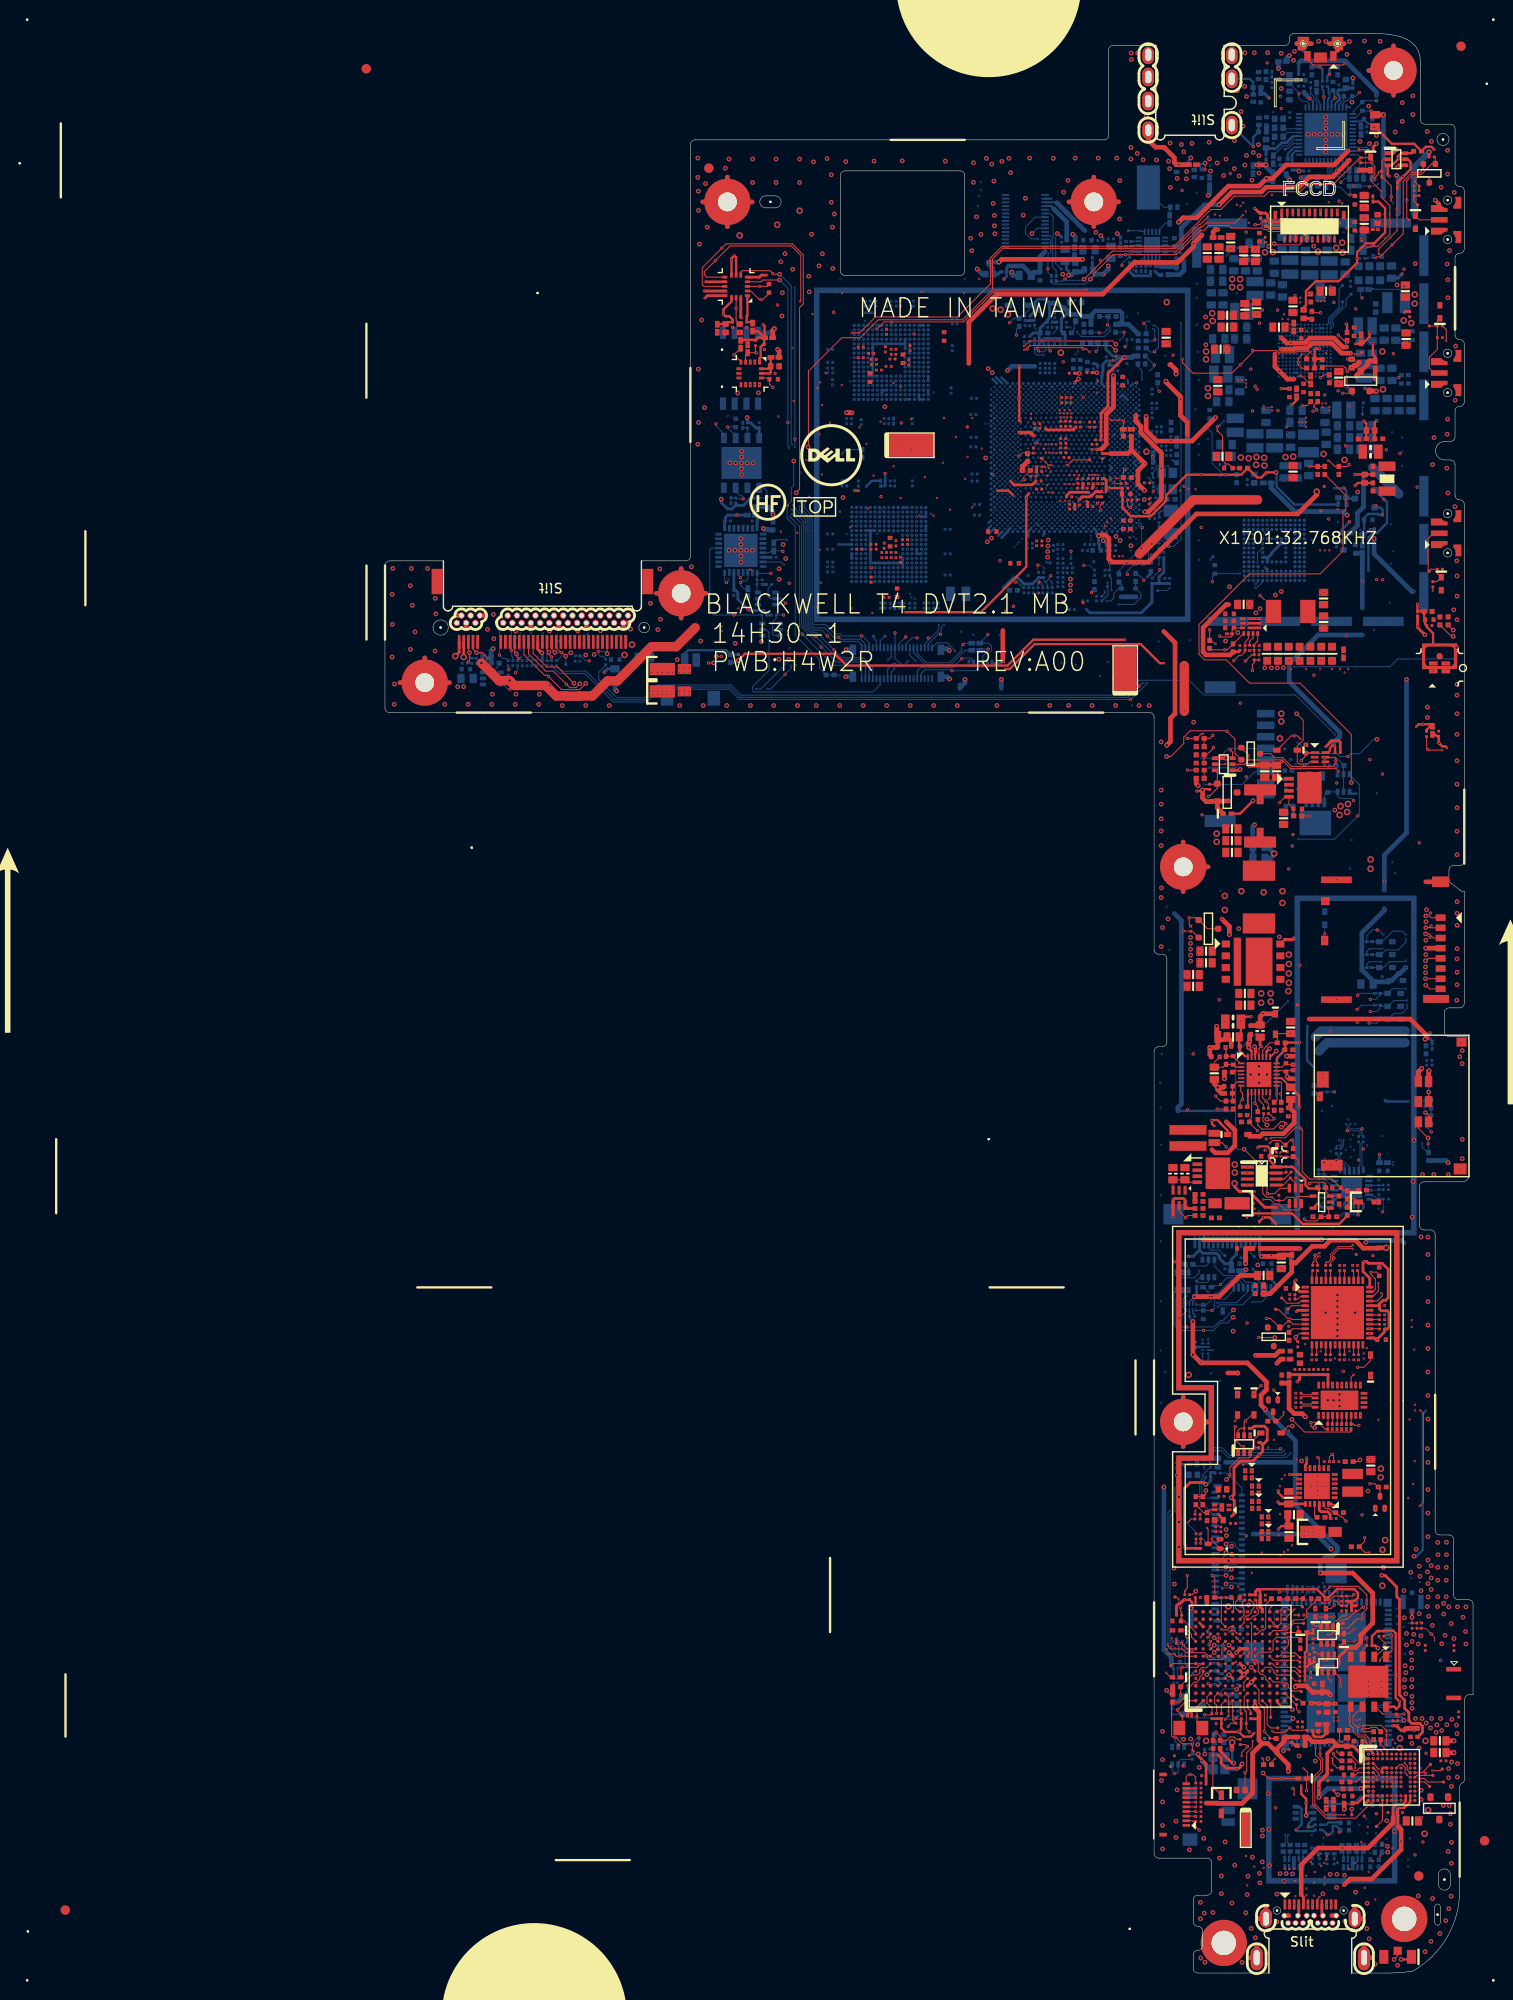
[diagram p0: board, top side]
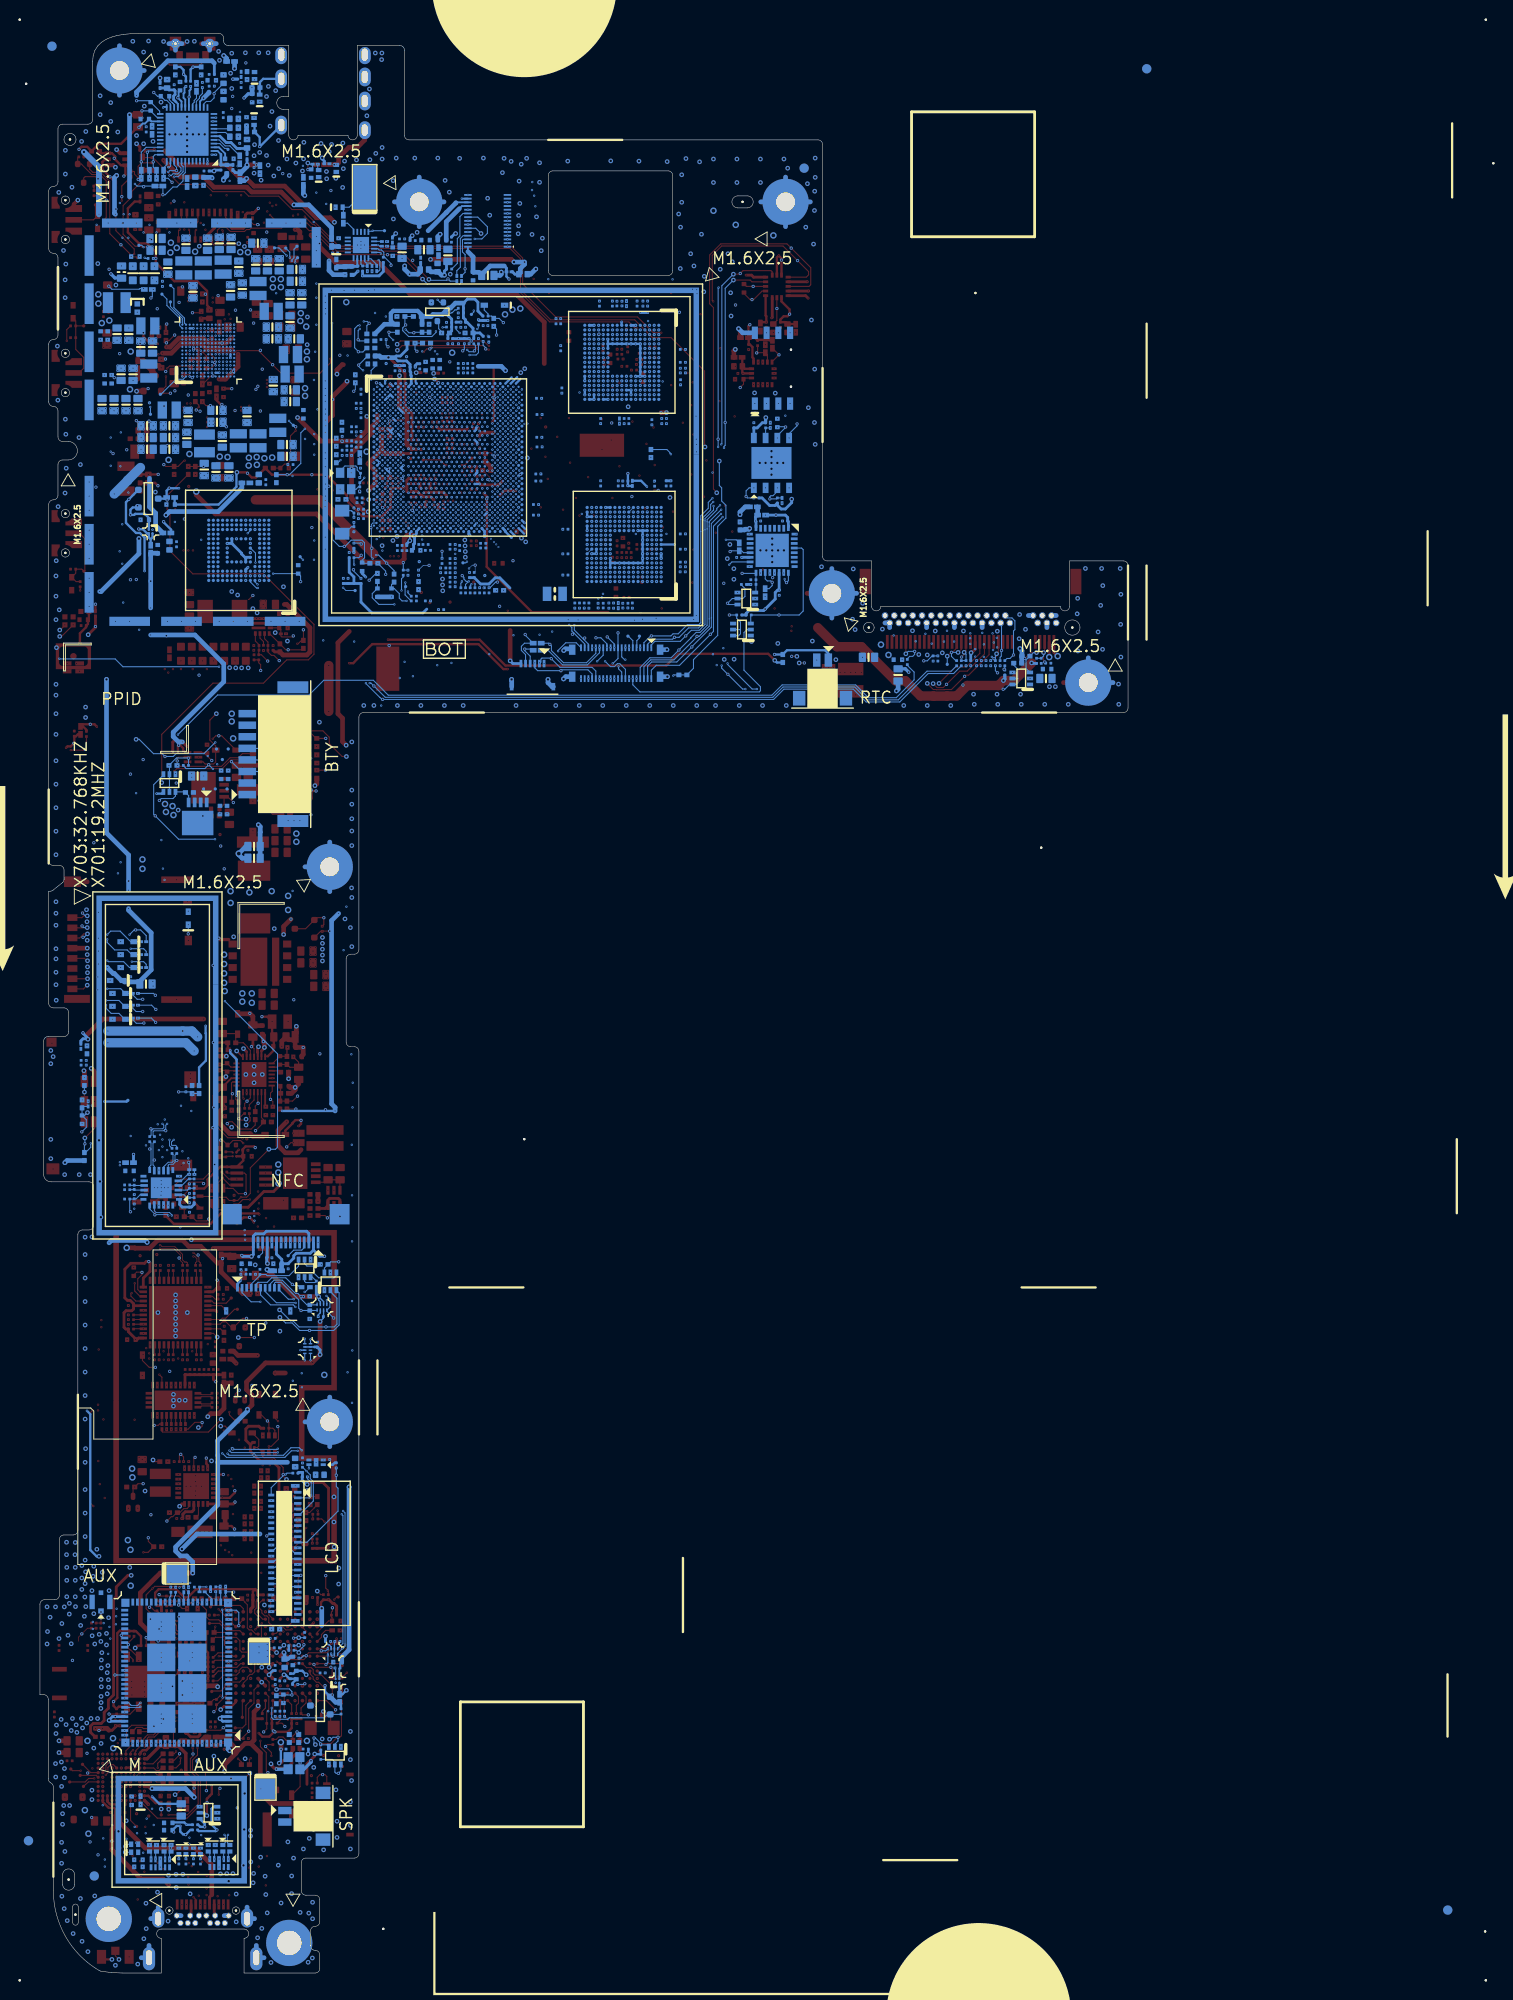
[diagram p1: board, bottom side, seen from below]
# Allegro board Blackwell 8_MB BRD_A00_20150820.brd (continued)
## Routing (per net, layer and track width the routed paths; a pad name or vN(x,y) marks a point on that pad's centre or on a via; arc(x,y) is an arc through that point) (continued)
LCM_HSYNC: length 25.7
  L7 w0.061: v5(93.79,72.54) 93.79,72.31 92.09,70.61 92.09,57.02 92.21,56.9 92.21,53.57 93.08,52.7 93.08,51.51 v5(92.62,51.05)
  BOTTOM w0.114: v5(93.79,72.54) 94.79,72.54 95.77,73.52 TP1.2
LCM_ID1: length 27.8
  TOP w0.114: U1704.G10 92.07,36.72 91.79,37 91.49,37 91.4,36.9 v9(91.3,36.9)
  L2 w0.061: v9(91.3,36.9) 91.3,37 90.88,37.42 90.7,37.42 90.03,38.09 90.03,38.27 88.25,40.05 88.25,40.06 87.88,40.43 87.51,40.43 87.28,40.66 87.28,40.68 87.01,40.95 87.01,41.63 86.53,42.11 86.53,44.89 87.08,45.43 87.16,45.52 87.16,48.15 87.42,48.41 87.42,49.16 87.11,49.47 87.11,50.62 87.11,50.62 87.11,50.77 87.59,51.24 87.59,52.67 88.67,53.75 88.8,53.75 89.34,54.3 v10(89.52,54.3)
  L3SGND w0.127: v11(89.39,53.82) 89.39,54.17 v10(89.52,54.3)
  L6SGND w0.127: v11(89.39,53.82) 88.91,53.82 v5(88.71,53.61)
  BOTTOM w0.114: LCD1.3 88.46,51.35 88.3,51.51 88.3,53 88.71,53.41 v5(88.71,53.61)
LCM_ID2: length 28.6
  TOP w0.114: v9(91.97,36.31) 91.97,36.23 U1704.G9
  L2 w0.061: v9(91.97,36.31) 91.97,36.7 91.07,37.6 90.78,37.6 90.21,38.17 90.21,38.34 89.33,39.22 89.33,39.5 89.25,39.58 89.25,40.24 88.52,40.98 87.93,40.98 87.79,40.84 87.49,40.84 87.23,41.1 87.23,41.44 87.25,41.46 87.25,42 86.71,42.54 86.71,44.82 87.25,45.36 87.34,45.44 87.34,48.08 87.59,48.33 87.59,49.37 87.29,49.68 87.29,50.69 88.17,51.58 88.17,52.82 88.58,53.23 89.5,53.23 v10(90.44,54.17)
  L3SGND w0.127: v10(90.44,54.17) v11(90.79,54.17)
  L6SGND w0.127: v5(91.07,53.87) 91.03,53.91 91.03,53.94 v11(90.79,54.17)
  BOTTOM w0.114: R423.2 90.92,54.02 v5(91.07,53.87) 91.2,53.87 92.62,52.45 LCD1.2
LCM_ID3: length 28.9
  TOP w0.114: v9(90.41,37.16) 90.49,37.07 91.03,37.07 91.39,37.43 U1704.F11
  L2 w0.061: v9(90.41,37.16) 90.41,37.27 90.33,37.36 90.33,37.55 89.86,38.02 89.86,38.2 88.08,39.98 88.08,39.99 87.81,40.26 87.8,40.26 87.44,40.26 87.11,40.59 87.11,40.6 86.83,40.88 86.83,41.45 86.36,41.92 86.36,44.96 86.9,45.5 86.99,45.59 86.99,47.93 86.99,48.22 87.24,48.48 87.24,48.86 86.94,49.17 86.94,49.53 86.94,50.55 86.94,50.84 87.39,51.29 87.39,52.98 88.71,54.3 v10(88.76,54.3)
  L3SGND w0.127: v10(88.76,54.3) 88.76,54.43 88.78,54.45 v11(88.78,54.66)
  L6SGND w0.127: v5(88.81,54.25) 88.81,54.63 v11(88.78,54.66)
  BOTTOM w0.114: LCD1.9 89.53,49.55 88.07,51.01 88.07,53.09 88.4,53.42 88.4,53.84 v5(88.81,54.25) 89.22,54.66 R421.2
LCM_RST#: length 192.3
  TOP w0.114: U3402.2 v10(92.87,56.92) 92.61,56.92 91.84,57.69 91.84,58.98 v1(91.91,59.05)
  L3SGND w0.127: v10(92.87,56.92) v11(93.59,56.92)
  L5 w0.076: v4(109.64,141.09) 109.64,141.35 110.03,141.74 110.03,142.77 110.1,142.83 110.1,150.83 108.09,152.84 108.09,170.61 108.41,170.92 108.41,171.36 107.29,172.47 107.29,186.74 106.23,187.79 106.17,187.79 106.04,187.92 98.16,187.92 97.94,187.7 97.19,187.7 96.4,187.7 96.25,187.7 96.09,187.7 95.93,187.7 95.5,187.7 95.5,187.7 92.9,185.1 92,185.1 89.66,182.75 89.66,181.99 87.31,179.65 87.31,179.52 86.97,179.17 86.97,179.07 85.68,177.78 85.43,177.78 85.13,177.48 85.02,177.48 v4(84.24,176.7) ; v4(99.27,141.24) 99.15,141.12 99.15,141 99.13,140.98 99.13,140.74 99.15,140.73 99.15,136.83 99.34,136.64 99.34,136.43 99.35,136.42 99.35,136.29 99.35,136.29 99.35,136.13 99.35,136.13 99.35,135.03 99.88,134.5 99.88,134.41 101.01,133.28 101.01,128.49 100.7,128.17 100.7,111.83 101.08,111.45 101.08,110.34 101.08,110.34 101.08,95.27 100.51,94.7 100.51,91.89 100.51,90.95 96.74,87.19 96.74,75.26 96.75,75.26 96.75,74.94 96.74,74.94 96.74,74.54 93.89,71.69 93.89,61.53 93.8,61.44 93.8,60.81 93.8,60.47 93.93,60.34 93.93,57.26 v11(93.59,56.92)
  L7 w0.06: v8(75.5,169.15) 75.87,169.52 76.15,169.52 76.83,170.2 76.83,170.76 77.4,171.33 77.4,172.4
  L7 w0.061: 77.4,172.4 77.96,172.97 77.96,173.26 80.61,175.9 83.51,175.9 83.93,176.32 83.93,176.4 v4(84.24,176.7) ; v4(99.27,141.24) 99.37,141.15 99.54,141.15 99.6,141.09 v4(109.64,141.09)
LCM_VDD: length 37.3
  TOP w0.305: R3401.1 94.63,57.35 94.88,57.09 ; v10(102.27,49.12) 102.17,49.12 102.17,49.59 101.91,49.85 101.19,49.85 100.99,50.05 U4401.22 ; 94.88,57.09 95.36,57.58 95.36,58.8 95.07,59.09 93.95,59.09 93.74,58.87 R3402.1 ; 94.88,57.09 94.88,56.38 v1(94.47,55.98) 93.83,55.33 92.5,55.33 91.78,54.61 91.78,51.68 v2(91.48,51.38) 91.81,51.05 91.81,49.65 91.5,49.35 ; 90.28,49.27 90.28,49.39 90.1,49.58 v9(90.08,49.58)
  L2 w0.305: v9(90.08,49.58) 89.04,50.62 v9(88.4,50.62)
  L3SGND w0.305: v10(102.27,49.12) v11(102.27,48.66)
  L5 w0.305: v2(102.27,45.82) 102.27,45.95 102.26,45.96 102.26,48.56 102.27,48.57 v11(102.27,48.66)
  L7 w0.508: v2(91.48,51.38) 92.09,50.77 92.09,49.07 92.41,48.74 92.54,48.74 v5(93.84,47.44)
  BOTTOM w0.508: v2(102.27,45.82) 100.65,47.44 v5(93.84,47.44)
  vias: v2(90.92,47.92) v2(90.97,47.26)
LCM_VDD_EN: length 4.7
  TOP w0.114: R3408.2 R3407.2 88.48,51.48 88.73,51.73 v2(88.73,52.14)
  L7 w0.061: v5(88.54,54.53) 88.3,54.29 88.3,52.57 v2(88.73,52.14)
  BOTTOM w0.114: U3403.4 v5(88.54,54.53)
LCM_VDD_V1P8A: length 0.8
  BOTTOM w0.254: R3404.1 85.76,55.14 85.97,54.94 C3410.1
LCM_XRES: length 25.9
  TOP w0.114: 94.12,56.79 U3402.3 93.52,55.81 93.38,55.67 92.36,55.67 91.32,54.63 v1(91.32,53.87) 91.32,53.69 v2(90.97,53.33) ; 94.12,56.79 93.97,56.94 93.97,57.66 D3405.K ; 94.12,56.79 R3401.2
  L2 w0.061: v9(92.09,62.51) 92.09,62.04 92.59,61.54 92.59,57.64 91.07,56.12 91.07,53.84 90.97,53.74 v2(90.97,53.33)
  L7 w0.061: v2(90.97,53.33) 90.97,53.11 91.37,52.7 91.37,52.21 90.92,51.76 90.92,51.22 91.37,50.77 91.37,47.4 92.52,46.25 v5(92.62,46.25)
LCM_XRES1: length 20.8
  TOP w0.114: v9(91.88,59.63) 92.16,59.91 D3403.A
  L2 w0.061: v10(86.65,54.6) 86.75,54.71 88.86,54.71 91.88,57.73 v9(91.88,59.63)
  L3SGND w0.127: v10(86.65,54.6) v11(86.27,54.6)
  L6SGND w0.127: v5(85.58,54.58) 86.24,54.58 v11(86.27,54.6)
  BOTTOM w0.114: v5(85.58,54.58) v1(85.58,53.79) 85.58,52.57 85.4,52.39 85.4,49.91 86.16,49.15 86.16,49.14 88.76,46.55 LCD1.19
LCM_XRES_R: length 4.1
  TOP w0.114: D3404.A 93.68,60.31 v1(93.03,59.66) 92.87,59.51 R3402.2 ; U3402.5 R3402.2 ; R3402.2 92.44,58.87 92.22,58.65 U3402.6
LPC_AD0: length 61.4
  L5 w0.076: v5(53.93,143.22) 53.93,144.47 53.55,144.85 v4(53.55,145.82) 51.51,145.82 51.02,145.32 47.33,145.32 43.81,148.84 37.45,148.84 36.97,149.32 36.97,150.49 v5(37.12,150.64)
  L7 w0.061: v4(53.55,145.82) 53.55,145.87 54.01,146.32 54.42,146.32 54.48,146.26 54.48,145.98 54.54,145.92 54.66,145.92 54.72,145.98 54.72,146.26 54.78,146.32 54.9,146.32 54.97,146.26 54.97,145.98 55.03,145.92 55.15,145.92 55.21,145.98 55.21,146.26 55.27,146.32 55.39,146.32 55.45,146.26 55.45,145.98 55.51,145.92 55.64,145.92 55.7,145.98 55.7,146.26 55.76,146.32 58.55,146.32 58.7,146.17 58.7,146.17 59.89,144.98 61.74,144.98 62.14,145.39 62.96,145.39 64.3,146.73 65.3,146.73 65.38,146.65 65.75,146.65 67.01,145.39 68.18,145.39 69.34,146.55 74.78,146.55 77,148.77 77,153.58 75.85,154.72 75.85,155.44 76.31,155.89 v8(76.31,156.38)
  BOTTOM w0.114: U5702.24 36.72,150.46 v1(36.92,150.26) 37.12,150.46 v5(37.12,150.64)
LPC_AD1: length 60.2
  L5 w0.076: v5(54.33,143.22) 54.33,144.61 53.94,145 v4(53.94,145.82) 53.94,145.98 53.78,146.13 51.56,146.13 50.94,145.51 47.41,145.51 43.89,149.03 37.53,149.03 37.27,149.29 37.27,150.35 v5(38.22,151.29)
  L7 w0.06: 76.51,156.15 76.51,156.82 v8(76.35,156.98)
  L7 w0.061: 76.51,156.15 76.51,155.92 75.98,155.39 75.98,154.77 77.17,153.57 77.17,148.63 74.91,146.37 69.41,146.37 68.25,145.21 66.94,145.21 65.67,146.47 65.31,146.47 65.23,146.56 64.37,146.56 63.03,145.21 62.5,145.21 v5(62.25,144.97) 62.09,144.81 59.26,144.81 58.53,145.54 58.53,146.09 58.47,146.15 58.35,146.15 58.29,146.09 58.29,145.8 58.23,145.74 54.01,145.74 v4(53.94,145.82)
LPC_AD2: length 62.3
  L2 w0.061: v10(71.51,143.15) 71.59,143.23 71.59,143.36 73.94,145.71 74.94,145.71 77.48,148.25 v10(77.48,149.84)
  L3SGND w0.061: v11(77.19,150.27) 77.19,150.13 v10(77.48,149.84) ; v11(71.21,142.77) 71.21,142.9 71.46,143.15 v10(71.51,143.15)
  L5 w0.076: v5(56.53,141.75) 57.05,141.23 57.89,141.23 58.05,141.39 59.02,141.39 59.02,141.39 59.34,141.39 59.34,141.39 60.01,141.39 60.01,141.39 63.02,141.39 63.34,141.71 63.6,141.97 66.19,141.97 66.56,142.34 68.65,142.34 68.98,142.01 70.45,142.01 v11(71.21,142.77)
  L6SGND w0.089: v11(77.19,150.27) 77.19,150.24 76.92,149.98 v4(76.71,149.98)
  L7 w0.06: 75.79,153.93 75.71,154.01 75.71,154.49 75.71,154.49 75.71,155.46 76.1,155.85 76.1,156.45 76.27,156.62 76.27,156.78 76.07,156.98 v8(76.07,157.27)
  L7 w0.061: v4(76.71,149.98) 76.67,149.98 76.33,150.32 76.33,153.39 75.79,153.93 ; v5(56.53,141.75) 56.3,141.98 54.8,141.98 54.46,141.65 45.74,141.65 v5(44.87,142.51) 41.11,146.27 41.11,149.09 39.72,150.48 v5(39.72,151.29)
  BOTTOM w0.114: v5(56.53,141.75) 55.95,141.18 55.52,141.18 55.2,141.5 54.94,141.5 54.33,140.89 XDP1.16
LPC_AD3: length 62.3
  L2 w0.061: v10(69.62,143.18) 69.62,149.21 v12(70.73,150.31) 71.68,151.26 76.22,151.26 v10(76.31,151.18)
  L3SGND w0.061: v11(69.33,142.84) 69.43,142.95 69.43,142.97 69.62,143.17 v10(69.62,143.18) ; v10(76.31,151.18) 76.35,151.14 v11(76.35,150.69)
  L5 w0.076: v11(69.33,142.84) 69.12,142.84 68.98,142.98 66.29,142.98 65.84,142.54 63.25,142.54 63.17,142.46 62.99,142.27 54.68,142.27 v5(54.34,141.93)
  L6SGND w0.089: v4(76.35,149.85) v11(76.35,150.69)
  L7 w0.06: 75.67,153.88 75.59,153.96 75.59,154.44 75.59,154.44 75.59,155.51 75.98,155.9 75.98,156.5 75.78,156.7 v8(75.78,156.98)
  L7 w0.061: v5(43.12,152.19) 43.47,151.84 43.47,144.37 45.91,141.93 v5(54.34,141.93) ; v4(76.35,149.85) 76.16,150.05 76.16,153.39 75.67,153.88
  BOTTOM w0.114: U5702.15 42.82,152.49 v5(43.12,152.19) ; v5(54.34,141.93) 54.43,141.93 54.73,142.23 XDP1.17
LPC_CLKOUT_0: length 61.5
  L2 w0.061: v10(78.32,150.01) 78.32,148.77 75.03,145.49 74.03,145.49 71.81,143.27 71.81,143.05 71.63,142.86 71.16,142.86 v10(70.88,143.15)
  L3SGND w0.061: v11(70.6,142.82) 70.88,143.1 v10(70.88,143.15) ; v10(78.32,150.01) 78.37,150.06 v11(78.37,150.64)
  L5 w0.06: v11(78.37,150.64) 78.37,152.32 76.06,154.63 76.06,157.82 76.07,157.83 v8(76.07,158.4)
  L5 w0.076: v11(70.6,142.82) 70.01,142.23 69.08,142.23 68.74,142.57 66.46,142.57 66.06,142.16 63.47,142.16 63.17,141.87 62.95,141.64 57.69,141.64 57.51,141.46 57.23,141.46 56.65,142.04 56.23,142.04 v5(55.71,141.52)
  L7 w0.061: v5(55.71,141.52) 54.95,141.52 54.72,141.3 45.19,141.3 44.85,141.64 44.85,141.67 44.56,141.96 44.53,141.96 39.58,146.9 39.58,148.23 39.23,148.58 v5(39.23,148.74)
  BOTTOM w0.114: v5(55.71,141.52) 55.66,141.52 55.13,142.05 XDP1.19 v1(55.13,144.83)
LPC_CLKRUN#: length 63.5
  L5 w0.06: 78.01,150.35 78,150.36 78,152.23 77.92,152.32 77.92,152.56 75.94,154.53 75.94,157.78 75.9,157.82 75.9,157.99 v8(75.78,158.12)
  L5 w0.076: 78.01,150.35 79.11,149.25 v4(79.11,146.2)
  L7 w0.061: v4(79.11,146.2) 79.01,146.1 77.25,146.1 75.51,144.35 75.51,144.35 75.2,144.04 74.87,143.71 70.27,143.71 69.1,142.54 v5(69.05,142.54) 68.87,142.54 68.75,142.66 66.47,142.66 66.34,142.53 66.2,142.53 65.89,142.21 64.4,142.21 64.39,142.22 63.89,142.22 63.89,142.22 63.37,142.22 63.36,142.21 54.46,142.21 54.46,142.21 54.22,142.21 54.22,142.21 45.94,142.21 43.73,144.42 43.73,153.02 43.47,153.28 v5(43.47,154.88)
  BOTTOM w0.114: R5704.2 42.35,154.88 v5(43.47,154.88)
LPC_CLKRUN#_L: length 2.2
  BOTTOM w0.114: U5702.13 41.57,153.49 41.77,153.69 R5704.1 42.94,153.69 v1(43.01,153.61)
LPC_FRAME#: length 67.8
  L2 w0.061: v10(69.53,141.19) 70.85,142.51 73.85,142.51 80.4,149.07 82.28,149.07 v10(82.41,149.19)
  L3SGND w0.061: v10(69.53,141.19) 69.48,141.24 v11(69.07,141.24)
  L3SGND w0.127: v11(82.04,149.33) 82.18,149.19 v10(82.41,149.19)
  L5 w0.06: 76.27,155.11 76.27,158.6 v8(76.35,158.68)
  L5 w0.076: v11(69.07,141.24) 67.75,141.24 67.36,140.85 61.93,140.85 61.58,141.2 60.61,141.2 58.12,141.2 57.97,141.04 55.28,141.04 55.14,141.19 v5(55.07,141.19) ; v11(82.04,149.33) 76.27,155.11
  L7 w0.061: v5(55.07,141.19) 55.07,141.19 55,141.12 44.66,141.12 44.46,141.32 v5(44.46,141.35) 44.46,141.78 39.31,146.93 39.31,147.31 38.72,147.9 v5(38.72,151.29)
  BOTTOM w0.114: v5(55.07,141.19) 55.07,140.93 54.73,140.59 XDP1.18
LPC_RCOMP: length 9.6
  L5 w0.076: v8(75.5,158.96) 75.29,158.76 75.29,157.82 75.52,157.59 75.52,154.2 76.91,152.81 76.91,152.18 76.69,151.96 v5(76.69,151.61)
  BOTTOM w0.076: v5(76.69,151.61) 76.19,152.12 v1(75.55,152.12)
LPDDR3_M0_CA0: length 32.4
  L2 w0.061: v10(61.56,170.6) 61.38,170.42 59.94,170.42 59.27,171.09 56.89,171.09 55.89,172.09 55.88,172.09 55.05,172.93 55.05,173.61 55.14,173.71 55.14,173.87 55.19,173.92 55.19,173.97 v10(55.36,174.14)
  L3SGND w0.127: v11(61.53,171.11) 61.54,171.1 61.54,170.62 v10(61.56,170.6) ; v10(55.36,174.14) 55.5,174.14 v11(55.78,174.41) 55.65,174.54 54.71,174.54 v10(54.59,174.42)
  L5 w0.06: 66.37,169.61 66.46,169.52 66.88,169.52 67.45,168.95 67.66,168.95 67.78,169.07 68.23,169.07 v8(68.43,168.87) ; v8(55.72,177.56) 56,177.84 56.35,177.84 56.54,177.64 56.54,177.27 56.19,176.91 56.19,176 56.14,175.94 56.14,175.65 55.92,175.43 55.49,175.43 55.36,175.31 55.36,174.84 v11(55.78,174.41)
  L5 w0.076: v11(61.53,171.11) 61.64,171.22 61.92,171.22 62.16,171.46 62.46,171.46 62.53,171.53 62.53,172.09 62.62,172.18 62.75,172.18 62.84,172.09 62.84,171.53 62.91,171.46 63.12,171.46 63.2,171.53 63.2,171.69 63.29,171.78 63.41,171.78 63.5,171.69 63.5,171.53 63.58,171.46 63.73,171.46 63.81,171.53 63.81,171.84 63.9,171.93 64.02,171.93 64.11,171.84 64.11,171.53 64.19,171.46 64.53,171.46 66.37,169.61
  L6SGND w0.127: v11(55.78,174.41) 55.63,174.41 55.41,174.64 v4(55.41,174.7)
  L7 w0.061: v8(51.22,176.06) 51.47,175.81 52.34,175.81 52.47,175.68 54.36,175.68 55.32,174.72 55.37,174.72 55.39,174.7 v4(55.41,174.7)
LPDDR3_M0_CA1: length 31.1
  L2 w0.061: v9(54.72,175.46) 54.88,175.46 55.09,175.24 55.31,175.24 55.35,175.29 v10(55.58,175.29) 55.17,174.87 54.47,174.87 54.34,174.75 54.34,174.01 54.11,173.77 54.11,173.35 55.82,171.64 55.83,171.64 56.81,170.66 58.94,170.66 59.7,169.9 62.53,169.9 62.6,169.83 62.6,169.61 62.67,169.54 62.77,169.54 62.84,169.61 62.84,169.83 62.9,169.9 63.23,169.9 63.36,170.02 v10(63.36,170.42)
  L3SGND w0.127: v10(63.36,170.42) 63.36,170.7 v11(63.17,170.89) ; v10(55.58,175.29) 55.58,175.56 v11(55.79,175.77)
  L5 w0.06: v11(63.17,170.89) 63.36,170.89 65.1,169.15 66.75,169.15 67.31,168.58 v8(68.14,168.58) ; v11(55.79,175.77) 56.07,176.05 56.07,176.96 56.42,177.32 56.42,177.59 56.3,177.72 56.05,177.72 55.92,177.59 55.92,177.48 55.81,177.36 55.46,177.36 55.41,177.31 55.41,177.16 55.53,177.03 55.67,177.03 v8(55.72,177.08)
  L6SGND w0.127: v11(55.79,175.77) 55.6,175.58 v4(55.39,175.58)
  L7 w0.061: v8(51.75,176.06) 51.96,176.27 54.7,176.27 v4(55.39,175.58)
LPDDR3_M0_CA2: length 30
  L2 w0.061: v10(61.2,173.32) 60.82,173.71 59.91,173.71 59.85,173.64 59.85,173.52 59.78,173.45 59.68,173.45 59.6,173.52 59.6,173.64 59.54,173.71 59.42,173.71 59.36,173.64 59.36,173.52 59.29,173.45 59.19,173.45 59.12,173.52 59.12,173.64 59.06,173.71 57.26,173.71 56.14,174.83 56.14,175.7 55.81,176.02 v10(55.81,176.22)
  L3SGND w0.127: v10(55.22,175.46) 55.22,176 v11(55.28,176.06) 55.43,176.22 v10(55.81,176.22) ; v10(61.2,173.32) 61.17,173.28 61.17,172.99 v11(61.05,172.87)
  L5 w0.06: v4(55.03,175.55) 55.03,175.81 v11(55.28,176.06) 55.15,176.19 55.15,176.27 55.36,176.47 55.36,176.75 55.49,176.88 55.63,176.88 55.63,176.88 55.8,176.88 55.8,176.88 55.82,176.88 55.94,176.75 55.94,176.15 55.87,176.08 55.73,176.08 55.65,176.15 v8(55.65,176.54)
  L6SGND w0.127: v11(61.05,172.87) 61.05,172.87 61.12,172.95 61.46,172.95 v4(61.56,173.05)
  L7 w0.06: v8(68.71,168.02) 68.71,168.3 67.09,169.92 ; 66.81,170.2 66.81,170.33 66.75,170.39 66.49,170.39 66.42,170.46 66.42,170.56 66.49,170.63 66.75,170.63 66.81,170.69 66.81,170.93 66.93,171.05 66.93,171.21 66.51,171.63
  L7 w0.061: v4(61.56,173.05) 61.43,173.05 61.31,172.92 61.31,172.53 61.43,172.4 61.65,172.4 62.02,172.77 62.02,173.09 62.13,173.2 62.29,173.2 62.39,173.09 62.39,172.69 62.52,172.56 62.74,172.56 62.81,172.63 62.81,172.77 62.88,172.84 62.98,172.84 63.05,172.77 63.05,172.66 63.12,172.59 63.22,172.59 63.3,172.66 63.3,172.76 63.36,172.82 63.92,172.82 64.68,172.07 64.76,171.98 64.85,171.9 64.89,171.86 65.74,171.86 65.97,171.63 66.51,171.63 ; 66.81,170.2 67.09,169.92 ; v8(52.22,176.06) 52.37,176.06 52.62,175.81 54.45,175.81 54.7,175.55 v4(55.03,175.55)
LPDDR3_M0_CA3: length 33.6
  L2 w0.061: v10(55.36,173.78) 55.36,173.75 55.17,173.56 55.17,172.98 55.93,172.21 55.94,172.21 56.59,171.56 56.87,171.56 56.94,171.5 56.94,171.34 57,171.28 57.12,171.28 57.18,171.34 57.18,171.5 57.24,171.56 57.36,171.56 57.42,171.5 57.42,171.34 57.48,171.28 57.61,171.28 57.67,171.34 57.67,171.5 57.73,171.56 57.85,171.56 57.91,171.5 57.91,171.34 57.97,171.28 58.09,171.28 58.15,171.34 58.15,171.5 58.22,171.56 58.34,171.56 58.4,171.5 58.4,171.34 58.46,171.28 58.58,171.28 58.64,171.34 58.64,171.5 58.7,171.56 58.83,171.56 58.9,171.48 58.9,171.34 59,171.24 59.14,171.24 59.24,171.34 59.24,171.46 59.33,171.55 59.45,171.55 59.53,171.46 59.53,171 59.9,170.63 60.44,170.63 v10(60.51,170.71)
  L3SGND w0.127: v10(55.36,173.78) 55.38,173.76 55.71,173.76 55.9,173.57 v11(56,173.57) 56.38,173.57 v10(56.62,173.81) ; v10(60.51,170.71) 60.63,170.59 60.85,170.59 v11(61.55,169.89)
  L5 w0.06: v11(61.55,169.89) 61.3,170.13 61.3,170.31 61.43,170.44 62.19,170.44 62.44,170.69 62.44,170.71 63.01,171.27 64.39,171.27 66.35,169.32 66.88,169.32 67.37,168.83 67.82,168.83 v8(67.86,168.87) ; v8(55.22,177.56) 55.42,177.76 55.76,177.76 55.95,177.96 56.4,177.96 56.66,177.69 56.66,177.22 56.31,176.86 56.31,175.95 56.25,175.9 56.25,175.6 55.81,175.15 55.81,174.89 56.09,174.61 56.09,173.98 56,173.89 v11(56,173.57)
  L6SGND w0.127: v11(56,173.57) 55.94,173.57 55.86,173.65 55.79,173.65 55.46,173.98 v4(55.46,174.03)
  L7 w0.061: v8(51.22,175.56) 51.46,175.33 51.77,175.33 51.81,175.28 51.81,175.28 51.94,175.15 51.94,175.15 51.96,175.13 51.96,175.02 52.01,174.97 52.01,174.97 52.13,174.84 52.13,174.84 52.17,174.81 52.78,174.81 52.84,174.87 52.84,175.12 52.9,175.18 53.03,175.18 53.09,175.12 53.09,174.87 53.15,174.81 54.12,174.81 54.71,174.23 55.27,174.23 v4(55.46,174.03)
LPDDR3_M0_CA4: length 30.3
  L2 w0.061: v10(53.77,174.81) 53.6,174.81 53.35,174.57 53.35,174.39 53.41,174.33 53.79,174.33 53.86,174.26 53.86,174.16 53.79,174.09 53.41,174.09 53.35,174.03 53.35,173.91 53.41,173.85 53.76,173.85 53.83,173.77 53.83,173.67 53.76,173.6 53.41,173.6 53.35,173.54 53.35,173.15 53.71,172.79 53.71,171.92 55.33,170.3 58.86,170.3 59.99,169.18 63.66,169.18 v10(64.56,170.08)
  L3SGND w0.127: v10(54.08,175.2) 54.31,175.2 v11(54.5,175.02) 54.29,174.81 v10(53.77,174.81) ; v11(64.64,170.58) 64.64,170.31 64.56,170.23 v10(64.56,170.08)
  L5 w0.076: v8(55.22,177.06) 55.22,177.26 55.1,177.39 54.92,177.39 54.86,177.33 54.86,177.18 54.79,177.11 54.79,176.97 54.61,176.79 54.47,176.79 54.33,176.65 54.33,175.18 v11(54.5,175.02) 54.5,174.75 v4(54.7,174.54)
  L6SGND w0.127: v4(64.35,170.25) 64.35,170.29 64.64,170.58 v11(64.64,170.58)
  L7 w0.06: v8(67.01,168.58) 66.73,168.58 65.96,169.35
  L7 w0.061: v4(64.35,170.25) 64.94,170.25 65.84,169.35 65.96,169.35 ; v8(51.72,175.56) 51.87,175.56 52.07,175.36 52.14,175.36 52.14,175.36 52.31,175.36 52.31,175.36 53.97,175.36 54.7,174.63 v4(54.7,174.54)
LPDDR3_M0_CA5: length 30.6
  L2 w0.061: v10(55.38,173.43) 55.38,173.28 55.49,173.17 55.49,172.82 55.98,172.33 55.99,172.33 56.64,171.68 59.49,171.68 60.17,171 60.8,171 60.86,170.94 60.86,170.67 60.92,170.61 61.04,170.61 61.1,170.67 61.1,170.76 61.23,170.89 61.41,170.89 61.47,170.95 61.47,171.2 61.54,171.27 61.64,171.27 61.71,171.2 61.71,170.95 61.77,170.89 62.08,170.89 62.34,171.14 63.13,171.14 63.26,171.27 63.26,171.76 63.32,171.82 63.59,171.82 63.66,171.89 63.66,171.99 63.59,172.06 63.32,172.06 63.26,172.12 63.26,172.5 63.15,172.61 62.99,172.61 62.88,172.5 62.88,171.82 v10(62.59,171.53)
  L3SGND w0.127: v11(62.81,170.33) 62.59,170.55 v10(62.59,171.53) ; v11(55.15,173.05) 55.38,173.27 v10(55.38,173.43) 55.33,173.48 55.24,173.48 55.08,173.63 55.06,173.65 54.89,173.65 54.86,173.65 54.83,173.63 v10(54.72,173.63)
  L5 w0.076: v8(53.72,177.06) 53.99,176.79 53.99,176.49 54.03,176.45 54.03,174.66 54.88,173.8 v4(54.88,173.6) ; v8(66.73,168.87) 66.23,168.87 66.16,168.79 66.16,168.57 66.08,168.5 65.93,168.5 65.85,168.57 65.85,168.79 65.78,168.87 65.62,168.87 65.55,168.79 65.55,168.57 65.47,168.5 65.32,168.5 65.24,168.57 65.24,168.79 65.17,168.87 64.88,168.87 63.41,170.33 v11(62.81,170.33)
  L6SGND w0.127: v11(55.15,173.05) 55.15,173.32 v4(54.88,173.6)
  L7 w0.061: v4(54.88,173.6) 54.88,173.66 54.28,174.26 52.93,174.26 52.87,174.32 52.87,174.47 52.81,174.53 52.69,174.53 52.63,174.47 52.63,174.32 52.57,174.26 52.33,174.26 52.31,174.28 51.93,174.28 v8(51.73,174.08)
LPDDR3_M0_CA6: length 31.7
  L2 w0.061: v10(61.99,169.46) 59.93,169.46 58.94,170.45 56.38,170.45 56.32,170.52 56.32,170.94 56.25,171.01 56.15,171.01 56.08,170.94 56.08,170.52 56.02,170.45 55.9,170.45 55.84,170.52 55.84,171.09 55.76,171.17 55.66,171.17 55.59,171.09 55.59,170.52 55.53,170.45 55.36,170.45 54.98,170.83 54.98,170.91 55.39,171.32 55.39,171.42 55.31,171.49 55.21,171.49 54.81,171.09 54.72,171.09 54.64,171.17 54.64,171.26 54.85,171.47 54.85,171.57 54.78,171.64 54.68,171.64 54.47,171.43 54.38,171.43 54.29,171.52 54.29,171.6 54.49,171.8 54.49,171.9 54.42,171.97 54.32,171.97 54.14,171.79 54.04,171.79 53.97,171.86 53.97,171.96 54.31,172.3 v10(54.59,172.3) 54.59,172.44 53.81,173.22 v9(53.66,173.22)
  L3SGND w0.127: v10(61.99,169.46) 62.02,169.49 62.02,169.77 v11(62.15,169.9) ; v10(54.59,172.3) 54.57,172.32 v11(54.57,172.79)
  L5 w0.076: v11(62.15,169.9) 62.36,169.9 62.42,169.96 62.68,169.96 62.69,169.95 63.52,169.95 65.17,168.3 v8(67.86,168.3) ; v11(54.57,172.79) 54.57,173.84 53.89,174.53 53.89,176.39 v8(53.72,176.56)
  L6SGND w0.127: v11(54.57,172.79) v4(54.57,173.37)
  L7 w0.061: v4(54.57,173.37) 54.57,173.79 54.5,173.87 54.5,173.87 54.37,174 54.37,174 54.31,174.06 53.69,174.06 53.63,174 53.63,173.88 53.56,173.81 53.46,173.81 53.39,173.88 53.39,174 53.33,174.06 53.15,174.06 53.09,174 53.09,173.93 53.03,173.87 52.91,173.87 52.85,173.93 52.85,174 52.79,174.06 v8(52.22,174.06)
LPDDR3_M0_CA7: length 30.5
  L2 w0.061: v10(64.92,169.74) 64.19,169 59.93,169 58.84,170.1 54.55,170.1 54,170.65 54,170.73 54.28,171.02 54.28,171.12 54.21,171.19 54.11,171.19 53.82,170.91 53.74,170.91 53.65,170.99 53.65,171.08 53.94,171.37 53.94,171.47 53.87,171.54 53.77,171.54 53.48,171.25 53.39,171.25 53.27,171.38 53.27,171.67 53.21,171.73 52.9,171.73 52.84,171.79 52.84,171.91 52.9,171.97 53.21,171.97 53.27,172.03 53.27,172.15 53.21,172.21 52.9,172.21 52.84,172.28 52.84,172.4 52.9,172.46 53.21,172.46 53.27,172.52 v10(53.27,172.88)
  L3SGND w0.127: v10(53.27,172.88) 53.27,173.28 v11(53.15,173.4) 53.12,173.43 v10(53.12,173.83) ; v11(65.02,170.19) 64.92,170.1 v10(64.92,169.74)
  L5 w0.076: v8(53.22,177.56) 53.22,177.54 52.61,176.94 52.61,173.96 52.8,173.77 52.8,173.75 v11(53.15,173.4) 53.18,173.37 53.61,173.37 v4(53.71,173.47)
  L6SGND w0.127: v4(64.8,169.81) 65.02,170.03 v11(65.02,170.19)
  L7 w0.06: 65.97,168.83 v8(66.13,168.83)
  L7 w0.061: v4(64.8,169.81) 64.87,169.74 65.01,169.74 65.03,169.71 65.27,169.47 65.33,169.47 65.68,169.12 65.68,169.07 65.8,168.95 65.85,168.95 65.97,168.83 ; v8(51.22,173.56) 51.22,173.57 50.99,173.81 50.99,173.96 51.12,174.09 51.37,174.09 51.7,173.76 52.64,173.76 52.77,173.63 52.77,173.46 52.83,173.4 53.1,173.4 53.3,173.6 53.58,173.6 53.71,173.48 v4(53.71,173.47)
LPDDR3_M0_CA8: length 30.4
  L2 w0.061: v10(62.19,170.37) 62.27,170.45 62.54,170.45 62.65,170.34 62.65,170.18 62.54,170.07 59.95,170.07 59.24,170.78 56.86,170.78 55.88,171.76 55.87,171.76 54.37,173.26 54.37,173.63 v10(54.32,173.68)
  L3SGND w0.127: v11(62.03,170.82) 62.06,170.79 62.06,170.5 v10(62.19,170.37) ; v10(54.32,173.68) 54.25,173.68 v11(53.75,174.18) 53.61,174.32 53.14,174.32 v10(53.09,174.37)
  L5 w0.076: v11(53.75,174.18) 53.38,174.18 53.25,174.3 53.25,174.59 53.38,174.71 53.63,174.71 53.75,174.84 53.75,175.39 53.43,175.71 53.43,176.85 v8(53.22,177.06)
  L6SGND w0.127: v11(53.75,174.18) 53.89,174.18 v4(54.28,173.78) ; v11(62.03,170.82) 62.27,170.82 v4(62.66,171.21)
  L7 w0.06: 66.77,169.8 66.77,169.68 67.38,169.07 67.38,168.5 67.78,168.1 67.78,167.65
  L7 w0.061: v4(62.66,171.21) 62.66,171.8 62.78,171.92 62.98,171.92 63.11,171.8 63.11,171.44 63.23,171.32 63.51,171.32 63.57,171.38 63.57,171.53 63.64,171.6 63.74,171.6 63.81,171.53 63.81,171.38 63.87,171.32 64.04,171.32 64.24,171.12 65.04,171.12 65.52,170.63 65.98,170.63 66.77,169.85 66.77,169.8 ; v4(54.28,173.78) 54.2,173.7 54.2,173.49 53.85,173.13 53.57,173.13 53.57,173.13 52.15,173.13 v8(51.72,173.56) ; 67.78,167.65 v8(67.58,167.45)
LPDDR3_M0_CA9: length 30.8
  L2 w0.061: v10(62.59,171.98) 62.16,171.98 61.9,171.72 61.9,171.63 62.13,171.41 62.13,171.32 62.05,171.23 61.96,171.23 61.73,171.46 61.42,171.46 61.14,171.18 60.25,171.18 59.63,171.8 56.69,171.8 56.04,172.45 56.03,172.45 55.61,172.87 55.61,174.19 55.44,174.37 54.98,174.37 54.68,174.07 v10(54.68,174.07)
  L3SGND w0.127: v10(62.59,171.98) 62.49,171.88 v11(62.05,171.88) ; v10(52.82,175.03) 52.92,174.92 53.26,174.92 v11(53.36,175.03) 53.36,174.81 53.63,174.54 53.95,174.54 54.42,174.07 v10(54.68,174.07)
  L5 w0.076: v11(53.36,175.03) 52.84,175.03 52.75,175.12 52.75,175.83 52.83,175.91 53.15,175.91 53.22,175.98 53.22,176.13 53.15,176.21 52.83,176.21 52.75,176.29 52.75,176.73 52.88,176.86 53.1,176.86 53.22,176.73 v8(53.22,176.56)
  L6SGND w0.127: v4(62.31,171.48) 62.26,171.53 62.26,171.67 v11(62.05,171.88) ; v4(53.92,173.76) 53.69,173.76 53.36,174.09 v11(53.36,175.03)
  L7 w0.06: 66.65,169.75 66.65,169.23 67.21,168.67 67.21,168.5 67.09,168.38 67.09,168.22 67.29,168.02 v8(67.29,167.74)
  L7 w0.061: v4(62.31,171.48) 62.31,171.16 62.54,170.93 62.9,170.93 62.97,170.87 62.97,170.72 63.03,170.65 63.15,170.65 63.21,170.72 63.21,170.99 63.4,171.18 63.87,171.18 64.11,170.94 64.91,170.94 65.37,170.48 65.96,170.48 66.65,169.8 66.65,169.75 ; v4(53.92,173.76) 53.93,173.75 53.93,173.56 53.93,173.38 53.8,173.25 53.62,173.25 53.62,173.26 52.5,173.26 v8(52.21,173.55)
LPDDR3_M0_CKE0_A: length 20
  L2 w0.061: v10(52.36,174.14) 52.36,173.23 52.48,173.1 52.48,173.02 52.22,172.76 52.22,172.65 52.29,172.58 52.39,172.58 52.65,172.84 52.74,172.84 52.83,172.76 52.83,172.67 52.55,172.4 52.55,171.71 54.32,169.95 58.66,169.95 59.88,168.73 64.91,168.73 v10(65.34,169.16)
  L3SGND w0.127: v10(65.34,169.16) 65.37,169.19 v11(65.37,169.72) ; v10(52.36,174.14) 52.25,174.25 v11(52.25,174.62)
  L6SGND w0.127: v5(51.72,175.06) 51.81,175.06 v11(52.25,174.62) ; v11(65.37,169.72) 65.37,169.72 v8(65.8,169.72)
LPDDR3_M0_CKE0_B: length 19.2
  L2 w0.061: v10(64.1,170.24) 64.1,171.62 62.58,173.64 60.91,174.83 56.44,177.33 55.86,177.91 55.72,177.91 55.69,177.88 55.39,177.88 55.23,177.72 55.23,177.71 v10(55.21,177.69)
  L3SGND w0.127: v11(64.12,170.72) 64.12,170.27 v10(64.1,170.24) ; v10(55.21,177.69) 55.23,177.71 55.23,177.86 v11(55.44,178.07)
  L6SGND w0.127: v5(54.72,177.06) 54.97,177.31 54.97,177.63 54.99,177.65 54.99,177.66 55.13,177.79 55.14,177.79 55.41,178.07 v11(55.44,178.07) ; v4(63.71,170.96) 63.71,170.92 63.91,170.72 v11(64.12,170.72)
  L7 w0.06: 65.94,170.04 66.2,169.77 66.2,169.67 66.45,169.43 v8(66.45,169.15)
  L7 w0.061: v4(63.71,170.96) 63.88,170.8 64.82,170.8 65.58,170.04 65.94,170.04
LPDDR3_M0_CKE1_A: length 19.8
  L2 w0.061: v10(60.94,172.42) 60.57,172.42 60.5,172.48 60.5,172.78 60.44,172.84 60.32,172.84 60.26,172.78 60.26,172.48 60.2,172.42 60.02,172.42 59.63,172.82 59.45,172.82 59.39,172.76 59.39,172.62 59.33,172.56 59.21,172.56 59.15,172.62 59.15,172.76 59.08,172.82 58.96,172.82 58.9,172.76 58.9,172.62 58.84,172.56 58.72,172.56 58.66,172.62 58.66,172.76 58.6,172.82 56.19,172.82 55.98,173.03 55.98,173.61 56.29,173.93 56.29,174.11 55.98,174.43 55.98,175.37 55.36,175.98 54.21,175.98 53.71,175.48 v10(53.07,175.48)
  L3SGND w0.127: v11(52.26,175.53) 52.31,175.48 53.07,175.48 v10(53.07,175.48) ; v10(60.94,172.42) 61.17,172.42 61.3,172.55 v11(61.55,172.55)
  L6SGND w0.127: v4(62.04,172.38) 61.72,172.38 v11(61.55,172.55) ; v11(52.26,175.53) 52.26,175.09 v5(52.22,175.06)
  L7 w0.061: v8(66.13,171.09) 65.85,171.09 65.54,171.4 64.51,171.4 63.99,171.92 63.67,171.92 63.21,172.38 v4(62.04,172.38)
LPDDR3_M0_CKE1_B: length 20.3
  L2 w0.061: v10(54.95,175.76) 55.41,175.76 55.86,175.32 55.86,172.98 56.14,172.7 56.14,172.7 56.55,172.28 56.73,172.28 56.79,172.34 56.79,172.6 56.85,172.66 56.97,172.66 57.03,172.6 57.03,172.34 57.09,172.28 57.22,172.28 57.28,172.34 57.28,172.6 57.34,172.66 57.46,172.66 57.52,172.6 57.52,172.34 57.58,172.28 57.7,172.28 57.76,172.34 57.76,172.6 57.83,172.66 57.95,172.66 58.01,172.6 58.01,172.34 58.07,172.28 59.94,172.28 59.98,172.24 60.71,172.24 60.82,172.13 61.69,172.13 61.78,172.04 61.78,171.91 61.69,171.82 v10(60.38,171.82)
  L3SGND w0.127: v11(54.65,176.12) 54.95,175.82 v10(54.95,175.76) ; v10(60.38,171.82) 60.46,171.82 60.6,171.96 v11(60.83,171.96)
  L6SGND w0.127: v11(54.65,176.12) 54.55,176.22 54.55,176.39 v5(54.73,176.57) ; v11(60.83,171.96) 61.03,172.16 v4(61.27,172.16)
  L7 w0.061: v4(61.27,172.16) 61.3,172.16 61.35,172.1 63.13,172.1 63.49,171.73 63.91,171.73 64.39,171.25 65.1,171.25 65.43,170.92 65.74,170.92 v8(65.8,170.85)
LPDDR3_M0_CLK_DN_A: length 22.9
  L3SGND w0.127: v11(51.04,173.81) 51.17,173.81 51.68,174.32 v10(51.68,174.57)
  L5 w0.066: v11(51.04,173.81) 51.04,173.89 51.37,174.21 51.37,174.37 51.55,174.55 v8(51.71,174.55) 51.71,174.11 52.43,173.38 52.43,173.28 51.78,172.63 51.78,172.38 51.96,172.2 52.22,172.2 52.87,172.85 52.96,172.85 53.61,172.2 54.08,172.2 54.15,172.13 54.15,172.02 54.4,171.77 54.61,171.77 54.76,171.92 54.76,172.13 54.83,172.2 55.55,172.2 55.61,172.25 56.4,172.25 57.66,170.99 58.77,170.99 60.39,169.37 62.71,169.37 v4(62.95,169.62)
  L7 w0.06: 66,168.58 66.06,168.52 66.22,168.52 66.36,168.38 66.61,168.38 66.69,168.31 v5(66.74,168.31)
  L7 w0.061: 66,168.58 65.99,168.58 65.54,169.04 65.03,169.54 63.07,169.54 62.99,169.62 v4(62.95,169.62)
LPDDR3_M0_CLK_DN_B: length 22.3
  L3SGND w0.127: v10(54.22,177.62) 53.96,177.88 53.96,177.9 v11(53.81,178.05)
  L5 w0.066: v11(53.81,178.05) 53.81,177.98 v8(54.22,177.56) 54.26,177.6 54.26,177.63 55.15,178.52 55.62,178.52 55.65,178.49 56.36,178.49 56.94,177.91 56.94,177.01 56.58,176.65 56.58,175.84 56.52,175.79 56.52,175.26 56.57,175.21 56.57,174.76 56.52,174.7 56.52,173.31 57.95,171.88 58.92,171.88 60.92,169.88 v4(60.96,169.88)
  L7 w0.06: 65.01,169.03 65.09,169.03 65.54,168.58 65.58,168.54 65.86,168.26 65.87,168.26 66.05,168.08 66.22,168.08 66.36,168.22 66.53,168.22 66.73,168.02 v8(67.01,168.02)
  L7 w0.061: v4(60.96,169.88) 61.04,169.79 61.95,169.79 62.71,169.03 65.01,169.03
LPDDR3_M0_CLK_DP_A: length 22.8
  L3SGND w0.127: v11(50.53,174.06) 50.66,174.06 v10(51.17,174.57)
  L5 w0.066: v11(50.53,174.06) 50.66,174.19 51.14,174.19 51.22,174.27 v8(51.22,174.58) 51.4,174.76 51.79,174.76 51.91,174.64 51.91,174.47 51.85,174.41 51.85,174.17 52.58,173.44 52.58,173.23 51.93,172.57 51.93,172.44 52.02,172.34 52.16,172.34 52.81,172.99 53.02,172.99 53.67,172.34 54.14,172.34 54.29,172.19 54.29,172.08 54.46,171.92 54.56,171.92 54.62,171.98 54.62,172.19 54.77,172.34 55.49,172.34 55.55,172.4 56.46,172.4 57.72,171.13 58.83,171.13 60.45,169.51 62.4,169.51 62.55,169.66 v4(62.56,169.66)
  L7 w0.06: v8(66.16,168.3) 66.12,168.35 65.95,168.35
  L7 w0.061: v4(62.56,169.66) 62.56,169.61 62.83,169.33 63.07,169.33 63.08,169.34 64.95,169.34 65.45,168.84 65.66,168.63 65.67,168.62 65.91,168.38 65.92,168.38 65.95,168.35
LPDDR3_M0_CLK_DP_B: length 22.2
  L3SGND w0.127: v10(54.22,177.11) 54.08,177.11 53.78,177.41 v11(53.78,177.49)
  L5 w0.066: v4(60.51,169.88) 60.51,170.08 58.86,171.74 57.89,171.74 56.38,173.25 56.38,174.76 56.43,174.82 56.43,175.15 56.38,175.2 56.38,175.84 56.44,175.9 56.44,176.71 56.8,177.07 56.8,177.85 56.3,178.35 55.59,178.35 55.57,178.38 55.21,178.38 54.43,177.59 54.43,177.44 54.51,177.36 54.51,177.23 54.35,177.06 v8(54.22,177.06) 54.14,177.06 53.78,177.41 v11(53.78,177.49)
  L7 w0.06: v8(66.45,168.02) 66.34,167.91 65.99,167.91 65.8,168.1 65.79,168.1 65.48,168.41 65.39,168.49 65.39,168.5 65.06,168.83 65.01,168.83
  L7 w0.061: v4(60.51,169.88) 60.8,169.59 61.87,169.59 62.63,168.83 65.01,168.83
LPDDR3_M0_CS0_B: length 22.3
  L2 w0.061: v10(61,171.46) 60.33,171.46 59.71,172.09 56.58,172.09 56.09,172.57 56.09,172.57 55.73,172.92 55.73,174.39 55.54,174.59 v10(55.54,174.93)
  L3SGND w0.127: v11(61.46,171.66) 61.26,171.46 v10(61,171.46) ; v10(55.54,174.93) 55.03,174.93 v11(55.02,174.92)
  L5 w0.076: v8(55.16,176.57) 55.16,176.75 55.03,176.88 54.9,176.88 54.77,176.75 54.77,176.45 54.96,176.26 54.96,175.92 54.85,175.81 54.57,175.81 54.47,175.71 54.47,175.41 54.55,175.33 55.15,175.33 55.23,175.25 55.23,175.13 v11(55.02,174.92)
  L6SGND w0.127: v4(61.98,171.28) 61.61,171.66 v11(61.46,171.66) ; v4(55.09,174.48) 55.02,174.55 v11(55.02,174.92)
  L7 w0.06: 65.89,169.92 66.08,169.73 66.08,169.52 v8(66.13,169.47)
  L7 w0.061: v4(61.98,171.28) 61.98,171.24 62.74,170.48 64.96,170.48 65.53,169.92 65.89,169.92 ; v8(52.22,175.56) 52.26,175.53 54.14,175.53 55.08,174.59 55.08,174.55 55.09,174.54 v4(55.09,174.48)
LPDDR3_M0_CS1_B: length 24.1
  L2 w0.061: v10(62.35,172.47) 61.79,173.03 60.97,173.03 60.88,173.12 58.37,173.12 58.31,173.18 58.31,173.42 58.24,173.48 58.12,173.48 58.06,173.42 58.06,173.18 58,173.12 57.63,173.12 57.57,173.18 57.57,173.42 57.51,173.48 57.39,173.48 57.33,173.42 57.33,173.12 57.25,173.05 57.15,173.05 57.08,173.12 57.08,173.42 57.02,173.48 56.9,173.48 56.84,173.42 56.84,173.18 56.78,173.12 v10(56.19,173.12)
  L3SGND w0.127: v11(62.82,172.62) 62.67,172.47 v10(62.35,172.47) ; v11(55.72,173.12) v10(56.19,173.12)
  L5 w0.076: v11(55.72,173.12) 55.72,173.21 54.18,174.74 54.18,176.69 54.72,177.24 v8(54.72,177.56)
  L6SGND w0.127: v4(55.08,173.93) 55.47,173.54 55.47,173.52 55.48,173.51 55.68,173.31 55.68,173.31 55.72,173.27 v11(55.72,173.12) ; v11(62.82,172.62) 62.88,172.62 62.88,172.62 63.49,172.62 v4(63.56,172.54)
  L7 w0.061: v4(63.56,172.54) 63.92,172.54 64.05,172.41 64.75,171.71 65.65,171.71 65.95,171.42 66.26,171.42 66.26,171.41 v8(66.45,171.41) ; v8(51.22,175.06) 51.4,174.88 51.47,174.82 51.98,174.82 52.15,174.65 54.11,174.65 54.84,173.93 v4(55.08,173.93)
LPDDR3_M0_D0_A: length 21
  L5 w0.06: 70.73,170.98 70.73,169.57 70.54,169.39 70.42,169.31 70.42,169.16 v8(70.41,169.15)
  L5 w0.076: v8(56.78,176.55) 56.8,176.57 57.06,176.57 58.69,178.2 65.82,178.2 70.58,173.44 70.58,171.13 70.73,170.98
LPDDR3_M0_D0_B: length 14.5
  L7 w0.06: 65.89,167.25 66.04,167.41 66.21,167.41 66.64,166.97 66.81,166.97 67.01,167.17 v8(67.01,167.45)
  L7 w0.061: v8(55.75,171.06) 56.01,170.79 56.01,170.49 56.13,170.38 56.17,170.38 57.04,169.5 58.89,169.5 59.01,169.38 59.01,168.67 59.7,167.99 60.2,167.99 60.27,168.05 60.27,168.24 60.34,168.31 60.44,168.31 60.51,168.24 60.51,168.05 60.57,167.99 60.78,167.99 62.34,167.99 62.71,167.62 62.72,167.62 63.36,167.62 63.38,167.64 65.34,167.64 65.72,167.25 65.89,167.25
LPDDR3_M0_D1_A: length 19.5
  L5 w0.06: 70.32,170.76 70.32,169.92 70.2,169.79 70.2,169.74 69.97,169.52 69.97,169.35 70.04,169.28 70.04,168.95 v8(70.12,168.87)
  L5 w0.076: v8(58.23,176.09) 58.36,176.09 58.59,176.31 58.59,177.36 58.86,177.63 65.58,177.63 70.1,173.11 70.1,170.98 70.32,170.76
LPDDR3_M0_D1_B: length 15.2
  L7 w0.06: v8(66.13,167.21) 66.05,167.13 64.93,167.13
  L7 w0.061: 64.93,167.13 64.62,167.44 63.2,167.44 62.64,167.44 62.27,167.81 62.23,167.81 62.23,167.81 60.85,167.81 60.85,167.81 59.62,167.81 58.84,168.6 58.84,169.25 58.74,169.34 58.57,169.34 58.51,169.28 58.51,168.65 58.44,168.59 58.32,168.59 58.26,168.65 58.26,169.28 58.2,169.34 58.08,169.34 58.02,169.28 58.02,168.65 57.96,168.59 57.84,168.59 57.77,168.65 57.77,169.28 57.71,169.34 56.88,169.34 56.41,169.82 56.04,169.82 55.75,170.11 v8(55.75,170.58)
LPDDR3_M0_D2_A: length 20.3
  L5 w0.06: 70.46,170.82 70.46,169.87 70.45,169.86 70.42,169.82 70.42,169.73 v8(70.41,169.72)
  L5 w0.076: v8(57.71,176.06) 57.52,176.06 57.39,176.19 57.39,176.45 57.52,176.57 57.95,176.57 58.12,176.41 58.23,176.41 58.34,176.51 58.34,176.62 58.17,176.79 58.17,177.14 58.85,177.82 65.66,177.82 70.23,173.25 70.23,171.04 70.46,170.82
LPDDR3_M0_D2_B: length 15.2
  L7 w0.06: v8(66.73,167.74) 66.61,167.74 66.58,167.77 65.96,167.77
  L7 w0.061: 65.96,167.77 65.75,167.98 65.74,167.98 65.63,168.09 65.58,168.14 62.93,168.14 62.54,168.54 61.01,168.54 59.4,170.16 58.01,170.16 57.41,170.75 57.24,170.75 57.02,170.98 57.02,171.63 56.87,171.77 56.55,171.77 56.42,171.9 56.42,172.24 55.86,172.8 55.1,172.8 54.97,172.67 54.97,172.34 v8(55.23,172.07)
LPDDR3_M0_D3_A: length 20.4
  L5 w0.06: 70.12,170.75 v8(70.12,170)
  L5 w0.076: v8(57.22,176.06) 57.07,176.06 56.99,175.98 56.99,175.87 57.07,175.78 58.25,175.78 59,176.53 59,176.64 58.76,176.88 58.76,177 58.85,177.09 58.98,177.09 59.22,176.86 59.32,176.86 59.43,176.96 59.43,177.07 59.27,177.23 59.27,177.36 59.36,177.45 59.49,177.45 59.65,177.29 59.76,177.29 59.91,177.44 65.5,177.44 69.96,172.98 69.96,170.91 70.12,170.75
LPDDR3_M0_D3_B: length 16.2
  L7 w0.061: v8(65.8,167.45) 65.46,167.79 63.31,167.79 63.3,167.79 62.79,167.79 62.42,168.16 62.35,168.16 61.04,168.16 61.04,168.17 60.88,168.17 60.54,168.5 60.25,168.5 59.92,168.17 59.82,168.17 59.75,168.24 59.75,168.34 60.18,168.77 60.18,168.86 60.1,168.95 60.01,168.95 59.6,168.53 59.49,168.53 59.42,168.6 59.42,168.7 59.84,169.12 59.84,169.21 59.75,169.29 59.66,169.29 59.38,169.01 59.28,169.01 59.21,169.08 59.21,169.18 59.49,169.46 59.49,169.55 59.37,169.67 57.3,169.67 56.42,170.56 56.42,170.66 56.22,170.86 56.16,170.86 56,171.02 56,171.56 55.82,171.74 55.39,171.74 v8(55.23,171.59)
LPDDR3_M0_D4_A: length 20.7
  L5 w0.06: 70.6,170.87 70.61,170.86 70.61,169.63 70.48,169.51 70.27,169.51 70.2,169.43 v8(70.17,169.43)
  L5 w0.076: 70.6,170.87 70.38,171.09 70.38,173.37 65.74,178.01 58.73,178.01 v8(56.78,176.07)
LPDDR3_M0_D4_B: length 15.4
  L7 w0.06: 65.71,166.51 65.72,166.52 65.89,166.52 66.04,166.37 66.21,166.37 66.36,166.52 66.53,166.52 66.73,166.32 v8(67.01,166.32)
  L7 w0.061: 65.71,166.51 65.69,166.49 65.68,166.49 62.25,166.49 62.08,166.65 61.88,166.86 61.83,166.86 61.25,166.86 61.25,166.86 59.67,166.86 59.23,166.86 58.97,167.12 56.94,167.12 55.17,168.89 55.17,169.18 55.03,169.32 55.03,170.76 55.21,170.94 v8(55.21,171.06)
LPDDR3_M0_D5_A: length 19
  L5 w0.06: 69.98,170.59 69.98,170.13 69.92,170.08 69.92,169.66 69.85,169.57 69.85,169.16 v8(69.84,169.15)
  L5 w0.076: 69.98,170.59 69.81,170.76 69.81,172.86 65.42,177.25 62.07,177.25 61.73,176.91 61.54,176.91 61.47,176.99 61.47,177.1 61.39,177.18 61.24,177.18 61.16,177.1 61.16,176.99 61.09,176.91 60.93,176.91 60.86,176.99 60.86,177.1 60.78,177.18 60.63,177.18 60.55,177.1 60.55,176.99 60.48,176.91 60.32,176.91 60.25,176.99 60.25,177.1 60.17,177.18 60.02,177.18 59.94,177.1 59.94,176.99 59.87,176.91 59.57,176.91 v8(58.22,175.56)
LPDDR3_M0_D5_B: length 16.5
  L7 w0.06: 64.72,166.64 64.73,166.64 65.94,166.64 66.01,166.57 v8(66.13,166.57)
  L7 w0.061: v8(55.23,170.55) 55.23,169.73 55.5,169.46 55.5,169.25 55.51,169.25 55.35,169.09 55.35,168.96 55.47,168.84 55.56,168.84 55.79,169.07 55.89,169.07 55.97,169 55.97,168.9 55.73,168.66 55.73,168.58 55.81,168.49 55.9,168.49 56.17,168.77 56.28,168.77 56.35,168.69 56.35,168.59 56.07,168.32 56.07,168.23 56.2,168.11 56.28,168.11 56.69,168.52 56.79,168.52 56.87,168.45 56.87,168.35 56.46,167.94 56.46,167.85 56.64,167.67 56.8,167.67 56.88,167.75 57.12,167.75 57.55,167.32 59.01,167.32 59.3,167.03 59.59,167.03 59.59,167.03 61.18,167.03 61.95,167.03 62.26,166.73 62.32,166.66 64.7,166.66 64.72,166.64
LPDDR3_M0_D6_A: length 19.9
  L5 w0.06: 69.81,170.57 69.8,170.56 69.8,169.7 69.73,169.61 69.73,169.37 69.64,169.28 69.64,168.78 v8(69.84,168.58)
  L5 w0.076: 69.81,170.57 69.81,170.57 69.67,170.7 69.67,172.73 65.34,177.06 63.72,177.06 63.38,176.72 63.18,176.72 63.11,176.8 63.11,176.98 63.03,177.06 62.88,177.06 62.8,176.98 62.8,176.8 62.73,176.72 62.57,176.72 62.5,176.8 62.5,176.98 62.42,177.06 62.27,177.06 62.19,176.98 62.19,176.8 62.12,176.72 59.68,176.72 58.31,175.35 58.14,175.35 57.93,175.56 v8(57.72,175.56)
LPDDR3_M0_D6_B: length 14.9
  L7 w0.061: v8(54.73,171.06) 54.41,171.06 54.32,170.97 54.32,170.83 54.41,170.74 54.76,170.74 54.89,170.61 54.89,169.29 54.99,169.18 54.99,168.96 54.99,168.96 54.99,168.82 56.88,166.93 58.91,166.93 59.15,166.68 59.74,166.68 61.32,166.68 61.8,166.68 61.9,166.58 62.17,166.31 63.36,166.31 63.36,166.32 v8(65.8,166.32)
LPDDR3_M0_D7_A: length 19.3
  L5 w0.076: v8(69.53,169.47) 69.53,169.58 69.6,169.65 69.67,169.74 69.67,170.51 69.42,170.77 69.42,172.64 69.42,172.64 69.42,172.69 67.49,174.61 67.49,174.65 65.63,176.51 65.3,176.51 65.22,176.58 65.22,176.76 65.15,176.83 65,176.83 64.92,176.76 64.92,176.58 64.84,176.51 64.69,176.51 64.62,176.58 64.62,176.76 64.54,176.83 64.39,176.83 64.31,176.76 64.31,176.58 64.23,176.51 64.08,176.51 64.01,176.58 64.01,176.76 63.93,176.83 63.78,176.83 63.7,176.76 63.7,176.58 63.62,176.51 59.66,176.51 58.37,175.22 57.77,175.22 57.43,175.56 v8(57.22,175.56)
LPDDR3_M0_D7_B: length 15.5
  L7 w0.06: v8(66.73,166.04) 66.7,166.04 66.63,166.11 66.37,166.11 66.28,166.21 65.97,166.21 65.89,166.12 65.7,166.12 65.7,166.11
  L7 w0.061: v8(54.67,170.52) 54.41,170.52 54.28,170.4 54.28,170.09 54.7,169.67 54.7,169.57 54.71,169.56 54.71,169.29 54.82,169.18 54.82,169.03 54.82,168.74 56.81,166.75 58.84,166.75 59.08,166.51 59.23,166.51 59.23,166.51 59.81,166.51 61.39,166.51 61.73,166.51 62.1,166.14 63.25,166.14 63.29,166.18 65.62,166.18 65.68,166.11 65.7,166.11
LPDDR3_M0_D8_A: length 16.1
  L5 w0.06: 66.66,172.97 68.67,170.96 68.67,170.53 68.85,170.34 68.85,169.91 68.91,169.85 68.91,169.63 68.79,169.52 68.79,169.07 v8(68.99,168.87)
  L5 w0.076: 66.66,172.97 66.66,173.43 64.76,175.33 59.47,175.33 58.6,174.46 58.02,174.46 57.92,174.36 57.92,174.21 58.02,174.11 v8(58.23,174.11)
LPDDR3_M0_D8_B: length 30
  L7 w0.06: 66.22,164.64 66.23,164.64 66.36,164.77 66.53,164.77 66.6,164.7 66.81,164.7 66.92,164.82 66.92,164.99 66.81,165.1 66.81,165.27 66.93,165.39 67.21,165.67 67.21,165.84 67.09,165.95 66.93,165.95 66.81,165.84 66.65,165.84 66.49,165.99 66.21,165.99 v8(66.19,166.01)
  L7 w0.061: 66.22,164.64 65.62,164.64 64.63,164.64 64.04,164.05 62.37,164.05 62.09,164.33 61.99,164.43 61.99,164.43 61.56,164.43 61.42,164.43 61.23,164.62 52.18,164.62 51.81,164.99 51.71,165.09 49.82,165.09 49.47,165.44 49.47,168.83 49.61,168.97 49.61,170.05 50.35,170.79 50.39,170.84 51.74,170.84 51.88,170.98 51.88,171.18 52.08,171.38 52.26,171.38 52.52,171.64 52.52,171.65 52.64,171.77 52.81,171.77 52.99,171.59 v8(53.2,171.59)
LPDDR3_M0_D9_A: length 15.9
  L5 w0.06: 66.41,172.89 68.55,170.75 68.55,170.48 68.73,170.29 68.73,169.74 v8(68.71,169.72)
  L5 w0.076: v8(57.72,174.06) 57.88,173.9 58.46,173.9 58.54,173.98 58.54,174.22 58.61,174.3 58.77,174.3 58.84,174.22 58.84,173.98 58.92,173.9 59.12,173.9 59.72,174.5 59.72,174.71 59.56,174.87 59.56,174.98 59.66,175.09 59.77,175.09 59.93,174.93 60.04,174.93 60.25,175.14 64.66,175.14 66.41,173.39 66.41,172.89
LPDDR3_M0_D9_B: length 28.4
  L7 w0.06: 65.74,165.99 65.75,166 65.92,166 66.12,165.79 66.4,165.79 66.43,165.75 v8(66.45,165.75)
  L7 w0.061: v8(53.23,171.04) 53.23,170.88 53.31,170.79 53.83,170.79 53.95,170.92 53.95,171.22 54.08,171.35 54.24,171.35 54.32,171.27 54.32,171.14 54.2,171.02 54.2,170.79 54.11,170.7 54.11,170.34 54.05,170.28 53.65,170.28 53.59,170.22 53.59,170.09 53.65,170.03 54.16,170.03 54.58,169.62 54.58,168.81 54.45,168.68 54.12,168.68 54.01,168.57 54.01,168.42 54.12,168.31 54.55,168.31 54.71,168.47 54.84,168.47 54.94,168.37 54.94,168.24 54.55,167.85 54.55,167.75 54.62,167.67 54.72,167.67 55.14,168.09 55.22,168.09 55.31,168 55.31,167.92 55.14,167.74 55.14,167.67 55.24,167.57 55.31,167.57 55.48,167.75 55.57,167.75 55.66,167.66 55.66,167.57 54.84,166.76 54.84,166.66 54.92,166.59 55.02,166.59 55.83,167.4 55.91,167.4 56,167.31 56,167.23 55.47,166.69 55.47,166.59 55.54,166.52 55.64,166.52 56.17,167.06 56.26,167.06 56.35,166.97 56.35,166.88 56.12,166.66 56.12,166.56 56.19,166.48 56.29,166.48 56.52,166.71 56.6,166.71 56.84,166.48 58.86,166.48 59.01,166.33 59.89,166.33 61.47,166.33 61.61,166.33 61.63,166.31 62.03,165.91 62.61,165.91 62.88,165.91 63.04,165.75 63.3,165.75 63.36,165.7 63.62,165.7 63.7,165.77 63.7,165.97 63.78,166.05 63.89,166.05 63.97,165.97 63.97,165.75 64.02,165.7 64.21,165.7 64.27,165.76 64.27,165.96 64.37,166.06 64.51,166.06 64.59,165.97 64.59,165.76 64.65,165.7 64.9,165.7 64.95,165.75 64.95,165.95 65.05,166.04 65.18,166.04 65.28,165.95 65.28,165.78 65.35,165.71 65.47,165.71 65.74,165.99
LPDDR3_M0_D10_A: length 14.1
  L5 w0.06: v8(68.41,170.03) 68.32,170.12 68.32,170.21 67.61,170.92 67.61,171.03 67.5,171.14
  L5 w0.076: 67.5,171.14 66.04,172.6 66.04,173.11 65.21,173.93 65.1,173.93 64.79,173.62 64.68,173.62 64.57,173.73 64.57,173.83 64.89,174.15 64.89,174.26 64.39,174.76 60.41,174.76 59.2,173.55 v8(58.23,173.55)
LPDDR3_M0_D10_B: length 28
  L7 w0.06: v8(67.01,165.75) 67.01,165.75 66.92,165.67 66.64,165.67 66.53,165.55 66.36,165.55 66.25,165.67 65.99,165.67 65.94,165.62 65.94,165.62 65.92,165.6 65.58,165.6 65.57,165.58
  L7 w0.061: v8(53.25,170.55) 53.46,170.35 53.46,169.91 53.52,169.85 53.77,169.85 53.84,169.78 53.84,169.68 53.77,169.61 53.2,169.61 53.09,169.5 53.09,169.35 53.2,169.24 53.58,169.24 53.65,169.17 53.65,169.07 53.58,169 53.19,169 53.11,168.92 53.11,168.82 53.19,168.75 53.75,168.75 53.82,168.68 53.82,168.58 53.75,168.51 53.19,168.51 53.12,168.44 53.12,168.34 53.19,168.26 53.91,168.26 54.01,168.17 54.01,168.09 53.94,168.02 53.23,168.02 53.16,167.96 53.16,167.78 53.23,167.72 54.13,167.72 54.2,167.65 54.2,167.55 54.13,167.48 53.24,167.48 53.17,167.4 53.17,167.27 53.29,167.15 54.6,167.15 54.71,167.04 54.71,166.9 54.61,166.79 53.19,166.79 53.12,166.72 53.12,166.62 53.19,166.55 54.6,166.55 54.85,166.3 58.79,166.3 58.94,166.16 59.37,166.16 59.96,166.16 61.54,166.16 61.56,166.14 61.96,165.74 62.53,165.74 62.53,165.73 62.8,165.73 62.96,165.57 65.56,165.57 65.57,165.58
LPDDR3_M0_D11_A: length 16.2
  L5 w0.06: 67.88,171.06 67.88,170.85 68.61,170.12 68.61,169.94 68.51,169.84 68.51,169.63 68.63,169.52 68.63,169.35 68.51,169.23 67.78,169.23 67.66,169.35 67.66,169.63 v8(67.58,169.72)
  L5 w0.076: v8(57.75,173.6) 57.92,173.77 59.18,173.77 59.87,174.45 59.87,174.49 60.33,174.95 64.47,174.95 66.17,173.24 66.17,172.82 67.88,171.11 67.88,171.06
LPDDR3_M0_D11_B: length 28.5
  L7 w0.06: 65.32,164.08 66.19,164.08 66.45,164.34 v8(66.73,164.34)
  L7 w0.061: 65.32,164.08 65.29,164.11 64.77,164.11 64.18,163.53 62.15,163.53 61.96,163.71 61.77,163.9 61.49,163.9 61.2,163.9 61.02,164.09 50.08,164.09 49.4,164.77 48.91,165.26 48.91,170.1 50.62,171.81 50.68,171.81 51.15,172.27 52.54,172.27 v8(52.72,172.1)
LPDDR3_M0_D12_A: length 16.1
  L5 w0.06: 67.36,169.65 67.49,169.52 67.49,169.23 v8(67.58,169.15)
  L5 w0.076: 67.36,169.65 67.09,169.92 66.58,169.92 65.97,170.53 65.97,170.54 65.89,170.62 65.84,170.62 62.93,173.54 60.89,173.54 60.47,173.11 60.47,172.4 60.26,172.19 60.26,172.19 60.09,172.19 59.96,172.06 59.96,171.67 59.89,171.6 59.74,171.6 59.66,171.67 59.66,172.04 59.56,172.14 59.32,172.14 59.24,172.22 59.24,172.39 59.15,172.47 59.03,172.47 58.94,172.39 58.94,172.22 58.86,172.14 58.71,172.14 58.63,172.22 58.63,172.4 58.55,172.48 58.41,172.48 58.33,172.4 58.33,172.22 58.25,172.14 58.06,172.14 57.23,172.97 57.23,173.51 v8(57.19,173.55)
LPDDR3_M0_D12_B: length 27.5
  L7 w0.06: 52.13,171.26 52,171.13 52,170.59 51.88,170.47 ; 66.18,164.76 66.31,164.89 66.71,164.89 v8(66.72,164.9)
  L7 w0.061: 52.13,171.26 52.32,171.26 52.62,171.57 v8(52.72,171.57) ; 66.18,164.76 64.58,164.76 64.05,164.23 62.44,164.23 62.06,164.6 61.49,164.6 61.31,164.79 52.26,164.79 51.98,165.06 51.78,165.27 49.89,165.27 49.65,165.51 49.65,166.98 49.77,167.11 50.46,167.11 50.67,167.31 50.67,167.67 50.74,167.75 50.74,167.75 50.82,167.82 50.82,168.19 50.32,168.68 50.32,168.8 49.8,169.33 49.8,169.88 50.22,170.3 51.71,170.3 51.76,170.35 51.76,170.35 51.88,170.47
LPDDR3_M0_D13_A: length 15.4
  L5 w0.06: v8(67.29,169.43) 67.01,169.71 66.6,169.71 65.83,170.48
  L5 w0.076: v8(56.72,173.56) 56.72,173.29 58,172.01 58.98,172.01 59.54,171.45 60.33,171.45 60.45,171.58 60.45,172.12 60.66,172.32 60.66,173.02 60.67,173.03 60.67,173.03 60.89,173.25 60.89,173.25 60.99,173.35 61.42,173.35 61.5,173.27 61.5,173.03 61.59,172.94 61.72,172.94 61.8,173.03 61.8,173.27 61.88,173.35 62.8,173.35 64.55,171.59 64.58,171.59 65.69,170.48 65.83,170.48
LPDDR3_M0_D13_B: length 29.8
  L7 w0.061: v8(66.16,165.47) 66.16,165.47 65.96,165.47 65.63,165.47 65.55,165.4 62.86,165.4 62.7,165.56 62.46,165.56 61.89,165.56 61.47,165.98 60.03,165.98 59.45,165.98 58.35,165.98 58.28,166.04 58.28,166.07 58.22,166.13 58.1,166.13 58.04,166.07 58.04,166.04 57.98,165.98 57.86,165.98 57.8,166.04 57.8,166.07 57.74,166.13 57.61,166.13 57.55,166.07 57.55,166.04 57.49,165.98 57.37,165.98 57.31,166.04 57.31,166.07 57.25,166.13 57.13,166.13 57.07,166.07 57.07,166.04 57,165.98 56.88,165.98 56.82,166.04 56.82,166.07 56.76,166.13 56.64,166.13 56.58,166.07 56.58,166.04 56.52,165.98 56.39,165.98 56.33,166.04 56.33,166.07 56.27,166.13 56.15,166.13 56.09,166.07 56.09,166.04 56.03,165.98 55.91,165.98 55.85,166.04 55.85,166.07 55.79,166.13 55.66,166.13 55.6,166.07 55.6,166.04 55.54,165.98 55.42,165.98 55.36,166.04 55.36,166.07 55.3,166.13 55.18,166.13 55.11,166.07 55.11,166.04 55.05,165.98 54.62,165.98 54.56,166.04 54.56,166.3 54.48,166.37 54.38,166.37 54.31,166.3 54.31,166.04 54.25,165.98 54.13,165.98 54.07,166.04 54.07,166.31 54,166.37 53.89,166.37 53.82,166.31 53.82,166.04 53.76,165.98 53.64,165.98 53.58,166.04 53.58,166.29 53.51,166.36 53.41,166.36 53.34,166.29 53.34,166.04 53.28,165.98 53.07,165.98 52.94,166.1 52.94,168.75 52.94,168.75 52.94,169 52.94,169 52.94,169.77 52.87,169.84 52.77,169.84 52.7,169.77 52.7,166.1 52.63,166.03 52.53,166.03 52.46,166.1 52.46,169.79 52.58,169.9 53.03,170.36 53.03,170.95 52.95,171.03 v8(52.72,171.03)
LPDDR3_M0_D14_A: length 14.7
  L5 w0.06: v8(68.43,169.43) 68.36,169.5 68.36,169.79 68.18,169.97 68.18,170.15 66.12,172.21
  L5 w0.076: v8(58.23,173.09) 58.23,173.25 58.39,173.41 58.58,173.41 58.66,173.34 58.66,173.19 58.73,173.11 58.89,173.11 58.96,173.19 58.96,173.34 59.04,173.41 59.25,173.41 60.06,174.22 60.14,174.22 60.49,174.57 63.46,174.57 63.87,174.17 63.97,174.17 64.27,174.46 64.38,174.46 64.48,174.35 64.48,174.24 64.19,173.95 64.19,173.84 65.82,172.21 66.12,172.21
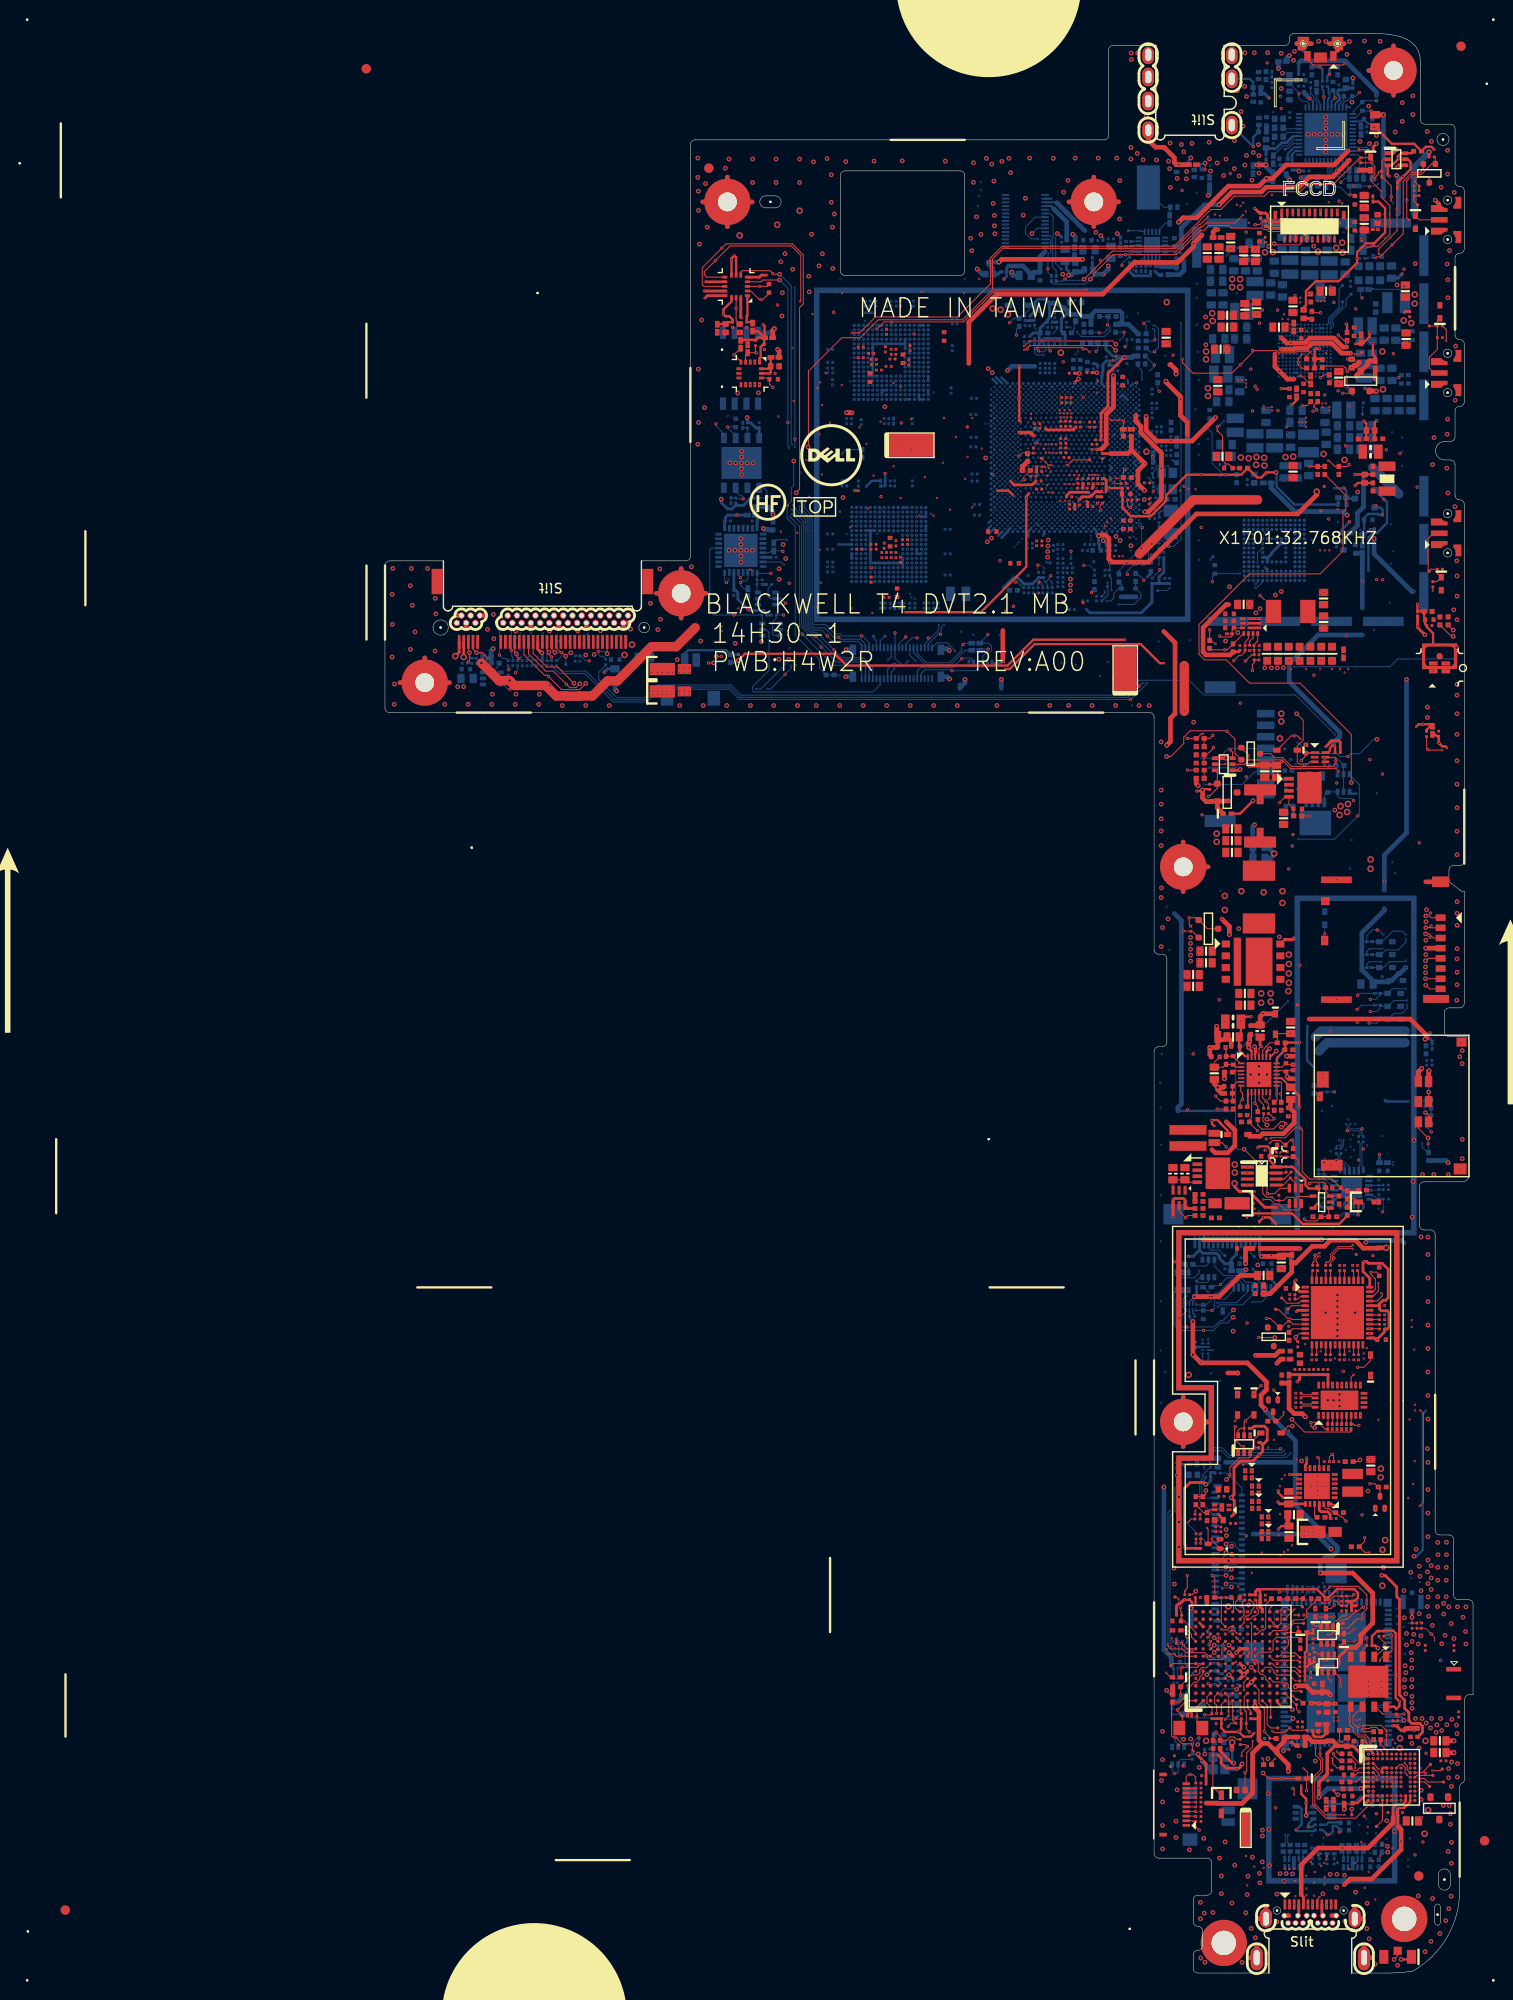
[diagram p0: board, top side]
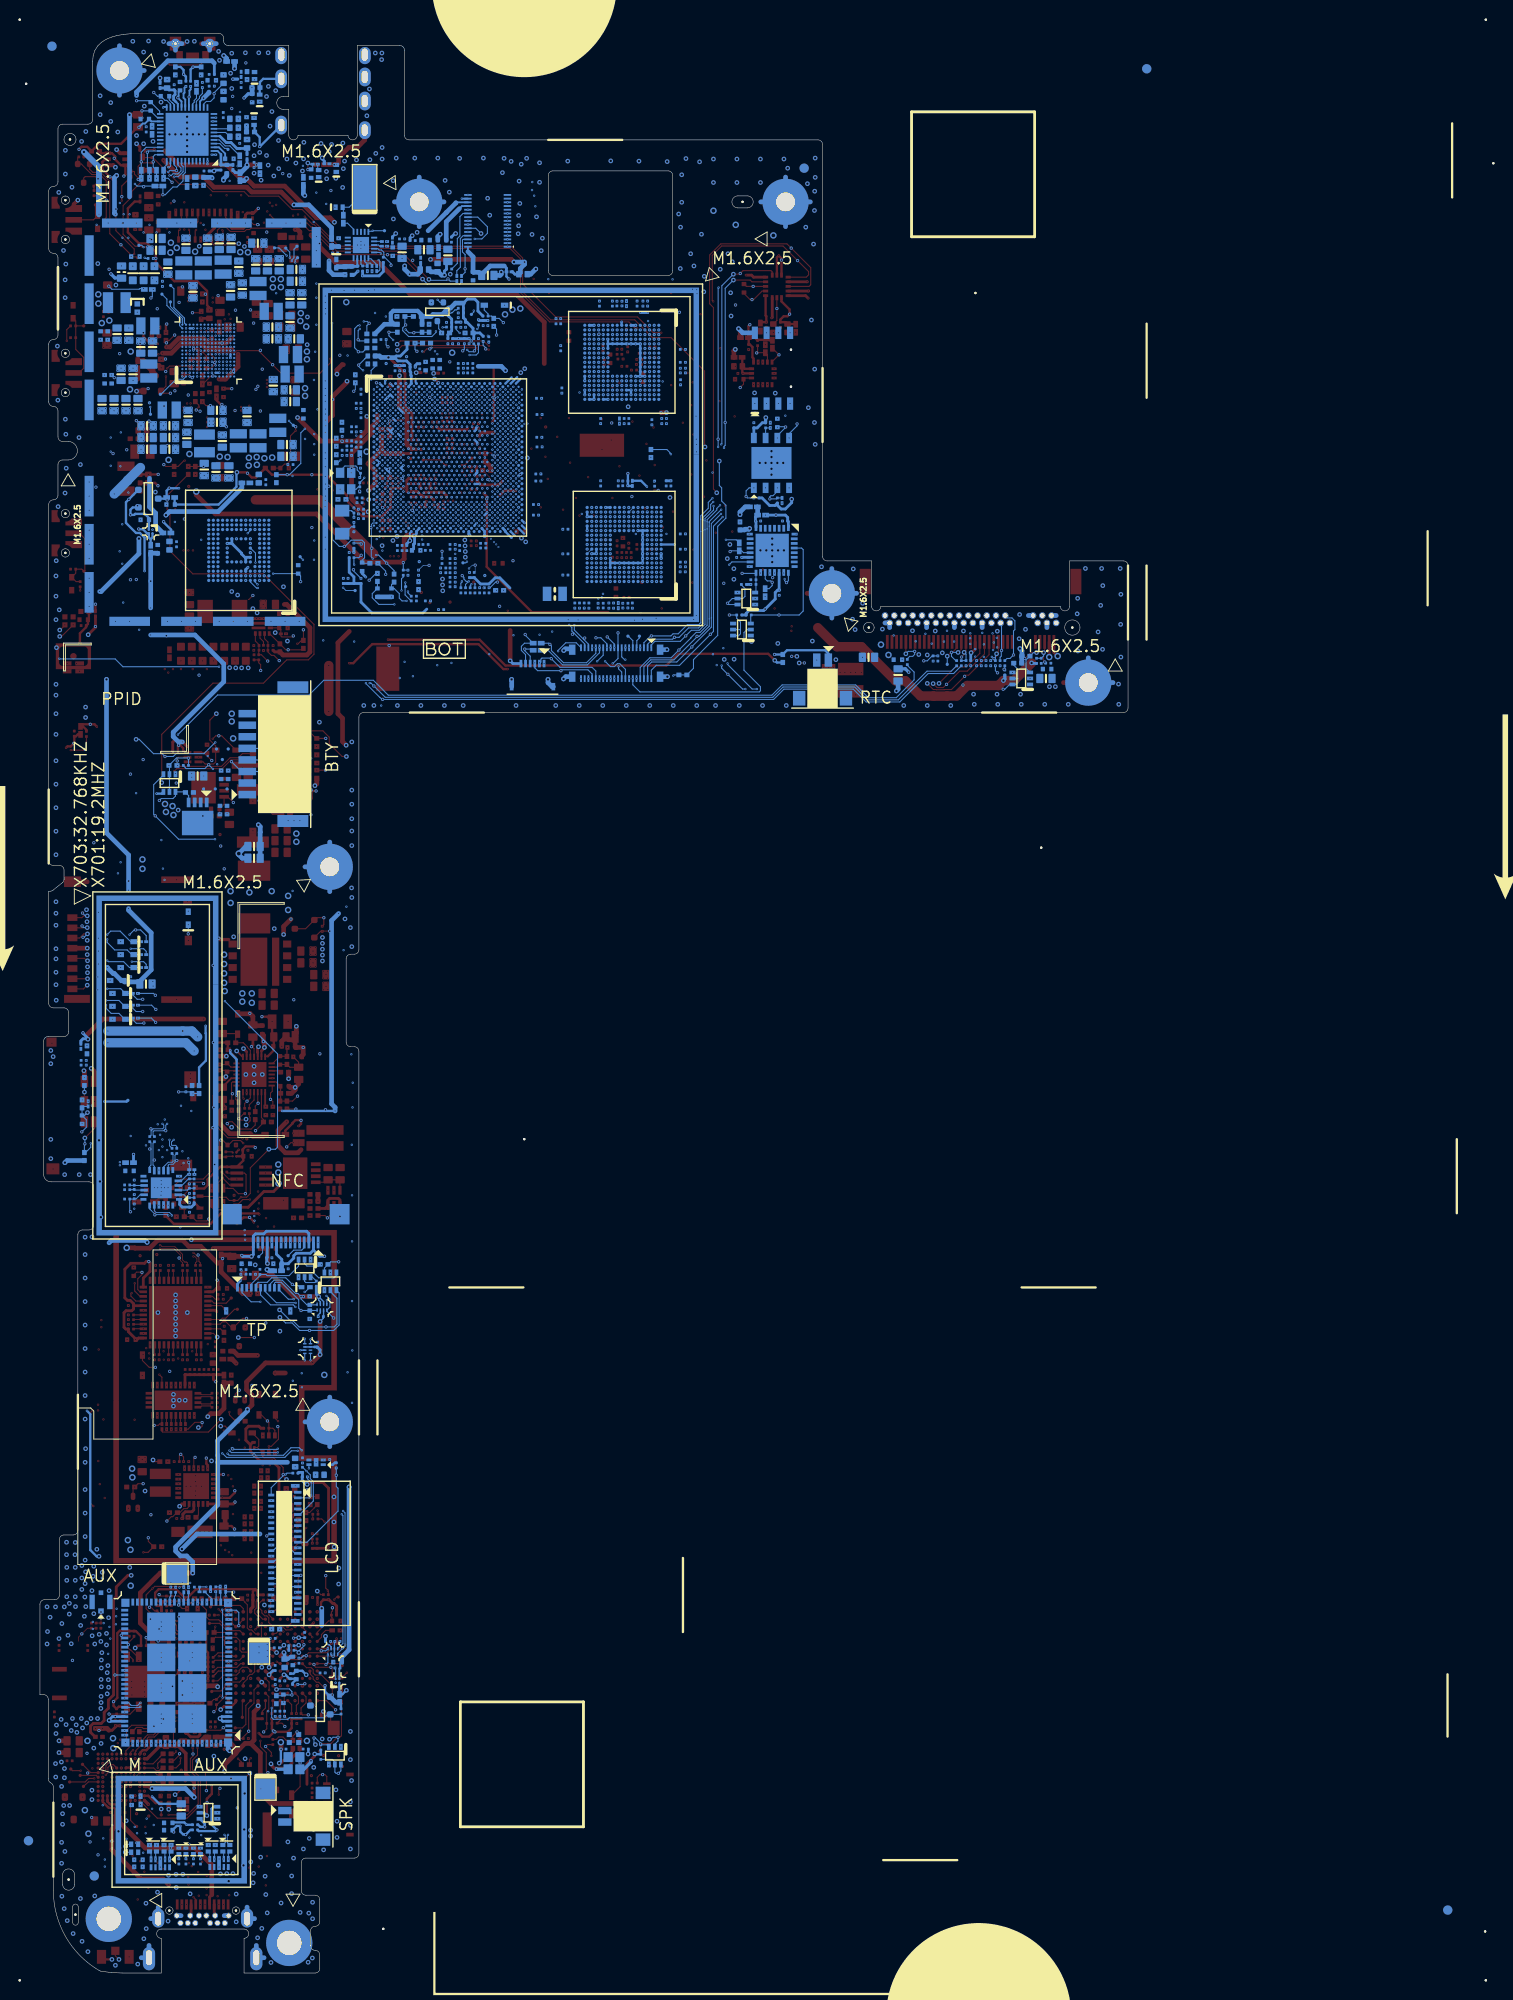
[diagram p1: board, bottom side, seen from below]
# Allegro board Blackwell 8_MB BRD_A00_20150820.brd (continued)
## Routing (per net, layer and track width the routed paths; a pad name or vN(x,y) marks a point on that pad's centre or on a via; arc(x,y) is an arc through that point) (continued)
LPDDR3_M0_D14_B: length 27.8
  L7 w0.06: v8(66.73,165.47) 66.7,165.47 66.63,165.39 66.36,165.39 66.25,165.27 65.99,165.27 65.91,165.35 65.74,165.35 65.74,165.35 65.68,165.35 65.67,165.34
  L7 w0.061: 65.67,165.34 65.55,165.22 63.97,165.22 63.91,165.16 63.91,164.96 63.84,164.89 63.74,164.89 63.67,164.96 63.67,165.16 63.61,165.22 63.04,165.22 62.97,165.15 62.97,165.07 62.91,165.01 62.77,165.01 62.72,165.06 62.72,165.17 62.5,165.38 62.39,165.38 61.82,165.38 61.39,165.81 59.52,165.81 52.35,165.81 52.1,166.05 52.02,166.05 51.8,166.27 51.8,167.3 51.8,167.31 51.8,167.54 51.8,167.55 51.8,169.46 51.87,169.54 51.97,169.54 52.04,169.46 52.04,166.3 52.11,166.23 52.21,166.23 52.28,166.3 52.28,169.78 52.45,169.95 52.75,170.24 v8(52.75,170.58)
LPDDR3_M0_D15_A: length 16.3
  L5 w0.06: 67.5,170.08 67.86,169.72 v8(67.86,169.43)
  L5 w0.076: v8(57.67,173.05) 57.7,173.02 57.7,172.74 57.83,172.62 58.03,172.62 58.03,172.61 59.02,172.61 59.02,172.61 59.13,172.61 59.26,172.75 59.37,172.75 59.81,172.31 59.92,172.31 60.03,172.42 60.03,172.52 59.62,172.93 59.62,173.1 59.76,173.24 59.93,173.24 60.02,173.15 60.12,173.15 60.7,173.73 60.89,173.73 60.99,173.83 61.19,173.83 61.29,173.73 61.5,173.73 61.6,173.83 61.8,173.83 61.9,173.73 62.11,173.73 62.21,173.83 62.41,173.83 62.51,173.73 63.01,173.73 63.14,173.59 63.25,173.59 63.34,173.68 63.44,173.68 63.55,173.57 63.55,173.47 63.46,173.38 63.46,173.27 63.65,173.08 63.65,173.07 64.48,172.25 64.92,171.81 65.03,171.81 65.19,171.97 65.31,171.97 65.4,171.88 65.4,171.75 65.24,171.59 65.24,171.49 65.77,170.96 65.88,170.96 66.08,171.16 66.21,171.16 66.3,171.06 66.3,170.94 66.1,170.73 66.1,170.63 66.58,170.15 67.43,170.15 67.5,170.08
LPDDR3_M0_D15_B: length 28.9
  L7 w0.06: 65.33,164.27 66.1,164.27 v8(66.12,164.3)
  L7 w0.061: 65.33,164.27 64.72,164.27 64.15,163.7 62.22,163.7 62.04,163.89 61.85,164.08 61.7,164.08 61.7,164.08 61.42,164.08 61.27,164.08 61.09,164.26 51.39,164.26 51.25,164.4 51.25,164.64 51.17,164.73 51.04,164.73 50.96,164.64 50.96,164.33 50.89,164.26 50.7,164.26 50.63,164.33 50.63,164.66 50.55,164.74 50.36,164.74 50.28,164.66 50.28,164.45 50.17,164.34 50.08,164.34 49.92,164.5 49.92,164.67 49.85,164.74 49.67,164.74 49.47,164.95 49.09,165.33 49.09,169.3 49.15,169.36 49.18,169.36 49.26,169.44 49.26,169.59 49.18,169.67 49.15,169.67 49.09,169.73 49.09,170.03 50.38,171.32 50.53,171.32 50.69,171.16 50.8,171.16 50.93,171.28 50.93,171.67 51.03,171.78 51.3,171.78 51.44,171.92 51.54,171.92 51.69,171.78 51.91,171.78 51.98,171.85 51.98,172.02 52.03,172.07 v8(52.21,172.07)
LPDDR3_M0_D16_A: length 23.4
  L7 w0.06: 69.9,174.2 69.9,172.83 70.09,172.63 70.09,171.88 70.12,171.85 70.12,171.75 70.12,171.75 70.12,171.44 70.32,171.24 70.32,171.05 69.78,170.5 69.78,170.35 v8(69.84,170.28)
  L7 w0.061: 69.9,174.2 66.15,177.95 65.48,177.95 64.71,178.72 64.42,178.72 64.36,178.78 64.36,178.85 64.32,178.9 64.16,178.9 64.12,178.85 64.12,178.73 64.08,178.69 63.94,178.69 63.87,178.76 63.87,178.84 63.81,178.9 63.69,178.9 63.63,178.84 63.63,178.71 63.59,178.68 63.42,178.68 63.39,178.71 63.39,178.85 63.33,178.9 63.2,178.9 63.14,178.85 63.14,178.74 63.08,178.68 62.96,178.68 62.9,178.74 62.9,178.85 62.85,178.9 62.71,178.9 62.66,178.85 62.66,178.74 62.6,178.68 62.45,178.68 62.39,178.74 62.39,178.83 62.32,178.9 62.2,178.9 62.13,178.83 62.13,178.5 62.04,178.41 61.72,178.41 61.58,178.55 61.49,178.55 61.36,178.41 61.19,178.41 61.16,178.44 61.16,178.55 61.08,178.63 60.98,178.63 60.9,178.56 60.9,178.48 60.84,178.41 60.69,178.41 60.61,178.5 60.61,178.82 60.53,178.9 58.6,178.9 58.5,178.8 58.5,178.65 58.37,178.53 57.92,178.53 57.83,178.43 57.83,178.32 57.91,178.23 58.47,178.23 58.57,178.13 58.57,177.99 58.47,177.89 57.98,177.89 57.9,177.81 57.9,177.69 57.98,177.61 v8(58.23,177.61)
LPDDR3_M0_D16_B: length 15.4
  L5 w0.06: 68.46,166.64 v8(68.43,166.6)
  L5 w0.076: v8(57.22,171.06) 57.01,170.85 57.01,170.46 57.96,169.51 59.54,169.51 60.17,168.88 64.05,168.88 64.95,167.98 65.24,167.98 65.31,167.9 65.31,167.76 65.39,167.69 65.54,167.69 65.62,167.76 65.62,167.9 65.7,167.98 65.85,167.98 65.92,167.9 65.92,167.76 66,167.69 66.15,167.69 66.23,167.76 66.23,167.9 66.3,167.98 66.46,167.98 66.53,167.9 66.53,167.76 66.61,167.69 66.76,167.69 66.84,167.76 66.84,167.9 66.91,167.98 67.49,167.98 68.07,167.4 68.4,167.4 68.49,167.31 68.49,166.66 68.46,166.64
LPDDR3_M0_D17_A: length 21.6
  L7 w0.061: v8(70.41,171.49) 70.46,171.54 70.46,171.95 70.41,171.99 70.32,171.99 70.26,172.05 70.26,172.18 70.32,172.24 70.42,172.24 70.48,172.3 70.48,172.42 70.42,172.48 70.32,172.48 70.26,172.54 70.26,172.66 70.32,172.73 70.41,172.73 70.48,172.79 70.48,172.9 70.41,172.97 70.12,172.97 70.05,173.04 70.05,173.14 70.12,173.21 70.41,173.21 70.48,173.28 70.48,173.39 70.41,173.46 70.12,173.46 70.04,173.53 70.04,173.64 70.12,173.72 70.43,173.72 70.48,173.76 70.48,173.94 70.4,174.02 70.12,174.02 70.07,174.07 70.07,174.27 66.22,178.13 65.56,178.13 64.61,179.07 58.22,179.07 58.04,178.89 57.95,178.89 57.79,179.06 57.71,179.06 57.61,178.96 57.61,178.89 57.78,178.72 57.78,178.63 57.46,178.31 57.46,177.69 57.59,177.56 v8(57.72,177.56)
LPDDR3_M0_D17_B: length 14.1
  L5 w0.076: v8(57.22,170.55) 58.09,169.68 59.66,169.68 59.76,169.58 59.76,169.58 60.26,169.07 64.05,169.07 65,168.12 67.55,168.12 68.12,167.54 68.62,167.54 68.83,167.33 69.06,167.33 69.18,167.2 69.18,167.01 69.06,166.89 v8(68.71,166.89)
LPDDR3_M0_D18_A: length 23
  L7 w0.06: 70.6,171.75 70.61,171.74 70.61,171.41 70.45,171.25 70.45,171.09 70.61,170.93 70.61,170.77 70.41,170.57 v8(70.12,170.57)
  L7 w0.061: v8(57.22,177.56) 57.42,177.56 57.51,177.47 57.51,177.34 57.42,177.25 57,177.25 56.95,177.31 56.95,177.64 56.98,177.68 56.98,178.22 56.84,178.36 56.84,178.42 56.99,178.57 57.05,178.57 57.23,178.39 57.31,178.39 57.4,178.48 57.4,178.57 57.23,178.74 57.23,178.83 57.65,179.25 64.68,179.25 65.63,178.3 66.29,178.3 70.6,173.99 70.6,171.75
LPDDR3_M0_D18_B: length 16.2
  L5 w0.06: v8(67.86,166.04) 67.86,166.32 67.18,167 67.17,167
  L5 w0.076: v8(56.73,171.57) 56.45,171.29 56.17,171.29 55.77,170.88 55.77,169.76 57.77,167.75 64.21,167.75 64.97,167 65.64,167 67.17,167
LPDDR3_M0_D19_A: length 21.9
  L7 w0.06: 70.77,172.36 70.85,172.28 70.85,171.06 70.77,170.98 70.77,170.76 70.89,170.65 70.89,170.48 70.69,170.28 v8(70.41,170.28)
  L7 w0.061: v8(56.72,177.56) 56.72,178.57 57.58,179.43 64.75,179.43 65.7,178.48 66.36,178.48 70.2,174.64 70.2,174.57 70.76,174.01 70.76,172.36 70.77,172.36
LPDDR3_M0_D19_B: length 15.6
  L5 w0.076: v8(56.71,171.06) 56.5,170.85 56.5,170.46 56.62,170.34 56.72,170.34 57.18,169.88 57.18,169.4 57.34,169.24 57.44,169.24 57.56,169.37 57.67,169.37 57.78,169.26 57.78,169.15 57.66,169.03 57.66,168.92 57.82,168.76 57.89,168.76 58.34,169.21 59.27,169.21 59.46,169.03 59.46,168.92 59.26,168.72 59.26,168.6 59.35,168.51 59.48,168.51 59.67,168.7 59.78,168.7 59.99,168.5 64.04,168.5 65.14,167.4 67.63,167.4 v8(68.14,166.89)
LPDDR3_M0_D20_A: length 23.6
  L7 w0.06: 69.76,171.7 69.76,171.05 69.56,170.85 v8(69.56,170.57)
  L7 w0.061: v8(58.25,177.09) 58.25,177.1 58.51,177.1 58.56,177.15 59.94,177.15 60.08,177.29 60.08,177.71 60.14,177.77 60.27,177.77 60.33,177.71 60.33,177.49 60.39,177.42 60.51,177.42 60.57,177.49 60.57,177.81 60.64,177.88 60.74,177.88 60.82,177.81 60.82,177.49 60.88,177.42 61.05,177.42 61.11,177.49 61.11,177.8 61.18,177.87 61.29,177.87 61.36,177.8 61.36,177.49 61.42,177.42 61.54,177.42 61.6,177.49 61.6,177.8 61.67,177.87 61.77,177.87 61.84,177.8 61.84,177.49 61.91,177.42 62.03,177.42 62.09,177.49 62.09,177.8 62.16,177.87 62.26,177.87 62.33,177.8 62.33,177.49 62.39,177.42 62.51,177.42 62.58,177.49 62.58,177.73 62.64,177.79 62.76,177.79 62.82,177.73 62.82,177.49 62.88,177.42 63,177.42 63.06,177.49 63.06,177.73 63.12,177.79 63.25,177.79 63.31,177.73 63.31,177.49 63.37,177.42 63.49,177.42 63.55,177.49 63.55,177.73 63.61,177.79 63.73,177.79 63.79,177.73 63.79,177.49 63.86,177.42 63.98,177.42 64.04,177.49 64.04,177.73 64.1,177.79 64.22,177.79 64.28,177.73 64.28,177.49 64.34,177.42 64.47,177.42 64.53,177.49 64.53,177.73 64.59,177.79 64.71,177.79 64.77,177.73 64.77,177.49 64.83,177.42 65.12,177.42 65.67,176.87 65.67,176.67 65.76,176.59 65.94,176.59 66,176.65 66,176.9 66.09,176.99 66.22,176.99 66.31,176.9 66.31,176.65 66.37,176.59 66.63,176.59 69.5,173.71 69.5,172.71 69.73,172.48 69.73,171.73 69.76,171.7
LPDDR3_M0_D20_B: length 14.2
  L5 w0.06: 68.35,166.8 68.34,166.8 68.23,166.69 68.23,166.52 68.43,166.32 v8(68.71,166.32)
  L5 w0.076: v8(56.71,170.55) 57.91,169.35 59.43,169.35 60.09,168.69 64.04,168.69 65.19,167.54 67.74,167.54 68.18,167.09 68.23,167.09 68.35,166.97 68.35,166.8
LPDDR3_M0_D21_A: length 23.1
  L7 w0.06: v8(69.84,170.85) 69.88,170.89 69.88,171.75
  L7 w0.061: v8(57.75,177.08) 57.77,177.11 57.97,177.11 58.16,177.29 58.73,177.29 58.86,177.42 58.86,177.82 58.93,177.89 59.03,177.89 59.1,177.82 59.1,177.36 59.17,177.29 59.27,177.29 59.35,177.36 59.35,177.84 59.42,177.92 59.52,177.92 59.59,177.84 59.59,177.41 59.68,177.32 59.81,177.32 59.91,177.41 59.91,177.94 60.03,178.06 62.4,178.06 62.48,178.14 62.48,178.22 62.56,178.3 62.67,178.3 62.75,178.22 62.75,178.04 62.82,177.97 62.92,177.97 62.99,178.04 62.99,178.26 63.06,178.33 63.16,178.33 63.23,178.26 63.23,178.02 63.29,177.96 63.42,177.96 63.48,178.02 63.48,178.25 63.55,178.32 63.65,178.32 63.72,178.25 63.72,178.02 63.78,177.96 63.9,177.96 63.96,178.02 63.96,178.25 64.04,178.32 64.14,178.32 64.21,178.25 64.21,178.02 64.27,177.96 64.39,177.96 64.45,178.02 64.45,178.22 64.52,178.29 64.62,178.29 64.7,178.22 64.7,178.02 64.76,177.96 64.78,177.96 64.95,177.8 64.95,177.67 65.02,177.6 65.45,177.6 65.49,177.55 65.49,177.3 65.6,177.19 65.77,177.19 65.83,177.25 65.83,177.46 65.92,177.55 66.05,177.55 66.14,177.46 66.14,177.32 66.48,176.98 66.59,176.98 66.75,176.82 66.75,176.71 66.91,176.55 67.02,176.55 67.18,176.39 67.18,176.28 67.34,176.12 67.45,176.12 67.61,175.96 67.61,175.85 67.77,175.69 67.88,175.69 68.04,175.53 68.04,175.42 68.2,175.26 68.31,175.26 68.47,175.1 68.47,174.99 69.63,173.83 69.63,172.75 69.85,172.53 69.85,171.78 69.88,171.75
LPDDR3_M0_D21_B: length 16.5
  L5 w0.06: v8(67.29,166.04) 66.74,166.59
  L5 w0.076: 66.74,166.59 64.8,166.59 64.21,167.18 58.01,167.18 57.5,167.18 55.36,169.32 55.36,169.5 55.36,171.47 55.69,171.79 55.91,171.79 56.17,172.05 v8(56.2,172.05)
LPDDR3_M0_D22_A: length 22.1
  L7 w0.06: v8(70.12,171.13) 70,171.25 70,171.8
  L7 w0.061: v8(57.22,177.05) 57.41,177.05 57.71,177.36 58,177.36 58.06,177.41 58.31,177.41 58.69,177.79 58.69,178.61 58.76,178.69 58.87,178.69 58.94,178.61 58.94,178.13 59.01,178.06 59.11,178.06 59.18,178.13 59.18,178.64 59.25,178.71 59.35,178.71 59.42,178.64 59.42,178.16 59.5,178.09 59.6,178.09 59.67,178.16 59.67,178.64 59.74,178.72 59.84,178.72 59.91,178.64 59.91,178.33 59.98,178.26 60.08,178.26 60.16,178.33 60.16,178.53 60.24,178.61 60.35,178.61 60.43,178.53 60.43,178.33 60.53,178.24 62.25,178.24 62.51,178.5 62.99,178.5 62.99,178.5 63.23,178.5 63.24,178.5 64.66,178.5 64.7,178.46 64.7,178.46 64.87,178.29 65.12,178.04 65.12,177.84 65.19,177.77 65.56,177.77 65.56,177.77 66.07,177.77 68.73,175.11 68.73,174.99 68.89,174.84 69.01,174.84 69.16,174.68 69.16,174.56 69.32,174.41 69.44,174.41 69.77,174.08 69.77,172.78 69.97,172.58 69.97,171.83 70,171.8
LPDDR3_M0_D22_B: length 15.5
  L5 w0.06: 67.03,166.86 67.57,166.32 v8(67.58,166.32)
  L5 w0.076: 67.03,166.86 65.7,166.86 64.91,166.86 64.21,167.56 57.85,167.56 57.69,167.56 55.63,169.62 55.63,169.74 55.63,170.96 v8(56.22,171.54)
LPDDR3_M0_D23_A: length 23.7
  L7 w0.06: 69.61,171.68 69.61,171.18 v8(69.56,171.13)
  L7 w0.061: 69.61,171.68 69.61,172.43 69.36,172.68 69.36,173.6 66.55,176.41 65.62,176.41 65.5,176.53 65.5,176.8 65.04,177.25 60.34,177.25 60.11,177.02 58.61,177.02 58.47,176.88 57.59,176.88 57.45,176.74 57.16,176.74 57.04,176.63 57.04,176.61 57.03,176.59 57.03,176.38 56.94,176.29 56.67,176.29 56.51,176.14 56.51,175.69 56.38,175.57 55.77,175.57 55.64,175.69 55.64,175.93 55.77,176.05 56.26,176.05 56.32,176.11 56.32,176.24 56.26,176.3 55.51,176.3 55.44,176.37 55.44,176.73 55.58,176.86 55.82,176.86 55.95,176.99 55.95,177.35 56.06,177.47 56.23,177.47 56.35,177.35 56.35,177.19 56.47,177.06 v8(56.78,177.06)
LPDDR3_M0_D23_B: length 16.8
  L5 w0.06: v8(67.56,165.77) 67.28,165.77 66.67,166.38
  L5 w0.076: 66.67,166.38 64.82,166.38 64.2,166.99 58.09,166.99 58.09,166.99 57.62,166.99 57.42,166.99 55.23,169.19 55.23,169.26 55.23,169.44 55.23,169.55 55.23,169.55 55.23,170.03 55.23,171.54 v8(55.73,172.05)
LPDDR3_M0_D24_A: length 17.5
  L7 w0.06: v8(68.99,170.57) 68.91,170.65 68.91,171.01 68.83,171.09 68.83,172.36
  L7 w0.061: 68.83,172.36 68.37,172.82 68.37,173.16 66.96,174.56 66.96,174.64 66.15,175.46 59.02,175.46 58.89,175.33 57.68,175.33 57.51,175.15 57.51,175.06 57.31,174.86 57.21,174.86 57.01,174.66 57.01,174.56 56.73,174.28 56.65,174.28 56.52,174.15 56.52,173.27 v8(56.73,173.06)
LPDDR3_M0_D24_B: length 22.9
  L5 w0.06: v8(68.14,164.06) 65.8,164.06
  L5 w0.076: 65.8,164.06 65.31,164.55 64.27,164.55 63.95,164.87 55.48,164.87 55.31,164.86 50.73,169.44 50.73,169.65 50.73,171.38 51.14,171.79 51.45,171.79 v8(51.72,172.06)
LPDDR3_M0_D25_A: length 16
  L7 w0.06: v8(68.39,171.17) 68.46,171.24 68.46,171.9 68.46,171.9
  L7 w0.061: v8(56.73,172.56) 56.93,172.36 57.28,172.36 57.39,172.47 57.39,172.68 57.47,172.76 57.47,173.13 57.53,173.19 57.53,173.66 57.73,173.86 57.81,173.86 58,174.05 58,174.17 58.41,174.58 58.41,174.58 58.77,174.93 65.9,174.93 67.17,173.66 67.35,173.66 67.73,173.29 67.73,172.64 68.46,171.9
LPDDR3_M0_D25_B: length 20.8
  L5 w0.06: v8(68.71,165.19) 68.47,165.43 67.59,165.43 67.57,165.45 67.43,165.45 67.41,165.47 67.02,165.47 66.98,165.52
  L5 w0.076: 66.98,165.52 66.49,166 64.62,166 64.01,166.61 58.25,166.61 58.25,166.61 57.77,166.61 57.3,166.61 57.3,166.61 56.9,166.61 54.73,168.78 54.73,170.79 54.12,171.41 51.94,171.41 51.78,171.57 v8(51.73,171.57)
LPDDR3_M0_D26_A: length 16.8
  L7 w0.06: 68.71,172.21 68.71,172.21 v8(68.71,170.85)
  L7 w0.061: 68.71,172.21 68.17,172.75 68.17,173.19 66.08,175.28 59.02,175.28 58.94,175.2 58.7,175.2 58.31,174.82 57.67,174.82 57.51,174.65 57.51,174.59 57.25,174.33 57.19,174.33 56.99,174.13 56.99,172.76 v8(57.19,172.56)
LPDDR3_M0_D26_B: length 21
  L5 w0.06: v8(68.14,165.19) 68.07,165.12 67.73,165.12 67.52,165.33 67.38,165.33 67.36,165.35 66.96,165.35 66.92,165.39 66.9,165.4
  L5 w0.076: v8(51.68,171.06) 51.68,171.15 51.78,171.25 52.29,171.25 54.01,171.25 54.46,170.81 54.46,170.62 54.38,170.54 54.24,170.54 54.15,170.45 54.15,170.32 54.24,170.23 54.38,170.23 54.46,170.16 54.46,168.79 55.5,167.75 55.5,167.64 55.46,167.6 55.46,167.49 55.56,167.38 55.67,167.38 55.71,167.42 55.82,167.42 56.82,166.42 57.22,166.42 57.85,166.42 58.33,166.42 64.01,166.42 64.56,165.87 66.43,165.87 66.9,165.4
LPDDR3_M0_D27_A: length 14.6
  L7 w0.06: v8(67.58,170.85) 67.61,170.88 67.61,171.27 67.57,171.31 67.57,171.72
  L7 w0.061: 67.57,171.72 67.24,172.05 67.09,172.05 66.85,172.29 66.84,172.29 66.45,172.69 66.36,172.69 66.21,172.53 66.12,172.53 66.04,172.62 66.04,172.71 66.19,172.86 66.19,172.94 66.03,173.1 66.03,173.1 65.81,173.33 65.8,173.33 65.6,173.53 65.6,173.54 65.37,173.76 65.37,173.76 65.19,173.94 61.17,173.94 61.17,173.94 61.13,173.94 61.13,173.94 61.03,173.94 60.44,173.36 60.44,172.2 60.35,172.1 60.21,172.1 60.12,172.2 60.12,172.76 60.03,172.84 59.9,172.84 59.82,172.76 59.82,172.19 59.69,172.07 59.05,172.07 58.8,172.32 58.62,172.32 58.38,172.07 v8(58.23,172.07)
LPDDR3_M0_D27_B: length 22.4
  L5 w0.06: 66.43,164.87 v8(67.3,164.87)
  L5 w0.076: 66.43,164.87 66.04,165.27 64.5,165.27 64.09,165.68 58.63,165.68 58.16,165.68 56.91,165.68 56.91,165.68 56.51,165.68 55.94,166.26 54.99,166.26 52.83,168.42 52.83,169.13 53.11,169.41 53.18,169.41 53.63,169.86 53.63,170.58 53.51,170.71 53.19,170.71 53.06,170.58 53.06,169.9 52.99,169.83 52.83,169.83 52.76,169.9 52.76,170.28 52.68,170.36 52.53,170.36 52.45,170.28 52.45,170.02 52.36,169.93 52.24,169.93 52.15,170.02 52.15,170.28 51.88,170.55 v8(51.68,170.55)
LPDDR3_M0_D28_A: length 15.6
  L7 w0.06: 67.45,171.67 67.45,171.26 67.49,171.22 67.49,171.05 67.38,170.93 67.38,170.77 67.86,170.28 v8(68.14,170.28)
  L7 w0.061: v8(57.72,172.05) 57.69,172.08 57.51,172.08 57.41,171.99 57.41,171.86 57.51,171.77 58.06,171.77 58.17,171.87 60.38,171.87 60.62,172.12 60.62,173.28 61.1,173.77 64.18,173.77 64.36,173.58 64.44,173.58 64.65,173.79 64.75,173.79 64.82,173.72 64.82,173.62 64.62,173.41 64.62,173.32 65.4,172.54 65.83,172.54 66.2,172.17 66.8,172.17 67.04,171.93 67.19,171.93 67.45,171.67
LPDDR3_M0_D28_B: length 23.5
  L5 w0.06: v8(68.71,164.06) 68.43,164.06 68.22,163.85 65.81,163.85
  L5 w0.076: v8(51.22,172.06) 51.08,171.92 51.08,171.92 50.59,171.44 50.59,169.7 50.59,169.31 55.23,164.67 55.4,164.67 55.56,164.67 63.95,164.67 64.24,164.38 65.28,164.38 65.81,163.85
LPDDR3_M0_D29_A: length 15.8
  L7 w0.06: 68.34,171.8 68.34,171.41 68.12,171.18 68.12,171.11 67.86,170.85 v8(67.86,170.57)
  L7 w0.061: 68.34,171.8 67.35,172.79 66.97,172.79 66.77,172.99 66.77,173.7 65.72,174.75 59.98,174.75 59.93,174.81 59.32,174.81 58.85,174.34 58.7,174.34 58.51,174.15 58.51,174.11 58.03,173.63 58.03,173.12 57.53,172.63 57.53,172.39 v8(57.22,172.07)
LPDDR3_M0_D29_B: length 22.3
  L5 w0.06: v8(68.71,164.62) 68.37,164.29 65.76,164.29
  L5 w0.076: 65.76,164.29 65.36,164.69 64.32,164.69 63.95,165.06 55.39,165.06 55.34,165.11 55.34,165.11 51.41,169.03 51.41,169.03 50.87,169.58 50.87,171.22 v8(51.22,171.58)
LPDDR3_M0_D30_A: length 15.3
  L7 w0.06: 67.33,171.62 67.33,171.18 67.29,171.14 v8(67.29,171.13)
  L7 w0.061: 67.33,171.62 67.14,171.81 66.93,171.81 66.71,172.03 66.13,172.03 65.77,172.39 65.24,172.39 64.04,173.59 61.17,173.59 60.8,173.21 60.8,171.28 60.67,171.15 60.49,171.15 60.43,171.21 60.43,171.61 60.36,171.68 60.26,171.68 60.19,171.61 60.19,171 60.12,170.93 60.02,170.93 59.94,171 59.94,171.64 59.87,171.71 59.77,171.71 59.7,171.64 59.7,171.27 59.6,171.17 59.47,171.17 59.37,171.27 59.37,171.55 59.22,171.71 58.8,171.71 58.8,171.72 58.38,171.72 v8(58.23,171.57)
LPDDR3_M0_D30_B: length 22.1
  L5 w0.06: 66.43,164.42 68.34,164.42 68.51,164.59 68.51,164.82 v8(68.43,164.91)
  L5 w0.076: 66.43,164.42 66.2,164.65 66.1,164.65 65.91,164.46 65.78,164.46 65.65,164.59 65.65,164.87 65.52,165 65.03,165 64.95,164.92 64.95,164.9 64.88,164.82 64.73,164.82 64.65,164.9 64.65,164.92 64.57,165 64.38,165 64.08,165.3 58.79,165.3 58.32,165.3 56.76,165.3 56.75,165.3 55.98,165.3 55.98,165.3 55.41,165.3 51.41,169.3 51.4,169.3 51,169.7 51,170.98 51.09,171.07 v8(51.22,171.07)
LPDDR3_M0_D31_A: length 14.7
  L7 w0.06: 67.21,171.57 67.21,171.41 67.09,171.29 67.09,171.05 67.21,170.93 67.21,170.76 67.09,170.65 67.09,170.48 67.29,170.28 v8(67.58,170.28)
  L7 w0.061: v8(57.72,171.57) 57.97,171.32 58.9,171.32 59.18,171.03 59.39,171.03 59.69,170.73 60.54,170.73 60.97,171.16 60.97,173.14 61.25,173.42 63.91,173.42 65.14,172.19 65.78,172.19 66.07,171.91 66.65,171.91 66.7,171.86 66.87,171.69 67.09,171.69 67.21,171.57
LPDDR3_M0_D31_B: length 22.7
  L5 w0.06: 66.46,164.62 v8(67.58,164.62)
  L5 w0.076: 66.46,164.62 65.95,165.13 64.44,165.13 64.08,165.49 58.71,165.49 58.24,165.49 56.83,165.49 56.2,165.49 56.13,165.56 56.13,165.76 56.04,165.84 55.91,165.84 55.82,165.76 55.82,165.62 55.69,165.49 55.49,165.49 55.41,165.58 55.41,165.87 55.32,165.96 55.02,165.96 52.1,168.88 52.1,168.99 52.62,169.51 52.62,169.63 52.53,169.72 52.4,169.72 51.88,169.21 51.78,169.21 51.67,169.31 51.67,169.42 51.97,169.72 51.97,169.83 51.86,169.93 51.75,169.93 51.45,169.64 51.35,169.64 51.21,169.77 51.21,169.9 51.4,170.09 51.4,170.46 51.28,170.59 v8(51.21,170.59)
LPDDR3_M0_DM0_A: length 19.1
  L5 w0.06: v8(69.27,168.58) 69.47,168.78 69.47,169.23 69.33,169.38 69.33,169.57 69.4,169.63 69.4,169.64 69.5,169.74 69.54,169.79
  L5 w0.076: 69.54,169.79 69.54,170.39 69.28,170.65 69.28,172.58 65.55,176.31 59.65,176.31 58.42,175.08 57.56,175.08 57.34,175.3 56.98,175.3 v8(56.72,175.56)
LPDDR3_M0_DM0_B: length 16
  L7 w0.06: 65.91,167.65 66.53,167.65 66.66,167.52 66.66,167.24 v8(66.73,167.17)
  L7 w0.061: v8(54.27,171.57) 54.53,171.82 54.53,172.13 54.64,172.25 54.81,172.25 55.03,172.02 55.03,171.99 55.15,171.87 55.32,171.87 55.53,172.09 55.53,172.13 55.65,172.25 55.82,172.25 55.93,172.13 55.93,172.03 56.12,171.85 56.19,171.85 56.47,171.57 56.47,171.01 56.68,170.8 56.74,170.8 56.94,170.61 56.94,170.54 57.63,169.84 59.46,169.84 60.96,168.34 60.97,168.34 61.11,168.34 61.11,168.34 61.51,168.34 61.51,168.34 62.13,168.34 62.14,168.34 62.43,168.34 62.44,168.34 62.49,168.34 62.86,167.97 62.87,167.97 65.58,167.97 65.69,167.86 65.7,167.86 65.85,167.71 65.91,167.65
LPDDR3_M0_DM1_A: length 15.3
  L5 w0.06: v8(69.06,169.99) 69.06,170.31 68.89,170.48 68.89,171 66.89,173
  L5 w0.076: 66.89,173 66.89,173.48 64.84,175.52 59.47,175.52 58.55,174.6 57.23,174.6 v8(57.21,174.58)
LPDDR3_M0_DM1_B: length 28.6
  L7 w0.06: v8(66.45,164.57) 66.39,164.52 65.57,164.52
  L7 w0.061: 65.57,164.52 64.79,164.52 64.15,163.88 62.3,163.88 61.92,164.25 61.35,164.25 61.16,164.44 52.11,164.44 51.63,164.92 49.89,164.92 49.89,164.92 49.75,164.92 49.54,165.12 49.54,165.12 49.44,165.23 49.44,165.23 49.3,165.37 49.3,168.91 49.43,169.04 49.43,170.13 50.28,170.97 50.84,170.97 51.14,171.27 51.72,171.27 52.01,171.57 52.01,171.7 52.13,171.82 52.46,171.82 52.53,171.88 52.58,171.88 52.59,171.89 52.87,171.89 52.96,171.79 53.39,171.79 53.51,171.92 53.51,172.15 53.39,172.28 53.28,172.28 53.19,172.19 v8(53.19,172.06)
LPDDR3_M0_DM2_A: length 21.3
  L7 w0.06: 69.47,171.63 69.47,171.33 69.07,170.93 69.07,170.76 69.27,170.57 v8(69.27,170.28)
  L7 w0.061: 69.47,171.63 69.47,172.39 69.23,172.64 69.23,173.49 66.48,176.24 65.55,176.24 65.32,176.46 65.32,176.73 64.97,177.07 60.51,177.07 60.39,176.96 60.39,176.64 60.39,176.34 60.3,176.25 60.17,176.25 60.08,176.34 60.08,176.74 59.95,176.87 58.64,176.87 58.53,176.76 58.43,176.76 57.64,176.76 57.52,176.64 57.52,176.48 57.53,176.48 57.53,176.16 57.51,176.15 57.51,175.39 57.38,175.26 57.12,175.26 56.99,175.39 56.99,175.99 57.02,176.01 57.02,176.15 57.24,176.37 v8(57.24,176.54)
LPDDR3_M0_DM2_B: length 16.3
  L5 w0.06: v8(68.14,165.75) 67.86,165.75 66.89,166.73
  L5 w0.076: 66.89,166.73 66.89,166.73 64.86,166.73 64.21,167.37 57.93,167.37 57.93,167.37 57.62,167.37 55.5,169.49 55.5,169.61 55.5,169.61 55.5,169.91 55.5,171.31 v8(55.73,171.54)
LPDDR3_M0_DM3_A: length 15.8
  L7 w0.06: v8(68.43,170.57) 68.51,170.65 68.51,171 68.59,171.08 68.59,172.14 68.59,172.14
  L7 w0.061: v8(57.24,173.06) 57.24,173.21 57.41,173.38 57.41,174.02 57.73,174.34 57.84,174.34 58.19,174.7 58.36,174.7 58.75,175.08 58.99,175.08 59.01,175.11 66,175.11 67.26,173.85 67.34,173.85 67.98,173.2 67.98,172.74 68.59,172.14
LPDDR3_M0_DM3_B: length 21.6
  L5 w0.06: v8(68.71,165.75) 68.51,165.55 67.64,165.55 67.62,165.57 67.48,165.57 67.46,165.59 67.28,165.59 66.73,166.14
  L5 w0.076: 66.73,166.14 64.71,166.14 64.04,166.8 58.17,166.8 57.69,166.8 57.38,166.8 56.98,166.8 54.92,168.86 54.92,170.8 54.17,171.55 53.63,171.55 53.56,171.62 53.56,171.91 53.48,171.98 53.33,171.98 53.25,171.91 53.25,171.62 53.17,171.55 53.02,171.55 52.95,171.62 52.95,171.91 52.87,171.98 52.72,171.98 52.64,171.91 52.64,171.62 52.56,171.55 52.37,171.55 52.3,171.62 v8(52.21,171.62)
LPDDR3_M0_DQS0_N_A: length 18.3
  L5 w0.06: v8(68.99,169.43) 69.05,169.5 69.05,169.67 69.06,169.68 69.26,169.88
  L5 w0.066: 69.26,169.88 69.26,170.28 69.01,170.53 69.01,172.47 68.61,172.87 68.51,172.87 68.26,172.62 68.05,172.62 67.83,172.85 67.83,173.06 68.08,173.31 68.08,173.4 67.35,174.13 67.11,174.13 65.37,175.87 59.6,175.87 58.54,174.81 57.17,174.81 56.9,175.08 56.78,175.08 v8(56.78,175.08)
LPDDR3_M0_DQS0_N_B: length 15.7
  L7 w0.06: v8(66.45,166.89) 66.42,166.89 66.35,166.96 64.93,166.96 ; 55.57,170.07 55.55,170.09 55.55,171.26 55.41,171.39 55,171.39 54.9,171.49 54.9,171.97 54.82,172.05 v8(54.73,172.05)
  L7 w0.061: 64.93,166.96 64.74,167.15 63.08,167.15 62.52,167.15 62.15,167.52 62.11,167.52 59.5,167.52 58.78,168.25 58.39,168.25 57.95,167.81 57.75,167.81 57.48,168.07 57.48,168.94 57.21,169.22 56.83,169.22 56.55,169.5 56.13,169.5 56.07,169.56 55.57,170.07
LPDDR3_M0_DQS0_P_A: length 18.3
  L5 w0.06: v8(69.27,169.15) 69.2,169.23 69.2,169.62 69.4,169.82
  L5 w0.066: 69.4,169.82 69.4,170.34 69.15,170.59 69.15,172.53 68.66,173.01 68.45,173.01 68.2,172.76 68.11,172.76 67.97,172.91 67.97,173 68.22,173.25 68.22,173.46 67.41,174.27 67.17,174.27 65.43,176.01 59.54,176.01 58.48,174.95 57.44,174.95 57.32,175.06 v8(57.22,175.06)
LPDDR3_M0_DQS0_P_B: length 15.8
  L7 w0.06: 55.43,169.92 55.37,169.98 55.37,170.15 55.43,170.21 55.43,171.21 55.36,171.27 54.95,171.27 54.78,171.44 54.78,171.49 v8(54.7,171.57) ; v8(66.73,166.6) 66.69,166.64 66.39,166.64 66.23,166.8 64.81,166.8 64.79,166.82
  L7 w0.061: 64.79,166.82 64.65,166.95 63,166.95 62.44,166.95 62.07,167.32 62.02,167.32 59.42,167.32 58.7,168.05 58.47,168.05 58.03,167.61 57.67,167.61 57.28,167.99 57.28,168.86 57.12,169.02 56.74,169.02 56.46,169.3 56.05,169.3 55.93,169.42 55.68,169.67 55.43,169.92
LPDDR3_M0_DQS1_N_A: length 16.6
  L5 w0.066: v8(56.72,174.07) 56.92,173.87 57.16,173.87 57.41,173.62 57.41,173.45 57.61,173.25 57.75,173.25 57.89,173.12 57.89,172.95 58.09,172.75 59.07,172.75 60.01,173.68 60.23,173.68 60.67,174.13 63.52,174.13 64.16,173.49 64.16,173.39 64.02,173.26 64.02,173.05 64.24,172.82 64.45,172.82 64.59,172.96 64.69,172.96 64.83,172.82 64.83,172.73 64.69,172.59 64.69,172.38 64.91,172.15 65.12,172.15 65.26,172.29 65.35,172.29 65.62,172.02 65.62,171.55 65.83,171.34 66.11,171.34 66.27,171.5 66.45,171.5 66.7,171.25 66.7,171.07 66.5,170.87 66.5,170.66 66.73,170.43 66.94,170.43 67.18,170.67 67.27,170.67 67.86,170.09 v8(67.86,170)
LPDDR3_M0_DQS1_N_B: length 29.4
  L7 w0.06: v8(53.73,172.03) 53.87,172.03 53.94,171.95 53.94,171.5 53.82,171.38 53.72,171.38 53.64,171.31 53.64,171.31 53.57,171.24 52.64,171.24 52.52,171.12 52.52,170.45 52.34,170.26 52.15,170.26 52.15,170.26 52.06,170.26 51.56,169.76
  L7 w0.061: 51.56,169.76 50.37,169.76 50.29,169.67 50.29,169.55 50.37,169.47 51.24,169.47 51.48,169.22 51.48,167.8 51.23,167.54 51.16,167.47 51.16,167.44 51.16,167.44 51.16,167.27 51.16,167.27 51.16,167.1 50.67,166.62 50.23,166.62 50.14,166.52 50.14,165.86 50.24,165.76 50.59,165.76 50.69,165.86 50.69,166.19 50.93,166.43 51.27,166.43 51.51,166.19 51.51,165.9 51.65,165.76 51.98,165.76 52.23,165.52 53.17,165.52 53.4,165.28 53.59,165.28 53.82,165.52 54.18,165.52 54.41,165.28 54.6,165.28 54.83,165.52 55.19,165.52 55.42,165.28 55.61,165.28 55.84,165.52 56.2,165.52 56.43,165.28 56.62,165.28 56.86,165.52 57.21,165.52 57.44,165.28 57.63,165.28 57.87,165.52 58.67,165.52 61.27,165.52 61.29,165.5 61.7,165.1 62.27,165.1 62.27,165.09 62.64,164.73 64.08,164.73 64.44,165.09 64.61,165.09 65.76,165.09 v8(65.82,165.15)
LPDDR3_M0_DQS1_P_A: length 16.6
  L5 w0.06: v8(68.14,169.72) 68.07,169.78 68.07,169.88 68.07,169.91 68.06,169.92 68.06,170.08 68.05,170.09 68.05,170.1 67.97,170.18
  L5 w0.066: v8(57.21,174.07) 57.26,174.02 57.26,173.97 57.55,173.68 57.55,173.51 57.67,173.39 57.81,173.39 58.03,173.17 58.03,173.01 58.15,172.89 59.01,172.89 59.95,173.82 60.17,173.82 60.61,174.27 63.58,174.27 64.3,173.55 64.3,173.34 64.16,173.2 64.16,173.11 64.3,172.96 64.4,172.96 64.53,173.1 64.74,173.1 64.97,172.88 64.97,172.67 64.83,172.53 64.83,172.44 64.97,172.29 65.06,172.29 65.2,172.43 65.41,172.43 65.76,172.08 65.76,171.61 65.89,171.48 66.05,171.48 66.21,171.64 66.51,171.64 66.84,171.3 66.84,171.01 66.65,170.81 66.65,170.72 66.79,170.58 66.88,170.58 67.12,170.82 67.33,170.82 67.97,170.18
LPDDR3_M0_DQS1_P_B: length 29.4
  L7 w0.06: 51.78,170.15 51.89,170.26 52.01,170.38 52.1,170.38 52.1,170.38 52.29,170.38 52.4,170.5 52.4,171.17 52.59,171.36 53.52,171.36 53.59,171.43 53.59,171.43 53.71,171.54 v8(53.71,171.58)
  L7 w0.061: 51.78,170.15 51.59,169.96 50.29,169.96 50.09,169.76 50.09,169.47 50.29,169.27 51.15,169.27 51.28,169.14 51.28,167.88 51.03,167.63 51.03,167.63 50.96,167.55 50.96,167.35 50.96,167.19 50.59,166.82 50.15,166.82 49.94,166.61 49.94,165.78 50.15,165.56 50.67,165.56 50.89,165.78 50.89,166.11 51.01,166.23 51.18,166.23 51.31,166.11 51.31,165.82 51.56,165.56 51.9,165.56 52.14,165.32 53.08,165.32 53.32,165.08 53.67,165.08 53.91,165.32 54.09,165.32 54.33,165.08 54.68,165.08 54.92,165.32 55.1,165.32 55.34,165.08 55.69,165.08 55.93,165.32 56.11,165.32 56.35,165.08 56.7,165.08 56.94,165.32 57.13,165.32 57.36,165.08 57.71,165.08 57.95,165.32 58.59,165.32 61.19,165.32 61.21,165.3 61.61,164.89 62.18,164.89 62.55,164.52 64.16,164.52 64.53,164.89 66.03,164.89 v8(66.14,165.01)
LPDDR3_M0_DQS2_N_A: length 22.1
  L7 w0.06: 58.7,175.79 58.65,175.79 58.62,175.76 58.05,175.76 ; v8(69.03,171.17) 69.07,171.21 69.07,172.36 68.8,172.64 68.8,173.06 68.94,173.2 68.94,173.32 68.91,173.35
  L7 w0.061: 58.05,175.76 57.91,175.91 57.91,176.24 57.72,176.42 v8(57.72,176.56) ; 68.91,173.35 68.65,173.61 68.56,173.61 68.47,173.52 68.21,173.52 68.01,173.72 68.01,174.04 68.08,174.11 68.08,174.18 67.9,174.36 67.66,174.36 66.28,175.75 65.01,175.75 64.83,175.92 64.83,176.52 64.77,176.58 64.59,176.58 64.52,176.52 64.52,175.92 64.35,175.75 64,175.75 63.82,175.92 63.82,176.52 63.76,176.58 63.57,176.58 63.51,176.52 63.51,175.92 63.34,175.75 62.99,175.75 62.81,175.92 62.81,176.52 62.75,176.58 62.56,176.58 62.5,176.52 62.5,175.92 62.32,175.75 61.87,175.75 61.53,176.09 61.53,176.52 61.46,176.58 60.96,176.58 60.88,176.5 60.88,176 60.64,175.76 59.86,175.76 59.62,176 59.62,176.41 59.53,176.5 59.4,176.5 59.32,176.41 59.32,175.97 59.14,175.79 58.7,175.79
LPDDR3_M0_DQS2_N_B: length 16.2
  L5 w0.06: v8(67.86,166.6) 67.33,167.13
  L5 w0.066: v8(56.24,171.06) 55.9,170.72 55.9,170.05 56.18,169.77 56.39,169.77 56.51,169.89 56.6,169.89 56.74,169.75 56.74,169.65 56.63,169.54 56.63,169.32 57.9,168.05 58.31,168.05 58.46,168.2 58.46,168.69 58.53,168.76 58.72,168.76 58.79,168.69 58.79,168.2 58.94,168.05 64.1,168.05 65.02,167.13 65.59,167.13 65.59,167.13 67.33,167.13
LPDDR3_M0_DQS2_P_A: length 22.2
  L7 w0.06: 58.03,175.96 58.11,175.88 58.52,175.88 58.63,175.99 58.76,175.99 ; 69.05,173.49 69.1,173.45 69.1,173.14 68.96,173 68.96,172.7 69.27,172.39 v8(69.27,171.49)
  L7 w0.061: 69.05,173.49 68.73,173.81 68.56,173.81 68.48,173.81 68.38,173.72 68.3,173.72 68.21,173.81 68.21,173.96 68.28,174.03 68.28,174.26 67.98,174.56 67.74,174.56 66.36,175.95 65.09,175.95 65.03,176.01 65.03,176.61 64.85,176.78 64.5,176.78 64.32,176.61 64.32,176.01 64.26,175.95 64.08,175.95 64.02,176.01 64.02,176.61 63.84,176.78 63.49,176.78 63.31,176.61 63.31,176.01 63.25,175.95 63.07,175.95 63.01,176.01 63.01,176.61 62.83,176.78 62.48,176.78 62.3,176.61 62.3,176.01 62.24,175.95 61.95,175.95 61.73,176.17 61.73,176.6 61.54,176.78 60.88,176.78 60.68,176.59 60.68,176.09 60.56,175.96 59.95,175.96 59.82,176.09 59.82,176.49 59.61,176.7 59.32,176.7 59.11,176.49 59.11,176.05 59.05,175.99 58.76,175.99 ; 58.03,175.96 58.03,176.35 57.95,176.43 57.95,176.52 57.99,176.56 58.22,176.56 v8(58.22,176.56)
LPDDR3_M0_DQS2_P_B: length 16.1
  L5 w0.06: 67.39,167.27 67.86,166.81 ; 67.94,166.81 67.94,166.8 67.94,166.8 68.06,166.69 68.06,166.68 68.06,166.68 68.06,166.52 68.06,166.52 68.06,166.4 v8(68.14,166.32)
  L5 w0.066: 67.86,166.81 67.94,166.81 ; v8(56.22,170.58) 56.1,170.58 56.04,170.52 56.04,170.11 56.24,169.91 56.33,169.91 56.45,170.03 56.66,170.03 56.89,169.81 56.89,169.59 56.77,169.48 56.77,169.38 57.96,168.2 58.25,168.2 58.32,168.26 58.32,168.75 58.47,168.9 58.78,168.9 58.93,168.75 58.93,168.26 59,168.2 64.16,168.2 65.08,167.27 65.53,167.27 65.53,167.27 67.39,167.27
LPDDR3_M0_DQS3_N_A: length 15.7
  L7 w0.06: v8(67.86,171.13) 67.86,171.26 67.7,171.42 67.7,171.59 67.7,171.83 67.45,172.08 67.44,172.08 67.35,172.18 67.31,172.22
  L7 w0.061: v8(57.75,172.56) 57.91,172.56 58.11,172.36 58.33,172.36 58.48,172.51 58.81,172.51 58.96,172.37 59.33,172.37 59.6,172.64 59.6,172.94 59,173.54 59,173.67 59.09,173.75 59.21,173.75 59.68,173.29 59.97,173.29 60.2,173.52 60.2,173.77 59.91,174.05 59.91,174.16 60.02,174.26 60.14,174.26 60.4,174 60.65,174 60.89,174.23 61.29,174.23 65.45,174.23 66.33,173.36 66.33,172.98 66.89,172.41 66.9,172.41 67.05,172.26 67.22,172.26 67.27,172.26 67.31,172.22
LPDDR3_M0_DQS3_N_B: length 23
  L5 w0.06: v8(67.86,164.91) 67.77,164.91 67.47,165.21 67.33,165.21 67.31,165.23 66.6,165.23 66.35,165.49
  L5 w0.066: v8(52.2,171.05) 52.2,170.87 52.35,170.72 52.62,170.72 52.96,171.06 53.76,171.06 53.97,170.85 53.97,169.81 53.27,169.11 53.27,168.6 53.49,168.38 53.59,168.38 53.89,168.69 54.14,168.69 54.16,168.67 54.16,168.66 54.32,168.5 54.32,168.25 54.02,167.95 54.02,167.86 54.16,167.72 54.25,167.72 54.55,168.01 54.76,168.01 54.99,167.79 54.99,167.58 54.69,167.28 54.69,167.19 55.18,166.7 56.12,166.7 56.7,166.12 57.1,166.12 57.98,166.12 58.45,166.12 64.11,166.12 64.64,165.59 66.24,165.59 66.35,165.49
LPDDR3_M0_DQS3_P_A: length 15.7
  L7 w0.06: 67.96,171.39 67.86,171.49 67.86,171.52 67.86,171.89 67.51,172.25 ; 67.14,172.46 67.22,172.46
  L7 w0.061: v8(68.14,171.49) 68.05,171.39 67.96,171.39 ; 67.14,172.46 66.98,172.61 66.97,172.61 66.53,173.06 66.53,173.44 65.54,174.43 61.38,174.43 60.8,174.43 60.57,174.2 60.48,174.2 60.22,174.46 59.93,174.46 59.71,174.24 59.71,173.97 59.99,173.69 59.99,173.6 59.88,173.49 59.76,173.49 59.3,173.96 59,173.96 58.8,173.75 58.8,173.46 59.39,172.86 59.39,172.72 59.24,172.57 59.04,172.57 58.9,172.71 58.61,172.71 58.48,172.84 58.33,172.84 58.21,172.72 v8(58.21,172.56) ; 67.22,172.46 67.35,172.46 67.51,172.3 67.51,172.25 67.51,172.25
LPDDR3_M0_DQS3_P_B: length 23.1
  L5 w0.06: v8(68.14,164.62) 67.86,164.62 67.41,165.07 66.54,165.07 66.25,165.36
  L5 w0.066: 66.25,165.36 66.16,165.45 64.58,165.45 64.19,165.84 64.05,165.98 58.51,165.98 58.04,165.98 57.04,165.98 57.04,165.98 56.64,165.98 56.06,166.56 55.12,166.56 54.55,167.13 54.55,167.34 54.84,167.64 54.84,167.73 54.7,167.87 54.61,167.87 54.31,167.57 54.1,167.57 53.88,167.8 53.88,168.01 54.18,168.31 54.18,168.44 54.07,168.54 53.95,168.54 53.64,168.24 53.43,168.24 53.13,168.54 53.13,169.17 53.83,169.87 53.83,170.79 53.71,170.91 53.01,170.91 52.68,170.58 52.29,170.58 52.29,170.58 v8(52.2,170.58)
LPDDR3_M0_ODT_A: length 18.3
  L2 w0.061: v10(62.3,173.44) 62.14,173.27 61.65,173.27 60.3,174.62 59.81,174.62 59.75,174.56 59.75,174.15 59.69,174.09 59.57,174.09 59.51,174.15 59.51,174.56 59.45,174.62 59.32,174.62 59.26,174.56 59.26,174.15 59.2,174.09 59.08,174.09 59.02,174.15 59.02,174.56 58.96,174.62 58.84,174.62 58.78,174.56 58.78,174.15 58.71,174.09 58.59,174.09 58.53,174.15 58.53,174.56 58.47,174.62 58.35,174.62 58.29,174.56 58.29,174.15 58.23,174.09 58.1,174.09 58.04,174.15 58.04,174.56 57.98,174.62 57.86,174.62 57.8,174.56 57.8,174.15 57.74,174.09 57.62,174.09 57.56,174.15 57.56,174.56 57.49,174.62 56.8,174.62 v10(56.63,174.79)
  L3SGND w0.127: v10(62.3,173.44) 62.31,173.43 v11(62.31,172.97) ; v10(56.63,174.79) 56.35,174.79 v11(56.12,175.02)
  L6SGND w0.127: v11(56.12,175.02) 56.22,174.92 56.37,174.92 v8(56.72,174.56) ; v11(62.31,172.97) 62.59,172.97 62.65,173.03 62.68,173.03 62.78,173.13 v4(62.86,173.13)
  L7 w0.061: v4(62.86,173.13) 63.91,173.13 65.05,171.99 65.79,171.99 66.02,171.76 66.59,171.76 66.86,171.49 v8(67.01,171.49)
LPDDR3_M0_ODT_B: length 19.1
  L2 w0.061: v10(54.71,173.28) 54.71,173.09 55.93,171.88 55.93,171.88 56.9,170.91 59.28,170.91 59.94,170.25 61.61,170.25 62.02,170.66 62.32,170.66 62.38,170.72 62.38,170.87 62.45,170.94 62.56,170.94 62.63,170.87 62.63,170.72 62.69,170.66 62.81,170.66 62.87,170.72 62.87,170.89 62.94,170.96 63.04,170.96 63.11,170.89 63.11,170.72 63.18,170.66 63.46,170.66 63.6,170.8 63.6,170.92 63.66,170.98 63.88,170.98 63.94,171.04 63.94,171.16 63.88,171.22 63.66,171.22 63.6,171.28 v10(63.6,171.57)
  L3SGND w0.127: v10(63.6,171.57) 63.26,171.91 v11(63.26,172.11) ; v10(54.71,173.28) 54.58,173.28 54.25,172.95 v11(54.06,172.95)
  L6SGND w0.127: v5(54.22,172.07) 53.99,172.3 53.99,172.39 53.98,172.41 53.98,172.62 53.99,172.64 53.99,172.82 54.06,172.89 v11(54.06,172.95) ; v4(63.79,172.2) 63.35,172.2 v11(63.26,172.11)
  L7 w0.061: v4(63.79,172.2) 63.99,172.2 64.62,171.57 65.62,171.57 65.9,171.29 66.21,171.29 66.37,171.13 v8(66.73,171.13)
LPDDR3_M1_CA0: length 28.2
  L2 w0.061: v10(54.01,154.48) 56.02,154.48 56.34,154.16 56.66,154.16 56.87,154.38 61.33,154.38 61.45,154.49 v10(62.47,154.49)
  L3SGND w0.127: v10(54.01,154.48) R1409.1 53.96,154.88 54.04,154.96 v11(54.04,155.52) ; v10(62.47,154.49) 62.94,154.49 v11(62.96,154.47)
  L5 w0.06: v8(68.43,158.68) 68.14,158.68 67.94,158.88 67.44,158.88 66.76,158.2 66.76,157.84
  L5 w0.076: v11(62.96,154.47) 63.59,154.47 66.76,157.64 66.76,157.84 ; v8(50.97,155.38) 50.97,155.5 51.19,155.72 51.82,155.72 52.42,156.31 52.5,156.31 52.81,156.63 53.44,156.63 54.11,155.95 54.29,155.95 54.34,155.9 54.34,155.65 54.22,155.52 v11(54.04,155.52)
  L6SGND w0.127: v11(54.04,155.52) 53.91,155.39 v4(53.91,155.08)
  L7 w0.061: v8(52.47,150.88) 52.75,151.16 52.75,151.97 53.04,152.26 53.04,154.2 53.91,155.07 v4(53.91,155.08)
LPDDR3_M1_CA1: length 31.8
  L2 w0.061: v10(61.46,155.71) 61.25,155.71 60.47,156.49 55.36,156.49 55.3,156.43 55.3,156.35 55.23,156.28 55.13,156.28 55.05,156.35 55.05,156.43 54.99,156.49 54.87,156.49 54.81,156.43 54.81,156.31 54.74,156.24 54.64,156.24 54.57,156.31 54.57,156.43 54.51,156.49 54,156.49 53.68,156.17 v10(53.68,155.9) 53.07,155.29 53.07,154.07 52.87,153.87 v9(52.54,153.87)
  L3SGND w0.127: v10(53.68,155.9) 53.64,155.9 v11(53.33,155.59) ; v11(62.28,154.99) 61.92,155.35 61.92,155.41 61.7,155.63 61.67,155.63 61.61,155.68 61.49,155.68 v10(61.46,155.71)
  L5 w0.06: v8(68.14,158.96) 68.11,159 67.39,159 66.62,158.23 66.62,158.21
  L5 w0.076: 66.62,158.21 66.62,157.69 63.72,154.79 63.46,154.79 63.38,154.87 62.4,154.87 v11(62.28,154.99) ; v8(51.46,155.38) 51.46,155.53 51.41,155.58 51.25,155.58 51.18,155.51 51.18,155.22 51.3,155.09 51.63,155.09 51.76,155.22 51.76,155.46 52.48,156.18 52.59,156.18 52.91,156.49 53.38,156.49 53.78,156.1 53.78,155.72 53.65,155.59 v11(53.33,155.59)
  L6SGND w0.127: v11(53.33,155.59) 53.56,155.37 v4(53.56,155.18)
  L7 w0.061: v4(53.56,155.18) 53.17,155.18 52.27,154.28 52.27,151.58 v8(52.47,151.38)
LPDDR3_M1_CA2: length 28
  L2 w0.061: v9(52.54,154.38) 52.54,154.89 v10(52.56,154.91) 52.56,156.25 53.15,156.84 59.79,156.84 59.96,157.01 v10(61.09,157.01)
  L3SGND w0.127: v11(52.9,155.28) 52.56,154.94 v10(52.56,154.91) ; v11(61.54,156.89) 61.27,156.89 61.15,157.01 v10(61.09,157.01)
  L5 w0.06: v8(68.71,159.53) 68.56,159.38 68.06,159.38 68,159.45 66.35,159.45
  L5 w0.076: v8(51.97,155.38) 51.97,155.48 52.53,156.04 52.67,156.04 52.98,156.35 53.34,156.35 53.46,156.22 53.46,156.07 53.35,155.96 53.15,155.96 53.02,155.83 53.02,155.4 52.9,155.28 v11(52.9,155.28) 53.23,154.95 v4(53.25,154.95) ; 66.35,159.45 66.31,159.45 64.68,157.82 64.68,157.26 64.17,156.75 62.69,156.75 62.33,156.39 62.02,156.39 61.79,156.61 61.79,156.64 v11(61.54,156.89)
  L7 w0.061: v8(52.47,151.88) 52.83,152.24 52.83,154.53 v4(53.25,154.95)
LPDDR3_M1_CA3: length 33.6
  L2 w0.061: v10(61,155.19) 61.08,155.27 61.08,155.63 60.91,155.8 60.68,155.8 60.57,155.69 60.09,155.69 59.91,155.88 59.22,155.88 59.21,155.89 56.01,155.89 55.95,155.83 55.52,155.83 55.37,155.98 v10(54.13,155.98) 53.38,155.24 53.38,152.97 53.62,152.74 53.8,152.74 54.01,152.95 v9(54.22,152.95)
  L3SGND w0.127: v10(54.13,155.98) 54.2,155.98 v11(54.65,155.54) ; v11(62,154.5) 61.68,154.5 61.35,154.84 61.34,154.84 61.1,155.07 61.1,155.08 v10(61,155.19)
  L5 w0.06: 66.89,157.7 66.89,158.17 67.41,158.68 v8(67.86,158.68)
  L5 w0.076: v11(62,154.5) 62.41,154.09 63.4,154.09 66.89,157.58 66.89,157.7 ; v8(50.97,154.88) 50.9,154.88 50.69,155.09 50.69,155.41 51.14,155.86 51.77,155.86 52.36,156.45 52.44,156.45 52.76,156.77 53.5,156.77 54.17,156.09 54.35,156.09 54.65,155.79 v11(54.65,155.54)
  L6SGND w0.127: v11(54.65,155.54) 54.65,155.44 v4(54.32,155.11)
  L7 w0.061: v4(54.32,155.11) 54.32,154.68 54.06,154.42 54.06,154.18 53.67,153.79 53.67,151.79 53.45,151.58 53.39,151.58 53.2,151.39 53.2,151.11 v8(52.97,150.88)
LPDDR3_M1_CA4: length 28.6
  L2 w0.061: v10(62.28,155.46) 61.92,155.46 61.19,154.73 60.42,154.73 60,155.14 57.19,155.14 57.13,155.08 57.13,154.77 57.07,154.71 56.95,154.71 56.89,154.77 56.89,155.08 56.82,155.14 55.89,155.14 55.83,155.08 55.83,154.71 55.77,154.65 55.65,154.65 55.59,154.71 55.59,155.1 55.46,155.23 55.01,155.23 54.95,155.29 54.95,155.43 54.89,155.49 54.76,155.49 54.7,155.43 54.7,155.29 54.64,155.23 54.38,155.23 54.18,155.43 54.06,155.43 53.98,155.34 53.98,155.23 54.35,154.86 54.35,154.76 54.28,154.69 54.17,154.69 53.87,154.99 53.77,154.99 53.7,154.92 53.7,154.82 53.83,154.69 53.83,154.6 53.7,154.48 v10(53.7,154.18) 53.7,154.17 53.71,154.17 v9(53.71,152.95)
  L3SGND w0.127: v10(53.7,154.18) 53.69,154.17 53.45,154.17 53.44,154.18 53.27,154.18 v11(53.26,154.19) ; v11(62.89,155.45) 62.88,155.46 v10(62.28,155.46)
  L5 w0.06: 66.33,157.99 66.33,158.57 66.73,158.96 v8(67.01,158.96)
  L5 w0.076: v4(53.79,154.24) 53.73,154.18 53.27,154.18 v11(53.26,154.19) 53.26,154.04 53.13,153.91 52.78,153.91 52.69,154 52.69,154.28 52.56,154.4 51.32,154.4 51.32,154.41 51.3,154.41 51.18,154.53 51.18,154.75 51.31,154.88 v8(51.47,154.88) ; 66.33,157.99 63.79,155.45 v11(62.89,155.45)
  L7 w0.061: v8(52.97,151.38) 52.97,151.46 53.27,151.76 53.27,151.96 53.49,152.18 53.49,153.95 v4(53.79,154.24)
LPDDR3_M1_CA5: length 27.1
  L2 w0.061: v10(56.48,154.88) 56.48,154.71 56.63,154.55 57.25,154.55 57.31,154.61 57.31,154.85 57.37,154.91 57.49,154.91 57.55,154.85 57.55,154.61 57.62,154.55 57.74,154.55 57.8,154.61 57.8,154.84 57.87,154.91 57.97,154.91 58.04,154.84 58.04,154.61 58.1,154.55 58.23,154.55 58.29,154.61 58.29,154.9 58.36,154.97 58.46,154.97 58.53,154.9 58.53,154.61 58.59,154.55 58.71,154.55 58.77,154.61 58.77,154.9 58.85,154.97 58.95,154.97 59.02,154.9 59.02,154.61 59.08,154.55 59.2,154.55 59.26,154.61 59.26,154.9 59.33,154.97 59.44,154.97 59.51,154.9 59.51,154.61 59.57,154.55 59.69,154.55 59.75,154.61 59.75,154.88 59.82,154.95 59.92,154.95 59.99,154.88 59.99,154.61 60.05,154.55 61.26,154.55 61.5,154.8 61.87,154.8 61.93,154.86 61.93,155.14 62,155.21 62.1,155.21 62.17,155.14 62.17,154.86 62.27,154.77 62.4,154.77 62.49,154.86 62.49,155.2 62.61,155.33 62.78,155.33 62.9,155.2 62.9,155.03 62.81,154.94 v10(62.8,154.94)
  L3SGND w0.127: v11(63.59,155.11) 63.12,155.11 62.99,154.98 62.83,154.98 v10(62.8,154.94) ; v11(55.55,155.1) 56.26,155.1 v10(56.48,154.88)
  L5 w0.06: 66.53,158.48 v8(66.73,158.68)
  L5 w0.076: v8(51.47,153.38) 51.68,153.58 52.1,153.58 52.11,153.6 53.79,153.6 54.74,154.55 v4(54.78,154.55) ; 66.53,158.48 66.49,158.44 66.49,157.95 63.64,155.11 v11(63.59,155.11)
  L6SGND w0.127: v4(54.78,154.55) 54.8,154.55 55.35,155.1 v11(55.55,155.1)
  L7 w0.061: v8(54.46,151.37) 54.34,151.48 54.34,151.5 54.27,151.58 54.27,151.96 54.31,152 54.31,154.08 v4(54.78,154.55)
LPDDR3_M1_CA6: length 27.5
  L2 w0.061: v10(56.37,155.39) 56.5,155.27 56.61,155.27 56.73,155.4 56.73,155.49 56.8,155.56 56.91,155.56 56.98,155.49 56.98,155.4 57.04,155.34 57.16,155.34 57.22,155.4 57.22,155.49 57.29,155.56 57.39,155.56 57.46,155.49 57.46,155.4 57.52,155.34 57.65,155.34 57.71,155.4 57.71,155.5 57.77,155.56 57.89,155.56 57.95,155.5 57.95,155.4 58.01,155.34 58.13,155.34 58.2,155.4 58.2,155.49 58.26,155.56 58.37,155.56 58.44,155.49 58.44,155.4 58.5,155.34 58.62,155.34 58.68,155.4 58.68,155.48 58.75,155.55 58.86,155.55 58.93,155.48 58.93,155.4 58.99,155.34 59.25,155.34 59.41,155.5 59.52,155.5 59.68,155.34 60.07,155.34 60.5,154.9 61.12,154.9 61.74,155.53 61.74,155.84 61.58,156 61.58,156.18 61.65,156.24 61.97,156.24 62.08,156.13 62.08,155.87 62.21,155.74 62.41,155.74 v10(62.51,155.84)
  L3SGND w0.127: v10(62.51,155.84) 62.51,155.88 62.83,156.21 v11(62.83,156.21) ; v11(55.73,154.27) 56.14,154.27 56.25,154.38 v10(56.5,154.38) 56.73,154.38 56.81,154.46 56.81,154.95 v10(56.37,155.39)
  L5 w0.076: v11(55.73,154.27) 55.72,154.27 54.73,154.27 53.92,153.46 52.17,153.46 52.08,153.38 v8(51.97,153.38) ; v8(67.86,159.25) 66.31,159.25 65.44,158.38 65.44,158.17 65.55,158.06 65.55,157.94 65.43,157.81 65.3,157.81 65.14,157.97 65.04,157.97 64.93,157.86 64.93,157.76 65.1,157.59 65.1,157.48 64.15,156.54 63.6,156.54 63.47,156.41 63.47,156.15 63.34,156.02 63.02,156.02 v11(62.83,156.21)
  L6SGND w0.127: v11(55.73,154.27) 55.72,154.27 55.26,154.27 55.21,154.32 v4(55.16,154.32)
  L7 w0.061: v4(55.16,154.32) 55.07,154.23 54.74,154.23 54.53,154.03 54.53,151.94 v8(54.47,151.88)
LPDDR3_M1_CA7: length 27.9
  L2 w0.061: v10(63.94,155.66) 63.85,155.58 63.85,154.73 61.6,152.48 58.65,152.48 58.59,152.54 58.59,152.86 58.52,152.93 58.42,152.93 58.35,152.86 58.35,152.54 58.29,152.48 58.16,152.48 58.1,152.54 58.1,152.86 58.03,152.93 57.93,152.93 57.86,152.86 57.86,152.54 57.8,152.48 57.68,152.48 57.61,152.54 57.61,152.95 57.55,153.01 57.43,153.01 57.37,152.95 57.37,152.54 57.31,152.48 57.19,152.48 57.13,152.54 57.13,152.95 57.07,153.01 56.94,153.01 56.88,152.95 56.88,152.54 56.82,152.48 56.49,152.48 v10(56.37,152.6)
  L3SGND w0.127: v11(55.2,153.01) 55.2,153 v10(55.74,153) 55.97,153 v10(56.37,152.6) ; v11(63.8,156.12) 63.8,155.81 v10(63.94,155.66)
  L5 w0.06: v8(66.13,158.72) 66.07,158.72 65.93,158.57
  L5 w0.076: 65.93,158.57 65.92,158.56 65.92,158.11 64.07,156.26 63.94,156.26 v11(63.8,156.12) ; v8(50.97,152.88) 50.99,152.88 51.23,152.63 53.91,152.63 54.31,152.23 54.66,152.23 55.2,152.76 v11(55.2,153.01) 55.16,153.04 v4(55.16,153.48)
  L7 w0.061: v8(54.97,150.88) 54.85,150.76 54.29,150.76 54.19,150.86 54.19,151 54.29,151.09 54.57,151.09 54.74,151.26 54.74,153.21 55.01,153.48 v4(55.16,153.48)
LPDDR3_M1_CA8: length 28.7
  L2 w0.061: v10(54.77,153.74) 55.69,153.74 55.93,153.5 62.13,153.5 63.23,154.61 63.23,155.63 63.08,155.79 63.08,156.5 v10(62.8,156.79)
  L3SGND w0.127: v11(63.04,157.68) 63.04,157.62 62.74,157.32 62.74,156.84 v10(62.8,156.79) ; v10(54.72,152.95) 54.72,153.04 v11(54.35,153.41) 54.44,153.41 v10(54.77,153.74)
  L5 w0.076: v11(54.35,153.41) 54.27,153.32 52.9,153.32 52.82,153.25 52.82,153.09 52.74,153.01 52.59,153.01 52.52,153.09 52.52,153.25 52.44,153.32 52.25,153.32 52.09,153.17 51.25,153.17 51.16,153.08 51.16,152.96 51.25,152.88 v8(51.47,152.88)
  L6SGND w0.127: v11(54.35,153.41) 54.52,153.57 54.52,153.68 54.75,153.91 v4(54.75,153.94) ; v4(62.68,157.37) 62.68,157.37 62.95,157.63 62.99,157.63 v11(63.04,157.68)
  L7 w0.06: 66.93,159.16 67.58,159.81 ; 66.31,158.57 66.34,158.57 66.65,158.88 66.65,158.88
  L7 w0.061: 67.58,159.81 v8(67.58,160.1) ; 66.93,159.16 66.81,159.05 66.81,159.05 66.65,158.88 ; 66.31,158.57 66.27,158.57 66.21,158.52 66.04,158.52 65.96,158.6 65.5,158.6 64.22,157.32 62.73,157.32 v4(62.68,157.37) ; v4(54.75,153.94) 55.23,153.94 55.5,153.67 55.5,153.32 55.34,153.16 55.34,151.74 v8(54.97,151.38)
LPDDR3_M1_CA9: length 27.8
  L2 w0.061: v9(55.23,152.95) 55.23,152.61 v10(55.33,152.51) 55.91,152.51 56.7,153.3 59.67,153.3 59.73,153.24 59.73,152.74 59.8,152.67 59.91,152.67 59.98,152.74 59.98,153.24 60.04,153.3 60.16,153.3 60.22,153.24 60.22,152.74 60.29,152.67 60.39,152.67 60.46,152.74 60.46,153.24 60.53,153.3 62.18,153.3 63.35,154.48 63.35,155.76 63.31,155.8 v10(63.31,156.24)
  L3SGND w0.127: v10(55.33,152.51) 55.31,152.51 55.28,152.54 v11(54.53,152.54) ; v11(63.15,157.13) 63.15,156.49 63.23,156.4 63.23,156.32 v10(63.31,156.24)
  L5 w0.06: v8(67.29,159.81) CPU1.BE53 67.1,159.62 66.35,159.62
  L5 w0.076: v8(51.97,152.88) 53.08,152.88 53.15,152.95 53.15,153.08 53.23,153.15 53.38,153.15 53.46,153.08 53.46,152.88 53.55,152.79 53.67,152.79 53.76,152.88 53.76,153.08 53.84,153.15 53.99,153.15 54.07,153.08 54.07,152.95 54.14,152.88 54.4,152.88 54.53,152.75 v11(54.53,152.54) ; 66.35,159.62 66.29,159.62 64.43,157.76 63.78,157.76 v11(63.15,157.13)
  L6SGND w0.127: v11(54.53,152.54) 54.53,152.85 54.77,153.09 v4(54.77,153.57)
  L7 w0.061: v8(54.98,151.88) 55.18,152.08 55.18,153.18 55.38,153.37 55.38,153.57 55.25,153.7 54.9,153.7 v4(54.77,153.57)
LPDDR3_M1_CKE0_A: length 18.9
  L2 w0.061: v10(54.89,152.1) 63.29,152.1 64.28,153.08 64.28,156.21 64.27,156.21 v10(64.27,156.7)
  L3SGND w0.127: v11(53.78,152.32) 53.89,152.2 54.79,152.2 v10(54.89,152.1) ; v10(64.27,156.7) 64.27,157.1 64.37,157.2 v11(64.37,157.39)
  L6SGND w0.127: v11(64.37,157.39) 64.39,157.39 64.41,157.41 64.43,157.41 64.58,157.56 v4(64.78,157.56) ; v8(53.47,151.38) 53.47,151.46 53.78,151.77 v11(53.78,152.32)
  L7 w0.06: v8(66.45,158.4) 66.26,158.4 66.14,158.28 66.04,158.28 65.96,158.2
  L7 w0.061: v4(64.78,157.56) 65.24,157.56 65.89,158.2 65.96,158.2
LPDDR3_M1_CKE0_B: length 19.4
  L2 w0.061: v10(61.44,157.37) 61.37,157.3 60.69,157.3 60.63,157.36 60.63,157.72 60.56,157.79 60.45,157.79 60.38,157.72 60.38,157.36 60.32,157.3 60,157.3 59.72,157.02 53.15,157.02 v10(50.64,154.5)
  L3SGND w0.127: v11(61.91,157.43) 61.85,157.37 v10(61.44,157.37) ; v10(50.64,154.5) 50.64,154.69 v11(50.43,154.9)
  L6SGND w0.127: v11(50.43,154.9) 50.71,154.62 51.2,154.62 51.44,154.38 v8(51.47,154.38) ; v11(61.91,157.43) 62.13,157.21 v4(62.32,157.21)
  L7 w0.061: v4(62.32,157.21) 62.45,157.08 65.05,157.08 v8(65.8,157.83)
LPDDR3_M1_CKE1_A: length 20.4
  L2 w0.061: v10(63.73,156.58) 64.16,156.16 64.16,154.79 62.82,153.45 62.82,153.36 63.18,153 63.18,152.9 63.11,152.83 63.01,152.83 62.64,153.19 62.56,153.19 62.47,153.1 62.47,153.02 62.85,152.64 62.85,152.54 62.78,152.47 62.68,152.47 62.3,152.84 62.21,152.84 61.66,152.29 55.24,152.29 55.18,152.36 53.78,152.36 53.36,152.77 v10(53.15,152.77)
  L3SGND w0.127: v10(53.15,152.77) 53.15,152.32 v11(53.2,152.27) ; v11(63.73,157.07) 63.73,157.07 v10(63.73,156.58)
  L6SGND w0.127: v4(64.25,156.77) 63.94,157.07 v11(63.73,157.07) ; v11(53.2,152.27) 53.47,152 v8(53.47,151.88)
  L7 w0.061: v8(65.8,156.7) 65.59,156.92 65.13,156.92 64.98,156.77 v4(64.25,156.77)
LPDDR3_M1_CKE1_B: length 19.9
  L2 w0.061: v10(61.35,156.42) 61.92,156.42 62.01,156.51 62.01,156.64 61.92,156.73 59.93,156.73 59.86,156.67 53.81,156.67 53.74,156.6 53.74,156.4 53.62,156.28 53.53,156.28 53.28,156.53 53.2,156.53 53.11,156.44 53.11,156.36 53.43,156.04 53.43,155.95 53.34,155.87 53.26,155.87 52.94,156.18 52.85,156.18 52.77,156.1 52.77,156.01 53.08,155.69 53.08,155.61 52.82,155.34 v10(52.82,154.12)
  L3SGND w0.127: v10(61.35,156.42) 61.4,156.47 61.75,156.47 62.01,156.72 62.09,156.72 62.13,156.77 v11(62.17,156.77) ; v10(52.82,154.12) 52.37,154.12 v11(52.34,154.09)
  L6SGND w0.127: v4(62.84,156.76) 62.26,156.76 62.26,156.77 v11(62.17,156.77) ; v11(52.34,154.09) 52.26,154.09 v8(51.97,154.38)
  L7 w0.061: v4(62.84,156.76) 63.15,156.45 v8(66.13,156.45)
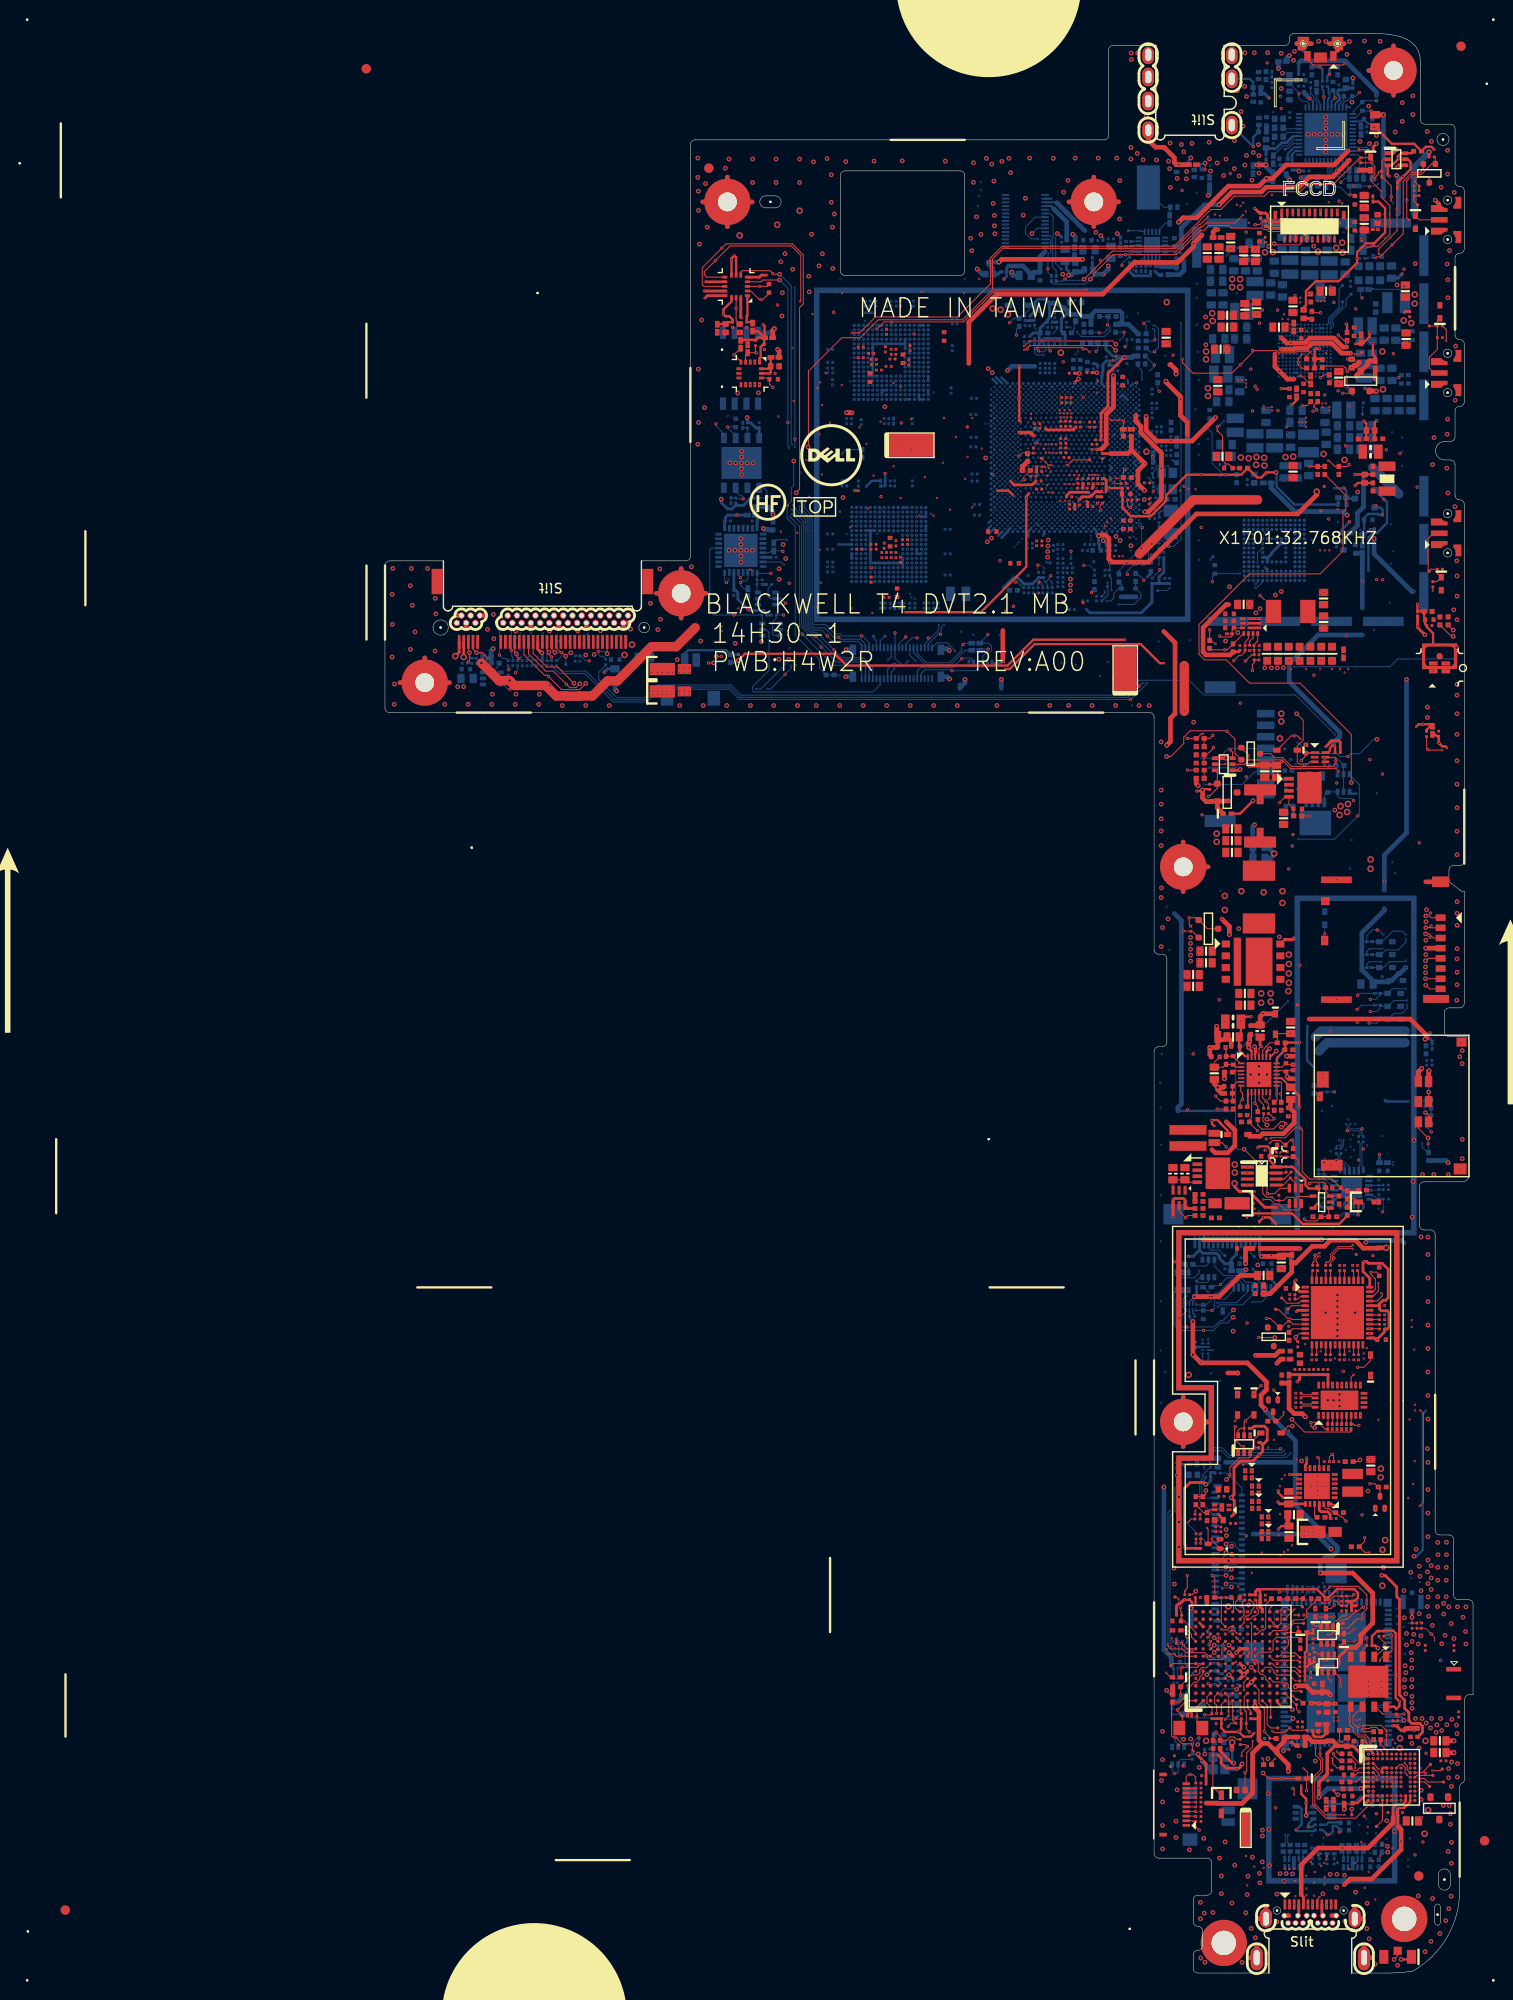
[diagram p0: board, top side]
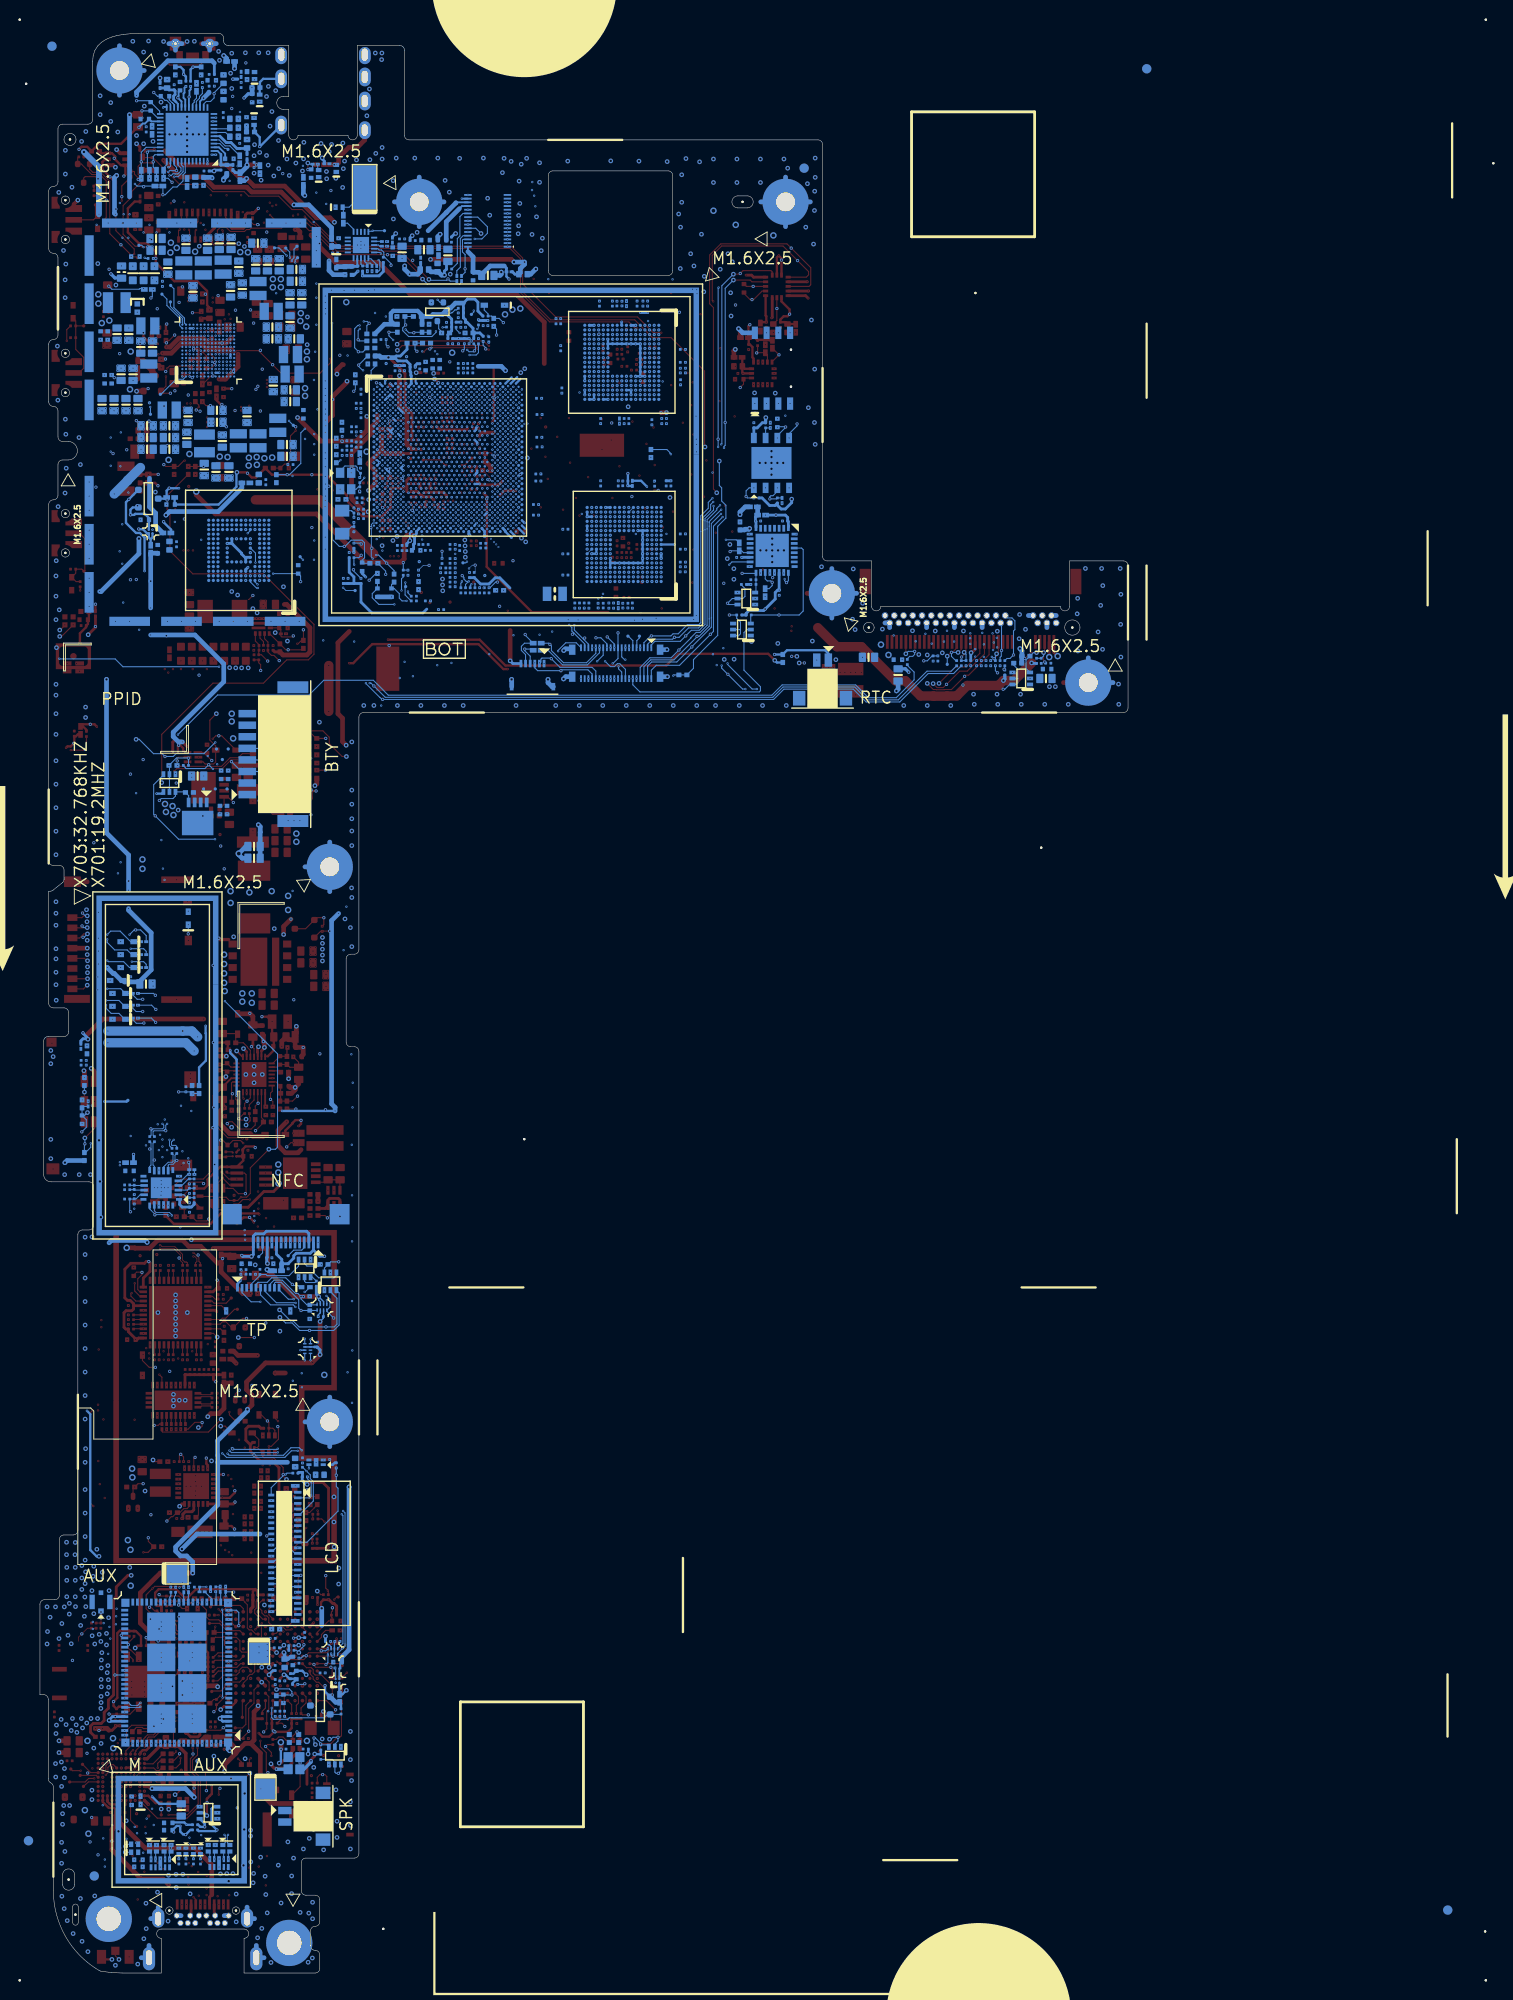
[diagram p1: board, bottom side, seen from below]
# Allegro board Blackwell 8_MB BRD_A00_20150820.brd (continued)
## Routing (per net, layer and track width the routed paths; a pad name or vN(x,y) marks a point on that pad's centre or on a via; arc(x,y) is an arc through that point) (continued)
LPDDR3_M1_CLK_DN_A: length 25.4
  L2 w0.061: v9(54.49,148.66) 54.32,148.84 54.32,151.02 v10(54.32,151.02)
  L3SGND w0.127: v11(54.68,150.96) 54.38,150.96 v10(54.32,151.02)
  L5 w0.066: v4(61.57,157.8) 61.57,157.62 61.45,157.49 61.27,157.49 61.14,157.37 61.14,157.21 60.93,157 59.88,157 59.73,157.15 59.73,157.35 59.64,157.45 59.5,157.45 59.4,157.35 59.4,157.15 59.25,157 58.94,157 58.79,157.15 58.79,157.33 58.69,157.43 58.55,157.43 58.46,157.33 58.46,157.15 58.31,157 57.86,157 56.1,155.24 56.1,154.73 56.22,154.61 56.22,153.36 55.42,152.56 55.42,152.47 55.91,151.98 55.91,151.72 55.73,151.54 55.47,151.54 54.98,152.03 54.89,152.03 54.68,151.82 53.8,151.82 53.76,151.78 53.76,151.51 53.89,151.39 v8(53.98,151.39) 53.98,151.26 54.22,151.02 54.25,151.02 54.31,150.96 v11(54.68,150.96)
  L7 w0.06: v8(67.01,159.53) 66.73,159.53 66.53,159.33 66.36,159.33 66.36,159.33
  L7 w0.061: v4(61.57,157.8) 61.57,158.02 61.96,158.4 63.37,158.4 63.52,158.25 63.84,158.25 64.09,158.25 65.32,159.48 66.21,159.48 66.36,159.33
LPDDR3_M1_CLK_DN_B: length 23.9
  L3SGND w0.127: v10(51.01,153.87) 50.95,153.87 50.43,153.35 v11(50.04,153.35)
  L5 w0.066: v11(50.04,153.35) 50.09,153.35 50.27,153.54 50.63,153.54 v8(50.97,153.88) 50.4,154.45 50.25,154.45 49.98,154.72 49.98,155.29 50.82,156.13 51.65,156.13 52.57,157.04 53.6,157.04 54.28,156.36 54.58,156.36 54.9,156.04 56.3,156.04 57.83,157.57 58,157.57 58.67,158.24 62.08,158.24 62.51,157.81 v4(62.56,157.81)
  L7 w0.06: v8(66.73,159.25) 66.65,159.16 66.36,159.16 66.27,159.08 66.24,159.05 66.07,159.05
  L7 w0.061: 66.07,159.05 65.92,159.2 65.75,159.2 64.46,157.9 62.65,157.9 v4(62.56,157.81)
LPDDR3_M1_CLK_DP_A: length 24.7
  L2 w0.061: v10(53.96,150.52) 54.11,150.37 54.11,148.84 v9(53.94,148.66)
  L3SGND w0.127: v10(53.96,150.52) v11(54.39,150.52)
  L5 w0.066: v11(54.39,150.52) 54.36,150.55 54.36,150.71 54.19,150.88 v8(53.96,150.88) 53.62,151.22 53.62,151.84 53.74,151.96 54.62,151.96 54.83,152.17 55.04,152.17 55.53,151.68 55.67,151.68 55.76,151.78 55.76,151.92 55.28,152.41 55.28,152.62 56.08,153.42 56.08,154.55 55.96,154.67 55.96,155.3 57.81,157.14 58.25,157.14 58.31,157.21 58.31,157.39 58.49,157.57 58.75,157.57 58.93,157.39 58.93,157.21 59,157.14 59.19,157.14 59.26,157.21 59.26,157.41 59.44,157.59 59.69,157.59 59.87,157.41 59.87,157.21 59.94,157.14 60.88,157.14 61,157.27 61,157.63 v4(61.18,157.8)
  L7 w0.061: v8(66.45,159.53) 66.32,159.66 65.82,159.66 65.82,159.65 65.21,159.65 64.01,158.45 63.93,158.45 63.92,158.45 63.6,158.45 63.45,158.61 61.88,158.61 61.18,157.91 v4(61.18,157.8)
LPDDR3_M1_CLK_DP_B: length 23.2
  L3SGND w0.127: v10(51.57,153.87) 51.08,153.37 v11(50.93,153.37)
  L5 w0.066: RAM2.H3 51.2,154.14 50.91,154.14 50.45,154.59 50.31,154.59 50.12,154.77 50.12,155.23 50.88,155.99 51.71,155.99 52.63,156.9 53.54,156.9 54.23,156.22 54.52,156.22 54.84,155.9 56.36,155.9 57.89,157.43 58.06,157.43 58.73,158.1 61.81,158.1 61.94,157.96 v4(61.94,157.95) ; RAM2.H3 51.29,153.88 50.93,153.51 v11(50.93,153.37) ; RAM2.H3 v8(51.48,153.88)
  L7 w0.061: v4(61.94,157.95) 61.94,157.69 62.03,157.6 62.16,157.6 62.25,157.69 62.25,157.95 62.41,158.1 64.37,158.1 65.63,159.36 66.04,159.36 66.15,159.25 v8(66.16,159.25)
LPDDR3_M1_CS0_B: length 21.9
  L2 w0.061: v10(60.8,155.51) 60.66,155.51 60.65,155.52 60.02,155.52 59.86,155.68 55.92,155.68 55.86,155.61 54.07,155.61 v10(53.6,155.14)
  L3SGND w0.127: v10(53.6,155.14) 53.6,154.68 v11(53.61,154.67) ; v11(61.51,155.24) 61.39,155.24 61.13,155.51 60.99,155.51 60.98,155.51 v10(60.8,155.51)
  L5 w0.076: v8(51.97,154.88) 51.79,154.88 51.69,154.78 51.69,154.64 51.79,154.54 52.16,154.54 52.29,154.67 52.29,155.04 52.4,155.14 52.55,155.14 52.65,155.04 52.65,154.65 52.78,154.53 53.48,154.53 53.61,154.65 v11(53.61,154.67) ; v11(61.51,155.24) 61.91,155.64 62.42,155.64 62.61,155.83 63.05,155.83 63.07,155.81 63.93,155.81 64.11,155.99 64.11,156.06 v8(66.13,158.08)
  L6SGND w0.127: v11(53.61,154.67) 53.98,154.67 v4(54.06,154.75)
  L7 w0.061: v8(52.95,151.89) 53.24,152.18 53.24,154 53.99,154.75 v4(54.06,154.75)
LPDDR3_M1_CS1_B: length 23.8
  L2 w0.061: v10(55.87,156.05) 60.13,156.05 v10(60.21,155.98)
  L3SGND w0.127: v11(55.2,155.52) 55.22,155.52 55.24,155.54 55.37,155.54 55.87,156.04 v10(55.87,156.05) ; v10(60.21,155.98) 60.68,156.45 v11(60.68,156.59)
  L5 w0.076: v8(50.97,154.38) 51.14,154.38 51.24,154.27 51.26,154.27 51.26,154.27 51.69,154.27 52.18,153.78 53.64,153.78 54.53,154.66 54.53,154.71 54.98,155.16 54.99,155.16 55.2,155.38 v11(55.2,155.52)
  L6SGND w0.127: v4(61.35,157.35) 61.35,157.3 60.68,156.62 v11(60.68,156.59) ; v11(55.2,155.52) 55.2,155.43 54.73,154.95 v4(54.68,154.95)
  L7 w0.06: 66.3,155.99 v8(66.45,156.13)
  L7 w0.061: 66.3,155.99 62.32,155.99 62.09,156.23 62.09,156.62 v4(61.35,157.35) ; v8(53.47,150.88) 53.62,151.03 53.71,151.12 53.71,151.45 54,151.74 54,153.94 54.21,154.15 54.21,154.36 54.68,154.83 v4(54.68,154.95)
LPDDR3_M1_D0_A: length 27.2
  L7 w0.061: v8(66.13,163.25) 66.05,163.33 65.34,163.33 65.19,163.17 62.01,163.17 61.92,163.26 61.82,163.36 57.86,163.36 52.19,163.36 52.16,163.33 50.77,163.33 49.09,161.65 49.09,160.79 49.15,160.73 49.35,160.73 49.41,160.67 49.41,160.55 49.35,160.49 49.15,160.49 49.09,160.43 49.09,157.81 50.36,156.54 50.47,156.54 50.6,156.67 50.7,156.67 50.77,156.6 50.77,156.5 50.59,156.32 50.59,156.23 50.81,156.01 51.05,156.01 51.11,156.07 51.11,156.2 51.18,156.27 51.29,156.27 51.36,156.2 51.36,156.07 51.42,156.01 51.93,156.01 52.03,156.11 52.03,156.26 v8(51.95,156.33)
LPDDR3_M1_D0_B: length 17.6
  L5 w0.06: 67.37,157.91 67.58,158.12 v8(67.86,158.12)
  L5 w0.076: v8(57.47,155.39) 57.46,155.39 57.33,155.51 57.33,155.67 57.5,155.84 58.7,155.84 58.78,155.91 58.78,156.09 58.9,156.21 59.2,156.21 59.22,156.2 59.3,156.2 59.41,156.09 59.41,155.83 59.42,155.83 59.57,155.68 59.68,155.68 60,156.01 60.13,156.01 60.22,155.92 60.22,155.8 59.89,155.47 59.89,155.36 60,155.25 60.11,155.25 60.53,155.67 60.66,155.68 60.74,155.59 60.74,155.45 60.32,155.04 60.32,154.93 61.73,153.52 63.41,153.52 66.16,156.27 66.27,156.27 66.42,156.11 66.53,156.11 66.64,156.22 66.64,156.33 66.48,156.48 66.48,156.59 67.37,157.48 67.37,157.91
LPDDR3_M1_D1_A: length 26.3
  L7 w0.06: 65.65,162.2 65.74,162.2 65.74,162.19 65.98,162.19 66.08,162.29 66.23,162.29 66.36,162.16 66.38,162.16 66.41,162.13 66.65,162.13 66.7,162.08 v8(66.73,162.08)
  L7 w0.061: 65.65,162.2 65.63,162.19 64.96,162.19 64.59,161.82 63.57,161.82 63.55,161.8 61.54,161.8 61.41,161.93 61.3,162.03 60.97,162.03 60.58,161.65 60.45,161.65 60.45,161.65 58,161.65 58,161.65 57.97,161.65 57.56,162.06 57.32,162.06 57.32,162.06 57.18,162.06 57.18,162.06 53.7,162.06 53.67,162.03 51.49,162.03 51.35,161.89 51.35,161.52 51.52,161.35 51.52,160.73 51.4,160.6 51.19,160.6 51.11,160.52 51.11,160.4 51.19,160.32 51.61,160.32 51.62,160.32 51.99,159.94 51.99,159.7 51.99,159.41 51.71,159.13 50.97,159.13 50.9,159.07 50.9,158.94 50.97,158.88 51.97,158.88 52.05,158.81 52.05,158.7 51.97,158.62 50.62,158.62 50.54,158.54 50.54,158.42 50.62,158.34 51.65,158.34 51.72,158.34 51.89,158.18 52.37,158.18 52.48,158.07 v8(52.48,157.87)
LPDDR3_M1_D1_B: length 15.3
  L5 w0.06: 68.2,157.32 68.2,157.6 68.35,157.76 68.35,158.04 v8(68.43,158.12)
  L5 w0.076: 68.2,157.32 67.98,157.11 67.74,157.11 67.53,156.9 67.53,156.71 67.79,156.44 67.79,156.32 67.7,156.23 67.58,156.23 67.4,156.41 67.26,156.41 67.15,156.31 67.15,155.58 64.35,152.78 61.43,152.78 58.85,155.35 v8(58.01,155.35)
LPDDR3_M1_D2_A: length 27.4
  L7 w0.06: v8(66.16,162.08) 66.15,162.08 66.15,162.07 66.05,162.07 65.7,162.07 65.7,162.07
  L7 w0.061: v8(52.51,157.42) 52.7,157.42 52.78,157.5 52.78,157.96 52.54,158.2 52.53,158.2 52.22,158.51 52.22,158.86 52.17,158.91 52.17,159.98 52.24,160.05 52.34,160.05 52.41,159.98 52.41,158.77 52.48,158.7 52.58,158.7 52.65,158.77 52.65,160 52.32,160.34 51.84,160.34 51.7,160.48 51.7,161.24 51.82,161.36 52.87,161.36 52.94,161.43 52.94,161.53 52.87,161.6 51.63,161.6 51.56,161.67 51.56,161.77 51.63,161.84 53.35,161.84 53.35,161.84 53.5,161.84 53.5,161.84 53.73,161.84 53.77,161.88 57.49,161.88 57.9,161.47 57.92,161.47 57.93,161.47 60.52,161.47 60.52,161.47 60.66,161.47 60.94,161.75 61.03,161.75 61.16,161.63 61.16,161.51 61.22,161.44 61.34,161.44 61.4,161.51 61.4,161.56 61.46,161.62 61.58,161.62 61.64,161.56 61.64,161.51 61.71,161.44 61.83,161.44 61.89,161.51 61.89,161.56 61.95,161.62 62.07,161.62 62.13,161.56 62.13,161.51 62.19,161.44 62.32,161.44 62.38,161.51 62.38,161.56 62.44,161.62 62.56,161.62 62.62,161.56 62.62,161.51 62.68,161.44 62.8,161.44 62.86,161.51 62.86,161.56 62.92,161.62 63.54,161.62 63.62,161.7 64.78,161.7 64.91,161.82 64.91,161.97 65.01,162.07 65.16,162.07 65.24,161.99 65.24,161.84 65.31,161.77 65.39,161.77 65.7,162.07
LPDDR3_M1_D2_B: length 16
  L5 w0.06: v8(67.29,158.12) 67.17,157.99 67.17,157.51
  L5 w0.076: v8(56.44,154.87) 56.44,154.98 57.85,156.39 58.05,156.39 58.12,156.31 58.12,156.09 58.2,156.02 58.35,156.02 58.43,156.09 58.43,156.31 58.5,156.39 60.05,156.39 60.42,156.01 60.77,156.01 60.93,155.85 60.93,154.75 61.97,153.71 63.41,153.71 67.17,157.47 67.17,157.51
LPDDR3_M1_D3_A: length 25.8
  L7 w0.06: 66.19,162.74 66.22,162.74 66.39,162.57 66.66,162.57 v8(66.73,162.64)
  L7 w0.061: v8(52.47,156.85) 52.27,156.85 52.06,157.05 51.83,157.05 51.7,157.18 51.7,157.45 51.58,157.58 50.61,157.58 50.55,157.64 50.55,157.82 50.46,157.91 50.34,157.91 50.25,157.82 50.25,157.56 50.16,157.47 50.03,157.47 49.94,157.56 49.94,158.32 49.95,158.32 49.95,158.78 50.37,159.21 50.37,159.68 49.98,160.08 49.98,160.49 50.45,160.96 50.45,162.26 50.99,162.81 52.38,162.81 52.41,162.84 56.85,162.84 61.6,162.84 61.73,162.7 61.86,162.58 62.37,162.58 62.44,162.65 63.47,162.65 63.51,162.69 64.08,162.69 64.27,162.5 64.45,162.5 64.64,162.69 65.36,162.69 65.41,162.74 66.19,162.74
LPDDR3_M1_D3_B: length 17.1
  L5 w0.06: v8(67.58,158.4) 67.29,158.4 67.03,158.13 67.03,157.57
  L5 w0.076: v8(56.94,154.87) 56.87,154.87 56.66,154.67 56.36,154.67 56.23,154.79 56.23,154.97 57.84,156.58 60.13,156.58 60.5,156.2 60.94,156.2 61.12,156.02 61.12,154.83 62.05,153.9 63.41,153.9 67.03,157.52 67.03,157.57
LPDDR3_M1_D4_A: length 27.3
  L7 w0.061: v8(52.46,156.31) 52.04,155.89 50.76,155.89 48.91,157.74 48.91,161.73 50.7,163.51 52.09,163.51 52.12,163.54 56.56,163.54 61.89,163.54 62.08,163.35 64.73,163.35 64.74,163.34 65.18,163.34 65.29,163.45 66.21,163.45 66.45,163.21 v8(66.73,163.21)
LPDDR3_M1_D4_B: length 16.9
  L5 w0.06: 67.88,155.84 68.07,156.03 68.07,156.8 68.61,157.34 68.61,157.64 68.61,157.64 68.51,157.74 68.51,157.92 68.63,158.03 68.63,158.2 68.51,158.31 68.34,158.31 67.86,157.83 v8(67.58,157.83)
  L5 w0.076: 67.88,155.84 64.43,152.4 61.27,152.4 58.95,154.71 57.67,154.71 57.54,154.84 v8(57.51,154.84)
LPDDR3_M1_D5_A: length 25.7
  L7 w0.06: v8(67.01,161.8) 66.94,161.86 66.66,161.86 66.53,162 66.36,162 66.25,161.88 66.08,161.88 66,161.95 65.75,161.95 65.66,161.86 65.66,161.86
  L7 w0.061: 65.66,161.86 65.37,161.58 63.69,161.58 63.59,161.48 63.29,161.48 63.08,161.27 61.09,161.27 57.82,161.27 57.38,161.71 53.85,161.71 53.81,161.67 53.44,161.67 52.95,161.18 51.98,161.18 51.89,161.09 51.89,160.96 51.95,160.91 53.02,160.91 53.11,160.82 53.11,160.69 53.02,160.6 52.56,160.6 52.49,160.53 52.49,160.43 52.56,160.36 53.21,160.36 53.33,160.23 53.33,158.71 53.26,158.64 53.16,158.64 53.09,158.71 53.09,160.07 53.02,160.14 52.92,160.14 52.85,160.07 52.85,158.58 52.73,158.46 52.73,158.29 52.85,158.16 53.18,158.16 53.29,158.05 53.29,157.91 53.18,157.8 53.04,157.8 v8(52.99,157.85)
LPDDR3_M1_D5_B: length 14.2
  L5 w0.06: v8(68.41,157.53) 68.41,157.35
  L5 w0.076: v8(57.96,154.92) 58.25,155.21 58.72,155.21 61.35,152.59 64.35,152.59 67.93,156.17 67.93,156.87 68.41,157.35
LPDDR3_M1_D6_A: length 26.3
  L7 w0.06: v8(66.45,161.8) 66.44,161.8 66.37,161.73 66.1,161.73 66.08,161.71 66.08,161.71 65.92,161.55 65.67,161.55
  L7 w0.061: v8(52.97,157.43) 52.97,157.55 53.07,157.65 53.54,157.65 53.68,157.51 53.68,157.3 53.89,157.09 54.12,157.09 54.22,157.2 54.22,157.5 54.11,157.62 53.88,157.62 53.79,157.7 53.79,157.82 53.86,157.88 54.11,157.88 54.2,157.97 54.2,158.07 54.14,158.14 53.62,158.14 53.52,158.24 53.52,158.43 53.58,158.49 53.75,158.49 53.82,158.56 53.82,158.65 53.82,158.65 53.82,158.67 53.75,158.74 53.58,158.74 53.52,158.8 53.52,158.97 53.58,159.03 53.76,159.03 53.84,159.11 53.84,159.21 53.76,159.28 53.58,159.28 53.52,159.34 53.52,159.46 53.58,159.52 53.79,159.52 53.85,159.59 53.85,159.7 53.79,159.77 53.58,159.77 53.52,159.83 53.52,159.95 53.58,160.01 53.77,160.01 53.84,160.08 53.84,160.18 53.77,160.25 53.58,160.25 53.29,160.55 53.29,160.86 53.94,161.52 54.18,161.52 54.19,161.51 54.99,161.51 54.99,161.52 55.39,161.52 55.45,161.46 55.45,161.02 55.53,160.95 55.63,160.95 55.7,161.02 55.7,161.46 55.76,161.52 55.88,161.52 55.94,161.46 55.94,160.99 56.01,160.92 56.11,160.92 56.19,160.99 56.19,161.46 56.26,161.53 56.41,161.53 56.49,161.45 56.49,161.04 56.57,160.96 57.27,160.96 57.33,161.02 57.33,161.27 57.4,161.34 57.5,161.34 57.57,161.27 57.57,161.02 57.63,160.96 57.75,160.96 57.81,161.02 57.81,161.03 57.88,161.09 58,161.09 58.06,161.03 58.06,161.02 58.12,160.96 58.24,160.96 58.3,161.02 58.3,161.03 58.36,161.09 58.49,161.09 58.55,161.03 58.55,161.02 58.61,160.96 58.73,160.96 58.79,161.02 58.79,161.03 58.85,161.09 58.97,161.09 59.03,161.03 59.03,161.02 59.09,160.96 59.22,160.96 59.28,161.02 59.28,161.03 59.34,161.09 59.46,161.09 59.52,161.03 59.52,161.02 59.58,160.96 59.7,160.96 59.77,161.02 59.77,161.03 59.83,161.09 59.95,161.09 60.01,161.03 60.01,161.02 60.07,160.96 60.7,160.96 60.84,161.09 61.01,161.09 63.32,161.09 63.4,161.02 63.58,161.02 64.02,161.46 65.58,161.46 65.67,161.55
LPDDR3_M1_D6_B: length 16.1
  L5 w0.06: 68.34,156.05 68.34,156.84 68.73,157.24 68.73,157.8 v8(68.71,157.83)
  L5 w0.076: 68.34,156.05 64.83,152.54 64.83,152.52 64.51,152.2 61.19,152.2 59.34,154.06 59.23,154.06 59.04,153.87 58.93,153.87 58.82,153.98 58.82,154.09 59.01,154.27 59.01,154.38 58.85,154.54 57.64,154.54 v8(57.47,154.37)
LPDDR3_M1_D7_A: length 28.5
  L7 w0.06: 67.22,161.73 67.22,161.72 67.09,161.6 66.93,161.6 66.82,161.71 66.64,161.71 66.53,161.59 66.24,161.59 v8(66.16,161.51) ; 67.22,161.87 67.22,161.87 67.09,162 67.09,162 66.81,162.28 66.81,162.44 66.93,162.56 66.93,162.73 66.81,162.84 ; 66.28,162.85 66.36,162.77 66.57,162.77 66.65,162.84 66.68,162.84
  L7 w0.061: 67.22,161.87 67.22,161.73 ; v8(52.94,156.81) 52.94,156.78 52.81,156.65 52.56,156.65 52.55,156.65 52.38,156.65 52.37,156.65 51.9,156.65 51.78,156.77 51.78,156.85 51.55,157.08 50.75,157.08 50.53,157.29 50.03,157.29 49.82,157.5 49.82,158.37 49.82,158.37 49.82,158.83 50.1,159.11 50.1,159.7 49.8,160 49.8,160.56 50.27,161.03 50.27,162.33 50.92,162.98 52.31,162.98 52.34,163.01 56.78,163.01 61.67,163.01 61.93,162.75 62.3,162.75 62.37,162.82 63.37,162.82 63.41,162.86 66.27,162.86 66.28,162.85 ; 66.68,162.84 66.81,162.84
LPDDR3_M1_D7_B: length 16.2
  L5 w0.06: v8(68.99,158.68) 68.99,158.41 68.79,158.21 68.79,158.03 68.91,157.92 68.91,157.67 68.85,157.62 68.85,157.12 68.53,156.8 68.53,155.97
  L5 w0.076: v8(57.98,154.34) 58.19,154.34 59.31,153.21 59.91,153.21 61.11,152.01 64.59,152.01 65.02,152.44 65.02,152.45 68.53,155.97
LPDDR3_M1_D8_A: length 15.2
  L7 w0.06: v8(66.73,161.51) 66.66,161.44 66.37,161.44 66.25,161.31 66,161.31 65.89,161.43 65.72,161.43 65.62,161.33
  L7 w0.061: 65.62,161.33 64.06,161.33 63.63,160.9 63.35,160.9 63.32,160.92 60.94,160.92 60.69,160.66 55.35,160.66 54.43,159.74 54.43,158.64 54.25,158.47 54.25,158.29 54.42,158.11 v8(54.42,157.87)
LPDDR3_M1_D8_B: length 24.3
  L5 w0.06: v8(69.56,158.12) 69.56,157.9 69.68,157.78 69.68,156.82 69.65,156.79
  L5 w0.076: 69.65,156.79 69.64,156.79 69.33,156.48 69.33,154.79 68.87,154.34 68.87,153.56 68.83,153.52 68.83,153.44 68.04,152.65 67.96,152.65 67.83,152.52 67.83,152.52 67.4,152.08 67.27,151.96 67.12,151.8 66.53,151.22 66.53,151.22 66.18,150.86 65.42,150.86 65.35,150.79 65.35,150.47 65.27,150.4 65.12,150.4 65.04,150.47 65.04,150.79 64.97,150.86 64.81,150.86 64.74,150.79 64.74,150.47 64.66,150.4 64.51,150.4 64.43,150.47 64.43,150.79 64.36,150.86 64.2,150.86 64.13,150.79 64.13,150.47 64.05,150.4 63.9,150.4 63.82,150.47 63.82,150.79 63.75,150.86 63.59,150.86 63.52,150.79 63.52,150.47 63.44,150.4 63.29,150.4 63.21,150.47 63.21,150.79 63.14,150.86 62.98,150.86 62.91,150.79 62.91,150.47 62.83,150.4 62.68,150.4 62.6,150.47 62.6,150.79 62.53,150.86 59.99,150.86 59.99,150.86 59.82,150.86 59.47,151.21 59.37,151.21 59.18,151.03 59.07,151.03 58.96,151.14 58.96,151.24 59.15,151.43 59.15,151.54 58.86,151.83 58.86,152.02 58.86,152.52 58.66,152.72 58.56,152.72 58.51,152.67 58.4,152.67 58.29,152.78 58.29,152.88 58.34,152.93 58.34,153.04 58.07,153.31 57.43,153.31 57.28,153.16 57.27,153.16 56.99,152.88 v8(56.97,152.88)
LPDDR3_M1_D9_A: length 14.3
  L7 w0.06: 65.65,161.16 65.71,161.23 v8(65.8,161.23)
  L7 w0.061: v8(54.47,157.38) 54.63,157.53 54.63,158.06 54.69,158.12 54.69,158.6 54.6,158.68 54.6,159.52 54.6,159.67 55.43,160.49 60.76,160.49 61.01,160.74 63.65,160.74 64.07,161.16 65.65,161.16
LPDDR3_M1_D9_B: length 26.6
  L5 w0.06: v8(69.84,158.96) 70.14,158.96 70.77,158.33 70.77,158.31 70.81,158.28 70.81,158.17 70.82,158.16 70.82,156.38 70.81,156.37 70.81,155.32 70.7,155.21 70.7,153.45 70.63,153.38
  L5 w0.076: 70.63,153.38 70.59,153.38 69.41,152.2 66.97,149.77 66.97,149.77 66.72,149.52 66.27,149.06 57.36,149.06 56.14,150.28 56.14,152.34 56.39,152.6 57.1,152.6 57.25,152.75 57.35,152.75 v8(57.47,152.87)
LPDDR3_M1_D10_A: length 16
  L7 w0.06: 64.68,160.9 66.05,160.9 v8(66.13,160.98)
  L7 w0.061: v8(54.95,157.87) 54.95,159.52 55.57,160.14 55.75,160.14 55.84,160.05 56.05,160.05 56.14,160.14 56.64,160.14 56.72,160.06 56.72,159.88 56.78,159.82 56.91,159.82 56.97,159.88 56.97,160.08 57.03,160.14 57.15,160.14 57.21,160.08 57.21,159.88 57.27,159.82 57.39,159.82 57.45,159.88 57.45,160.08 57.51,160.14 57.64,160.14 57.7,160.08 57.7,159.88 57.76,159.82 57.88,159.82 57.94,159.88 57.94,160.08 58,160.14 58.12,160.14 58.19,160.08 58.19,159.88 58.25,159.82 58.37,159.82 58.43,159.88 58.43,160.08 58.49,160.14 60.9,160.14 61.16,160.39 64.15,160.39 64.19,160.43 64.19,160.54 64.05,160.68 64.05,160.8 64.13,160.88 64.25,160.88 64.41,160.73 64.51,160.73 64.68,160.9
LPDDR3_M1_D10_B: length 23.8
  L5 w0.06: v8(69.84,158.4) 69.8,158.36 69.8,156.76 69.48,156.43 69.47,156.43
  L5 w0.076: v8(57.98,152.87) 57.98,152.69 58.17,152.5 58.62,152.5 58.72,152.41 58.72,150.91 58.9,150.72 58.9,150.37 59.07,150.2 59.21,150.2 59.22,150.2 59.4,150.2 59.48,150.28 59.48,150.61 59.55,150.67 59.72,150.67 59.79,150.61 59.79,150.28 59.86,150.2 60.01,150.2 60.09,150.28 60.09,150.6 60.17,150.67 60.32,150.67 60.39,150.6 60.39,150.28 60.47,150.2 60.62,150.2 60.7,150.28 60.7,150.6 60.78,150.67 60.93,150.67 61,150.6 61,150.28 61.08,150.2 61.23,150.2 61.31,150.28 61.31,150.6 61.39,150.67 61.54,150.67 61.61,150.6 61.61,150.28 61.69,150.2 61.84,150.2 61.92,150.28 61.92,150.6 62,150.67 62.15,150.67 62.22,150.6 62.22,150.28 62.3,150.2 65.79,150.2 67,151.42 67,151.42 67.31,151.72 67.31,151.73 67.33,151.75 67.44,151.86 67.53,151.95 68.02,152.44 68.02,152.44 69.01,153.43 69.01,154.28 69.47,154.74 69.47,156.43
LPDDR3_M1_D11_A: length 15.3
  L7 w0.06: v8(67.01,161.23) 66.73,161.23 66.53,161.03 66.36,161.03 66.21,161.18 66.04,161.18 65.88,161.02 64.1,161.02
  L7 w0.061: v8(54.95,157.41) 54.75,157.61 54.75,157.98 54.81,158.03 54.81,158.65 54.78,158.68 54.78,159.59 55.5,160.31 60.83,160.31 61.09,160.57 63.64,160.57 64.1,161.02
LPDDR3_M1_D11_B: length 25
  L5 w0.06: v8(70.12,158.12) 70.2,158.19 70.44,158.19 70.57,158.06 70.57,157.36 70.53,157.32 70.44,157.32 70.37,157.24 70.37,157.13 70.44,157.06 70.52,157.06 70.58,157 70.58,156.88 70.52,156.82 70.44,156.82 70.37,156.75 70.37,156.65 70.44,156.58 70.49,156.58 70.55,156.52 70.55,156.29 70.49,156.23 70.14,156.23 70.07,156.16 70.07,156.06 70.14,155.99 70.49,155.99 70.55,155.93 70.55,155.53 70.4,155.37 70.4,155.19 70.39,155.18
  L5 w0.076: 70.39,155.18 70.39,153.77 70.08,153.46 70.08,153.42 69.03,152.36 66.81,150.15 66.81,150.15 66.34,149.68 66.11,149.44 57.51,149.44 56.88,150.07 56.81,150.07 56.63,150.25 56.63,150.4 56.71,150.47 56.82,150.47 56.95,150.6 56.95,151.46 56.72,151.7 56.72,151.95 56.57,152.1 56.35,152.1 56.3,152.14 56.3,152.31 56.38,152.39 v8(56.48,152.39)
LPDDR3_M1_D12_A: length 15.6
  L7 w0.061: v8(54.97,156.84) 55.15,156.84 55.5,157.19 55.57,157.19 55.74,157.36 55.74,157.46 55.89,157.61 55.98,157.61 56.25,157.88 56.25,158.47 56.51,158.73 56.62,158.73 56.69,158.66 56.69,158.49 56.79,158.39 56.93,158.39 57.03,158.49 57.03,158.65 57.1,158.73 58.18,158.73 58.21,158.7 58.64,158.7 58.7,158.64 58.82,158.64 58.88,158.7 58.88,158.98 58.95,159.05 59.05,159.05 59.12,158.98 59.12,158.7 59.19,158.64 59.31,158.64 59.37,158.7 59.37,158.95 59.43,159.01 59.55,159.01 59.61,158.95 59.61,158.7 59.67,158.64 59.79,158.64 59.86,158.7 59.86,158.93 59.93,159 60.03,159 60.1,158.93 60.1,158.7 60.16,158.64 60.28,158.64 60.34,158.7 60.34,158.94 60.41,159.01 60.52,159.01 60.59,158.94 60.59,158.7 60.65,158.64 60.77,158.64 60.83,158.7 60.83,158.84 60.89,158.9 61.26,158.9 61.63,159.26 64.27,159.26 64.38,159.37 64.38,159.37 65.1,160.1 v8(65.8,160.1)
LPDDR3_M1_D12_B: length 24.8
  L5 w0.06: v8(70.12,157.55) 70.12,156.65 69.8,156.33 69.8,154.58
  L5 w0.076: v8(56.96,152.36) 57.09,152.36 57.32,152.6 57.56,152.6 57.71,152.44 57.71,152.02 57.64,151.94 57.16,151.94 57.07,151.85 57.07,151.73 57.16,151.64 57.64,151.64 57.71,151.56 57.71,151.41 57.64,151.33 57.34,151.33 57.26,151.26 57.26,150.45 57.39,150.32 57.58,150.32 57.65,150.4 57.65,150.87 57.74,150.96 57.87,150.96 57.96,150.87 57.96,150.4 58.03,150.32 58.19,150.32 58.26,150.4 58.26,150.66 58.34,150.74 58.5,150.74 58.63,150.61 58.63,149.94 58.74,149.82 65.95,149.82 65.96,149.84 66.65,150.53 66.66,150.53 68.65,152.52 69.05,152.93 69.13,152.93 69.13,152.93 69.2,152.93 69.8,153.53 69.8,154.58
LPDDR3_M1_D13_A: length 14.1
  L7 w0.06: v8(66.73,159.81) 66.69,159.78 65.32,159.78
  L7 w0.061: v8(54.98,156.38) 55.18,156.18 56.1,156.18 56.22,156.3 56.22,156.91 56.43,157.12 57.04,157.12 57.2,157.28 57.2,157.91 57.38,158.09 57.88,158.09 57.89,158.07 58,158.07 58.19,158.26 61.12,158.26 61.77,158.91 64.29,158.91 65.15,159.77 65.3,159.77 65.3,159.78 65.32,159.78
LPDDR3_M1_D13_B: length 25.1
  L5 w0.06: 69.94,156.27 70.24,156.57 70.24,157.39 70.32,157.47 70.32,157.81 v8(70.37,157.86)
  L5 w0.076: 69.94,156.27 69.94,155.9 70.02,155.82 70.32,155.82 70.41,155.74 70.41,155.61 70.32,155.52 70.02,155.52 69.94,155.44 69.94,155.17 70.02,155.1 70.17,155.1 70.25,155.02 70.25,154.87 70.17,154.79 70.02,154.79 69.94,154.72 69.94,154.56 70.02,154.49 70.17,154.49 70.25,154.41 70.25,154.26 70.17,154.18 70.02,154.18 69.94,154.11 69.94,153.47 69.26,152.79 69.18,152.79 68.84,152.44 68.84,152.44 66.73,150.34 66.73,150.34 66.15,149.76 66.15,149.76 66.03,149.63 58.64,149.63 58.49,149.78 58.49,150.11 58.42,150.18 58.26,150.18 58.19,150.11 58.19,149.74 58.1,149.65 57.97,149.65 57.88,149.74 57.88,150.11 57.81,150.18 57.66,150.18 57.58,150.11 57.58,149.91 57.5,149.84 57.31,149.84 57.09,150.06 57.09,151.52 56.87,151.73 56.87,152.03 57,152.15 57.42,152.15 57.47,152.2 v8(57.47,152.39)
LPDDR3_M1_D14_A: length 14.8
  L7 w0.061: v8(66.13,160.34) 66.05,160.42 65.08,160.42 64.28,159.61 64.09,159.61 64.03,159.67 64.03,159.82 63.97,159.88 63.85,159.88 63.79,159.82 63.79,159.67 63.72,159.61 61.48,159.61 61.23,159.36 59.22,159.36 59.17,159.3 58.76,159.3 58.43,158.97 56.69,158.97 56.31,159.35 56.21,159.35 56.14,159.28 56.14,159.18 56.32,159 56.32,158.91 56.24,158.83 56.15,158.83 55.76,159.21 55.66,159.21 55.59,159.14 55.59,159.04 55.98,158.65 55.98,158.57 55.89,158.48 55.8,158.48 55.63,158.65 55.53,158.65 55.46,158.58 55.46,158.48 55.63,158.31 55.63,158.22 55.48,158.07 55.48,157.99 55.48,157.99 v8(55.48,157.87)
LPDDR3_M1_D14_B: length 24
  L5 w0.06: v8(70.12,158.68) 70.12,158.4 69.92,158.2 69.92,156.7 69.62,156.39 69.62,154.66
  L5 w0.076: v8(57.95,152.39) 57.97,152.37 58.48,152.37 58.58,152.26 58.58,152.07 58.51,152 57.89,152 57.8,151.91 57.8,151.78 57.89,151.69 58.51,151.69 58.58,151.62 58.58,151.46 58.51,151.39 58.01,151.39 57.92,151.3 57.92,151.17 58.01,151.08 58.51,151.08 58.58,151.01 58.58,150.85 58.77,150.67 58.77,150.31 59.06,150.01 65.87,150.01 66.57,150.72 66.58,150.72 68.46,152.6 68.46,152.6 68.65,152.79 68.92,153.06 69.07,153.06 69.07,153.06 69.14,153.06 69.24,153.16 69.24,153.44 69.33,153.53 69.59,153.53 69.67,153.61 69.67,153.77 69.59,153.85 69.22,153.85 69.15,153.92 69.15,154.08 69.22,154.15 69.54,154.15 69.62,154.23 69.62,154.66
LPDDR3_M1_D15_A: length 13.6
  L7 w0.06: 66.93,160.46 66.93,160.46 66.81,160.58 66.65,160.58 66.25,160.18 ; 67.01,160.38 v8(67.01,160.1)
  L7 w0.061: v8(55.49,157.39) 55.49,157.5 55.74,157.76 55.74,158.13 56.46,158.85 58.48,158.85 58.81,159.18 61.3,159.18 61.56,159.44 64.27,159.44 64.33,159.49 65.13,160.3 65.89,160.3 66.04,160.14 66.21,160.14 66.25,160.18 ; 66.93,160.46 66.93,160.46 67.01,160.38
LPDDR3_M1_D15_B: length 24.7
  L5 w0.06: v8(70.41,158.4) 70.7,158.11 70.7,156.43 70.69,156.42 70.69,155.49 70.56,155.36 70.56,155.28
  L5 w0.076: 70.56,155.28 70.56,153.63 69.22,152.28 69.22,152.28 66.89,149.96 66.89,149.96 66.53,149.6 66.53,149.6 66.19,149.25 57.43,149.25 56.29,150.4 56.29,150.55 56.35,150.61 56.71,150.61 56.8,150.7 56.8,150.83 56.71,150.92 56.36,150.92 56.28,151 56.28,151.14 56.36,151.22 56.68,151.22 56.77,151.31 56.77,151.44 56.68,151.52 56.38,151.52 56.28,151.62 56.28,151.78 56.38,151.88 v8(56.47,151.88)
LPDDR3_M1_D16_A: length 23.3
  L5 w0.06: 64.37,162.9 65.44,162.9 65.44,162.9 65.53,162.9 65.57,162.94 v8(67.58,162.94)
  L5 w0.076: 64.37,162.9 64.26,163.01 54.47,163.01 52.64,161.17 52.64,159.85 52.35,159.56 52.35,159.45 52.54,159.26 52.54,159.16 52.43,159.05 52.32,159.05 52.05,159.32 51.92,159.32 51.83,159.23 51.83,159.11 52.11,158.83 52.11,158.73 52,158.62 51.89,158.62 51.31,159.2 51.18,159.2 51.09,159.11 51.09,158.98 51.68,158.4 51.68,158.29 51.57,158.19 51.46,158.19 51.27,158.38 51.16,158.38 51.05,158.26 51.05,158.21 51.17,158.09 51.17,157.94 51.1,157.88 v8(50.97,157.88)
LPDDR3_M1_D16_B: length 13.1
  L7 w0.06: 66.83,155.6 66.84,155.6 67.21,155.98 67.21,156.14 67.09,156.26 67.09,156.5 67.21,156.62 67.21,156.78 67.09,156.9 67.09,157.07 67.29,157.27 v8(67.58,157.27)
  L7 w0.061: 66.83,155.6 62.21,155.6 61.74,156.08 61.74,156.27 60.75,157.26 60.61,157.26 60.1,157.77 59.44,157.77 59.13,157.46 58.86,157.46 58.55,157.15 57.76,157.15 v8(57.47,156.86)
LPDDR3_M1_D17_A: length 23.1
  L5 w0.06: 66.99,163.13 67.48,163.13 67.49,163.14 67.66,163.14 67.67,163.13 68.22,163.13 68.43,162.92 v8(68.43,162.64)
  L5 w0.076: v8(50.99,157.37) 50.76,157.6 50.76,158.24 51.11,158.6 51.11,158.7 50.87,158.95 50.87,159.16 51.53,159.82 52.32,159.82 52.44,159.95 52.44,160.53 52.37,160.6 52.19,160.6 52.12,160.68 52.12,160.83 52.19,160.91 52.37,160.91 52.44,160.99 52.44,161.31 54.33,163.2 64.29,163.2 64.32,163.17 64.32,163.16 64.46,163.03 65.47,163.03 65.58,163.13 66.99,163.13
LPDDR3_M1_D17_B: length 14.7
  L7 w0.06: v8(67.29,156.42) 67.29,156.23 67.33,156.19 67.33,155.93 66.89,155.48 66.88,155.48
  L7 w0.061: 66.88,155.48 66.38,155.48 66.32,155.42 66.32,155.05 66.26,154.99 66.13,154.99 66.07,155.05 66.07,155.42 66.01,155.48 65.05,155.48 64.92,155.35 64.92,155.04 64.85,154.97 64.75,154.97 64.68,155.04 64.68,155.37 64.62,155.43 64.49,155.43 64.43,155.37 64.43,154.94 64.36,154.87 64.26,154.87 64.19,154.94 64.19,155.37 64.13,155.43 62.14,155.43 61.56,156.01 61.56,156.19 61.29,156.46 61.04,156.46 60.78,156.73 60.42,157.08 60.35,157.15 60.24,157.26 59.8,157.26 59.74,157.32 59.74,157.54 59.68,157.6 59.56,157.6 59.5,157.54 59.5,157.32 59.44,157.26 59.23,157.26 59.1,157.13 59.01,157.13 58.9,157.25 58.82,157.25 58.73,157.16 58.73,157.07 58.84,156.96 58.84,156.88 58.72,156.75 58.09,156.75 v8(57.97,156.88)
LPDDR3_M1_D18_A: length 23
  L5 w0.06: 66.74,163.34 67.19,163.34 67.28,163.26 68.37,163.26 v8(68.71,162.93)
  L5 w0.076: 66.74,163.34 65.5,163.34 65.32,163.16 64.51,163.16 64.46,163.22 64.29,163.39 54.25,163.39 51.11,160.25 51.11,159.67 50.62,159.18 50.62,157.22 v8(50.97,156.88)
LPDDR3_M1_D18_B: length 15
  L7 w0.06: 66.85,154.47 68.34,155.96 68.34,156.14 68.08,156.41 68.08,156.48 67.86,156.7 v8(67.86,156.98)
  L7 w0.061: 66.85,154.47 65.8,153.41 62.55,153.41 61.42,154.54 61.37,154.59 61.1,154.87 59.13,154.87 58.44,155.55 57.58,155.55 57.45,155.69 57.39,155.69 57.22,155.86 57.22,156.12 v8(56.96,156.38)
LPDDR3_M1_D19_A: length 24.2
  L5 w0.06: v8(68.71,163.49) 68.43,163.49 68.22,163.7 65.77,163.7
  L5 w0.076: v8(50.97,156.38) 50.35,156.99 50.35,159.55 50.7,159.9 50.7,160.37 54.09,163.77 64.34,163.77 64.69,164.12 65.35,164.12 65.77,163.7
LPDDR3_M1_D19_B: length 14.1
  L7 w0.06: 66.72,155.14 67.45,155.87 67.45,155.88 67.45,155.89 67.45,156.29 67.49,156.33 67.49,156.5 67.38,156.62 67.38,156.78 67.86,157.27 v8(68.14,157.27)
  L7 w0.061: 66.72,155.14 65.85,154.27 64.61,154.27 63.76,155.12 62.2,155.12 61.39,155.94 61.39,156.12 61.22,156.29 60.97,156.29 60.73,156.53 60.48,156.78 60.18,157.08 59.25,157.08 58.8,156.63 57.81,156.63 57.56,156.38 v8(57.47,156.38)
LPDDR3_M1_D20_A: length 22.8
  L5 w0.076: v8(51.45,157.87) 51.3,157.87 51.21,157.78 51.21,157.65 51.3,157.56 51.62,157.56 51.75,157.68 51.75,158.17 52.88,159.31 52.88,161.15 54.55,162.81 54.98,162.81 55.05,162.74 55.05,162.22 55.13,162.14 55.28,162.14 55.36,162.22 55.36,162.74 55.43,162.81 64.21,162.81 64.36,162.66 64.93,162.66 65,162.58 65,162.48 65.08,162.4 65.23,162.4 65.31,162.48 65.31,162.68 65.4,162.77 65.52,162.77 65.61,162.68 65.61,162.48 65.69,162.4 65.84,162.4 65.92,162.48 65.92,162.71 66.01,162.8 66.13,162.8 66.22,162.71 66.22,162.48 66.3,162.4 66.45,162.4 66.53,162.48 66.53,162.58 66.6,162.66 v8(67.3,162.66)
LPDDR3_M1_D20_B: length 14.3
  L7 w0.06: 66.71,154.95 67.58,155.82 67.58,156.25 67.61,156.28 67.61,156.66 v8(67.58,156.7)
  L7 w0.061: 66.71,154.95 66.7,154.95 66.62,154.87 66.62,154.86 66.61,154.85 66.61,154.85 65.79,154.03 64.28,154.03 64.16,154.16 64.16,154.53 63.74,154.94 63.13,154.94 62.99,154.8 62.99,154.35 62.92,154.28 62.82,154.28 62.74,154.35 62.74,154.88 62.68,154.94 62.13,154.94 61.8,155.27 61.77,155.3 61.64,155.43 61.37,155.7 61.13,155.7 61.13,155.7 60.54,155.7 60.42,155.82 60.42,156.45 60.01,156.85 59.48,156.85 59.1,156.48 59.1,156.47 58.06,156.47 v8(57.97,156.38)
LPDDR3_M1_D21_A: length 21.8
  L5 w0.06: 64.67,162.05 64.76,161.96 66.91,161.96 67.09,162.14 67.29,162.14 67.37,162.21 67.65,162.21 67.8,162.36 v8(68.14,162.36)
  L5 w0.061: 52.44,157.74 52.28,157.58 52.28,157.41 52.04,157.17 51.77,157.17 51.67,157.08 51.26,157.08 51.18,157.16 51.18,157.27 51.26,157.35 v8(51.42,157.35)
  L5 w0.076: 64.67,162.05 64.65,162.07 57.27,162.07 56.88,161.68 56.74,161.68 56.49,161.93 56.34,161.93 56.23,161.82 56.23,161.67 56.5,161.4 56.5,161.3 56.39,161.19 56.28,161.19 56,161.47 55.87,161.47 55.78,161.38 55.78,161.26 56.07,160.97 56.07,160.86 55.96,160.76 55.85,160.76 55.69,160.91 55.59,160.91 55.42,160.74 55.42,160.57 54,159.16 53.86,159.16 52.44,157.74
LPDDR3_M1_D21_B: length 16.6
  L7 w0.06: 68.46,155.56 68.71,155.81 v8(68.71,156.7)
  L7 w0.061: v8(56.47,155.88) 56.47,155.68 56.73,155.41 56.73,154.8 56.91,154.62 57.01,154.62 57.22,154.41 57.22,154.34 57.42,154.14 58.07,154.14 58.23,154.3 58.23,154.45 58.38,154.59 58.75,154.59 59.01,154.34 60.89,154.34 61.05,154.17 62.33,152.89 65.78,152.89 68.46,155.56
LPDDR3_M1_D22_A: length 20.7
  L5 w0.06: 64.62,161.84 66.96,161.84 67.14,162.02 67.34,162.02 67.42,162.09 67.99,162.09 68.01,162.11 68.58,162.11 68.71,162.24 v8(68.71,162.36)
  L5 w0.061: v8(51.47,156.88) 51.25,156.88 51.17,156.79 51.17,156.67 51.25,156.59 51.71,156.59 51.77,156.65 51.77,156.96 51.87,157.05 52.11,157.05 52.54,157.48
  L5 w0.076: 64.62,161.84 64.58,161.88 57.35,161.88 56,160.52 55.61,160.52 55.61,160.49 54.38,159.27 54.32,159.27 52.54,157.48
LPDDR3_M1_D22_B: length 15.2
  L7 w0.06: 66.75,154.2 68.46,155.91 68.46,156.24 68.39,156.31 v8(68.39,156.38)
  L7 w0.061: 66.75,154.2 65.79,153.24 62.48,153.24 61.3,154.42 61.25,154.47 61.02,154.69 59.13,154.69 58.99,154.84 58.48,154.84 58.19,155.13 57.44,155.13 57.22,155.36 57.22,155.45 57.09,155.58 56.81,155.58 56.68,155.71 56.68,155.97 56.76,156.06 56.88,156.06 56.97,155.97 v8(56.97,155.88)
LPDDR3_M1_D23_A: length 23.4
  L5 w0.06: 64.65,163.33 65.13,163.33 65.3,163.49 v8(68.14,163.49)
  L5 w0.076: v8(51.47,156.38) 51.26,156.38 50.97,156.67 50.88,156.67 50.49,157.06 50.49,159.32 50.54,159.38 50.54,159.47 50.89,159.82 50.89,160.3 54.17,163.58 64.4,163.58 64.65,163.33
LPDDR3_M1_D23_B: length 16.8
  L7 w0.06: 68.49,155.41 68.83,155.75 68.83,156.54 68.92,156.62 68.92,156.9 v8(68.99,156.98)
  L7 w0.061: 68.49,155.41 65.8,152.71 62.26,152.71 60.81,154.16 58.38,154.16 58.24,154.01 57.16,154.01 57.06,154.12 56.95,154.12 56.67,154.39 56.67,154.46 56.46,154.67 56.36,154.67 56.24,154.79 56.24,155.15 v8(56.47,155.38)
LPDDR3_M1_D24_A: length 16.3
  L5 w0.06: 64.93,161.4 65.11,161.58 67.04,161.58 67.24,161.77 v8(67.55,161.77)
  L5 w0.076: 64.93,161.4 64.89,161.35 57.63,161.35 55.01,158.74 55.01,156.83 v8(55.47,156.38)
LPDDR3_M1_D24_B: length 21.9
  L7 w0.061: v8(69.56,156.42) 69.56,156.26 69.69,156.13 69.69,155.6 69.36,155.27 69.36,155 68.63,154.27 68.63,154.27 68.62,154.26 68.41,154.04 68.41,153.99 68.41,153.98 68.41,153.87 68.47,153.81 68.47,153.7 68.39,153.61 68.3,153.61 68.21,153.7 68.13,153.7 68.04,153.61 68.04,153.53 68.13,153.44 68.13,153.35 68.04,153.26 67.96,153.26 67.87,153.36 67.78,153.36 67.03,152.6 67.03,152.3 66.19,151.46 65.7,150.97 62.09,150.97 61.7,151.36 61.44,151.36 61.38,151.42 61.38,151.55 61.32,151.61 61.2,151.61 61.13,151.55 61.13,151.41 61.07,151.35 60.96,151.35 60.96,151.34 60.89,151.41 60.89,151.55 60.83,151.61 60.71,151.61 60.65,151.55 60.65,151.13 60.58,151.05 60.47,151.05 60.4,151.13 60.4,151.55 60.34,151.61 60.22,151.61 60.16,151.55 60.16,151.16 60.09,151.09 59.99,151.09 59.92,151.16 59.92,151.55 59.85,151.61 59.73,151.61 59.67,151.55 59.67,151.28 59.54,151.15 59.53,151.17 58.98,151.17 58.61,151.54 58.08,151.54 58.06,151.56 57.23,151.56 57.14,151.65 56.31,151.65 56.19,151.52 56.19,151.29 56.18,151.28 56.18,151.21 56.31,151.08 56.63,151.08 56.72,151.17 56.72,151.29 56.63,151.38 v8(56.47,151.38)
LPDDR3_M1_D25_A: length 15.8
  L5 w0.06: v8(67.58,161.23) 67.51,161.16 65.45,161.16 65.06,160.77
  L5 w0.076: v8(55.97,156.38) 56.17,156.58 56.17,156.92 56.05,157.04 55.84,157.04 55.42,157.46 55.42,158.34 57.87,160.78 65.05,160.78 65.06,160.77
LPDDR3_M1_D25_B: length 20.3
  L7 w0.061: v8(56.97,151.38) 57.14,151.38 57.27,151.25 57.27,151.06 57.17,150.96 57.17,150.54 57.27,150.44 57.6,150.44 57.7,150.54 57.81,150.54 57.89,150.46 57.89,150.35 57.69,150.14 57.69,149.66 57.8,149.55 59.36,149.55 59.99,149.55 60.15,149.39 65.36,149.39 65.55,149.58 65.55,149.58 65.96,149.99 65.96,149.99 66.45,150.48 66.45,150.48 66.55,150.58 66.55,150.58 70.32,154.35 70.32,154.43 70.32,154.53 70.32,154.53 70.32,155.69 70.61,155.98 70.61,156.37 70.48,156.5 70.31,156.5 v8(70.21,156.4)
LPDDR3_M1_D26_A: length 16
  L5 w0.06: 64.98,161.16 65.27,161.46 67.24,161.46 v8(67.29,161.51)
  L5 w0.076: v8(55.96,156.84) 55.8,156.67 55.37,156.67 55.15,156.89 55.15,158.6 57.71,161.16 64.98,161.16
LPDDR3_M1_D26_B: length 21.6
  L7 w0.061: v8(57.47,151.35) 57.7,151.35 57.95,151.09 58.46,151.09 58.98,150.57 60.92,150.57 61.39,150.11 63.32,150.11 63.4,150.18 63.4,150.28 63.32,150.35 61.44,150.35 61.38,150.41 61.38,150.53 61.44,150.59 63.48,150.59 63.61,150.47 63.61,150.28 63.78,150.11 65.33,150.11 65.43,150.21 65.43,150.21 65.92,150.7 65.92,150.7 66.33,151.11 69.93,154.7 69.93,154.78 69.93,156.23 69.89,156.27 69.89,156.56 69.84,156.6 v8(69.84,156.7)
LPDDR3_M1_D27_A: length 14.7
  L5 w0.06: v8(68.71,161.23) 68.43,161.23 68.23,161.03 68.23,160.86 68.34,160.74 68.34,160.56
  L5 w0.076: v8(56.47,157.88) 56.81,158.22 56.9,158.22 58.34,159.66 59.53,159.66 59.97,159.22 62.06,159.22 62.36,158.92 64.97,158.92 66.35,160.3 68.08,160.3 68.34,160.56
LPDDR3_M1_D27_B: length 21.8
  L7 w0.061: v8(57.98,151.36) 58.44,151.36 59.03,150.77 59.21,150.77 59.27,150.83 59.27,150.92 59.34,150.99 59.44,150.99 59.51,150.92 59.51,150.83 59.57,150.77 59.69,150.77 59.75,150.83 59.75,150.83 59.83,150.91 59.93,150.91 60,150.83 60,150.83 60.06,150.77 61.36,150.77 61.43,150.83 61.43,151.1 61.5,151.17 61.6,151.17 61.67,151.1 61.67,150.83 61.73,150.77 65.23,150.77 65.31,150.7 65.31,150.6 65.23,150.53 63.85,150.53 63.78,150.45 63.78,150.35 63.85,150.28 65.26,150.28 65.75,150.77 65.75,150.77 66.26,151.28 68.75,153.77 68.75,153.86 68.62,153.98 68.62,154.07 68.7,154.16 68.79,154.16 68.92,154.03 69,154.03 69.09,154.11 69.09,154.2 68.96,154.33 68.96,154.42 69.05,154.5 69.14,154.5 69.28,154.36 69.4,154.35 69.48,154.44 69.48,154.55 69.37,154.66 69.37,154.79 69.47,154.89 69.68,154.89 69.81,155.02 69.81,156.18 69.76,156.23 69.76,156.5 69.64,156.62 69.64,156.62 69.56,156.71 v8(69.56,156.98)
LPDDR3_M1_D28_A: length 16
  L5 w0.06: 67.92,160.44 v8(68.14,160.66)
  L5 w0.076: v8(56.47,157.38) 56.26,157.58 56.26,157.96 56.65,158.35 56.75,158.35 56.76,158.36 56.76,158.36 58.26,159.85 59.97,159.85 60.04,159.77 60.04,159.52 60.12,159.45 60.27,159.45 60.35,159.52 60.35,159.77 60.43,159.85 60.58,159.85 60.65,159.77 60.65,159.52 60.73,159.45 60.88,159.45 60.96,159.52 60.96,159.77 61.04,159.85 61.19,159.85 61.26,159.77 61.26,159.52 61.34,159.45 61.49,159.45 61.57,159.52 61.57,159.77 61.65,159.85 61.84,159.85 62.36,159.32 65.17,159.32 66.29,160.44 67.92,160.44
LPDDR3_M1_D28_B: length 21.1
  L7 w0.06: 70.85,155.88 70.85,156.54 70.77,156.62 70.77,156.78 70.89,156.9 70.89,157.07 70.69,157.27 v8(70.41,157.27)
  L7 w0.061: 70.85,155.88 70.56,155.59 70.56,154.08 65.53,149.04 65.51,149.04 60,149.04 59.85,149.2 59.51,149.2 57.44,149.2 56.47,150.17 v8(56.47,150.88)
LPDDR3_M1_D29_A: length 16.3
  L5 w0.06: 65.9,161.03 67.66,161.03 67.86,161.23 v8(67.86,161.51)
  L5 w0.076: 65.9,161.03 65.33,160.45 64.83,160.45 64.69,160.59 64.52,160.59 64.38,160.45 64.22,160.45 64.08,160.59 63.92,160.59 63.77,160.45 63.5,160.45 63.36,160.59 62.85,160.59 62.71,160.45 62.61,160.45 62.47,160.59 57.95,160.59 56.62,159.27 56.55,159.27 55.56,158.28 55.56,157.51 55.89,157.18 56.34,157.18 56.47,157.05 v8(56.47,156.88)
LPDDR3_M1_D29_B: length 21.5
  L7 w0.06: 70.65,156.55 70.65,156.74 70.41,156.98 v8(70.12,156.98)
  L7 w0.061: 70.65,156.55 70.73,156.48 70.73,155.93 70.44,155.64 70.44,154.58 70.44,154.23 66.62,150.41 66.13,149.92 65.91,149.7 65.43,149.22 60.08,149.22 59.92,149.38 59.43,149.38 57.53,149.37 57.18,149.72 57.18,149.81 57.52,150.14 57.52,150.24 57.45,150.32 57.35,150.32 57.01,149.98 56.93,149.98 56.67,150.24 56.67,150.8 56.75,150.88 v8(56.97,150.88)
LPDDR3_M1_D30_A: length 13.6
  L5 w0.06: v8(68.71,160.66) 68.71,160.58 68.17,160.04 66.48,160.04 66.36,159.91
  L5 w0.076: v8(56.97,157.88) 58.41,159.32 59.24,159.32 59.71,158.84 61.9,158.84 62.2,158.54 64.98,158.54 66.36,159.91
LPDDR3_M1_D30_B: length 20.1
  L7 w0.061: v8(70.41,156.06) 70.29,155.94 70.2,155.85 70.2,154.48 66.48,150.76 66.27,150.55 65.78,150.06 65.48,149.76 65.45,149.73 65,149.73 64.94,149.66 64.94,149.63 64.88,149.57 64.75,149.57 64.69,149.63 64.69,149.66 64.63,149.73 64.51,149.73 64.45,149.66 64.45,149.63 64.39,149.57 64.27,149.57 64.21,149.63 64.21,149.66 64.14,149.73 64.02,149.73 63.96,149.66 63.96,149.63 63.9,149.57 63.78,149.57 63.72,149.63 63.72,149.66 63.66,149.73 63.53,149.73 63.47,149.66 63.47,149.63 63.41,149.57 63.29,149.57 63.23,149.63 63.23,149.66 63.17,149.73 63.05,149.73 62.99,149.66 62.99,149.63 62.93,149.57 62.8,149.57 62.74,149.63 62.74,149.66 62.68,149.73 62.56,149.73 62.5,149.66 62.5,149.63 62.44,149.57 62.32,149.57 62.25,149.63 62.25,149.66 62.19,149.73 62.07,149.73 62.01,149.66 62.01,149.63 61.95,149.57 61.83,149.57 61.77,149.63 61.77,149.66 61.71,149.73 61.58,149.73 61.52,149.66 61.52,149.63 61.46,149.57 61.34,149.57 61.28,149.63 61.28,149.66 61.22,149.73 61.1,149.73 61.04,149.66 61.04,149.63 60.97,149.57 60.85,149.57 60.79,149.63 60.79,149.66 60.73,149.73 60.61,149.73 60.55,149.66 60.55,149.63 60.49,149.57 60.36,149.57 60.3,149.63 60.3,149.66 60.24,149.73 59.29,149.73 58.82,149.73 58.64,149.91 58.55,149.91 58.38,149.73 58.28,149.73 58.2,149.8 58.2,149.9 58.38,150.08 58.38,150.17 58.26,150.29 58.26,150.38 58.38,150.5 58.38,150.58 58.29,150.67 58.2,150.67 58.09,150.55 58,150.55 57.75,150.79 57.75,151.07 57.67,151.15 57.55,151.15 57.47,151.07 v8(57.47,150.88)
LPDDR3_M1_D31_A: length 15.7
  L5 w0.06: 66.31,160.07 66.42,160.17 68.13,160.17 68.47,160.51 68.47,160.9 v8(68.43,160.94)
  L5 w0.076: v8(56.97,157.38) 57.14,157.38 57.23,157.29 57.23,157.16 57.14,157.08 56.82,157.08 56.69,157.2 56.69,157.91 56.87,158.08 56.95,158.08 58.32,159.45 59.39,159.45 59.81,159.03 61.98,159.03 62.28,158.73 64.98,158.73 66.31,160.07
LPDDR3_M1_D31_B: length 22.2
  L7 w0.06: 70.01,156.59 70.04,156.62 70.04,156.78 69.84,156.98
  L7 w0.061: 69.84,156.98 v8(69.84,157.27) ; v8(57.97,150.88) 58.49,150.88 58.62,150.75 58.62,150.19 58.89,149.91 60.84,149.91 60.91,149.98 60.91,150.08 60.84,150.15 58.93,150.15 58.86,150.23 58.86,150.33 58.93,150.4 60.85,150.4 61.32,149.93 65.4,149.93 65.61,150.14 66.1,150.62 66.4,150.93 70.05,154.58 70.05,154.65 70.05,156.28 70.01,156.32 70.01,156.59
LPDDR3_M1_DM0_A: length 25.9
  L7 w0.061: v8(66.46,162.97) 66.34,162.97 66.31,163 61.93,163 61.75,163.19 57.79,163.19 57.79,163.19 56.71,163.19 52.27,163.19 52.24,163.16 50.85,163.16 50.09,162.41 50.09,161.11 49.62,160.64 49.62,159.93 49.93,159.63 49.93,159.29 49.93,159.28 49.93,159.1 49.7,158.88 49.7,158.42 49.7,158.42 49.7,157.45 50.05,157.1 50.55,157.1 50.69,156.97 50.69,156.88 50.96,156.6 51.69,156.6 51.76,156.53 52.32,156.53 52.33,156.52 52.6,156.52 52.61,156.53 52.79,156.53 52.93,156.4 v8(52.93,156.34)
LPDDR3_M1_DM0_B: length 16.1
  L5 w0.06: 68.69,156.74 69.06,157.11 v8(69.06,157.54)
  L5 w0.076: 68.69,156.74 68.69,155.83 64.69,151.82 61.03,151.82 59.83,153.02 59.29,153.02 59.1,153.21 58.44,153.88 v8(56.97,153.88)
LPDDR3_M1_DM1_A: length 15.5
  L7 w0.06: 65.25,159.9 65.25,159.9 65.37,159.9 66.53,159.9 66.73,160.1 v8(66.73,160.38)
  L7 w0.061: 65.25,159.9 65.09,159.9 64.29,159.09 61.7,159.09 61.05,158.44 58.3,158.44 58.13,158.6 57.41,158.6 57.4,158.59 57.38,158.59 57.25,158.47 57.25,158.45 56.73,157.92 56.73,157.85 56.45,157.58 56.39,157.58 56.24,157.43 56.24,157.39 56.05,157.2 56.04,157.2 55.76,156.92 55.76,156.89 55.45,156.58 54.9,156.58 54.78,156.46 54.78,156.38 54.56,156.16 54.32,156.16 54.19,156.29 54.19,156.76 54.07,156.88 v8(53.96,156.88)
LPDDR3_M1_DM1_B: length 23.8
  L5 w0.06: v8(69.27,158.96) 68.9,158.96 68.78,159.09 68.78,159.31 69.03,159.57 69.48,159.57 69.6,159.44 69.6,158.44 69.36,158.2 69.36,157.93 69.56,157.73 69.56,156.94 69.45,156.82
  L5 w0.076: 69.45,156.82 69.17,156.55 69.17,154.89 68.69,154.41 68.69,153.5 67.98,152.79 67.83,152.79 67.21,152.16 66.93,151.88 66.34,151.3 66.34,151.29 66.1,151.05 59.97,151.05 59.96,151.07 59.9,151.07 59,151.97 59,152.61 58.15,153.46 57.37,153.46 57.08,153.16 56.22,153.16 56.14,153.08 56.14,152.96 56.22,152.88 v8(56.47,152.88)
LPDDR3_M1_DM2_A: length 21.8
  L5 w0.06: v8(68.71,161.79) 68.74,161.76 68.74,161.54 68.65,161.44 68.51,161.44 68.41,161.54 68.41,161.82 68.24,161.99 68.06,161.99 68.04,161.97 67.47,161.97 67.39,161.9 67.19,161.9 66.99,161.7 64.95,161.7
  L5 w0.076: v8(51.98,156.85) 52.13,156.85 52.84,157.56 52.95,157.56 53.22,157.28 53.33,157.28 53.44,157.39 53.44,157.5 53.16,157.78 53.16,157.89 54.06,158.78 54.27,158.78 54.51,158.55 54.64,158.55 54.73,158.63 54.73,158.76 54.49,159 54.49,159.11 54.96,159.58 55.11,159.58 55.21,159.48 55.34,159.48 55.43,159.57 55.43,159.7 55.33,159.8 55.33,159.91 55.44,160.02 55.54,160.02 55.61,159.95 55.72,159.95 57.46,161.69 64.94,161.69 64.95,161.7
LPDDR3_M1_DM2_B: length 15.1
  L7 w0.06: 66.92,154.19 68.59,155.86 68.59,156.46 68.43,156.63 v8(68.43,156.98)
  L7 w0.061: 66.92,154.19 65.79,153.06 62.41,153.06 61.18,154.29 61.08,154.39 60.95,154.52 59.03,154.52 58.84,154.71 58.05,154.71 57.98,154.64 57.43,154.64 57.22,154.85 57.22,154.93 56.97,155.17 v8(56.97,155.38)
LPDDR3_M1_DM3_A: length 15.9
  L5 w0.06: 65.05,160.97 65.36,161.28 67.35,161.28 67.86,161.79 v8(68.14,161.79)
  L5 w0.076: 65.05,160.97 57.79,160.97 55.29,158.47 55.29,157.06 v8(55.47,156.88)
LPDDR3_M1_DM3_B: length 20.3
  L7 w0.06: 69.23,156.46 69.08,156.62 69.08,156.78 69.2,156.9 69.2,157.09
  L7 w0.061: 69.23,156.46 69.32,156.37 69.32,156.32 69.57,156.08 69.57,155.65 69.24,155.32 69.24,155.32 69.08,155.16 69.08,154.89 68.51,154.32 68.51,154.32 68.5,154.31 68.29,154.1 68.29,154.04 66.02,151.76 65.8,151.76 65.67,151.64 65.67,151.27 65.59,151.19 65.46,151.19 65.38,151.27 65.38,151.75 65.31,151.82 65.21,151.82 65.14,151.75 65.14,151.25 65.03,151.14 62.16,151.14 61.83,151.48 61.83,151.65 61.69,151.79 59.33,151.79 59.27,151.72 59.27,151.44 59.26,151.43 59.26,151.36 59.2,151.29 59.1,151.29 59.02,151.36 59.02,151.72 58.96,151.79 58.69,151.79 58.56,151.66 58.38,151.66 58.36,151.68 58.33,151.68 57.41,151.68 57.28,151.8 57.28,152.03 57.16,152.15 56.8,152.15 56.67,152.03 56.67,151.9 56.75,151.82 56.91,151.82 v8(56.97,151.88) ; v8(69.27,157.27) 69.2,157.19 69.2,157.09
LPDDR3_M1_DQS0_N_A: length 27.9
  L7 w0.06: 51.6,158.22 51.77,158.04 51.77,157.85 51.93,157.7 52.13,157.7 52.31,157.53 52.31,157.5 52.31,157.33 52.42,157.22 52.43,157.22 52.46,157.19 53.43,157.19 53.74,156.88 53.74,156.45 53.66,156.38 v8(53.47,156.38) ; 65.48,162.39 v8(65.82,162.39)
  L7 w0.061: 51.6,158.22 50.39,158.22 50.27,158.35 50.27,158.65 50.4,158.78 50.57,158.78 50.77,158.98 50.77,159.22 50.87,159.32 51.5,159.32 51.7,159.53 51.7,159.82 51.5,160.03 50.74,160.03 50.62,160.15 50.62,160.44 50.94,160.76 50.94,162.06 51.2,162.32 52.59,162.32 52.61,162.35 57.06,162.35 57.06,162.35 57.44,162.35 57.85,162.35 57.91,162.29 57.91,162.18 58.12,161.97 58.41,161.97 58.62,162.18 58.62,162.29 58.68,162.35 58.86,162.35 58.92,162.29 58.92,162.16 59.13,161.96 59.42,161.96 59.63,162.16 59.63,162.29 59.69,162.35 59.87,162.35 59.94,162.29 59.94,162.2 60.14,161.99 60.43,161.99 60.64,162.2 60.64,162.29 60.7,162.35 61.4,162.35 61.53,162.21 61.66,162.09 63.24,162.09 63.4,162.24 63.52,162.24 63.64,162.37 63.95,162.37 64.01,162.31 64.01,162.12 64.19,161.94 64.54,161.94 64.72,162.12 64.72,162.31 64.78,162.37 65.45,162.37 65.48,162.39
LPDDR3_M1_DQS0_N_B: length 16.7
  L5 w0.066: v8(67.86,157.55) 67.86,157.45 67.79,157.38 67.46,157.38 66.85,156.77 66.85,156 66.55,155.7 66.45,155.7 66.38,155.76 66.13,155.76 65.95,155.58 65.95,155.33 66.14,155.14 66.14,155.04 65.16,154.06 65.07,154.06 64.86,154.26 64.63,154.26 64.32,153.95 64.32,153.76 64.45,153.63 64.45,153.48 64.19,153.22 61.61,153.22 59.13,155.69 57.87,155.69 57.67,155.49 57.67,155.3 57.55,155.18 57.37,155.18 57.15,154.96 57.15,154.79 56.98,154.62 56.92,154.62 56.67,154.38 v8(56.47,154.38)
LPDDR3_M1_DQS0_P_A: length 27.9
  L7 w0.06: 51.63,157.98 51.65,157.95 51.65,157.8 51.88,157.58 52.08,157.58 52.19,157.48 52.19,157.28 52.4,157.07 53.38,157.07 53.45,156.99 53.45,156.83 v8(53.45,156.82) ; 65.48,162.59 66.08,162.59 v8(66.14,162.53)
  L7 w0.061: 51.63,157.98 51.52,158.09 50.31,158.09 50.07,158.33 50.07,158.73 50.32,158.98 50.48,158.98 50.57,159.06 50.57,159.31 50.78,159.52 51.41,159.52 51.5,159.61 51.5,159.74 51.41,159.83 50.66,159.83 50.42,160.07 50.42,160.52 50.73,160.84 50.73,162.14 51.11,162.52 52.5,162.52 52.53,162.55 56.97,162.55 57.94,162.55 58.11,162.37 58.11,162.26 58.2,162.17 58.33,162.17 58.42,162.26 58.42,162.37 58.6,162.55 58.95,162.55 59.13,162.37 59.13,162.25 59.21,162.16 59.34,162.16 59.43,162.25 59.43,162.37 59.61,162.55 59.96,162.55 60.14,162.37 60.14,162.28 60.23,162.19 60.35,162.19 60.44,162.28 60.44,162.37 60.62,162.55 61.48,162.55 61.61,162.42 61.74,162.29 63.16,162.29 63.31,162.44 63.43,162.44 63.56,162.57 64.03,162.57 64.21,162.39 64.21,162.2 64.27,162.14 64.45,162.14 64.52,162.2 64.52,162.39 64.69,162.57 65.45,162.57 65.48,162.59
LPDDR3_M1_DQS0_P_B: length 16.8
  L5 w0.06: 68.06,157.75 68.06,157.75 v8(68.14,157.83)
  L5 w0.066: v8(56.97,154.38) 57.29,154.7 57.29,154.9 57.43,155.04 57.61,155.04 57.81,155.24 57.81,155.43 57.93,155.55 59.07,155.55 61.55,153.08 64.25,153.08 64.59,153.42 64.59,153.69 64.46,153.82 64.46,153.89 64.69,154.12 64.81,154.12 65.01,153.92 65.21,153.92 66.28,154.98 66.28,155.2 66.09,155.39 66.09,155.52 66.19,155.62 66.32,155.62 66.39,155.56 66.61,155.56 66.99,155.94 66.99,156.71 67.52,157.24 67.85,157.24 68.06,157.45 68.06,157.75 68.06,157.75
LPDDR3_M1_DQS1_N_A: length 15.4
  L7 w0.06: 55.28,158.57 55.28,158.56 55.27,158.55 55.27,157.24 55.09,157.05 54.84,157.05 54.72,156.93 54.72,156.81 54.59,156.68 54.46,156.68 54.4,156.62 54.4,156.44 v8(54.48,156.36)
  L7 w0.061: 55.28,158.57 55.28,159.16 55.69,159.56 56.35,159.56 56.58,159.33 58.3,159.33 58.3,159.33 58.39,159.33 58.39,159.33 58.57,159.33 58.89,159.65 61.11,159.65 61.36,159.9 63.44,159.9 63.58,160.04 64.4,160.04 64.94,160.58 66.37,160.58 v8(66.45,160.66)
LPDDR3_M1_DQS1_N_B: length 23.4
  L5 w0.06: v8(68.99,158.12) 69.08,158.03 69.08,157.82 69.28,157.61 69.28,157.1 68.86,156.68 68.86,155.93
  L5 w0.066: v8(56.47,153.38) 56.67,153.38 56.88,153.58 56.96,153.58 57.13,153.74 58.26,153.74 59.3,152.7 59.3,152.29 60.08,151.51 64.81,151.51 65.16,151.87 65.43,151.87 65.69,151.61 65.83,151.61 65.93,151.71 65.93,151.84 65.69,152.08 65.69,152.38 65.9,152.58 66.19,152.58 66.53,152.25 66.66,152.25 66.76,152.35 66.76,152.48 66.32,152.93 66.32,153.18 66.5,153.36 66.75,153.36 67.31,152.81 67.45,152.81 67.54,152.9 67.54,153.01 67.4,153.15 67.08,153.48 67.08,153.72 67.63,154.27 67.9,154.27 68.03,154.13 68.17,154.13 68.27,154.23 68.27,154.37 68,154.64 68,154.85 68.22,155.07 68.44,155.07 68.56,154.95 68.65,154.95 68.86,155.16 68.86,155.93
LPDDR3_M1_DQS1_P_A: length 15.4
  L7 w0.06: v8(66.73,160.94) 66.67,160.88 66.31,160.88 66.21,160.78 ; v8(54.47,156.88) 54.5,156.88 54.79,157.17 55.04,157.17 55.15,157.29 55.15,158.51 55.1,158.57 55.08,158.55 55.08,158.57
  L7 w0.061: 55.08,158.57 55.08,159.24 55.6,159.76 56.44,159.76 56.67,159.53 58.48,159.53 58.8,159.85 61.02,159.85 61.28,160.1 63.35,160.1 63.49,160.24 64.32,160.24 64.86,160.78 66.04,160.78 66.04,160.78 66.21,160.78 66.21,160.78
LPDDR3_M1_DQS1_P_B: length 23.3
  L5 w0.06: 68.88,154.97 69.02,155.12 69.02,156.61 69.44,157.03 69.44,157.68 69.24,157.88 69.24,158.36 v8(69.27,158.4)
  L5 w0.066: 68.88,154.97 68.71,154.8 68.5,154.8 68.38,154.93 68.28,154.93 68.14,154.79 68.14,154.7 68.41,154.43 68.41,154.17 68.23,153.99 67.98,153.99 67.84,154.13 67.69,154.13 67.22,153.66 67.22,153.54 67.69,153.07 67.69,152.84 67.5,152.66 67.25,152.66 66.69,153.22 66.55,153.22 66.46,153.12 66.46,152.99 66.91,152.54 66.91,152.29 66.72,152.1 66.47,152.1 66.13,152.44 65.96,152.44 65.83,152.32 65.83,152.14 66.07,151.9 66.07,151.65 65.89,151.47 65.63,151.47 65.38,151.72 65.22,151.72 64.87,151.37 60.02,151.37 59.16,152.23 59.16,152.64 58.2,153.6 57.18,153.6 56.97,153.39 v8(56.97,153.38)
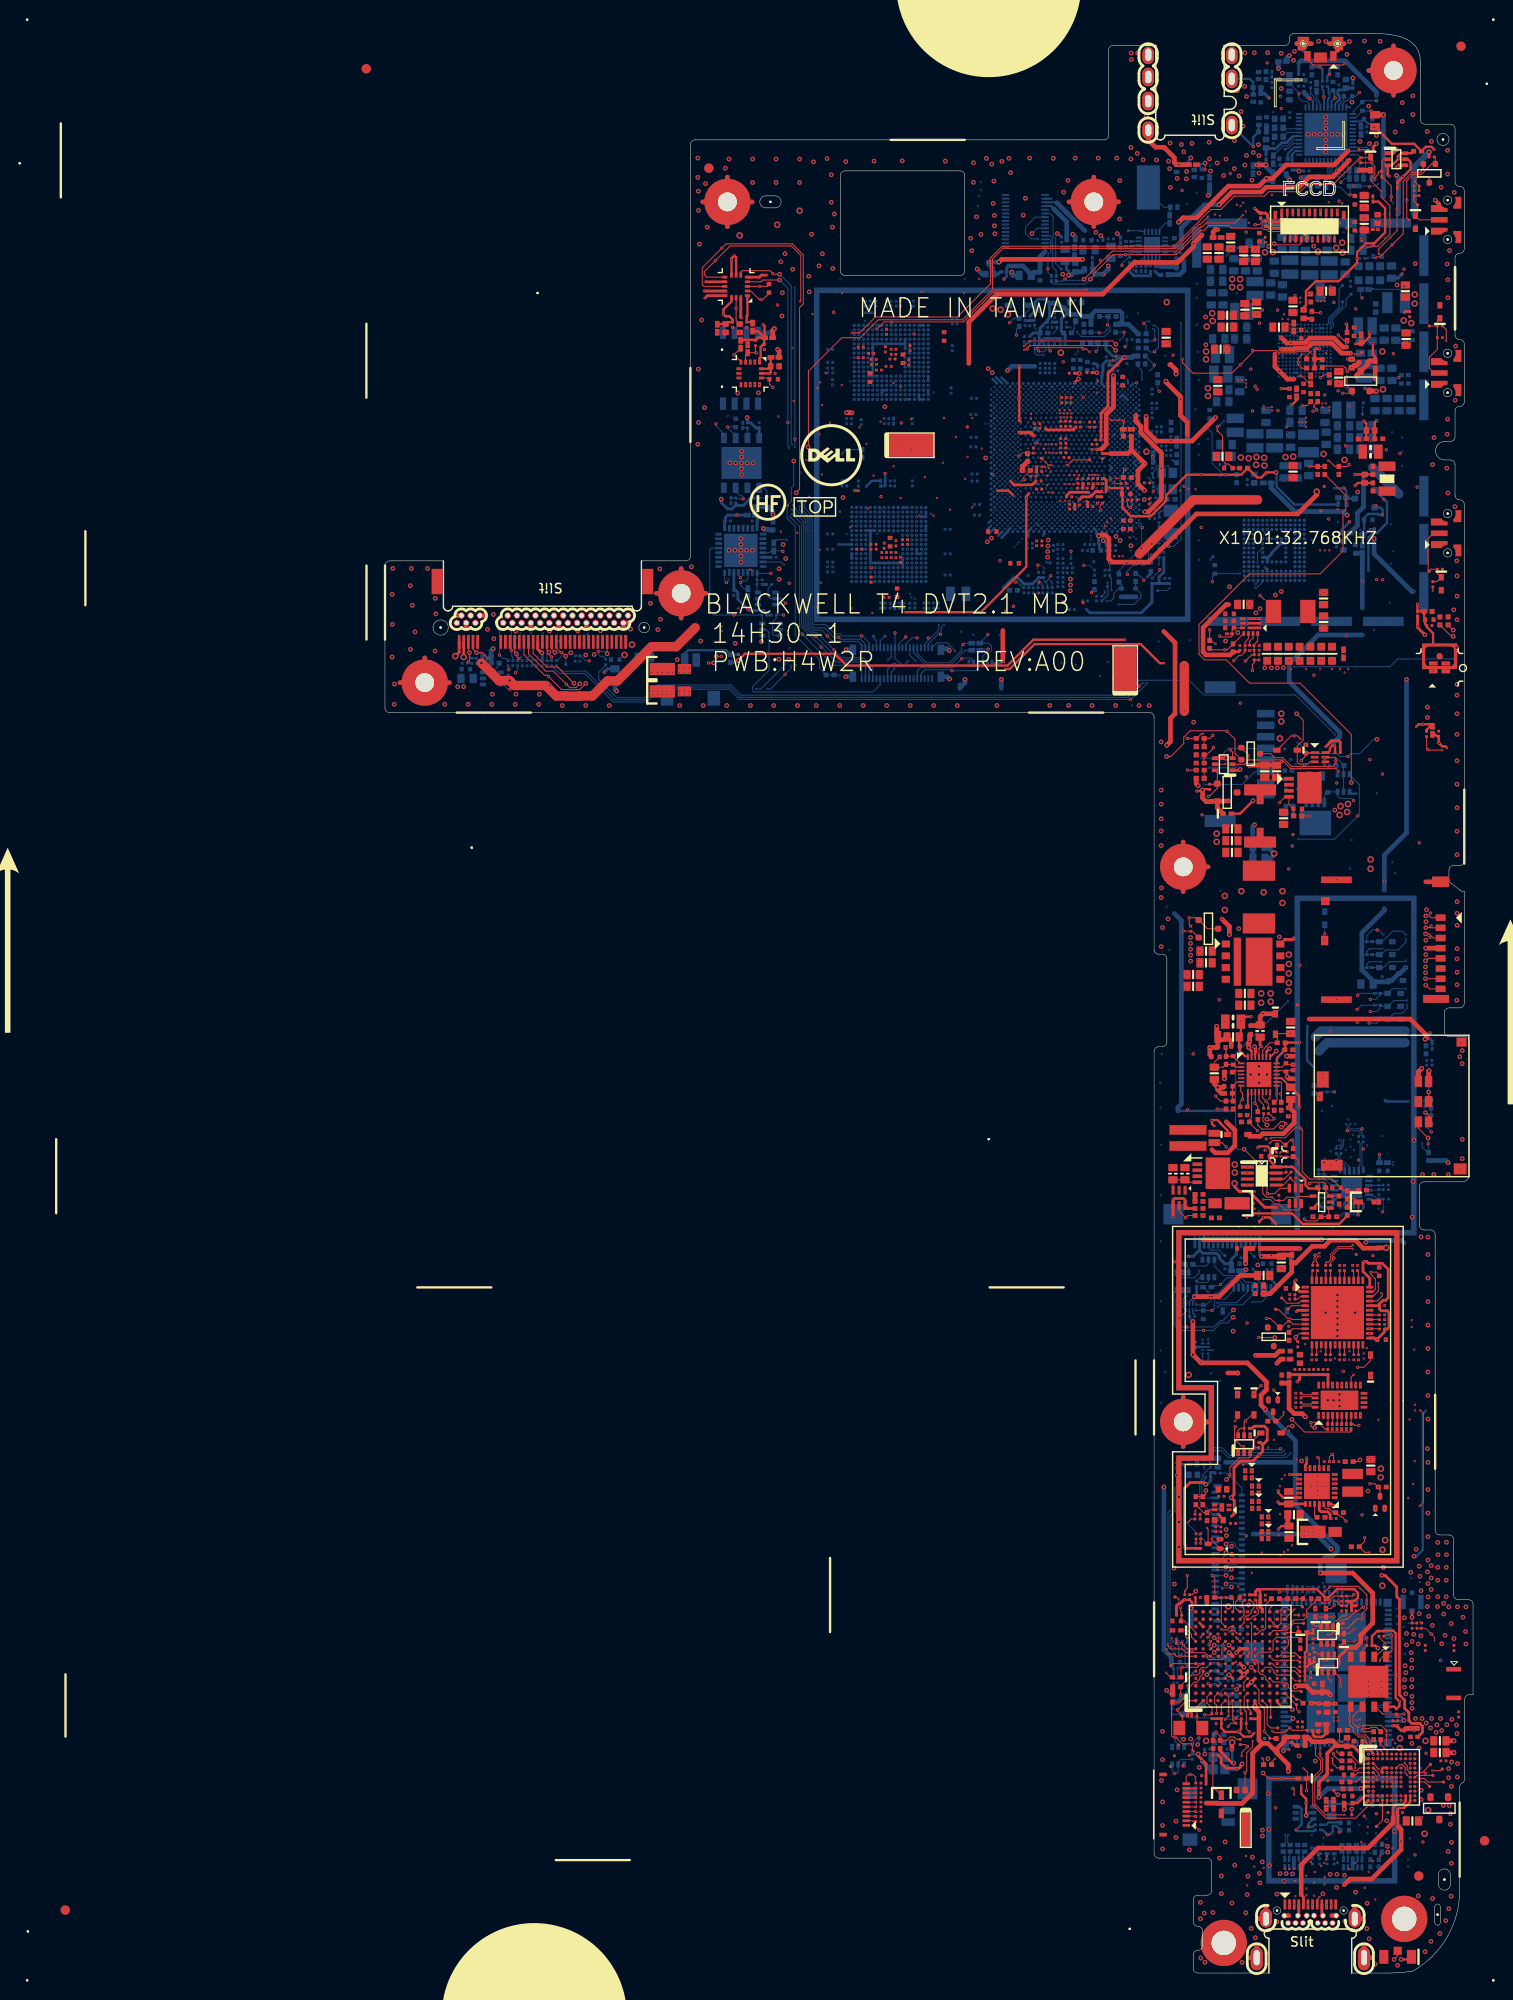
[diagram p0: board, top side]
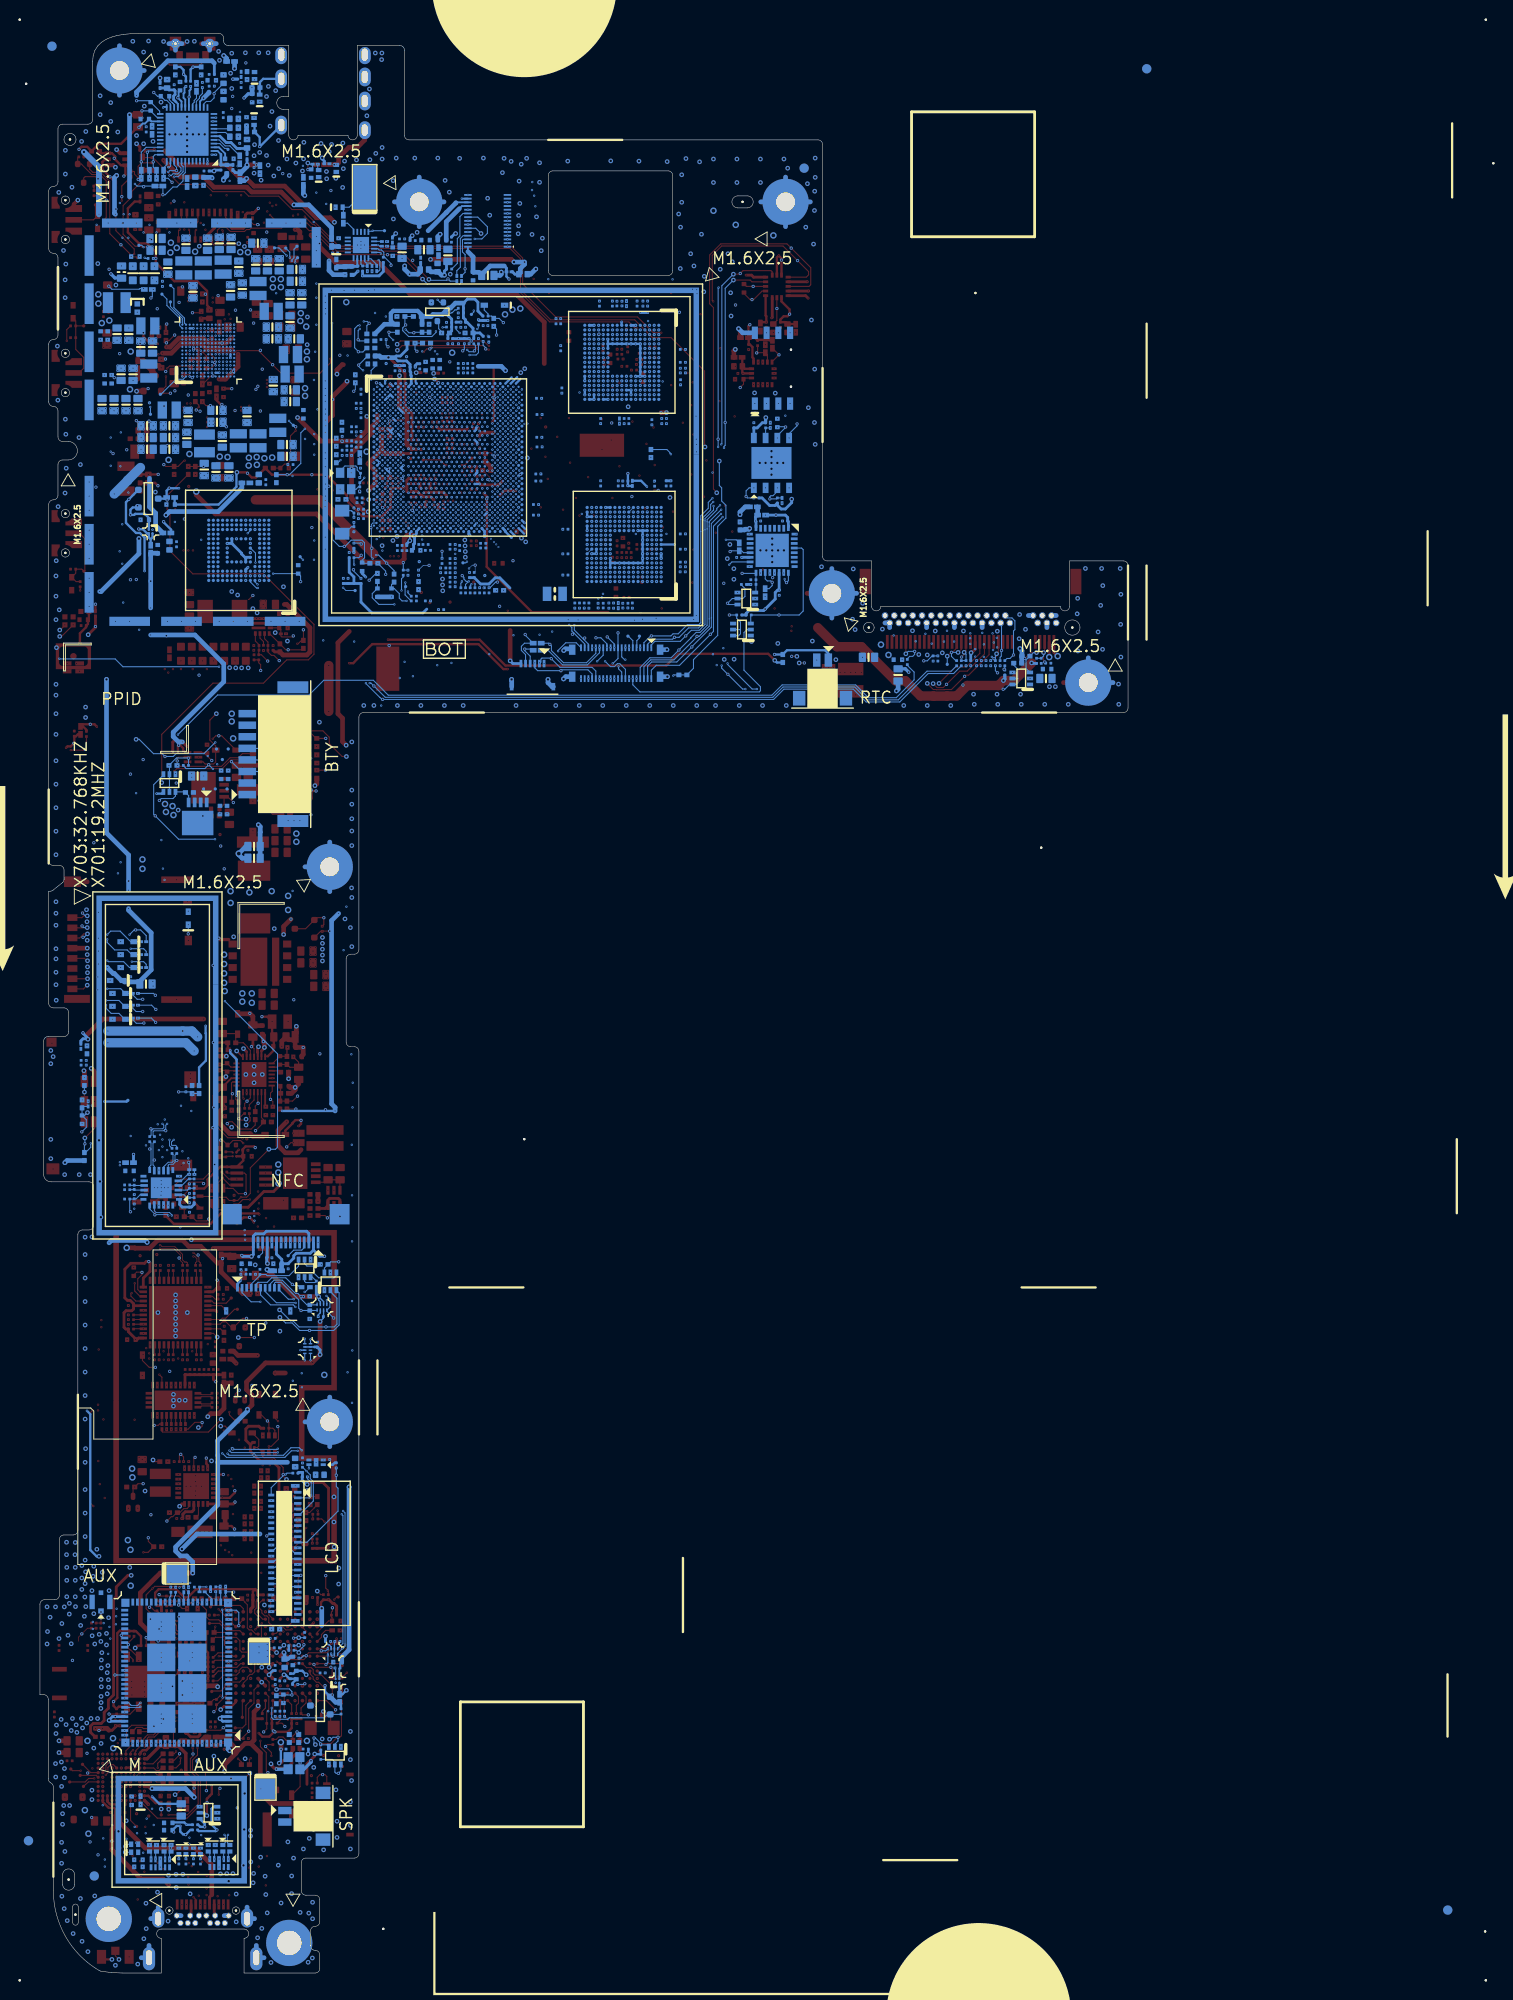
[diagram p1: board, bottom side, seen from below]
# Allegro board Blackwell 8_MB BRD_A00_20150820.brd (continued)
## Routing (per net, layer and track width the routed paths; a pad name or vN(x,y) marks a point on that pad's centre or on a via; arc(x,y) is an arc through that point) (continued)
LPDDR3_M1_DQS2_N_A: length 23.8
  L5 w0.06: 64.56,162.34 64.67,162.23 64.68,162.24 64.8,162.11 64.94,162.11 66.8,162.11 67.02,162.33 67.49,162.33 67.75,162.58 67.8,162.58 v8(67.86,162.64)
  L5 w0.066: 64.56,162.34 64.53,162.37 56.34,162.37 55.39,161.42 55.07,161.42 54.58,161.91 54.44,161.91 54.34,161.81 54.34,161.68 55,161.02 55,160.76 54.82,160.58 54.57,160.58 53.98,161.17 53.84,161.17 53.75,161.07 53.75,160.93 54.41,160.28 54.41,160.02 54.23,159.84 53.97,159.84 53.52,160.29 53.39,160.29 53.32,160.22 53.32,160.02 53.69,159.65 53.69,159.44 52.26,158.01 52.26,157.88 51.95,157.58 v8(51.95,157.38)
LPDDR3_M1_DQS2_N_B: length 15.5
  L7 w0.06: 66.66,154.73 66.66,154.73 66.72,154.79 66.73,154.79 67.69,155.76 67.69,155.77 67.7,155.77 67.7,156.2 67.86,156.36 v8(67.86,156.42)
  L7 w0.061: v8(57.47,155.89) 57.68,156.1 57.99,156.1 58.18,156.29 58.64,156.29 58.89,156.05 58.89,155.56 59.04,155.41 59.33,155.41 59.39,155.47 59.39,155.95 59.6,156.16 59.89,156.16 60.1,155.95 60.1,155.47 60.16,155.41 61.25,155.41 61.44,155.22 61.57,155.09 61.6,155.06 61.62,155.04 62.03,154.63 62.08,154.58 62.75,153.9 63.22,153.9 63.28,153.97 63.28,154.45 63.46,154.63 63.81,154.63 63.99,154.45 63.99,153.97 64.05,153.9 65.83,153.9 66.66,154.73
LPDDR3_M1_DQS2_P_A: length 23.8
  L5 w0.06: v8(68.14,162.93) 67.86,162.93 67.72,162.78 67.39,162.45 66.91,162.45 66.74,162.28 64.87,162.28 64.74,162.4 64.7,162.4 64.66,162.44
  L5 w0.066: v8(51.98,157.93) 53.55,159.5 53.55,159.59 53.18,159.96 53.18,160.28 53.33,160.43 53.58,160.43 54.03,159.98 54.17,159.98 54.26,160.08 54.26,160.22 53.61,160.87 53.61,161.13 53.79,161.31 54.04,161.31 54.63,160.72 54.76,160.72 54.86,160.82 54.86,160.96 54.2,161.62 54.2,161.87 54.38,162.05 54.63,162.05 55.12,161.56 55.33,161.56 56.28,162.52 64.59,162.52 64.66,162.44
LPDDR3_M1_DQS2_P_B: length 15.4
  L7 w0.06: 66.8,154.59 66.85,154.64 66.85,154.69 67.85,155.69 67.85,155.7 67.86,155.7 67.86,156.13 67.92,156.2 68.02,156.2 68.14,156.07 v8(68.14,156.06)
  L7 w0.061: 66.8,154.59 65.92,153.7 63.97,153.7 63.79,153.88 63.79,154.37 63.73,154.43 63.54,154.43 63.48,154.37 63.48,153.88 63.3,153.7 62.67,153.7 61.94,154.44 61.89,154.49 61.48,154.9 61.46,154.92 61.43,154.95 61.17,155.21 60.08,155.21 59.9,155.39 59.9,155.87 59.81,155.96 59.68,155.96 59.59,155.87 59.59,155.39 59.41,155.21 58.96,155.21 58.69,155.48 58.69,155.97 58.56,156.09 58.27,156.09 58.21,156.04 58.21,155.89 58.12,155.8 58.02,155.8 v8(57.95,155.87)
LPDDR3_M1_DQS3_N_A: length 16.9
  L5 w0.06: 65.37,160.29 65.82,160.74 67.7,160.74 67.86,160.89 v8(67.86,160.94)
  L5 w0.066: v8(55.97,157.4) 55.69,157.68 55.69,158.15 56.7,159.16 56.94,159.16 58.07,160.29 62.34,160.29 62.49,160.14 62.49,159.84 62.56,159.77 62.76,159.77 62.82,159.84 62.82,160.14 62.97,160.29 63.38,160.29 63.53,160.14 63.53,159.82 63.63,159.72 63.77,159.72 63.86,159.82 63.86,160.14 64.01,160.29 64.33,160.29 64.48,160.14 64.48,159.74 64.57,159.65 64.71,159.65 64.81,159.74 64.81,160.14 64.96,160.29 65.37,160.29
LPDDR3_M1_DQS3_N_B: length 21.5
  L7 w0.06: v8(69.03,156.38) 69.03,155.83 68.95,155.75
  L7 w0.061: v8(57.49,151.88) 57.8,152.19 58.04,152.19 58.17,152.31 59.69,152.31 59.81,152.43 59.81,153.66 60.01,153.86 60.31,153.86 60.51,153.66 60.51,152.37 60.6,152.28 60.83,152.28 60.92,152.37 60.92,152.86 61.13,153.07 61.42,153.07 61.63,152.86 61.63,152.38 61.69,152.31 62.14,152.31 62.32,152.14 62.32,151.72 62.41,151.63 62.54,151.63 62.63,151.72 62.63,152.22 62.83,152.42 63.13,152.42 63.33,152.22 63.33,151.7 63.39,151.63 63.57,151.63 63.64,151.7 63.64,152.24 63.84,152.45 64.14,152.45 64.34,152.24 64.34,151.7 64.41,151.63 64.59,151.63 64.65,151.7 64.65,152.14 64.83,152.31 65.86,152.31 67.66,154.12 67.66,154.34 68.76,155.45 68.76,155.45 68.95,155.64 68.95,155.75
LPDDR3_M1_DQS3_P_A: length 16.8
  L5 w0.06: 65.53,160.22 65.88,160.57 67.77,160.57 68.06,160.86 68.06,161.14 v8(68.14,161.23)
  L5 w0.066: v8(55.97,157.88) 55.93,157.84 55.86,157.84 55.83,157.86 55.83,158.09 56.76,159.01 57,159.01 58.13,160.15 62.28,160.15 62.35,160.08 62.35,159.78 62.5,159.63 62.81,159.63 62.96,159.78 62.96,160.08 63.03,160.15 63.32,160.15 63.39,160.08 63.39,159.76 63.57,159.58 63.83,159.58 64.01,159.76 64.01,160.08 64.07,160.15 64.27,160.15 64.34,160.08 64.34,159.68 64.52,159.5 64.77,159.5 64.95,159.68 64.95,160.08 65.02,160.15 65.46,160.15 65.53,160.22
LPDDR3_M1_DQS3_P_B: length 21.4
  L7 w0.061: v8(69.27,156.06) 69.37,156.06 69.44,155.99 69.44,155.82 69.39,155.77 69.2,155.77 69.15,155.72 69.15,155.56 68.96,155.37 68.96,155.36 67.86,154.26 67.86,154.03 65.94,152.11 64.91,152.11 64.85,152.05 64.85,151.61 64.67,151.43 64.32,151.43 64.14,151.61 64.14,152.16 64.05,152.25 63.93,152.25 63.84,152.16 63.84,151.61 63.66,151.43 63.31,151.43 63.13,151.61 63.13,152.14 63.04,152.22 62.91,152.22 62.83,152.14 62.83,151.63 62.63,151.43 62.32,151.43 62.12,151.63 62.12,152.05 62.06,152.11 61.61,152.11 61.43,152.29 61.43,152.78 61.34,152.87 61.21,152.87 61.12,152.78 61.12,152.28 60.92,152.08 60.52,152.08 60.31,152.28 60.31,153.57 60.22,153.66 60.1,153.66 60.01,153.57 60.01,152.35 59.78,152.11 58.25,152.11 58.2,152.06 58.2,151.93 58.13,151.87 58.02,151.87 v8(57.97,151.91)
LPDDR3_M1_ODT_A: length 19.2
  L2 w0.061: v10(54.26,157.23) 54.26,157.27 54.86,157.87 55.25,157.87 55.31,157.8 55.31,157.38 55.37,157.32 55.49,157.32 55.55,157.38 55.55,157.8 55.61,157.87 55.74,157.87 55.8,157.8 55.8,157.38 55.86,157.32 55.98,157.32 56.04,157.38 56.04,157.8 56.1,157.87 56.22,157.87 56.29,157.8 56.29,157.38 56.35,157.32 56.47,157.32 56.53,157.38 56.53,157.8 56.59,157.87 56.71,157.87 56.77,157.8 56.77,157.38 56.83,157.32 56.96,157.32 57.02,157.38 57.02,157.8 57.08,157.87 v10(59.85,157.87)
  L3SGND w0.127: v10(54.26,157.23) 54.26,156.82 v11(54.41,156.67) ; v10(59.85,157.87) 60.06,157.87 60.23,157.69 v11(60.28,157.69)
  L6SGND w0.127: v4(60.74,157.54) 60.43,157.54 v11(60.28,157.69) ; v11(54.41,156.67) 54.41,156.63 54.16,156.38 v5(53.97,156.38)
  L7 w0.06: 66.39,155.8 66.73,156.13 v8(66.73,156.42)
  L7 w0.061: v4(60.74,157.54) 61.91,156.37 61.91,156.15 62.27,155.8 66.39,155.8
LPDDR3_M1_ODT_B: length 18.1
  L2 w0.061: v10(56.12,153.96) 56.16,153.99 62.37,153.99 63.08,154.7 63.08,155.53 62.94,155.67 62.94,155.68 62.9,155.71 62.9,156.39 62.79,156.5 62.48,156.5 62.35,156.38 v10(62.35,156.24)
  L3SGND w0.127: v11(61.84,156.03) 62.04,156.24 v10(62.35,156.24) ; v11(55.6,153.62) 55.91,153.62 56.12,153.83 v10(56.12,153.96)
  L6SGND w0.127: v4(62.37,156.34) 62.34,156.34 62.32,156.32 62.17,156.32 61.99,156.13 61.93,156.13 v11(61.84,156.03) ; v8(56.47,153.88) 56.17,153.58 55.64,153.58 v11(55.6,153.62)
  L7 w0.06: v8(67.01,156.06) 66.94,156.13 66.94,156.48 66.93,156.5 66.93,156.5 66.81,156.62 66.65,156.62 66.53,156.5 66.52,156.5 66.23,156.21
  L7 w0.061: 66.23,156.21 62.52,156.21 62.38,156.34 v4(62.37,156.34)
LRESET#: length 3.7
  L2 w0.061: v9(100.06,32.48) 100.01,32.53 98.8,32.53 98.7,32.63 v9(96.44,32.63)
M0_ZQ0_A: length 2.9
  L7 w0.061: v5(48.4,172.92) 51.08,172.92 v5(51.22,173.06)
M0_ZQ0_B: length 2.9
  L7 w0.061: v5(51.93,180.16) 52.26,179.83 52.26,179.23 52.53,178.95 52.53,177.75 v8(52.72,177.57)
M0_ZQ1_A: length 3.5
  L7 w0.061: v5(51.72,173.06) 51.55,173.06 51.33,173.28 50.73,173.28 50.72,173.28 49.36,173.28 49.21,173.43 v5(48.37,173.43)
M0_ZQ1_B: length 3.4
  L7 w0.061: v8(52.72,177.06) 52.92,177.25 52.92,178.82 52.43,179.3 52.43,179.54 52.44,179.54 v5(52.44,180.16)
M1_ZQ0_A: length 3.2
  L7 w0.061: v5(56.12,148.05) 55.79,148.38 55.7,148.38 55.45,148.62 55.45,148.96 55.47,148.97 v5(55.47,150.88)
M1_ZQ0_B: length 3
  L7 w0.061: v8(50.97,152.39) 50.67,152.09 50.38,152.09 50.38,152.09 49.09,152.09 v5(48.42,151.42)
M1_ZQ1_A: length 3.6
  L7 w0.061: v5(55.47,151.38) 55.47,151.23 55.25,151.01 55.25,150.55 55.28,150.52 55.28,148.54 55.61,148.21 v5(55.61,148.05)
M1_ZQ1_B: length 3.5
  L7 w0.061: v8(51.45,152.37) 51.3,152.37 51.02,152.65 49.08,152.65 v5(48.4,151.96)
MC1CD#: length 64.7
  L3SGND w0.061: v10(101.58,111.58) 101.58,112.22 v11(101.46,112.34)
  L5 w0.076: v5(78.53,149.41) 78.53,146.11 80.22,144.42 83.6,144.42 85.06,142.95 85.06,140.67 86.79,138.94 86.79,137.56 90.28,134.07 94.66,134.07 v4(94.83,133.9)
  L6SGND w0.089: v11(101.46,112.34) 101.59,112.47 v5(101.59,113.29)
  L7 w0.061: v5(101.59,113.29) 101.97,113.67 101.97,120.21 101.97,120.21 101.97,120.97 105.51,124.51 105.51,131.04 103.62,132.93 103.62,133.7 102.67,134.65 102.05,134.65 101.08,133.68 98.54,133.68 97.54,132.68 95.88,132.68 94.83,133.73 v4(94.83,133.9)
  BOTTOM w0.114: v5(78.53,149.41) 78.53,150.68 78.35,150.87 R510.2 ; v5(101.59,113.29) v1(101.59,112.3)
MC1CK: length 82.9
  L5 w0.06: v8(76.91,158.12) 76.91,157.44 76.88,157.4 76.88,156.42 79.11,154.19
  L5 w0.076: 79.11,154.19 79.11,153.71 82.17,150.65 82.17,150.52 82.68,150.01 84.06,150.01 84.55,150.01 85.63,148.92 85.63,141.29 87.3,139.62 87.3,139.24 87.36,139.18 87.36,138.04 87.63,137.76 v4(87.69,137.76)
  L7 w0.061: v5(107.05,105.86) 108.08,106.9 108.08,108.74 108.61,109.27 108.61,110.17 108.62,110.18 108.62,111.32 108.61,111.33 108.61,113.75 109.47,114.61 109.47,120.24 109.47,120.55 109.81,120.88 109.81,131.6 108.36,133.04 108.36,137.71 107.48,138.6 88.84,138.6 88.06,137.82 87.75,137.82 v4(87.69,137.76)
  BOTTOM w0.114: v1(105.14,105.66) 105.35,105.86 R2305.1
MC1CK_B: length 10.1
  TOP w0.114: MSD1.5 112.79,109.65 112.53,109.39 v2(112.47,109.39)
  L5 w0.076: v2(112.47,109.39) 110.35,107.27 v5(110.35,106.37)
  BOTTOM w0.114: v5(110.35,106.37) 108.89,106.37 D2307.1 R2305.2 107.58,105.7 107.1,105.23 v1(106.51,105.23)
MC1CM_B: length 10.2
  TOP w0.114: MSD1.3 113.33,111.85 112.88,112.29 v2(112.48,112.29)
  L5 w0.076: v2(112.48,112.29) 111.24,111.05 111.24,110.31 v5(110.35,109.42)
  BOTTOM w0.114: v1(112.97,111.93) 112.84,111.93 v2(112.48,112.29) ; v5(110.35,109.42) 110.22,109.29 108.57,109.29 107.94,108.66 D2306.1 R2306.2
MC1CMD: length 76.6
  L5 w0.06: v8(77.48,156.98) 78.33,156.98 79.96,155.36 80.24,155.36 81.27,154.33 81.27,153.91
  L5 w0.076: v4(88.73,138.07) 88.64,138.16 88.64,139.77 86.65,141.77 86.65,142.38 86.65,142.38 86.65,147.25 86.65,147.25 86.65,147.63 86.65,147.63 86.65,149.25 84.7,151.2 83.58,151.2 81.27,153.51 81.27,153.91
  L7 w0.061: v4(88.73,138.07) 89.07,138.41 107.42,138.41 108.19,137.64 108.19,132.97 109.62,131.54 109.62,120.96 109.19,120.53 v5(109.19,118.84) 109.19,114.68 108.42,113.92 108.42,110.03 v5(107.68,109.29)
  BOTTOM w0.114: v5(107.68,109.29) 106.41,109.29 106.13,109.01 R2306.1
MC1DA0: length 84.5
  L5 w0.06: v8(77.2,158.4) 77.2,158.11 77.04,157.95 77.04,157.39 77,157.35 77,156.49 79.49,153.99
  L5 w0.076: v4(87.67,138.15) 87.55,138.26 87.55,139.26 87.49,139.32 87.49,139.7 85.83,141.36 85.83,148.51 85.83,149 84.63,150.2 84.3,150.2 84.14,150.2 83.98,150.2 82.75,150.2 82.4,150.56 82.4,150.74 79.49,153.65 79.49,153.99
  L7 w0.061: v4(87.67,138.15) 88.12,138.15 88.76,138.79 107.54,138.79 108.54,137.78 108.54,133.11 109.99,131.66 109.99,120.81 109.66,120.47 109.66,112.95 109.34,112.63 109.34,108.68 108.27,107.61 108.27,106.45 107.05,105.23 v5(107.05,104.59)
  BOTTOM w0.114: v1(105.09,104.13) 105.55,104.59 R2301.1
MC1DA0_B: length 9.6
  TOP w0.114: MSD1.7 v2(112.47,107.45)
  L5 w0.076: v2(112.47,107.45) 110.48,105.45 v5(110.48,105.1)
  BOTTOM w0.114: v5(110.48,105.1) 109.08,105.1 108.44,104.47 D2301.1 107.71,104.47 R2301.2 107.58,104.26 107.22,103.91 v1(106.51,103.91)
MC1DA1: length 84.5
  L5 w0.06: 77.18,156.52 77.16,156.54 77.16,157.18 77.2,157.21 v8(77.2,157.27)
  L5 w0.076: 77.18,156.52 77.18,156.51 82.62,151.07 82.62,150.6 82.81,150.41 84.68,150.41 86.02,149.08 86.02,148.75 86.02,141.57 87.84,139.75 v4(87.84,138.5)
  L7 w0.061: v4(87.84,138.5) 88.3,138.96 107.61,138.96 108.71,137.86 108.71,133.19 110.18,131.72 110.18,120.73 109.85,120.39 109.85,112.87 109.53,112.55 109.53,108.6 108.5,107.56 108.5,104.64 v5(107.05,103.2)
  BOTTOM w0.114: R2302.1 105.57,103.2 v1(105.12,102.74)
MC1DA1_B: length 10.1
  TOP w0.114: v2(112.51,106.75) 112.91,106.35 MSD1.8
  L5 w0.076: v5(110.48,104.59) 112.06,106.18 112.06,106.29 112.51,106.73 v2(112.51,106.75)
  BOTTOM w0.114: v5(110.48,104.59) 110.48,104.26 109.91,103.7 109.08,103.7 108.44,103.07 D2302.1 107.71,103.07 R2302.2 107.58,103.02 107.2,102.64 106.41,102.64 v1(106.39,102.66)
MC1DA2: length 77.5
  L5 w0.06: v8(76.63,158.96) 76.83,158.76 76.83,158.31 76.71,158.2 76.71,156.41 78.85,154.27 78.85,153.92
  L5 w0.076: 78.85,153.92 78.85,153.64 81.94,150.56 81.94,150.31 82.44,149.82 84.47,149.82 85.44,148.84 85.44,141.21 87.11,139.54 87.11,139.16 87.17,139.1 87.17,137.87 87.57,137.47 88.04,137.47 v4(88.1,137.54)
  L7 w0.061: v4(88.1,137.54) 88.28,137.36 88.78,137.36 89.46,138.03 107.3,138.03 107.84,137.49 107.84,132.82 109.24,131.42 109.24,121.12 108.55,120.42 108.55,114.57 107.94,113.96 v5(107.94,112.21)
  BOTTOM w0.114: v5(107.94,112.21) 107.43,112.72 v1(107.28,112.72) 106.74,112.72 106.13,112.11 R2303.1
MC1DA2_B: length 9.6
  TOP w0.114: v2(112.51,114.24) 112.89,114.24 113.08,114.05 MSD1.1
  L5 w0.076: v2(112.51,114.24) 112.38,114.24 v5(110.35,112.21)
  BOTTOM w0.114: R2303.2 D2303.1 107.81,111.45 108.95,112.59 109.97,112.59 v5(110.35,112.21) ; v1(113.02,114.55) 112.71,114.24 v2(112.51,114.24)
MC1DA3: length 76.9
  L5 w0.06: 81.17,153.23 81.14,153.26 81.14,154.29 80.19,155.24 79.91,155.24 78.36,156.78 77.4,156.78 77.28,156.9 77.28,157.07 77.4,157.18 77.4,157.35 77.28,157.47 77.28,157.8 77.48,158 v8(77.48,158.12)
  L5 w0.076: v4(88.68,137.66) 88.68,137.69 88.42,137.96 88.42,139.73 86.42,141.73 86.42,142.29 86.42,142.29 86.42,147.35 86.42,149.21 84.66,150.97 83.42,150.97 81.17,153.23
  L7 w0.061: v4(88.68,137.66) 88.73,137.66 89.29,138.22 107.36,138.22 108.01,137.57 108.01,132.9 109.43,131.48 109.43,121.04 108.9,120.51 v5(108.9,120.04) 108.9,114.66 108.23,113.99 108.23,111.11 v5(107.81,110.69)
  BOTTOM w0.114: R2304.1 106.13,110.41 106.41,110.69 v5(107.81,110.69)
MC1DA3_B: length 9.5
  TOP w0.114: v2(112.51,112.97) 113.02,112.97 113.04,112.95 MSD1.2
  L5 w0.076: v2(112.51,112.97) 111.75,112.97 110.48,111.7 v5(110.35,111.7)
  BOTTOM w0.114: v5(110.35,111.7) 110.35,111.37 109.54,110.56 108.19,110.56 107.68,110.05 D2304.1 R2304.2 ; v2(112.51,112.97) 112.89,112.97 v1(113.07,113.15)
MCSI_1_CLK_DN: length 26.8
  L5 w0.066: v5(67.08,189.35) 67.09,189.34 67.69,189.34 68.21,188.82 68.21,188.41 72.04,184.59 76.2,184.59 77.38,183.41 77.38,174.37 76.41,173.4 76.41,172.29 76.73,171.97 76.73,171.56 76.52,171.35 76.52,171 76.65,170.87 76.82,170.87 76.85,170.85 v8(77.2,170.85)
MCSI_1_CLK_DP: length 26.7
  L5 w0.066: v5(67.08,189.75) 67.13,189.75 67.4,189.48 67.75,189.48 68.35,188.88 68.35,188.47 72.1,184.73 76.26,184.73 77.53,183.46 77.53,174.31 76.56,173.34 76.56,172.34 76.87,172.03 76.87,171.51 76.66,171.29 76.66,171.06 76.7,171.01 76.8,171.01 v8(76.95,171.17)
MCSI_1_DATA0_DN: length 28.3
  L5 w0.066: v8(76.35,169.43) 75.68,169.43 75.48,169.64 75.48,173.73 76.51,174.77 76.51,179.6 73.12,182.99 70.43,182.99 67.67,185.75 67.67,185.96 68.12,186.41 68.12,186.5 68,186.62 67.91,186.62 67.46,186.17 67.25,186.17 66.65,186.76 66.65,187.53 66.91,187.79 67.53,187.79 67.63,187.88 67.63,188.08 67.56,188.15 v5(67.08,188.15)
MCSI_1_DATA0_DP: length 28.2
  L5 w0.066: v8(76.07,169.72) 76.07,169.63 76.01,169.58 75.74,169.58 75.62,169.7 75.62,173.68 76.65,174.71 76.65,179.66 73.18,183.13 70.49,183.13 67.81,185.81 67.81,185.9 68.26,186.35 68.26,186.56 68.06,186.76 67.85,186.76 67.4,186.31 67.31,186.31 66.8,186.82 66.8,187.47 66.97,187.64 67.59,187.64 67.77,187.82 67.77,188.14 67.62,188.29 67.35,188.29 67.09,188.55 v5(67.08,188.55)
MCSI_1_DATA1_DN: length 26.4
  L5 w0.066: v8(76.07,171.49) 76.11,171.44 76.23,171.44 76.33,171.55 76.33,171.83 76.07,172.1 76.07,173.69 76.95,174.57 76.95,183.11 76.04,184.02 71.27,184.02 70.2,185.09 70.11,185.09 69.91,184.89 69.7,184.89 69.5,185.09 69.5,185.3 69.7,185.5 69.7,185.59 69.49,185.8 69.4,185.8 68.92,185.33 68.71,185.33 68.51,185.53 68.51,185.74 68.99,186.21 68.99,186.31 68.09,187.21 67.36,187.21 67.32,187.17 67.32,186.99 67.25,186.91 67.12,186.91 v5(67.08,186.95)
MCSI_1_DATA1_DP: length 26.6
  L5 w0.06: v8(76.31,171.17) 76.39,171.24
  L5 w0.066: 76.39,171.24 76.39,171.24 76.39,171.4 76.48,171.49 76.48,171.89 76.21,172.16 76.21,173.63 77.09,174.51 77.09,183.16 76.09,184.16 71.33,184.16 70.26,185.23 70.05,185.23 69.85,185.03 69.76,185.03 69.64,185.15 69.64,185.24 69.84,185.44 69.84,185.65 69.55,185.95 69.34,185.95 68.86,185.47 68.77,185.47 68.65,185.58 68.65,185.68 69.13,186.15 69.13,186.37 68.14,187.35 v5(67.08,187.35)
MCSI_2_CLK_DN: length 43.1
  TOP w0.102: CAMF1.17 v9(101.74,189.02)
  L2 w0.061: v10(92.32,190.47) 92.44,190.47 93.3,191.33 99.3,191.33 101.61,189.02 v9(101.74,189.02)
  L3SGND w0.127: v11(91.9,190.57) 92.22,190.57 v10(92.32,190.47)
  L5 w0.066: v8(77.48,169.43) 77.51,169.43 77.59,169.35 77.89,169.35 78.16,169.62 78.16,170.78 81.96,174.58 81.96,179.45 83.13,180.61 83.13,183.3 87.51,187.69 91.74,187.69 92.65,188.59 92.65,190.01 92.32,190.34 92.13,190.34 v11(91.9,190.57)
MCSI_2_CLK_DP: length 43.1
  TOP w0.102: CAMF1.16 101.44,188.32 v9(101.51,188.39)
  L2 w0.061: v10(92.32,190.09) 92.35,190.09 93.39,191.13 99.22,191.13 101.51,188.84 v9(101.51,188.39)
  L3SGND w0.127: v11(91.9,189.96) 92.19,189.96 v10(92.32,190.09)
  L5 w0.06: 77.85,169.52 77.68,169.52 77.48,169.72 v8(77.2,169.72)
  L5 w0.066: 77.85,169.52 78.01,169.68 78.01,170.84 81.82,174.64 81.82,179.51 82.98,180.67 82.98,183.36 87.46,187.83 91.68,187.83 92.5,188.65 92.5,189.95 92.26,190.2 92.13,190.2 v11(91.9,189.96)
MCSI_2_DATA0_DN: length 42.4
  TOP w0.102: v9(100.75,188.36) 100.84,188.27 CAMF1.14
  L2 w0.061: v9(100.75,188.36) 100.53,188.58 99.99,188.58 97.97,190.6 94.48,190.6 v10(94.37,190.49)
  L3SGND w0.127: v11(93.94,190.33) 94.21,190.33 v10(94.37,190.49)
  L5 w0.066: v11(93.94,190.33) 93.85,190.25 92.85,190.25 91.56,191.54 91.42,191.54 91.17,191.28 91.17,191.19 91.47,190.89 91.47,190.67 91.27,190.48 91.06,190.48 90.76,190.78 90.67,190.78 90.03,190.14 90.03,190.05 90.32,189.75 90.32,189.54 90.12,189.34 89.91,189.34 89.62,189.64 89.52,189.64 89.41,189.52 89.41,189.43 89.61,189.22 89.61,189.01 89.43,188.83 89.18,188.83 89.09,188.93 89,189.02 88.9,189.02 88.53,188.64 87.01,188.64 82.23,183.87 82.23,181 80.75,179.51 80.75,174.63 79.55,173.44 78.8,173.44 77.34,171.97 77.34,171.79 77.34,171.79 77.34,171.69 77.48,171.55 v8(77.48,171.13)
MCSI_2_DATA0_DP: length 42.4
  TOP w0.102: v9(100.65,189.17) 100.54,189.28 CAMF1.13
  L2 w0.061: v10(93.84,190.8) 98.06,190.8 100.07,188.78 100.48,188.78 100.65,188.95 v9(100.65,189.17)
  L3SGND w0.127: v11(93.46,190.62) 93.64,190.8 v10(93.84,190.8)
  L5 w0.066: v11(93.46,190.62) 93.22,190.39 92.9,190.39 91.61,191.68 91.37,191.68 91.03,191.34 91.03,191.13 91.33,190.83 91.33,190.73 91.21,190.62 91.12,190.62 90.82,190.92 90.61,190.92 89.88,190.2 89.88,189.99 90.18,189.69 90.18,189.6 90.06,189.48 89.97,189.48 89.67,189.78 89.46,189.78 89.26,189.58 89.26,189.37 89.47,189.16 89.47,189.07 89.37,188.97 89.24,188.97 89.06,189.16 88.84,189.16 88.47,188.78 86.95,188.78 82.09,183.93 82.09,181.06 80.61,179.57 80.61,174.69 79.49,173.58 78.74,173.58 77.2,172.03 77.2,171.73 77.2,171.73 v8(77.2,171.49)
MCSI_2_DATA1_DN: length 42.9
  TOP w0.102: v9(102.5,188.41) 102.64,188.27 CAMF1.20
  L2 w0.061: v10(91.2,190.37) 91.1,190.47 91.1,190.57 92.15,191.62 100.43,191.62 102.04,190.01 102.04,189.1 102.5,188.64 v9(102.5,188.41)
  L3SGND w0.127: v10(91.2,190.37) 91.3,190.27 v11(91.3,189.96)
  L5 w0.066: v11(91.3,189.96) 91.09,189.75 91.09,189.62 89.6,188.13 87.16,188.13 85.08,186.05 82.69,183.66 82.69,180.79 81.27,179.37 81.27,174.37 77.76,170.86 v8(77.76,169.72)
MCSI_2_DATA1_DP: length 42.9
  TOP w0.102: CAMF1.19 102.34,189.26 102.42,189.17 v9(102.55,189.17)
  L2 w0.061: v10(90.82,190.37) 90.9,190.45 90.9,190.65 92.07,191.82 92.16,191.82 92.16,191.82 100.51,191.82 102.24,190.09 102.24,189.18 102.33,189.1 102.48,189.1 v9(102.55,189.17)
  L3SGND w0.127: v10(90.82,190.37) 90.74,190.29 v11(90.74,189.96)
  L5 w0.066: v8(77.48,170) 77.62,170.14 77.62,170.92 81.12,174.42 81.12,179.43 82.55,180.85 82.55,183.72 84.93,186.11 87.1,188.27 89.54,188.27 90.94,189.68 90.94,189.76 v11(90.74,189.96)
MCSI_COMP: length 5.1
  L7 w0.06: v8(76.63,169.15) 76.71,169.23 77,169.23 77.4,169.63 77.4,169.8 77.28,169.92 77.28,170.08 77.93,170.73 77.93,170.85 77.96,170.88 77.96,171.55 77.85,171.67 77.85,171.88 78.12,172.15 78.12,172.79 78.22,172.89 v5(78.22,173.2)
MDSI_A_CLKN_A: length 10.5
  L2 w0.061: v9(93.74,50.21) 93.88,50.36 93.88,50.55 93.76,50.67 93.59,50.67 93.39,50.47 93.39,45.51 v2(91.51,43.63)
  BOTTOM w0.102: LCD1.29 90.62,43.55 90.74,43.43 91.31,43.43 v2(91.51,43.63)
MDSI_A_CLKP_A: length 10.6
  L2 w0.061: v2(90.92,43.86) 91.16,43.86 91.34,44.04 91.64,44.04 93.19,45.6 93.19,50.56 93.51,50.87 93.64,50.87 v9(93.74,50.97)
  BOTTOM w0.102: LCD1.28 92.2,43.85 91.93,44.11 91.17,44.11 v2(90.92,43.86)
MDSI_A_DN_0_A: length 11.4
  L2 w0.061: v2(91.53,46.12) 91.4,46.25 91.4,46.55 92.41,47.56 92.41,51.68 92.41,53.89 92.58,54.05 92.82,54.05 93,53.87 v9(93,53.52)
  BOTTOM w0.102: LCD1.23 90.05,45.35 90.56,45.87 91.27,45.87 v2(91.53,46.12)
MDSI_A_DN_1_A: length 10.8
  L2 w0.061: v2(91.53,45.25) 91.74,45.46 92.42,45.46 92.9,45.94 92.9,51.89 93.26,52.24 93.91,52.24 94.02,52.13 94.02,51.98 93.91,51.87 v9(93.74,51.87)
  BOTTOM w0.102: LCD1.26 92.33,44.45 v2(91.53,45.25)
MDSI_A_DN_2_A: length 9.9
  L2 w0.061: v2(91.5,42.72) 91.55,42.67 91.83,42.67 93.88,44.72 93.88,48.5 94.39,49 94.78,49 94.91,48.88 94.91,48.66 v9(94.78,48.54)
  BOTTOM w0.102: v2(91.5,42.72) 91.57,42.65 LCD1.32
MDSI_A_DN_3_A: length 9.6
  L2 w0.061: v9(94.78,46.94) 94.83,46.94 94.93,47.04 94.93,47.19 94.83,47.29 94.5,47.29 94.37,47.16 94.37,44.52 91.86,42 91.6,42 91.5,41.9 v2(91.5,41.73)
  BOTTOM w0.102: v2(91.5,41.73) 91.4,41.63 90.49,41.63 90.36,41.75 LCD1.35
MDSI_A_DP_0_A: length 11.4
  L2 w0.061: v2(90.92,46.35) 92.21,47.65 92.21,51.6 92.21,53.97 92.49,54.25 92.98,54.25 v9(93,54.27)
  BOTTOM w0.102: v2(90.92,46.35) 91.12,46.55 91.71,46.55 91.96,46.3 91.96,46.1 92.41,45.65 LCD1.22
MDSI_A_DP_1_A: length 10.9
  L2 w0.061: v9(93.74,52.62) 93.56,52.44 93.18,52.44 92.7,51.97 92.7,46.03 92.34,45.66 91.36,45.66 91.13,45.44 v2(90.92,45.44)
  BOTTOM w0.102: LCD1.25 90.44,44.75 90.92,45.23 v2(90.92,45.44)
MDSI_A_DP_2_A: length 9.9
  L2 w0.061: v9(94.78,49.29) 94.69,49.2 94.3,49.2 93.68,48.59 93.68,44.8 92.01,43.13 91.33,43.13 91.17,42.97 v2(90.92,42.97)
  BOTTOM w0.102: v2(90.92,42.97) 90.9,42.95 LCD1.31
MDSI_A_DP_3_A: length 9.5
  L2 w0.061: v9(94.78,47.69) 94.58,47.49 94.42,47.49 94.17,47.25 94.17,44.6 91.77,42.2 91.05,42.2 90.92,42.07 v2(90.92,42.06)
  BOTTOM w0.102: v2(90.92,42.06) 91.02,42.16 91.88,42.16 91.99,42.05 LCD1.34
MDSI_C_CLK_DN: length 157.7
  L2 w0.061: v9(94.47,50.21) 94.47,50.46 94.6,50.59 95.17,50.59 95.41,50.84 95.41,52.22 95.41,54.19 98.28,57.06 106.69,57.06 106.92,57.3 111.62,57.3 111.8,57.48 v10(111.92,57.48)
  L3SGND w0.127: v10(111.92,57.48) 112.28,57.48 v11(112.46,57.3)
  L5 w0.066: v11(112.46,57.3) 112.13,57.63 111.67,57.63 111.46,57.84 111.46,78.18 109.98,79.66 109.98,88.18 109.98,93.84 108.88,94.93 108.88,112.43 109.22,112.77 110.73,114.28 110.73,121.1 111.67,122.04 111.67,130.87 111.67,136.69 110.36,138 110.2,138 110.2,138 109.6,138 109.32,138 108.41,138.92 108.41,150.16 98.1,160.47 94.04,160.47 83.42,171.09 80.53,171.09 80.48,171.14 80.32,171.14 v8(80.31,171.13)
MDSI_C_CLK_DP: length 157.7
  L2 w0.061: v10(111.92,57.88) 111.54,57.5 106.84,57.5 106.6,57.26 98.2,57.26 95.21,54.27 95.21,52.14 95.21,52.14 95.21,50.92 95.09,50.79 94.6,50.79 94.47,50.92 v9(94.47,50.97)
  L3SGND w0.127: v10(111.92,57.88) 112,57.96 v11(112.43,57.96)
  L5 w0.066: v8(80.03,171.41) 80.41,171.41 80.59,171.23 83.48,171.23 94.1,160.61 98.15,160.61 108.55,150.21 108.55,138.98 109.38,138.15 109.54,138.15 110.42,138.15 111.81,136.75 111.81,134.55 111.82,134.55 111.82,130.81 111.81,130.81 111.81,121.99 110.87,121.04 110.87,114.22 109.28,112.63 109.03,112.37 109.03,94.99 110.12,93.89 110.12,88.18 110.12,79.72 111.6,78.24 111.6,57.92 111.7,57.83 112.3,57.83 v11(112.43,57.96)
MDSI_C_DATA0_DN: length 156.4
  L2 w0.061: v10(111.92,58.69) 111.7,58.69 111.51,58.87 106.37,58.87 105.53,58.04 97.88,58.04 94.43,54.6 94.43,54.03 94.2,53.79 93.86,53.79 93.74,53.67 v9(93.74,53.51)
  L3SGND w0.127: v10(111.92,58.69) 112.05,58.57 v11(112.43,58.57)
  L5 w0.066: v11(112.43,58.57) 112.18,58.82 112.04,58.82 111.9,58.97 111.9,78.38 110.46,79.82 110.46,88.38 110.46,88.38 110.46,94.12 109.32,95.26 109.32,112.25 111.17,114.1 111.17,120.88 112.11,121.82 112.11,130.69 112.11,136.93 110.55,138.49 109.55,138.49 108.89,139.15 108.89,150.29 98.28,160.9 94.22,160.9 83.51,171.62 79.94,171.62 79.46,171.14 v8(79.46,170.85)
MDSI_C_DATA0_DP: length 156.3
  L2 w0.061: v10(111.87,59.08) 106.28,59.08 105.45,58.24 97.79,58.24 94.23,54.68 94.23,54.11 94.12,53.99 93.84,53.99 93.74,54.1 v9(93.74,54.27)
  L3SGND w0.127: v11(112.43,59.2) 112.3,59.08 v10(111.87,59.08)
  L5 w0.066: v8(79.22,171.17) 79.29,171.17 79.88,171.76 83.57,171.76 94.28,161.05 98.34,161.05 109.03,150.35 109.03,139.21 109.61,138.63 110.61,138.63 112.17,137.07 112.25,136.99 112.25,134.73 112.25,130.68 112.25,130.68 112.25,121.76 111.31,120.82 111.31,114.04 109.46,112.19 109.46,95.32 110.6,94.18 110.6,88.32 110.6,79.88 112.04,78.44 112.04,59.02 112.1,58.96 112.19,58.96 v11(112.43,59.2)
MDSI_C_DATA1_DN: length 156.6
  L2 w0.061: v9(94.47,51.86) 94.47,52.22 94.6,52.35 94.71,52.35 94.92,52.56 94.92,54.39 98.08,57.55 106.13,57.55 106.39,57.81 110.43,57.81 v10(110.56,57.93)
  L3SGND w0.127: v11(110.02,57.7) 110.25,57.93 v10(110.56,57.93)
  L5 w0.066: v11(110.02,57.7) 109.98,57.74 109.37,57.74 109.17,57.95 109.17,58.55 110.15,59.54 110.15,72.78 110.08,72.84 109.76,72.84 109.61,72.99 109.61,73.31 109.76,73.46 110.08,73.46 110.15,73.52 110.15,73.82 110.08,73.88 109.69,73.88 109.54,74.03 109.54,74.35 109.69,74.5 110.08,74.5 110.15,74.57 110.15,74.76 110.08,74.83 109.69,74.83 109.54,74.98 109.54,75.29 109.69,75.44 110.08,75.44 110.15,75.51 110.15,75.71 110.08,75.77 109.69,75.77 109.54,75.92 109.54,76.24 109.69,76.39 110.08,76.39 110.15,76.46 110.15,77.41 108.38,79.18 108.38,93.5 107.57,94.31 107.57,112.98 108.68,114.08 108.68,114.08 109.4,114.8 109.4,121.73 110.36,122.69 110.36,131.42 110.36,135.61 109.85,136.12 109.36,136.62 108.86,136.62 106.94,138.53 106.94,149.76 97.55,159.16 93.5,159.16 82.94,169.72 v8(80.03,169.72)
MDSI_C_DATA1_DP: length 156.7
  L2 w0.061: v10(110.53,58.31) 110.22,58.01 106.3,58.01 106.05,57.75 98,57.75 94.72,54.48 94.72,52.64 94.63,52.55 94.55,52.55 v9(94.47,52.62)
  L3SGND w0.127: v10(110.53,58.31) v11(110.02,58.31)
  L5 w0.066: v8(79.74,170) 80.09,170 80.23,169.86 83,169.86 93.56,159.3 97.61,159.3 107.09,149.82 107.09,138.59 108.91,136.76 109.42,136.76 109.91,136.26 110.5,135.67 110.5,134.07 110.5,122.63 109.54,121.67 109.54,114.74 108.74,113.94 107.72,112.92 107.72,94.37 108.53,93.56 108.53,79.24 110.29,77.47 110.29,76.4 110.14,76.25 109.74,76.25 109.68,76.18 109.68,75.98 109.74,75.92 110.14,75.92 110.29,75.77 110.29,75.45 110.14,75.3 109.74,75.3 109.68,75.24 109.68,75.04 109.74,74.97 110.14,74.97 110.29,74.82 110.29,74.51 110.14,74.36 109.74,74.36 109.68,74.29 109.68,74.09 109.74,74.03 110.14,74.03 110.29,73.88 110.29,73.46 110.14,73.32 109.82,73.32 109.75,73.25 109.75,73.05 109.82,72.99 110.14,72.99 110.29,72.84 110.29,59.48 109.31,58.49 109.31,58.01 109.43,57.89 109.67,57.89 110.02,58.24 v11(110.02,58.31)
MDSI_C_DATA2_DN: length 157.9
  L2 w0.061: v9(95.52,48.53) 95.9,48.92 95.9,52.43 95.9,53.99 98.49,56.57 110.16,56.57 110.42,56.31 111.37,56.31 v10(111.39,56.33)
  L3SGND w0.127: v11(110.86,56.23) 110.96,56.33 v10(111.39,56.33)
  L5 w0.066: v11(110.86,56.23) 111.02,56.39 111.31,56.39 111.52,56.6 111.52,57.12 111.17,57.47 111.17,77.94 109.63,79.48 109.63,88.06 109.63,93.76 108.59,94.81 108.59,112.56 109.1,113.07 110.42,114.38 110.42,121.22 111.38,122.18 111.38,131.04 111.38,131.04 111.38,134.34 111.38,136.12 109.79,137.71 109.2,137.71 108.11,138.8 108.11,150.03 97.97,160.17 93.92,160.17 83.31,170.78 80.1,170.78 v8(80.03,170.85)
MDSI_C_DATA2_DP: length 157.8
  L2 w0.061: v9(95.52,49.3) 95.7,49.48 95.7,52.34 95.7,54.07 98.4,56.77 110.24,56.77 110.5,56.51 111.16,56.51 v10(111.37,56.71)
  L3SGND w0.127: v11(110.83,56.79) 110.91,56.71 v10(111.37,56.71)
  L5 w0.066: v8(79.74,171.13) 79.67,171.05 79.67,170.76 79.79,170.64 83.25,170.64 93.86,160.03 97.91,160.03 107.97,149.97 107.97,138.74 109.14,137.57 109.73,137.57 111.24,136.07 111.24,134.31 111.24,122.24 110.27,121.28 110.27,114.44 109.04,113.21 108.45,112.61 108.45,94.75 109.49,93.71 109.49,88.11 109.49,79.42 111.02,77.88 111.02,57.41 111.38,57.06 111.38,56.66 111.25,56.54 111.08,56.54 110.83,56.79 v11(110.83,56.79)
MDSI_C_DATA3_DN: length 159.2
  L2 w0.061: v9(95.52,46.93) 95.52,47.09 95.92,47.5 96.08,47.5 96.39,47.81 96.39,52.63 96.39,53.78 98.69,56.08 109.1,56.08 109.92,55.27 110.25,55.27 v10(110.37,55.14)
  L3SGND w0.127: v10(110.37,55.14) 110.81,55.14 v11(110.88,55.06)
  L5 w0.066: v11(110.88,55.06) 110.23,55.71 110.23,57.01 110.59,57.36 110.59,77.61 108.89,79.31 108.89,79.43 108.89,93.69 108.01,94.57 108.01,112.8 108.86,113.65 109.84,114.62 109.84,121.55 110.8,122.51 110.8,131.23 110.8,131.23 110.8,134.19 110.8,134.19 110.8,135.87 109.54,137.13 108.96,137.13 107.53,138.56 107.53,138.92 107.53,149.79 97.73,159.59 93.68,159.59 83.07,170.2 79.66,170.2 79.39,169.93 79.39,169.79 v8(79.46,169.72)
MDSI_C_DATA3_DP: length 159.2
  L2 w0.061: v9(95.52,47.7) 95.99,47.7 96.19,47.9 96.19,52.55 96.19,53.87 98.61,56.28 109.19,56.28 110,55.47 110.27,55.47 v10(110.35,55.54)
  L3SGND w0.127: v10(110.35,55.54) 110.78,55.54 v11(110.86,55.62)
  L5 w0.066: v8(79.18,169.43) 79.18,169.92 79.6,170.34 83.13,170.34 93.74,159.74 97.79,159.74 107.68,149.85 107.68,138.86 107.68,138.62 109.02,137.27 109.6,137.27 110.94,135.93 110.94,134.25 110.94,122.45 109.98,121.49 109.98,114.56 108.92,113.5 108.15,112.74 108.15,94.63 109.03,93.75 109.03,79.37 110.73,77.67 110.73,57.3 110.38,56.95 110.38,55.77 110.58,55.57 110.81,55.57 v11(110.86,55.62)
MDSI_COMP: length 4.6
  L7 w0.06: v5(78.73,173.15) 78.25,172.67 78.25,171.25 78.17,171.17 78.17,170.92 78.05,170.8 78.05,170.29 77.56,169.8 77.56,169.63 77.73,169.47 77.73,169.3 77.76,169.27 v8(77.76,169.15)
MIC_CAP: length 3.7
  BOTTOM w0.114: U2001.14 99.91,201.98 99.64,202.26 99.17,202.26 98.79,202.64 v1(98.79,203.09) 98.79,203.19 C2006.1
MICBIAS1:
  vias: v1(96.79,202.8)
MIPI_BKLT_EN: length 11.9
  L5 w0.076: v5(105.37,185.29) 105.37,185 105.59,184.78 105.59,182.74 105.66,182.66 105.66,181.35 104.31,179.99 104.31,178.62 102.4,176.72 101.44,176.72 101.42,176.74 100.83,176.74 v8(100.63,176.53)
MIPI_PANEL_EN: length 10.2
  L5 w0.076: v5(105.37,181.94) 105.24,181.81 105.24,181.12 104.16,180.04 104.16,179.44 104.17,179.43 104.17,178.68 102.4,176.91 100.57,176.91 100.49,176.83 100.49,176.69 100.42,176.62 100.42,176.24 100.53,176.13 v5(100.63,176.13)
  BOTTOM w0.114: v1(105.62,181.02) 105.47,181.17 PR5107.2 v5(105.37,181.94)
MODEM_PWR_ON: length 6.1
  L7 w0.06: v8(70.97,170.85) 70.97,173.97 70.38,174.56 70.38,174.83 69.15,176.06 69.15,176.12 v5(69.1,176.17)
MODEM_PWR_ON_R: length 118.3
  TOP w0.114: NGFF1.6 9.02,142.8 v2(9.13,142.69) 9.13,141.8 v1(9,141.68)
  L5 w0.076: v4(52.18,145.36) 51.33,145.36 51.1,145.13 47.25,145.13 43.99,148.39 36.5,148.39 27.32,139.21 24.57,139.21 24.19,138.83 18.63,138.83 18.34,139.12 12.7,139.12 11.71,140.11 11.71,141.71 11.15,142.27 9.55,142.27 v2(9.13,142.69)
  L7 w0.061: v4(52.18,145.36) 50.86,145.36 45.29,150.93 45.29,152.92 45.92,153.55 45.92,153.79 46.1,153.96 46.1,160.16 45.92,160.34 45.92,161.6 45.17,162.36 45.17,164.94 45.89,165.65 46.02,165.65 47.37,167 47.57,167.2 47.57,167.66 47.57,167.66 47.57,168.43 47.57,168.43 47.57,168.98 47.57,168.98 47.57,178.54 50.01,180.98 61.6,180.98 62.47,180.98 62.76,180.98 63.05,180.98 66.24,180.98 67.27,179.95 67.37,179.95 67.88,179.43 67.88,178.12 68.44,177.57 68.57,177.57 v5(69.2,176.93)
  BOTTOM w0.114: v2(9.13,142.69) 9.13,142.34 R4003.1 R4018.1 ; R4010.1 v5(69.2,176.93)
MODEM_SLPCLK: length 85
  L2 w0.061: v10(43.65,166.72) 43.65,166.74 45.53,168.62 45.53,174.5 47.07,176.04 47.37,176.04 48.39,177.06 48.43,177.06 50.46,179.1 64.57,179.1 65.56,178.11 69.93,178.11 v10(70.95,177.09)
  L3SGND w0.127: v11(43.27,166.72) v10(43.65,166.72) ; v11(71.34,177.09) v10(70.95,177.09)
  L5 w0.076: v11(43.27,166.72) 43.27,166.11 43.05,165.89 43.05,158.56 43.04,158.55 43.04,157.84 42.88,157.68 42.88,155.48 43.95,154.4 43.95,150.95 48.58,146.32 53.86,146.32 54.44,145.74 54.44,144.9 54.77,144.57 54.77,143.12 54.01,142.36 54.01,141.76 56.48,139.29 58.51,139.29 59.12,139.9 v5(59.14,139.9)
  L6SGND w0.127: v11(71.34,177.09) 71.34,177.06 71.64,176.75 v4(71.67,176.75)
  L7 w0.06: 72.45,173.81 72.45,172.72 72.15,172.41 72.15,170.89 v8(72.1,170.85)
  L7 w0.061: 72.45,173.81 72.45,174.24 72.3,174.39 72.02,174.67 72.02,175.74 71.74,176.02 v5(71.74,176.07) 71.74,176.6 71.67,176.68 v4(71.67,176.75)
  BOTTOM w0.114: v5(71.74,176.07) 71.74,175.48 v1(71.92,175.31)
MUX_AUXN: length 66.8
  TOP w0.102: R3022.2 107.48,69.62 v10(106.45,69.62)
  L2 w0.061: v9(106.83,19.65) 106.73,19.65 105.93,18.86 105.64,18.86 105.17,18.39 103.75,18.39 102.28,16.92 v10(102.07,16.92)
  L3SGND w0.127: v11(101.54,16.68) 101.71,16.86 101.74,16.86 101.8,16.92 v10(102.07,16.92) ; v10(106.45,69.62) v11(105.95,69.62)
  L5 w0.066: v11(105.95,69.62) 106.18,69.84 106.81,69.84 107.58,69.08 107.58,60.93 106.97,60.32 106.97,53.14 107.62,52.49 107.62,47.84 107.13,47.36 107.13,37.11 104.14,34.12 104.14,23.12 100.3,19.29 100.3,17.49 100.85,16.94 101.28,16.94 v11(101.54,16.68)
MUX_AUXN_ST: length 1.1
  TOP w0.102: U3102.29 107.49,70.62 C3010.1
MUX_AUXP: length 66.1
  TOP w0.102: v10(106.45,70.12) 107.48,70.12 R3021.2
  L2 w0.061: v9(106.32,19.65) 106.32,19.53 105.85,19.06 105.56,19.06 105.09,18.59 103.67,18.59 102.37,17.29 v10(101.99,17.29)
  L3SGND w0.127: v10(106.45,70.12) 106.04,70.12 105.98,70.18 v11(105.98,70.18) ; v10(101.99,17.29) 101.6,17.29 v11(101.57,17.26)
  L5 w0.066: v11(105.98,70.18) 106.17,69.99 106.87,69.99 107.72,69.13 107.72,60.87 107.12,60.26 107.12,53.19 107.76,52.55 107.76,47.78 107.28,47.3 107.28,37.05 104.28,34.06 104.28,23.07 100.44,19.23 100.44,17.54 100.91,17.08 101.39,17.08 v11(101.57,17.26)
MUX_AUXP_ST: length 1.1
  TOP w0.102: U3102.30 107.5,71.12 C3009.1
MUX_ML0N: length 6.4
  L3SGND w0.127: v10(105.44,63.53) 105.44,64.07 v11(105.49,64.13) ; v11(104.94,65.81) 104.74,66.01 v10(104.74,66.26)
  L5 w0.066: v11(105.49,64.13) 105.45,64.18 105.45,64.61 105.73,64.89 106.18,64.89 106.4,65.11 106.4,66.35 106.11,66.64 105.29,66.64 105.17,66.64 104.97,66.45 104.97,65.84 v11(104.94,65.81)
MUX_ML0N_ST: length 1.1
  TOP w0.102: U3102.22 104.71,66.85 C3012.2
MUX_ML0P: length 6.3
  L3SGND w0.127: v11(105.5,65.84) 105.24,66.09 v10(105.24,66.26) ; v10(104.94,63.53) 105.09,63.69 105.09,64 v11(104.94,64.15)
  L5 w0.066: v11(105.5,65.84) 105.47,65.84 105.12,66.19 105.12,66.39 105.23,66.5 106.05,66.5 106.26,66.29 106.26,65.17 106.12,65.03 105.67,65.03 105.3,64.67 105.3,64.5 104.96,64.15 v11(104.94,64.15)
MUX_ML0P_ST: length 1.1
  TOP w0.102: U3102.23 105.21,66.86 C3011.2
MUX_ML1N: length 6.8
  L3SGND w0.127: v11(103.16,66.75) 103.21,66.7 v10(103.21,66.26) ; v10(103.94,63.53) 103.85,63.62 103.85,64.16 103.99,64.31 v11(104.01,64.31)
  L5 w0.066: v11(103.16,66.75) 103.24,66.82 103.24,67.36 103.54,67.66 104.25,67.66 104.43,67.48 104.43,66.37 104.01,65.94 v11(104.01,64.31)
MUX_ML1N_ST: length 1.1
  TOP w0.102: U3102.19 103.21,66.83 C3014.2
MUX_ML1P: length 6.7
  L3SGND w0.127: v11(103.77,66.75) 103.72,66.7 v10(103.72,66.26) ; v11(103.45,64.32) 103.45,64.32 103.59,64.18 103.59,63.69 v10(103.44,63.53)
  L5 w0.066: v11(103.77,66.75) 103.69,66.75 103.38,67.06 103.38,67.3 103.6,67.52 104.19,67.52 104.29,67.42 104.29,66.42 103.86,66 103.86,64.74 v11(103.45,64.32)
MUX_ML1P_ST: length 1.1
  TOP w0.102: U3102.20 103.71,66.83 C3013.2
MUX_ML2N: length 5.6
  L3SGND w0.127: v10(102.94,63.53) v11(102.94,64.08) ; v10(101.69,66.26) 101.66,66.24 v11(101.66,65.78)
  L5 w0.066: v11(102.94,64.08) 102.73,64.28 102.73,65 102.88,65.15 102.88,66.42 102.64,66.66 101.91,66.66 101.7,66.45 101.7,65.82 v11(101.66,65.78)
MUX_ML2N_ST: length 1.1
  TOP w0.102: U3102.16 101.71,66.84 C3016.2
MUX_ML2P: length 5.6
  L3SGND w0.127: v11(102.38,64.08) 102.58,63.88 102.58,63.67 v10(102.44,63.53) ; v10(102.2,66.26) 102.09,66.26 102.02,66.19 102.02,66.01 v11(102.22,65.81)
  L5 w0.066: v11(102.38,64.08) 102.59,64.29 102.59,65.06 102.74,65.2 102.74,66.36 102.58,66.51 101.97,66.51 101.84,66.39 101.84,66.13 102.04,65.94 102.04,65.93 102.17,65.81 v11(102.22,65.81)
MUX_ML2P_ST: length 1.1
  TOP w0.102: U3102.17 102.2,67.87 C3015.2
MUX_ML3N: length 8
  L3SGND w0.127: v10(100.19,66.26) 100.37,66.44 100.37,66.62 100.21,66.77 v11(100.19,66.77) ; v10(101.44,63.53) v11(101.44,64.03)
  L5 w0.066: v11(100.19,66.77) 100.24,66.77 100.63,67.16 100.63,67.6 100.38,67.85 99.69,67.85 99.5,67.65 99.5,66.42 101.08,64.84 101.08,64.31 101.36,64.03 v11(101.44,64.03)
MUX_ML3N_ST: length 1.1
  TOP w0.102: U3102.13 100.21,66.84 C3018.2
MUX_ML3P: length 8
  L3SGND w0.127: v11(100.85,64) 100.94,63.92 v10(100.94,63.53) ; v10(100.7,66.26) 100.7,66.7 v11(100.77,66.77)
  L5 w0.066: v11(100.77,66.77) 100.77,67.66 100.44,67.99 99.63,67.99 99.35,67.71 99.35,66.36 100.94,64.78 100.94,64.09 v11(100.85,64)
MUX_ML3P_ST: length 1.1
  TOP w0.102: C3017.2 100.71,66.83 U3102.14
MUX_SSRXN: length 1.6
  TOP w0.102: U3101.27 100.31,61.64 100.16,61.49 99.17,61.49 C3142.1
MUX_SSRXP: length 1.6
  TOP w0.102: C3143.1 99.17,61.28 100.14,61.28 100.28,61.14 U3101.28
MUX_SSTXN: length 1.6
  TOP w0.102: U3101.25 100.3,62.64 100.16,62.5 99.17,62.5 C3141.1
MUX_SSTXP: length 1.6
  TOP w0.102: C3140.1 99.16,62.29 100.15,62.29 100.29,62.14 U3101.26
MUX_TX1N: length 0.9
  TOP w0.102: U3101.5 102.94,59.36 R3126.1
MUX_TX1P: length 0.9
  TOP w0.102: U3101.4 102.44,59.37 R3125.1
MUX_TX2N: length 0.9
  TOP w0.102: R3128.1 103.94,59.34 U3101.7
MUX_TX2P: length 0.9
  TOP w0.102: R3127.1 103.44,59.35 U3101.6
MUX_TYPE_C_RX1+: length 54.5
  L3SGND w0.127: v10(100.94,60.26) v11(100.94,60.78)
  L5 w0.066: v11(100.94,60.78) 101.19,60.53 101.19,59.65 101.33,59.51 101.33,57.23 102.95,55.6 102.95,51.34 103.5,50.79 103.5,45.7 103.92,45.28 103.92,43 104.55,42.37 104.55,38.85 100.17,34.47 100.17,32.81 100.17,25.84 96.65,22.31 96.65,18.89 96.65,16.12 96.65,14.77 97.13,14.28 98.88,14.28 98.98,14.19 98.98,13.92 98.89,13.84 v5(98.67,13.84)
MUX_TYPE_C_RX1-: length 54.4
  L3SGND w0.127: v11(101.49,60.75) 101.44,60.69 v10(101.44,60.26)
  L5 w0.066: v5(99.42,13.84) 99.23,13.84 99.12,13.94 99.12,14.24 98.94,14.43 97.18,14.43 96.79,14.82 96.79,16.18 96.79,18.95 96.79,18.95 96.79,22.25 100.32,25.77 100.32,25.78 100.32,27.21 100.32,34.41 104.69,38.79 104.69,42.43 104.07,43.06 104.07,45.34 103.64,45.76 103.64,50.85 103.09,51.39 103.09,55.66 101.47,57.29 101.47,59.57 101.33,59.71 101.33,60.58 v11(101.49,60.75)
MUX_TYPE_C_RX2+: length 57.6
  L3SGND w0.127: v10(104.94,60.26) 104.94,60.7 v11(104.94,60.7)
  L5 w0.066: v5(105.78,13.83) 105.59,13.83 105.55,13.78 105.55,13.3 105.32,13.08 104.89,13.08 104.51,13.46 104.51,13.94 103.39,15.06 100.69,15.06 100.57,15.06 99.02,16.61 99.02,16.78 99.02,19.66 102.57,23.21 102.57,33.62 106.47,37.52 106.47,47.83 106.73,48.09 106.73,52.26 106.28,52.7 106.14,52.85 106.14,58.76 105.15,59.76 105.15,60.49 v11(104.94,60.7)
MUX_TYPE_C_RX2-: length 57.5
  L3SGND w0.127: v10(105.44,60.26) 105.44,60.64 v11(105.5,60.7)
  L5 w0.066: v5(105.02,13.83) 105.02,13.9 105.13,14.02 105.29,14.02 105.4,13.9 105.4,13.36 105.26,13.22 104.95,13.22 104.65,13.52 104.65,14 103.45,15.2 100.63,15.2 99.17,16.66 99.17,16.84 99.17,16.84 99.17,19.6 102.71,23.15 102.71,33.56 106.62,37.46 106.62,47.78 106.87,48.03 106.87,52.32 106.28,52.91 106.28,58.82 105.94,59.16 105.29,59.82 105.29,60.49 v11(105.5,60.7)
MUX_TYPE_C_TX1+: length 50.5
  L3SGND w0.127: v10(102.4,58.77) v11(102.4,59.25)
  L5 w0.066: v5(97.29,14.93) 97.39,15.03 97.39,15.05 97.47,15.13 97.47,15.72 97.44,15.75 97.44,15.85 97.44,16.8 97.44,19.22 97.44,20.43 99.61,22.6 99.61,23.37 100.97,24.73 100.97,25.51 100.97,26.16 100.97,26.94 100.97,33.91 100.97,34.07 105.19,38.3 105.19,46.47 104.68,46.98 104.68,50.82 103.84,51.66 103.84,56.59 102.62,57.81 102.62,59.03 v11(102.4,59.25)
  BOTTOM w0.102: v5(97.29,14.93) 97.37,14.85 97.37,14.11 L3101.4
MUX_TYPE_C_TX1-: length 50.5
  L3SGND w0.127: v11(102.96,59.28) 102.91,59.23 v10(102.91,58.77)
  L5 w0.066: v5(97.67,14.93) 97.61,14.99 97.61,15.07 97.61,15.07 97.61,15.78 97.58,15.81 97.58,16.18 97.58,16.86 97.58,19.28 97.58,20.37 99.75,22.54 99.75,23.31 101.11,24.67 101.11,25.45 101.11,26.22 101.11,26.88 101.11,33.86 101.11,34.01 105.34,38.24 105.34,46.53 104.83,47.04 104.83,50.88 103.98,51.72 103.98,56.65 102.76,57.87 102.76,59.09 v11(102.96,59.28)
  BOTTOM w0.102: v5(97.67,14.93) 97.59,14.84 97.59,14.1 L3101.1
MUX_TYPE_C_TX2+: length 55.3
  L3SGND w0.127: v10(103.41,58.77) 103.41,59.08 v11(103.57,59.23)
  L5 w0.066: v11(103.57,59.23) 103.77,59.02 103.77,58.59 104.81,57.55 104.81,52.05 105.68,51.18 105.68,47.57 105.88,47.37 105.88,37.94 101.76,33.82 101.76,26.49 101.76,25.18 101.76,23.52 98.23,19.99 98.23,19.93 98.23,19.93 98.23,19.55 98.23,17.13 98.23,16.45 98.23,16.08 100.16,14.15 102.26,14.15 103.25,13.16 103.58,13.16 103.89,13.48 103.89,13.52 v5(104.2,13.83)
MUX_TYPE_C_TX2-: length 55.3
  L3SGND w0.127: v10(103.92,58.77) 103.92,59 v11(104.13,59.2)
  L5 w0.066: v11(104.13,59.2) 103.91,58.99 103.91,58.65 104.95,57.61 104.95,52.1 105.82,51.24 105.82,47.63 106.02,47.42 106.02,37.88 101.9,33.76 101.9,26.55 101.9,26.55 101.9,25.12 101.9,25.12 101.9,23.94 101.9,23.94 101.9,23.46 98.37,19.93 98.37,19.87 98.37,19.6 98.37,17.19 98.37,17.18 98.37,16.51 98.37,16.51 98.37,16.14 100.22,14.3 102.32,14.3 103.31,13.3 103.52,13.3 103.75,13.54 103.75,13.95 103.66,14.04 103.54,14.04 103.45,13.95 v5(103.45,13.83)
NCF_SIMVCC: length 2.7
  BOTTOM w0.114: NFC1.4 89.05,78.39 89.32,78.12 90.19,78.12 TP3902.1
NFC_DWL_REQ: length 185.5
  L5 w0.076: v4(84.7,178.63) 84.84,178.78 85.3,178.78 86.22,179.7 86.22,180.3 91.61,185.69 92.56,185.69 95.44,188.58 106.19,188.58 106.41,188.36 106.65,188.36 108.19,186.82 108.19,177.87 108.98,177.08 108.98,170.45 108.7,170.17 108.7,153.06 110.72,151.04 110.72,141.43 110.55,141.26 110.55,140.86 110.22,140.53 110.22,140.38 v4(109.99,140.15) ; v5(72.4,179.4) 72.39,179.29 72.11,179.01 72.11,178.27 72.41,177.97 72.41,177.48 72.54,177.36 72.54,176.92 72.34,176.72 72.34,175.61 72.33,175.6 72.33,174.6 72.34,174.59 72.34,169.48 v8(72.39,169.43)
  L7 w0.061: v4(109.99,140.15) 109.43,139.59 87.98,139.59 86.83,138.44 86.83,132.01 86.96,131.88 86.96,129.46 86.78,129.29 86.78,123.39 88.48,121.69 88.58,121.59 88.58,121.59 88.68,121.49 89.3,120.87 89.3,109.92 89.3,109.92 89.3,109.54 89.3,109.54 89.3,109.32 89.3,109.23 89.3,109.14 89.3,109 89.3,108.82 89.3,108.8 89.3,108.23 88.73,107.67 88.73,98.63 88.68,98.58 88.68,95.27 89.55,94.4 v5(89.55,78.95) ; v5(72.4,179.4) 72.77,179.02 75.36,179.02 76.74,179.02 77.21,179.49 79.53,179.49 79.63,179.4 v5(81.39,179.4) 83.65,179.4 84.32,178.72 84.61,178.72 v4(84.7,178.63)
NFC_EN_SEC: length 185.7
  L5 w0.06: v8(72.67,169.15) 72.67,169.43 72.47,169.63 72.47,172.33 72.55,172.41 72.55,174.64 72.51,174.68 72.51,175.53 72.72,175.74 72.72,177.43 72.6,177.56 72.6,178.04 72.5,178.14 72.5,178.79 v5(72.4,178.89)
  L5 w0.076: v4(84.36,178.43) 84.47,178.33 85.18,178.33 86.42,179.57 86.42,180.23 91.68,185.49 92.65,185.49 95.54,188.39 106.11,188.39 106.33,188.17 106.57,188.17 107.99,186.75 107.99,177.79 108.75,177.02 108.75,171.55 108.79,171.51 108.79,170.55 108.49,170.26 108.49,152.97 110.53,150.94 110.53,141.51 110.31,141.29 110.31,141 110.14,140.83 110.03,140.83 109.69,140.48 109.69,139.82 v4(109.92,139.59)
  L7 w0.061: v4(109.92,139.59) 109.64,139.31 87.95,139.31 87,138.36 87,132.09 87.14,131.95 87.14,129.36 86.96,129.18 86.96,123.89 86.96,123.75 86.96,123.46 88.55,121.87 88.65,121.77 88.75,121.66 88.76,121.66 89.37,121.05 89.47,120.95 89.47,109.99 89.47,109.65 89.47,109.32 89.47,109.23 89.47,109.13 89.47,109 89.47,108.81 89.47,108.76 89.47,108.16 88.91,107.6 88.91,98.56 88.86,98.51 88.86,95.35 89.06,95.15 89.17,95.05 90.44,93.77 90.44,82.53 90.62,82.36 90.62,79.77 90.05,79.2 v5(90.05,78.95) ; v5(72.4,178.89) 72.48,178.89 72.52,178.85 74.82,178.85 74.83,178.85 75.28,178.85 76.81,178.85 77.28,179.31 79.46,179.31 79.71,179.06 80.18,179.06 v5(80.22,179.01) 80.27,179.06 83.73,179.06 v4(84.36,178.43)
NFC_HOST_INT_SEC: length 171
  L5 w0.076: v4(71.13,178.65) 71.13,179.77 70.95,179.95 70.62,179.95 70.43,179.77 70.43,179.74 70.29,179.6 69.43,179.6 68.68,180.35 67.7,180.35 67.54,180.35 67.54,180.35 67.39,180.35 67.23,180.35 67.07,180.35 66.89,180.53 49.89,180.53 47.69,178.32 47.69,170.89 46.6,169.8 46.6,168.63 46.83,168.41 46.94,168.41 47.69,167.66 47.69,161.67 46.24,160.22 46.24,159.85 46.41,159.67 46.56,159.67 46.99,159.24 46.99,151.3 50.68,147.61 50.8,147.61 50.84,147.57 55.97,147.57 56.75,146.79 62.18,146.79 v4(62.62,146.35) ; v4(87.82,129.84) 87.51,129.84 87.39,129.71 86.47,129.71 86.32,129.87 86.32,129.88 86.31,129.9 86.31,129.98 86.12,130.17 86.12,131.72 84.39,133.45 84.39,133.73 84.09,134.03 84.09,136.32 82.71,137.69 79.46,137.69 74.89,142.26 74.38,142.26 71.3,145.35 70.08,145.35 69.05,146.38 v4(67.88,146.38)
  L7 w0.06: v5(71.23,176.07) 71.85,175.45 71.85,174.6 72.05,174.39 72.18,174.27 72.18,172.68 72.02,172.52 72.02,171.05 71.9,170.93 71.9,170.76 72.1,170.57 v5(72.1,170.28)
  L7 w0.061: v4(62.62,146.35) 63.28,146.35 63.84,146.91 65.38,146.91 65.46,146.82 65.82,146.82 65.94,146.71 66.49,146.71 66.56,146.77 67.48,146.77 v4(67.88,146.38) ; v5(92.55,78.95) 92.55,80.53 92.54,80.55 92.54,81.37 91.04,82.87 91.04,93.63 91.04,93.92 89.38,95.57 89.38,98.29 89.43,98.34 89.43,107.38 90,107.94 90,108.35 90,109.07 90,109.1 90,109.23 90,109.32 90,110 90,110 90,110.21 90,116.48 90.31,116.78 v5(90.31,116.94) 90.03,117.22 90.03,121.13 89.9,121.27 89.9,121.27 89.69,121.47 89.59,121.58 88.97,122.19 88.97,122.19 88.87,122.29 88.87,122.29 88.77,122.4 87.48,123.68 87.48,128.48 87.59,128.59 87.59,129.06 87.66,129.14 87.66,129.69 v4(87.82,129.84) ; v5(71.23,176.07) 71.23,176.22 70.95,176.51 70.95,176.74 71.18,176.98 71.18,178.56 71.13,178.6 v4(71.13,178.65)
NFC_SWP: length 1.7
  BOTTOM w0.114: TP3901.1 93.55,77.83 NFC1.13
NFC_VCC_BOOST: length 4.7
  TOP w0.508: v2(93.02,76.68) 93.03,76.68 TP3903.1 C3904.1 R3905.2
  BOTTOM w0.305: v2(93.02,76.68) 93.1,76.75 C3905.1 93.05,77.34 NFC1.12
OTG_ID: length 16.3
  TOP w0.114: v9(99.3,22.12) 99.73,21.69 99.73,21.13 D2902.K v1(99.62,19.71) ; U2901.E10 110.49,21.99 110.49,22.41 110.2,22.7 110.23,22.7 110.23,22.71 v9(110.24,22.71)
  L2 w0.061: v9(99.3,22.12) 99.42,22.24 100.14,22.24 100.24,22.14 100.87,22.14 100.97,22.24 102.4,22.24 102.44,22.2 102.47,22.2 102.78,21.88 103.56,21.88 103.72,22.05 103.72,22.15 104.03,22.45 105.01,22.45 105.3,22.16 106.2,22.16 106.45,21.91 106.53,21.91 106.62,21.82 107.15,21.82 107.26,21.71 107.5,21.71 107.59,21.8 107.97,21.8 108.61,22.45 108.64,22.48 109.22,22.48 109.55,22.81 110.09,22.81 110.2,22.7 110.2,22.7 110.23,22.7 110.23,22.71 v9(110.24,22.71)
P_RCOMP_N: length 4.6
  L5 w0.076: v5(84.54,159.25) 84.54,159.71 84.01,160.24 82.65,160.24 82.28,160.62 81.79,160.62 81.43,160.98 v8(80.91,160.98)
P_RCOMP_P: length 5
  L5 w0.076: v8(81.23,161.23) 81.37,161.23 81.85,160.75 82.33,160.75 82.64,160.45 84.08,160.45 84.73,159.79 84.73,159.75 85.23,159.25 v5(85.41,159.25)
PANEL_EN: length 155.7
  TOP w0.114: D3401.1 89.55,46.58 89.55,46.63 89.37,46.81 v9(89.37,46.96) ; v9(88.12,49.07) R4303.2
  L2 w0.061: v2(91.68,69.36) 91.79,69.25 91.79,62.09 92.42,61.46 92.42,57.72 90.9,56.2 90.9,53.98 89.32,52.41 89.32,51.76 89.01,51.46 88.91,51.46 88.38,50.93 88.27,50.93 88.09,50.75 88.09,50.49 88.12,50.46 v9(88.12,49.07) 88.12,48.31 88.71,47.72 88.71,47.49 89.24,46.96 v9(89.37,46.96)
  L5 w0.076: v4(107.36,158.61) 107.57,158.81 107.57,169.68 106.56,170.68 106.56,181.53 106.41,181.68 v5(106.41,182.04) ; v4(100.11,148.61) 100.2,148.52 100.2,147.58 100.8,146.98 100.8,141.53 100.75,141.48 100.75,137.31 100.98,137.08 100.98,135.99 102.2,134.77 v4(102.2,134.36)
  L7 w0.061: v2(91.68,69.36) 91.24,69.8 91.24,71.9 91.77,72.42 91.77,74.05 93.56,75.84 93.56,89.05 98.06,93.54 98.06,100.12 101.03,103.09 101.03,120.54 105.12,124.64 105.12,126.94 104.73,127.33 104.73,128.06 104.87,128.19 104.87,131.16 102.2,133.83 v4(102.2,134.36) ; v4(107.36,158.61) 107.2,158.45 107.09,158.45 106.92,158.28 106.92,157.88 107.03,157.78 107.03,157.58 107.03,156.25 100.32,149.54 100.32,148.81 v4(100.11,148.61)
  BOTTOM w0.114: v5(106.41,182.04) 106.82,182.04 106.89,181.96 109.84,181.96 v1(110.17,182.29)
PANEL_EN_L: length 29.4
  TOP w0.114: v10(87.62,49.98) 87.57,49.93 R4303.1
  L3SGND w0.127: v10(87.62,49.98) 87.69,50.06 v11(87.69,50.41)
  L6SGND w0.127: v11(87.69,50.41) 87.77,50.49 v4(87.77,50.79)
  L7 w0.061: v4(87.77,50.79) 87.92,50.64 88.66,50.64 89.37,51.35 89.37,53.01 89.6,53.24 89.6,53.55 90.86,54.81 90.86,60.29 89.75,61.41 89.75,62.43 89.29,62.89 v5(89.29,63.29) 89.29,63.72 88.99,64.03 88.99,64.94 89.36,65.32 90.08,66.03 90.08,68.04 89.75,68.37 89.75,71.21 89.74,71.21 89.74,71.59 89.54,71.79 89.54,72.17 89.65,72.33 89.69,72.37 89.69,72.53 89.86,72.69 89.92,72.69 90.05,72.82 v5(90.18,72.82)
  BOTTOM w0.114: TP1.10 91.77,73.82 90.77,72.82 v5(90.18,72.82)
PANEL_EN_R: length 6.2
  TOP w0.114: v9(88.84,48.1) 88.97,47.96 D3401.3 ; R3408.1 87.97,50.29 87.97,50.26 88.47,49.75 v9(88.86,49.75) 89.17,50.06 U3401.4
  L2 w0.061: v9(88.86,49.75) 88.86,49.37 88.58,49.09 88.58,48.36 v9(88.84,48.1)
PCIE_CLKN0: length 145.5
  L5 w0.066: v8(80.59,160.66) 80.74,160.66 81.72,159.69 82.44,159.69 87.21,154.92 87.76,154.92 90.12,152.56 96.65,152.56 101.41,147.8 101.41,136.94 101.41,136.42 101.41,136.05 104.18,133.29 104.18,131.33 104.87,130.63 104.87,125.07 102.33,122.53 102.33,120.94 102.33,118.77 102.33,94.03 102,93.71 102,90.8 100.32,89.12 98.78,87.58 98.78,87.13 98.63,86.98 98.18,86.98 97.89,86.69 97.89,86.57 97.89,86.34 98.1,86.13 98.64,86.13 98.74,86.03 98.74,85.9 98.64,85.8 97.98,85.8 97.83,85.65 97.83,85.33 97.98,85.19 98.67,85.19 98.77,85.09 98.77,84.95 98.67,84.86 97.98,84.86 97.92,84.79 97.81,84.68 97.81,75.7 97.81,72.74 95.42,70.35 95.08,70.01 95.08,62.7 95.67,62.12 95.67,56.13 98.73,53.07 98.73,45.43 100.43,43.73 100.43,43.35 100.43,40.16 100.26,39.99 100.12,39.99 100.02,40.09 100.02,40.24 v5(100.09,40.3)
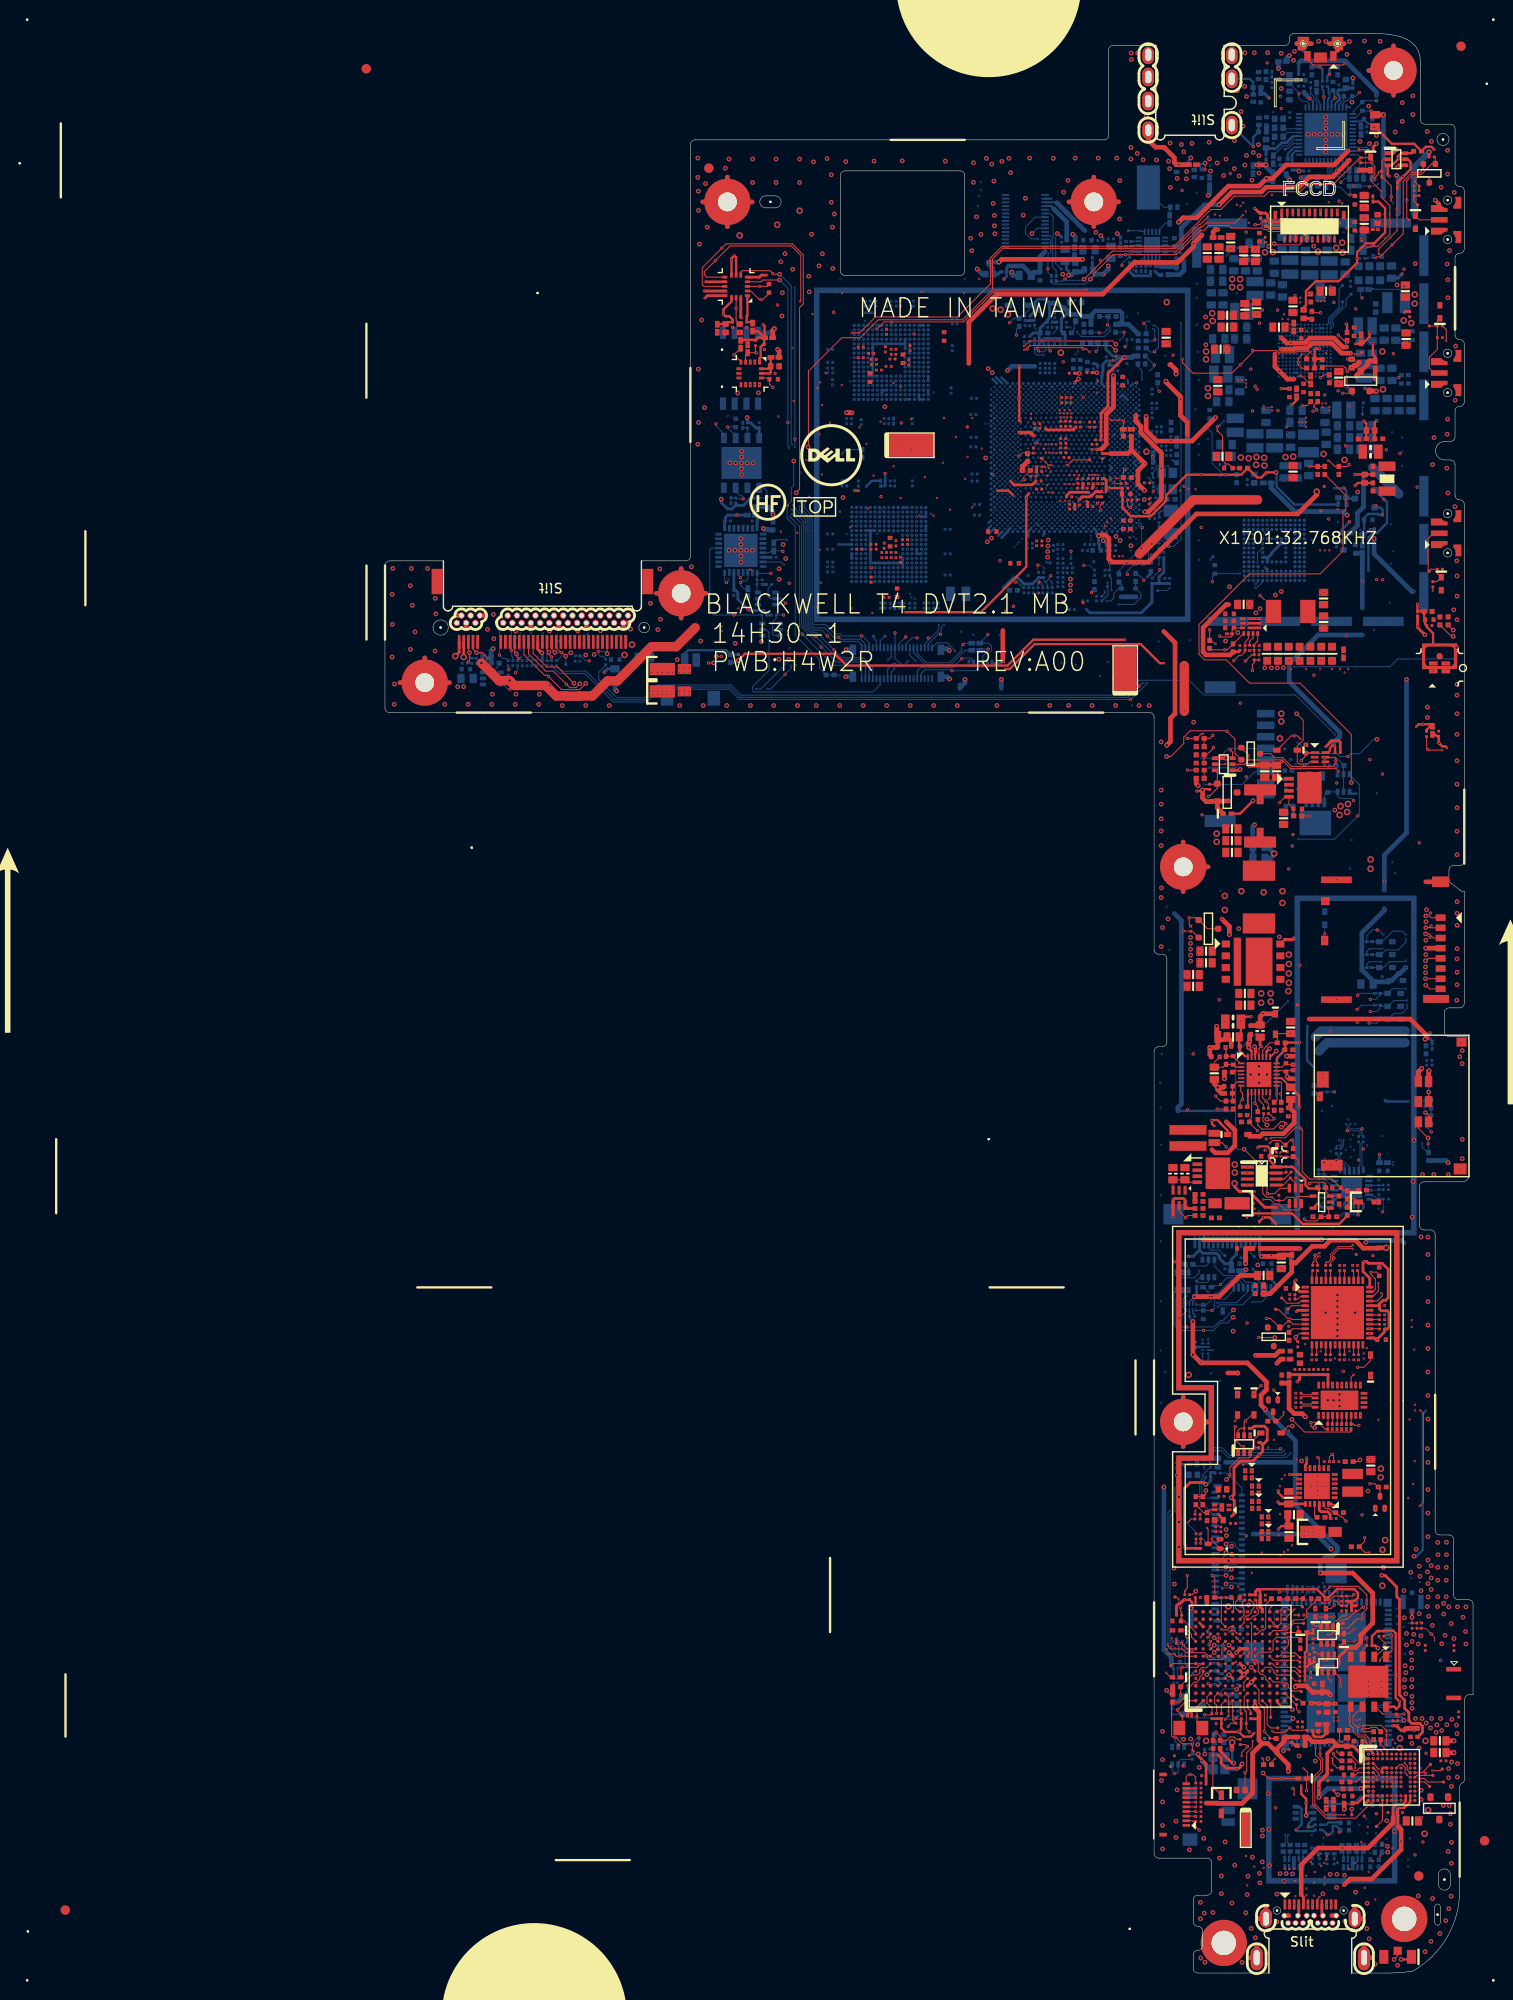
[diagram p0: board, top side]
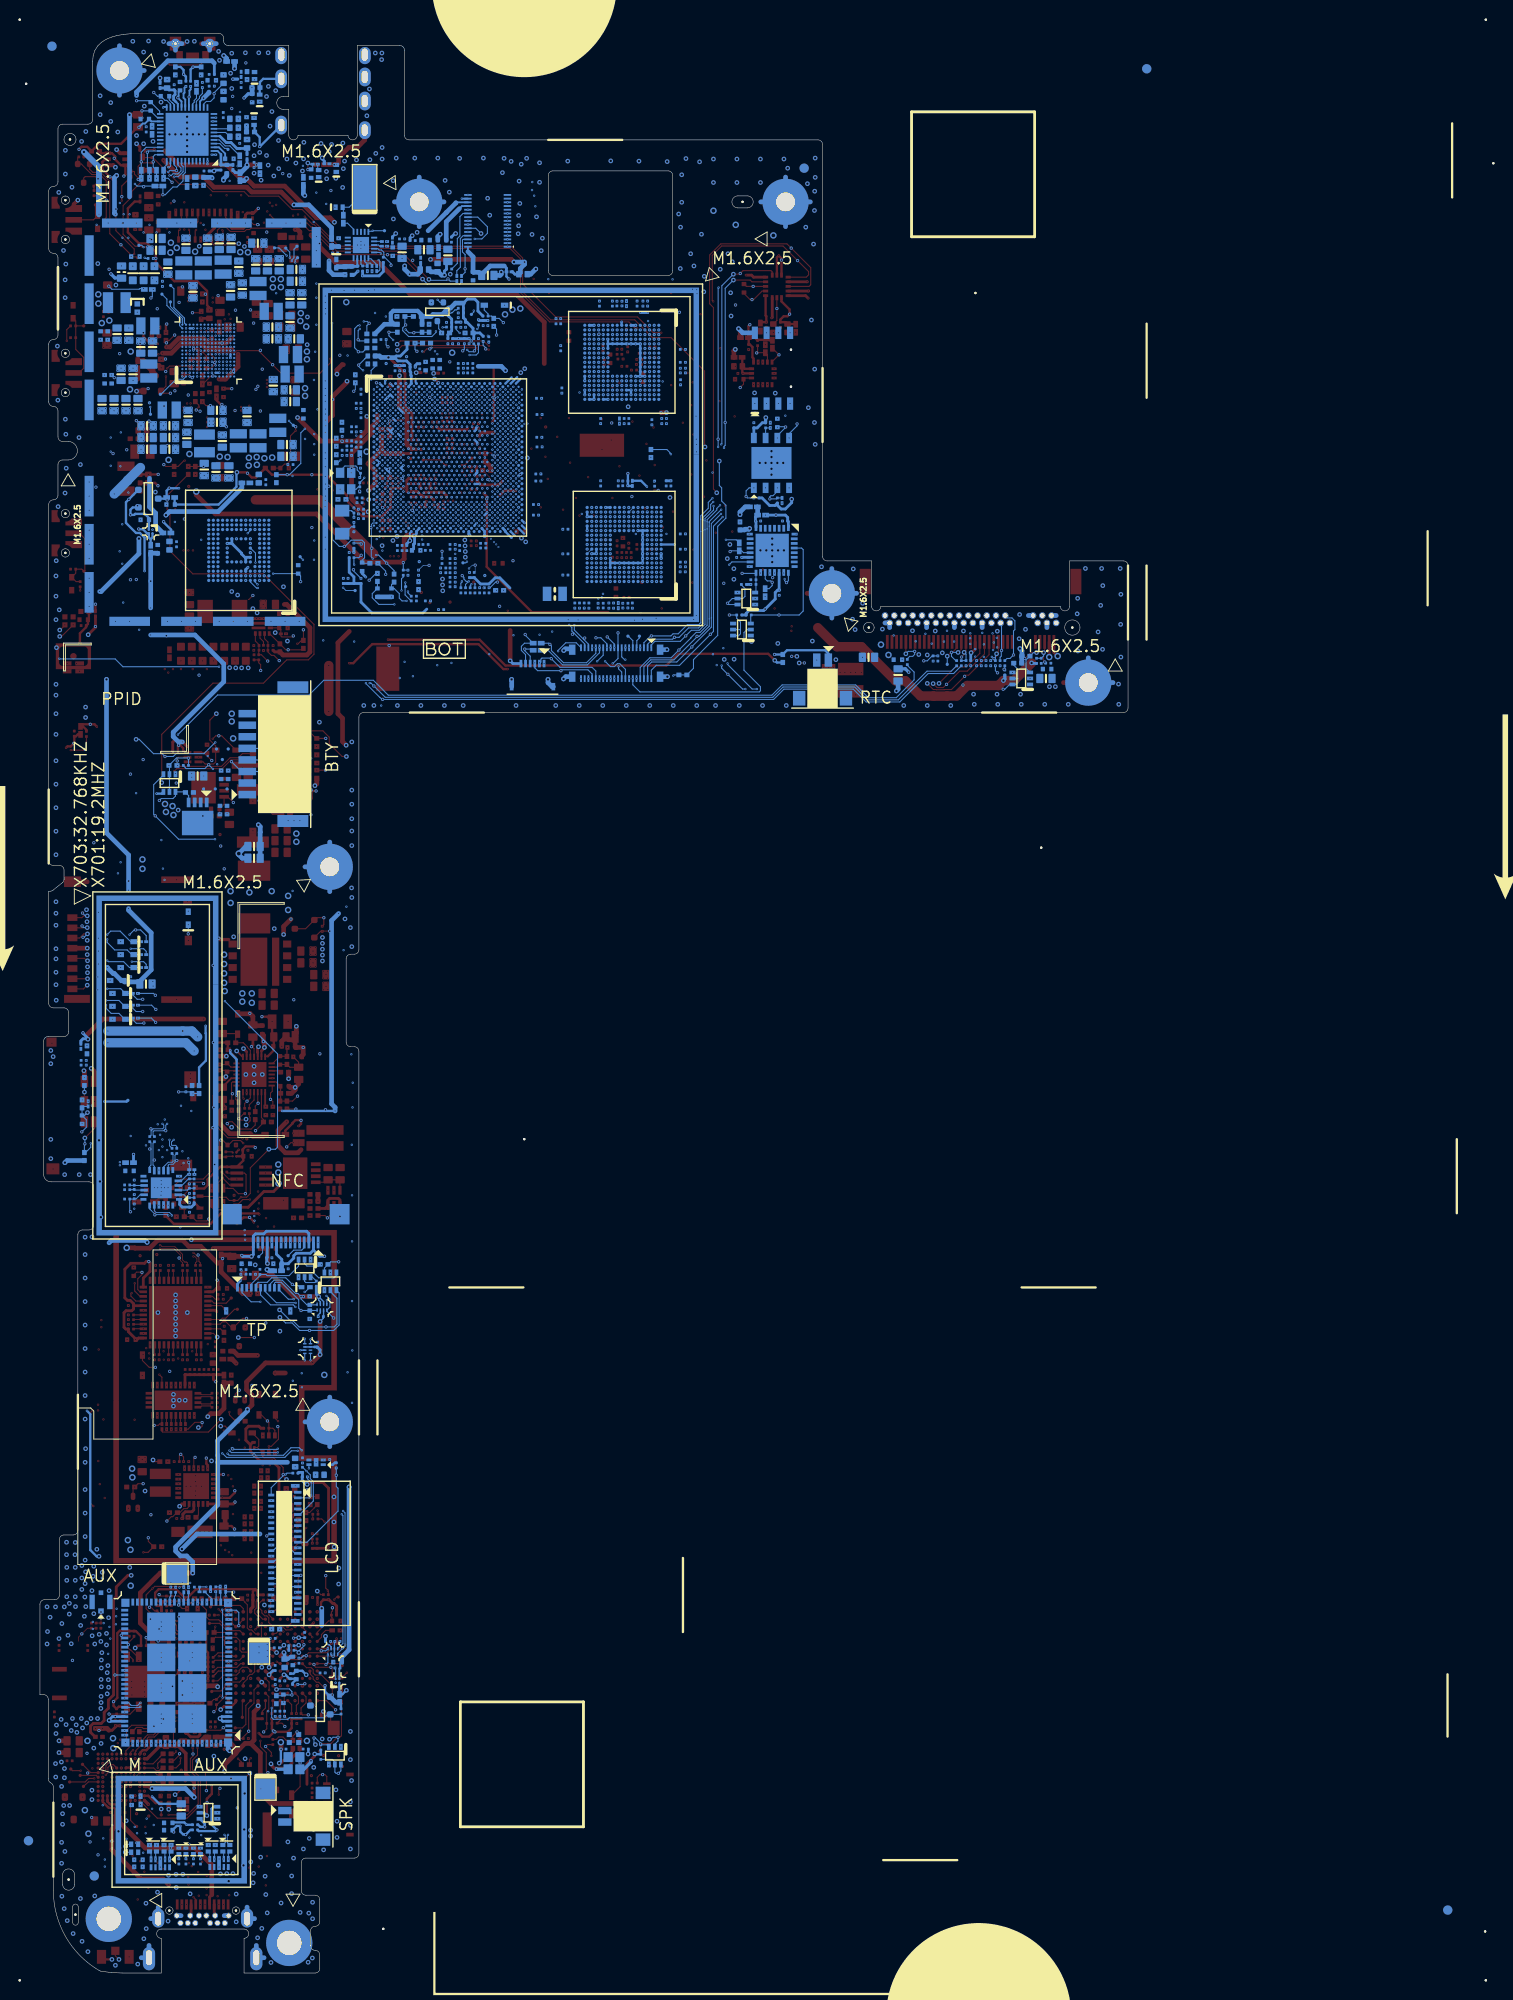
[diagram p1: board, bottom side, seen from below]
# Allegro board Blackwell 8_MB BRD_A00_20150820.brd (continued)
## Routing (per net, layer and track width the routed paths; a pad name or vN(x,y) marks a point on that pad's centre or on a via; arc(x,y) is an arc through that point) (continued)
PCIE_CLKP0: length 145.6
  L5 w0.066: v8(80.31,160.94) 80.66,160.94 81.78,159.83 82.5,159.83 87.27,155.06 87.82,155.06 90.18,152.7 96.71,152.7 101.55,147.86 101.55,136.88 101.55,136.36 101.55,136.11 104.32,133.35 104.32,131.39 105.02,130.69 105.02,125.01 102.47,122.47 102.47,120.88 102.47,118.83 102.47,93.97 102.14,93.65 102.14,90.74 100.38,88.98 99.62,88.21 99.62,88.21 98.92,87.52 98.92,87.07 98.69,86.84 98.24,86.84 98.03,86.63 98.03,86.4 98.16,86.27 98.7,86.27 98.88,86.09 98.88,85.84 98.7,85.66 98.04,85.66 97.98,85.59 97.98,85.39 98.04,85.33 98.73,85.33 98.91,85.15 98.91,84.89 98.73,84.71 98.04,84.71 97.95,84.62 97.95,75.76 97.95,75.76 97.95,74.45 97.95,74.45 97.95,72.68 95.48,70.21 95.23,69.96 95.23,62.76 95.81,62.17 95.81,56.19 98.87,53.13 98.87,45.49 100.57,43.79 100.57,43.3 100.57,43.3 100.57,40.1 100.57,40.1 v5(100.57,39.9)
PCIE_CLKREQ0#: length 158.5
  L5 w0.076: v4(69.84,148.89) 69.84,148.94 70.61,148.17 70.61,147.7 70.61,147.45 79.78,138.27 82.23,138.27 82.87,138.27 83.01,138.27 83.27,138.01 83.27,138 84.22,137.05 84.23,137.05 84.7,136.59 84.7,134.56 85.21,134.04 85.22,134.04 85.39,133.87 85.39,133.86 86.78,132.48 88.4,132.48 89.15,131.73 95.78,131.73 97.32,133.27 v4(97.62,133.27)
  L7 w0.06: 71.09,155.76 71.09,156.46 71.17,156.54 71.17,156.9 v8(71.26,156.98)
  L7 w0.061: v4(69.84,148.89) 69.56,148.61 69.49,148.61 69.31,148.43 69.31,148.16 69.14,148 68.91,148 67.98,148.92 67.98,150.05 69.04,151.11 69.04,151.19 69.32,151.47 69.32,151.49 70.25,152.41 70.25,152.42 70.83,153 70.83,155.32 70.84,155.32 70.84,155.5 71.09,155.76 ; v5(98.67,41.19) 98.44,41.42 97.01,41.42 96.73,41.7 96.73,45.9 96.96,46.13 96.96,53.54 95.18,55.32 95.18,58.69 95.6,59.11 95.6,63.74 95.24,64.09 95.24,69.14 96.76,70.66 97,70.66 98.72,72.38 98.72,85 98.63,85.09 98.63,88.41 100.9,90.68 100.9,92.18 101.03,92.3 101.03,92.93 v5(101.26,93.16) 102.33,94.23 102.33,120.94 105.68,124.29 105.68,131.25 104.69,132.24 104.69,132.88 102.75,134.82 101.81,134.82 101.05,134.06 98.41,134.06 v4(97.62,133.27)
  BOTTOM w0.114: WU3701.30 98.58,41.11 v5(98.67,41.19)
PCIE_RXN0: length 144
  L5 w0.066: v8(80.88,161.51) 80.94,161.57 81.74,161.57 82.3,161.01 84.23,161.01 92.23,153 96.83,153 101.85,147.99 101.85,136.76 101.85,136.24 104.61,133.47 104.61,131.51 105.56,130.57 105.56,125.1 102.77,122.31 102.77,120.76 102.77,118.95 102.77,118.95 102.77,93.85 102.44,93.52 102.44,90.62 99.27,87.45 99.27,84.06 98.33,83.12 98.33,81.19 98.24,81.11 98.24,75.88 98.24,74.32 98.24,74.32 98.24,72.56 95.56,69.87 95.56,63.04 96.3,62.3 96.3,56.15 99.16,53.29 99.16,45.8 99.51,45.46 99.72,45.46 99.99,45.73 100.12,45.73 100.22,45.63 100.22,45.5 99.95,45.23 99.95,45.02 101.22,43.74 101.43,43.74 101.73,44.04 101.87,44.04 101.96,43.94 101.96,43.8 101.67,43.51 101.67,42.46 101.77,42.36 101.77,41.8 101.81,41.76 101.81,41.41 101.74,41.35 101.59,41.35 101.51,41.42 v5(101.51,41.65)
PCIE_RXP0: length 144.1
  L5 w0.066: v5(102.09,41.68) 101.91,41.86 101.91,42.42 101.81,42.52 101.81,43.45 102.11,43.74 102.11,44 101.93,44.18 101.67,44.18 101.38,43.89 101.28,43.89 100.09,45.07 100.09,45.17 100.36,45.44 100.36,45.69 100.18,45.87 99.93,45.87 99.66,45.6 99.56,45.6 99.31,45.86 99.31,53.35 96.45,56.21 96.45,62.36 95.7,63.1 95.7,69.82 98.39,72.5 98.39,74.26 98.39,81.05 98.47,81.13 98.47,83.06 99.41,84 99.41,87.39 102.58,90.56 102.58,93.47 102.91,93.79 102.91,119.01 102.91,119.01 102.91,120.7 102.91,120.7 102.91,122.25 105.7,125.04 105.7,130.63 104.76,131.57 104.76,133.53 101.99,136.29 101.99,136.34 101.99,148.04 96.89,153.15 92.29,153.15 84.29,161.15 82.36,161.15 81.79,161.72 80.8,161.72 80.59,161.51 v8(80.59,161.23)
PCIE_TXN0: length 144.4
  L5 w0.066: v8(78.9,161.79) 78.9,161.84 79.02,161.96 79.45,161.96 79.73,162.23 81.07,162.23 81.19,162.35 83.5,162.35 92.36,153.5 96.95,153.5 102.28,148.17 102.28,136.46 105.05,133.69 105.05,131.69 105.99,130.75 105.99,124.87 103.2,122.08 103.2,121.99 103.2,120.58 103.2,119.13 103.2,119.13 103.2,93.67 102.88,93.34 102.88,90.44 99.91,87.47 99.91,83.61 98.89,82.6 98.89,81.14 98.68,80.93 98.68,76.06 98.68,72.37 96.88,70.58 96.88,56.44 99.6,53.72 99.6,52.96 99.6,47.07 102.67,44 102.67,42.52 103.04,42.16 103.04,41.96 103.2,41.79 103.2,41.62 103.14,41.55 103.02,41.55 v5(102.92,41.65)
PCIE_TXP0: length 144.4
  L5 w0.066: v5(103.49,41.7) 103.18,42.01 103.18,42.22 102.81,42.58 102.81,44.06 99.74,47.13 99.74,52.9 99.74,53.78 97.02,56.5 97.02,70.52 98.82,72.32 98.82,74.08 98.82,74.08 98.82,76.12 98.82,80.87 99.04,81.08 99.04,82.54 100.05,83.55 100.05,87.41 103.02,90.38 103.02,93.28 103.35,93.61 103.35,119.19 103.35,120.52 103.35,121.96 103.35,122.02 106.14,124.81 106.14,130.81 105.19,131.75 105.19,133.75 102.42,136.52 102.42,148.23 97.01,153.64 92.42,153.64 83.56,162.49 81.13,162.49 81.01,162.38 79.67,162.38 79.39,162.1 78.63,162.1 v8(78.61,162.08)
PEWAKE#: length 1.1
  BOTTOM w0.114: WU3701.29 98.08,41.14 WR3710.1
PLT_CLK1_CAM1: length 103.8
  L3SGND w0.127: v2(69.94,187.98) 69.15,187.98 68.57,187.4 66.53,187.4 64.76,185.62 64.76,182.82 62.98,181.05 48.63,181.05 44.56,176.98 44.56,169.74 42.4,167.58 42.4,158.19 43.52,157.07 v11(43.52,155.44)
  L5 w0.076: v4(62.22,144.55) 62.14,144.62 55.52,144.62 54.92,145.22 54.92,145.53 53.94,146.51 50.36,146.51 50.2,146.67 49.32,146.67 44.19,151.79 44.19,155.01 43.76,155.44 v11(43.52,155.44)
  L7 w0.061: v5(77.99,148.28) 77.58,148.28 75.48,146.18 69.47,146.18 68.33,145.04 66.9,145.04 v5(66.43,144.57) 66.43,145.11 65.16,146.38 64.65,146.38 62.97,144.7 62.47,144.7 62.32,144.55 v4(62.22,144.55)
  BOTTOM w0.114: CAMR1.25 70.51,188.55 v2(69.94,187.98) ; v5(77.99,148.28) 78.47,148.28 78.78,148.58 78.78,149.07 79.34,149.63 C712.1 79.62,150.03 R723.1
PLT_CLK1_CAM1_1: length 7.9
  L7 w0.06: v8(79.46,157.27) 79.46,156.98 79.66,156.78 79.66,156.62 79.54,156.5 79.54,156.33 80.69,155.19 80.69,155.12 81.29,154.53 v5(81.29,153.23)
  BOTTOM w0.114: R723.2 79.34,151.56 v1(80.14,152.36) 81.01,153.23 v5(81.29,153.23)
PLT_CLK1_CAM2: length 51
  TOP w0.114: CAMF1.8 99.04,186.98 98.82,186.76 96.25,186.76 v2(96.13,186.89)
  L7 w0.061: v2(96.13,186.89) 95.41,187.6 91.15,187.6 90.56,187.02 90.54,187.02 88.12,184.6 88.12,180.03 86.4,178.3 v5(86.04,178.3)
  BOTTOM w0.114: R722.1 82.71,152.34 C711.1 82.79,152.67 82.53,152.93 82.53,154.58 82.79,154.84 83.97,154.84 84.64,154.17 v1(84.72,154.17) 85.26,154.17 86.04,154.95 v5(86.04,178.3)
PLT_CLK1_CAM2_1: length 7.3
  L7 w0.06: v8(79.18,156.98) 79.18,156.63 79.02,156.46 79.02,156.3 79.19,156.12 79.38,156.12 79.89,155.61 79.89,155.61 80.45,155.05 80.45,155.02 81.02,154.46 81.02,153.69 80.89,153.56 80.89,152.55 v5(81.09,152.34)
  BOTTOM w0.114: v1(80.25,151.15) 80.25,151.51 v5(81.09,152.34)
PLTRST#: length 245.9
  TOP w0.114: v10(90.86,130.67) 90.81,130.63 U1706.5
  L2 w0.061: v10(85.81,153.18) 85.49,152.86 85.49,152.73 83.06,150.31 77.68,150.31 77.68,150.31 77.29,150.31 77.01,150.03 77.01,148.07 75.06,146.12 73.77,146.12 73.52,145.87 72.55,145.87 70.22,143.54 v10(70.22,143.12)
  L3SGND w0.127: v11(90.51,130.7) 90.54,130.68 90.79,130.68 90.8,130.67 v10(90.86,130.67) ; v11(69.95,142.85) 70.22,143.11 v10(70.22,143.12) ; v11(85.79,153.61) 85.76,153.58 85.76,153.23 v10(85.81,153.18)
  L5 w0.076: v4(85.94,158.85) 85.94,158.26 85.98,158.22 85.98,157.08 86.88,156.18 v4(86.88,155.9) ; v11(85.79,153.61) 85.8,153.61 85.82,153.59 86.15,153.59 86.92,152.81 86.94,152.81 87.65,152.1 87.65,151.64 87.65,151.64 87.65,151.33 87.65,151.33 87.65,151.17 87.65,148.99 87.58,148.91 87.58,148.67 87.65,148.59 87.65,142.22 90,139.87 90,138.5 91.24,137.26 91.3,137.26 91.68,136.88 v4(91.68,135.81) ; v4(88.68,168.55) 87.17,170.06 87.17,170.83 88.22,171.88 90.71,171.88 91.25,172.41 92.6,172.41 93.55,173.37 93.55,173.38 94.39,174.22 94.91,174.22 95.05,174.08 96.69,174.08 97.14,174.53 v8(97.43,174.53) ; v11(69.95,142.85) 69.57,142.46 69.17,142.46 68.84,142.79 66.37,142.79 65.92,142.35 63.33,142.35 63.05,142.07 62.85,141.87 57.5,141.87 v5(57.39,141.75)
  L6SGND w0.127: v11(85.79,153.61) 85.8,153.61 85.8,153.67 85.99,153.87 v4(85.99,153.94) ; v11(90.51,130.7) 90.51,130.53 v4(90.33,130.35)
  L7 w0.06: 82.77,157.82 82.77,158 82.28,158.48 81.77,158.48 81.49,158.76 81.15,158.76 81,158.92 80.83,158.92 80.59,158.68 v8(80.31,158.68)
  L7 w0.061: 82.77,157.82 82.77,156.95 83.27,156.45 83.27,155.51 83.79,154.99 83.87,154.99 84.1,154.76 84.53,154.76 84.92,154.38 84.92,154.21 85.26,153.86 85.5,153.86 85.58,153.94 v4(85.99,153.94) 85.99,154.81 86.77,155.59 86.77,155.87 86.8,155.9 v4(86.88,155.9) ; v4(85.94,158.85) 86.02,158.92 86.02,161.62 88.33,163.93 88.33,168.19 v4(88.68,168.55) ; v5(57.39,141.75) 57.26,141.75 56.97,141.47 56.17,141.47 55.83,141.81 54.97,141.81 54.63,141.47 45.45,141.47 v5(43.75,143.17) 39.97,146.96 39.97,148.07 40.31,148.41 v5(40.31,148.53) ; v4(90.33,130.35) 89.72,130.96 89.72,134.99 90.54,135.81 v4(91.68,135.81) 92.65,136.78 98.86,136.78 99.55,136.09 99.55,135.77 99.72,135.6 103.48,135.6 105.21,133.87 105.21,132.46 106.26,131.41 106.26,123.62 102.86,120.21 102.86,93.44 101.97,92.55 101.86,92.45 101.56,92.14 101.56,92.09 101.43,91.96 101.43,90.46 99.16,88.19 99.16,85.31 99.16,85.31 99.3,85.17 99.3,79.56 99.3,79.41 99.3,79.41 99.3,74.18 99.3,73.17 99.3,73.02 99.3,72.13 99.09,71.92 99.08,71.92 96.7,69.55 96.38,69.55 95.76,68.93 95.76,66.17 96.13,65.8 96.13,58.89 95.71,58.48 95.71,55.54 97.82,53.42 97.82,50.9 97.82,46.24 97.52,45.93 97.26,45.68 97.26,44.65 97.26,44.51 97.26,44.51 97.26,43.82 99.36,41.73 v5(99.63,41.73)
  BOTTOM w0.114: v5(57.39,141.75) 56.73,142.41 XDP1.27 ; v5(99.63,41.73) 100.34,41.73 WR3705.1 WR3711.2
PLTRST_EC: length 132.7
  TOP w0.114: U1706.3 91.61,131.96 v1(91.38,132.2) ; U1704.N11 97.53,37.43 98.11,38.02 98.13,38.02 98.28,38.17 99.33,38.17 99.64,38.48 99.64,38.91 99.63,38.91 99.63,39.24 100.85,40.46 v10(100.9,40.46)
  L3SGND w0.127: v11(100.94,40.89) 100.9,40.85 v10(100.9,40.46) ; v11(91.73,130.91) 91.91,131.08 v10(91.91,131.26)
  L6SGND w0.127: v11(91.73,130.91) v4(91.73,130.53) ; v11(100.94,40.89) v4(100.94,41.43)
  L7 w0.061: v4(100.94,41.43) 99.41,42.96 99.41,51.36 98.33,52.44 98.33,53.41 96.06,55.68 96.06,57.06 96.48,57.48 96.48,62.63 96.79,62.94 96.79,69.13 97.86,70.19 99.65,71.99 99.65,73.17 99.65,73.17 99.65,73.31 99.65,74.04 99.65,74.04 99.65,79.27 99.65,79.86 99.65,79.86 99.65,85.31 99.51,85.46 99.51,88.04 101.78,90.31 101.78,91.81 101.91,91.94 101.91,91.99 102.11,92.2 103.29,93.37 103.29,120.12 106.62,123.45 106.62,131.55 105.56,132.6 105.56,134.01 103.62,135.96 100.16,135.96 99.17,136.95 91.44,136.95 89.54,135.06 89.54,130.74 90.22,130.06 90.53,130.06 91,130.53 v4(91.73,130.53)
PLTRST_N_3P3: length 3.6
  BOTTOM w0.114: U5706.3 40.22,149.28 R5720.2 C5707.1 40.22,151.25 U5702.17 v1(41.72,151.25)
PLTRST_N_3P3_R: length 4.8
  BOTTOM w0.114: U5706.6 43.15,147.88 v1(43.29,148.03) 42.79,148.53 U5706.5 41.64,148.53 41.41,148.76 41.41,149.63 41.79,150.01 R5717.1
PMIC_5V_EN: length 55.3
  TOP w0.114: v9(89.8,143.66) 89.7,143.66 89.34,144.01 R5217.1 v1(89.14,145.16)
  L2 w0.061: v9(89.8,143.66) 90.88,142.58 94.62,142.58 95.68,143.64 95.68,143.64 104.52,143.64 107.17,146.3 107.17,153.23 106.92,153.49 v10(106.92,153.98)
  L3SGND w0.127: v11(107.26,153.98) v10(106.92,153.98)
  L5 w0.076: v11(107.26,153.98) 106.48,154.77 106.48,158.91 107.05,159.48 107.05,162.91 106.49,163.47 106.49,165.22 105.51,166.2 105.51,168.99 105.35,169.15 105.35,171.04 104.9,171.48 104.78,171.48 103.96,172.3 103.96,172.86 103.27,173.54 103.27,174.51 101.25,176.53 v8(101.03,176.53)
PMIC_AGND: length 24.8
  TOP w0.508: v10(96.2,174.95) 96.2,173.6 v1(96.71,173.1) 97.56,172.24 v10(98.26,172.24) ; v9(96.89,176.73) 97.47,176.14 v1(97.93,176.14) 99.44,176.14 99.97,176.68 102.59,176.68 103.56,175.71 v10(103.95,175.71)
  L2 w0.508: v10(96.2,174.95) 96.2,176.04 v9(96.89,176.73) 96.89,176.96 v10(98.23,178.3)
  L3SGND w0.508: v11(104.33,175.71) v10(103.95,175.71) ; v11(95.83,174.95) v10(96.2,174.95) ; v10(98.23,178.3) 98.23,178.67 v11(98.21,178.7) ; v11(98.64,172.24) v10(98.26,172.24)
  L6SGND w0.254: v4(96.18,174.95) v11(95.83,174.95) ; v11(104.33,175.71) 104.26,175.65 v4(103.8,175.65) ; v4(98.23,178.33) 98.23,178.65 98.21,178.67 v11(98.21,178.7)
  L6SGND w0.305: v4(98.64,172.59) v11(98.64,172.24)
  L7 w0.203: v5(101.43,175.73) 101.54,175.62 101.54,175.61 101.71,175.44 103.6,175.44 v4(103.8,175.65) ; v8(98.63,173.33) 98.63,172.91 98.64,172.89 v4(98.64,172.59)
  L7 w0.254: v4(96.18,174.95) 96.19,174.93 v8(97.43,174.93) ; v4(98.23,178.33) v8(98.23,177.33)
PMIC_BATID: length 4.8
  TOP w0.114: v10(104,176.42) 103.64,176.42 v1(103.06,177.01)
  L3SGND w0.127: v11(103.62,176.6) 103.8,176.42 v10(104,176.42)
  L6SGND w0.06: v8(101.03,175.33) 101.1,175.33 101.96,176.19 102.05,176.19 102.05,176.2 103.21,176.2 v11(103.62,176.6)
PMIC_INT: length 41.4
  L5 w0.076: v4(85.53,176.8) 85.85,176.49 85.85,176.33 86.02,176.16 87.19,176.16 88.05,177.02 91.01,177.02 v11(92.82,175.2)
  L6SGND w0.06: v8(98.23,174.93) 98.03,175.13 96.3,175.13 96.27,175.17 96.21,175.17 95.92,175.46 93.76,175.46 93.58,175.64 93.33,175.64 93.15,175.46 93.08,175.46 v11(92.82,175.2)
  L7 w0.06: 72.85,179.88 72.84,179.88 71.86,179.88 70.85,178.87 70.85,178.43 71.01,178.27 71.01,177.21 70.77,176.97 70.77,176.07 71.15,175.69 71.15,175.29 71.5,174.94 71.5,174.52 71.63,174.39 71.63,171.68 71.74,171.57 71.74,171.41 71.62,171.29 71.62,171.05 71.74,170.93 71.74,170.76 71.82,170.68 v8(71.82,170.57)
  L7 w0.061: v4(85.53,176.8) 85.53,176.99 85.53,176.99 85.53,177.23 85,177.76 85,178.98 84.28,179.7 83.95,179.7 83.78,179.88 79.28,179.88 79.24,179.84 77.06,179.84 76.86,179.63 76.6,179.37 75.5,179.37 74.03,179.37 73.52,179.88 72.85,179.88
PMIC_LCM_BKLT_EN: length 163.9
  TOP w0.114: v2(98.08,59.1) 97.61,59.1 D3405.A ; v9(102.09,55.27) 102.09,55.77 102.37,56.05 v1(102.4,56.05) 102.55,55.9 R4403.2
  L2 w0.061: v9(107.05,50.22) 107.16,50.22 108.57,51.63 108.57,55.06 108.24,55.39 107.48,55.39 107.04,54.96 102.33,54.96 102.09,55.19 v9(102.09,55.27) 101.79,54.96 101,54.96 100.48,55.48 99.21,55.48 v2(99.07,55.34)
  L5 w0.076: v4(101.12,137.35) 101.11,137.35 100.99,137.47 100.99,147.58 100.68,147.89 100.58,147.89 v4(100.49,147.98) ; v5(106.31,185.36) 106.31,185.11 106.64,184.78 106.64,182.68 106.12,182.16 106.12,181.51 106.37,181.26 106.37,170.61 107.38,169.6 107.38,159.33 107.07,159.02 107.07,158.48 107.21,158.35 v4(107.21,158.16)
  L7 w0.061: v4(107.21,158.16) 107.4,158.16 107.65,157.91 107.65,156.38 101.15,149.89 101.15,148.71 100.49,148.05 v4(100.49,147.98) ; v4(101.12,137.35) 103.73,137.35 106.61,134.46 106.61,133.04 108.11,131.55 108.11,123.43 104.5,119.82 104.5,119.58 104.61,119.47 104.61,93.16 102.83,91.38 102.83,89.88 100.64,87.69 100.64,85.98 100.77,85.85 100.77,71.62 98.29,69.14 98.05,68.9 98.05,60.76 97.62,60.33 97.62,59.56 v2(98.08,59.1) 98.27,58.91 98.27,56.24 99.07,55.44 v2(99.07,55.34)
  BOTTOM w0.114: v5(106.31,185.36) 106.23,185.29 PR5108.1
PMIC_LCM_BKLT_EN_R: length 12.1
  TOP w0.114: v1(106.46,52.88) 107.02,52.88 v9(107.38,52.52) 107.56,52.34 D4402.3
  L2 w0.061: v9(107.38,52.52) 107.96,52.52 108.37,52.93 108.37,54.96 108.11,55.21 107.58,55.21 107.12,54.76 102.19,54.76 v9(101.99,54.55)
PMIC_PANEL_PWM0: length 138.6
  TOP w0.114: v1(96.07,62.99) 96.51,62.56 v9(96.51,61.93)
  L2 w0.061: v9(96.51,61.93) 96.72,61.93 v10(97.04,61.62)
  L3SGND w0.127: v11(97.45,61.62) v10(97.04,61.62)
  L5 w0.076: v4(100.06,142.11) 100.35,142.11 100.61,141.85 100.61,141.61 100.52,141.52 100.52,136.9 v4(100.6,136.82) ; v4(109.38,141.98) 109.65,142.25 109.65,150.74 105.95,154.43 105.95,160.24 104.27,161.93 104.27,164.97 103.76,165.47 103.76,169.13 104.23,169.6 104.23,170.73 103.63,171.34 103.34,171.34 102.2,172.48 101.58,172.48 101.33,172.73 101.33,173.43 v8(100.63,174.13)
  L6SGND w0.127: v11(97.45,61.62) 97.4,61.67 v4(97.4,62)
  L7 w0.061: v4(100.6,136.82) 100.71,136.82 101.01,136.53 103.8,136.53 106.09,134.23 106.09,132.82 107.58,131.33 107.58,123.65 103.85,119.92 103.85,93.14 102.3,91.59 102.3,90.1 100.03,87.82 100.03,85.67 100.18,85.53 100.18,80.09 100.18,79.92 100.18,79.92 100.18,79.05 100.18,79.05 100.18,73.82 100.18,73.53 100.18,73.38 100.18,71.77 98.07,69.66 97.52,69.12 97.52,62.13 v4(97.4,62) ; v4(109.38,141.98) 109.31,142.06 108.57,142.06 108.42,142.21 100.16,142.21 v4(100.06,142.11)
PMIC_PANEL_PWM0_R: length 15.7
  TOP w0.114: D4403.3 96,59.94 R4405.1 96.46,59.63 97.14,60.32 v9(97.14,60.62) ; v1(100.85,55.72) 100.99,55.58 v10(100.99,54.55)
  L2 w0.061: v9(97.14,60.62) v10(97.45,60.62)
  L3SGND w0.127: v11(97.42,61.06) 97.42,60.93 97.45,60.9 v10(97.45,60.62) ; v11(101.07,54.12) 100.99,54.21 v10(100.99,54.55)
  L6SGND w0.127: v11(101.07,54.12) 101.02,54.07 v4(100.6,54.07) ; v11(97.42,61.06) v4(97.17,60.8)
  L7 w0.061: v4(100.6,54.07) 98.5,54.07 96.59,55.99 96.59,56.85 97,57.26 97,60.64 v4(97.17,60.8)
PMIC_PWRBTN#: length 4.9
  TOP w0.114: U1704.J10 94.29,36.63 94.73,37.07 94.99,37.07 95.2,37.28 95.2,39.81 95.47,40.08 95.47,40.11 R1737.1
PMIC_PWRBTN_R#: length 147
  TOP w0.114: R1737.2 v10(97.6,40.46)
  L3SGND w0.127: v10(97.6,40.46) v11(97.6,40.99)
  L5 w0.06: 99.64,173.82 99.52,173.93 99.23,173.93 v8(99.03,174.13)
  L5 w0.076: v4(101.97,157.96) 101.97,158.37 101.91,158.43 101.91,158.87 102.32,159.28 102.48,159.28 103.61,160.41 103.76,160.41 103.94,160.58 103.94,160.82 103.76,160.99 103.45,160.99 101.87,162.58 101.62,162.58 100.82,163.38 100.82,172.38 100.61,172.59 100.59,172.59 99.64,173.53 99.64,173.81 99.64,173.82 ; v4(99.43,148.41) 99.11,148.09 99.11,142.22 98.77,141.88 98.77,141.16 98.75,141.14 98.75,140.58 98.77,140.57 98.77,136.67 98.96,136.48 98.96,136.27 98.97,136.26 98.97,135.91 98.96,135.9 98.97,134.87 99.5,134.34 99.5,134.26 100.45,133.31 100.45,129.53 100.06,129.15 100.06,128.29 100.32,128.04 100.32,111.67 100.7,111.29 100.7,110.5 100.7,110.5 100.7,95.43 100.13,94.86 100.13,91.74 100.13,91.11 96.16,87.15 96.16,83.72 95.76,83.31 95.76,81.54 95.76,79.17 95.76,75.89 95.79,75.85 95.79,75.22 95.78,75.21 95.78,74.81 93.12,72.14 93.12,68.55 92.61,68.04 92.61,56.23 92.61,56.23 92.61,56.08 93.34,55.34 93.34,55.33 95.03,53.64 95.03,52.22 95.03,52.06 95.03,52.06 95.03,50.95 95.69,50.29 95.69,44.56 97.41,42.84 97.41,41.18 v11(97.6,40.99)
  L7 w0.061: v4(101.97,157.96) 103.03,156.89 v5(103.03,156.81) 103.03,156.71 101.55,155.23 101.55,152.28 101.14,151.87 101.08,151.81 101.08,150.55 100.14,149.62 100.14,149.12 v4(99.43,148.41)
PMIC_SYSTHERM0: length 66.8
  TOP w0.114: v10(103.87,173.4) 103.62,173.65 101.48,173.65 PR5102.2
  L3SGND w0.127: v11(103.67,173.72) 103.87,173.52 v10(103.87,173.4)
  L5 w0.076: v11(103.67,173.72) 104.2,174.26 104.23,174.26 105.2,175.23 105.2,175.82 105.17,175.85 105.17,179.65 105.93,180.41 105.93,182.27 106.45,182.79 106.45,183.29 106.02,183.73 106.02,185.61 106.7,186.29 106.7,186.63 106.53,186.8 106.1,186.8 105.83,186.53 105.52,186.53 104.54,187.51 98.29,187.51 98.1,187.32 95.66,187.32 93.06,184.72 92.16,184.72 90.04,182.59 90.04,181.84 84.35,176.15 84.35,172.69 86.04,171 86.04,169.82 v5(88.99,166.87)
  L6SGND w0.06: v11(103.67,173.72) 103.63,173.72 103.42,173.93 101.23,173.93 101.03,174.13 v8(101.03,174.13)
  BOTTOM w0.114: v5(88.99,166.87) 89.42,166.44 89.42,163.14 90.64,161.92 v1(90.89,161.92) RT5101.2
PMIC_SYSTHERM1: length 142.2
  TOP w0.114: RT5102.2 105.22,55.27 v2(105.4,55.44) ; v10(99.17,174.95) 98.73,174.51 v1(98.73,174.04) 98.73,173.79 99.1,173.43 PR5103.2
  L3SGND w0.127: v11(99.55,174.95) v10(99.17,174.95)
  L5 w0.076: v4(109.36,142.39) 109.38,142.41 109.38,150.64 103.58,156.45 103.58,159.95 104.13,160.5 104.13,160.9 102.56,162.46 102.56,171.28 100.86,172.98 100.78,172.98 100.04,173.73 100.04,174.37 99.55,174.85 v11(99.55,174.95)
  L6SGND w0.06: v11(99.55,174.95) 99.71,174.95 99.93,174.73 100.38,174.73 100.58,174.53 v8(100.63,174.53)
  L7 w0.061: v4(109.36,142.39) 110.55,142.39 111.9,141.03 111.9,140.22 111.74,140.05 111.72,140.05 109.31,137.64 109.31,133 110.36,131.95 110.36,113.12 109.71,112.48 109.71,108.52 108.68,107.49 108.68,89.67 108.29,89.28 108.29,79.83 107.56,79.1 107.56,77.23 109.47,75.32 109.47,53.18 109.3,53.01 106.79,53.01 106.44,53.36 106.44,54.2 105.4,55.24 v2(105.4,55.44)
PMIC_SYSTHERM2: length 82.3
  TOP w0.114: v9(53.07,177.72) 53.25,177.72 53.96,178.43 62.52,178.43 65.95,181.87 75.66,181.87 75.73,181.94 v10(75.88,181.94) ; PR5104.2 99.63,174.77 v10(100.06,175.2) 98.54,175.2 98.42,175.09 96.59,175.09 96.36,175.32 93.98,175.32 v1(92.47,173.81) 91.55,172.89 87.34,172.89 86.22,174.01 v10(86.22,174.44)
  L2 w0.061: v9(53.07,177.72) 52.4,177.72 50.46,175.78 50.46,171.14 49.49,170.17 49.49,164.77 v10(49.87,164.38)
  L3SGND w0.127: v10(86.22,174.44) v11(86.22,174.95) ; v10(75.88,181.94) 75.93,181.88 v11(75.93,181.35) ; v11(99.81,175.46) v10(100.06,175.2) ; v10(49.87,164.38) 49.52,164.74 v11(49.52,164.82)
  L6SGND w0.06: v8(100.63,174.93) 100.51,174.93 100.31,175.13 100.14,175.13 v11(99.81,175.46)
  L6SGND w0.127: v4(86.23,175.34) 86.22,175.33 v11(86.22,174.95) ; v4(75.93,180.82) v11(75.93,181.35) ; v5(49.41,164.13) 49.41,164.71 v11(49.52,164.82)
  L7 w0.061: v4(86.23,175.34) 86.23,176.13 86.43,176.33 86.43,177.51 85.71,178.23 85.71,181.59 85.68,181.62 85.68,182.63 85.46,182.85 85,182.85 83.72,181.57 82.66,181.57 82.03,180.95 76.06,180.95 v4(75.93,180.82)
  BOTTOM w0.114: v5(49.41,164.13) 49.52,164.23 49.52,164.31 49.85,164.64 RT5103.2
PMIC_VBATSENSE: length 7.7
  TOP w0.254: v10(104.89,176.07) 105.42,176.07 PR5110.2 105.78,176.17 106.44,176.83 v1(106.44,177.26)
  L3SGND w0.254: v11(104.89,175.69) v10(104.89,176.07)
  L6SGND w0.06: v11(104.89,175.69) 104.57,175.36 102.17,175.36 101.94,175.13 100.52,175.13 100.32,175.33 v8(100.23,175.33)
PMIC_VBUS_IN: length 16.2
  TOP w0.114: v1(104.23,163.01) 104.02,162.81 PR4914.1 102.68,162.81 102.04,163.44 v10(101.97,163.44)
  L3SGND w0.127: v10(101.97,163.44) 102.17,163.24 v11(102.17,163.16)
  L5 w0.076: v11(102.17,163.16) 102.35,163.34 102.35,164.71 102.18,164.87 102.18,166.09 101.23,167.04 101.23,169.29 101.88,169.94 101.88,171.77 101.45,172.2 101.38,172.2 100.73,172.85 100.69,172.85 99.9,173.64 99.9,174.06 v8(99.43,174.53)
PMIC_VDCIN: length 14.9
  TOP w0.114: v1(99.94,162.81) PR4912.1 v10(101.59,162.81)
  L3SGND w0.127: v10(101.59,162.81) v11(101.59,163.15)
  L5 w0.06: 101.75,171.65 100.68,172.72 100.64,172.72 99.77,173.58 99.77,173.87 99.51,174.13 v8(99.43,174.13)
  L5 w0.076: 101.75,171.65 101.75,169.99 101.04,169.29 101.04,166.96 101.99,166.01 101.99,163.56 v11(101.59,163.15)
PMU_BATTLOW#: length 47.1
  L5 w0.06: v4(86.9,157.91) 86.85,157.86 86.85,156.94 87.51,156.29 87.51,155.8 87.54,155.76 87.54,155.61 87.57,155.59 v4(87.57,155.39)
  L5 w0.076: v4(89.24,168.12) 89.36,168.23 89.36,168.85 87.74,170.46 v4(87.74,170.99) ; v4(87.53,176.91) 87.55,176.91 87.84,177.21 90.13,177.21 91.68,178.76 v11(92.11,178.76)
  L6SGND w0.06: v11(92.11,178.76) 92.18,178.76 92.38,178.56 93.67,178.56 96.03,176.2 97.36,176.2 v8(97.43,176.13)
  L7 w0.06: v8(80.59,158.96) 80.68,159.05 81.03,159.05 81.15,159.16 81.32,159.16 81.45,159.03 81.45,158.97 81.82,158.6 82.33,158.6 82.92,158.01 82.92,157.05 83.43,156.54 83.43,155.9 83.4,155.87 83.4,155.63 83.86,155.16 83.94,155.16 84.17,154.93 85.86,154.93 86.6,155.67 86.6,156.02 86.83,156.26 87.21,156.26 87.51,155.95 87.51,155.77 87.59,155.7 87.59,155.42 v4(87.57,155.39)
  L7 w0.061: v4(87.74,170.99) 87.51,171.22 87.51,176.88 87.53,176.9 v4(87.53,176.91) ; v4(86.9,157.91) 87.18,158.19 87.18,162.29 88.27,163.38 88.96,164.07 v5(88.96,165.78) 88.96,166.5 88.7,166.76 88.7,167.76 89.06,168.12 v4(89.24,168.12)
PMU_SLP_S0I3_N: length 61.6
  L5 w0.076: v4(89.52,144.06) 89.61,143.97 89.97,143.97 90.31,144.31 90.31,148.74 90.38,148.81 90.38,149.53 90.22,149.69 90.22,150.25 v4(90.16,150.31)
  L7 w0.06: v8(80.03,158.96) 80.31,158.96 80.79,159.45 81.37,159.45 81.69,159.13 81.69,159.07 81.92,158.84 82.39,158.84 82.73,159.18 82.82,159.18 82.84,159.16 83.53,159.16 83.64,159.05 83.64,158.98 84.18,158.44 85.2,158.44 85.6,158.04 85.62,158.04 86.37,157.29 86.37,157.27 86.85,156.79 86.87,156.79 86.95,156.71 87.25,156.71 88.22,155.74
  L7 w0.061: v4(90.16,150.31) 90.16,150.42 88.57,152.01 88.57,155.56 88.42,155.7 88.26,155.7 88.22,155.74 ; v4(89.52,144.06) 89.47,144.06 89.02,144.52 88.75,144.52 88.57,144.7 84.14,144.7 83.85,144.4 83.11,144.4 82.88,144.17 81.82,144.17 81.61,143.97 77.8,143.97 75.42,141.58 74.92,141.58 v5(74.67,141.33) 74.22,140.87 59.28,140.87 59.13,140.87 58.6,140.34 57.74,140.34 55.62,140.34 55.48,140.2 54.25,140.2 v5(53.93,139.88)
POWER_BUTTON_N: length 136.8
  TOP w0.114: v9(103.71,206.32) 103.58,206.19 100.32,206.19 99.72,206.79 PKEY1.2 ; v9(50.46,177.26) 51.32,177.26 53.02,178.96 61.87,178.96 65.44,182.54 65.44,185.33 66.72,186.61 83.2,186.61 85.31,186.61 89.27,190.57 90.36,190.57 91.81,192.02 95.06,192.02 95.54,192.5 98.94,192.5 99.74,193.3 102.51,193.3 105.4,196.18 R5403.2 106.5,196.18 D5404.1 106.54,196.54 106.26,196.82 C5404.2 106.18,197.05 v9(105.27,197.05)
  L2 w0.061: v9(103.71,206.32) 105.02,206.32 108.35,202.99 108.35,198.27 107.59,197.51 107.12,197.05 v9(105.27,197.05) ; v9(50.46,177.26) 50.33,177.14 50.33,171.26 45.59,166.53 45.59,166.49 44.18,165.07 v2(44.18,163.39)
  L7 w0.061: v5(55.93,139.88) 55.93,139.77 55.72,139.56 49.74,139.56 49.16,140.14 v5(49.16,140.2)
  BOTTOM w0.114: v5(49.16,140.2) 49.08,140.28 R5603.1 R5603.2 46.98,140.99 46.98,141.93 44.36,144.55 44.36,156.33 43.47,157.22 43.47,158.62 43.93,159.08 43.93,160.5 44.18,160.75 v2(44.18,163.39)
PPMIC_DEBUG_I2C_CLK: length 4.8
  L6SGND w0.089: v8(102.23,172.53) 102.66,172.53 105.52,169.67 v5(105.8,169.67)
PPMIC_DEBUG_I2C_DATA: length 3.6
  BOTTOM w0.114: TP5102.1 104.53,170.61 102.91,172.23 102.13,172.23 PMIC1.B1
PROCHOT#: length 144.3
  TOP w0.114: v2(96.9,91.4) 97.06,91.4 97.37,91.71 v1(97.37,91.79) 97.17,91.99 96.84,91.99 96.04,91.2 94.79,91.2 94.35,91.64 PR4627.1
  L5 w0.06: v5(74.2,177.24) 74.2,177.1 74.46,176.84 74.55,176.84 74.93,176.46 74.93,175.93 74.91,175.91 74.91,175.88 74.86,175.83 74.81,175.78 74.51,175.48 74.51,175.42 74.38,175.3 74.38,174.92 74.29,174.83 74.29,174.59 74.29,174.5 73.42,173.63 73.42,170.12 73.24,169.93 v8(73.24,169.72)
  L5 w0.076: v4(91.48,164.71) 91.48,164.99 91.44,165.03 91.44,165.24 91.27,165.41 91.09,165.41 89.81,166.69 89.81,167.36 89.81,167.36 89.81,167.52 90.21,167.91 90.21,167.94 90.49,168.22 90.52,168.22 90.92,168.62 90.92,170.51 91.2,170.78 93.47,170.78 96.15,173.47 97.06,173.47 98.59,175 98.59,175.18 98.63,175.21 v8(98.63,175.33) ; v11(92.14,179.42) 91.67,178.95 91.6,178.95 90.05,177.4 87.68,177.4 87.54,177.26 86.96,177.26 v4(86.14,176.45) ; v2(96.9,91.4) 96.9,91.42 96.63,91.69 96.63,93.88 98.98,96.23 98.98,110.19 98.98,110.51 98.54,110.95 98.54,121.41 97.83,122.12 97.83,122.88 97.89,122.95 97.89,123.29 97.92,123.32 97.92,133.39 97.61,133.69 97.61,135.55 97.56,135.6 97.56,135.66 97.56,135.67 97.56,136.51 97.56,136.51 97.56,140.08 97.61,140.14 97.61,149.28 98.46,150.13 v4(98.46,150.19)
  L6SGND w0.06: v11(92.14,179.42) 92.83,178.73 92.95,178.73 93,178.68 93.72,178.68 93.85,178.55 94.15,178.55 95.39,177.31 96.01,177.31 96.59,176.73 97.91,176.73 98.63,176.01 v8(98.63,175.33)
  L7 w0.061: v4(98.46,150.19) 100.85,152.57 100.85,156.1 99.91,157.04 95.96,157.04 94.4,158.6 91.96,161.04 91.96,163.06 91.22,163.8 91.22,164.45 v4(91.48,164.71) ; v5(74.2,177.24) 75.64,178.67 76.89,178.67 76.94,178.73 82.46,178.73 82.49,178.77 83.63,178.77 85.25,177.14 85.25,176.69 85.42,176.52 86.07,176.52 v4(86.14,176.45)
  BOTTOM w0.114: v5(74.2,177.24) 74.2,177.38 74.52,177.69 74.52,178.36 Q501.3
PROJECT_ID1: length 3.9
  TOP w0.114: R1729.2 93.56,40.3 93.94,39.92 93.94,39.47 93.64,39.16 93.64,38.92 93.32,38.6 93.09,38.6 92.88,38.38 92.88,37.87 U1704.G11
PROJECT_ID2: length 2.4
  TOP w0.114: R1744.2 92.67,40.03 92.67,39.52 92.87,39.31 92.87,38.7 92.44,38.27 U1704.G12
PROX_CX: length 1.6
  BOTTOM w0.114: U4101.5 83.72,188.45 84.36,189.1 R4105.2
PROX_CX_R: length 3.9
  BOTTOM w0.114: SPR1.1 84.19,190.83 D4101.2 R4105.1
PROX_DET#: length 85.2
  L5 w0.076: v4(82.84,149.22) 82.84,148.48 80.5,146.15 v4(80.5,145.89)
  L7 w0.061: v5(43.29,141.52) 43.29,141.3 43.86,140.73 55.26,140.73 55.4,140.87 57.52,140.87 58.52,141.86 63.5,141.86 63.51,141.87 63.75,141.87 63.75,141.86 64.01,141.86 64.01,141.87 64.25,141.87 64.25,141.86 65.74,141.86 66.03,141.86 66.35,142.18 66.48,142.18 66.52,142.21 68.23,142.21 68.4,142.04 69.8,142.04 70.85,143.1 75.07,143.1 77.1,145.13 79.61,145.13 80.37,145.89 v4(80.5,145.89) ; v5(13.83,141.27) 15.89,139.21 18.25,139.21 19.49,137.96 27.88,137.96 28.62,138.7 40.06,138.7 v5(40.12,138.76) ; v4(82.84,149.22) 82.84,149.27 82.77,149.34 82.77,149.83 81.72,150.88 81.72,152.61 81.65,152.68 v5(81.65,152.85)
  BOTTOM w0.102: CPU1.BT2 81.63,156.7 81.79,156.53 81.79,154.02 v1(81.75,153.97) 81.79,153.92 81.79,153 v5(81.65,152.85)
  BOTTOM w0.114: v5(40.12,138.76) 40.63,138.76 43.29,141.42 v5(43.29,141.52)
PS8713_3V3: length 3.4
  BOTTOM w0.305: U5407.1 102.52,83.05 102.25,82.77 C3132.1 101.24,82.77 100.95,83.06 R3161.1 ; R3146.2 v1(107.5,88.46)
PWR_AD: length 11.6
  TOP w0.508: 89.39,88.97 89.72,88.64 91.1,88.64 91.88,89.42 91.88,91.06 v12(90.94,91.99) ; PR4621.1 v2(90.74,96.64)
  L2 w0.508: v2(90.74,96.64) 90.74,95.52 90.66,95.45 90.66,95.44 90.41,95.18 90.41,93.11 90.94,92.58 v12(90.94,91.99)
PWR_AD_B:
  vias: v1(86.75,93.29) v1(87.36,99.33) v1(90.18,105.18)
PWR_BT_A:
  vias: v1(93.1,129.26)
PWR_CHG_ACDET: length 4.8
  TOP w0.114: v1(89.78,94.76) 90.31,94.23 PR4623.2 PR4633.2 91.6,94.31 PR4608.2 91.6,95.8 PC4602.2 92.1,96.3 PU4601.6
PWR_CHG_ACN: length 13.1
  TOP w0.102: v9(90.87,100.02) 90.92,99.97 PR4614.1 90.94,99.08 PC4620.1 92.46,98.3 PU4601.1
  L2 w0.061: v9(90.23,90.75) 90.23,91.02 90.41,91.2 90.41,92.35 89.6,93.16 89.6,97.4 90.52,98.32 90.52,99.67 v9(90.87,100.02)
PWR_CHG_ACOK: length 42.4
  TOP w0.114: PR4642.2 97.2,85.8 v9(96.33,85.8)
  L2 w0.061: v2(91.68,70.86) 92.16,71.34 92.16,73.73 95.25,76.82 95.25,80.45 95.22,80.47 95.22,84.17 96.33,85.28 v9(96.33,85.8) 96.33,85.81 96.33,87.31 94.85,88.79 94.85,93.06 92.51,95.41 v9(92.51,96.7)
  BOTTOM w0.114: v2(91.68,70.86) 91.07,70.25 90.36,70.25 89.55,69.44 v1(88.48,69.44) 85.86,69.44 85.28,70.02 85.28,73.51 U701.3
PWR_CHG_ACP: length 15.9
  TOP w0.102: v1(90.94,89.28) 90.49,89.73 v9(90.23,89.73) PG4603.2 ; v9(90.23,99) 89.65,98.42 PC4623.1 90.61,97.89 PR4614.2 90.94,98.17 PC4620.2 91.95,97.9 PU4601.2
  L2 w0.061: v9(90.23,89.73) 89.93,90.04 89.93,91 90.21,91.28 90.21,92.27 89.4,93.08 89.4,97.49 90.32,98.4 90.32,98.92 v9(90.23,99)
PWR_CHG_BAT: length 4.4
  TOP w0.203: PU4601.17 96.93,96.7 PR4605.2
  TOP w0.254: PR4605.2 98.82,94.81 v1(98.82,93.54)
PWR_CHG_BATDRV#: length 31.1
  TOP w0.114: v9(99.1,125.04) v1(100.01,125.04)
  L2 w0.061: v9(96.44,97.1) 96.63,97.28 98.03,97.28 98.04,97.27 98.27,97.27 99.34,98.33 99.34,103.09 99.22,103.2 99.22,122.23 99.1,122.35 v9(99.1,125.04)
PWR_CHG_BTST: length 2.3
  TOP w0.114: v1(94.75,100.11) 94.69,100.11 94.47,99.89 PU4601.25
  TOP w0.305: v1(94.75,100.11) 94.6,100.26 PR4617.1
PWR_CHG_BTST_A: length 3.8
  TOP w0.508: PC4615.1 94.52,102.38 PR4617.2 94.6,103.37 v1(94.93,103.7) 94.97,103.66 PD4601.K
PWR_CHG_CELL: length 2.7
  TOP w0.114: PR4625.1 96.89,94.94 v1(96.81,95.02) 96.91,95.11 96.91,96.19 96.8,96.3 PU4601.16
PWR_CHG_CLK: length 1.9
  TOP w0.114: PU4601.12 94.87,94.58 v1(95.24,94.22) 95.49,93.96 PR4601.2
PWR_CHG_CMPIN: length 21.2
  TOP w0.114: R5722.1 105.17,84.53 R5721.2 103.64,84.53 PC4631.1 102.37,85.8 99.96,85.8 99.15,86.61 99.15,91.13 v1(98.92,91.36) 98.41,91.36 97.32,90.27 95.79,90.27 v9(95.72,90.19)
  L2 w0.061: v9(95.27,95.13) 95.35,95.13 95.88,94.6 95.88,94.36 95.49,93.97 95.49,92.98 95.92,92.54 95.92,90.47 95.72,90.27 v9(95.72,90.19)
PWR_CHG_CMPIN_L: length 3.6
  TOP w0.114: v1(105.2,81.94) PD4604.K 104.87,83.66 R5721.1 PR4646.2
PWR_CHG_CMSRC: length 1
  TOP w0.114: PR4621.2 91.75,97.5 PU4601.3
PWR_CHG_DATA: length 1.9
  TOP w0.114: PR4602.2 94.98,93.82 94.47,94.33 PU4601.11
PWR_CHG_HG: length 16.3
  TOP w0.203: 94.07,99.47 PU4601.26
  TOP w0.305: 94.07,99.47 94.11,99.5 94.11,99.98 v2(93.99,100.1)
  TOP w0.508: v2(91.28,112.23) 91.28,113.1 v1(90.49,113.89)
  L5 w0.508: v2(93.99,100.1) 93.99,101.39 91.28,104.1 v2(91.28,112.23)
PWR_CHG_IADP: length 78.2
  TOP w0.114: v10(92.44,93.62) 92.44,94.15 v1(92.7,94.41) 92.7,95.09 92.51,95.28 PU4601.7
  L2 w0.061: v10(89.9,32.93) 90.82,32.93 91.01,33.12 91.56,33.12 92.11,32.56 92.11,32.38 93.72,30.78 95.05,30.78 95.59,30.23 v9(95.64,30.23)
  L3SGND w0.127: v10(89.9,32.93) v11(89.27,32.93) ; v11(92.7,93.24) 92.44,93.49 v10(92.44,93.62)
  L5 w0.076: v11(89.27,32.93) 87.25,32.93 86.01,34.17 86.01,35.25 86.73,35.97 86.93,35.97 88.39,37.44 88.39,44.87 87.74,45.51 87.74,46.23 87.11,46.86 87.11,51.16 87.82,51.87 87.82,55.2 89.36,56.74 89.36,67.33 89.36,67.7 89.36,71.99 89.36,73.65 89.36,75.51 89.36,75.51 89.36,75.66 89.36,75.98 89.36,76.29 89.36,76.38 90.04,77.06 90.71,77.73 93.09,80.11 93.09,80.27 93.09,80.27 93.09,80.43 93.09,82.64 93.09,82.64 93.09,84.42 93.5,84.82 93.5,88.25 93.5,91.27 92.7,92.07 v11(92.7,93.24)
PWR_CHG_IBAT: length 76.9
  TOP w0.203: v9(93.2,93.62) 93.27,93.69 PU4601.8
  TOP w0.254: v10(96.33,80.94) 95.62,81.66 v1(94.96,81.66) 94.5,81.2 v9(94.5,81.12) ; U1704.M1 96.44,29.27 96.89,28.82 97.73,28.82 v2(98.08,28.47)
  L2 w0.254: v9(93.2,93.62) 93.25,93.62 94.25,92.63 94.25,87.8 94.68,87.37 94.68,84.27 94.55,84.15 94.55,81.17 v9(94.5,81.12)
  L3SGND w0.254: v11(96.33,80.56) v10(96.33,80.94)
  L5 w0.254: v4(96.43,45.18) 96.43,45.33 96.38,45.38 96.38,52.98 93.83,55.53 93.83,55.84 93.12,56.55 93.12,67.6 93.6,68.08 93.6,71.94 96.33,74.67 v11(96.33,80.56)
  L7 w0.254: v2(98.08,28.47) 97.95,28.47 97.22,29.2 97.22,32.89 97.6,33.27 97.6,38.22 98.36,38.98 98.36,40.81 98.06,41.12 96.71,41.12 96.43,41.4 v4(96.43,45.18)
PWR_CHG_ILIM: length 4.2
  TOP w0.203: PR4629.1 96.44,98.94 PU4601.21
  TOP w0.254: PR4629.1 97.32,99.82 PR4628.2 97.4,100.53 97.42,100.55 v1(98.87,100.55)
PWR_CHG_LG: length 14.6
  TOP w0.203: 95.27,99.55 PU4601.23
  TOP w0.305: v2(95.62,99.89) 95.27,99.55
  TOP w0.356: v1(98.28,111.83) 98.13,111.68 97.22,111.68
  L5 w0.508: v2(96.68,111.98) 96.68,102.05 95.62,100.99 v2(95.62,99.89)
PWR_CHG_PH: length 18
  TOP w0.203: 93.67,99.64 PU4601.27
  TOP w0.305: v2(93.36,100.02) 93.36,99.96 93.67,99.64
  TOP w0.508: PC4615.2 93.46,101.35 v1(93.46,100.66) 93.46,100.64 93.36,100.53 v2(93.36,100.02)
  L5 w0.508: v2(92.29,112.86) 91.02,112.86 90.64,112.49 90.64,103.84 93.36,101.13 v2(93.36,100.02)
PWR_CHG_PMON: length 4.5
  TOP w0.114: v1(94.32,91.03) 93.46,91.89 PR4632.1 93.46,92.22 93.67,92.44 PU4601.9
PWR_CHG_PROCHOT#: length 2.2
  TOP w0.114: PR4627.2 94.35,93.68 v1(94.04,93.99) 94.07,94.03 PU4601.10
PWR_CHG_REGN: length 22.3
  TOP w0.114: PU4601.24 94.87,99.71 95.18,100.01 95.18,100.07 95.63,100.53 PR4628.1 96.46,101.26 PD4601.A 96.31,101.52 v9(97.9,101.52) ; PR4635.2 98.18,89.9 v1(98.07,90.01) 97.88,90.01 C5711.1 97.24,89.48 96.76,89.96 95.93,89.96 95.8,89.83 95.79,89.83 v9(95.64,89.68)
  L2 w0.061: v9(95.64,89.68) 96.1,90.14 96.1,92.61 95.67,93.05 95.67,93.43 96.16,93.92 96.16,97.39 96.89,98.12 96.89,100.5 v9(97.9,101.52)
PWR_CHG_REGN_R: length 2.7
  TOP w0.114: v1(98.74,87.37) 98.74,87.85 98.36,88.23 PR4635.1 98.13,88.18 PR4640.2 97.44,88.26 U1705.B2
PWR_CHG_SRN: length 33.8
  TOP w0.102: PU4601.19 97.3,97.5 PC4621.2 97.55,97.56 v9(98.16,97.56)
  L2 w0.061: v9(94.6,126.64) 94.6,125.42 94.86,125.17 95.87,125.17 98,123.03 v12(98.16,123.03) 98.16,122.88 98.93,122.11 98.93,103.08 99.05,102.97 99.05,98.59 98.16,97.7 v9(98.16,97.56)
PWR_CHG_SRP: length 33.1
  TOP w0.102: v9(98.16,98.17) 97.55,98.17 PC4621.1 96.98,97.9 PU4601.20
  L2 w0.061: v9(94.6,123.44) 94.6,124.73 94.84,124.97 95.79,124.97 98.73,122.02 98.73,104.73 v12(98.64,104.64) 98.73,104.55 98.73,103 98.85,102.88 98.85,98.67 98.34,98.17 v9(98.16,98.17)
PWR_CHG_VCC: length 44
  TOP w0.203: 92.99,99.07 PU4601.28
  TOP w0.254: v1(93.62,103.35) 93.05,103.35 v9(92.52,102.81) 92.52,101.34 PC4607.1 92.34,100.2 PC4624.1 92.39,99.66 92.99,99.07 ; v9(93.92,81.99) 94.02,82.09 98.06,82.09 99.18,80.96 103.15,80.96 104.02,81.83 PR4646.1
  L2 w0.254: v9(92.52,102.81) 91.68,102.81 91.27,103.22 90.64,103.22 90.41,102.99 90.41,100.93 89.39,99.92 89.39,98.83 88.62,98.05 88.62,92.57 89.14,92.04 89.14,85.11 92.06,82.19 93.71,82.19 v9(93.92,81.99)
PWR_CHG_VCC_A: length 24.5
  TOP w0.254: v9(89.67,91.54) 89.62,91.54 89.39,91.77 v1(89.39,92.15) 89.42,92.17 90,92.17 90.31,91.87 90.31,91.82 91.09,91.04 PD4605.K
  L2 w0.254: v9(91.3,83.51) 89.52,85.29 89.52,91.38 v9(89.67,91.54) 89.67,92.17 89.01,92.83 89.01,97.73 89.78,98.5 89.78,99.51 90.79,100.53 v9(90.79,102.81)
PWR_SW_IN#: length 78.7
  TOP w0.114: U5401.3 99.99,130.89 99.76,130.65 98.84,130.65 98.62,130.87 PD4606.K 98.62,132.61 99.26,133.24 99.26,135.38 v2(98.55,136.09) ; v10(106.16,186.51) 106.57,186.51 106.67,186.6 107.33,186.6 108.63,187.9 v1(108.63,189.12) 108.63,191 107.68,191.94 107.68,192.55 106.62,193.62 106.62,194 107,194.39 107,195.25 106.63,195.63 R5403.1
  L3SGND w0.127: v11(105.68,186.91) 105.68,186.74 105.9,186.51 v10(106.16,186.51)
  L5 w0.076: v11(105.68,186.91) 105.68,186.94 105.9,187.17 106.46,187.17 107.05,186.58 107.05,171.4 106.75,171.11 106.75,170.76 107,170.52 107.24,170.52 107.33,170.43 107.33,170.25 107.83,169.74 107.83,158.29 107.35,157.81 v4(107.35,157.75) ; v2(98.55,136.09) 98.55,136.23 98.58,136.25 98.58,140.49 98.56,140.51 98.56,144.9 98.91,145.24 98.91,147.12 v4(98.79,147.24)
  L7 w0.061: v4(107.35,157.75) 107.35,156.33 100.82,149.8 100.82,148.86 99.78,147.82 99.38,147.82 v4(98.79,147.24)
R_OSC: length 3
  L2 w0.061: v9(104.43,20.01) 105.23,20.81 105.23,20.84 105.47,21.08 106.11,21.08 106.54,20.65 v9(106.83,20.65)
RF_LTE_SIM1_CLK: length 154.7
  TOP w0.114: NGFF1.32 15.52,142.55 17.39,140.69 18.2,140.69 v1(19.62,139.26) 19.98,138.91 20.64,138.91 v2(21.07,139.34)
  L7 w0.061: v5(112.41,94.2) 111.02,95.59 111.02,97.34 109.63,98.73 109.63,101.96 110.19,102.52 110.19,103.18 110.19,103.67 110.84,104.32 110.84,105.91 110.87,105.94 110.98,106.04 110.98,106.15 111.02,106.19 111.02,115.05 111,115.07 111,121.16 111.36,121.52 111.36,131.57 110.1,132.83 109.75,133.18 109.75,136.98 109.75,137.44 112.35,140.04 112.35,140.4 112.35,141.38 110.8,142.93 84.82,142.93 82.32,140.43 82.02,140.43 81.75,140.15 80.79,140.15 78.03,137.39 44.46,137.39 43.97,137.39 42.11,139.26 42.05,139.26 41.95,139.36 22.71,139.36 22.6,139.26 22.43,139.26 22.13,138.95 21.45,138.95 v2(21.07,139.34)
RF_LTE_SIM1_DATA: length 165
  TOP w0.114: v2(112.76,90.24) 111.71,91.29 MSIM1.7 ; NGFF1.34 16.02,142.61 17.49,141.14 18.66,141.14 v2(20.43,139.36)
  L7 w0.061: v2(20.43,139.36) 21.02,139.95 42.25,139.95 44.22,137.99 77.78,137.99 80.55,140.75 81.51,140.75 81.78,141.02 82.07,141.02 84.57,143.52 111.05,143.52 112.83,141.73 112.94,141.63 112.94,139.79 110.34,137.2 110.34,133.42 112.05,131.72 112.05,121.38 111.95,121.28 111.95,121.27 111.59,120.91 111.59,115.31 112.05,114.85 112.05,114.71 111.85,114.51 111.85,106.08 111.44,105.66 111.44,104.08 110.78,103.42 110.78,99.46 111.66,98.58 111.66,96.92 113.33,95.26 113.33,92.96 112.13,91.77 v5(112.13,89.66)
  BOTTOM w0.114: v5(112.13,89.66) 112.13,89.23 112.69,88.67 D2405.2 112.81,89.56 v1(112.76,89.61) v2(112.76,90.24)
RF_LTE_SIM1_DET: length 131.8
  L3SGND w0.127: v10(101.05,94.7) 101.06,94.7 v11(101.46,94.31)
  L6SGND w0.127: v5(101.08,95.02) 101.08,94.94 101.46,94.56 v11(101.46,94.31)
  L7 w0.061: v5(101.84,95.22) 101.84,112.44 101.3,112.98 101.3,120.57 105.3,124.57 105.3,130.97 102.7,133.57 v5(102.7,133.83)
  BOTTOM w0.114: PR5106.1 D2402.2 101.36,95.22 v5(101.84,95.22) v1(102.63,95.22) ; v5(102.7,133.83) 98.42,138.11 88.53,138.11 86.94,139.7 81.58,139.7 79.96,138.09 38.5,138.09 37.39,139.2 29.45,139.2 28.06,137.82 25.06,137.82 23.13,139.75 23.13,140.58 23.86,141.32 R4012.2
RF_LTE_SIM1_RST: length 156.5
  TOP w0.114: v2(21.7,139.36) 21.6,139.26 21.6,139.25 21.05,138.7 20.75,138.7 20.73,138.68 19.88,138.68 19.86,138.7 19.09,138.7 v1(17.67,140.12) 17.54,140.25 17.23,140.25 15.02,142.47 NGFF1.30 ; MSIM1.2 v2(112.81,95.19)
  L7 w0.061: v2(21.7,139.36) 22.12,139.78 42.18,139.78 44.14,137.81 44.29,137.81 77.86,137.81 80.62,140.57 81.58,140.57 81.85,140.84 82.14,140.84 84.64,143.34 110.98,143.34 112.76,141.56 112.76,140.58 112.76,139.86 110.17,137.27 110.17,133.35 110.27,133.25 111.88,131.65 111.88,121.45 111.78,121.36 111.78,121.34 111.42,120.99 111.42,115.24 111.67,114.98 111.67,106.15 111.26,105.74 111.26,104.15 110.61,103.5 110.61,99.39 111.49,98.5 111.49,96.55 112.81,95.23 v2(112.81,95.19)
  BOTTOM w0.114: v2(112.81,95.19) 112.81,95.2 D2403.2
RF_LTE_UIM_PWR: length 140.7
  TOP w0.305: v2(16.97,142.68) 16.82,142.83 16.75,142.83 16.52,143.05 NGFF1.36
  TOP w0.508: v9(99.91,103.09) 110.83,103.09 112.56,101.37 112.56,101.04 v2(112.43,100.91)
  L2 w0.508: v2(16.97,142.68) 16.97,140.32 19.67,137.61 99.07,137.61 102.22,134.46 102.22,128.19 99.75,125.71 99.75,103.26 v9(99.91,103.09)
  BOTTOM w0.305: 112.46,100.93 112.56,100.93 112.58,100.96 112.97,100.96 113.19,100.73 R2401.1 ; 112.46,100.93 112.56,101.04 112.56,101.14 112.97,101.54 v1(112.97,101.59) ; 112.46,100.93 v2(112.43,100.91) ; v2(16.97,142.68) 17,142.64 C4001.1
RF_W_DISABLE: length 4.8
  BOTTOM w0.114: 11.92,139.9 11.92,139.39 12.07,139.25 U4002.6 12.8,139.25 13.32,138.73 v1(13.5,138.73) ; 11.92,139.9 11.92,140.91 12.36,141.35 R4017.1 ; 11.92,139.9 U4002.5
RF_W_DISABLE#: length 5.8
  TOP w0.114: v1(11.16,142.06) 10.53,142.69 v2(9.89,142.69) 9.52,143.06 NGFF1.8
  BOTTOM w0.114: v2(9.89,142.69) 10.22,142.69 R4020.2 11.03,141.89 11.03,140.98 U4002.3
RF_WIFI_ANT_AUX_1: length 2.4
  TOP w0.089: WL3701.1 WC3706.1 111.02,37.83 v2(111.02,38.45)
  TOP w0.279: v2(111.02,38.45) v1(111.02,39.01)
  BOTTOM w0.089: ANT1.1 v2(111.02,38.45)
RF_WIFI_ANT_AUX_2: length 2.7
  TOP w0.089: WL3701.2 WC3707.1 112.48,37.26 v1(113.09,36.65) 113.45,36.29 113.45,35.86
RF_WIFI_ANT_AUX_3:
  vias: v1(114.11,33.78)
RF_WWAN_DISABLE#_1P8: length 126.3
  TOP w0.114: v9(70.32,175.54) 70.42,175.64 75.34,175.64 v1(75.47,175.51) 75.81,175.51 v10(76.14,175.18)
  L2 w0.061: v10(80.08,185.56) 79.14,184.62 79.14,184.15 78.67,183.68 78.6,183.68 70.45,175.54 v9(70.32,175.54) 69.63,176.22 66.95,176.22 64.43,178.74 51.13,178.74 50.94,178.55 50.94,178.54 50.76,178.35 50.74,178.35 45.88,173.49 45.88,168.12 45.07,167.31 45.07,166.95 43.42,165.3 43.42,160.35 45.86,157.9 45.86,149.73 v10(44.11,147.98)
  L3SGND w0.127: v11(75.93,174.87) 75.93,174.98 v10(76.14,175.18) ; v11(43.83,147.7) v10(44.11,147.98) ; v10(80.08,185.56) 80.22,185.71 v11(80.22,185.92)
  L5 w0.076: v5(10.59,139.9) 11.17,139.9 12.14,138.93 18.22,138.93 18.58,138.58 24.32,138.58 24.75,139.01 27.38,139.01 36.46,148.09 41.55,148.09 41.95,147.7 v11(43.83,147.7)
  L6SGND w0.127: v4(75.78,174.5) 75.78,174.51 75.78,174.72 v11(75.93,174.87) ; v11(80.22,185.92) 80.33,185.82 v5(80.76,185.82)
  L7 w0.06: v4(75.78,174.5) 75.66,174.5 74.6,173.44 74.6,173.38 74.46,173.23 74.46,171.7 74.37,171.6 74.37,170.73 73.84,170.2 73.84,169.96 74,169.8 74,169.63 73.97,169.6 73.89,169.52 73.72,169.52 73.56,169.68 73.48,169.68 73.32,169.52 73.15,169.52 73.04,169.63 72.87,169.63 72.75,169.52 72.59,169.52 72.47,169.63 72.3,169.63 72.19,169.52 72.02,169.52 71.9,169.63 71.74,169.63 71.54,169.43 v8(71.26,169.43)
  BOTTOM w0.114: v5(80.76,185.82) 80.87,185.94 U4101.16
RSMRST#: length 89.4
  L2 w0.061: v10(73.37,143.12) 75.14,144.9 75.94,144.9 80.52,149.48 83,149.48 83.21,149.68 86.45,152.92 86.45,153 88.26,154.81 v10(88.73,154.81)
  L3SGND w0.127: v10(88.73,154.81) 89.08,154.81 v11(89.09,154.81) ; v11(73.27,142.69) 73.27,143.02 v10(73.37,143.12)
  L5 w0.076: v4(91.15,165.12) 91.11,165.12 89.53,166.7 89.53,167.02 89.53,167.18 89.27,167.44 89.12,167.44 88.95,167.62 88.95,167.73 88.76,167.92 88.76,167.96 88.65,168.07 88.48,168.07 88.2,168.35 88.2,168.39 86.79,169.8 86.79,171.08 88.21,172.5 90.31,172.5 91.67,173.87 93,173.87 93.02,173.89 93.22,173.89 93.83,174.49 95.02,174.49 95.17,174.35 96.58,174.35 97.26,175.04 97.84,175.04 99.08,176.27 99.16,176.27 v8(99.43,176.53) ; v11(73.27,142.69) 72.1,143.86 69.38,143.86 69.13,143.61 69.08,143.61 69.08,143.61 67.14,143.61 66.1,143.61 65.61,143.11 64.82,143.11 64.55,143.38 63.05,143.38 62.57,143.86 56.17,143.86 v5(55.54,143.23)
  L6SGND w0.127: v11(89.09,154.81) v4(89.09,155.19)
  L7 w0.061: v8(80.88,159.81) 81.09,160.03 81.64,160.03 81.84,159.83 82.29,159.83 82.59,159.53 82.82,159.53 82.84,159.51 83.38,159.51 83.68,159.51 83.99,159.2 83.99,159.13 84.33,158.79 85.37,158.79 85.48,158.68 85.48,158.66 85.75,158.39 85.77,158.39 86.72,157.43 86.72,157.41 86.99,157.14 87.01,157.14 87.1,157.06 87.33,157.06 87.39,157.06 87.6,156.85 88.32,156.13 88.56,156.13 89.06,155.62 89.06,155.21 v4(89.09,155.19) 89.19,155.19 90.03,156.03 90.03,158.69 88.25,160.47 88.25,160.7 87.97,160.99 87.97,162.14 88.76,162.94 90.74,162.94 v5(90.82,163.01) 90.92,163.11 90.92,164.89 v4(91.15,165.12)
  BOTTOM w0.114: v1(56.3,144.39) 55.53,143.62 XDP1.21
RTC_CLK: length 3.5
  L7 w0.061: v5(97.55,40.74) 97.55,40.56 97.6,40.51 97.6,39.1 v5(97.21,38.71)
  BOTTOM w0.114: v5(97.55,40.74) WR3704.2 96.71,41.19 v1(96.68,41.17)
RTC_XTAL_IN: length 7.7
  L5 w0.076: v8(79.18,159.25) 79.27,159.15 81.21,159.15 82.03,158.33 82.27,158.33 82.93,157.67 82.93,157.51 v5(83.68,156.76)
  BOTTOM w0.114: v5(83.68,156.76) C708.1 83.93,156.31 84.69,155.55 X703.1
RTC_XTAL_OUT: length 7.6
  L5 w0.06: v8(78.9,159.53) 79.18,159.53 79.39,159.32 79.4,159.32
  L5 w0.076: v5(83.68,157.27) 83.63,157.32 83.6,157.32 82.46,158.47 82.09,158.47 81.55,159.01 81.55,159.09 81.32,159.32 79.4,159.32
  BOTTOM w0.114: R730.2 C707.1 83.88,157.98 83.91,157.98 83.96,158.03 X703.2
SAR_A0: length 0.8
  BOTTOM w0.114: R4107.1 80.68,187.14 U4101.19
SAR_A1: length 0.8
  BOTTOM w0.114: U4101.18 81.01,186.74 80.89,186.61 R4103.1
SAR_CSG: length 1.8
  BOTTOM w0.114: TP4101.1 v5(81.65,188.29) 81.71,188.22 U4101.1
SAR_INT: length 143.4
  L5 w0.076: v4(89.83,144.67) 89.83,144.9 89.91,144.98 89.91,148.88 90,148.97 90,149.37 89.43,149.94 89.43,150.43 89.26,150.6 89.1,150.6 v4(88.89,150.82) ; v8(81.23,157.83) 81.29,157.83 83.97,155.15 83.97,154.01 84.19,153.79 84.48,153.79 84.62,153.93 84.87,153.93 85.01,153.79 85.02,153.79 85.6,153.21 v4(86.12,153.21)
  L7 w0.061: v5(44.26,182.14) 44.5,182.38 48.41,182.38 62.18,182.38 66.65,182.38 67.47,182.38 67.76,182.38 68.86,183.49 72.32,183.49 74.43,185.6 78.81,185.6 79.6,184.81 80.25,184.81 81.44,183.61 82.03,183.61 82.23,183.81 v5(82.23,183.92) ; v5(44.31,164.92) 44.13,164.74 44.13,164.63 43.77,164.26 43.77,161.82 45.38,160.22 45.38,160.14 45.57,159.94 45.57,154.18 45.38,153.98 45.38,153.91 44.98,153.51 44.64,153.17 44.64,151.13 44.64,150.84 52.54,142.93 58.05,142.93 59.2,144.08 63.94,144.08 64.9,143.12 65.25,143.12 65.36,143.23 66.05,143.23 67.51,144.69 68.47,144.69 68.58,144.8 74.96,144.8 76.96,146.8 77.84,146.8 77.94,146.9 78.18,147.13 80.66,147.13 81.14,146.65 86.3,146.65 86.8,146.15 88.73,146.15 89.7,145.18 89.7,144.8 v4(89.83,144.67) ; v4(88.89,150.82) 88.51,150.82 v4(86.12,153.21)
  BOTTOM w0.114: v5(44.26,182.14) 44.31,182.09 v1(44.31,165.76) v5(44.31,164.92)
SAR_INT_R: length 1.4
  BOTTOM w0.114: R4108.2 R4101.2 82.92,184.65 U4101.13
SAR_RST: length 3
  BOTTOM w0.114: v1(79.67,184.55) 79.67,184.73 80.35,185.41 R4106.2 80.45,185.47 80.45,185.95 80.7,186.2 80.96,186.2 81.09,186.34 U4101.17
SAR_SVDD_V1P8: length 3.2
  BOTTOM w0.203: C4104.1 83.32,184.54 U4101.12
  BOTTOM w0.305: C4103.1 83.3,184.42 C4104.1
  BOTTOM w0.508: D1708.A 85.46,184.4 R4104.2 84.62,184.42 C4103.1
SD3_CD#: length 6.7
  L7 w0.061: v5(77.84,151.61) 77.84,152.24 77.86,152.27 77.86,153.7 76.66,154.9 76.66,155.5 76.87,155.71 76.87,156.2 76.95,156.28 v8(76.95,156.38)
  BOTTOM w0.114: v1(78.35,152.42) R510.1 v5(77.84,151.61)
SDIO3_RCOMP: length 1.9
  TOP w0.076: v10(77.56,158.85) R504.2 77.35,158.64 v1(77.35,158.06)
  L3SGND w0.114: v10(77.56,158.85) 77.56,159.25 v11(77.48,159.33)
  L6SGND w0.114: v11(77.48,159.33) 77.48,159.28 77.2,159 v8(77.2,158.96)
SDIO_PWR_EN#: length 57.6
  L2 w0.061: v10(99.88,160.42) 99.96,160.35 99.96,159.53 97.7,157.28 88.23,157.28 82.2,151.25 77.05,151.25 76.94,151.14 76.94,151.14 76.18,150.38 76.18,150.38 75.47,149.68 v12(75.47,148.1) v10(75.47,147.62)
  L3SGND w0.127: v11(100.24,160.65) 100.01,160.42 v10(99.88,160.42) ; v11(75.23,147.38) v10(75.47,147.62)
  L5 w0.076: v11(96.94,167.96) 96.53,167.55 96.53,165.94 97.89,164.59 98.48,164.59 99.3,163.76 99.3,162.6 100.05,161.85 100.05,161.4 100.27,161.18 100.27,160.68 v11(100.24,160.65)
  L6SGND w0.06: v11(96.94,167.96) 97.42,168.44 97.42,172.64 98.03,173.25 98.03,173.53 v8(98.23,173.73)
  L6SGND w0.127: v4(74.99,147.77) 74.99,147.72 75.23,147.48 v11(75.23,147.38)
  L7 w0.061: v4(74.99,147.77) 74.99,148.53 75.46,149 75.46,153.14 75.11,153.49 75.11,155.84 75.22,155.95 v8(75.22,156.42)
SDMMC3_1P8_EN: length 57.9
  L2 w0.061: v10(75.93,148.2) 75.93,149.88 76.35,150.3 76.35,150.31 77.01,150.97 77.02,150.97 77.12,151.07 82.28,151.07 88.3,157.1 97.78,157.1 100.24,159.57 100.24,159.85 100.21,159.88 100.21,160.3 100.24,160.33 100.24,160.35 100.85,160.95 v10(101.26,160.95) 101.26,160.93 v12(101.54,160.65)
  L3SGND w0.127: v10(101.26,160.95) 101.13,161.08 v11(101.13,161.39) ; v11(76.21,147.92) v10(75.93,148.2)
  L5 w0.076: v3(99.17,168.79) 98.5,168.12 98.5,165.99 99.87,164.62 99.87,162.83 100.62,162.08 100.62,161.64 100.87,161.39 v11(101.13,161.39)
  L6SGND w0.06: v3(99.17,168.79) 99.24,168.79 99.42,168.97 99.42,171.98 99.42,173.06 99.23,173.25 99.23,174.21 99.11,174.33 98.9,174.33 98.7,174.53 98.63,174.53 v8(98.63,174.53)
  L6SGND w0.127: v4(75.83,148.53) 75.83,148.31 v11(76.21,147.92)
  L7 w0.06: 75.35,154.19 75.35,155.74 75.46,155.85 75.46,156.13 75.54,156.21 75.54,156.66 v8(75.5,156.7)
  L7 w0.061: v4(75.83,148.53) 75.81,148.56 75.81,153.4 75.35,153.86 75.35,154.19
SIM1_CLK_C: length 5.6
  TOP w0.114: v2(112.48,92.98) 112.81,92.66 MSIM1.3
  BOTTOM w0.114: v1(113.09,90.9) 112.61,91.38 112.61,92.22 C2404.1 ; R2403.2 112.91,93.64 D2404.2 C2404.1 ; C2404.1 112.79,92.68 v2(112.48,92.98)
SIM_DETECT: length 3.7
  TOP w0.114: NGFF1.66 v2(24.02,142.57)
  BOTTOM w0.114: v2(24.02,142.57) 23.76,142.83 v1(23.07,142.83) 23.07,142.5 23.28,142.29 23.61,142.29 23.86,142.03 R4012.1
SLP_S0IX#: length 242.6
  L3SGND w0.127: v10(101.84,37.34) 101.84,37.49 101.79,37.54 v11(101.79,37.74)
  L5 w0.076: v4(99.43,148.92) 99.43,148.82 99.72,148.53 99.72,148.29 99.35,147.92 99.35,142.19 98.96,141.8 98.96,141.08 98.94,141.06 98.94,140.66 98.96,140.65 98.96,136.75 99.15,136.56 99.15,136.35 99.16,136.34 99.16,136.21 99.16,134.95 99.69,134.42 99.69,134.34 100.82,133.21 100.82,128.56 100.51,128.25 100.51,111.75 100.89,111.37 100.89,110.42 100.89,95.35 100.32,94.78 100.32,91.82 100.32,91.03 96.35,87.07 96.35,83.64 95.95,83.23 95.95,75.97 95.99,75.93 95.99,75.14 95.97,75.13 95.97,74.73 93.31,72.06 93.31,68.47 92.8,67.96 92.8,56.15 93.53,55.42 93.53,55.41 95.22,53.72 95.22,52.14 95.22,52.14 95.22,51.98 95.22,51.03 95.88,50.37 95.88,45.02 99.15,41.75 99.15,39.73 99.15,39.23 100.64,37.74 v11(101.79,37.74) ; v4(100.85,159.08) 100.77,159.08 99.86,159.99 99.86,161.77 99.07,162.55 99.07,163.72 98.4,164.4 97.79,164.4 96.18,166.01 v11(96.18,168.16) ; v4(84.28,154.11) 84.34,154.17 84.94,154.17 85.26,153.86 85.5,153.86 85.67,154.02 85.92,154.02 86.05,153.89 86.24,153.89 89.86,150.27 89.86,149.78 90.19,149.45 90.19,148.89 90.12,148.81 90.12,144.53 v4(89.85,144.27)
  L6SGND w0.06: v8(97.83,173.73) 97.63,173.53 97.63,173.25 97.29,172.91 97.29,170.28 96.18,169.16 v11(96.18,168.16)
  L7 w0.061: v8(80.91,158.08) 80.93,158.06 81.29,158.06 81.43,157.92 81.43,157.86 82.38,156.92 82.38,156.82 82.38,156.64 82.77,156.25 82.77,155.46 83.11,155.12 83.11,154.2 83.42,153.89 84.06,153.89 v4(84.28,154.11) ; v5(53.53,139.88) 53.53,139.88 54.03,140.38 55.41,140.38 55.55,140.52 57.4,140.52 57.67,140.52 58.2,141.05 59.06,141.05 72.61,141.05 v5(73.14,141.57) 73.32,141.76 75.34,141.76 77.73,144.14 81.54,144.14 81.75,144.35 82.81,144.35 83.04,144.57 83.4,144.57 83.7,144.87 88.64,144.87 88.82,144.69 89.17,144.69 89.47,144.39 89.72,144.39 v4(89.85,144.27) 90.21,144.27 91.43,145.49 93.71,145.49 97.14,148.92 v4(99.43,148.92) 99.43,149.27 100.85,150.69 100.85,151.83 101.07,152.05 101.38,152.35 101.38,156.32 100.85,156.85 v4(100.85,159.08)
  BOTTOM w0.114: v5(53.53,139.88) 53.53,139.22 52.76,138.44 39.86,138.44 39.74,138.57 39.74,139.01 41.52,140.79 41.52,144.85 41.18,145.18 U5709.2
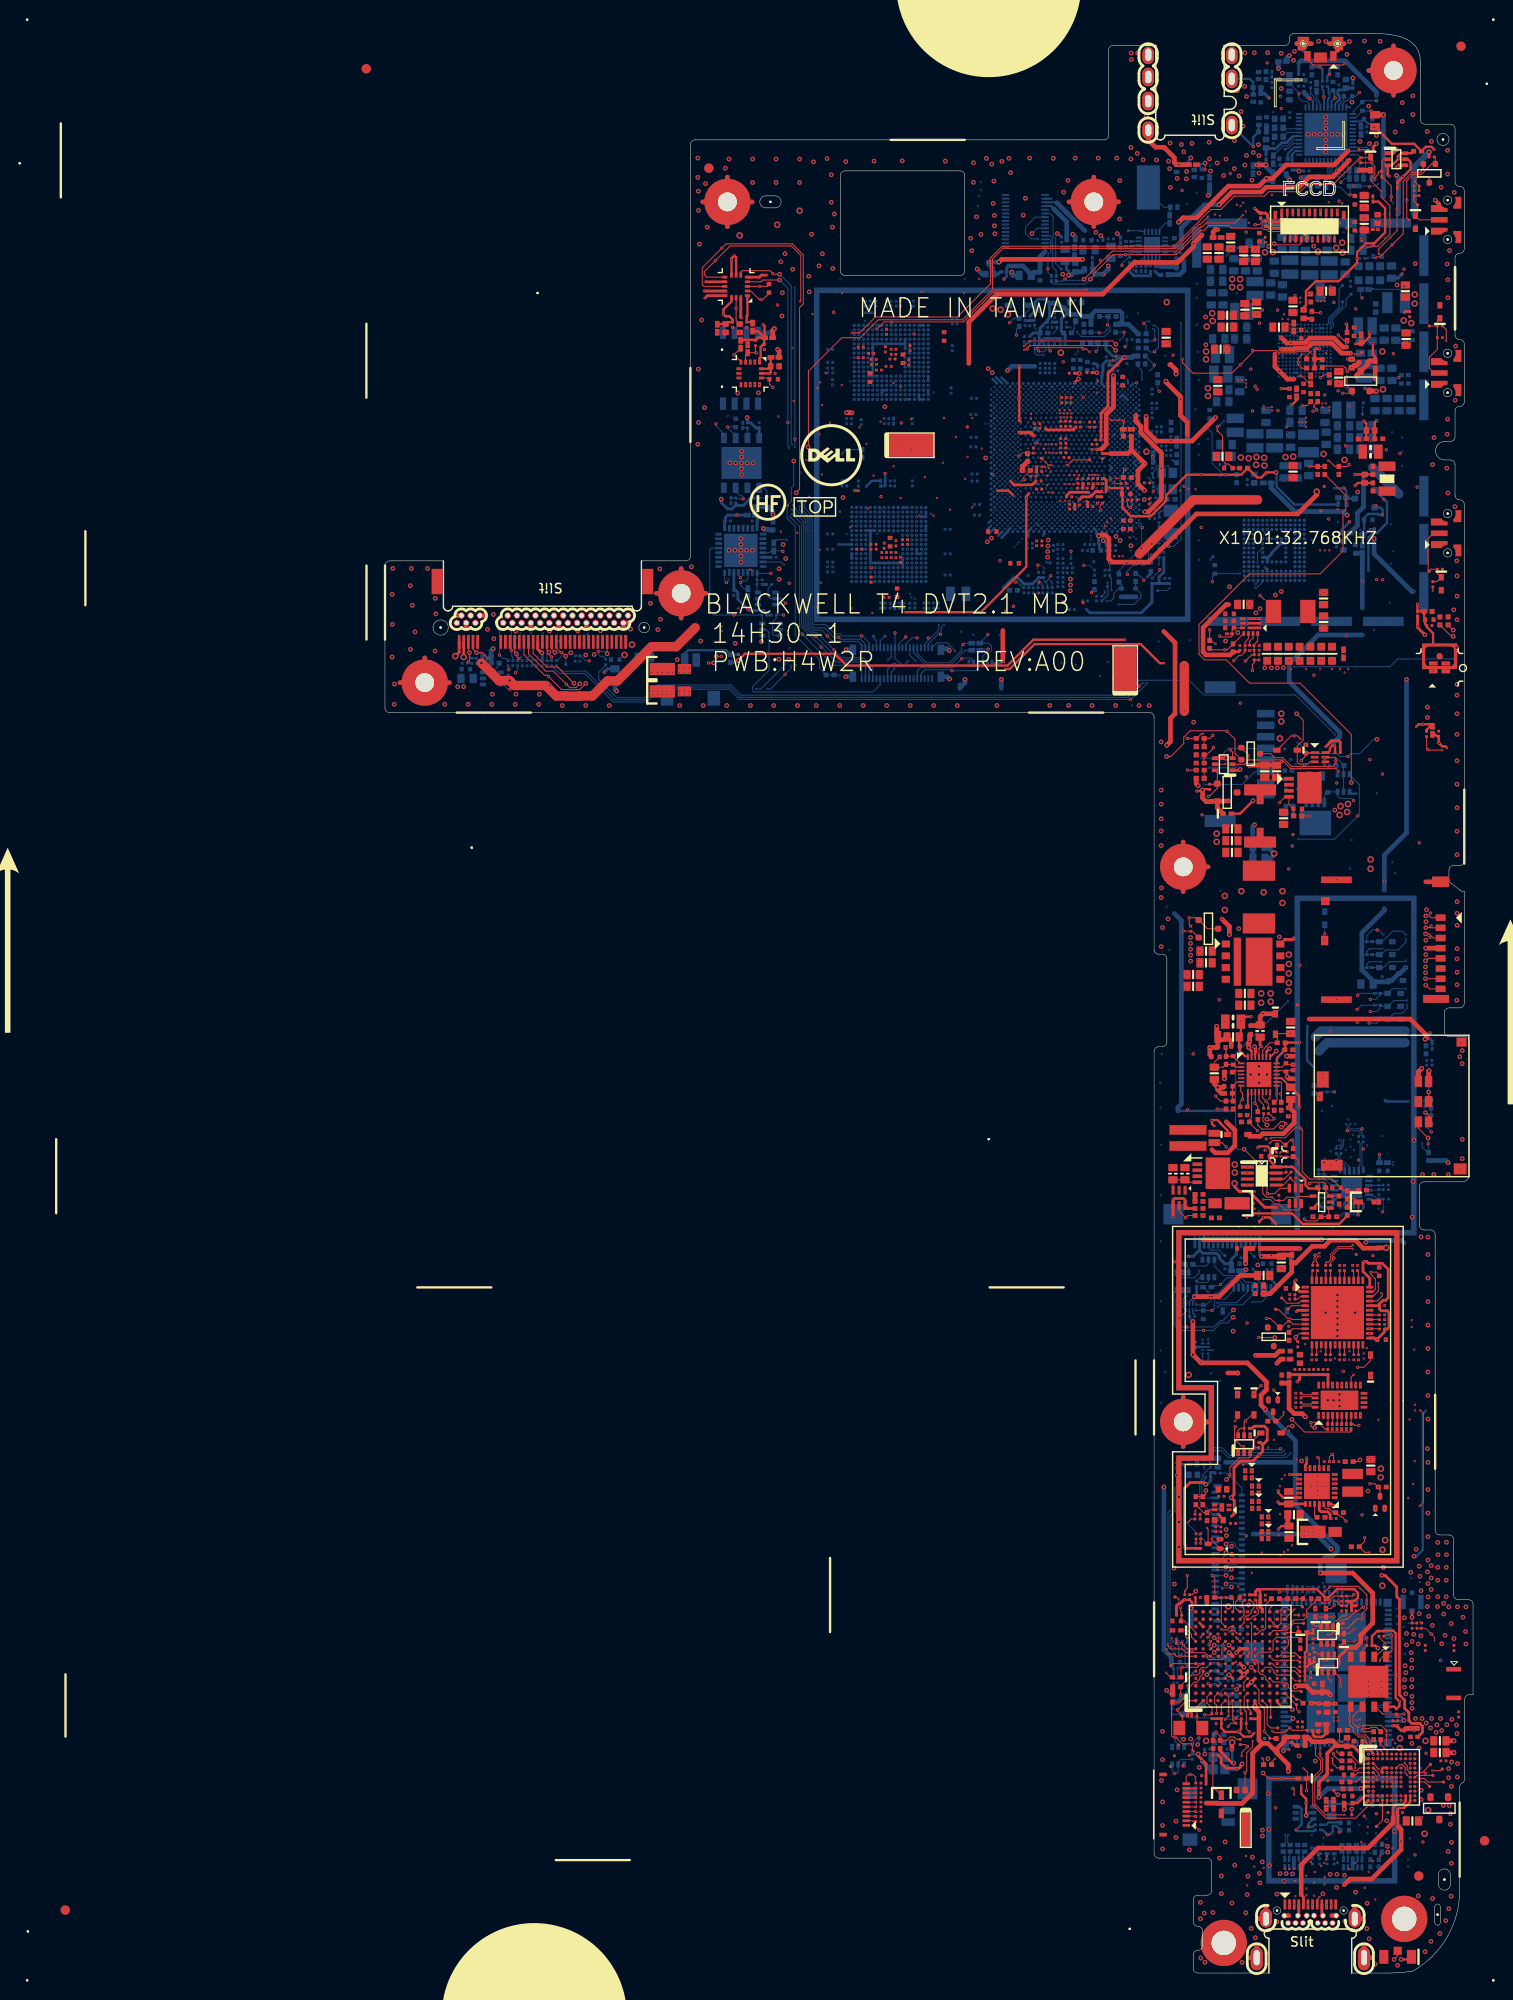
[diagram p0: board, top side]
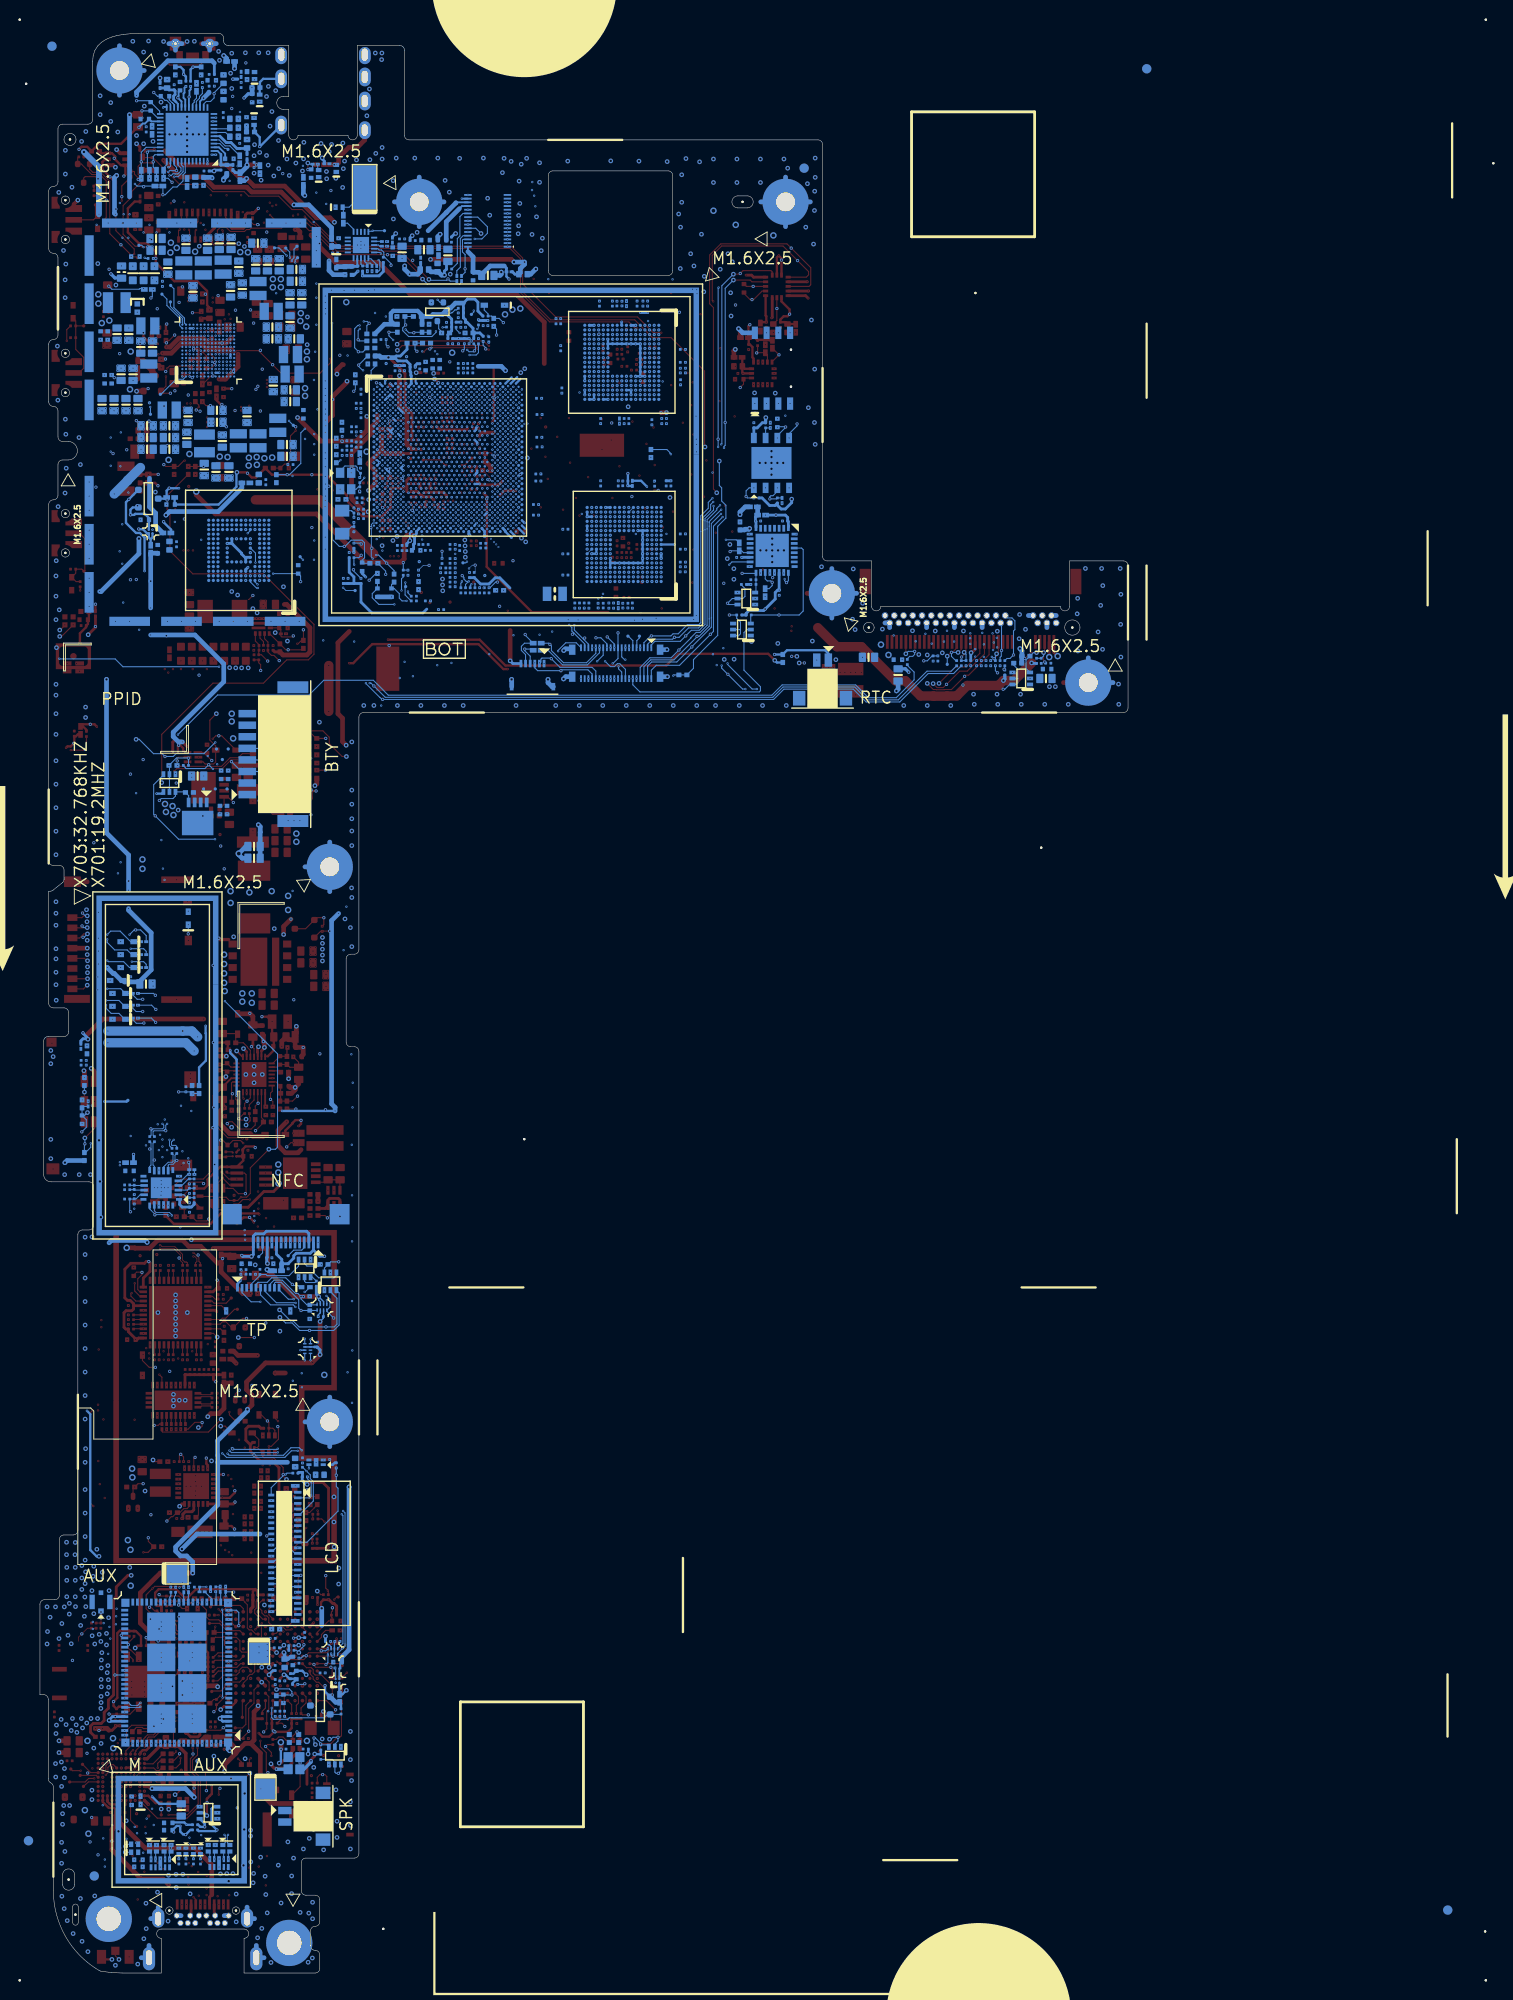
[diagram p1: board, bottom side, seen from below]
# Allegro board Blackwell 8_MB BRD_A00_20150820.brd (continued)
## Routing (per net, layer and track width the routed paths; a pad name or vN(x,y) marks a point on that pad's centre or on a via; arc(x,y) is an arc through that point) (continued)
SLP_S0IX#_EC: length 8.1
  TOP w0.114: U1708.3 100.56,37.47 v9(100.32,37.71) ; U1704.J11 v9(94.35,37.13)
  L2 w0.061: v9(100.32,37.71) 100.16,37.87 97.97,37.87 97.89,37.95 97.84,37.95 97.73,38.06 97.32,38.06 97.3,38.07 94.95,38.07 94.35,37.47 94.35,37.13 v9(94.35,37.13)
SLP_S0IX#_EC_R: length 3.2
  TOP w0.114: U1708.5 101.84,36.11 101.87,36.14 ; 101.87,36.14 102.35,36.14 102.49,36 U1708.6 ; 101.87,36.14 R1732.1
SLP_S3#: length 168.8
  L2 w0.061: v2(86.32,25.27) 86.32,25.09 87.16,24.25 87.67,24.25 87.68,24.25 91.29,24.25 91.29,24.25 91.99,24.25 92.09,24.35 93.68,24.35 94.36,23.67 94.85,23.67 95.36,23.16 v2(95.44,23.16)
  L5 w0.076: v2(95.44,23.16) 94.09,24.51 94.09,26.84 94.84,27.59 94.84,35.65 93.61,36.87 93.61,37.74 95.07,39.2 95.07,42.41 94.54,42.95 94.54,49.07 94.54,49.74 94.08,50.19 94.08,52.46 94.08,52.61 94.08,53.24 92.39,54.93 92.39,54.94 91.65,55.68 91.65,56.47 91.65,56.99 91.65,67.8 91.65,68.43 92.16,68.94 92.16,73.44 93.99,75.26 93.99,75.42 93.99,76.29 93.93,76.35 93.93,77.31 94.99,78.38 94.99,78.69 94.99,78.85 94.99,79.48 94.99,79.48 94.99,81.06 94.99,81.22 94.99,81.85 94.99,81.85 94.99,83.63 95.4,84.03 95.4,87.46 99.36,91.42 99.36,95.17 99.94,95.75 99.94,110.81 99.94,110.97 99.5,111.4 99.5,127.78 99.11,128.17 99.11,133.27 98.32,134.06 98.32,135.11 v4(98.39,135.17) ; v4(84.75,153.64) 84.89,153.64 84.93,153.6 84.94,153.6 85.67,152.88 85.89,152.88 86.14,152.62 86.86,152.62 87.46,152.02 87.46,151.56 87.46,151.4 87.46,151.25 87.46,149.06 87.39,148.99 87.39,148.59 87.46,148.51 87.46,142.14 89.81,139.79 89.81,138.42 91.39,136.85 91.39,135.69 92.22,134.86 94.95,134.86 94.96,134.84 v4(95.9,134.84)
  L7 w0.061: v8(80.91,158.72) 81.01,158.62 81.22,158.62 81.48,158.36 82.23,158.36 82.62,157.97 82.62,157.17 82.62,156.93 82.62,156.92 82.62,156.78 83.02,156.38 83.02,155.59 83.38,155.23 83.38,155.15 83.72,154.81 83.8,154.81 84.02,154.58 84.39,154.58 84.4,154.57 84.47,154.57 84.74,154.3 84.74,154.14 84.75,154.13 v4(84.75,153.64) ; v4(98.39,135.17) 97.97,134.76 97.97,134.76 97.6,134.39 96.35,134.39 v4(95.9,134.84)
  BOTTOM w0.114: v2(86.32,25.27) 86.14,25.27 85.93,25.48 v1(85.4,25.48) 85.4,25.07 85.74,24.73 U1709.2
SLP_S3#_R: length 4.2
  BOTTOM w0.114: R1740.1 86.02,23.08 85.74,22.8 U1709.5 85.74,21.71 85.6,21.58 v1(85.36,21.58) 85.09,21.85 U1709.6
SLP_S4#: length 154.4
  TOP w0.114: v9(101.97,32.52) 101.97,31.81 v1(102.22,31.56)
  L2 w0.061: v10(102.86,38.81) 102.86,38.8 103,38.8 103.37,38.44 103.37,38.11 103.95,37.53 103.95,35.36 103.57,34.99 103.57,34.98 103.07,34.49 103.07,34.09 101.97,32.99 v9(101.97,32.52)
  L3SGND w0.127: v10(102.86,38.81) v11(102.86,39.44)
  L5 w0.06: v8(79.18,158.68) 79.46,158.68 82.73,155.41 82.73,154.5 84.73,152.5 84.76,152.5
  L5 w0.076: 84.76,152.5 85.73,152.5 85.98,152.24 86.7,152.24 87.08,151.86 87.08,149.22 87.01,149.15 87.01,148.43 87.08,148.35 87.08,142.45 87.08,141.98 89.43,139.63 89.43,138.26 90.73,136.97 90.73,135.2 91.37,134.56 v4(94.83,134.56) ; v11(102.86,39.44) 101.74,39.44 101.42,39.76 100.85,39.76 100.69,39.61 100.19,39.61 100.1,39.69 99.99,39.69 99.72,39.97 99.72,43.26 97.24,45.74 97.24,53.33 94.69,55.89 94.69,60.65 94.56,60.78 94.56,61.13 94.65,61.22 94.65,71.37 95.35,72.07 97.39,74.1 97.46,74.17 97.51,74.21 97.51,74.63 97.51,74.63 97.51,75.58 97.51,75.58 97.51,86.87 101.69,91.05 101.69,93.86 102.03,94.2 102.03,98.38 102.02,98.39 102.02,105.21 102.03,105.22 102.03,118.64 101.78,118.9 101.78,133.81 101.13,134.46 v4(101.13,134.54)
  L7 w0.061: v4(101.13,134.54) 101.13,134.56 100.61,135.07 99.5,135.07 99.19,135.38 99.11,135.46 98.27,135.46 97.37,134.56 96.6,134.56 96.04,135.13 95.39,135.13 v4(94.83,134.56)
SLP_S4#_R: length 2.8
  TOP w0.114: U1710.5 101.97,33.85 101.84,33.73 101.46,33.73 101.32,33.87 U1710.6 100.97,34.42 100.75,34.64 R1745.1
SMB3_CLK_BATT: length 111
  TOP w0.114: v2(91.25,35.43) U1704.F8 ; v10(87.69,129.99) v1(86.75,129.99)
  L3SGND w0.061: v10(87.69,129.99) 88.25,129.99 88.38,130.12 v11(88.56,130.12)
  L5 w0.076: v11(88.56,130.12) 89.03,129.65 93.04,129.65 93.38,129.99 96.63,129.99 97.7,128.92 97.7,123.02 97.64,122.96 97.64,122.04 98.35,121.33 98.35,110.87 98.7,110.52 98.7,96.22 96.19,93.7 96.19,91.45 94.45,89.71 94.45,87.86 94.45,87.86 94.45,84.43 94.04,84.02 94.04,82.25 94.04,80.83 94.04,80.67 94.04,79.88 94.04,79.63 90.31,75.9 90.31,73.26 90.31,72.39 90.31,71.6 90.31,68.1 90.31,68.09 90.31,66.94 90.31,66.94 90.31,57.35 90.31,56.34 90.16,56.19 90.16,55.48 90.03,55.35 90.03,36.65 v2(91.25,35.43)
  BOTTOM w0.114: R1717.1 91.53,35.15 v2(91.25,35.43)
SMB3_CLK_BATT_R: length 11.4
  TOP w0.114: D4502.1 R4502.2
  L3SGND w0.061: v10(88.56,129.08) v11(88.94,129.08)
  L6SGND w0.089: v5(88.56,128.44) 88.56,128.47 88.94,128.85 v11(88.94,129.08)
  BOTTOM w0.114: v5(88.56,128.44) 92.67,128.44 94.07,129.85 BATT1.3 95.85,129.85 v1(96.91,130.91)
SMB3_DAT_BATT: length 109.9
  TOP w0.114: U1704.D9 90.04,35.85 89.65,36.24 v2(89.65,36.24)
  L3SGND w0.061: v10(87.67,130.74) 87.91,130.74 v11(88.07,130.58)
  L5 w0.076: v2(89.65,36.24) 89.65,53.53 89.78,53.66 89.78,53.98 89.56,54.19 89.56,55.86 90.12,56.42 90.12,67.02 90.12,68.02 90.12,72.31 90.12,72.86 90.12,75.98 93.85,79.71 93.85,79.96 93.85,79.96 93.85,80.59 93.85,80.75 93.85,82.33 93.85,82.33 93.85,84.1 94.26,84.51 94.26,87.94 94.26,89.79 96,91.53 96,93.78 98.51,96.3 98.51,110.44 98.16,110.79 98.16,121.25 97.45,121.96 97.45,123.04 97.51,123.1 97.51,128.84 96.55,129.8 93.46,129.8 93.12,129.46 88.68,129.46 88.07,130.06 v11(88.07,130.58)
  BOTTOM w0.114: v1(90.2,36.19) 90.18,36.19 90.13,36.24 v2(89.65,36.24) 89.64,36.24 R1718.1
SMB3_DAT_BATT_R: length 9.8
  TOP w0.114: R4503.2 D4501.1 88.84,131.64 89.55,132.35 v1(89.55,132.43)
  L3SGND w0.061: v10(88.58,130.75) 89.06,130.75 v11(89.09,130.78)
  L6SGND w0.089: v5(89.04,130.25) 89.04,130.68 89.09,130.73 v11(89.09,130.78)
  BOTTOM w0.114: v5(89.04,130.25) 91.95,130.25 92.79,131.09 95.2,131.09 BATT1.4
SND75DP130SS_3V3: length 38.5
  TOP w0.305: U3102.36 106.45,75.1 105.73,75.81 105.73,76.75 v1(105.85,76.88) 106.13,76.88 106.32,76.69 107.81,76.69 108.44,76.05 108.44,72.97 108.16,72.69 107.86,72.69 107.5,72.33 C3031.1 ; C3031.1 107.5,71.75 107.68,71.57 108.32,71.57 108.53,71.36 108.53,69.78 108.34,69.59 R3022.1 108.06,69.31 107.28,68.52 v9(107.28,68.45) 107.12,68.45 106.95,68.62 U3102.25 ; C3031.1 107.49,72.12 U3102.32 ; U3102.6 98.66,71.62 v9(98.51,71.47)
  L2 w0.508: v9(107.28,68.45) 107.28,66.54 106.08,65.35 99.94,65.35 98.92,66.37 v9(98.92,66.82) ; v9(99.47,74.12) 98.6,74.12 v9(97.8,73.32) 98.08,73.32 98.51,72.89 v9(98.51,71.47) 98.51,69.74 99.48,68.78 v9(99.48,67.97)
SOC_PROJECT_ID1: length 15.9
  L5 w0.06: v5(74.81,177.41) 74.81,176.83 75.1,176.54 75.1,175.85 75.09,175.84 75.09,175.81 75.08,175.8 74.69,175.41 74.69,174.98 74.46,174.75 74.46,174.52 74.46,174.5 73.54,173.58 73.54,170.07 73.44,169.96 73.44,169.63 73.24,169.43 v8(73.24,169.15)
  BOTTOM w0.114: v5(74.81,177.41) 74.81,177.28 75.25,176.85 77.76,176.85 78.4,177.49 78.4,177.79 v1(78.09,178.1) 78.17,178.18 R412.2 R411.2
SOC_PROJECT_ID2: length 12.2
  L7 w0.06: v5(78.09,177.62) 77.3,176.83 76.98,176.83 73.76,173.61 73.76,173.53 73.76,171.17 74,170.93 74,170.77 73.88,170.65 73.6,170.65 v8(73.52,170.57)
  BOTTOM w0.114: v5(78.09,177.62) 77.73,177.25 v1(77.21,177.25) 77.15,177.31 R417.2 R418.2
SOC_PWRBTN#: length 47
  L2 w0.061: v10(102.22,159.46) 102.22,159.34 102.19,159.32 102.19,159.04 v12(101.17,158.02) 99.59,156.44 88.65,156.44 85.2,153 v10(85.2,152.85)
  L3SGND w0.06: v11(102.43,159.76) 102.43,159.66 v10(102.22,159.46)
  L3SGND w0.127: v10(85.2,152.85) 85.14,152.85 84.95,153.05 84.95,153.05 v11(84.93,153.07)
  L5 w0.06: v11(84.93,153.07) 84.79,153.21 84.51,153.21 83.02,154.7 83.02,155.59 80.91,157.7 80.91,157.79 79.83,158.88 78.98,158.88 v8(78.9,158.96)
  L5 w0.076: v11(102.43,159.76) 102.05,160.14 102.05,161.13 100.06,163.11 100.06,167.18 99.5,167.74 v3(99.5,168.6)
  L6SGND w0.06: v8(98.63,174.93) 98.79,174.77 99.07,174.77 99.23,174.61 99.23,174.45 99.34,174.33 99.51,174.33 99.63,174.21 99.63,168.88 99.51,168.76 99.51,168.66 99.5,168.66 v3(99.5,168.6)
SOC_RTEST#: length 81.6
  TOP w0.114: PC5005.2 PC5004.1 91.19,163.07 90.93,163.07 90.54,163.46 90.54,166.11 v10(89.98,166.67) v1(89.98,167.1)
  L2 w0.061: v10(88.71,156.08) 88.68,156.08 86.1,153.49 86.1,153.07 82.86,149.83 80.38,149.83 75.8,145.25 74.2,145.25 v10(72.1,143.15)
  L3SGND w0.127: v11(71.97,142.74) 71.97,143.02 v10(72.1,143.15) ; v10(89.98,166.67) 90.31,167 v11(90.38,167) ; v10(88.71,156.08) 88.58,156.08 88.53,156.03 88.15,156.03 v11(88.11,156.07)
  L5 w0.076: v5(61.61,142.84) 64.55,142.84 64.66,142.73 65.76,142.73 66.26,143.23 66.99,143.23 69.23,143.23 69.24,143.23 71.48,143.23 v11(71.97,142.74) ; v11(90.38,167) 90.64,167.25 90.71,167.25 94.33,170.87 97.78,170.87 97.92,170.72 99.07,170.72 99.26,170.91 99.26,172.59 98.45,173.4 98.45,173.42 98.28,173.59 98.28,174.08 98.73,174.53 v8(99.03,174.53)
  L6SGND w0.127: v4(88.35,156.51) 88.35,156.31 88.11,156.07 v11(88.11,156.07) ; v11(90.38,167) 90.21,166.82 v4(89.7,166.82)
  L7 w0.061: v8(80.59,160.1) 80.71,160.1 81.19,160.58 81.24,160.6 82.26,160.6 82.49,160.38 82.49,160.06 82.87,159.68 83.31,159.68 83.74,159.68 83.78,159.68 84.16,159.3 84.16,159.2 84.4,158.96 85.44,158.96 85.66,158.75 85.66,158.73 85.82,158.56 85.84,158.56 86.9,157.5 86.9,157.48 87.07,157.32 87.09,157.32 87.17,157.24 87.4,157.24 87.4,157.23 87.47,157.23 87.77,156.93 87.77,156.93 88.19,156.51 v4(88.35,156.51) 88.43,156.59 88.43,156.99 87.79,157.63 87.79,162.37 89.55,164.13 89.55,166.62 89.7,166.77 v4(89.7,166.82)
  BOTTOM w0.114: v5(61.61,142.84) 61.61,142.93 60.79,143.75 59.65,143.75 59.14,143.24 59.14,143.23 XDP1.39
SOC_VBUSSNS: length 7.8
  L7 w0.06: v5(81.82,172.2) 82.13,171.88 82.13,170.92 81.77,170.55 81.77,170.28 80.05,168.57 80.05,168.41 79.94,168.3 79.94,168.22 79.54,167.81 79.54,167.53 v8(79.46,167.45)
  BOTTOM w0.114: R408.2 81.39,173.6 81.82,173.18 v5(81.82,172.2)
SPI3_CS0_N: length 7.8
  L5 w0.06: v8(71.54,157.83) 71.54,156.91 71.39,156.76 71.39,155.87 71.34,155.82 71.34,155.62 71.39,155.58 71.39,155.1 71.24,154.96 v5(71.24,151.79)
  BOTTOM w0.06: R509.2 70.57,151.46 v1(70.57,152.14) 70.88,152.14 v5(71.24,151.79)
SPI_CLK: length 110.3
  L5 w0.06: v4(74,147.95) 74,147.42 78.02,143.4 78.56,143.4 78.74,143.22 78.74,142.69 79.05,142.38 79.72,142.38 v4(80.3,141.8)
  L7 w0.06: v4(74,147.95) 74.64,148.59 74.64,148.68 75.04,149.07 75.04,153.07 74.66,153.44 74.66,156.07 74.89,156.3 74.89,156.46 74.71,156.64 74.71,157 74.93,157.22 v8(74.93,157.27)
  L7 w0.061: v4(80.3,141.8) 80.3,141.78 79.97,141.45 79.54,141.45 76.78,138.69 47.67,138.69 46.58,139.78 43.42,139.78 37.43,145.76 35.12,145.76 34.76,146.12 34.76,161.68 34.86,161.78 35.43,161.78 35.5,161.84 35.5,161.96 35.43,162.02 34.54,162.02 34.47,162.09 34.47,162.21 34.54,162.27 35.43,162.27 35.5,162.33 35.5,162.45 35.43,162.51 34.54,162.51 34.47,162.57 34.47,162.69 34.54,162.76 35.43,162.76 35.5,162.82 35.5,162.94 35.43,163 34.54,163 34.47,163.06 34.47,163.24 37.12,165.89 v5(37.91,165.89) ; v5(37.91,167.05) 37.73,167.05 36.74,168.04 36.74,168.52 37.2,168.98 37.2,169.95 37.5,170.25 37.5,176.95 v5(37.8,177.25)
  BOTTOM w0.114: v5(37.91,167.05) 37.86,167.1 37.04,167.1 v1(37.02,167.08) 37.02,167.03 37.91,166.14 v5(37.91,165.89)
SPI_CS#: length 102.8
  L5 w0.076: v5(40.34,169.6) 40.8,169.14 40.8,160.85 v5(40.45,160.49) ; v4(73.62,148) 73.62,147.82 73.82,147.62 73.82,147.34 78.11,143.05 78.4,143.05 v4(78.42,143.07)
  L7 w0.061: v8(74.69,156.38) 74.54,156.23 74.54,152.99 74.85,152.68 74.85,149.2 73.65,148 v4(73.62,148) ; v5(40.45,159.41) 39.1,159.41 36.6,156.9 36.6,155.2 36.42,155.02 36.42,148.91 36.55,148.78 36.63,148.78 36.98,149.13 37.06,149.13 37.15,149.04 37.15,148.95 36.81,148.61 36.81,148.52 36.89,148.44 36.98,148.44 37.32,148.78 37.41,148.78 37.5,148.7 37.5,148.61 37.15,148.26 37.15,148.18 37.24,148.09 37.32,148.09 37.67,148.44 37.75,148.44 37.84,148.35 37.84,148.26 37.5,147.92 37.5,147.83 37.58,147.75 37.67,147.75 38.01,148.09 38.1,148.09 38.19,148.01 38.19,147.92 37.84,147.57 37.84,147.49 37.93,147.4 38.01,147.4 38.36,147.75 38.44,147.75 38.53,147.66 38.53,147.58 38.19,147.23 38.19,147.14 38.27,147.06 38.36,147.06 38.7,147.4 38.79,147.4 38.88,147.32 38.88,147.23 38.53,146.88 38.53,146.8 39.13,146.2 39.13,146.11 38.68,145.66 38.68,145.58 38.77,145.49 38.85,145.49 39.3,145.94 39.39,145.94 39.48,145.85 39.48,145.77 39.03,145.32 39.03,145.23 39.11,145.14 39.2,145.14 39.65,145.59 39.74,145.59 39.82,145.51 39.82,145.42 39.37,144.97 39.37,144.89 39.46,144.8 39.54,144.8 39.99,145.25 40.08,145.25 40.17,145.16 40.17,145.08 39.72,144.63 39.72,144.54 39.8,144.45 39.89,144.45 40.34,144.9 40.43,144.9 40.51,144.82 40.51,144.73 40.06,144.28 40.06,144.2 40.15,144.11 40.23,144.11 40.68,144.56 40.77,144.56 43.01,142.32 43.01,141.18 43.69,140.49 46.97,140.49 48.07,139.39 59.13,139.39 60.24,140.49 76.2,140.49 78.4,142.69 78.4,143.05 v4(78.42,143.07)
  BOTTOM w0.114: v5(40.45,160.49) 40.96,160.49 41.29,160.17 v1(41.29,159.56) 41.13,159.41 v5(40.45,159.41)
SPI_MISO: length 104.6
  L5 w0.076: v4(79.23,142.87) 79.26,142.89 79.26,143.23 76.82,145.67 76.82,146.45 75.11,148.16 75.11,152.85 74.31,153.65 74.31,158.33 v8(74.4,158.41) ; v5(39.07,169.6) 40.61,168.06 40.61,161.07 40.03,160.49 v5(39.18,160.49)
  L7 w0.061: v4(79.23,142.87) 79.26,142.85 79.26,142.75 v5(78.2,141.69) 76.83,140.32 60.31,140.32 59.2,139.21 47.9,139.21 46.81,140.3 43.63,140.3 41.98,141.95 41.98,142.04 42.4,142.46 42.4,142.54 42.32,142.63 42.23,142.63 41.81,142.21 41.73,142.21 41.64,142.3 41.64,142.38 42.06,142.8 42.06,142.89 41.97,142.97 41.88,142.97 41.47,142.56 41.38,142.56 41.3,142.64 41.3,142.73 41.71,143.15 41.71,143.23 41.63,143.32 41.54,143.32 41.12,142.9 41.04,142.9 40.95,142.99 40.95,143.07 41.37,143.49 41.37,143.58 41.28,143.66 41.19,143.66 40.78,143.25 40.69,143.25 38.36,145.58 38.36,145.67 38.84,146.15 38.84,146.24 38.75,146.33 38.67,146.33 38.18,145.84 38.1,145.84 38.01,145.93 38.01,146.01 38.49,146.5 38.49,146.59 38.41,146.67 38.32,146.67 37.84,146.19 37.75,146.19 37.67,146.27 37.67,146.36 38.15,146.84 38.15,146.93 38.06,147.02 37.98,147.02 37.49,146.53 37.41,146.53 37.32,146.62 37.32,146.7 37.81,147.19 37.81,147.28 37.72,147.36 37.63,147.36 37.15,146.88 37.06,146.88 36.98,146.96 36.98,147.05 37.46,147.53 37.46,147.62 37.37,147.71 37.29,147.71 36.8,147.22 36.72,147.22 36.63,147.31 36.63,147.39 37.12,147.88 37.12,147.97 37.03,148.05 36.94,148.05 36.46,147.57 36.37,147.57 36.25,147.69 36.25,155.13 36.42,155.31 36.42,157.47 39.18,160.22 v5(39.18,160.49)
SPI_MODE: length 8.6
  L5 w0.076: v8(71.82,170) 71.78,170.04 71.78,175.34 70.95,176.16 70.95,177.24 71.58,177.87 v5(71.64,177.87)
SPI_MOSI: length 108.3
  L5 w0.076: v4(83.2,142.9) 83.12,142.9 82.36,143.66 79.91,143.66 77.69,145.88 77.69,148.28 75.7,150.27 75.7,152.9 74.65,153.95 v8(74.65,157.55)
  L7 w0.061: v4(83.2,142.9) 83.17,142.93 82.66,142.93 81,141.27 79.63,141.27 76.87,138.51 47.57,138.51 46.48,139.6 43.34,139.6 37.36,145.59 35.03,145.59 34.55,146.06 34.55,161.59 34.25,161.89 34.25,163.5 v5(36.64,165.89) 36.64,167.63 36.39,167.89 36.39,168.47 37.02,169.11 37.02,170.05 37.32,170.35 37.32,176.46 v5(36.53,177.25)
  BOTTOM w0.114: v1(35.77,167.41) 35.77,167.2 36.64,166.34 v5(36.64,165.89)
SPK_LN: length 200
  L5 w1.016: v5(110.27,101.8) 110.27,101.8 111.09,102.62 111.09,104.07 113.68,106.66 113.68,115.19 112.25,116.61 112.25,120.46 113.68,121.88 113.68,143.1 113.32,143.46 113.32,151.01 110.73,153.6 110.73,176.37 112.58,178.22 112.58,185.27 103.45,194.41 101.05,194.41 100.48,194.97
  L7 w1.016: v13(88.76,25.09) 89.88,25.09 90.99,26.21 92.96,26.21 94.99,28.24 94.99,39.66 93.79,40.86 93.79,45.87 94.9,46.98 94.9,52.68 93.12,54.46 93.12,57.51 92.99,57.64 92.99,69.95 96.66,73.62 96.66,83.74 96.08,84.32 96.08,88.8 98.84,91.56 98.84,93.03 98.85,93.04 98.85,99.44 v5(100.57,101.16)
  BOTTOM w1.016: v5(110.27,101.8) v1(102.2,101.8) 101.21,101.8 v5(100.57,101.16)
  vias: v3(99.5,195.8) v3(99.51,195.48) v4(99.5,195.8) v4(99.51,195.48) v5(99.5,195.8) v5(99.51,195.48)
SPK_LN_R: length 1.7
  BOTTOM w0.356: R2108.2 89.09,22.02 88.32,22.79 v1(88.32,22.94)
SPK_LP: length 202.4
  TOP w0.508: v13(91.58,24.94) 91.55,24.91 v1(91.55,24.18)
  L5 w1.016: v5(110.27,100.53) 110.8,100.53 111.54,101.27 111.54,101.28 112.06,101.8 112.07,101.8 112.36,102.08 112.36,103.54 114.95,106.13 114.95,115.72 113.52,117.14 113.52,119.93 114.95,121.36 114.95,143.63 114.59,143.98 114.59,151.53 112,154.12 112,175.84 113.85,177.69 113.85,185.8 103.97,195.68 101.57,195.68 100.5,196.75 99.86,196.75
  L7 w1.016: v13(91.58,24.94) 93.48,24.94 96.26,27.71 96.26,40.19 95.06,41.39 95.06,45.34 96.17,46.45 96.17,53.21 94.39,54.99 94.39,58.03 94.26,58.17 94.26,69.42 97.93,73.1 97.93,84.27 97.35,84.85 97.35,88.27 100.11,91.03 100.11,92.5 100.12,92.51 100.12,98.81 v5(100.95,99.64)
  BOTTOM w1.016: v5(110.27,100.53) 101.84,100.53 v5(100.95,99.64)
  vias: v3(98.62,196.5) v3(99.03,196.5) v4(98.62,196.5) v4(99.03,196.5) v5(98.62,196.5) v5(99.03,196.5)
SPK_LP_R: length 1.3
  BOTTOM w0.356: R2107.2 92.04,22.02 v1(92.06,22.04)
SRT_CRST#: length 62.6
  TOP w0.114: v10(80.28,159.2) 80.28,158.54 80.45,158.36 v1(80.58,158.36) 80.73,158.52 C709.1
  L3SGND w0.127: v11(80.35,159.81) 80.28,159.74 v10(80.28,159.2)
  L5 w0.076: v4(90.29,150.7) 90.5,150.5 90.5,149.68 90.58,149.61 90.58,148.73 90.5,148.66 90.5,144.23 90.04,143.77 89.31,143.77 v4(89.09,143.99)
  L6SGND w0.127: v8(80.59,159.53) 80.59,159.57 v11(80.35,159.81)
  L7 w0.061: v8(80.59,159.53) 80.71,159.53 80.77,159.6 81.61,159.6 81.63,159.61 82.33,159.61 82.54,159.41 82.77,159.41 82.84,159.33 83.45,159.33 83.45,159.33 83.6,159.33 83.81,159.12 83.81,159.06 84.26,158.61 85.3,158.61 85.3,158.6 85.3,158.58 85.68,158.21 85.7,158.21 86.55,157.36 86.55,157.34 86.92,156.97 86.94,156.97 87.02,156.88 87.32,156.88 87.42,156.78 88.29,155.92 88.51,155.92 88.75,155.68 88.75,152.08 90.12,150.7 v4(90.29,150.7) ; v4(89.09,143.99) 89.03,143.99 88.5,144.52 84.22,144.52 83.92,144.22 83.19,144.22 82.96,144 81.89,144 81.69,143.79 77.88,143.79 74.78,140.7 59.21,140.7 58.78,140.27 58.67,140.17 57.81,140.17 57.81,140.17 57.25,140.17 57.25,140.17 55.81,140.17 55.53,139.88 v5(55.53,139.88)
SUS_CLK_WLAN: length 142.3
  L5 w0.076: v4(83.76,149.52) 83.82,149.52 83.83,149.54 84.46,149.54 85.05,148.95 85.05,143.23 85.25,143.03 85.25,140.75 86.98,139.02 86.98,137.79 88.02,136.76 88.11,136.76 v4(90,134.87)
  L7 w0.06: v8(80.03,157.83) 80.03,157.55 82.05,155.53 82.05,155.12 82.26,154.91 82.26,153.56 82.49,153.32 82.49,152.9 82.73,152.67 82.73,152.2 83.38,151.55 83.38,149.97 83.76,149.59 v4(83.76,149.52)
  L7 w0.061: v5(97.55,41.75) 97.55,42.39 96.91,43.03 96.91,45.82 97.37,46.29 97.47,46.39 97.47,53.27 95.36,55.39 95.36,58.62 95.78,59.04 95.78,65.66 95.41,66.02 95.41,69.07 95.42,69.08 95.62,69.28 96.24,69.9 96.56,69.9 98.86,72.2 98.86,72.28 98.95,72.37 98.95,72.88 98.95,73.02 98.95,85.02 98.81,85.17 98.81,88.33 101.08,90.6 101.08,92.1 101.21,92.23 101.21,92.55 v5(102.37,93.72) 102.51,93.85 102.51,120.87 105.86,124.22 105.86,131.32 104.86,132.31 104.86,132.95 102.56,135.25 99.57,135.25 99.37,135.45 99.37,135.46 99.19,135.63 98.2,135.63 97.3,134.74 96.67,134.74 96.11,135.3 91.78,135.3 91.52,135.04 90.18,135.04 v4(90,134.87)
SUS_PWRDOWNACK: length 80.5
  L5 w0.076: v4(88.48,143.84) 89.71,145.07 89.71,148.95 89.81,149.05 89.81,149.29 89.14,149.96 v4(89.14,150.31) ; v4(87.46,170.33) 89.04,168.75 89.04,168.55 v4(89.06,168.55) ; v4(86.32,158.51) 86.27,158.47 86.27,157.2 87.26,156.2 v4(87.26,155.65) ; v8(75.5,158.4) 75.45,158.35 75.45,157.89 75.68,157.67 75.68,154.37 77.18,152.87 77.18,150.82 77.57,150.44 77.57,150.11 77.35,149.9 77.35,149.37 78.07,148.65 78.07,146.04 80.07,144.04 82.89,144.04 v4(83.25,143.68) ; v11(93.41,181.53) 93.14,181.53 93.02,181.64 90.38,181.64 88.07,179.33 88.07,179.2 87.73,178.86 87.73,178.75 87.73,178.14 v4(87.34,177.74)
  L6SGND w0.06: v11(93.41,181.53) 95.5,179.43 96.39,179.43 98.23,177.6 98.23,176.93 v8(98.23,176.93)
  L7 w0.061: v4(87.34,177.74) 87.34,177.69 87.23,177.59 87.23,170.94 87.46,170.71 v4(87.46,170.33) ; v4(86.32,158.51) 86.3,158.5 86.3,161.66 88.5,163.86 88.5,167.91 89.06,168.47 v4(89.06,168.55) ; v4(88.48,143.84) 88.48,144.09 88.22,144.35 84.29,144.35 83.99,144.05 83.82,144.05 v5(83.65,143.89) 83.45,143.68 v4(83.25,143.68) ; v4(89.14,150.31) 88.63,150.31 86.01,152.92 86,152.92 85.83,153.09 85.83,153.33 86.32,153.82 86.32,154.3 87.26,155.24 v4(87.26,155.65)
SVID_ALERT#: length 38.6
  L5 w0.06: v3(92.04,175.05) 90.52,176.57 88.13,176.57 87.34,175.78 85.21,175.78 v4(84.97,176.02)
  L6SGND w0.06: v8(97.83,174.13) 98.03,174.33 98.03,174.61 97.91,174.73 97.69,174.73 97.57,174.85 97.15,174.85 96.71,174.41 92.68,174.41 v3(92.04,175.05)
  L7 w0.06: v8(72.92,171.17) 72.95,171.2 72.95,171.7 73.16,171.91 73.16,173.98 73.92,174.74 73.92,175.46
  L7 w0.061: v4(84.97,176.02) 84.77,176.22 84.77,177.12 83.85,178.05 v5(83.07,178.05) 80.55,178.05 80.4,178.2 80.22,178.38 77.09,178.38 75.26,176.55 74.26,176.55 73.99,176.28 73.99,175.89 73.92,175.83 73.92,175.46
  BOTTOM w0.114: PR4907.2 82.71,175.18 83.17,175.18 v1(83.2,175.2) 83.2,175.23 83.6,175.64 83.6,177.7 83.25,178.05 v5(83.07,178.05)
SVID_CLK: length 36.7
  L5 w0.076: v4(85.13,176.4) 85.56,175.97 87.27,175.97 88.05,176.75 90.83,176.75 92.32,175.26 v3(92.36,175.26)
  L6SGND w0.06: v3(92.36,175.26) 92.36,175.14 92.86,174.64 96.77,174.64 97.1,174.97 97.79,174.97 v8(97.83,174.93)
  L7 w0.06: 72.87,172.04 72.83,172 72.83,171.37 72.72,171.25 72.72,171.09 72.87,170.93 72.87,170.76 72.75,170.65 72.75,170.48 72.87,170.37 73.15,170.37 v8(73.24,170.28)
  L7 w0.061: v4(85.13,176.4) 84.97,176.56 84.97,177.18 83.66,178.48 v5(82.61,178.48) 80.37,178.48 80.29,178.55 77.02,178.55 75.19,176.72 74.18,176.72 73.81,176.35 73.81,176.35 73.81,175.96 73.75,175.9 73.75,175.39 73.75,174.82 72.99,174.06 72.99,172.17 72.87,172.04
  BOTTOM w0.114: v5(82.61,178.48) 82.23,178.48 v1(82.03,178.28) 82.28,178.02 PR4909.2
SVID_DATA: length 35.1
  L5 w0.076: v4(84.64,175.71) 84.75,175.6 87.42,175.6 88.2,176.39 90.19,176.39 v3(91.68,174.9)
  L6SGND w0.06: v8(97.83,174.53) 97.72,174.53 97.52,174.73 97.2,174.73 96.7,174.23 92.34,174.23 v3(91.68,174.9)
  L7 w0.06: v8(73.24,170.85) 73.24,171.15 73.47,171.39
  L7 w0.061: v4(84.64,175.71) 84.6,175.76 84.6,177.05 83.98,177.67 v5(83.04,177.67) 80.68,177.67 80.32,178.03 80.15,178.2 77.28,178.2 74.28,175.2 74.28,174.6 73.63,173.95 73.63,171.55 73.47,171.39
  BOTTOM w0.114: PR4908.2 83.09,176.37 v1(83.22,176.5) 83.22,177.49 v5(83.04,177.67)
SX_OFF: length 4.1
  TOP w0.114: v10(100.19,179.42) v1(101.13,179.42)
  L3SGND w0.127: v10(100.19,179.42) v11(100.54,179.42)
  L6SGND w0.06: v11(100.54,179.42) 100.23,179.1 100.23,178.99 100.23,178.99 100.23,178.52 100.04,178.34 100.04,178.05 100.23,177.87 v8(100.23,176.93)
SYS_PWR_ON: length 21.1
  TOP w0.114: v10(103.11,129.87) 102.83,130.15 97.92,130.15 96.96,131.1 93.39,131.1 ; 93.39,131.1 93.39,131.6 D5411.1 ; 93.39,131.1 92.91,130.63 U1706.2
  L3SGND w0.127: v10(103.11,129.87) 103.11,130.41 v11(103.2,130.5)
  L6SGND w0.127: v5(103.67,130.5) v11(103.2,130.5)
  BOTTOM w0.114: U4501.5 U4501.2 103.62,130.45 v5(103.67,130.5) 102.87,131.3 101.57,131.3 v1(101.56,131.29) R5409.2
SYS_PWR_ON#: length 4.7
  BOTTOM w0.114: Q4501.4 101.55,127.23 R4501.2 101.96,127.65 U4501.6 102.97,127.19 103.24,126.92 104.51,126.92 v1(104.71,126.72)
T0: length 4.7
  BOTTOM w0.114: PMIC1.A14 102.53,178.03 102.53,178.25 102.4,178.38 102.4,178.71 103.9,180.21 103.9,180.89 TP5103.1
T1: length 3
  BOTTOM w0.114: PMIC1.A15 102.2,178.16 102.2,178.79 103.52,180.11 TP5105.1
T2: length 12.3
  L5 w0.076: v5(106.41,186.51) 106.16,186.51 105.99,186.34 105.44,186.34 105.42,186.36 104.58,186.36 104.18,185.95 104.18,183.37 102.74,181.93 102.74,179.48 101.83,178.57 v8(101.83,177.73)
  BOTTOM w0.114: v5(106.41,186.51) 106.62,186.71 TP5106.1
T3: length 4.9
  BOTTOM w0.114: TP5107.1 103.14,182.01 103.14,179.98 101.99,178.84 101.99,178.3 PMIC1.B15
T4: length 13.7
  L5 w0.076: v8(96.63,177.73) 95.61,177.73 95.24,178.11 95.24,181.05 93.74,182.55 v4(93.74,184.09)
  L7 w0.061: v5(90.38,185.01) 91.12,184.27 93.56,184.27 v4(93.74,184.09)
  BOTTOM w0.114: v5(90.38,185.01) 90.38,185.14 90.16,185.36 90.16,186.28 TP5108.1
T5: length 12.4
  L5 w0.076: v8(96.63,178.13) 96.63,180.79 95.08,182.33 95.08,183.18 v4(94.12,184.14)
  L7 w0.061: v4(94.12,184.14) 93.81,184.45 91.31,184.45 90.79,184.97 90.79,185.19 v5(90.61,185.36)
  BOTTOM w0.114: TP5109.1 90.61,185.97 v5(90.61,185.36)
T6: length 13.1
  L5 w0.076: v4(93.33,183.94) 93.36,183.92 93.36,182.66 95.01,181.01 95.01,178.14 95.63,177.52 96.74,177.52 96.95,177.73 v8(97.03,177.73)
  L7 w0.061: v4(93.33,183.94) 93.18,184.09 90.79,184.09 v5(90.03,184.86)
  BOTTOM w0.114: v5(90.03,184.86) 90.03,185.11 TP5110.1
T7: length 13.3
  L5 w0.076: v4(94.52,184.22) 94.52,184.14 95.31,183.36 95.31,182.37 97.03,180.65 v8(97.03,178.13)
  L7 w0.061: v5(90.94,185.59) 91.02,185.52 91.02,184.99 91.38,184.63 94.04,184.63 94.45,184.22 v4(94.52,184.22)
  BOTTOM w0.114: v5(90.94,185.59) 91.78,186.43 TP5111.1
T8: length 6.7
  L7 w0.061: v8(101.83,172.93) 102.03,173.13 102.31,173.13 102.45,172.99 102.45,172.6 103.19,171.86 104.94,170.11 104.94,170 v5(105.7,169.24)
  BOTTOM w0.114: TP5112.1 105.68,169.21 v5(105.7,169.24)
T9: length 9.2
  L5 w0.076: v5(90.69,167.74) 92.29,169.34 92.52,169.34 96.11,172.93 v8(97.03,172.93)
  BOTTOM w0.114: TP5113.1 90.69,167.71 v5(90.69,167.74)
TOUCH_INT#: length 95.9
  L5 w0.06: v8(75.78,158.68) 75.78,158.4 75.58,158.2 75.58,158.03 75.77,157.85
  L5 w0.076: 75.77,157.85 75.77,157.77 75.82,157.72 75.82,154.43 77.37,152.87 77.37,150.9 77.76,150.51 77.76,150.04 77.54,149.82 77.54,149.58 77.71,149.41 77.73,149.41 v5(77.84,149.3) 78.26,148.87 78.26,146.11 80.15,144.23 83.16,144.23 84.75,142.64 v4(84.75,140.86)
  L7 w0.061: v5(89.01,73.6) 89.01,74.51 88.87,74.65 88.87,76.05 87.98,76.94 87.98,77.57 87.12,78.43 87.12,78.57 87.12,78.57 87.12,79.46 87.12,79.46 87.12,80.38 87.12,80.38 87.12,80.82 87.12,80.82 87.12,81.52 87.12,81.53 87.12,82.11 87.12,82.11 87.12,93.81 86.61,94.32 86.61,98.25 87.51,99.14 87.51,108.18 88.07,108.74 88.07,108.89 88.07,108.9 88.07,109.15 88.07,109.44 88.07,120.36 88.07,120.36 85.24,123.2 85.24,123.67 85.24,129.81 85.24,130.63 85.47,130.86 85.47,130.86 85.78,131.17 85.93,131.33 85.93,135.6 85.91,135.62 85.91,137.05 85.26,137.7 84.96,138.01 84.96,140.09 84.75,140.3 v4(84.75,140.86)
  BOTTOM w0.114: v5(89.01,73.6) 88.94,73.6 D1705.A ; R713.1 77.84,149.14 v5(77.84,149.3)
TOUCH_INT#_3P3: length 6
  BOTTOM w0.114: D1705.K 89.52,74.11 89.7,74.29 90.21,74.29 v1(90.33,74.42) 91.05,75.13 92.57,75.13 93.06,74.64 94.05,74.64 94.27,74.42 TP1.5
TOUCH_RESET#: length 198.3
  L5 w0.076: v4(109.92,139.11) 109.99,139.03 110.61,139.03 110.96,139.38 110.96,139.92 110.74,140.13 110.74,141.18 110.91,141.35 110.91,151.12 109,153.02 v5(109,153.64) 109,170.21 109.17,170.38 109.17,177.17 108.38,177.96 108.38,186.9 106.73,188.55 106.48,188.55 105.93,189.11 105.85,189.11 105.37,189.59 96.04,189.59 92.34,185.88 91.53,185.88 86.03,180.38 86.03,179.78 85.22,178.97 84.61,178.97 v4(84.34,179.24) ; v4(85.12,133.74) 85.1,133.74 85.1,133.55 86.8,131.86 87.89,131.86 88.21,132.18 v4(88.23,132.18)
  L7 w0.06: 72.36,172.22 72.28,172.15 72.28,171.23 v8(72.39,171.13)
  L7 w0.061: v4(109.92,139.11) 109.71,138.9 107.92,138.9 107.68,139.14 88.02,139.14 87.39,138.5 87.39,138.27 87.38,138.26 87.38,138.03 87.39,138.02 87.39,136.29 87.79,135.88 87.79,135.37 87.82,135.34 87.82,135 87.79,134.97 87.79,132.61 v4(88.23,132.18) ; v5(87.16,76.58) 86.7,76.58 86.38,76.9 86.38,93.57 85.91,94.03 85.91,98.65 86.68,99.42 86.68,109.19 86.67,109.2 86.67,116.27 84.75,118.19 84.75,122.42 84.54,122.63 84.54,130.92 84.97,131.36 84.97,133.59 v4(85.12,133.74) ; 72.36,172.22 72.57,172.44 72.57,174.37 72.55,174.39 72.2,174.74 72.2,175.81 72.03,175.99 72.03,176.19 72,176.22 72,176.91 v5(71.66,177.24) 71.66,177.39 71.36,177.7 71.36,178.12 71.44,178.2 71.44,179.21 71.93,179.7 72.92,179.7 73.45,179.71 73.95,179.2 75.43,179.2 75.43,179.2 76.67,179.2 77.13,179.66 79.32,179.66 79.35,179.7 83.7,179.7 84.19,179.22 84.31,179.22 v4(84.34,179.24)
  BOTTOM w0.114: v5(87.16,76.58) R750.1 87.51,76.4 88.76,76.4 89.01,76.65 U4302.2
TOUCH_RESET#_3P3: length 7.2
  BOTTOM w0.114: TP1.4 94.77,74.45 93.84,75.38 R4311.2 93.18,75.48 93.06,75.37 90.68,75.37 89.66,76.38 U4302.3
TOUCH_RESET#_R: length 2.6
  BOTTOM w0.114: U4302.6 88.16,75.19 R4310.1 87.9,74.62 88.89,74.62 89.01,74.75 U4302.5
TP_1P05_OBS: length 8.3
  L5 w0.06: v8(71.46,159.49) 71.46,159.19 71.34,159.08 71.34,158.31 71.74,157.92 71.74,156.94 71.61,156.81 71.61,155.52 72.08,155.06 72.08,152.9 71.7,152.52 v5(71.46,152.52)
  BOTTOM w0.114: v5(71.46,152.52) 71.59,152.39 TP801.1
TP_FUSE_PWRMON: length 13.1
  L5 w0.076: v5(89.19,152.73) 87.54,154.38 86.99,154.38 82.53,158.83 81.92,158.83 81.69,159.06 81.69,159.15 81.35,159.48 79.51,159.48 v8(79.46,159.53)
  BOTTOM w0.114: TP701.1 89.5,153.03 v5(89.19,152.73)
TP_ID1: length 31.8
  L3SGND w0.127: v10(88.17,47.47) 88.17,47.49 v11(88.51,47.82)
  L6SGND w0.127: v4(88.45,48.18) 88.45,47.87 v11(88.51,47.82)
  L7 w0.061: v5(89.98,72.41) 89.9,72.33 89.9,72.28 89.72,72.1 89.72,71.86 89.92,71.66 89.92,71.29 89.92,71.28 89.92,68.44 90.25,68.11 90.25,65.75 v5(89.32,64.82) 89.32,64.61 89.92,64.01 89.92,61.48 91.04,60.36 91.04,54.74 89.78,53.47 89.78,53.17 89.54,52.94 89.54,51.28 89.22,50.95 88.45,50.19 v4(88.45,48.18)
  BOTTOM w0.114: v5(89.98,72.41) 90,72.44 92.06,72.44 93.27,73.64 TP1.7
TP_ID2: length 32.8
  L3SGND w0.127: v10(87.67,47.47) 87.67,47.36 v11(88.03,47)
  L6SGND w0.127: v4(88.48,47.11) 88.14,47.11 v11(88.03,47)
  L7 w0.061: v5(90,71.98) 90.1,71.89 90.1,71.36 90.1,71.36 90.1,68.51 90.43,68.18 90.43,64.15 v5(90.28,64) 90.43,63.86 90.43,61.22 91.22,60.44 91.22,54.67 89.95,53.4 89.95,53.1 89.72,52.87 89.72,51.21 89.29,50.78 88.74,50.23 88.74,47.37 v4(88.48,47.11)
  BOTTOM w0.114: TP1.6 93.77,73.28 92.7,72.21 90.23,72.21 v5(90,71.98)
TP_VCCCORE2_OBS: length 2.1
  TOP w0.114: v10(72.02,162.96) 71.69,162.96 TP802.1
  L3SGND w0.102: v10(72.02,162.96) 72.02,163.11 v11(72.2,163.29)
  L6SGND w0.102: v5(72.56,163.3) 72.2,163.3 v11(72.2,163.29)
TP_VCCDDR_1P24_1P35_OBS: length 11.7
  L5 w0.06: v5(70.73,179.65) 70.73,176.14 71.59,175.27 71.59,169.1 v8(71.82,168.87)
  BOTTOM w0.114: v5(70.73,179.65) 70.73,179.5 TP805.1
TP_VCCSRAMGEN_1P15_OBS: length 3.6
  TOP w0.114: TP804.1 74.38,163.52 73.81,162.95 v10(73.7,162.95)
  L3SGND w0.102: v11(73.29,162.66) 73.43,162.8 73.54,162.8 v10(73.7,162.95)
  L6SGND w0.102: v5(73.11,162.34) 73.11,162.47 v11(73.29,162.66)
TP_VCCSRAMSOC_1P15_OBS: length 10.8
  L7 w0.06: 75.11,167.38 75.38,167.65 75.38,167.67 75.66,167.94 75.66,168.15 75.77,168.26 76.03,168.26 76.55,168.78 76.71,168.78 76.83,168.67 77,168.67 77.11,168.78 77.28,168.78 77.4,168.67 77.56,168.67 77.96,169.07 77.96,169.23 77.85,169.35 77.85,169.52 78.25,169.92 78.25,170.28 78.17,170.36 78.17,170.75 78.29,170.87 78.29,171.12 78.41,171.24 78.41,171.46 80.2,173.25 v5(80.2,173.93)
  L7 w0.061: 75.11,167.38 74.6,167.38 74.33,167.11 v8(74.21,167.11)
TPM_GPIO0: length 14.3
  BOTTOM w0.114: U5709.3 40.79,146.7 R5726.2 v1(37.73,146.76) 35.55,146.76 35.11,147.19 35.11,153.82 35.29,153.99 U5702.29
TPM_GPIO0#: length 4.7
  BOTTOM w0.114: 41.9,145.11 41.97,145.18 U5709.5 ; 41.9,145.11 41.9,145.99 42.3,146.4 R5725.1 v1(43.09,146.76) ; 41.9,145.11 41.9,144.72 42.09,144.53 U5709.6
TPM_SCLK: length 2.8
  BOTTOM w0.114: U5702.19 39.22,150.66 39,150.44 38.62,150.44 v1(38.47,150.29) 38.47,149.93 38.8,149.6 R5712.2
TPS65982_DEBUG3: length 286
  TOP w0.114: R3130.1 104.43,58.54 104.35,58.46 99.41,58.46 v2(98.03,59.84)
  L2 w0.061: v9(107.32,18.65) 107.32,17.87 106.41,16.96 v12(105.85,16.96) 105.77,16.96 103.61,14.8 98.84,14.8 98.28,14.24 96.56,14.24 95.74,15.06 95.24,15.06 v2(94.86,15.44) ; v10(75.68,138.12) 75.77,138.02 99.24,138.02 102.63,134.63 102.63,127.99 100.16,125.52 100.16,103.5 100.32,103.34 100.32,102.49 99.78,101.95 99.78,98.04 97.17,95.42 97.17,94.68 95.84,93.36 95.84,93.12 96.27,92.69 96.27,89.73 95.84,89.3 95.84,88.34 96.79,87.39 96.79,85.15 95.57,83.93 95.57,80.62 95.6,80.59 95.6,76.51 95.31,76.21 95.31,75.98 95.52,75.76 95.74,75.76 95.97,75.53 95.97,69.06 95.74,68.83 95.74,67.38 97.88,65.25 97.88,60.4 98.03,60.24 v2(98.03,59.84)
  L3SGND w0.127: v11(75.3,138.12) v10(75.68,138.12)
  L5 w0.076: v2(98.03,59.84) 100.32,57.55 100.32,47.18 103.1,44.39 103.11,44.38 103.11,42.95 103.77,42.29 103.77,41.85 103.78,41.83 103.78,41.57 103.55,41.34 103.55,38.91 95.88,31.24 95.88,20.58 95.07,19.77 95.07,19.23 95.72,18.58 95.72,16.86 94.86,16 v2(94.86,15.44)
  L6SGND w0.127: v4(75.3,138.98) v11(75.3,138.12)
  L7 w0.061: v4(75.3,138.98) 74.66,138.98 74.23,139.42 68.02,139.42 67.46,138.86 47.75,138.86 46.66,139.95 43.49,139.95 35.5,147.95 35.5,157.34 44.54,166.39 46.51,166.39 47.3,167.18 47.3,167.64 47.4,167.73 47.4,168.91 47.4,168.93 47.23,169.1 47.23,178.44 47.4,178.61 49.94,181.16 61.67,181.16 61.67,181.15 62.39,181.15 62.69,181.15 62.98,181.16 62.98,181.16 66.38,181.16 67.07,180.46 67.16,180.46 v5(67.39,180.23)
TPS65982_DEBUG3_R: length 1.8
  TOP w0.114: v1(105.27,59.18) 104.84,59.18 104.68,59.33 R3130.2 104.44,59.33 U3101.8
TPS65982_DEBUG4: length 95.9
  TOP w0.114: v9(98.28,19.27) 98.28,19.83 v1(98.16,19.96)
  L2 w0.061: v10(109.69,22.52) 109.95,22.52 109.95,22.52 110.02,22.52 110.15,22.39 110.25,22.3 110.25,21.52 110.24,21.51 110.24,21.3 110.25,21.29 110.25,21.19 110.32,21.12 110.32,20.02 109.76,19.45 107.62,19.45 v9(107.32,19.15) 103.36,15.18 99.33,15.18 98.28,16.23 v9(98.28,19.27) ; v10(109.33,65.1) 107.1,65.1 v9(106.56,64.56)
  L3SGND w0.127: v11(110.03,22.69) 109.85,22.69 v10(109.69,22.52) ; v11(109.69,65.1) v10(109.33,65.1)
  L5 w0.076: v11(110.03,22.69) 110.03,22.74 110.02,22.76 110.02,22.95 109.09,23.87 109.09,24.05 108.83,24.32 108.83,28.93 108.81,28.94 108.81,32.56 108.19,33.18 108.19,34.28 108.81,34.91 108.81,38.3 109.33,38.82 109.33,45.13 110.13,45.93 110.13,48.61 110.32,48.79 110.32,51.13 109.91,51.54 109.91,53.46 109.91,54.48 108.87,55.52 108.87,58.68 109.63,59.45 109.63,64.39 109.69,64.45 v11(109.69,65.1) 109.69,65.1 109.69,69.82 109.59,69.92 108.6,69.92 101.71,76.8 101.71,76.88 v4(101.74,76.91)
  L7 w0.061: v5(100.93,86.3) 100.93,85.94 100.95,85.92 100.95,80.41 101.71,79.65 101.71,76.93 v4(101.74,76.91)
  BOTTOM w0.114: R3129.1 v5(100.93,86.3)
TPS65982_DEBUG4_R: length 28.8
  TOP w0.114: U3101.17 104.44,64.39 v10(104.71,64.66)
  L3SGND w0.127: v11(104.89,65.12) 104.71,64.94 v10(104.71,64.66)
  L6SGND w0.127: v11(104.89,65.12) v4(105.35,65.12)
  L7 w0.061: v5(101.48,86.3) 101.15,85.97 101.15,80.59 102.17,79.58 102.17,76.24 106.33,72.08 106.33,66.41 105.35,65.43 v4(105.35,65.12)
  BOTTOM w0.114: v1(101.54,87.6) 101.48,87.55 R3129.2 v5(101.48,86.3) 101.64,86.3 102.34,85.61 U5407.5
TPS65982_GPIO0: length 72.4
  TOP w0.114: R3131.1 101.61,58.77 100.87,59.51 100.11,59.51 v1(100.09,59.48) 100.09,59.1 100.24,58.95 v2(100.49,58.95)
  L3SGND w0.127: v10(106.84,23.19) 106.84,23.13 107.17,22.8 v11(107.17,22.55)
  L5 w0.076: v2(100.49,58.95) 100.49,57.64 100.51,57.63 100.51,50.97 102.69,48.78 102.69,45.19 103.3,44.58 103.3,43.03 103.96,42.37 103.96,41.93 103.97,41.91 103.97,41.49 103.75,41.26 103.75,38.83 96.07,31.16 96.07,16.27 96.05,16.25 96.05,14.24 v4(96.63,13.66)
  L6SGND w0.127: v11(107.17,22.55) 107.17,21.93 v4(107.17,21.93)
  L7 w0.061: v4(96.63,13.66) 96.81,13.49 99.48,13.49 99.83,13.84 99.83,15.54 101.36,17.06 106.41,17.06 107.36,18.01 107.36,19.2 107.55,19.4 107.55,20.78 107.18,21.15 107.18,21.92 v4(107.17,21.93)
TPS65982_GPIO0_R: length 0.9
  TOP w0.114: U3101.3 101.94,59.37 R3131.2
TPS65982_GPIO1: length 79.6
  TOP w0.114: v9(107.41,22.02) 107.17,22.26 107.17,22.32 106.98,22.52 106.96,22.52 U2901.C2 ; v2(96.18,68.68) v1(94.45,68.68)
  L2 w0.061: v9(107.41,22.02) 107.34,22.09 106.52,22.09 106.04,22.57 105.72,22.57 105.35,22.93 104.1,22.93 103.6,22.44 100.92,22.44 100.8,22.32 100.32,22.32 100.2,22.44 99.82,22.44 v2(98.82,23.44) ; v2(96.18,68.68) 96.18,80.51 95.92,80.76 95.92,81.51 95.97,81.55 95.97,83.38 v9(96.63,84.04) 98.44,85.85 v9(98.44,85.92)
  L7 w0.061: v2(98.82,23.44) 98.79,23.44 97.57,24.66 97.57,26.13 98.77,27.33 98.77,30.4 99.17,30.81 99.17,40.41 99.55,40.78 99.55,41.06 100.01,41.52 100.01,41.93 98.16,43.78 98.16,53.33 95.88,55.61 95.88,57.18 96.3,57.6 96.3,63.88 96.4,63.98 96.4,65.88 96,66.28 96,68.5 v2(96.18,68.68)
TPS65982_GPIO2: length 23.8
  TOP w0.114: R1715.1 93.03,24.68 v1(93.23,24.48) 93.23,24.46 92.61,23.83 v9(92.61,23.46)
  L2 w0.061: v9(110.83,22.15) 110.83,22.18 110.5,22.5 110.5,22.85 110.11,23.25 110.11,23.27 109.94,23.44 109.71,23.44 109.28,23.02 109.28,22.96 109.02,22.69 106.69,22.69 106.64,22.74 105.79,22.74 105.42,23.11 104.02,23.11 103.56,22.65 100.88,22.65 100.73,22.49 100.39,22.49 99.54,23.34 99.5,23.34 98.99,23.85 98.65,23.85 96.82,22.02 94.04,22.02 v9(92.61,23.46)
TPS65982_GPIO3: length 1.8
  TOP w0.114: U2901.G11 112.37,20.65 TP2913.1
TPS65982_GPIO4_HPD: length 45.3
  TOP w0.114: v9(106.44,45.46) 105.93,45.46 R2918.2 105.9,46.65 v1(105.9,47.04)
  L2 w0.061: v9(106.44,45.46) 105.95,44.98 105.95,41.15 103.82,39.01 103.8,39.01 103.61,38.82 103.61,38.11 104.12,37.61 104.12,35.29 103.42,34.59 103.42,33 99.42,29 99.42,28.18 98.38,27.14 98.38,26.14 100.48,24.04 101.25,24.04 101.88,24.68 102.34,24.68 102.96,25.3 102.96,25.83 104.1,26.96 105.46,26.96 105.52,27.02 105.85,27.02 106.19,26.68 106.19,25.2 105.81,24.82 105.81,23.76 106.66,22.92 106.71,22.92 106.76,22.87 108.94,22.87 109.11,23.04 109.11,23.09 109.63,23.61 110.02,23.61 110.28,23.34 110.28,23.32 110.66,22.94 110.66,22.79 v9(110.83,22.63)
TPS65982_GPIO6: length 3.9
  TOP w0.114: TP2912.1 112.74,20.65 112.36,21.03 v9(111.75,21.03)
  L2 w0.061: v9(110.83,20.65) 110.83,20.69 111.16,21.03 v9(111.75,21.03)
TPS65982_GPIO7: length 6.9
  TOP w0.114: v9(113.22,21.86) 114.11,21.86 TP2916.1 ; U2901.D7 109.46,22.29 109.46,22.3 109.67,22.52 109.98,22.52 110.27,22.22 110.27,21.64 v9(110.5,21.41)
  L2 w0.061: v9(113.22,21.86) 112.38,22.71 111.8,22.71 v9(110.5,21.41)
TPS65982_GPIO8: length 3.3
  L3SGND w0.127: v11(108.29,19.68) 108.36,19.68 v10(108.83,20.15)
  L5 w0.076: v5(106.74,18.21) 107.05,18.52 107.05,19.18 107.55,19.68 v11(108.29,19.68)
TPS65982_I2C_ADDR: length 2.2
  TOP w0.114: R2905.1 105.02,20.65 105.52,21.15 U2901.F1
TPS65982_I2C_IRQ1#: length 2.5
  TOP w0.114: R2910.1 104.63,23.37 104.63,23.37 105.4,22.6 106.27,22.6 U2901.C1
TPS65982_I2C_IRQ2#: length 19.3
  TOP w0.114: R2921.1 95.85,22.8 v9(96.2,23.16) ; v9(108.27,24.61) 108.27,26.21 107.7,26.77 105.81,26.77 105.76,26.72 v9(105.73,26.72)
  L2 w0.061: v9(108.27,24.61) 108.83,24.05 v9(108.83,23.15) ; v9(96.2,23.16) 96.89,23.16 97.7,23.97 v12(97.7,24.18) 98.41,24.89 99.2,24.89 100.22,23.87 101.71,23.87 102.35,24.5 102.62,24.5 103.08,24.96 103.08,25.09 103.24,25.25 103.24,25.85 103.62,26.23 v9(104.05,26.23) 104.91,26.23 105.37,26.69 105.69,26.69 v9(105.73,26.72)
TPS65982_I2C_IRQ2#_R: length 21.3
  TOP w0.114: v9(94.83,23.21) 94.98,23.06 R2921.2 ; U1704.B5 88.44,32.45 88.4,32.41 88.4,32.3 88.08,31.98 88.08,31.76 87.74,31.42 87.48,31.42 86.85,30.79 86.85,30.22 85.92,29.28 85.13,29.28 85.03,29.19 85.03,25.64 85.14,25.53 85.43,25.53 86.17,24.78 87.26,24.78 v1(87.29,24.75) 87.29,24.1 v9(87.44,23.95)
  L2 w0.061: v9(94.83,23.21) 94.58,23.21 93.61,24.18 92.16,24.18 91.91,23.92 88.99,23.92 88.83,24.08 87.75,24.08 87.69,24.02 87.51,24.02 v9(87.44,23.95)
TPS65982_I2C_SCL1: length 5
  TOP w0.114: v9(107.43,21.42) 107.4,21.45 107.4,21.59 106.98,22.02 106.96,22.02 U2901.D2 ; R2909.1 104.61,22.93 104.89,22.65 v9(104.89,22.17)
  L2 w0.061: v9(104.89,22.17) 105.07,21.99 106.13,21.99 106.38,21.74 106.45,21.74 106.55,21.64 107.04,21.64 107.26,21.42 v9(107.43,21.42)
TPS65982_I2C_SCL2: length 2.7
  L2 w0.061: v9(108.32,23.15) 108.16,23.31 108.16,23.92 v9(106.87,25.22)
TPS65982_I2C_SDA1: length 2.3
  TOP w0.114: R2908.1 104.45,22.17 104.76,21.86 105.02,21.86 105.31,22.15 U2901.D1
TPS65982_I2C_SDA2: length 1.9
  TOP w0.114: U2901.A5 108.32,24.02 107.63,24.71 107.63,25.22
TPS65982_LDO_1V8A: length 2.1
  TOP w0.254: C2917.1 105.12,18.36 105.91,19.15 U2901.K1
TPS65982_LDO_1V8D: length 8.2
  TOP w0.254: v10(106.83,23.65) 106.76,23.72 106.76,23.83 106.5,24.09 106.12,24.09 106.12,24.09 105.89,24.31 105.89,24.31 105.68,24.53 C2916.1
  L3SGND w0.254: v10(110.83,21.15) v11(110.29,21.15) ; v10(106.83,23.65) v11(106.83,24.17)
  L5 w0.254: v11(106.83,24.17) 106.83,24.04 107.39,23.48 107.55,23.48 108.61,22.42 108.61,22 109.46,21.15 v11(110.29,21.15)
TPS65982_LDO_3V3: length 40.5
  TOP w0.254: U2901.D5 108.29,22.19 v9(107.86,22.19) 107.79,22.12 107.79,21.86 107.73,21.81 107.73,21.75 U2901.E4 ; U2901.G1 105.66,20.65 v10(105.64,20.67) ; U2903.8 109.1,28.78 R2912.2 109.66,28.87 v1(109.66,29.33) 109.26,29.74 109.26,36.72 108.98,37 108.01,37 R2915.2 R2914.2 107.25,36.95 106.69,36.39 R2913.2 107.07,35.38 v2(107.33,35.12)
  L2 w0.254: v10(106.62,22.4) 106.64,22.37 107.22,22.37 107.25,22.4 107.57,22.4 107.58,22.39 107.61,22.41 107.64,22.41 v9(107.86,22.19)
  L3SGND w0.254: v10(106.62,22.4) 106.62,22.47 106.49,22.6 106.21,22.6 v11(106.16,22.65) ; v10(105.64,20.67) v11(105.1,20.67)
  L5 w0.254: v2(107.33,35.12) 107.3,35.12 106.29,34.11 106.29,31.59 107.15,30.73 107.15,26.65 106.15,25.65 106.15,22.66 v11(106.16,22.65) 106.16,21.73 v11(105.1,20.67) 104.89,20.46 104.89,19.32 105.14,19.07 v5(105.5,19.07)
  BOTTOM w0.254: C2915.1 104.71,18.28 v5(105.5,19.07)
TPS65982_LDO_BMC: length 1.8
  TOP w0.114: U2901.E1 105.19,21.65 104.94,21.41 C2918.1
TPS65982_LSX_P2P: length 3.1
  TOP w0.114: TP2905.1 107.83,16.5 U2901.L4
TPS65982_LSX_P2R: length 2.2
  L2 w0.061: v9(107.17,17.22) 107.83,17.87 v9(107.83,19.15)
TPS65982_MRESET: length 2.1
  TOP w0.114: TP2918.1 112.12,21.65 U2901.E11
TPS65982_RESET#: length 2
  TOP w0.114: U2901.F11 111.34,21.15 111.55,21.36 113.24,21.36 TP2919.1
TPS65982_SPI_CLK: length 7.4
  TOP w0.114: U2901.A3 107.32,23.86 107.24,23.95 107.24,24.05 106.39,24.9 106.39,25.31 106.24,25.46 106.24,25.49 106,25.73 105.34,25.73 105.12,25.95 105.12,26.49 v1(105.29,26.66) 104.96,26.66 104.64,26.98 104.64,27.77 105.66,28.78 U2903.6
TPS65982_SPI_HOLD: length 3.5
  TOP w0.114: U2903.7 107.07,28.78 107.86,27.99 R2912.1 v1(110.15,27.99)
TPS65982_SPI_MISO: length 15.7
  TOP w0.114: R2914.1 107.45,36.29 108.06,35.68 v1(108.06,35.48) 108.06,35.1 107.88,34.92 107.81,34.92 107.08,34.18 106.94,34.18 U2903.2 ; U2901.A4 107.83,23.85 107.61,24.07 v9(107.56,24.07)
  L2 w0.061: v9(106.93,33.78) 106.93,33.12 104.4,30.58 104.4,29.11 105.25,28.27 105.35,28.27 105.35,28.27 106.59,27.03 106.59,25.34 106.58,25.33 106.58,25.1 106.59,25.1 106.59,25.04 v9(107.56,24.07)
TPS65982_SPI_MOSI: length 7.8
  TOP w0.114: v9(106.27,24.47) 106.27,24.69 106.01,24.96 106.01,25.37 105.87,25.5 105.24,25.5 104.66,26.08 104.66,26.45 104.3,26.82 104.3,27.43 v1(104.28,27.45) 104.3,27.47 104.3,28.18 104.39,28.28 U2903.5
  L2 w0.061: v9(106.27,24.47) 106.68,24.47 107.49,23.66 107.49,23.49 v9(107.83,23.15)
TPS65982_SPI_SSZ: length 19.3
  TOP w0.114: v9(107.56,33.7) 107.56,33.88 107.85,34.17 U2903.1 108.85,34.82 108.85,36.47 v1(108.83,36.49) 108.06,36.49 R2915.1
  L2 w0.061: v9(107.32,23.19) 107.32,23.37 107.3,23.4 107.3,23.58 106.7,24.19 106.16,24.19 105.99,24.35 105.99,24.59 106.41,25.01 106.41,25.41 106.41,25.41 106.41,26.95 105.28,28.09 105.18,28.09 104.22,29.04 104.22,29.18 104.23,29.19 104.23,30.66 106.65,33.08 106.65,33.89 106.82,34.06 107.17,34.06 107.56,33.68 v9(107.56,33.7)
TPS65982_SPI_WP: length 2.3
  TOP w0.114: v1(106.13,36.24) R2913.1 105.66,34.91 U2903.3
TPS65982_SS: length 3.6
  L3SGND w0.127: v11(109.97,19.88) 109.7,20.15 v10(109.33,20.15)
  L6SGND w0.127: v4(109.33,20.19) 109.66,20.19 v11(109.97,19.88)
  L7 w0.061: v5(107.71,19.07) 108.83,20.19 v4(109.33,20.19)
TPS65982_SWD_CLK: length 5.5
  TOP w0.114: v2(104.51,17.72) TP2908.1
  L3SGND w0.061: v10(107.83,20.65) v11(107.36,20.65)
  L5 w0.076: v2(104.51,17.72) 104.51,17.71 105.3,18.5 105.62,18.5 105.78,18.5 106.27,18.99 106.27,19.47 107.36,20.56 v11(107.36,20.65)
TPS65982_SWD_DATA: length 7.7
  TOP w0.114: TP2907.1 102.58,19.6 102.91,19.27 v2(103.01,19.27)
  L3SGND w0.061: v10(107.83,21.15) 107.81,21.15 v11(107.43,21.53)
  L5 w0.076: v2(103.01,19.27) 103.59,18.69 105.7,18.69 106.08,19.07 106.08,19.76 106.97,20.66 106.97,20.81 107.43,21.26 v11(107.43,21.53)
TPS65982_UART_RX: length 5.6
  L2 w0.061: v9(106.83,21.15) 106.73,21.25 104.99,21.25 103.95,20.21 102.53,20.21 v9(101.92,20.77)
TPS65982_UART_TX: length 6.6
  TOP w0.076: v9(107.25,20.82) 107.17,20.91 107.17,21.3 107.11,21.35 107.11,21.37 U2901.E2
  L2 w0.061: v9(107.25,20.82) 107.11,20.96 107.11,21.27 106.91,21.47 106.77,21.47 106.48,21.47 106.38,21.56 106.3,21.56 106.05,21.81 103.74,21.81 103.64,21.71 102.68,21.71 102.48,21.92 v9(102.35,21.92)
TPS65982_VOUT_3V3: length 3.1
  L2 w0.061: v9(104.46,19.25) 104.46,19.55 105.24,20.34 105.32,20.34 105.33,20.35 105.67,20.35 105.67,20.34 106.64,20.34 v9(106.83,20.15)
TXE_WP: length 51.9
  L3SGND w0.127: v10(94.04,33.43) 94.03,33.43 v11(93.66,33.8)
  L5 w0.076: v2(91.72,71.66) 91.26,71.2 91.26,68.49 91.46,68.29 91.46,67.72 91.46,67.41 91.46,56.55 91.46,55.6 92.2,54.86 92.2,54.86 93.89,53.17 93.89,52.69 93.89,52.54 93.89,50.11 94.35,49.66 94.35,42.73 94.88,42.2 94.88,42.17 94.88,42.16 94.88,42.01 94.88,39.28 93.36,37.76 93.36,36.16 93.66,35.86 v11(93.66,33.8)
  BOTTOM w0.114: U701.2 86.22,73.63 85.51,72.92 85.51,70.12 85.81,69.82 v1(86.7,69.82) 89.6,69.82 90.26,70.48 90.54,70.48 v2(91.72,71.66)
TXE_WP#: length 2.3
  BOTTOM w0.114: U701.6 86.87,76.18 R750.2 86.19,76.86 v1(85.33,76.86)
TYPE_C_IRQ#: length 35.2
  TOP w0.114: v1(86.02,30.04) v10(86.02,30.93) 86.02,31.03 87.18,32.2 87.87,32.2 88.08,32.41 88.08,32.78 88.29,33 88.8,33 U1704.C6 ; v9(103.36,24.98) 103.19,25.15 R2911.2 ; v9(102.91,23.95) 102.93,23.92 102.93,23.87 103.11,23.69 R2910.2
  L2 w0.061: v9(103.36,24.98) 103.36,24.96 103.24,24.84 103.24,24.28 v9(102.91,23.95) 102.8,23.84 102.78,23.84 102.63,23.69 100.14,23.69 99.36,24.48 98.47,24.48 96.72,22.73 94.68,22.73 94.66,22.75 94.64,22.75 94.37,23.02 94.37,23.04 94.02,23.39 94.02,23.47 93.52,23.97 92.21,23.97 91.98,23.75 91.61,23.75 91.12,23.26 87.65,23.26 87.61,23.3 v10(87.58,23.3)
  L3SGND w0.127: v10(86.02,30.93) v11(86.02,30.42) ; v10(87.58,23.3) 87.46,23.41 87.41,23.41 v11(87.11,23.72)
  L5 w0.076: v11(87.11,23.72) 87.05,23.66 86.61,23.66 85.43,24.85 85.43,29.62 86.02,30.21 v11(86.02,30.42)
TYPE_C_RX1+: length 8.4
  L5 w0.066: JUSBC1.B11 97.96,5.73 97.96,7.92 98.93,8.89 98.93,12.15 v5(98.76,12.32)
  BOTTOM w0.102: v5(98.76,12.32) 98.76,13.04 L3102.3
TYPE_C_RX1-: length 8.4
  L5 w0.066: v5(99.26,12.32) 99.07,12.13 99.07,8.83 98.1,7.87 98.1,5.73 JUSBC1.B10
  BOTTOM w0.102: v5(99.26,12.32) 99.26,12.96 L3102.2
TYPE_C_RX2+: length 8.6
  L2 w0.061: v9(102.28,7.41) 102.12,7.57 102.12,9.26 102.41,9.55 102.41,10.29 102.78,10.66 v2(102.91,10.66)
  L5 w0.066: v2(102.91,10.66) 102.91,10.88 103.01,10.98 105.07,10.98 105.34,11.24 105.34,12.05 v5(105.61,12.32)
  BOTTOM w0.102: L3105.2 105.61,12.96 v5(105.61,12.32)
TYPE_C_RX2-: length 8.6
  L2 w0.061: v9(101.78,7.41) 101.92,7.55 101.92,9.34 102.21,9.63 102.21,10.62 v2(102.17,10.66)
  L5 w0.066: v2(102.17,10.66) 102.27,10.66 102.73,11.12 105.02,11.12 105.19,11.3 105.19,12.23 v5(105.11,12.32)
  BOTTOM w0.102: v5(105.11,12.32) 105.11,13.04 L3105.3
TYPE_C_TX1+: length 6.2
  L2 w0.061: v2(97.42,10.74) 97.78,10.38 v9(97.78,7.41)
  L5 w0.066: v2(97.42,10.74) 97.66,10.98 97.66,11.47 97.45,11.68 97.45,12.13 v5(97.26,12.32)
  BOTTOM w0.102: v5(97.26,12.32) 97.26,12.96 L3101.3
TYPE_C_TX1-: length 6.3
  L2 w0.061: v9(98.28,7.41) 98.21,7.41 97.98,7.64 97.98,10.59 v2(98.11,10.71)
  L5 w0.066: v2(98.11,10.71) 97.8,11.02 97.8,11.53 97.59,11.74 97.59,12.15 v5(97.76,12.32)
  BOTTOM w0.102: v5(97.76,12.32) 97.76,13.04 L3101.2
TYPE_C_TX2+: length 10.8
  L5 w0.066: v5(104.11,12.32) 103.97,12.18 103.97,11.81 103.7,11.54 102.51,11.54 102.3,11.32 101.89,11.32 100.78,10.21 100.78,9.4 100.77,9.4 100.77,8.45 100.98,8.25 102.1,7.13 102.1,5.73 JUSBC1.B2
  BOTTOM w0.102: v5(104.11,12.32) 104.11,13.03 L3106.2
TYPE_C_TX2-: length 10.8
  L5 w0.066: JUSBC1.B3 101.96,5.73 101.96,7.07 100.92,8.11 100.63,8.39 100.63,9.46 100.63,9.46 100.63,10.27 101.83,11.47 102.24,11.47 102.45,11.68 103.65,11.68 103.83,11.86 103.83,12.1 v5(103.61,12.32)
  BOTTOM w0.102: v5(103.61,12.32) 103.61,12.96 L3106.3
UART0_DATAIN: length 9.2
  L5 w0.06: v5(74.15,152.88) 74.03,153 74.03,153.11 73.77,153.36 73.77,158.44 73.01,159.2 72,159.2 71.82,159.03 v8(71.82,158.68)
  BOTTOM w0.127: v5(74.15,152.88) v1(74.15,153.64)
UART0_DBG_RXD: length 92.3
  TOP w0.114: v2(78.98,175.36) 78.47,175.87 69.69,175.87 69.25,175.43 v9(69.1,175.43)
  L2 w0.061: v10(44.69,161.87) 43.77,162.79 43.77,164.91 45.42,166.56 45.42,167.16 46.23,167.98 46.23,173.35 51.33,178.44 59.64,178.44 59.92,178.16 64.51,178.16 67.24,175.43 v9(69.1,175.43)
  L3SGND w0.127: v10(44.69,161.87) v11(44.94,161.62)
  L6SGND w0.127: v4(45.33,161.62) v11(44.94,161.62)
  L7 w0.06: 77.28,173.99 77.26,173.99 77.04,173.77 76.96,173.77 76.83,173.64 76.83,173.56 76.54,173.27 76.54,171.04 76.07,170.57 v8(76.07,170.28)
  L7 w0.061: v2(78.98,175.36) 78.98,175.36 78.66,175.67 78.52,175.67 77.94,175.1 77.48,174.64 77.48,174.56 77.39,174.47 77.39,174.1 77.28,173.99 ; v4(45.33,161.62) 45.75,161.19 45.75,160.26 45.92,160.09 45.92,154.03 45.75,153.86 45.75,153.78 45.08,153.11 44.99,153.03 44.99,150.98 51.66,144.32 56.45,144.32 v5(57.54,143.23)
  BOTTOM w0.114: R5602.1 62.62,143.71 v1(62.5,143.58) 62.33,143.42 62.33,142.91 61.02,141.6 58.54,141.6 57.53,142.6 XDP1.31
UART0_DBG_TXD: length 92.5
  TOP w0.114: v2(79.01,176.02) 78.65,176.37 v1(71,176.37) 69.66,176.37 69.13,175.84 v9(69.07,175.84)
  L2 w0.061: v9(69.07,175.84) 67.08,175.84 64.36,178.56 51.2,178.56 46.06,173.42 46.06,168.05 45.24,167.24 45.24,166.63 43.6,164.98 43.6,162.07 v10(44.56,161.11)
  L3SGND w0.127: v11(44.94,160.98) 44.69,160.98 v10(44.56,161.11)
  L6SGND w0.127: v4(45.33,160.98) v11(44.94,160.98)
  L7 w0.06: 76.2,171.96 76.2,171.9 75.87,171.57 75.87,171.38 75.98,171.27 75.98,171.05 75.87,170.93 75.87,170.65 v8(75.78,170.57)
  L7 w0.061: v2(79.01,176.02) 78.92,176.02 78.77,175.87 78.52,175.87 78.5,175.85 78.44,175.85 78.13,175.54 77.94,175.54 77.2,174.8 77.2,174.55 76.2,173.54 76.2,171.96 ; v5(57.14,143.23) 56.22,144.14 51.58,144.14 44.82,150.91 44.82,153.1 44.96,153.24 45.2,153.48 45.57,153.86 45.57,153.93 45.75,154.11 45.75,160.01 45.57,160.19 45.57,160.27 45.33,160.51 v4(45.33,160.98)
  BOTTOM w0.114: XDP1.29 57.13,142.68 58.44,141.37 61.12,141.37 62.7,142.95 R5601.1
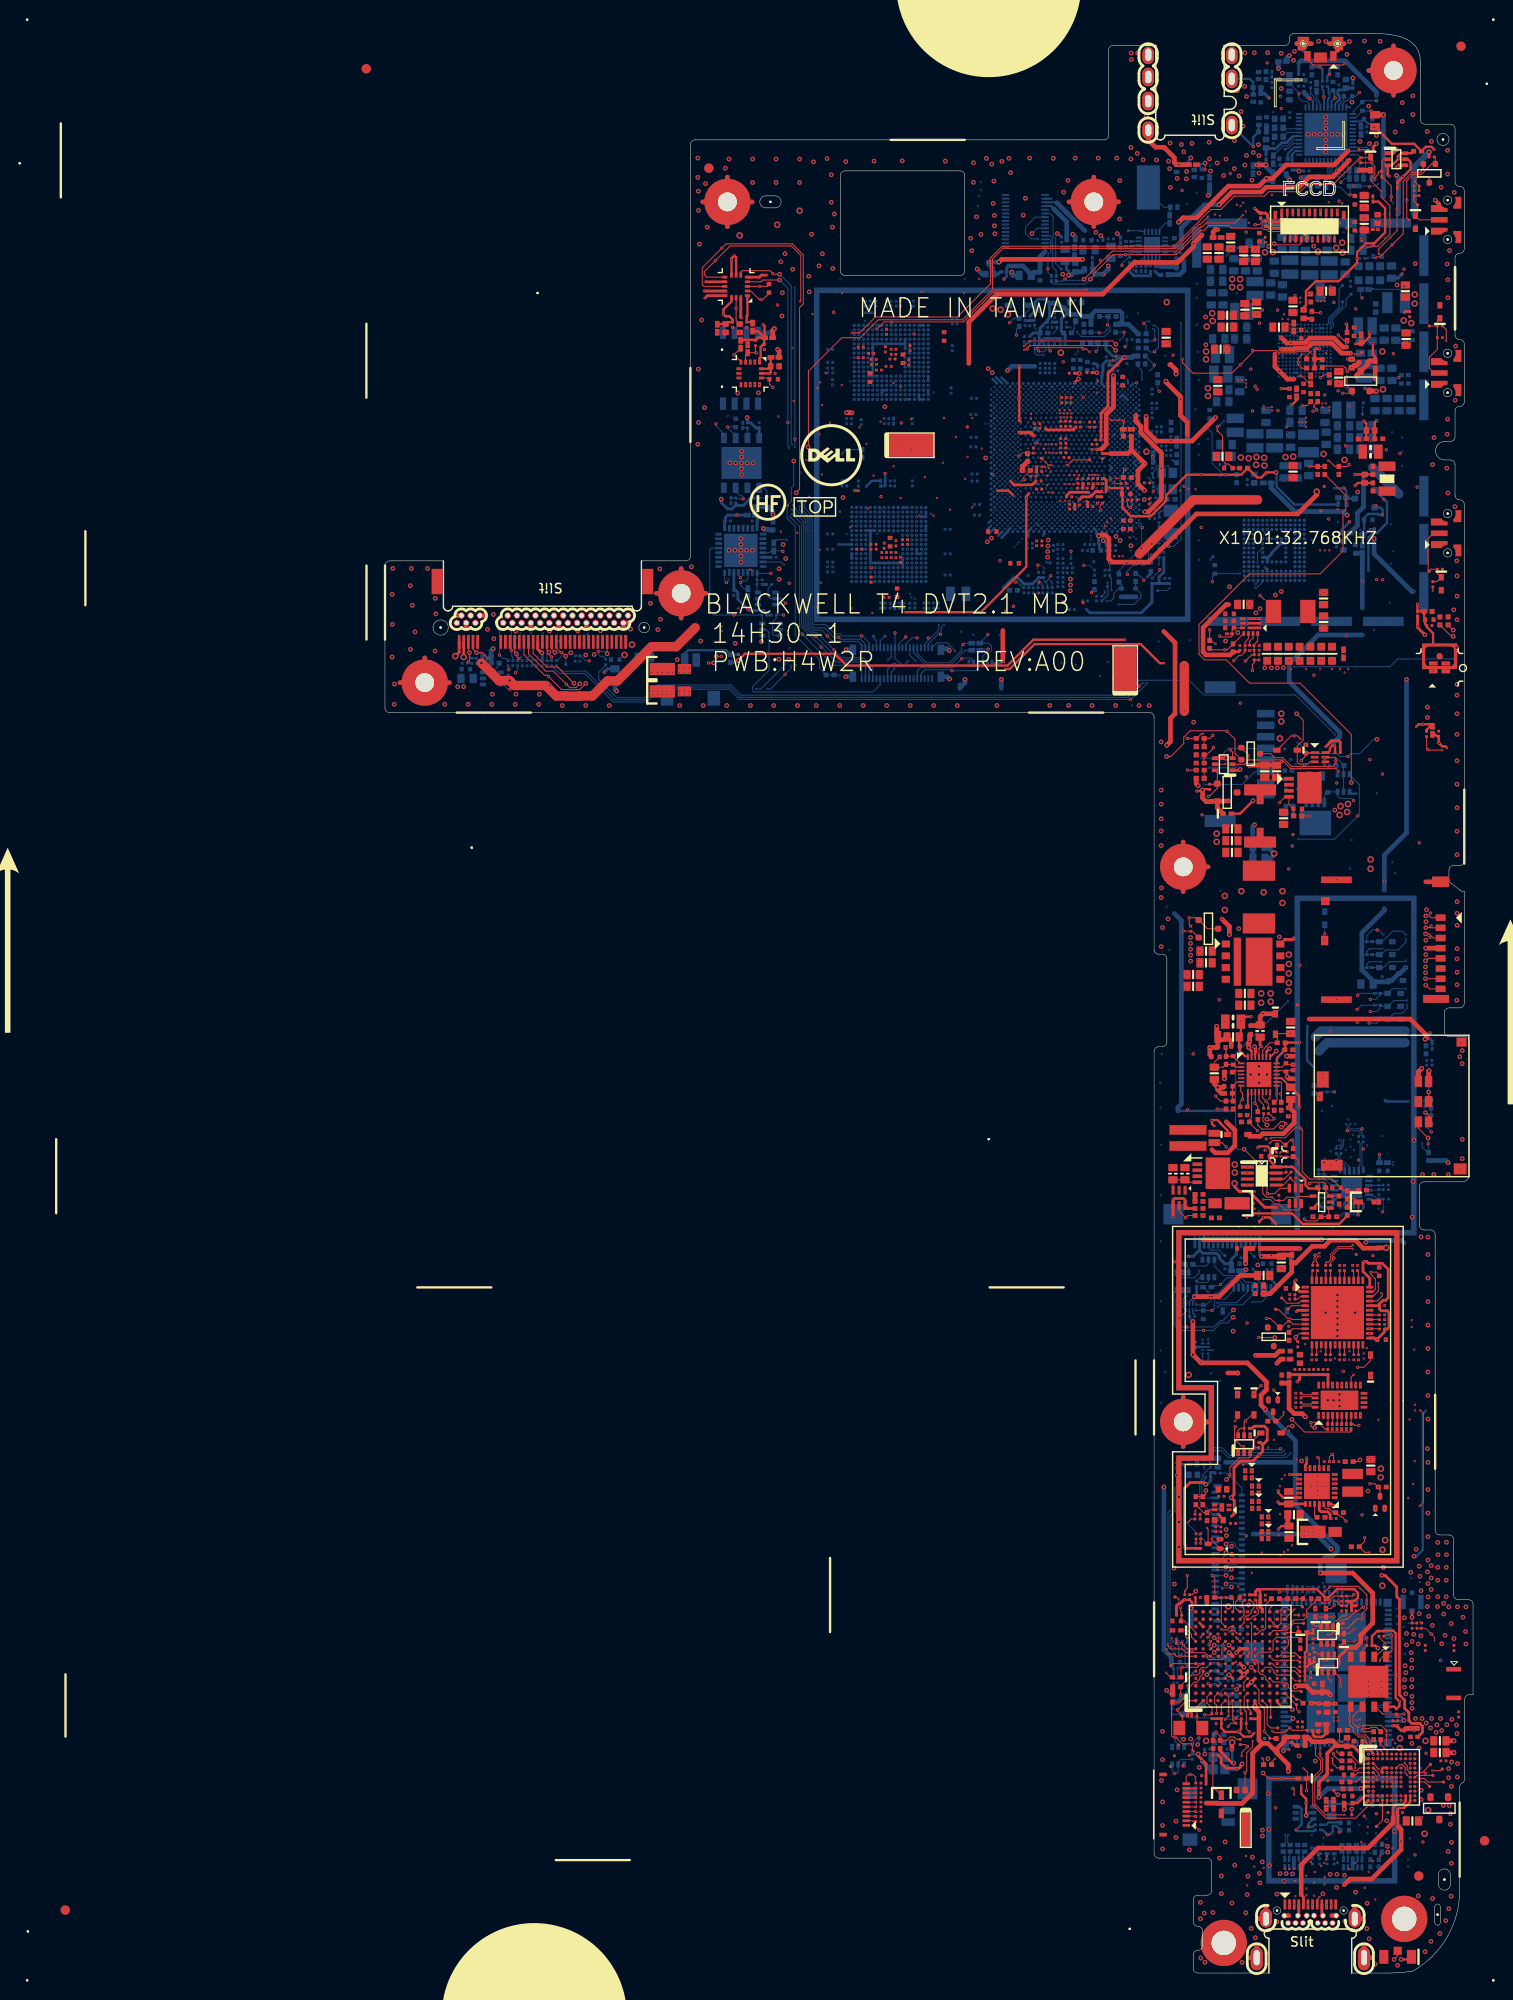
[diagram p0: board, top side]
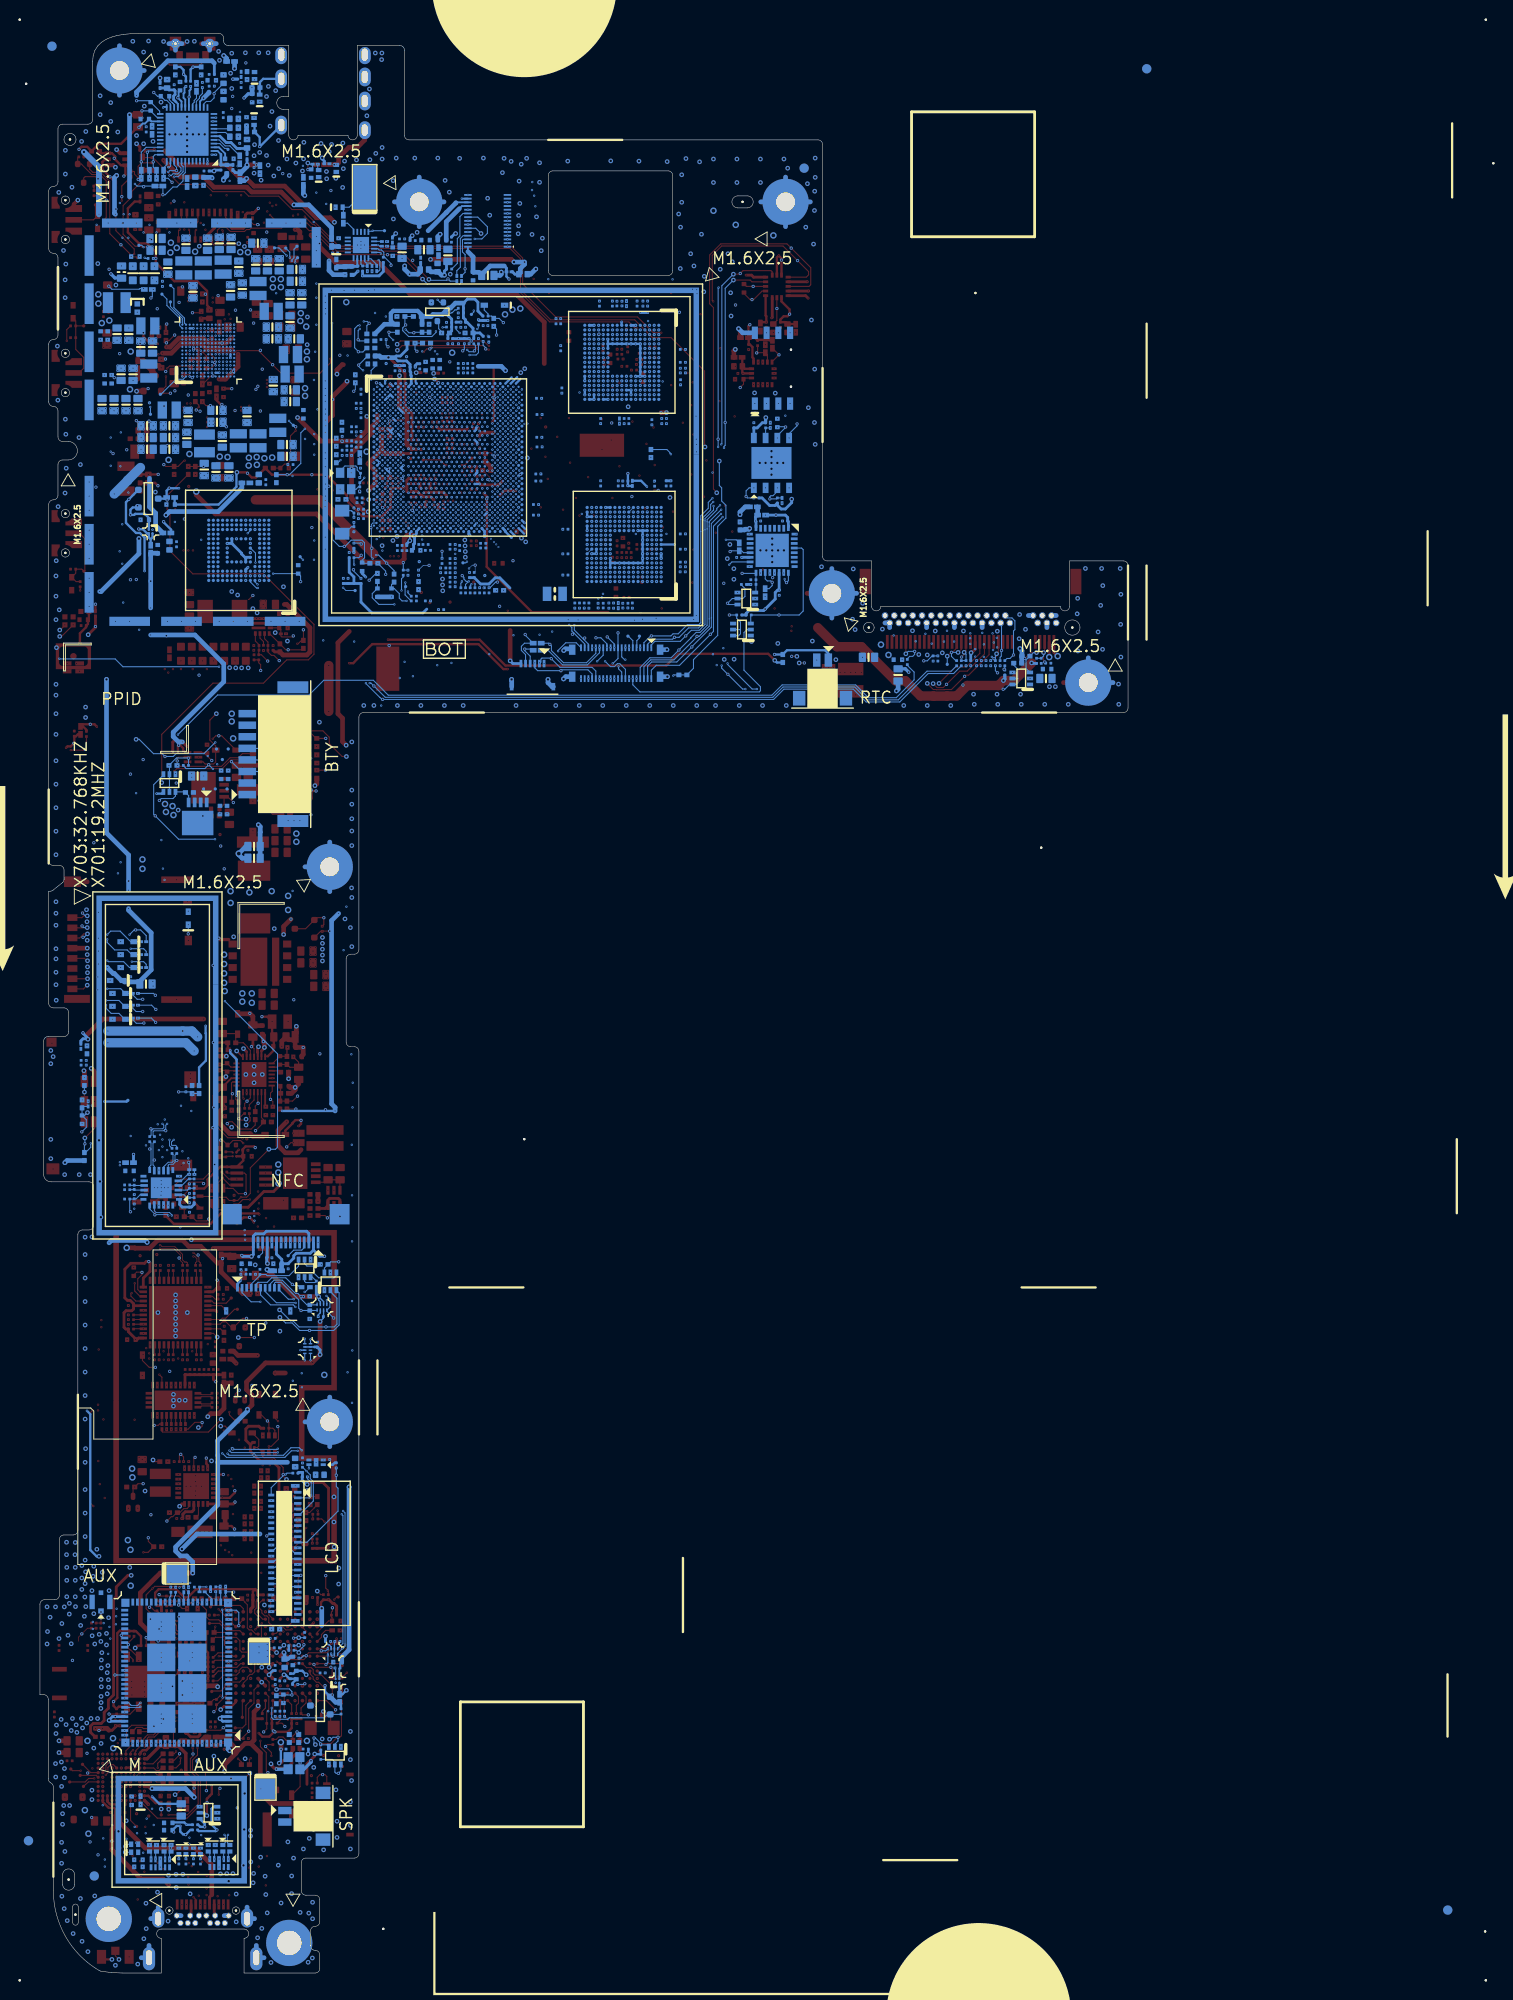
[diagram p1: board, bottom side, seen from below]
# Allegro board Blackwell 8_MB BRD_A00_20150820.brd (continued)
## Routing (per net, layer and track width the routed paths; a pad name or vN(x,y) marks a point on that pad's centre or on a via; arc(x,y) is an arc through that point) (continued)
UART_3_RXD_R: length 4.8
  BOTTOM w0.114: v1(65.16,144.65) 65.16,144.57 R5602.2 65.24,143.71 65.58,143.37 65.58,142.92 65.13,142.47 DB2.5
UART_3_TXD_R: length 2.8
  BOTTOM w0.114: R5601.2 64.43,143.07 v1(65.21,143.07) 65.21,142.9 64.62,142.31 DB2.4
USB2_DEBUG_TYPE_A_DN: length 66.9
  L2 w0.061: v10(94.14,155.65) 93.99,155.8 93.64,156.15 91.25,156.15 89.33,154.24 88.59,154.24 82.3,147.95 80.17,147.95 74.28,142.06 74.27,142.06 74.08,141.87 72.11,141.87 71.77,141.53 71.77,141.27 v10(71.64,141.14)
  L3SGND w0.127: v10(94.14,155.65) v11(94.42,155.93) ; v11(71.26,141.14) v10(71.64,141.14)
  L5 w0.066: v11(94.42,155.93) 94.11,156.24 92.29,156.24 82.83,165.69 81.21,165.69 81.03,165.52 80.13,165.52 79.68,165.97 79.68,166.76 79.55,166.89 v8(78.9,166.89) ; v11(71.26,141.14) 71.51,140.89 71.51,140.38 71.34,140.2 67.17,140.2 67.02,140.35 61.73,140.35 61.38,140.71 58.33,140.71 57.35,139.74 56.88,139.74 v5(56.73,139.88)
USB2_DEBUG_TYPE_A_DP: length 66.9
  L2 w0.061: v10(93.53,155.47) 93.69,155.47 93.75,155.53 93.75,155.76 93.55,155.95 91.33,155.95 89.42,154.04 88.68,154.04 82.38,147.75 80.25,147.75 74.36,141.86 74.36,141.86 74.17,141.67 72.2,141.67 71.97,141.44 71.97,141.17 72.09,141.05 72.38,141.05 v10(72.48,141.14)
  L3SGND w0.127: v11(93.56,155.82) 93.53,155.8 v10(93.53,155.47) ; v11(72.11,141.14) v10(72.48,141.14)
  L5 w0.066: v11(93.56,155.82) 93.56,155.93 93.39,156.1 92.23,156.1 82.78,165.55 81.27,165.55 81.17,165.46 81.09,165.38 80.07,165.38 79.54,165.91 79.54,166.7 79.49,166.74 79.32,166.74 v8(79.18,166.6) ; v11(72.11,141.14) 71.79,141.14 71.65,141.01 71.65,140.32 71.4,140.06 71.28,140.06 67.11,140.06 66.96,140.21 61.68,140.21 61.32,140.57 58.39,140.57 57.41,139.59 56.61,139.59 56.45,139.76 56.45,139.77 v5(56.33,139.88)
USB2_OTG_DN: length 175.7
  L3SGND w0.127: v10(102.5,18.71) 102.5,18.97 v11(102.3,19.17)
  L5 w0.066: v11(102.3,19.17) 102.3,19.2 101.91,19.59 101.91,20.02 102.14,20.26 104.72,22.83 104.72,33.86 108.06,37.21 108.06,39.29 108.51,39.74 108.51,45.76 108.93,46.17 108.93,54.25 108.13,55.04 108.13,59.89 108.51,60.27 108.53,60.27 108.53,68.95 100.31,77.16 100.31,79.06 101.1,79.85 102.86,79.85 104.91,81.9 104.91,92.5 104.66,92.76 104.66,121.4 107.45,124.19 107.45,131.52 106.5,132.46 106.5,134.37 103.88,137 103.88,140.01 103.88,148.68 97.61,154.95 92.96,154.95 82.52,165.39 81.41,165.39 81.27,165.25 79.64,165.25 78.61,166.28 78.61,166.6 v8(78.61,166.6)
USB2_OTG_DN_R: length 9
  L3SGND w0.127: v11(107.94,18.74) 108.32,19.13 v10(108.32,19.15) ; v10(102.5,17.85) v11(102.2,18.16)
  L5 w0.066: v11(102.2,18.16) 101.85,18.16 101.78,18.09 101.78,17.81 102.3,17.28 107.06,17.28 107.94,18.16 v11(107.94,18.74)
USB2_OTG_DP: length 175.8
  L3SGND w0.127: v10(101.74,18.71) v11(101.74,19.22)
  L5 w0.066: v11(101.74,19.22) 101.74,19.47 101.77,19.5 101.77,20.08 102,20.31 102,20.32 104.57,22.89 104.57,33.92 107.92,37.26 107.92,39.35 108.37,39.79 108.37,45.81 108.78,46.23 108.78,54.19 107.99,54.99 107.99,59.95 108.38,60.35 108.38,68.89 100.17,77.11 100.17,79.12 101.04,79.99 102.81,79.99 104.77,81.96 104.77,92.45 104.51,92.7 104.51,121.46 107.3,124.25 107.3,131.46 106.36,132.41 106.36,134.31 103.73,136.94 103.73,139.95 103.73,148.62 97.55,154.81 92.9,154.81 82.46,165.25 81.47,165.25 81.33,165.11 79.58,165.11 78.47,166.22 78.47,166.46 78.41,166.52 78.41,166.69 78.33,166.77 v8(78.33,166.89)
USB2_OTG_DP_R: length 9
  TOP w0.102: v10(108.32,18.21) 108.32,18.21 U2901.L5
  L3SGND w0.127: v11(101.41,18.21) 101.41,18.18 v10(101.74,17.85) ; v10(108.32,18.21) 108.14,18.03 v11(108.14,17.72)
  L5 w0.066: v11(101.41,18.21) 101.64,17.98 101.64,17.75 102.24,17.14 102.36,17.14 107.12,17.14 107.7,17.72 v11(108.14,17.72)
USB2_WIFI_DN: length 165.9
  L5 w0.066: v5(106.74,29.2) 106.72,29.23 106.59,29.23 106.54,29.18 106.54,28.98 106.31,28.75 106.03,28.75 105.77,29.01 105.77,34.25 108.51,37 108.51,38.75 108.95,39.19 108.95,45.46 109.61,46.12 109.61,54.36 108.57,55.4 108.57,59.66 109.17,60.27 109.17,68.93 100.75,77.35 100.75,78.38 100.98,78.61 102.24,78.61 105.35,81.72 105.35,92.73 105.09,92.98 105.09,121.19 107.88,123.98 107.88,133.69 104.31,137.26 104.31,140.19 104.31,148.89 96.52,156.68 92.47,156.68 83.07,166.08 81.21,166.08 80.92,165.79 80.38,165.79 80.25,165.92 80.25,165.98 v8(80.31,166.04)
  BOTTOM w0.102: WU3701.69 108.04,29.21 107.86,29.03 107.86,29.02 107.8,28.97 107.75,28.92 107.05,28.92 106.83,29.14 106.83,29.15 106.78,29.2 v5(106.74,29.2)
USB2_WIFI_DP: length 165.9
  L5 w0.066: v5(106.77,28.77) 106.54,28.77 106.37,28.61 105.97,28.61 105.62,28.95 105.62,34.31 108.37,37.05 108.37,38.81 108.81,39.25 108.81,45.52 109.47,46.18 109.47,54.3 108.42,55.34 108.42,59.72 109.03,60.32 109.03,68.87 100.61,77.29 100.61,78.44 100.93,78.76 102.18,78.76 105.21,81.78 105.21,92.67 104.95,92.92 104.95,121.25 107.74,124.04 107.74,133.64 104.17,137.21 104.17,140.13 104.17,148.83 96.47,156.54 92.41,156.54 83.01,165.93 81.26,165.93 80.98,165.65 80.32,165.65 80.11,165.86 80.11,166.24 v8(80.03,166.32)
  BOTTOM w0.102: v5(106.77,28.77) 106.83,28.71 WU3701.70
USB3_0_RX+: length 112.3
  L5 w0.066: v5(16.37,141.27) 16.27,141.27 16.06,141.06 16.06,140.96 16.14,140.89 27.04,140.89 35.59,149.44 35.59,154.89 39.52,158.82 40.45,158.82 41.79,160.16 41.79,168.01 43.48,169.7 43.48,177.88 48.2,182.6 66.65,182.6 66.93,182.87 69.05,182.87 70.26,181.67 73.2,181.67 75.78,179.09 75.78,175.89 75.12,175.23 75.12,174.39 73.81,173.08 73.81,168.36 74.39,167.78 77.16,167.78 77.74,167.2 77.74,165.98 78.6,165.12 78.6,164.17 79.28,163.49 v8(79.46,163.49)
USB3_0_RX+_L: length 5
  L7 w0.061: NGFF1.37 17.08,145.59 17.08,145.44 17,145.36 16.55,145.36 16.47,145.28 16.47,143.91 16.11,143.55 16.11,141.98 16.27,141.83 v5(16.37,141.83)
USB3_0_RX-: length 112.2
  L5 w0.066: v8(79.18,163.21) 79.18,163.38 78.46,164.11 78.46,165.06 77.59,165.92 77.59,167.14 77.1,167.63 74.33,167.63 73.67,168.3 73.67,173.14 74.98,174.45 74.98,175.28 75.64,175.94 75.64,179.03 73.14,181.52 70.2,181.52 68.99,182.73 66.98,182.73 66.71,182.46 48.26,182.46 43.62,177.82 43.62,169.64 41.93,167.95 41.93,160.1 40.51,158.68 39.58,158.68 35.73,154.83 35.73,149.38 27.1,140.75 16.08,140.75 15.92,140.91 15.92,141.21 v5(15.86,141.27)
USB3_0_RX-_L: length 5
  L7 w0.061: v5(15.86,141.83) 15.91,141.88 15.91,143.63 16.27,143.99 NGFF1.35
USB3_0_TX+: length 115.3
  L5 w0.066: v5(15.35,141.27) 15.72,141.64 27.25,141.64 35.29,149.68 35.29,155.01 39.54,159.26 40.35,159.26 41.5,160.41 41.5,168.13 43.19,169.82 43.19,178 48.08,182.89 66.53,182.89 66.82,183.19 69.24,183.19 70.47,181.96 73.53,181.96 76.07,179.42 76.07,175.75 75.41,175.09 75.41,174.33 73.94,172.85 73.94,168.41 74.45,167.9 77.32,167.9 77.95,167.27 77.95,166.08 79.87,164.16 81.04,164.16 81.24,164.36 81.24,164.82 81.08,164.98 80.39,164.98 v8(80.31,164.91)
USB3_0_TX+_L: length 4.9
  L7 w0.061: v5(15.35,141.83) 15.27,141.91 NGFF1.31
USB3_0_TX-: length 115.3
  L5 w0.066: v5(14.85,141.27) 14.85,141.42 14.98,141.56 15.44,141.56 15.66,141.78 27.19,141.78 35.15,149.74 35.15,155.07 39.48,159.4 40.29,159.4 41.36,160.46 41.36,168.19 43.04,169.88 43.04,178.06 48.02,183.04 66.47,183.04 66.76,183.33 69.3,183.33 70.53,182.1 73.59,182.1 76.22,179.47 76.22,175.69 75.56,175.03 75.56,174.27 75.49,174.21 74.08,172.79 74.08,168.47 74.5,168.05 77.38,168.05 78.09,167.33 78.09,166.14 79.93,164.3 80.98,164.3 81.1,164.42 81.1,164.76 81.02,164.84 80.73,164.84 80.59,164.7 v8(80.59,164.62)
USB3_0_TX-_L: length 4.9
  L7 w0.061: v5(14.85,141.83) 14.99,141.83 15.07,141.9 15.07,145.16 14.99,145.23 14.54,145.23 14.46,145.31 14.46,145.59 NGFF1.29
USB3_A_INN: length 2.6
  BOTTOM w0.102: 103.02,87.8 103.02,87.61 103.24,87.4 103.67,87.4 103.76,87.31 U5407.8 ; 103.02,87.8 103.02,88.37 C3139.1 ; 103.02,87.8 v1(102.83,87.8)
USB3_A_INP: length 2.5
  BOTTOM w0.102: U5407.9 104.26,87.11 103.76,87.61 103.33,87.61 103.24,87.7 103.24,88.46 C3138.1
USB3_A_OUTN: length 26.9
  L3SGND w0.127: v10(98.46,62.66) 98.61,62.81 v11(98.94,62.81)
  L5 w0.066: v5(103.75,82.97) 103.83,82.97 103.97,82.83 103.97,82.83 104.05,82.75 104.05,82.6 103.92,82.47 100.84,82.47 99.12,80.75 99.12,76.24 99.12,71.24 97.83,69.96 97.83,69.6 97.83,69.48 97.83,65.37 99.55,63.65 99.55,62.65 99.47,62.57 99.18,62.57 v11(98.94,62.81)
USB3_A_OUTP: length 26.9
  L3SGND w0.127: v10(98.46,62.15) 98.87,62.15 v11(98.97,62.25)
  L5 w0.066: v5(104.26,82.95) 104.19,82.88 104.19,82.54 103.98,82.33 100.9,82.33 99.26,80.69 99.26,76.3 99.26,71.18 99.18,71.1 97.97,69.9 97.97,69.65 97.97,69.54 97.97,69.54 97.97,66.02 97.97,66.02 97.97,65.43 99.69,63.71 99.69,62.59 99.52,62.42 99.14,62.42 v11(98.97,62.25)
USB3_B_INN: length 28.8
  L3SGND w0.127: v11(98.97,61.69) 98.92,61.64 v10(98.46,61.64)
  L5 w0.066: v11(98.97,61.69) 99.23,61.43 99.68,61.43 99.99,61.73 99.99,64.06 98.9,65.14 98.9,70.41 99.3,70.81 99.55,71.06 99.55,73.78 99.55,80.57 99.94,80.95 103.01,80.95 103.48,81.41 103.48,81.65 103.36,81.76 v5(103.36,81.86)
  BOTTOM w0.102: U5407.20 105.26,82.38 105.05,82.18 103.61,82.18 103.36,81.94 v5(103.36,81.86)
USB3_B_INP: length 28.9
  L3SGND w0.127: v11(98.94,61.13) v10(98.46,61.13)
  L5 w0.066: v5(103.75,81.86) 103.75,81.78 103.62,81.66 103.62,81.35 103.07,80.81 100,80.81 99.7,80.51 99.7,76.48 99.7,71 99.36,70.66 99.05,70.35 99.05,65.2 100.13,64.12 100.13,61.67 99.74,61.29 99.1,61.29 v11(98.94,61.13)
  BOTTOM w0.102: U5407.19 105.76,82.57 105.14,81.96 103.85,81.96 v5(103.75,81.86)
USB3_B_OUTN: length 3.3
  BOTTOM w0.102: 105.4,87.85 105.4,87.32 105.26,87.18 U5407.11 ; 105.4,87.85 v1(105.24,87.85) ; 105.4,87.85 105.4,89.68 C3149.1
USB3_B_OUTP: length 3.2
  BOTTOM w0.102: 105.61,89.05 105.61,89.7 C3148.1 ; 105.61,89.05 v1(105.75,89.05) ; 105.61,89.05 105.61,87.31 105.76,87.16 U5407.12
USB3_DE1: length 1.7
  BOTTOM w0.114: U5407.3 101.66,84.61 R3172.1 R3171.2
USB3_DE2: length 1.5
  BOTTOM w0.114: R3170.2 107.45,84.65 R3173.1 107.36,84.61 U5407.16
USB3_EQ1: length 1.8
  BOTTOM w0.114: R3161.2 R3162.1 101.74,83.79 102.06,84.11 U5407.2
USB3_EQ2: length 3.1
  BOTTOM w0.114: U5407.17 106.78,84.11 107.22,83.66 R3164.1 107.45,83.64 R3163.2 107.91,82.34 v1(107.83,82.27)
USB3_OS1: length 1.9
  BOTTOM w0.114: U5407.4 102.28,85.11 101.56,85.82 R3166.1 R3167.2
USB3_OS2: length 1.5
  BOTTOM w0.114: U5407.15 107.4,85.11 R3169.1 107.45,85.11 107.86,85.11 R3168.2
USB3_RCOMP_N: length 5.3
  L7 w0.061: v5(85.58,164.08) 85.23,163.72 85.23,163.72 82.21,163.72 81.87,164.06 v8(80.59,164.06)
USB3_RCOMP_P: length 5
  L7 w0.061: v5(85.13,163.49) 85.1,163.52 82.13,163.52 81.79,163.86 80.94,163.86 80.88,163.8 v8(80.88,163.77)
  BOTTOM w0.102: R648.1 85.41,163.22 v5(85.13,163.49)
USB3_RXN0: length 92
  L5 w0.066: v8(80.59,162.93) 80.68,163.01 80.68,163.12 80.48,163.33 80.48,163.48 80.58,163.58 83.51,163.58 92.72,154.37 92.91,154.37 97.34,154.37 103.19,148.52 103.19,136.79 105.92,134.05 105.92,132.05 106.87,131.11 106.87,124.45 104.08,121.66 104.08,120.7 104.08,120.22 104.08,119.49 104.08,91.97 v5(103.87,91.77)
  BOTTOM w0.102: C3149.2 105.39,90.54 105.39,90.92 105.29,91.02 104.26,91.02 104.14,91.14 ; 104.14,91.14 104.02,91.26 104.02,91.62 v5(103.87,91.77) ; 104.14,91.14 v1(104.02,91.03)
USB3_RXP0: length 92.1
  L5 w0.066: v5(104.38,91.77) 104.22,91.93 104.22,119.55 104.22,120.64 104.22,121.6 107.01,124.39 107.01,131.17 106.07,132.11 106.07,134.11 103.33,136.85 103.33,148.58 97.4,154.52 93.33,154.52 92.78,154.52 83.57,163.72 80.52,163.72 80.31,163.51 v8(80.31,163.21)
  BOTTOM w0.102: v5(104.38,91.77) 104.23,91.62 104.23,91.35 104.35,91.23 105.38,91.23 105.5,91.11 ; 105.5,91.11 105.61,91.01 105.61,90.54 C3148.2 ; 105.5,91.11 v1(105.62,91.23)
USB3_TXN0: length 92.9
  L5 w0.066: v8(78.89,162.93) 78.98,162.93 79.19,162.72 80.24,162.72 80.39,162.57 80.79,162.57 81.02,162.79 83.68,162.79 92.54,153.93 97.13,153.93 102.72,148.35 102.72,136.64 105.49,133.87 105.49,131.87 106.43,130.93 106.43,124.63 103.64,121.84 103.64,120.4 103.64,119.31 103.64,119.31 103.64,93.49 103.31,93.16 103.31,90.8 103.5,90.61 103.5,90.38 103.41,90.29 103.35,90.29 103.16,90.11 v5(103.16,90.04)
  BOTTOM w0.102: v5(103.16,90.04) 103.4,89.8 103.4,89.51 103.34,89.44 102.94,89.44 102.83,89.33 C3139.2
USB3_TXP0: length 92.9
  L5 w0.066: v5(103.62,90.04) 103.64,90.06 103.64,90.67 103.46,90.86 103.46,93.1 103.78,93.43 103.78,119.37 103.78,119.37 103.78,120.34 103.78,121.78 106.57,124.57 106.57,130.99 105.63,131.93 105.63,133.93 102.86,136.7 102.86,148.41 97.19,154.08 92.6,154.08 83.74,162.94 80.96,162.94 80.73,162.71 80.45,162.71 80.3,162.86 79.25,162.86 78.9,163.21 v8(78.61,163.21)
  BOTTOM w0.102: C3138.2 103.62,89.4 v5(103.62,90.04)
USB_B_N: length 8.3
  L5 w0.066: JUSBC1.B7 99.99,6.56 99.99,7.8 99.84,7.95 99.84,10.26 101.6,12.02 102.01,12.02 102.1,12.11 102.1,12.26 102.02,12.34 v5(101.84,12.34)
  BOTTOM w0.102: L3104.2 v5(101.84,12.34)
USB_B_P: length 8.3
  L5 w0.066: v5(102.6,12.34) 102.53,12.34 102.07,11.88 101.66,11.88 99.98,10.21 99.98,8 100.13,7.86 100.13,6.5 JUSBC1.B6
  BOTTOM w0.102: L3104.3 v5(102.6,12.34)
USB_HSIC_RCOMP: length 8.2
  L7 w0.06: 80.58,165.43 80.26,165.11 80.23,165.11 80.11,164.99 79.94,164.99 79.83,165.11 79.66,165.11 79.54,164.99 78.81,164.99 78.61,165.19 v8(78.33,165.19)
  L7 w0.061: 85,166.35 84.33,166.35 83.75,165.77 82.14,165.77 82.1,165.82 81.38,165.82 80.99,165.43 80.58,165.43
  L7 w0.076: v5(85.58,165.86) 85.09,166.35 85,166.35
USB_MODEM_DN: length 130.5
  L5 w0.066: v4(68.59,181.58) 68.5,181.67 68.5,181.95 68.42,182.03 67.52,182.03 67.22,181.73 48.86,181.73 44.49,177.36 44.49,169.13 42.61,167.25 42.61,159.15 41.07,157.62 39.68,157.62 36.52,154.46 36.52,149.05 27.42,139.95 14.21,139.95 9.41,144.74 9.41,145.54 NGFF1.9 ; v4(83.83,182.8) 83.83,182.8 83.56,182.53 83.56,180 82.93,179.37 82.93,177.29 82.6,176.97 82.6,174.25 82.76,174.09 83.02,174.09 v4(83.12,174.19)
  L7 w0.061: v8(80.91,166.57) 81.16,166.81 82.66,166.81 84.02,168.17 84.02,173.47 84.02,173.47 84.02,173.65 83.66,174.01 83.3,174.01 v4(83.12,174.19) ; v4(68.59,181.58) 68.59,181.73 68.41,181.91 68.41,182.31 68.97,182.87 74.69,182.87 75.38,183.56 79.87,183.56 80.96,182.47 83.68,182.47 83.83,182.62 v4(83.83,182.8)
USB_MODEM_DP: length 130.5
  L5 w0.066: NGFF1.7 9.27,144.69 14.15,139.81 27.48,139.81 36.66,148.99 36.66,154.4 39.74,157.47 41.13,157.47 42.75,159.09 42.75,167.19 44.63,169.07 44.63,177.3 48.92,181.59 67.28,181.59 67.58,181.88 67.91,181.88 v4(68.21,181.58) ; v4(83.09,173.81) 82.96,173.94 82.71,173.94 82.46,174.19 82.46,174.28 82.46,177.03 82.79,177.35 82.79,179.43 83.42,180.06 83.42,182.74 83.45,182.77 v4(83.45,182.83)
  L7 w0.061: v4(83.09,173.81) 83.58,173.81 83.82,173.57 83.82,168.25 82.58,167.01 81.07,167.01 80.59,166.53 v8(80.59,166.32) ; v4(68.21,181.58) 68.21,182.39 68.89,183.07 74.6,183.07 75.29,183.76 79.95,183.76 81.04,182.67 83.32,182.67 83.45,182.8 v4(83.45,182.83)
USB_OTG_SOC_ID: length 155.5
  TOP w0.114: v2(94.93,21.61) 94.98,21.56 94.98,21.53 95.49,21.03 v1(96.96,21.03) D2902.A
  L5 w0.076: v2(94.93,21.61) 94.98,21.56 94.98,21.53 93.57,22.94 93.57,27.82 94.45,28.7 94.45,32.39 94.14,32.7 v4(94.14,35.66) ; v4(85.84,138.48) 85.8,138.48 81.7,142.58 79.11,142.58 78.93,142.76 78.93,143.29 78.64,143.58 78.3,143.58 v5(74.54,147.34)
  L7 w0.06: v8(75.22,156.98) 75.22,156.87 75.13,156.79 75.13,156.62 75.02,156.5 75.02,156.33 75.02,156.33 75.07,156.28 75.07,156.13 74.89,155.95 74.89,153.39 75.27,153 75.27,149.06 74.82,148.61 74.82,148.49 74.54,148.2 v5(74.54,147.34)
  L7 w0.061: v4(94.14,35.66) 94.06,35.74 94.06,35.76 93.22,36.6 93.17,36.65 92.62,36.65 92.24,37.03 92.24,37.28 92.42,37.46 92.42,38.02 91.58,38.86 90.9,38.86 89.11,40.65 89.11,49.65 90.49,51.03 90.49,53.69 90.67,53.88 90.68,53.88 90.88,54.08 91.09,54.29 91.39,54.59 91.39,60.51 90.6,61.3 90.6,68.26 90.28,68.58 90.28,71.43 90.27,71.43 90.27,71.67 90.28,71.67 90.28,71.87 90.49,72.08 90.49,75.42 89.31,76.6 89.31,77.3 89.31,77.73 88.4,78.65 88.4,79.91 88.4,80.06 88.4,80.06 88.4,80.35 88.03,80.72 87.82,80.92 87.82,94.6 87.85,94.63 87.85,98.49 88.04,98.68 88.21,98.85 88.21,107.89 88.77,108.45 88.77,108.87 88.77,108.88 88.77,109.02 88.77,109.15 88.77,109.19 88.77,109.19 88.77,109.37 88.77,109.7 88.77,109.7 88.77,120.65 88.77,120.66 88.46,120.96 88.36,121.07 88.36,121.07 88.26,121.17 85.94,123.49 85.94,130.27 86.64,130.97 86.64,135.89 86.63,135.89 86.63,137.33 85.84,138.12 v4(85.84,138.48)
USB_RCOMP: length 7.6
  L7 w0.06: 80.37,165.81 79.83,165.27 79.66,165.27 79.54,165.39 79.38,165.39 79.26,165.27 79.1,165.27 78.65,165.72 78.63,165.75 v8(78.33,165.75)
  L7 w0.061: 80.37,165.81 81.12,165.81 81.24,165.94 82.15,165.94 82.19,165.89 83.7,165.89 84.32,166.51
  L7 w0.076: 84.32,166.51 84.53,166.72 v5(84.97,166.72)
USB_SSIC_RCOMP_N: length 6.5
  L7 w0.06: v8(79.18,164.34) 79.26,164.42 79.54,164.42 79.66,164.54 79.83,164.54 79.94,164.42 80.11,164.42 80.23,164.54 80.39,164.54 80.51,164.42 80.68,164.42 80.79,164.54 80.79,164.58 80.79,164.58
  L7 w0.061: 80.79,164.58 81.43,165.21 81.56,165.21 81.75,165.41 82.72,165.41
  L7 w0.076: 82.72,165.41 82.77,165.35 84.77,165.35 84.91,165.5 v5(84.95,165.5)
USB_SSIC_RCOMP_P: length 6.2
  L7 w0.06: v5(84.95,166.06) 84.21,166.06 83.8,165.65 81.65,165.65 81.61,165.7 81.43,165.7 80.68,164.94 80.63,164.94 80.39,164.71 80.23,164.71 80.11,164.82 79.94,164.82 79.79,164.67 79.51,164.67 v8(79.46,164.62)
USB_T_N: length 6.1
  L2 w0.061: v10(100.19,11.2) 100.13,11.14 100.13,7.56 v9(100.28,7.41)
  L3SGND w0.127: v10(100.19,11.2) 100.19,11.48 v11(100.27,11.55)
  L5 w0.066: v11(100.27,11.55) 100.27,11.78 100.82,12.34 v5(101.03,12.34)
  BOTTOM w0.102: v5(101.03,12.34) L3103.3
USB_T_P: length 6.1
  L2 w0.061: v9(99.78,7.41) 99.93,7.56 99.93,11.07 v10(99.81,11.2)
  L3SGND w0.127: v10(99.81,11.2) 99.81,11.45 v11(99.71,11.55)
  L5 w0.066: v5(100.27,12.34) 100.32,12.34 100.37,12.28 100.37,12.09 100.21,11.93 100.11,11.93 99.73,11.55 v11(99.71,11.55)
  BOTTOM w0.102: v5(100.27,12.34) 100.26,12.34 L3103.2
VGG_LX0:
  vias: v1(100.32,168.78)
VGG_LX1:
  vias: v1(96.53,168.85)
VGG_LX2:
  vias: v1(93.79,168.8)
VGG_LX3:
  vias: v1(94.27,171.14)
VGG_SENSE: length 30.2
  L5 w0.066: v7(78.52,162.66) 78.46,162.6 76.82,162.6 75.62,161.39 v8(74.76,161.39)
  L6SGND w0.076: v4(90.64,168.98) 90.71,168.9 90.89,168.9 96.01,174.02 97.04,174.02 97.33,173.73 v8(97.43,173.73)
  L7 w0.061: v7(78.52,162.66) 78.55,162.63 78.96,162.63 79.15,162.44 81.73,162.44 82.45,163.16 82.62,163.16 85.53,163.16 86.17,163.81 86.17,165.38 87.6,166.8 87.6,168.45 88.2,169.05 90.39,169.05 90.47,168.98 v4(90.64,168.98)
VGG_VSSSENSE: length 30.2
  L5 w0.066: v7(78.83,162.35) 78.73,162.45 76.88,162.45 75.56,161.14 75.25,161.14 v8(75.03,160.92)
  L6SGND w0.076: v8(97.43,173.33) 97.43,173.39 96.97,173.85 96.08,173.85 90.94,168.7 90.74,168.7 v4(90.64,168.6)
  L7 w0.061: v7(78.83,162.35) 78.95,162.35 79.03,162.28 81.85,162.28 82.54,162.96 85.61,162.96 86.37,163.72 86.37,165.29 87.8,166.72 87.8,168.37 88.28,168.85 90.31,168.85 90.56,168.6 v4(90.64,168.6)
VNN_LX:
  vias: v1(93.79,175.36)
VNN_SENSE: length 39.9
  L5 w0.066: v8(98.23,175.73) 97.77,175.73 96.52,174.48 95.22,174.48 95.08,174.63 94.74,174.63 93.77,174.63 93.31,174.17 90.49,174.17 v11(90.18,173.86) ; v8(74.48,165.68) 74.71,165.68 74.91,165.48 75.12,165.48 75.18,165.54 76.22,165.54 77.15,166.47 v4(77.3,166.47)
  L6SGND w0.127: v11(90.18,173.86) 90.05,173.73 v4(90.05,173.53)
  L7 w0.06: v4(77.3,166.47) 77.67,166.47 77.7,166.43 77.89,166.43 78.15,166.69 78.41,166.69 78.53,166.8 78.7,166.8 78.81,166.69 78.98,166.69 79.26,166.97 79.26,167.54 79.26,168.07 79.26,168.08 79.26,169.23 79.38,169.35 79.38,169.52 79.26,169.63 79.26,169.9
  L7 w0.061: v4(90.05,173.53) 90.05,173.43 89.8,173.17 89.8,169.77 89.39,169.36 86.58,169.36 85.67,170.27 85.67,172.37 85.92,172.62 85.92,172.96 85.68,173.2 85.04,173.2 83.42,174.82 82.81,174.82 81.47,173.48 81.47,172.87 80.68,172.07 80.68,171.33 80.71,171.3 80.71,170.92 80.28,170.48 79.85,170.48 79.26,169.9
VNN_VSSSENSE: length 39.3
  L5 w0.066: v8(75.03,165.68) 76.16,165.68 77.3,166.82 v4(77.33,166.82) ; v11(89.6,173.86) 89.62,173.86 90.07,174.31 93.25,174.31 93.72,174.77 94.68,174.77 95.14,174.77 95.28,174.63 96.46,174.63 97.71,175.87 97.97,175.87 v8(98.23,176.13)
  L6SGND w0.127: v4(89.6,173.5) v11(89.6,173.86)
  L7 w0.06: 78.98,169.57 78.98,169.52 78.98,169.52 78.98,169.35 79.1,169.23 79.1,168.01 79.1,168.01 79.1,167.87 79.1,167.37 78.81,167.09 78.7,166.97 78.53,166.97 78.41,167.09 78.25,167.09 77.99,166.83 77.7,166.83 77.69,166.82 v4(77.33,166.82)
  L7 w0.061: v4(89.6,173.5) 89.6,173.5 89.6,169.86 89.3,169.56 86.66,169.56 85.87,170.35 85.87,172.28 86.13,172.54 86.13,173.04 85.77,173.4 85.12,173.4 83.5,175.02 82.73,175.02 81.27,173.56 81.27,172.95 80.47,172.16 80.47,171.25 80.51,171.21 80.51,171 80.14,170.63 79.71,170.63 79.06,169.98 79.06,169.65 78.98,169.57
VOLUME_DOWN: length 8.2
  TOP w0.114: VDKEY1.2 113.34,155.59 112.76,155.01 112.76,151.58 TP5403.1 113.09,151.71 C5403.2 113.75,151.27 D5402.1 113.71,150.36 R5405.2
VOLUME_DOWN_EC_IN: length 142
  TOP w0.114: R5405.1 v9(113.27,149.4) ; v2(87.64,41.27) 87.26,40.89 R1734.1
  L2 w0.061: v9(113.27,149.4) 113.27,143.96 113.01,143.7 113.01,138.76 113.96,137.82 113.96,135.3 112.2,133.55 107.45,133.55 v2(107.22,133.32)
  L3SGND w0.127: v11(91.23,37.92) 91.25,37.92 91.25,37.94 90.96,38.23 v10(90.84,38.23)
  L5 w0.076: v5(98.67,132.99) 98.67,122.91 98.4,122.65 98.4,122.36 99.12,121.64 99.12,111.25 99.55,110.81 99.55,95.96 98.87,95.27 98.87,91.89 95.05,88.07 95.05,87.65 95.02,87.62 95.02,84.19 94.61,83.78 94.61,82.01 94.61,82.01 94.61,81.06 94.61,80.91 94.61,79.64 94.61,79.64 94.61,78.69 94.61,78.54 93.52,77.44 93.52,77.29 93.52,77.29 93.52,75.66 91.05,73.19 91.05,72.86 91.05,71.53 90.88,71.36 90.88,68.33 91.05,68.17 91.05,55.47 91.82,54.7 91.82,54.7 93.51,53.01 93.51,52.69 93.51,52.69 93.51,42.46 94.09,41.87 94.09,39.36 92.77,38.04 91.35,38.04 v11(91.23,37.92)
  L6SGND w0.127: v11(91.23,37.92) 91.43,38.12 v4(91.43,38.3)
  L7 w0.061: v2(87.64,41.27) 90.61,38.3 v4(91.43,38.3)
  BOTTOM w0.114: v2(107.22,133.32) 106.89,133.32 105.35,131.77 104.41,131.77 v1(104.1,131.47) 103.21,131.47 102.91,131.77 99.88,131.77 v5(98.67,132.99)
VOLUME_DOWN_EC_OUT: length 8.4
  L2 w0.061: v9(93.24,36.63) 93.58,36.97 93.58,37.2 94.8,38.43 97.44,38.43 97.46,38.41 97.87,38.41 97.98,38.3 98.04,38.3 98.12,38.22 100.31,38.22 v9(100.57,38.48)
VOLUME_DOWN_SOC: length 225.6
  L3SGND w0.127: v11(99.81,39.11) 100.08,39.38 v10(100.57,39.38)
  L5 w0.076: v4(99.43,140.86) 99.44,140.85 99.44,136.81 99.53,136.72 99.53,136.51 99.54,136.5 99.54,136.37 99.54,136.37 99.54,136.05 99.54,135.11 100.07,134.58 100.07,134.49 101.21,133.36 101.21,128.41 100.89,128.09 100.89,111.91 101.27,111.53 101.27,110.26 101.27,110.26 101.27,95.19 100.7,94.62 100.7,91.97 100.7,91.97 100.7,90.87 96.94,87.11 96.94,75.34 96.94,75.34 96.94,74.87 96.94,74.46 94.08,71.61 94.08,61.45 93.99,61.37 93.99,60.89 93.99,60.54 94.12,60.42 94.12,57.05 94.12,55.65 96.67,53.1 96.67,45.5 97,45.17 97,44.17 97.79,43.38 99.34,41.83 99.34,39.81 99.81,39.34 v11(99.81,39.11) ; v8(70.97,169.15) 70.97,169.25 71.13,169.41 71.13,174.23 71.02,174.34 71.02,175.03 70.88,175.17 70.19,175.85 70.19,176.52 70.09,176.62 70.09,176.87 70.05,176.91 70.05,178.01 70.16,178.12 v4(70.16,178.13) ; v4(84.82,180.03) 91.25,186.46 92.1,186.46 95.99,190.34 105.5,190.34 106.72,189.12 106.98,189.12 108.95,187.15 108.95,186.82 109.1,186.67 109.1,183.94 110.27,182.77 110.27,182.14 109.04,180.91 109.04,178.11 109.74,177.41 109.74,153.09 111.59,151.24 111.59,141.38 111.61,141.37 111.61,141.34 111.71,141.24 111.71,141 111.54,140.83 111.53,140.83 v4(111.42,140.71)
  L7 w0.061: v4(99.43,140.86) 99.48,140.81 108.95,140.81 111.32,140.81 v4(111.42,140.71) ; v4(84.82,180.03) 84.8,180.05 84.1,180.05 83.92,180.23 79.14,180.23 79.1,180.19 76.67,180.19 76.2,179.72 74.42,179.72 73.81,180.33 71.81,180.33 70.5,179.02 70.5,178.54 70.16,178.2 v4(70.16,178.13)
VOLUME_UP: length 8
  TOP w0.114: R5404.2 C5402.2 113.75,175.46 112.88,174.59 112.88,173.43 113.4,172.91 VUKEY1.2 ; R5404.2 113.75,178.54 D5401.1 ; R5404.2 TP5402.1
VOLUME_UP_EC_IN: length 177.6
  TOP w0.114: R5404.1 114.72,177.59 v10(114.72,176.37) ; v1(86.73,42.95) 86.73,41.6 86.5,41.37 v9(86.5,41.32) 86.45,41.27 R1720.1
  L2 w0.061: v9(86.5,41.32) 86.5,41.27 86.66,41.11 86.66,40.81 86.93,40.53 86.93,40.52 87.37,40.08 87.72,40.08 87.73,40.08 87.9,39.92 87.9,39.91 89.68,38.12 89.68,37.75 89.89,37.54 89.93,37.54 v10(90.04,37.43)
  L3SGND w0.127: v11(114.95,176.07) 114.92,176.09 114.92,176.17 v10(114.72,176.37) ; v10(90.04,37.43) v11(90.64,37.43)
  L5 w0.076: v11(90.64,37.43) 90.64,37.87 91.07,38.3 92.76,38.3 93.9,39.44 93.9,41.8 93.32,42.38 93.32,52.93 91.63,54.62 91.63,54.62 90.69,55.56 90.69,57.51 90.69,66.78 90.69,66.78 90.69,68.25 90.69,68.25 90.69,71.44 90.69,72.55 90.69,73.1 91.15,73.56 91.15,76.15 94.42,79.43 94.42,79.72 94.42,79.72 94.42,80.83 94.42,80.83 94.42,80.98 94.42,82.09 94.42,82.09 94.42,83.86 94.83,84.27 94.83,87.7 94.86,87.72 94.86,88.86 96.78,90.79 97.39,90.79 98.41,91.81 98.41,95.12 99.36,96.07 99.36,110.03 99.36,110.66 98.92,111.11 98.92,121.57 98.21,122.28 98.21,122.72 98.27,122.79 98.27,123.14 98.3,123.16 98.3,133.55 97.99,133.85 97.99,135.71 97.94,135.76 97.94,135.82 97.94,135.82 97.94,136.35 97.94,136.35 97.94,139.93 97.99,139.98 97.99,140.9 v5(98.26,141.17)
  L6SGND w0.127: v4(114.62,175.89) 114.79,176.07 v11(114.95,176.07)
  L7 w0.061: v5(115.53,142.03) 115.53,142.31 115.42,142.42 115.42,143.58 115.91,144.06 115.91,145.31 114.49,146.73 114.49,151.33 113.75,152.06 113.75,161.13 112,162.89 112,166.44 113.5,167.94 113.5,174.78 114.62,175.9 v4(114.62,175.89)
  BOTTOM w0.114: v5(115.53,142.03) 115.51,142.01 109.49,142.01 108.65,141.17 v5(98.26,141.17)
VOLUME_UP_EC_OUT: length 11.1
  TOP w0.114: v9(101.1,38.48) D1704.K 102.56,38.48 v1(102.58,38.5)
  L2 w0.061: v9(101.1,38.48) 100.97,38.48 100.53,38.04 98.05,38.04 97.97,38.13 97.91,38.13 97.8,38.23 97.39,38.23 97.37,38.25 94.88,38.25 93.76,37.13 93.76,36.35 v9(93.24,35.83)
VOLUME_UP_SOC: length 153.9
  TOP w0.114: v10(101.71,39.38) 102.24,39.38 v1(102.63,39.77)
  L3SGND w0.127: v10(101.71,39.38) v11(101.26,39.38)
  L5 w0.076: v4(96,132.96) 87.1,132.96 84.89,135.18 84.89,136.42 84.89,136.67 84.31,137.24 84.3,137.24 83.46,138.08 83.46,138.09 83.09,138.46 82.95,138.46 82.95,138.46 79.86,138.46 70.8,147.53 70.8,148.34 70.04,149.1 v4(70.04,149.22) ; v11(101.26,39.38) 100.1,39.38 99.98,39.5 99.92,39.5 99.53,39.89 99.53,41.91 97.98,43.46 97.84,43.6 97.84,44.6 96.86,45.58 96.86,53.18 94.31,55.73 94.31,56.04 94.31,56.04 94.31,56.35 94.31,56.97 94.31,56.97 94.31,60.5 94.18,60.62 94.18,60.97 94.18,61.29 94.27,61.38 94.27,71.53 97.13,74.38 97.13,74.79 97.13,87.03 100.89,90.79 100.89,92.05 100.89,94.54 101.46,95.11 101.46,110.18 101.46,110.18 101.46,111.6 101.08,111.99 101.08,128.01 101.4,128.33 101.4,133.46 100.37,134.49 v4(100.37,134.61)
  L7 w0.06: v8(71.54,157.27) 71.74,157.07 71.74,156.62 71.62,156.5 71.62,156.26 71.74,156.14 71.74,155.47 71.3,155.03 71.22,154.95 71.22,152.89
  L7 w0.061: v4(100.37,134.61) 100.27,134.51 99.62,134.51 99.62,134.52 99.24,134.52 98.95,134.23 98.19,134.23 97.75,133.8 97.75,133.8 97.25,133.3 97.25,133.21 96.95,132.91 96.52,132.91 96.47,132.96 v4(96,132.96) ; 71.22,152.89 71.22,152.84 70.74,152.36 70.74,152.16 69.85,151.27 69.85,150.88 68.79,149.82 68.79,149.58 69.13,149.25 70.01,149.25 v4(70.04,149.22)
VOUT_3V3: length 5
  BOTTOM w0.254: U5101.B1 105.85,157.02 PC5104.1 105.83,157.23 106.28,157.68 107.32,157.68 107.43,157.58 v1(107.83,157.58) 107.83,158.14 107.59,158.38 PD5101.2
VPP: length 3.7
  L3SGND w0.254: v10(111.71,94.17) v11(111.11,94.17)
  L6SGND w0.254: v11(111.11,94.17) 110.66,94.17 v5(110.65,94.18)
  BOTTOM w0.254: TP2401.1 108.24,94.18 v5(110.65,94.18)
VREF25: length 3
  TOP w0.254: v10(97.78,171.22) v1(96.89,171.22)
  L3SGND w0.254: v10(97.78,171.22) 97.78,171.6 v11(97.83,171.65)
  L5 w0.203: v11(97.83,171.65) v8(97.83,173.33)
VREF_VTT: length 3.5
  TOP w0.254: v9(88.02,37.87) 88.07,37.82 U1704.B11 ; v9(87.62,39.8) 87.62,40.56 R1758.1
  L2 w0.254: v9(87.62,39.8) 87.62,39.7 88.02,39.29 88.02,38.08 v9(88.02,37.87)
VSET_EC: length 6.5
  TOP w0.114: v1(89.42,42.97) 89.7,42.69 R1754.1 C1717.1 90.4,40.56 90.4,37.87 U1704.E11
VSIM1_PMU_R: length 1.2
  TOP w0.508: v2(112.86,97.51) 112.81,97.45 MSIM1.1
VSYS_SENSE_PMIC: length 4.8
  TOP w0.254: v10(98.54,170.33) 98.54,169.97 98.07,169.51 v1(97.95,169.51)
  L3SGND w0.254: v10(98.54,170.33) 98.55,170.31 v11(99,170.31)
  L6SGND w0.06: v11(99,170.31) 99.25,170.57 99.25,170.91 99.25,170.91 99.25,171.17 99.25,171.17 99.25,172.88 99.03,173.1 v8(99.03,173.33)
WHITE_LED: length 22.7
  TOP w0.114: LED1.2 109.47,1.86 v2(109.08,1.47)
  L5 w0.254: v2(109.08,1.47) 107.05,3.5 107.05,13.1 104.17,15.97 102.53,15.97 v5(102.45,15.9)
  BOTTOM w0.254: C5714.1 102.83,15.9 v5(102.45,15.9) 102.45,15.29 102.14,14.98 101.89,14.98 v1(101.87,14.96) 101.36,15.46 R4903.2
WHITE_LED_EC: length 29
  TOP w0.254: v2(99.58,17.01) 99.58,18.38 v1(99.55,18.41) 99.58,18.44 99.58,18.82 99.5,18.89 99.5,18.89 99.25,19.15 99.05,19.35 v9(99.05,20.26)
  L2 w0.254: v10(87.57,22.91) 90.31,22.91 92.06,21.16 94.64,21.16 94.77,21.03 95.19,21.03 95.32,21.16 98.15,21.16 98.54,20.77 v9(99.05,20.26)
  L3SGND w0.254: v10(87.64,31.83) 87.33,31.83 v11(87.02,31.52) ; v11(86.88,22.88) 86.9,22.91 v10(87.57,22.91)
  L5 w0.254: v11(86.88,22.88) 86.83,22.93 86.83,22.98 85.14,24.67 85.14,30.21 86.45,31.52 v11(87.02,31.52)
  BOTTOM w0.254: v2(99.58,17.01) 99.88,17.32 U4901.5
WHITE_LED_R: length 5.4
  BOTTOM w0.254: U4901.3 98.85,17.97 99.07,17.74 99.07,16.05 v1(98.49,15.46) 98.61,15.34 100.44,15.34 R4903.1
WIFI_HOST_WAKE#: length 144.5
  L5 w0.06: v8(79.74,158.68) 82.85,155.58 82.85,154.63 84.79,152.69 84.87,152.69
  L5 w0.076: v4(91.02,135.33) 91.02,136.95 89.62,138.34 89.62,139.71 87.27,142.06 87.27,142.38 87.27,142.38 87.27,148.43 87.2,148.51 87.2,149.07 87.27,149.14 87.27,151.94 86.78,152.43 86.06,152.43 85.81,152.69 84.87,152.69
  L7 w0.061: v4(91.02,135.33) 91.56,135.33 91.71,135.48 95.55,135.48 96.67,136.6 98.78,136.6 99.37,136.01 99.37,135.69 99.54,135.53 99.64,135.43 103.41,135.43 105.04,133.8 105.04,132.39 106.09,131.33 106.09,124.03 v5(104.49,122.44) 102.68,120.62 102.68,93.51 101.89,92.73 101.79,92.62 101.59,92.42 101.38,92.21 101.38,92.16 101.25,92.03 101.25,90.53 98.98,88.26 98.98,85.24 99.13,85.09 99.13,79.49 99.13,79.49 99.13,74.26 99.13,74.26 99.13,73.09 99.13,73.09 99.13,72.95 99.13,72.21 99.02,72.1 99.01,72.1 96.63,69.72 96.31,69.72 95.7,69.11 95.59,69 95.59,66.09 95.95,65.73 95.95,58.97 95.53,58.55 95.53,55.46 97.65,53.35 97.65,46.31 97.44,46.11 97.09,45.75 97.09,43.1 98.13,42.06 v5(98.13,41.75)
  BOTTOM w0.114: WR3708.2 98.16,41.73 v5(98.13,41.75)
WIFI_PCIE_RXN0: length 1.1
  BOTTOM w0.102: WU3701.36 101.58,41.12 WR3713.1
WIFI_PCIE_RXP0: length 1.1
  BOTTOM w0.102: WU3701.37 102.08,41.13 WR3712.1
WIFI_PCIE_TXN0: length 1.1
  BOTTOM w0.102: WU3701.39 103.08,40.7 102.96,40.82 WC3713.2
WIFI_PCIE_TXP0: length 1.1
  BOTTOM w0.102: WU3701.40 103.58,40.62 103.47,40.74 WC3714.2
WIFI_PERST#: length 1.4
  BOTTOM w0.114: WR3711.1 99.08,40.47 WU3701.31
WL_DEV_EN: length 143.9
  L5 w0.076: v4(98.61,134.54) 99.3,133.85 99.3,128.25 99.73,127.82 99.73,111.45 100.13,111.05 100.13,110.74 100.13,95.67 99.55,95.1 99.55,91.5 99.55,91.35 95.59,87.38 95.59,83.95 95.19,83.55 95.19,81.77 95.18,81.77 95.18,81.3 95.18,81.14 95.19,81.14 95.19,79.4 95.18,79.4 95.18,78.93 95.18,78.77 95.19,78.77 95.19,76.5 94.18,75.5 94.18,74.28 92.35,72.46 92.35,68.86 91.84,68.35 91.84,67.88 91.84,67.56 91.85,67.56 91.85,56.91 91.84,56.91 91.84,56.39 91.84,55.76 92.58,55.02 92.58,55.01 94.27,53.32 94.27,52.54 94.27,52.38 94.27,52.38 94.27,50.27 94.73,49.82 94.73,49.41 94.73,48.99 94.73,43.3 95.29,42.74 95.29,41.12 v5(97.21,39.21) ; v4(76.19,148.74) 77.28,147.65 77.28,145.75 79.75,143.28 82.02,143.28 82.35,142.95 82.35,142.77 83.05,142.06 83.57,142.06 83.72,141.9 84.1,141.9 84.45,141.55 84.45,140.74 84.62,140.57 84.89,140.57 86.6,138.86 86.6,137.48 90.47,133.61 94.95,133.61 95.17,133.83 v4(95.31,133.83)
  L7 w0.06: 75.47,154.39 75.47,154.39 75.47,155.69 75.58,155.8 75.58,156.07 75.78,156.28 v8(75.78,156.42)
  L7 w0.061: v4(95.31,133.83) 95.46,133.97 97.68,133.97 98.11,134.41 98.32,134.41 98.46,134.54 v4(98.61,134.54) ; 75.47,154.39 75.47,153.91 75.98,153.4 75.98,148.94 v4(76.19,148.74)
  BOTTOM w0.114: v5(97.21,39.21) 96.37,39.21 96.13,38.96 v1(96.13,37.54)
WWAN_DETECT#: length 63.2
  L5 w0.076: v4(52.59,144.65) 51.73,144.65 51.57,144.8 46.65,144.8 44.13,147.31 36.59,147.31 35.99,146.72 35.74,146.72 30.72,141.7 v4(30.72,141.37) ; v8(71.82,156.42) 72.25,155.99 72.25,152.73 72.07,152.55 72.07,152.17 71.26,151.35 v5(71.18,151.35) 70.85,151.35 69.66,150.16 69.46,150.16 66.64,147.34 66.25,147.34 65.01,146.1 v4(64.91,146.1)
  L7 w0.061: v4(30.72,141.37) 30.44,141.09 23.18,141.09 22.49,141.78 v5(21.07,141.78) ; v4(64.91,146.1) 63.61,144.8 v5(63.61,144.62) 63.25,144.26 57.27,144.26 56.88,144.65 v4(52.59,144.65)
WWAN_DETECT#_L: length 6.2
  L7 w0.061: v5(20.56,142.34) 20.56,143.12 20.27,143.41 NGFF1.51
  BOTTOM w0.114: v1(22.08,141.8) 21.7,141.8 21.17,142.34 R4013.2 v5(20.56,142.34)
WWAN_WAKE#: length 87.5
  L5 w0.076: v4(81.52,154.66) 81.52,154.73 78.9,157.36 v8(78.9,158.4) ; v4(82.49,149.52) 82.49,148.41 v4(80.12,146.04)
  L7 w0.061: v5(13.32,140.81) 13.8,140.81 15.58,139.03 18.17,139.03 19.42,137.79 27.95,137.79 28.56,138.4 41.01,138.4 v5(41.36,138.76) ; v5(43.93,141.3) 44.32,140.9 55.19,140.9 55.33,141.04 57.45,141.04 58.44,142.04 63.43,142.04 63.44,142.04 63.82,142.04 63.83,142.04 63.93,142.04 63.94,142.04 64.32,142.04 64.32,142.04 65.96,142.04 66.28,142.35 66.41,142.35 66.45,142.39 68.3,142.39 68.48,142.22 69.72,142.22 70.88,143.38 75.1,143.38 77.03,145.31 79.31,145.31 80.05,146.04 v4(80.12,146.04) ; v4(82.49,149.52) 82.49,149.86 81.55,150.79 81.55,152.53 81.43,152.65 81.43,153.06 81.52,153.15 v4(81.52,154.66)
  BOTTOM w0.114: v5(43.93,141.3) 43.93,141.02 v1(43.26,140.34) 41.67,138.76 v5(41.36,138.76) ; R4008.1 v5(13.32,140.81)
WWAN_WAKE_HOST#: length 6.2
  BOTTOM w0.114: R4008.2 13.09,142.06 12.76,142.06 v1(12.38,142.44) 12.38,145.03 12.23,145.18 12.23,146.12 12.55,146.44 13.01,146.44 NGFF1.23
XDP_H_PRDY#: length 84.4
  L5 w0.076: v4(74.27,176.16) 73.8,176.63 73.8,176.68 73.49,176.98 73.49,178.14 73.38,178.26 73.38,178.5 73.53,178.65 73.53,179.54 72.57,180.5 70.51,180.5 70.46,180.45 69.99,180.45 69.99,180.45 69.02,180.45 68.93,180.54 67.62,180.54 67.46,180.54 67.31,180.54 67.15,180.54 66.97,180.72 49.51,180.72 45.52,176.73 45.52,168.88 45.52,168.73 44.27,167.48 44.27,165.92 44.27,165.92 44.27,165.77 44.27,165.77 44.27,164.67 44.27,164.67 44.27,163.96 44.6,163.63 44.6,162.97 43.81,162.18 43.81,158.91 v5(44.11,158.62)
  L7 w0.06: v8(72.95,170) 73.07,170 73.1,170.04 73.27,170.04 73.44,170.2 73.44,170.37 73.04,170.76 73.04,171.01 73.12,171.09 73.12,171.34 73.07,171.39 73.07,171.56 73.28,171.76 73.28,172.44 73.49,172.65
  L7 w0.061: v4(74.27,176.16) 74.26,176.14 74.26,175.83 74.16,175.74 74.16,175.74 74.1,175.68 74.1,175.55 74.1,175.55 74.1,174.67 73.49,174.06 73.49,172.65
  BOTTOM w0.114: v5(44.11,158.62) 44.45,158.27 44.45,158.1 45.5,157.05 45.5,156.83 45.5,145.63 46.26,144.88 46.68,144.88 47.26,144.3 47.26,144.27 v1(48.55,142.97) 49.39,142.13 51.69,142.13 52.73,141.09 XDP1.8
XDP_H_PREQ#: length 84.7
  L5 w0.076: v5(43.98,158.14) 43.76,158.35 43.76,158.35 43.62,158.49 43.62,163.82 44.08,164.28 44.08,164.59 44.08,167.56 45.33,168.8 45.33,176.81 49.43,180.91 67.05,180.91 67.23,180.73 67.38,180.73 67.39,180.73 67.54,180.73 69.01,180.73 69.1,180.64 70.06,180.64 70.38,180.64 70.43,180.69 72.65,180.69 73.72,179.62 73.72,178.57 73.67,178.52 v5(73.67,178.38) 73.67,178.24 73.68,178.22 73.68,177.06 74.1,176.64 74.15,176.64 74.31,176.49 74.4,176.49 74.57,176.32 74.57,176.07 74.56,176.06 74.56,176.03 74.55,176.02 74.15,175.63 74.15,175.57 73.93,175.35 73.93,174.96 73.93,174.84 73.93,174.5 73.93,174.49 73.5,174.07 73.5,174.06 73.18,173.74 73.18,170.22 v8(72.67,169.72)
  BOTTOM w0.114: XDP1.6 52.33,141.17 51.6,141.9 49.08,141.9 46.6,144.39 v1(46.6,144.45) 46.36,144.45 45.27,145.54 45.27,146.34 45.27,156.36 45.27,156.85 43.99,158.14 v5(43.98,158.14)
XDP_H_TCK: length 79.2
  L2 w0.061: v10(71.21,179.52) 70.97,179.52 70.26,178.81 68.81,178.81 68.48,178.49 68.28,178.28 65.63,178.28 64.74,179.17 64.74,179.17 64.62,179.29 56.68,179.29 56.1,179.29 54.9,179.29 50.7,179.29 50.41,179.29 48.35,177.24 48.31,177.24 48.23,177.16 48.2,177.16 47.26,176.22 46.8,176.22 46.61,176.03 v10(46.54,176.03)
  L3SGND w0.127: v10(46.54,176.03) 46.89,176.03 v11(46.9,176.02) ; v11(71.61,179.22) 71.51,179.22 v10(71.21,179.52)
  L5 w0.06: v8(72.67,170.28) 72.67,173.66 73.57,174.57 73.57,174.62 73.57,174.88 73.57,174.96 73.57,175.5 v5(73.01,176.07)
  L5 w0.076: v11(46.9,176.02) 46.49,176.02 46.19,175.72 46.19,168.59 44.88,167.28 44.88,164.16 45.17,163.87 45.17,162.74 44.56,162.13 44.56,160.68 44.64,160.6 44.69,160.6 45.07,160.22 45.07,159.71 44.89,159.53 44.89,159.41 v5(44.92,159.38) ; v11(71.61,179.22) 72.08,179.69 72.52,179.69 72.76,179.45 72.76,178.14 72.78,178.12 72.78,177.64 72.91,177.51 72.91,176.3 73.01,176.19 v5(73.01,176.07)
  BOTTOM w0.114: v5(44.92,159.38) 45.38,158.92 45.38,158.29 45.94,157.72 45.94,157.72 46.19,157.48 46.19,157.12 46.19,155.78 46.19,155.78 46.19,145.92 46.3,145.81 46.39,145.72 47.63,145.72 48.63,144.72 49.19,144.72 49.41,144.5 v1(51.52,144.5) 51.6,144.5 52.33,143.76 XDP1.5
XDP_H_TDI: length 81
  L2 w0.061: v10(45.63,176.93) 48.35,179.64 50.27,179.64 54.76,179.64 54.76,179.64 55.96,179.64 56.83,179.64 64.62,179.64 64.76,179.64 64.79,179.62 65.09,179.32 65.55,178.86 66.46,178.86 66.61,178.71 68.21,178.71 69.12,179.62 v10(69.79,179.62)
  L3SGND w0.127: v11(69.76,179.98) 69.76,179.75 69.79,179.73 v10(69.79,179.62) ; v10(45.63,176.93) 45.88,176.68 45.88,176.55 v11(45.91,176.52)
  L5 w0.06: v5(73.24,179.42) 73.24,178.62 73.2,178.58 73.2,177.75 73.31,177.63 73.31,176.91 73.62,176.6 73.62,176.37 73.8,176.19 73.8,175.95 73.75,175.9 73.75,174.96 73.75,174.67 73.75,174.53 72.95,173.73 v8(72.95,170.57)
  L5 w0.076: v11(45.91,176.52) 45.81,176.42 45.81,168.75 44.46,167.4 44.46,166 44.46,164.75 44.46,164.59 44.46,164.04 44.79,163.71 44.79,162.9 44.04,162.15 44.04,159.3 v5(44.81,158.53) ; v5(73.24,179.42) 73.24,179.51 72.44,180.31 70.68,180.31 70.35,179.98 v11(69.76,179.98)
  BOTTOM w0.114: v5(73.24,179.42) 73.06,179.42 72.75,179.73 72.57,179.73 R736.2 ; XDP1.1 51.53,143.52 51.14,143.91 48.4,143.91 v1(47.81,144.5) 47.2,145.11 46.35,145.11 45.73,145.73 45.73,155.97 45.73,157.17 44.8,158.1 44.8,158.53 v5(44.81,158.53)
XDP_H_TDO: length 86.6
  L5 w0.06: v8(72.95,169.43) 72.95,169.82 73.3,170.17 73.3,173.68 73.63,174.01 73.63,174.01 74.11,174.49 74.11,174.75 74.11,174.9 74.14,174.92 74.14,175.29 74.34,175.5 74.34,175.55 74.68,175.9 74.74,175.96 74.74,175.98 74.76,176 74.76,176.39 74.48,176.67 74.38,176.67 74.23,176.83 74.18,176.83 73.92,177.08 73.92,177.66 v5(74.09,177.83)
  L5 w0.076: v5(43.82,157.34) 43.82,157.38 43.71,157.49 43.71,157.72 43.23,158.2 43.23,158.47 43.24,158.48 43.24,163.97 43.7,164.43 43.7,167.72 44.94,168.96 44.94,176.96 49.27,181.29 67.2,181.29 67.38,181.11 69.17,181.11 69.26,181.02 70.22,181.02 70.27,181.07 72.81,181.07 74.4,179.49 74.4,178.11 74.22,177.93 74.19,177.93 v5(74.09,177.83)
  BOTTOM w0.114: v5(74.09,177.83) 74.08,177.85 73.95,177.85 R740.2 ; XDP1.2 51.53,140.79 51,141.32 48.48,141.32 45.15,144.65 v1(45.15,144.67) 45.13,144.67 44.81,144.99 44.81,145.39 44.81,156.35 v5(43.82,157.34)
XDP_H_TMS: length 77.9
  L2 w0.061: v10(71.39,179.9) 71.11,179.9 70.19,178.99 68.74,178.99 68.21,178.46 65.7,178.46 64.92,179.24 64.69,179.47 56.76,179.47 56.76,179.47 56.03,179.47 56.03,179.47 54.83,179.47 54.83,179.47 50.77,179.47 50.34,179.47 50.23,179.36 49.38,179.36 46.92,176.91 v10(46.42,176.91)
  L3SGND w0.127: v11(71.74,179.9) v10(71.39,179.9) ; v10(46.42,176.91) 46.42,176.65 v11(46.54,176.52)
  L5 w0.076: v5(73.52,176.07) 73.52,176.08 73.1,176.51 73.1,177.59 73.01,177.67 73.01,179.23 72.95,179.3 72.95,179.53 72.58,179.9 v11(71.74,179.9) ; v5(44.84,158.97) 44.63,159.19 44.63,159.54 44.88,159.79 44.88,160.14 44.61,160.41 44.56,160.41 44.37,160.6 44.37,162.21 44.98,162.82 44.98,163.79 44.69,164.08 44.69,167.36 46,168.67 46,175.9 46.54,176.45 v11(46.54,176.52)
  L7 w0.061: v8(72.63,171.46) 72.63,172.16 72.87,172.4 72.87,174.18 73.57,174.89 73.57,175.32 73.57,175.32 73.57,176.02 v5(73.52,176.07)
  BOTTOM w0.114: XDP1.3 51.93,143.6 51.4,144.14 49.24,144.14 v1(49.03,144.34) 48.53,144.34 47.51,145.36 46.42,145.36 45.96,145.82 45.96,155.88 45.96,157.27 45.72,157.51 45.12,158.1 45.12,158.69 v5(44.84,158.97)
XDP_H_TRST#: length 84.3
  L5 w0.076: v4(74.1,178.23) 74.1,179.51 72.73,180.88 70.35,180.88 70.3,180.83 69.18,180.83 69.09,180.92 67.46,180.92 67.31,180.92 67.13,181.1 49.35,181.1 45.13,176.89 45.13,169.04 45.13,169.04 45.13,168.88 43.89,167.64 43.89,164.51 43.89,164.36 43.43,163.9 43.43,158.4 43.42,158.39 43.42,158.28 44,157.7 v5(44,157.68)
  L7 w0.06: v8(72.39,170.57) 72.47,170.65 72.47,170.93 72.59,171.05 72.59,171.21 72.42,171.38 72.4,171.38
  L7 w0.061: 72.4,171.38 72.4,172.1 72.69,172.39 72.69,174.5 72.38,174.81 v5(72.38,176.07) 72.38,176.22 73.81,177.66 73.81,177.95 74.08,178.23 v4(74.1,178.23)
  BOTTOM w0.114: v5(44,157.68) 45.04,156.64 45.04,146.44 45.04,145.44 47.15,143.33 v1(47.15,143.3) 48.78,141.68 51.5,141.68 51.93,141.24 XDP1.4
XTAL19_2_IN: length 7.7
  L5 w0.076: v5(83.04,161.62) 82.85,161.62 82.65,161.81 82.53,161.81 82.3,162.05 80.39,162.05 79.57,161.23 v8(79.46,161.23)
  BOTTOM w0.114: v5(83.04,161.62) 82.97,161.69 C701.2 83.33,162.43 83.33,162.71 83.48,162.86 84.64,162.86 85.17,162.34 X701.1
XTAL19_2_OUT: length 6.1
  L5 w0.076: v8(79.18,160.94) 79.51,160.94 80.47,161.91 82.24,161.91 v5(82.56,161.59)
  BOTTOM w0.114: X701.3 83.45,160.35 83.2,160.6 C702.2 R716.2 82.56,161.54 v5(82.56,161.59)

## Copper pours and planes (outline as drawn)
5V_LX on TOP: 95.13,145.49 94.93,145.69 93.23,145.69 93.23,146.02 93.33,146.12 94.6,146.12 94.86,146.38 94.86,146.76 94.98,146.88 94.98,148.41 95.24,148.66 96.89,148.66 97.01,148.53 97.01,145.87 96.63,145.49
+AVDD_CAM_FRONT on TOP: 95.49,187.24 95.41,187.32 94.98,187.32 94.8,187.5 93.69,187.5 93.46,187.27 90.41,187.27 90.28,187.4 90.28,188.03 90.92,188.67 96.13,188.67 96.38,188.41 97.4,188.41 97.4,187.24 ; 4 cut-outs
+AVDD_CAM_REAR on BOTTOM: 73.04,185.85 72.88,186 72.88,187.17 72.93,187.22 73.29,187.22 73.6,187.52 74,187.52 74.13,187.4 74.13,186.89 74.2,186.81 74.74,186.81 74.84,186.71 74.84,186.2 74.76,186.13 74.26,186.13 73.98,185.85 ; 1 cut-out
+V1P2_FRONT on TOP: 99.78,190.14 99.78,190.52 99.68,190.62 99.68,192.86 99.94,193.11 104.2,193.11 104.58,193.49 107.05,193.49 107.22,193.31 107.22,192.15 106.79,191.71 100.6,191.71 100.24,191.36 100.24,190.62 100.09,190.47 100.09,190.14 ; 4 cut-outs
+V1P2_REAR on BOTTOM: 78.09,186.13 77.96,186.25 77.96,187.02 78.09,187.14 78.47,187.14 78.47,187.52 78.6,187.65 78.98,187.65 79.11,187.52 79.11,186.76 79.23,186.76 79.23,187.14 79.74,187.14 79.87,187.02 79.87,186.25 79.74,186.13
+V1P2A on TOP: 78.6,170.63 78.47,170.76 78.47,172.92 79.23,173.68 83.04,173.68 86.85,177.49 89.39,177.49 89.65,177.24 92.09,177.24 92.47,177.62 93.71,177.62 97.4,181.3 99.05,181.3 99.3,181.05 99.3,180.41 98.92,180.03 97.65,180.03 96.51,178.89 96.51,177.36 95.87,176.73 94.58,176.73 90.89,173.05 87.9,173.05 86.24,174.7 85.97,174.7 81.9,170.63 ; 5 cut-outs
+V1P2A on BOTTOM: 78.8,171.22 78.42,171.6 78.42,172.74 78.57,172.89 78.9,172.89 79.03,173.02 79.03,173.3 79.13,173.4 79.54,173.4 79.82,173.12 79.82,172.26 79.36,171.8 79.36,171.6 78.98,171.22 ; 1 cut-out
+V1P2A on BOTTOM: 81.04,165.61 80.94,165.71 80.94,165.81 81.44,166.32 83.5,166.32 83.58,166.24 83.58,165.99 83.53,165.94 81.62,165.94 81.29,165.61
+V1P05A on TOP: 78.73,152.85 78.6,152.98 78.6,153.74 78.98,154.12 81.9,154.12 82.16,153.87 82.16,153.23 81.77,152.85
+V1P05A on TOP: 88.25,158.57 88.12,158.69 88.12,159.71 88.38,159.96 94.22,159.96 95.62,161.36 95.62,161.87 95.49,162 95.49,164.03 95.24,164.28 94.47,164.28 88.51,170.25 88.51,171.52 88.63,171.65 90.54,171.65 90.92,171.27 90.92,170.51 97.01,164.41 97.01,163.39 97.27,163.14 97.27,160.6 95.24,158.57 ; 4 cut-outs
+V1P05A on TOP: 81.9,158.95 81.77,159.08 81.77,159.46 82.41,160.09 82.41,163.52 81.82,164.1 81.82,164.61 82.1,164.89 82.84,164.89 83.55,164.18 83.55,159.58 83.02,159.05 82.33,159.05 82.23,158.95 ; 4 cut-outs
+V1P05A on BOTTOM: 88.99,168.5 88.68,168.8 88.68,170.12 88.53,170.28 88.53,173.68 88.66,173.81 90.41,173.81 90.49,173.73 90.49,169.29 90.41,169.21 90.11,169.21 89.8,168.9 89.8,168.63 89.67,168.5 ; 5 cut-outs
+V1P05A on BOTTOM: 76.62,160.68 76.24,161.06 76.24,161.7 76.59,162.05 77.25,162.05 77.41,161.9 77.41,160.81 77.28,160.68
+V1P05A on BOTTOM: 81.37,163.58 81.32,163.63 81.32,163.91 81.39,163.98 81.39,164.16 81.29,164.26 81.29,164.97 81.38,165.06 81.41,165.06 81.57,165.22 84.52,165.22 85.08,164.66 85.08,164.41 84.97,164.31 83.73,164.31 83.63,164.21 83.63,163.88 83.58,163.82 82.51,163.82 82.26,163.58 ; 5 cut-outs
+V1P05A on BOTTOM: 81.9,158.97 81.87,159 81.37,159 80.96,159.41 80.96,159.64 81.04,159.71 81.24,159.71 81.45,159.51 82.18,159.51 82.33,159.35 82.33,159.08 82.23,158.97
+V1P05A on BOTTOM: 70.9,171.22 70.65,171.47 70.65,171.6 70.6,171.65 70.27,171.65 70.19,171.58 70.01,171.58 69.96,171.63 69.96,171.91 69.73,172.14 69.73,173.71 70.09,174.07 70.95,174.07 70.98,174.04 70.98,171.65 71.13,171.5 71.13,171.27 71.08,171.22 ; 3 cut-outs
+V1P05A on BOTTOM: 70.73,152.6 69.71,153.61 69.71,155.65 69.96,155.9 70.47,155.9 70.85,156.28 71.11,156.28 71.23,156.15 71.23,155.9 70.98,155.65 70.98,155.14 71.11,155.01 71.11,154 71.23,153.87 71.87,153.87 72,153.74 72,152.73 71.87,152.6 ; 3 cut-outs
+V1P05A on L2: 71.87,153.87 70.85,153.87 67.93,156.79 67.93,165.55 68.69,166.31 68.69,172.41 67.42,173.68 66.92,173.68 66.66,173.43 66.66,167.84 66.28,167.46 66.28,155.9 70.09,152.09 79.74,152.09 80.25,152.6 80.25,153.11 80,153.36 72.38,153.36
+V1P05A on L2: 78.98,164.92 77.2,163.14 75.78,163.14 75.65,163.27 75.65,164.23 75.04,164.84 74,164.84 73.9,164.74 73.9,164.18 73.91,164.17 73.91,163.61 75.14,162.38 75.14,162.12 76.03,161.23 78.47,161.23 78.98,161.74 80,161.74 81.9,163.65 82.54,163.65 84.31,165.43 85.58,165.43 89.39,169.24 89.39,171.39 89.01,171.78 88.63,171.78 88.51,171.9 86.35,171.9 82.41,167.97 81.65,167.97 78.98,165.3
+V1P05A on L3SGND: 77.07,162.08 77.28,161.87 77.28,161.28 77.18,161.18 75.81,161.18 75.73,161.26 75.73,161.95 75.86,162.08
+V1P05A on L3SGND: 75.04,164.49 74.03,164.49 73.9,164.62 73.9,165.23 74.03,165.35 74.76,165.35 75.14,164.97 75.14,164.59
+V1P05A on L6SGND: 75.09,164.59 74.28,164.59 73.8,165.07 73.6,165.07 73.52,165.15 73.52,165.25 73.62,165.35 74.76,165.35 75.17,164.95 75.17,164.67
+V1P05A on L6SGND: 77.28,160.78 76.62,160.78 76.44,160.96 76.44,161.16 76.29,161.31 76.29,161.64 76.62,161.98 76.82,161.98 77.3,161.49 77.3,161.06 77.38,160.98 77.38,160.88
+V1P05A_PCIE_STAT on BOTTOM: 81.42,161.34 81.32,161.44 81.32,162.38 81.32,162.38 81.32,162.56 81.32,162.56 81.32,163.35 81.37,163.4 81.62,163.4 81.62,163.4 82.03,163.4 82.03,163.39 82.36,163.39 82.61,163.65 84.11,163.65 84.16,163.6 84.16,163.04 84.11,162.99 83.73,162.99 83.73,162.94 83.63,162.84 82.92,162.84 82.69,162.61 82.69,161.92 82.1,161.34
+V1P8_REAR on BOTTOM: 77.2,184.98 77.08,185.11 76.19,185.11 76.06,185.24 76.06,187.42 75.55,187.93 75.55,188.29 75.68,188.41 76.06,188.41 76.97,187.5 77.13,187.5 77.33,187.29 77.33,187.02 77.58,186.76 77.58,185.11 77.46,184.98 ; 6 cut-outs
+V1P8A on TOP: 109.97,176.86 109.76,177.06 109.76,178.73 110.04,179.01 110.1,179.01 110.22,179.14 110.98,179.14 111.24,178.89 111.24,178.38 111.19,178.33 111.19,177.19 110.86,176.86 ; 3 cut-outs
+V1P8A on TOP: 33.26,144.6 32.88,144.98 32.88,145.49 33.26,145.87 68.95,145.87 73.27,150.19 73.27,154 73.14,154.12 73.14,156.54 72.76,156.92 72.76,159.46 73.01,159.71 73.65,159.71 73.77,159.58 73.77,159.33 73.9,159.2 74.15,159.2 74.28,159.08 74.28,157.68 74.79,157.17 74.79,152.98 75.55,152.22 75.55,151.33 77.33,149.55 82.79,149.55 88.38,155.14 101.71,155.14 102.48,154.38 102.48,152.85 100.95,151.33 93.33,151.33 92.95,150.95 91.05,150.95 84.7,144.6 ; 4 cut-outs
+V1P8A on BOTTOM: 80.76,174.32 80.63,174.44 80.63,177.62 80.89,177.87 81.77,177.87 81.9,177.74 81.9,174.57 81.77,174.44 81.27,174.44 81.14,174.32 ; 4 cut-outs
+V1P8A on BOTTOM: 90.54,54.94 90.28,55.19 90.28,55.32 89.65,55.32 89.52,55.44 89.01,55.44 88.89,55.32 88.25,55.32 88.25,55.95 88.51,56.21 90.54,56.21 91.05,55.7 91.05,55.19 90.79,54.94 ; 2 cut-outs
+V1P8A on BOTTOM: 62.72,146.76 62.22,147.26 62.22,149.68 62.34,149.8 68.31,149.8 68.69,149.42 72.88,149.42 73.01,149.55 73.01,154.5 72.76,154.76 72.76,155.9 73.14,156.28 73.39,156.28 73.77,155.9 73.9,155.9 74.28,156.28 74.41,156.28 74.79,155.9 75.04,155.9 75.42,156.28 75.55,156.28 75.93,155.9 75.93,154.25 75.68,154 75.68,149.68 76.19,149.17 76.95,149.17 77.2,148.92 77.2,148.03 75.93,146.76 ; 27 cut-outs
+V1P8A on BOTTOM: 106.11,176.98 105.98,177.11 105.98,178.89 106.11,179.01 110.81,179.01 110.83,179.04 110.86,179.01 111.24,179.01 111.62,178.63 111.62,177.54 111.59,177.54 111.44,177.39 111.44,177.11 111.31,176.98 ; 7 cut-outs
+V1P8A on L2: 111.11,179.01 108.06,179.01 107.94,178.89 107.68,178.89 103.87,175.08 103.87,157.81 100.82,154.76 100.82,152.34 100.95,152.22 104.51,152.22 107.43,155.14 107.43,169.87 106.79,170.51 106.79,171.52 107.43,172.16 107.43,173.17 111.49,177.24 111.49,178.63
+V1P8A on L2: 35.9,144.75 36.46,144.75 36.82,145.11 36.82,165.35 38.14,166.67 38.21,166.67 38.21,166.7 39.48,167.97 39.48,168.22 39.31,168.4 37.91,168.4 35.7,166.19 35.7,144.95
+V1P8A_EMMC_VCCQ on BOTTOM: 94.22,155.52 94.09,155.65 94.09,156.54 93.59,157.04 93.59,159.33 92.82,160.09 92.82,160.85 92.95,160.98 93.2,160.98 93.59,161.36 94.45,161.36 94.93,161.84 94.93,162.22 95.03,162.33 95.49,162.33 95.59,162.22 95.59,161.59 95.24,161.23 95.24,157.55 95.11,157.42 95.11,156.92 94.6,156.41 94.6,155.65 94.47,155.52 ; 2 cut-outs
+V1P8A_MEM on BOTTOM: 49.72,157.09 49.14,157.68 49.14,160.85 49.21,160.93 50.07,160.93 50.2,160.8 50.2,158.24 50.33,158.11 50.61,158.11 50.66,158.06 50.66,157.14 50.61,157.09 ; 1 cut-out
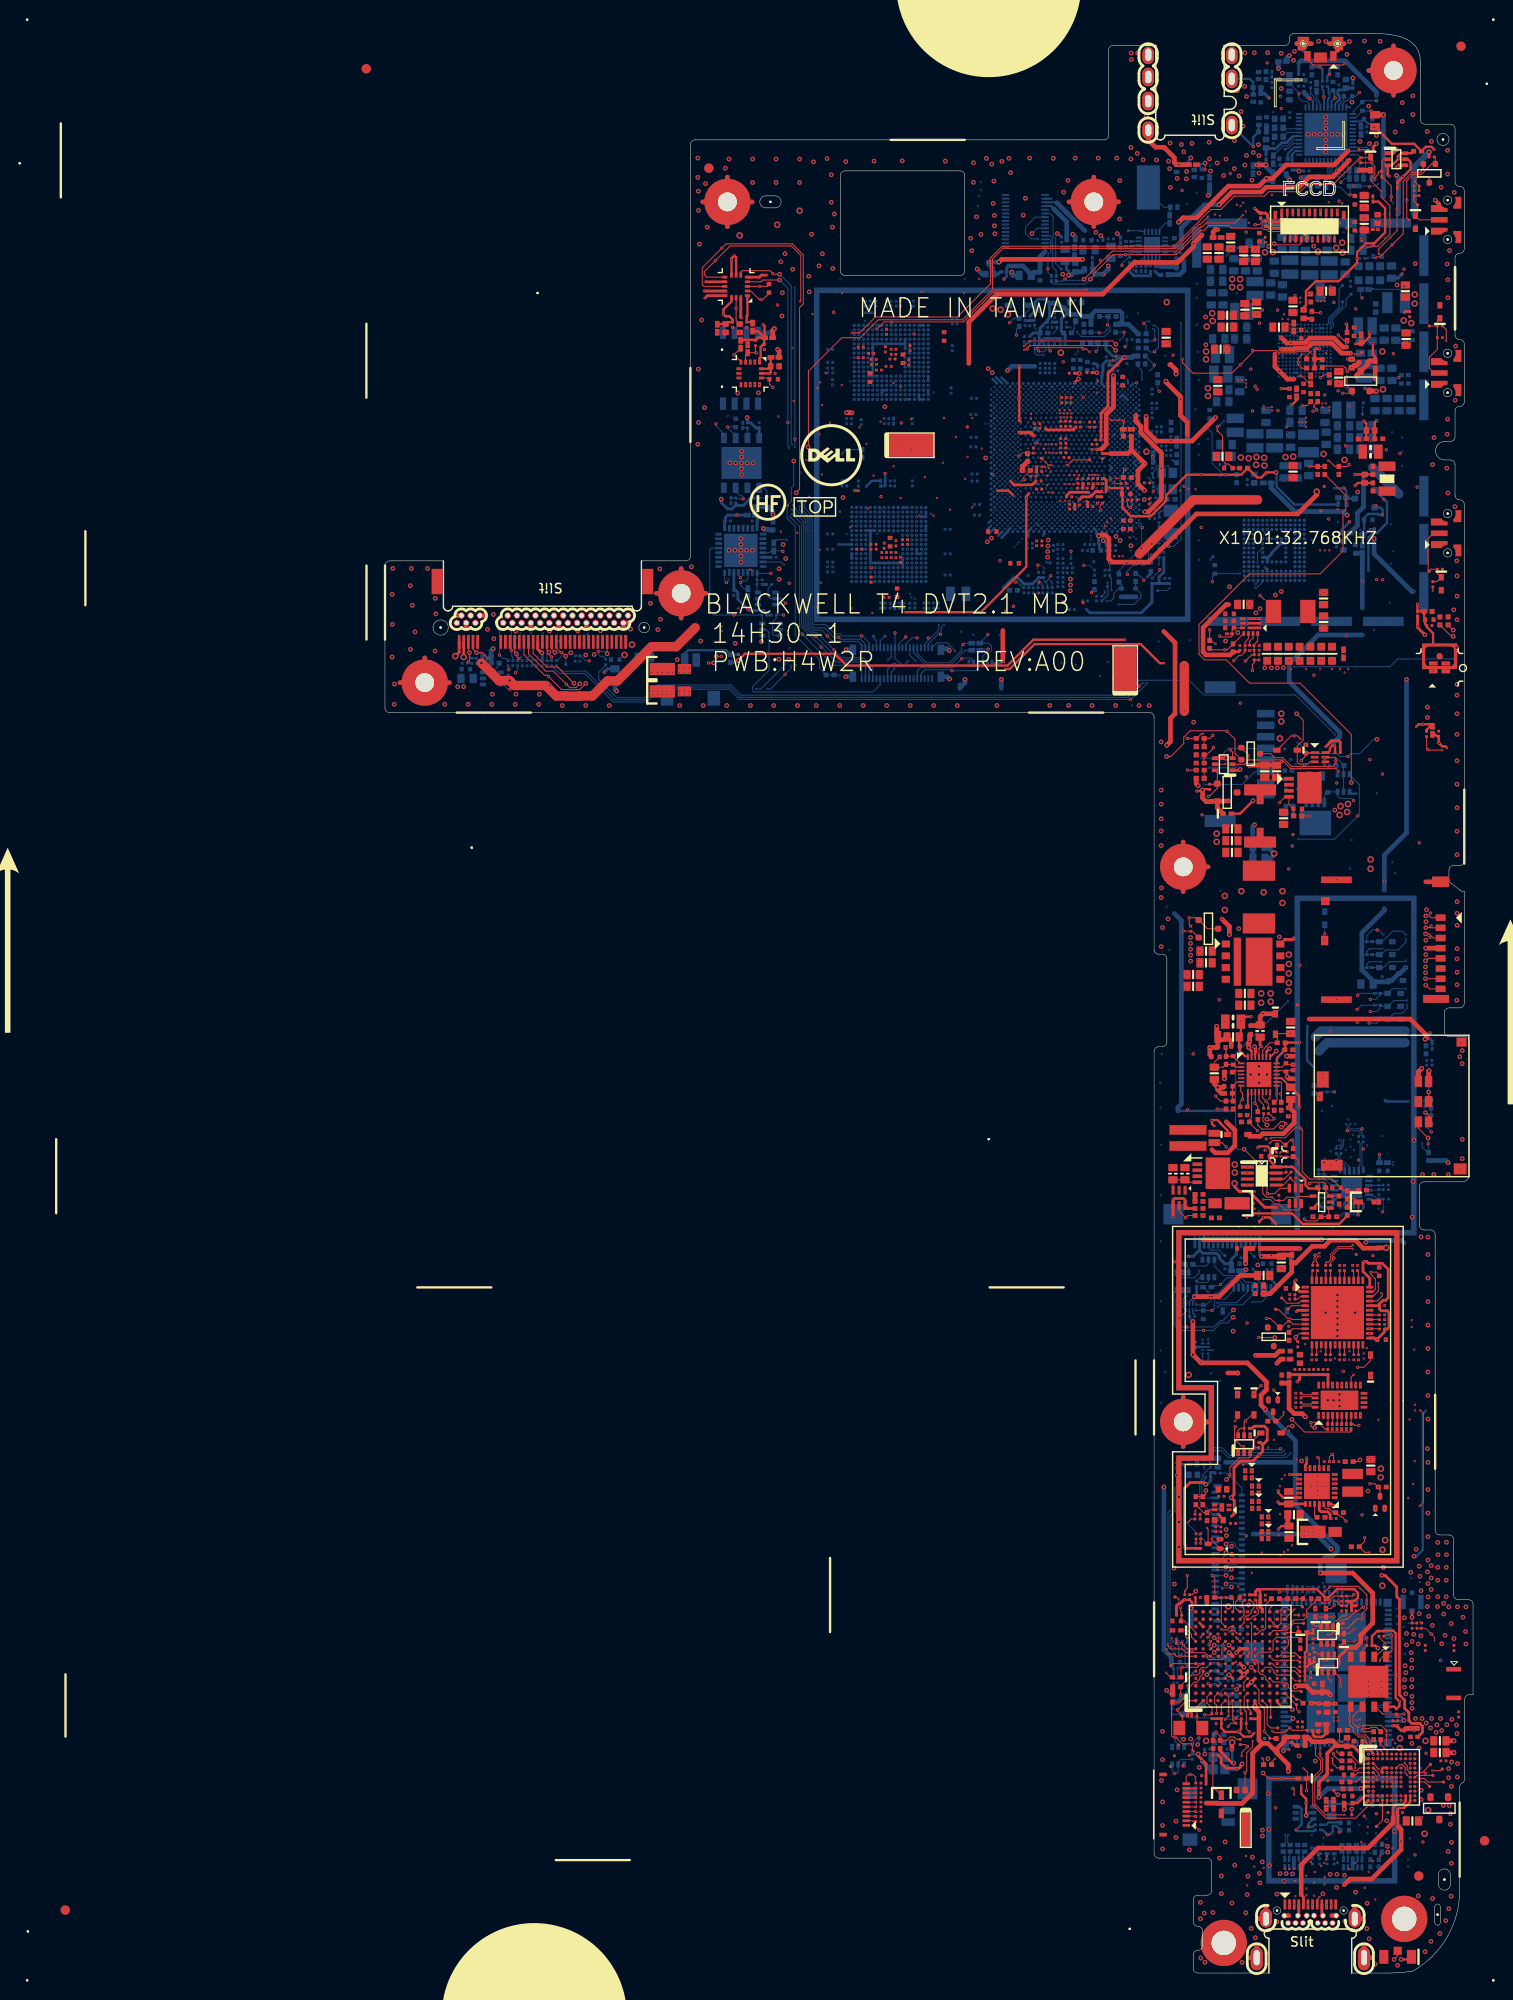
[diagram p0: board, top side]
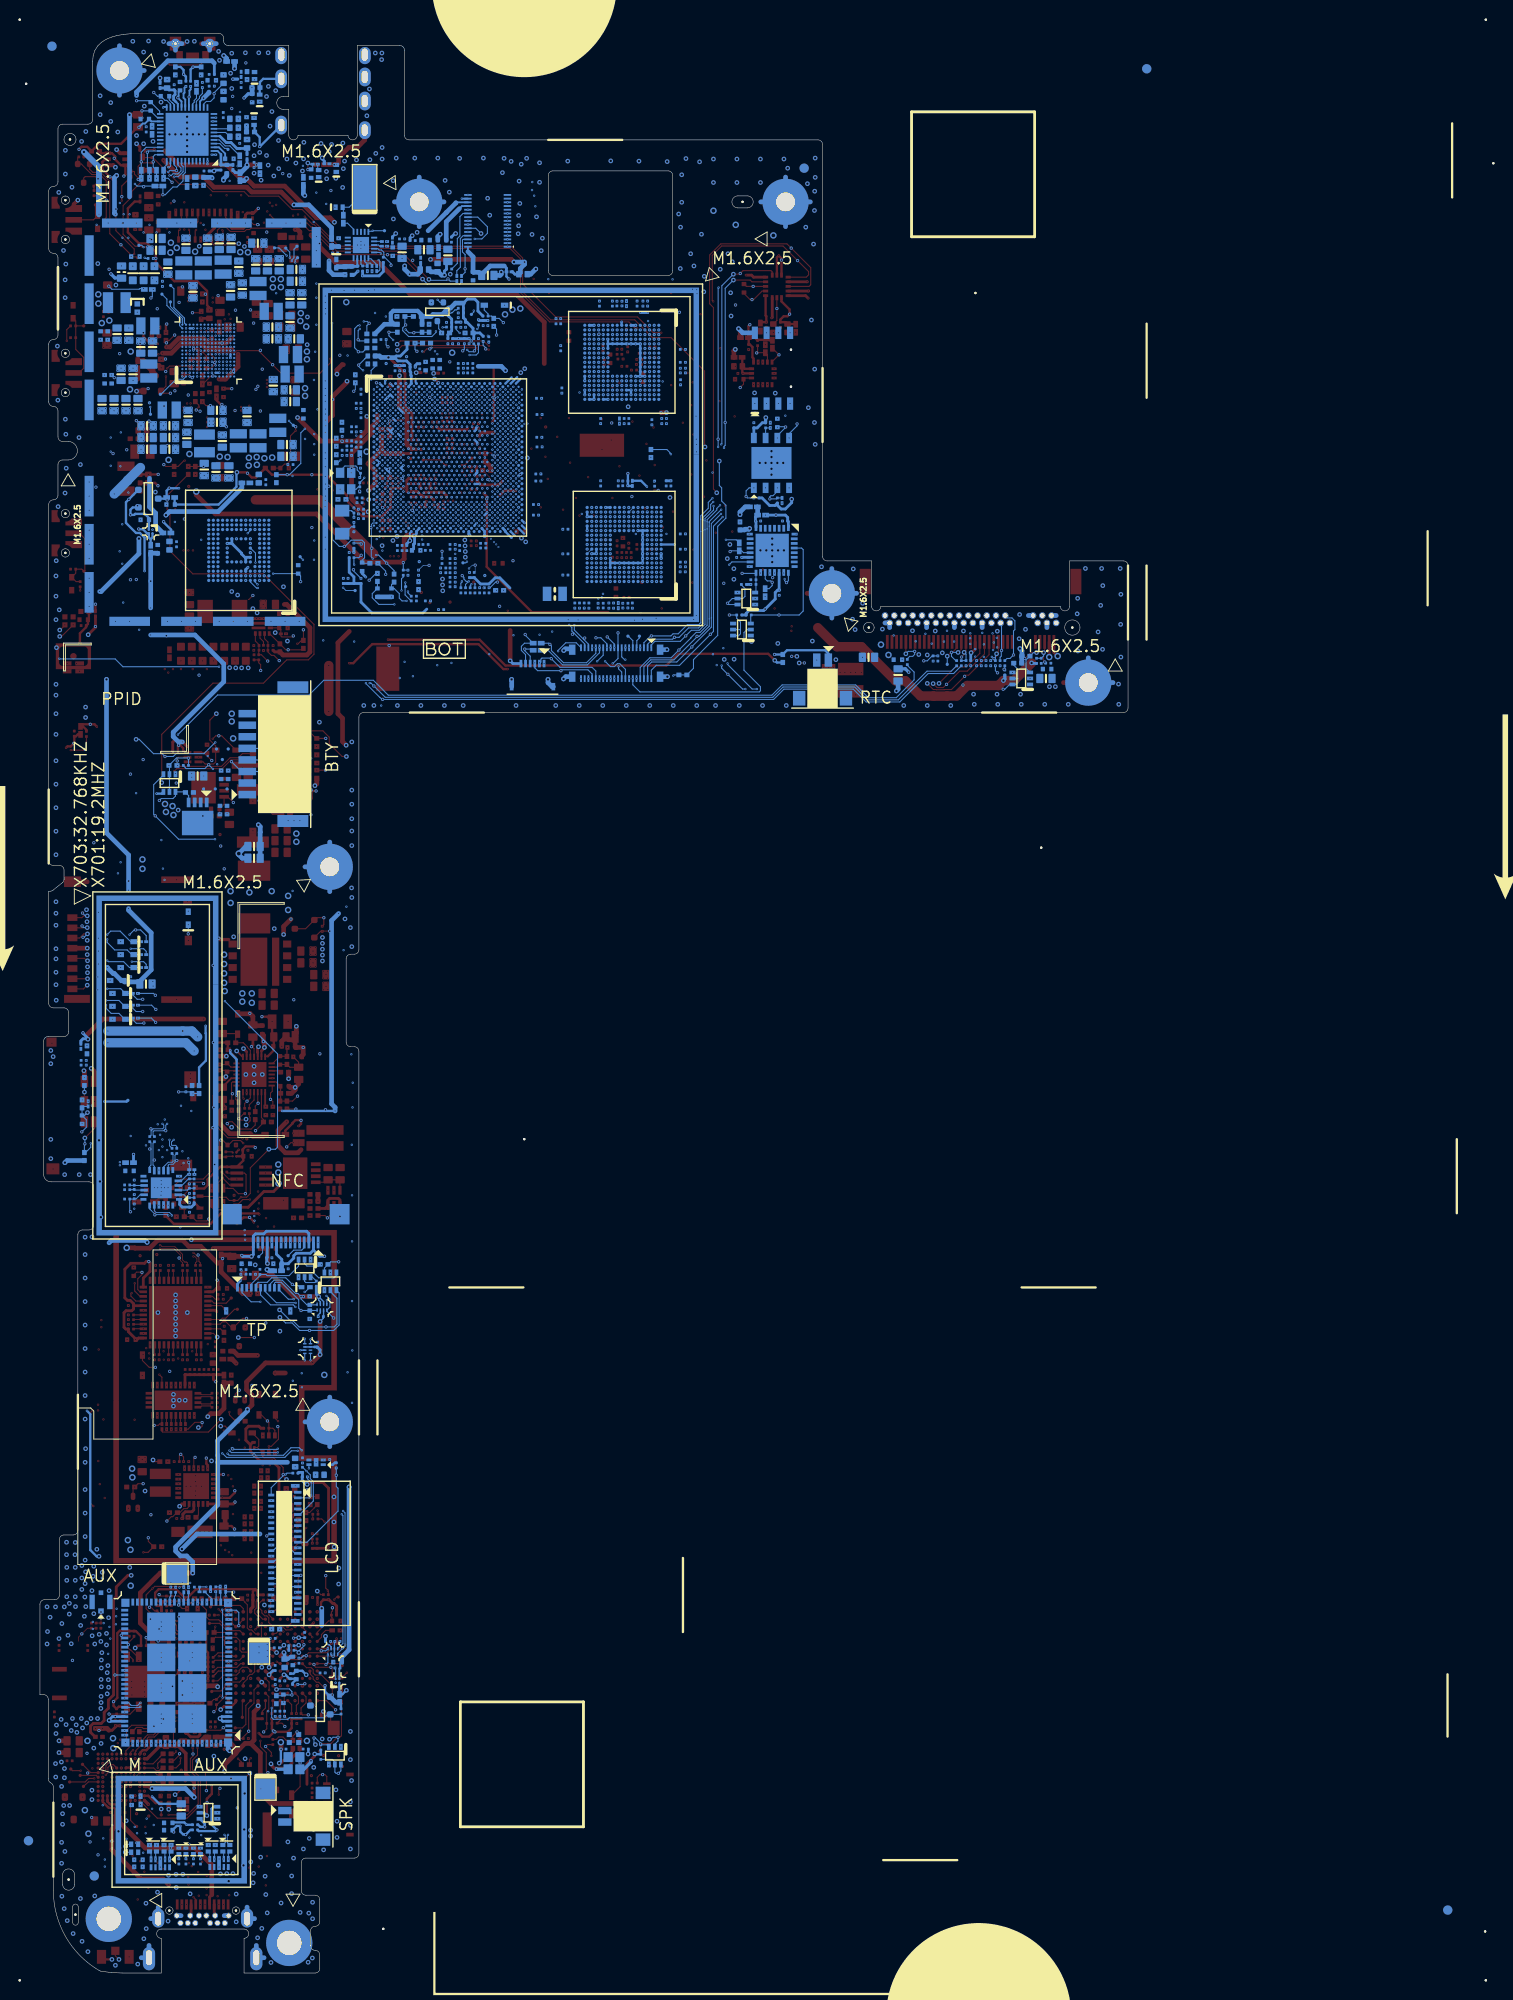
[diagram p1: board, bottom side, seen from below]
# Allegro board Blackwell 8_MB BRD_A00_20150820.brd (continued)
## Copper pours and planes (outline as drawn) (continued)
+V1P8A_MEM on BOTTOM: 49.68,167.8 49.16,168.32 49.16,171.17 49.28,171.29 50.81,171.29 50.89,171.21 50.89,170.47 50.81,170.4 50.6,170.4 50.48,170.28 50.48,169.36 50.58,169.26 50.58,167.86 50.52,167.8 ; 2 cut-outs
+V1P8A_MEM on BOTTOM: 59.88,147.85 59.83,147.89 57.75,147.89 57.67,147.97 57.67,148.03 57.64,148.03 57.39,148.28 57.01,148.28 56.63,148.66 56.63,149.8 57.38,150.56 58.03,150.56 58.16,150.43 58.16,150.18 58.33,150 60.37,150 60.44,149.93 61.46,149.93 61.58,149.8 61.58,149.68 61.58,149.68 61.58,147.85 ; 5 cut-outs
+V1P8A_MEM on L5: 56.25,149.17 51.55,149.17 48.5,152.22 48.5,159.96 49.26,160.73 49.26,169.49 49.39,169.62 49.9,169.62 50.53,168.98 50.53,165.68 50.91,165.3 50.91,164.16 50.53,163.77 50.53,159.96 49.52,158.95 49.52,153.11 51.68,150.95 52.56,150.95 53.33,150.19 55.74,150.19 56.25,149.68
+V1P8A_MEM on L7: 57.39,148.41 56.25,148.41 55.74,148.92 55.74,149.8 55.87,149.93 55.99,149.93 57.39,148.53
+V1P8DVDD_FRONT on TOP: 105.29,187.17 105.29,187.19 104.71,187.78 103.62,187.78 103.62,188.67 103.75,188.79 105.14,188.79 105.27,188.92 106.67,188.92 106.92,188.67 106.92,188.03 106.06,187.17 ; 3 cut-outs
+V1P8SX on TOP: 107.17,188.03 107.17,188.54 106.92,188.79 106.92,189.56 107.56,189.56 107.81,189.3 107.81,188.16 107.68,188.03
+V1P15 on TOP: 70.6,166.57 70.6,167.58 70.34,167.84 69.71,167.84 69.58,167.97 69.58,168.47 69.71,168.6 70.98,168.6 71.49,168.09 71.49,166.82 71.23,166.57 ; 2 cut-outs
+V1P15 on TOP: 70.98,154 70.85,154.12 70.85,155.14 70.98,155.27 71.87,155.27 72,155.14 72,154.12 71.87,154 ; 2 cut-outs
+V1P15 on BOTTOM: 71.44,153.97 71.26,154.15 71.26,155.27 71.64,155.65 71.64,155.93 72.02,156.31 72.12,156.31 72.58,155.85 72.58,154.86 72.43,154.71 72.43,154.1 72.38,154.05 71.89,154.05 71.82,153.97 ; 1 cut-out
+V1P15 on BOTTOM: 72.05,171.25 71.64,171.65 71.64,172.11 72.22,172.69 72.22,175.43 72.5,175.71 73.65,175.71 73.9,175.46 73.9,172.16 73.67,171.93 73.67,171.68 73.6,171.6 73.44,171.6 73.37,171.68 73.09,171.68 73.01,171.6 72.88,171.6 72.78,171.7 72.55,171.7 72.27,171.42 72.27,171.35 72.17,171.25 ; 4 cut-outs
+V1P15 on BOTTOM: 95.36,184.48 94.98,184.86 94.98,185.62 94.22,186.38 94.22,187.4 94.47,187.65 95.49,187.65 96.13,187.02 98.67,187.02 98.79,186.89 98.79,184.48 ; 6 cut-outs
+V1P15 on L2: 82.66,183.84 95.62,183.84 96.38,184.6 96.38,186.13 95.62,186.89 82.03,186.89 68.82,173.68 68.82,166.06 68.06,165.3 68.06,156.92 71.11,153.87 71.87,153.87 72.12,154.12 72.12,155.01 69.58,157.55 69.58,165.17 69.96,165.55 69.96,166.31 70.09,166.44 70.09,171.27
+V2P8SX on BOTTOM: 74.31,184.4 74.15,184.55 74.15,185.77 74.28,185.9 74.76,185.9 75.12,185.54 75.65,185.54 75.86,185.34 75.86,185.11 75.14,184.4 ; 1 cut-out
+V2P85S_EMMC_VCC on BOTTOM: 103.11,154.25 103.11,154.38 102.98,154.5 100.19,154.5 99.81,154.88 99.81,155.52 100.19,155.9 103.87,155.9 104,155.77 104,154.5 103.75,154.25 ; 2 cut-outs
+V3P3_EC on TOP: 88.07,16.2 88,16.28 88,16.99 88.07,17.06 88.45,17.06 88.45,17.72 88.4,17.77 88.05,17.77 87.97,17.85 87.97,20.75 88.02,20.8 88.76,20.8 88.84,20.72 88.84,16.23 88.81,16.2 ; 6 cut-outs
+V3P3_EC on BOTTOM: 87.87,28.01 87.11,28.77 87.11,36.09 87.01,36.19 86.63,36.19 86.52,36.29 86.52,37.31 86.88,37.66 90.92,37.66 91.17,37.41 91.17,37.03 91.68,36.52 91.93,36.52 92.06,36.39 92.82,36.39 92.95,36.27 92.95,36.06 92.75,35.86 92.75,33.32 93.15,33.32 93.2,33.27 93.2,32.96 93.08,32.84 92.7,32.84 92.44,33.09 92.06,33.09 91.93,32.96 91.93,32.33 92.44,31.82 93.71,31.82 93.97,31.57 93.97,31.19 93.71,30.93 92.7,30.93 92.57,31.06 92.57,31.31 92.44,31.44 91.93,31.44 91.81,31.31 91.55,31.31 91.43,31.44 91.43,31.95 91.55,32.08 91.55,32.46 91.43,32.58 90.92,32.58 90.41,33.09 88.76,33.09 88.38,32.71 88.38,32.08 89.65,30.81 90.03,30.81 90.16,30.68 90.16,29.66 90.92,28.9 91.68,28.9 91.81,29.03 91.81,29.28 91.93,29.41 93.97,29.41 94.35,29.03 94.35,28.52 93.84,28.01 ; 16 cut-outs
+V3P3_SAR on BOTTOM: 83.68,184.86 83.55,184.98 83.55,185.62 83.68,185.75 84.82,185.75 84.95,185.87 84.95,186.76 85.08,186.89 85.58,186.89 85.71,186.76 85.71,185.62 85.84,185.49 85.84,184.98 85.71,184.86 ; 2 cut-outs
+V3P3A on TOP: 78.47,151.46 77.71,152.22 77.71,153.74 77.96,154 77.96,154.88 77.71,155.14 76.82,155.14 76.82,157.09 77.86,158.14 77.86,159.02 77.71,159.18 77.71,159.84 77.66,159.89 77.33,159.89 77.3,159.91 77.3,160.19 77.33,160.22 78.47,160.22 78.6,160.09 78.6,157.63 77.58,156.61 77.58,156.28 78.73,155.14 78.73,154 78.47,153.74 78.47,152.98 78.73,152.73 81.77,152.73 87.36,158.31 98.03,158.31 100.32,160.6 100.95,160.6 101.46,160.09 101.46,158.82 99.55,156.92 88,156.92 82.54,151.46
+V3P3A on BOTTOM: 100.32,159.2 99.94,159.58 99.94,161.36 102.48,163.9 103.36,163.9 103.62,164.16 103.62,167.58 103.75,167.71 105.78,167.71 106.03,167.46 106.03,164.16 106.41,163.77 107.05,163.77 107.3,163.52 107.3,161.87 106.92,161.49 105.02,161.49 104.38,162.12 102.98,162.12 101.84,160.98 101.84,159.84 101.21,159.2 ; 9 cut-outs
+V3P3A on BOTTOM: 81.11,167.82 81.01,167.92 81.01,168.1 81.44,168.53 83.3,168.53 83.3,167.97 83.17,167.84 82.03,167.84 81.92,167.94 81.42,167.94 81.29,167.82
+V3P3A on L7: 101.81,172.72 101.81,172.64 102.02,172.43 102.07,172.37 102.14,172.31 102.23,172.3 102.28,172.31 102.53,172.31 105.38,169.45 105.38,169.41 105.42,169.36 105.48,169.31 105.48,169.28 105.55,169.06 105.78,169.02 105.81,169.03 105.9,168.93 105.9,166.82 105.68,166.59 103.85,166.59 103.67,166.77 103.67,169.11 100.82,171.95 100.82,172.45 100.84,172.53 100.82,172.61 100.82,172.85 100.83,172.89 100.84,172.93 100.98,173.07 101.53,173.07 101.6,173.04 101.62,172.97 101.65,172.81 101.78,172.72
+V3P3A on L7: 108.44,88.84 109.08,89.48 110.1,89.48 110.16,89.42 110.22,89.48 111.87,89.48 111.87,88.59 108.95,85.67 108.44,85.67
+V3P3SX on TOP: 89.19,50.41 88.96,50.64 88.96,54.07 90.11,55.21 90.11,63.52 89.65,63.98 86.4,63.98 86.32,64.05 86.32,64.99 86.5,65.17 91.12,65.17 91.6,64.69 91.6,54.68 90.58,53.65 90.58,52.79 90.46,52.67 90.46,51.76 90.38,51.68 90.38,51.15 90.08,50.85 90.08,50.59 89.9,50.41 ; 3 cut-outs
+V3P3SX on BOTTOM: 106.41,169.36 106.08,169.69 105.6,169.69 102.58,172.71 102.58,172.97 102.35,173.2 101.79,173.2 101.71,173.27 101.71,173.4 101.76,173.45 103.11,173.45 104.84,171.72 104.89,171.72 104.91,171.75 106.92,171.75 107.05,171.88 107.05,172.51 107.1,172.56 109.26,172.56 109.69,172.13 111.37,172.13 111.52,171.98 111.52,169.36 ; 12 cut-outs
+V3P3SX on L2: 108.57,171.9 107.56,171.9 106.92,171.27 106.92,170.76 107.56,170.12 107.56,154.63 107.43,154.5 107.43,146.12 104.76,143.45 95.74,143.45 94.86,142.57 93.97,142.57 93.71,142.31 90.66,142.31 90.41,142.57 86.73,142.57 85.97,141.8 85.97,141.04 86.22,140.79 94.86,140.79 95.24,141.17 102.86,141.17 103.11,141.42 105.4,141.42 108.95,144.98 108.95,171.52
+V5P0_BOOST on TOP: 111.24,21.92 111.11,22.04 111.11,23.69 111.24,23.82 111.87,23.82 112.18,24.12 112.18,24.53 112.13,24.58 112.13,25.6 112.25,25.73 113.65,25.73 113.78,25.6 113.78,23.82 114.29,23.31 114.29,22.8 114.03,22.55 112.84,22.55 112.2,21.92 ; 3 cut-outs
+V5P0_BOOST on TOP: 103.49,140.28 102.98,140.79 102.98,142.31 103.24,142.57 104,142.57 104.38,142.18 104.38,140.79 103.87,140.28
+V5P0_BOOST on BOTTOM: 108.32,184.09 108.19,184.22 108.19,184.86 107.94,185.11 107.56,185.11 107.43,185.24 107.43,185.75 107.94,186.25 107.94,187.65 108.06,187.78 109.21,187.78 109.71,187.27 109.71,184.22 109.59,184.09 ; 2 cut-outs
+V5P0_BOOST on BOTTOM: 107.81,189.81 106.79,190.83 102.98,190.83 101.46,192.35 101.46,193.37 102.73,193.37 103.87,192.22 107.94,192.22 108.83,191.33 108.83,190.06 108.57,189.81
+V5P0_BOOST on L2: 103.11,141.17 108.44,141.17 111.87,137.74 112.76,137.74 113.14,137.36 113.14,135.45 112.76,135.07 111.75,135.07 107.43,139.39 104.25,139.39 102.98,140.66 102.98,141.04
+V5P0_BOOST on L7: 107.56,190.32 107.56,187.27 108.95,187.27 109.33,187.65 109.33,189.56 108.95,189.94 108.95,190.32
+V5P0_BOOST_PMIC on BOTTOM: 104.89,182.44 104.76,182.57 104.76,183.46 104.89,183.59 109.33,183.59 109.46,183.46 109.46,182.82 109.08,182.44 ; 1 cut-out
+V5P0_BOOST_PMIC on L7: 101.71,177.21 101.71,177.43 101.74,177.5 101.81,177.52 102.04,177.73 101.81,177.94 101.74,177.97 101.71,178.03 101.71,179.14 104.86,182.29 104.86,183.05 105.14,183.33 106.79,183.33 106.92,183.21 106.92,180.92 105.14,179.14 104.58,179.14 102.65,177.21
+V5P0_BOOST_R on TOP: 94.35,142.31 94.35,143.2 94.6,143.2 94.73,143.33 94.73,143.96 94.6,144.09 94.6,145.11 93.2,145.11 93.2,145.51 95.01,145.51 95.16,145.36 96.51,145.36 97.14,144.72 104,144.72 104.25,144.47 104.25,142.82 104.13,142.69 95.24,142.69 94.86,142.31 ; 8 cut-outs
+VBATA_CHARGER on TOP: 102.6,163.52 101.46,164.66 98.16,164.66 91.81,171.01 91.81,172.16 92.06,172.41 94.6,172.41 98.28,168.73 100.44,168.73 101.21,167.97 103.36,167.97 105.27,166.06 106.41,166.06 106.41,163.77 106.16,163.52 ; 1 cut-out
+VBATA_CHARGER on BOTTOM: 94.75,168.4 94.7,168.45 94.7,169.16 97.67,172.13 97.67,172.61 97.73,172.66 97.9,172.66 97.95,172.61 97.95,171.44 95.74,169.24 95.74,168.45 95.69,168.4
+VBATA_CHARGER on BOTTOM: 92.01,171.72 91.86,171.88 91.86,172.54 91.91,172.59 93.71,172.59 95.39,174.26 97.09,174.26 97.17,174.19 97.17,174.06 97.12,174.01 96.81,174.01 96.76,173.96 96.76,173.68 96.68,173.6 95.87,173.6 93.99,171.72
+VBATA_CHARGER on BOTTOM: 98.16,177.59 98.11,177.64 98.11,178.4 97.13,179.38 96.85,179.38 95.24,181 95.24,181.81 95.36,181.94 96.51,181.94 96.56,181.88 97.12,181.88 97.52,181.48 97.52,180.03 98.77,178.79 98.77,177.67 98.69,177.59 ; 2 cut-outs
+VBATA_CHARGER on BOTTOM: 98.72,167 98.51,167.2 98.51,172.56 98.61,172.66 99.12,172.66 99.15,172.64 99.15,172.44 99.07,172.36 99.07,169.79 99.55,169.31 99.55,167.13 99.43,167 ; 2 cut-outs
+VBATA_CHARGER on BOTTOM: 92.67,176.02 92.52,176.17 92.52,178.3 92.62,178.4 93.46,178.4 95.21,176.65 97.09,176.65 97.14,176.6 97.14,176.09 97.06,176.02 ; 2 cut-outs
+VBATA_CHARGER on L2: 93.46,171.27 92.57,171.27 92.06,171.78 92.06,176.86 93.59,178.38 93.84,178.38 94.86,179.4 94.86,180.28 95.11,180.54 95.87,180.54 96.25,180.16 96.25,178.25 94.09,176.09 94.09,171.9
+VBATA_CHARGER on L3SGND: 96.13,180.03 95.87,179.78 95.11,179.78 94.73,180.16 94.73,181.05 95.11,181.43 95.74,181.43 96.13,181.05
+VBATA_CHARGER on L3SGND: 93.46,172.03 93.46,171.39 93.33,171.27 91.43,171.27 91.3,171.39 91.3,171.75 91.45,171.9 91.55,171.9 92.04,172.38 93.1,172.38
+VBATA_CHARGER on L3SGND: 94.98,169.74 95.74,169.74 96,169.49 96,168.6 95.74,168.35 95.24,168.35 94.86,168.73 94.86,169.62
+VBATA_CHARGER on L3SGND: 98.92,168.47 99.55,168.47 99.81,168.22 99.81,166.95 99.55,166.7 99.05,166.7 98.67,167.08 98.67,168.22
+VBATA_CHARGER on L3SGND: 92.7,178.13 93.71,178.13 93.97,177.87 93.97,176.35 93.84,176.22 92.82,176.22 92.57,176.47 92.57,178
+VBATA_CHARGER on L6SGND: 92.65,178.38 93.36,178.38 93.81,177.92 93.81,176.42 93.48,176.09 92.59,176.09 92.49,176.19 92.49,178.23
+VBATA_CHARGER on L6SGND: 95.49,168.42 95.26,168.42 94.98,168.7 94.98,169.44 95.21,169.67 95.57,169.67 95.79,169.44 95.79,168.73
+VBATA_CHARGER on L6SGND: 92.82,171.39 91.43,171.39 91.3,171.52 91.3,171.9 92.01,172.61 92.75,172.61 92.95,172.41 92.95,171.52
+VBATA_CHARGER on L6SGND: 95.06,180.54 95.06,181.48 95.16,181.58 96.15,181.58 96.18,181.55 96.18,180.44 96.05,180.31 95.29,180.31
+VBATA_CHARGER on L6SGND: 98.74,166.92 98.92,166.75 99.33,166.75 99.45,166.87 99.45,168.17 99.3,168.32 98.92,168.32 98.74,168.14
+VBATA_CHARGER_R on TOP: 107.43,162.25 107.17,162.5 106.54,162.5 106.54,163.27 106.79,163.52 106.79,165.3 106.67,165.43 106.67,166.06 107.43,166.06 107.56,166.19 107.56,167.08 107.3,167.33 104.63,167.33 103.87,168.09 101.97,168.09 101.08,168.98 101.08,170.12 100.82,170.38 99.17,170.38 98.79,170.76 98.28,170.76 98.16,170.89 98.16,171.39 98.28,171.52 98.92,171.52 99.17,171.27 101.33,171.27 101.46,171.14 102.73,171.14 103.49,170.38 106.92,170.38 107.56,171.01 107.56,174.57 107.17,174.95 107.17,179.01 106.92,179.27 101.33,179.27 100.57,180.03 100.57,180.92 100.95,181.3 103.11,181.3 103.24,181.43 106.41,181.43 106.67,181.68 111.75,181.68 112.38,181.05 112.38,178.51 112.25,178.38 112.25,177.62 112.38,177.49 112.38,169.49 110.98,168.09 110.98,162.76 110.48,162.25 ; 11 cut-outs
+VBATA_CHARGER_R on BOTTOM: 100.6,177.59 100.47,177.72 100.47,181.33 100.6,181.45 101.54,181.45 101.64,181.35 101.64,180 100.93,179.29 100.93,178.4 100.77,178.25 100.77,177.69 100.67,177.59
+VBATA_CHARGER_R on BOTTOM: 107,174.57 106.92,174.65 104.91,174.65 104.76,174.8 101.79,174.8 101.71,174.87 101.71,175.38 101.79,175.46 104.66,175.46 104.79,175.59 107.02,175.59 107.16,175.72 107.17,175.71 108.06,175.71 108.19,175.59 108.19,174.7 108.06,174.57
+VBATA_CHARGER_R on BOTTOM: 109.74,179.27 109.69,179.32 109.69,181.73 109.71,181.76 110.04,181.76 110.22,181.94 111.52,181.94 111.7,181.76 111.7,180.11 110.86,179.27
+VBATA_CHARGER_R on BOTTOM: 101.1,168.42 100.99,168.54 100.99,169.45 99.71,170.73 99.71,172.99 99.78,173.07 99.88,173.07 99.96,172.99 99.96,171.52 102.14,169.34 102.14,168.5 102.07,168.42
+VBATA_CHARGER_R on L3SGND: 101.71,167.97 101.46,167.97 101.08,168.35 101.08,169.62 101.21,169.74 102.09,169.74 102.22,169.62 102.22,168.47
+VBATA_CHARGER_R on L3SGND: 101.59,181.81 101.84,181.55 101.84,180.67 101.59,180.41 100.82,180.41 100.7,180.54 100.7,181.55 100.95,181.81
+VBATA_CHARGER_R on L6SGND: 101.21,169.29 102.04,169.29 102.12,169.21 102.12,168.3 101.87,168.04 101.41,168.04 101.1,168.35 101.1,169.18
+VBATA_CHARGER_R on L6SGND: 101.64,181.63 101.64,180.67 101.51,180.54 100.77,180.54 100.57,180.74 100.57,181.68 100.7,181.81 101.46,181.81
+VBATT_SW on TOP: 100.44,124.79 99.81,125.42 98.92,125.42 98.54,125.8 98.54,129.74 98.67,129.87 102.35,129.87 104.63,127.58 104.63,125.42 104,124.79 ; 1 cut-out
+VBATT_SW on BOTTOM: 98.92,122.75 98.79,122.88 98.79,125.55 98.92,125.67 101.59,125.67 102.6,126.69 104.25,126.69 104.63,126.31 104.63,124.79 102.6,122.75
+VBATT_SW on L3SGND: 104.76,123.77 101.59,123.77 101.08,124.28 101.08,126.06 102.86,127.83 102.86,134.82 99.43,138.25 75.42,138.25 75.17,137.99 31.79,137.99 31.66,138.12 31.66,141.09 31.79,141.22 33.11,141.22 33.41,140.91 67.42,140.91 68.31,140.03 77.58,140.03 77.84,140.28 102.6,140.28 106.41,136.47 106.41,125.42
+VBATTERY on BOTTOM: 94.22,125.8 93.59,126.44 93.59,128.72 93.97,129.1 96.38,129.1 96.63,129.36 98.28,129.36 98.67,129.74 100.32,129.74 100.44,129.61 100.44,129.23 101.33,128.34 101.33,127.33 101.21,127.2 101.21,125.8 ; 10 cut-outs
+VCC0_CPU on TOP: 89.78,177.36 89.52,177.62 88.25,177.62 88.12,177.74 88.12,178.63 88.76,179.27 88.76,179.52 89.01,179.78 90.56,179.78 90.77,179.57 90.77,177.44 90.69,177.36 ; 1 cut-out
+VCC0_CPU on TOP: 73.01,167.46 72.76,167.71 72.76,169.62 73.01,169.87 74.41,169.87 74.41,170.3 74.43,170.3 74.43,170.51 74.41,170.51 74.41,170.76 76.19,172.54 76.19,174.06 77.08,174.95 79.11,174.95 79.23,174.82 79.23,174.32 77.84,172.92 77.84,171.04 74.64,167.84 74.54,167.84 74.15,167.46 ; 7 cut-outs
+VCC0_CPU on BOTTOM: 88.73,177.36 88.4,177.69 88.4,180.46 88.73,180.79 92.16,180.79 92.47,180.49 92.47,178.68 92.29,178.51 91.38,178.51 91.17,178.3 90.16,178.3 89.98,178.13 89.98,177.57 89.78,177.36 ; 8 cut-outs
+VCC0_CPU on BOTTOM: 71.61,166.5 71.54,166.57 71.54,166.83 71.59,166.88 71.59,167.39 71.56,167.41 71.56,167.69 71.28,167.97 71.28,168.12 71.39,168.22 73.19,168.22 73.54,167.87 73.54,167.28 73.11,166.85 73.11,166.65 72.96,166.5
+VCC0_CPU on BOTTOM: 75.4,171.25 75.32,171.32 75.32,171.5 75.53,171.7 75.53,171.96 75.68,172.11 75.68,173.55 75.73,173.6 76.8,173.6 77.28,173.12 77.28,172.77 76.8,172.28 76.8,171.63 76.95,171.47 76.72,171.25 ; 1 cut-out
+VCC0_CPU on L2: 74.28,167.84 74.41,167.97 75.93,167.97 79.93,171.97 80.44,171.97 84.95,176.47 88.25,176.47 89.65,177.87 89.65,179.78 89.52,179.9 83.55,179.9 72.76,169.11 72.76,168.09 73.01,167.84
+VCC0_CPU on L3SGND: 72.71,166.88 72.48,166.88 72.02,167.33 71.61,167.33 71.49,167.46 71.49,167.74 71.64,167.89 72.25,167.89 72.38,168.02 72.38,168.07 72.48,168.17 72.48,168.75 72.78,169.06 74,169.06 74.26,168.8 74.26,167.89 73.75,167.39 73.21,167.39
+VCC0_CPU on L6SGND: 71.69,166.5 72.91,166.5 72.99,166.57 72.99,166.75 73.57,167.33 73.57,167.82 73.19,168.2 71.97,168.2 71.49,167.72 71.49,167.51 71.77,167.23 71.77,166.88 71.59,166.7 71.59,166.6
+VCC0_CPU on L7: 72.88,166.5 71.66,166.5 71.59,166.57 71.59,166.72 71.87,167 71.87,167.26 71.59,167.54 71.59,167.84 71.94,168.2 73.16,168.2 73.24,168.12 73.24,167.99 72.99,167.74 72.99,167.41 73.24,167.16 73.24,167.03 72.99,166.78 72.99,166.6
+VCC1_CPU on TOP: 71.36,164.03 71.11,164.28 71.11,165.17 71.49,165.55 73.14,165.55 73.27,165.43 73.27,164.16 73.14,164.03 ; 2 cut-outs
+VCC1_CPU on BOTTOM: 71.54,163.61 71.45,163.7 71.45,163.9 71.28,164.08 71.28,164.39 71.47,164.58 71.47,164.9 71.24,165.13 71.24,165.3 71.38,165.44 73.13,165.44 73.27,165.3 73.27,165.09 73.05,164.88 73.05,164.62 73.25,164.42 73.25,163.97 72.9,163.61
+VCC1_CPU on BOTTOM: 74.18,167.82 73.62,168.38 73.62,168.65 73.71,168.74 73.93,168.74 74,168.67 74.2,168.67 74.2,168.68 74.54,169.01 74.54,170.94 74.1,171.37 74.1,173.02 74.11,173.03 74.11,173.67 74.18,173.73 75.45,173.73 75.55,173.63 75.55,172.21 75.36,172.02 75.36,171.72 75.17,171.53 75.17,171.27 75.37,171.07 75.37,168.38 74.81,167.82 ; 1 cut-out
+VCC1_CPU on BOTTOM: 90.16,184.6 94.73,184.6 94.98,184.35 94.98,182.19 94.86,182.06 93.08,182.06 92.82,181.81 91.43,181.81 91.05,182.19 90.16,182.19 89.9,182.44 89.9,184.35 ; 3 cut-outs
+VCC1_CPU on L2: 72.48,166.21 72.48,167.18 72.63,167.33 72.63,169.24 83.5,180.11 91.63,180.11 92.95,181.43 92.95,183.21 92.57,183.59 82.66,183.59 70.22,171.14 70.22,166.06 70.85,165.43 70.85,164.66 71.39,164.13 73.06,164.13 73.19,164.26 73.19,165.5
+VCC1_CPU on L3SGND: 71.28,163.65 71.26,163.65 71.13,163.78 71.13,164.46 70.83,164.77 70.83,164.87 71.64,165.68 71.94,165.68 72.15,165.48 73.11,165.48 73.24,165.35 73.24,163.88 72.96,163.6 71.33,163.6
+VCC1_CPU on L6SGND: 72.93,163.68 71.61,163.68 71.49,163.8 71.49,164.01 71.31,164.18 71.31,164.34 71.46,164.49 71.46,165 71.33,165.12 71.33,165.25 71.41,165.33 73.16,165.33 73.24,165.25 73.24,165.12 73.04,164.92 73.04,164.52 73.24,164.31 73.24,164.21 73.06,164.03 73.06,163.8
+VCC1_CPU on L7: 72.86,163.65 71.69,163.65 71.31,164.03 71.31,164.34 71.51,164.54 71.51,164.97 71.33,165.15 71.33,165.28 71.41,165.35 73.14,165.35 73.24,165.25 73.24,165.07 72.99,164.82 72.99,164.59 73.24,164.34 73.24,164.03
+VCC1_CPU on L7: 74.05,167.92 74.81,167.92 75.35,168.45 75.35,171.6 75.83,172.08 75.83,173.46 75.63,173.66 75.37,173.66 74.97,173.25 74.97,171.63 74.79,171.45 74.79,169.9 74.54,169.65 74.54,169.01 74.23,168.71 73.7,168.71 73.62,168.63 73.62,168.35
+VDD3V3_WIFI on TOP: 100.32,26.49 100.32,26.87 98.16,26.87 97.65,27.38 97.65,27.76 98.41,28.52 102.98,28.52 103.11,28.39 103.11,27.12 102.98,27 102.48,27 101.97,27.5 101.59,27.5 101.33,27.25 101.33,26.61 101.21,26.49 ; 6 cut-outs
+VDD3V3_WIFI on TOP: 104.89,27 104.76,27.12 104.76,27.5 105.27,28.01 107.43,28.01 107.81,27.63 110.22,27.63 110.35,27.5 110.35,27.12 110.22,27
+VDD3V3_WIFI on L2: 102.48,27.12 105.4,27.12 105.52,27.25 105.52,27.63 105.4,27.76 102.48,27.76 102.35,27.63 102.35,27.25
+VDDQ_PMIC on TOP: 68.19,164.66 66.15,166.7 66.15,172.41 65.39,173.17 65.39,180.03 66.53,181.17 77.46,181.17 80.5,184.22 85.71,184.22 87.24,185.75 94.6,185.75 95.49,186.63 98.16,186.63 98.26,186.74 99.78,186.74 100.19,187.14 102.98,187.14 103.24,187.4 104.25,187.4 104.76,186.89 104.76,184.86 102.86,182.95 100.82,182.95 99.3,181.43 97.4,181.43 95.74,179.78 93.84,179.78 93.71,179.65 92.19,179.65 91.93,179.9 88.89,179.9 88.51,179.52 88.51,179.27 85.71,176.47 68.82,176.47 68.19,175.84 68.19,172.16 67.93,171.9 67.93,166.95 68.95,165.93 70.6,165.93 70.73,165.81 70.73,164.92 70.47,164.66 ; 21 cut-outs
+VDDQ_PMIC on BOTTOM: outline of 216 points within 47.13,146.76 67.93,181.3 ; 58 cut-outs
+VDDQ_PMIC on BOTTOM: 81.44,158.47 81.32,158.59 81.32,158.82 81.42,158.92 81.7,158.92 81.75,158.87 82.23,158.87 82.38,159.02 82.38,159.48 81.72,160.15 81.42,160.15 80.99,160.58 80.99,160.76 81.06,160.83 81.24,160.83 81.52,160.55 82.64,160.55 82.64,160.55 82.74,160.45 82.74,159.76 82.97,159.53 82.97,158.74 82.69,158.47
+VDDQ_PMIC on BOTTOM: 99.17,184.48 99.05,184.6 99.05,186.89 99.24,187.08 100.15,187.08 100.32,187.24 100.87,187.24 101.15,186.96 102.4,186.96 103.21,187.78 103.75,187.78 104,188.03 104.63,188.03 104.91,187.75 104.91,185.06 104.33,184.48 ; 10 cut-outs
+VDDQ_PMIC on BOTTOM: 53.51,172.25 53.46,172.3 53.46,172.81 53.13,173.14 53.13,175.22 53.38,175.48 56.25,175.48 56.48,175.25 56.48,174.67 56.17,174.36 56.17,174.03 56.48,173.73 56.48,172.33 56.4,172.25 55.06,172.25 54.68,172.63 54.24,172.63 53.86,172.25
+VDDQ_PMIC on BOTTOM: 52.95,152.74 52.77,152.92 52.77,155.26 53.28,155.77 53.28,156.07 53.35,156.15 53.68,156.15 53.99,155.84 54.32,155.84 54.62,156.15 56.07,156.15 56.12,156.1 56.12,155.74 55.74,155.36 55.74,155.23 55.84,155.13 56.07,155.13 56.17,155.03 56.17,154.72 56.1,154.65 55.77,154.65 55.69,154.57 55.69,153.73 55.79,153.63 56,153.63 56.15,153.48 56.15,153.25 56.02,153.12 55.74,153.12 55.36,152.74
+VDDQ_PMIC on BOTTOM: 81.37,166.42 80.99,166.8 80.99,166.95 81.37,167.33 81.9,167.33 82.03,167.46 82.03,167.46 82.08,167.51 82.08,167.53 82.28,167.74 83.17,167.74 83.55,168.12 83.55,169.34 82.76,169.34 82.1,168.68 81.85,168.68 81.85,168.68 81.54,168.68 81.32,168.45 81.16,168.45 81.09,168.53 81.09,168.66 81.34,168.91 81.34,170.05 82.31,171.02 83.55,171.02 83.55,180.28 84.19,180.92 84.95,180.92 85.2,180.67 85.2,178.18 85.48,177.9 85.48,175.15 85.2,174.87 85.2,167.18 84.83,166.81 84.82,166.82 82.79,166.82 82.41,166.44 82.16,166.44 82.13,166.42 ; 8 cut-outs
+VDDQ_PMIC on L2: 70.22,165.55 70.62,165.55 70.75,165.43 70.75,164.64 71.33,164.05 73.11,164.05 73.32,164.26 73.32,165.76 73.54,165.98 73.72,165.98 73.82,165.88 73.82,163.6 73.39,163.16 70.95,163.16 70.7,162.91 70.7,161.64 70.62,161.56 70.29,161.56 70.04,161.82 70.04,162.17 69.71,162.5 69.71,165.04
+VDDQ_PMIC on L3SGND: 69.53,166.01 70.55,166.01 70.98,165.58 70.98,165.25 70.73,164.99 70.04,164.99 69.46,165.58 69.46,165.93
+VDDQ_PMIC on L3SGND: 73.72,164.06 73.52,164.06 73.34,164.24 73.34,166.42 73.47,166.54 73.65,166.54 73.95,166.24 73.95,166.17 74,166.12 74,165.48 73.72,165.2 73.72,164.52 73.85,164.39 73.85,164.18
+VDDQ_PMIC on L5: 99.05,177.11 98.94,177.11 98.39,177.67 98.08,177.67 97.93,177.52 97.93,176.86 98.51,176.27 98.72,176.27 98.92,176.47 98.94,176.47 99.15,176.68 99.15,177.01
+VDDQ_VTT on TOP: 53.96,149.3 53.2,150.06 51.93,150.06 51.42,150.57 51.42,152.98 52.06,153.61 52.06,154.63 52.31,154.88 53.63,154.88 53.69,154.82 53.69,154.34 53.76,154.27 54.11,154.27 54.24,154.4 54.24,154.6 54.62,154.6 54.75,154.48 55.54,154.48 55.76,154.71 55.76,154.99 55.84,155.06 56.07,155.06 56.12,155.01 56.12,153.87 55.49,153.23 55.99,153.23 55.99,151.96 63.61,151.96 66.15,154.5 66.15,155.39 63.99,157.55 63.99,161.87 65.39,163.27 65.39,164.54 64.25,165.68 64.25,170.51 61.45,173.3 57.39,173.3 56.5,172.41 52.44,172.41 52.06,172.79 52.06,174.82 51.42,175.46 51.42,176.09 53.33,176.09 53.58,176.35 54.6,176.35 55.1,176.86 55.1,177.87 55.36,178.13 58.79,178.13 60.18,176.73 60.57,176.73 65.9,171.39 65.9,166.7 67.42,165.17 67.42,163.14 66.41,162.12 66.41,158.69 68.57,156.54 68.57,152.98 64.88,149.3 ; 33 cut-outs
+VDDR3_M0_ODQVREF on BOTTOM: 55.74,167.33 55.32,167.75 55.28,167.71 54.77,167.71 54.68,167.81 53.79,167.81 53.74,167.86 53.74,168.16 53.75,168.18 53.75,169.28 53.99,169.52 53.99,170.08 54.14,170.22 54.32,170.22 54.42,170.12 54.42,169.69 55.5,168.61 55.5,168.08 55.99,167.58 55.99,167.46 55.87,167.33 ; 2 cut-outs
+VIN_5V_19V on TOP: 109.33,22.93 109.21,23.06 109.21,23.31 109.08,23.44 108.83,23.44 108.7,23.57 108.7,25.6 108.95,25.85 110.1,25.85 110.22,25.73 110.22,23.95 110.1,23.82 110.1,23.57 109.97,23.44 109.71,23.44 109.59,23.31 109.59,23.06 109.46,22.93
+VIN_5V_19V on TOP: 88.17,83.89 88.12,83.94 88.12,84.63 88.71,85.21 88.71,87.98 88.86,88.13 91.93,88.13 92.19,87.88 92.19,84.88 92.14,84.83 89.62,84.83 88.68,83.89 ; 1 cut-out
+VIN_5V_19V on BOTTOM: 106.77,45.33 106.54,45.56 106.54,52.4 106.29,52.65 104.76,52.65 101.33,56.08 101.33,58.87 99.83,60.38 99.83,73.88 90.59,83.12 90.59,87.5 91.02,87.93 93.31,87.93 93.74,87.5 93.74,85.29 95.63,83.4 95.62,83.38 95.62,81.1 96,80.72 97.52,80.72 98.03,80.21 98.03,79.57 99.17,78.43 102.48,78.43 105.27,75.64 105.27,57.73 105.4,57.6 107.81,57.6 109.46,55.95 109.46,45.54 109.26,45.33
+VIN_5V_19V on L3SGND: 110.1,23.82 109.08,23.82 107.05,25.85 107.05,26.61 105.65,28.01 105.65,46.3 106.54,47.19 108.44,47.19 108.95,46.68 108.95,28.52 109.71,27.76 109.71,26.49 110.35,25.85 110.35,24.07
+VIN_5V_19V on L7: 94.22,82.49 94.22,79.45 94.73,78.94 95.62,78.94 95.74,79.07 95.74,81.99 95.11,82.62 94.35,82.62
GND on TOP (solid shape): 109.68,61.87 109.08,61.87 109.08,79.7 86.12,79.7 86.12,63.55 89.62,63.55 89.62,55.35 86.12,55.35 86.12,44.85 109.08,44.85 109.08,61.87 109.68,61.87 109.68,44.25 85.52,44.25 85.52,55.95 89.02,55.95 89.02,62.95 85.52,62.95 85.52,80.3 109.68,80.3
GND on BOTTOM (solid shape): 87.07,145.99 46.37,145.99 46.37,164.06 46.97,164.06 46.97,146.59 86.47,146.59 86.47,181.54 46.97,181.54 46.97,164.08 46.37,164.08 46.37,182.14 87.07,182.14
GND on BOTTOM (solid shape): 104,20.72 95.84,20.72 95.84,10.26 108.84,10.26 108.84,20.72 104.02,20.72 104.02,21.32 109.44,21.32 109.44,9.66 95.24,9.66 95.24,21.32 104,21.32
GND on BOTTOM (solid shape): 111.52,79.7 98.32,79.7 98.32,106.77 98.92,106.77 98.92,80.3 110.92,80.3 110.92,115.85 98.92,115.85 98.92,106.79 98.32,106.79 98.32,116.45 111.52,116.45
GND on TOP: 100.06,187.27 99.94,187.4 99.94,187.95 99,188.89 99,189.1 99.01,189.11 99.01,189.21 98.67,189.56 98.28,189.56 98.28,190.95 96.76,190.95 96.63,190.83 96.63,189.81 96.51,189.68 95.87,189.68 95.11,190.44 94.47,190.44 94.35,190.32 94.35,190.06 94.47,189.94 94.73,189.94 94.86,189.81 94.86,188.79 94.73,188.67 91.68,188.67 91.3,189.05 89.78,189.05 89.39,189.43 89.39,190.19 89.65,190.44 90.41,190.44 91.93,191.97 95.24,191.97 95.49,192.22 99.3,192.22 99.55,191.97 99.55,190.19 99.81,189.94 100.32,189.94 100.57,189.68 100.57,189.56 100.7,189.56 100.7,191.33 100.95,191.59 106.16,191.59 106.79,190.95 107.43,190.95 107.68,190.7 107.68,189.81 107.56,189.68 106.79,189.68 106.16,189.05 105.14,189.05 105.02,188.92 103.62,188.92 102.88,188.18 102.25,188.18 102.22,188.16 102.22,187.27 101.84,187.27 101.84,188.31 101.66,188.49 100.65,188.49 100.57,188.41 100.57,187.27 ; 8 cut-outs
GND on TOP: outline of 354 points within 0.51,0.51 117.11,209.09 ; 118 cut-outs
GND on TOP: 87.74,185.87 87.49,186.13 87.49,186.51 87.87,186.89 89.14,186.89 89.39,187.14 93.84,187.14 94.09,187.4 94.78,187.4 94.98,187.19 95.31,187.19 95.34,187.17 95.34,186.86 94.6,186.13 94.6,186 94.47,185.87 ; 10 cut-outs
GND on TOP: 104.25,173.05 104,173.3 104,173.55 104.25,173.81 104.63,173.81 105.9,175.08 105.9,177.11 105.65,177.36 104.13,177.36 103.87,177.62 102.73,177.62 102.22,177.11 98.28,177.11 98.16,176.98 97.27,176.98 96.76,177.49 96.76,179.01 97.65,179.9 98.67,179.9 98.79,179.78 98.79,179.52 99.05,179.27 99.81,179.27 99.94,179.14 106.41,179.14 106.92,178.63 106.92,175.08 104.89,173.05 ; 10 cut-outs
GND on TOP: 104.13,29.54 103.87,29.79 103.87,34.62 104,34.74 104.89,34.74 104.89,33.47 105.02,33.35 108.57,33.35 108.57,29.79 108.32,29.54
GND on TOP: 84.82,161.36 84.19,162 84.19,164.79 86.98,164.79 88,165.81 90.16,165.81 90.41,165.55 90.41,163.39 90.79,163.01 90.92,163.01 91.17,162.76 91.17,162.38 91.05,162.25 86.47,162.25 85.58,161.36 ; 2 cut-outs
GND on TOP: outline of 102 points within 68.82,157.68 82.82,174.82 ; 21 cut-outs
GND on TOP: 74.54,157.81 74.41,157.93 74.41,159.08 74.03,159.46 74.03,159.58 74.15,159.71 74.66,159.71 74.79,159.58 74.79,159.08 74.92,158.95 75.3,158.95 75.55,158.69 75.55,158.06 75.3,157.81 ; 3 cut-outs
GND on TOP: 92.44,146.2 92.44,146.5 92.7,146.76 92.7,148.03 93.08,148.41 94.6,148.41 94.86,148.15 94.86,147.14 94.73,147.01 94.73,146.2 ; 2 cut-outs
GND on TOP: 91.05,177.36 90.96,177.45 90.96,179.56 91.05,179.65 91.81,179.65 91.93,179.52 93.59,179.52 93.71,179.65 94.86,179.65 94.86,178.89 93.71,177.74 92.37,177.74 91.98,177.36 ; 4 cut-outs
GND on BOTTOM: 65.82,166.72 65.54,167 65.01,167 64.78,167.23 64.78,167.56 65.11,167.89 65.52,167.89 65.72,168.1 65.72,168.4 65.65,168.48 65.65,168.71 65.67,168.73 65.92,168.73 65.98,168.68 65.98,168.12 66.58,167.51 66.58,167.41 66.48,167.31 66.41,167.31 65.9,167.82 65.82,167.82 65.62,167.61 65.62,167.33 66.05,166.9 66.05,166.8 65.98,166.72
GND on BOTTOM: 76.95,173.3 76.44,173.81 75.55,173.81 75.42,173.93 74.15,173.93 74.15,175.84 74.79,176.47 75.53,176.47 75.91,176.09 76.69,176.09 77.33,175.46 77.33,173.43 77.2,173.3 ; 5 cut-outs
GND on BOTTOM: 81.44,165.27 81.34,165.37 81.34,165.55 81.6,165.81 83.53,165.81 83.68,165.96 83.68,166.26 83.58,166.36 82.76,166.36 82.71,166.42 82.71,166.67 82.79,166.75 84.49,166.75 84.67,166.57 84.67,165.43 84.52,165.27 ; 2 cut-outs
GND on BOTTOM: 83.02,156.99 82.94,157.07 82.94,158.59 83.04,158.69 83.04,159.58 82.89,159.74 82.89,160.12 82.94,160.17 83.35,160.17 83.45,160.07 83.45,159.68 83.55,159.58 83.55,158.82 83.4,158.67 83.4,157.93 83.43,157.91 83.43,157.04 83.37,156.99
GND on BOTTOM: 69.93,187.58 69.71,187.79 69.69,187.87 69.74,187.94 69.9,188.08 69.96,188.28 69.99,188.34 70.05,188.37 70.82,188.37 70.82,188.32 71.87,188.32 71.87,187.98 70.82,187.98 70.82,187.72 70.79,187.65 70.71,187.64 70.57,187.64 70.45,187.58
GND on BOTTOM: 69.69,188.65 69.65,188.66 69.58,188.72 69.61,188.81 70.36,189.57 70.82,189.57 70.82,189.52 71.87,189.52 71.87,188.78 70.82,188.78 70.82,188.73 69.77,188.73
GND on BOTTOM: 105.52,197.3 105.27,197.56 104.25,197.56 104.25,199.08 105.9,199.08 106.03,199.21 107.3,199.21 107.56,198.95 107.56,197.43 107.43,197.3 ; 1 cut-out
GND on BOTTOM: 84.36,163.06 84.34,163.09 84.34,163.62 84.21,163.75 83.86,163.75 83.76,163.85 83.76,164.16 83.81,164.21 85.1,164.21 85.2,164.1 85.2,163.19 85.08,163.06 ; 1 cut-out
GND on BOTTOM: 82.03,185.85 82.03,187.32 81.95,187.4 81.14,187.4 81.14,187.65 84.67,187.65 84.67,187.4 83.91,187.4 83.81,187.29 83.81,185.87 83.78,185.85
GND on BOTTOM: 65.82,162.76 65.54,163.04 65.44,163.04 65.06,163.42 64.83,163.42 64.71,163.55 64.71,163.9 65.42,164.61 65.64,164.61 65.82,164.79 65.95,164.79 66.05,164.69 66.05,164.54 65.92,164.41 65.92,164.18 66.28,163.82 66.28,163.7 66.23,163.65 66.18,163.65 65.92,163.39 65.92,163.12 66.05,162.99 66.05,162.84 65.98,162.76
GND on BOTTOM: 75.93,152.98 75.81,153.11 75.81,153.87 76.06,154.12 76.06,155.9 75.93,156.03 75.93,156.15 76.06,156.28 76.19,156.28 76.57,155.9 76.57,155.01 76.82,154.76 76.82,153.61 77.08,153.36 77.58,153.36 77.71,153.49 77.71,153.74 77.84,153.87 79.49,153.87 79.87,154.25 79.87,155.39 79.36,155.9 79.36,156.15 80.12,156.15 80.38,155.9 80.76,155.9 80.89,156.03 80.89,156.15 80.76,156.28 80.76,156.41 80.89,156.54 81.65,156.54 81.77,156.41 81.77,154.63 80.12,152.98 ; 6 cut-outs
GND on BOTTOM: 64.38,149.93 64.25,150.06 64.25,156.15 65.26,157.17 65.52,157.17 65.65,157.04 65.65,156.54 66.28,155.9 67.17,155.9 67.55,156.28 67.58,156.28 68.06,155.8 68.26,155.8 68.54,156.08 68.54,156.21 68.64,156.31 68.77,156.31 68.9,156.18 68.9,156.11 69.09,155.92 69.34,155.92 69.71,156.28 69.96,156.28 69.96,156.03 69.71,155.77 69.71,155.14 69.58,155.01 69.58,153.49 70.47,152.6 71.74,152.6 72,152.34 72,150.95 70.98,149.93 ; 3 cut-outs
GND on BOTTOM: 65.37,170.43 65.06,170.74 65.06,172.99 64.93,173.12 64.93,173.45 65.38,173.9 65.39,173.9 65.39,173.93 68.06,176.6 68.06,177.24 68.31,177.49 69.33,177.49 69.58,177.24 69.58,176.22 70.47,175.33 71.74,175.33 72.12,174.95 72.12,173.93 71.11,173.93 71.11,174.06 70.85,174.32 69.96,174.32 69.58,173.93 69.58,172.95 69.66,172.87 69.66,172.11 69.89,171.88 69.89,171.63 70.01,171.5 70.01,171.32 69.94,171.25 69.79,171.25 69.66,171.37 69.66,171.45 69.4,171.7 69.12,171.7 68.72,171.3 68.69,171.3 68.31,171.68 67.96,171.68 67.73,171.45 67.73,171.32 67.68,171.27 67.47,171.27 67.4,171.35 67.4,171.5 67.22,171.68 67.22,171.67 66.33,171.67 65.65,170.99 65.65,170.51 65.57,170.43
GND on BOTTOM: outline of 271 points within 0.51,0.51 117.11,209.09 ; 139 cut-outs
GND on BOTTOM: 97.4,165.81 97.4,169.36 97.52,169.49 98.16,169.49 98.28,169.36 98.28,167.08 98.41,166.95 98.41,165.93 98.28,165.81
GND on BOTTOM: 75.02,185.75 74.94,185.82 74.94,186.76 74.84,186.86 74.36,186.86 74.28,186.94 74.28,187.45 74.05,187.68 74.05,188.21 74.13,188.29 75.04,188.29 75.93,187.4 75.93,185.87 75.81,185.75 ; 3 cut-outs
GND on BOTTOM: 72.25,153.11 72,153.36 72,153.74 72.12,153.87 72.38,153.87 72.5,154 72.5,154.5 72.88,154.5 72.88,153.23 72.76,153.11 ; 1 cut-out
GND on BOTTOM: 65.82,159.36 65.54,159.64 65.34,159.64 65.11,159.41 64.78,159.41 64.71,159.49 64.71,159.82 65.44,160.55 65.54,160.55 65.82,160.83 65.95,160.83 66.05,160.73 66.05,160.58 65.95,160.48 65.85,160.48 65.54,160.17 65.54,160.04 65.77,159.82 65.98,159.82 66.38,160.22 66.51,160.22 66.58,160.15 66.58,159.99 65.95,159.36
GND on BOTTOM: 76.85,164.1 76.72,164.23 76.72,166.29 76.49,166.52 76.49,166.82 75.93,167.38 75.02,167.38 74.89,167.51 74.89,167.81 75.3,168.22 78.45,168.22 78.73,167.94 78.73,167.53 78.09,166.9 78.07,166.9 78.01,166.85 78.01,164.41 77.71,164.1
GND on BOTTOM: 71.18,171.6 71.08,171.7 71.08,174.01 71.23,174.16 72.02,174.16 72.1,174.09 72.1,172.71 71.51,172.13 71.51,171.7 71.41,171.6 ; 3 cut-outs
GND on L2: 85.27,147.33 88.12,150.19 88.12,151.58 92.19,155.65 99.43,155.65 100.44,154.63 100.44,153.61 100.32,153.49 100.32,152.47 100.95,151.84 104.51,151.84 105.78,153.11 107.05,153.11 107.17,152.98 107.17,146.38 104.63,143.84 87.11,143.84 85.27,145.68
GND on L2: 50.02,176.47 49.52,176.47 46.34,173.3 46.34,168.73 46.72,168.35 47.1,168.35 50.15,171.39 50.15,176.35
GND on L2: 89.78,33.22 88.89,33.22 87.49,31.82 87.49,30.68 85.71,28.9 85.71,25.85 86.73,24.84 87.87,24.84 89.27,26.23 89.27,28.39 90.41,29.54 90.41,32.58
GND on L2: 107.68,19.88 108.19,19.88 108.7,20.39 109.33,20.39 109.71,20.01 110.1,20.01 110.22,20.14 110.22,22.3 109.97,22.55 109.51,22.55 109.28,22.32 108.7,22.32 108.06,21.69 108.06,20.52 107.81,20.26 107.68,20.26 107.56,20.14 107.56,20.01
GND on L2: 87.62,164.92 87.11,165.43 87.11,166.57 89.01,168.47 89.01,171.78 88.89,171.9 88.89,172.28 90.54,173.93 90.54,179.14 91.17,179.78 94.6,179.78 94.73,179.65 94.73,179.4 93.84,178.51 92.95,178.51 91.81,177.36 91.81,171.52 92.32,171.01 93.46,171.01 94.22,171.78 94.22,176.09 96.38,178.25 96.38,180.54 95.62,181.3 95.62,183.46 96.13,183.97 97.52,183.97 99.05,182.44 99.17,182.44 99.3,182.57 101.59,182.57 102.09,182.06 102.09,176.47 100.06,174.44 100.06,173.17 99.81,172.92 99.81,170.89 101.46,169.24 101.46,165.3 101.08,164.92
GND on L2: outline of 169 points within 0.51,0.51 117.11,209.09 ; 17 cut-outs
GND on L3SGND: outline of 151 points within 0.51,0.51 117.11,209.09 ; 2 cut-outs
GND on L4SGND: outline of 151 points within 0.51,0.51 117.11,209.09 ; 1 cut-out
GND on L5: outline of 170 points within 0.51,0.51 117.11,209.09 ; 3 cut-outs
GND on L5: 91.43,152.09 94.47,152.09 96,150.57 96.13,150.57 97.4,149.3 97.4,133.55 96.89,133.04 96.51,133.04 96.13,133.42 96.13,135.07 96,135.2 93.71,135.2 90.28,138.63 90.28,143.58 90.66,143.96 90.66,151.33
GND on L5: 76.14,162.18 75.07,162.18 74.33,161.44 74.33,161.26 74.94,160.65 76.49,160.65 76.9,160.25 76.9,159.74 76.39,159.23 71.92,159.23 71.44,159.71 69.96,159.71 69.3,160.37 69.3,160.73 69,160.73 68.9,160.83 68.9,163.65 69.76,164.52 74.18,164.52 74.51,164.85 76.21,164.85 76.97,164.08 77.5,164.08 77.56,164.03 77.56,163.6 ; 3 cut-outs
GND on L6SGND: outline of 151 points within 0.51,0.51 117.11,209.09 ; 2 cut-outs
GND on L7: 90.05,100.4 96.76,100.4 99.3,102.94 99.3,120.34 102.22,123.26 102.22,127.2 103.62,128.6 103.62,130.88 101.08,133.42 98.28,133.42 97.4,132.53 94.98,132.53 93.71,133.8 93.71,134.44 93.2,134.95 90.79,134.95 89.9,134.06 89.9,131.52 90.66,130.75 91.93,130.75 92.06,130.63 92.06,130.5 91.81,130.25 91.05,130.25 90.54,129.74 88.51,129.74 87.74,128.98 87.74,123.64 90.16,121.23 90.16,107.79 89.64,107.27 89.64,100.82
GND on L7: outline of 429 points within 0.51,0.51 117.11,209.09 ; 3 cut-outs
GND on L7: 50.41,148.41 46.6,152.22 46.6,161.87 46.09,162.38 46.09,165.43 47.67,167.01 47.67,176.92 48.12,177.36 48.12,178.89 48.63,179.4 49.64,179.4 50.02,179.01 50.02,174.82 48.75,173.55 48.75,164.54 49.01,164.28 49.01,162.25 48.75,162 48.75,157.42 50.15,156.03 50.41,156.03 50.79,155.65 50.79,155.52 52.56,155.52 52.69,155.39 52.69,155.01 52.06,154.38 52.06,150.95 52.44,150.57 54.22,150.57 54.47,150.31 54.47,148.53 54.34,148.41
GND on L7: 99.43,58.41 99.43,69.16 102.35,72.08 105.78,72.08 106.41,71.45 106.41,65.73 106.67,65.48 106.67,56.79 105.8,55.93 101.92,55.93
GND on L7: 104.76,74.62 104.13,74.62 102.22,76.53 102.22,80.08 101.21,81.1 101.21,87.96 102.98,89.73 102.98,91.26 104,92.27 104.76,92.27 105.02,92.02 105.02,88.46 105.9,87.57 105.9,86.56 105.65,86.3 105.65,83.51 105.9,83.26 105.9,82.37 105.02,81.48 105.02,74.87
GND on L7: 42.91,163.9 42.91,163.65 39.48,160.22 39.48,159.33 36.94,156.79 36.94,155.01 36.69,154.76 36.69,149.55 37.58,148.66 37.96,148.66 38.85,149.55 38.85,150.95 40.25,150.95 42.15,149.04 42.4,149.04 42.91,149.55 42.91,151.84 43.67,152.6 43.67,155.14 43.17,155.65 43.17,156.66 43.93,157.42 43.93,160.35 43.29,160.98 43.29,163.9
GND on L7: outline of 201 points within 65.75,156.62 81.77,170.36 ; 19 cut-outs
GND on L7: 57.52,148.53 58.41,148.53 58.66,148.79 65.52,148.79 70.09,153.36 70.34,153.36 70.47,153.23 70.47,153.11 66.92,149.55 66.92,148.92 66.41,148.41 62.34,148.41 61.33,147.39 55.36,147.39 55.36,147.65 55.61,147.9 57.01,147.9 57.52,148.41
GND_L on L7: 93.08,36.9 92.57,36.9 92.44,37.03 92.44,37.28 92.57,37.41 92.57,38.3 92.32,38.55 92.32,40.33 92.44,40.46 92.82,40.46 93.08,40.2 93.08,39.31 93.33,39.06 93.33,37.16
V1P05A_LX on BOTTOM: 90.59,171.85 90.59,173.76 90.66,173.83 93.36,173.83 94.58,175.05 96.71,175.05 96.76,175 96.76,174.47 96.71,174.42 95.41,174.42 93.71,172.71 91.88,172.71 91.73,172.56 91.73,171.95 91.63,171.85
V1P8A_LX on BOTTOM: 102.17,175.61 102.09,175.69 102.09,176.17 102.2,176.27 103.39,176.27 103.87,176.75 103.87,176.78 104,176.91 104,178.25 104.71,178.96 105.95,178.96 105.95,177.01 105.85,176.91 105.04,176.91 104.84,176.7 104.84,176.42 104.04,175.62 103.3,175.62 103.29,175.61 ; 1 cut-out
V1P15_LX on BOTTOM: 99,178 98.89,178.1 98.89,178.81 97.65,180.06 97.65,182.9 97.47,183.08 96.94,183.08 96.89,183.13 96.89,184.12 98.77,184.12 98.87,184.02 98.87,179.93 99.55,179.24 99.55,178.07 99.48,178
V3P3A_LX1 on BOTTOM: 102.37,167.94 102.25,168.07 102.25,169.49 100.09,171.65 100.09,172.97 100.19,173.07 100.27,173.07 100.37,172.97 100.37,172.41 102.96,169.82 103.39,169.82 103.39,167.94 ; 1 cut-out
V3P3A_LX2 on BOTTOM: 103.75,167.97 103.64,168.07 103.64,169.62 103.29,169.97 103.03,169.97 100.9,172.11 100.9,172.99 100.98,173.07 101.08,173.07 101.15,172.99 101.15,172.49 101.31,172.33 101.79,172.33 101.97,172.16 101.97,172.14 102.94,172.14 104.94,170.15 104.94,167.97 ; 1 cut-out
V3P3SX_LX1 on BOTTOM: 104.61,173.3 103.75,174.16 102.5,174.16 102.27,174.39 101.79,174.39 101.69,174.49 101.69,174.57 101.79,174.67 104.41,174.67 104.66,174.42 106.82,174.42 106.84,174.39 106.84,173.38 106.77,173.3
V3P3SX_LX2 on BOTTOM: 104.93,171.86 103.19,173.6 101.76,173.6 101.69,173.68 101.69,173.78 101.76,173.86 102.27,173.86 102.45,174.04 103.64,174.04 104.84,172.84 106.74,172.84 106.74,171.86
V5P0A_LX on BOTTOM: 102.2,176.4 102.09,176.5 102.09,176.96 102.2,177.06 102.35,177.06 102.46,177.17 102.46,178.66 103.72,179.92 103.72,180.13 104.89,181.3 106.79,181.3 107.3,181.81 108.85,181.81 108.93,181.73 108.93,179.29 108.85,179.22 104.81,179.22 103.85,178.25 103.85,177.11 103.14,176.4
VCC0_LX on BOTTOM: 95.29,176.8 93.53,178.56 92.92,178.56 92.85,178.63 92.85,180.54 93.86,180.54 93.92,180.49 93.92,179.85 96.3,177.46 96.68,177.46 96.76,177.39 96.76,176.88 96.68,176.8 ; 1 cut-out
VCC1_LX on BOTTOM: 97.37,178 97.29,178.07 97.29,178.18 97.08,178.39 95.53,178.39 94.02,179.9 94.02,180.59 93.97,180.64 93.56,180.64 93.46,180.74 93.13,180.74 93.13,181.81 94.98,181.81 95.13,181.66 95.13,180.92 96.76,179.29 97.06,179.29 97.19,179.17 97.24,179.17 97.95,178.46 97.95,178.07 97.88,178
VDD_3G_LTE_3P3 on TOP: 25.26,141.8 24.88,142.18 24.88,144.6 27.04,144.6 27.55,144.09 27.55,143.45 25.89,141.8
VDD_3G_LTE_3P3 on BOTTOM: 24.37,140.15 24.24,140.28 24.24,141.04 24.88,141.68 24.88,143.07 25.77,143.96 27.55,143.96 28.05,143.45 28.05,140.91 27.29,140.15 ; 8 cut-outs
VDD_3G_LTE_3P3 on BOTTOM: 7.61,138.5 6.97,139.14 6.97,140.79 6.84,140.91 6.84,142.69 7.1,142.95 8.37,142.95 8.88,142.44 8.88,142.06 8.62,141.8 8.62,141.3 8.75,141.17 8.75,139.52 8.88,139.39 8.88,138.88 8.5,138.5 ; 5 cut-outs
VDD_3G_LTE_3P3 on L3SGND: 25.26,141.3 25.26,142.44 24.5,143.2 13.96,143.2 12.43,141.68 12.43,139.64 11.04,138.25 7.99,138.25 7.48,138.76 7.48,139.39 7.73,139.64 10.27,139.64 11.04,140.41 11.04,143.2 11.54,143.71 12.31,143.71 13.19,144.6 25.13,144.6 25.77,143.96 26.91,143.96 29.96,140.91 31.36,140.91 31.36,137.99 28.56,137.99
VDD_TP_3V3 on TOP: 93.71,73.86 93.59,73.99 93.59,76.53 93.84,76.78 94.6,76.78 95.11,76.27 95.11,74.62 95.24,74.49 95.24,73.99 95.11,73.86 ; 4 cut-outs
VDD_TP_3V3 on BOTTOM: 95.11,73.65 95.11,74.65 94.6,75.15 94.6,75.76 93.84,75.76 93.71,75.89 93.71,76.27 94.35,76.91 95.36,76.91 95.36,76.39 95.6,76.14 95.6,74.68 95.41,74.49 95.41,73.65 ; 5 cut-outs
VDDQ_LX0 on BOTTOM: 99.76,178 99.71,178.05 99.71,179.29 98.96,180.04 98.96,184.06 99.05,184.14 100.9,184.14 100.93,184.12 100.93,183.23 100.34,182.65 100.34,178.05 100.29,178
VDDQ_LX1 on BOTTOM: 101,178 100.9,178.1 100.9,178.23 101,178.33 101,179.14 101.71,179.85 101.71,183.1 101.18,183.1 101.13,183.15 101.13,184.09 101.18,184.14 103.01,184.14 103.01,179.7 101.81,178.51 101.81,178.33 101.48,178
+VGG on TOP: 94.09,162.5 93.59,163.01 91.55,163.01 91.17,163.39 90.79,163.39 90.79,164.41 90.92,164.54 94.09,164.54 94.47,164.16 95.11,164.16 95.36,163.9 95.36,162.63 95.24,162.5 ; 1 cut-out
+VGG on TOP: 97.65,162.5 97.4,162.76 97.4,163.14 97.14,163.39 97.14,163.52 97.01,163.65 97.01,164.03 97.52,164.54 101.59,164.54 101.84,164.28 101.84,163.77 101.46,163.39 99.94,163.39 99.05,162.5 ; 2 cut-outs
+VGG on TOP: 79.36,154.5 77.66,156.2 77.66,156.59 78.4,157.32 78.57,157.32 79.49,156.41 80.89,156.41 81.27,156.79 82.41,156.79 84.82,159.2 84.82,159.71 86.09,160.98 87.49,160.98 88,160.47 88,160.09 82.66,154.76 80.5,154.76 80.25,154.5 ; 3 cut-outs
+VGG on TOP: 71.11,159.84 70.73,160.22 70.73,162.89 70.85,163.01 71.49,163.01 71.74,162.76 74.66,162.76 75.17,162.25 75.17,160.35 75.04,160.22 73.01,160.22 72.63,159.84 ; 7 cut-outs
+VGG on BOTTOM: 91.17,162.63 90.78,163.02 90.78,165.79 90.92,165.93 90.92,167.08 92.95,167.08 92.95,165.68 93.08,165.55 102.22,165.55 102.22,164.16 100.7,162.63 ; 19 cut-outs
+VGG on BOTTOM: 71.06,159.79 70.7,160.15 70.7,160.6 70.9,160.81 70.9,161.04 70.67,161.26 70.67,161.49 70.93,161.75 70.93,162 70.7,162.23 70.7,162.43 70.93,162.66 70.93,162.97 70.73,163.17 70.73,163.35 70.83,163.45 72.05,163.45 72.5,162.99 73.8,162.99 73.95,163.14 73.95,163.3 74.15,163.5 74.51,163.5 74.94,163.93 75.68,163.93 75.98,163.63 75.98,163.17 75.73,162.91 75.73,162.51 75.35,162.13 75.35,161.57 75.75,161.16 75.75,160.76 75.6,160.6 75.6,160.3 75.81,160.1 75.81,159.87 75.73,159.79 75.53,159.79 75.12,160.2 74.94,160.2 74.56,159.82 74.43,159.82 74.03,160.22 73.37,160.22 72.93,159.79
+VGG on BOTTOM: 78.35,154.12 78.09,154.38 78.09,154.76 78.04,154.81 78.04,154.91 77.81,155.14 77.81,155.78 77.56,156.03 77.56,156.22 77.67,156.32 77.84,156.32 78.26,155.9 78.5,155.9 78.9,156.31 79.01,156.31 79.36,155.96 79.36,155.65 79.74,155.27 79.74,154.25 79.62,154.12 ; 2 cut-outs
+VGG on L2: 75.17,161.84 75.17,161.36 75.93,160.6 79.87,160.6 80,160.73 80,161.49 81.27,162.76 82.79,162.76 84.7,164.66 101.59,164.66 101.84,164.41 101.84,162.12 97.2,157.49 90.22,157.49 89.65,156.92 87.62,156.92 83.55,152.85 80.63,152.85 80,153.49 74.03,153.49 71.11,156.41 71.11,159.2 71.14,159.24 71.14,161.48 70.83,161.79 70.83,162.89 70.95,163.01 73.52,163.01 73.53,163.02 74.36,163.02 75.07,162.31 75.07,161.95
+VGG on L3SGND: 71.21,160.07 71.21,162.22 70.75,162.68 70.75,163.4 70.83,163.47 74.92,163.47 75.02,163.37 75.02,162.91 75.5,162.43 75.5,162.23 75.09,161.82 75.09,160.93 75.47,160.55 75.47,160.27 75.04,159.84 72.33,159.84 72.32,159.84 71.9,159.84 71.89,159.84 71.44,159.84
+VGG on L6SGND: 72.88,159.82 71.16,159.82 70.8,160.17 70.8,163.4 70.9,163.5 71.61,163.5 71.74,163.37 71.74,163.12 71.92,162.94 72.6,162.94 72.86,163.19 72.86,163.4 72.99,163.52 75.83,163.52 75.98,163.37 75.98,163.22 75.7,162.94 75.7,162.56 75.32,162.18 75.32,161.62 75.43,161.52 75.43,161.26 75.73,160.95 75.73,160.83 75.53,160.63 75.53,160.25 75.7,160.07 75.7,159.87 75.65,159.82 75.45,159.82 75.4,159.86 75.4,159.86 75.27,159.99 75.27,160.07 75.14,160.19 74.89,160.19 74.79,160.09 74.79,159.91 74.69,159.82 74.48,159.82 74.1,160.2 73.27,160.2
+VGG on L7: 71.06,159.79 72.93,159.79 73.37,160.22 74.03,160.22 74.43,159.82 74.56,159.82 74.94,160.2 75.12,160.2 75.53,159.79 75.73,159.79 75.81,159.87 75.81,160.1 75.6,160.3 75.6,160.6 75.75,160.76 75.75,161.16 75.35,161.57 75.35,162.13 75.73,162.51 75.73,162.91 75.98,163.17 75.98,163.63 75.68,163.93 74.94,163.93 74.51,163.5 74.15,163.5 73.95,163.3 73.95,163.14 73.8,162.99 72.5,162.99 72.05,163.45 70.83,163.45 70.73,163.35 70.73,163.17 70.93,162.97 70.93,162.66 70.7,162.43 70.7,162.23 70.93,162 70.93,161.75 70.67,161.49 70.67,161.26 70.9,161.04 70.9,160.81 70.7,160.6 70.7,160.15
+VNN on TOP: 88.51,174.06 88.38,174.19 88.38,175.84 88.63,176.09 90.03,176.09 90.16,175.97 90.16,175.08 89.14,174.06 ; 1 cut-out
+VNN on BOTTOM: 81.88,156.89 81.72,157.04 81.72,157.05 81.62,157.15 81.05,157.15 81,157.2 81,157.33 81.08,157.42 81.17,157.42 81.41,157.65 81.41,157.92 81.32,158.01 81.32,158.14 81.55,158.36 82.79,158.36 82.84,158.31 82.84,156.95 82.79,156.89 ; 2 cut-outs
+VNN on BOTTOM: 88.4,173.93 88.4,176.63 88.89,177.11 89.9,177.11 90.16,176.86 90.16,176.09 90.41,175.84 90.41,174.06 90.28,173.93 ; 2 cut-outs
+VNN on BOTTOM: 76.06,159.77 75.96,159.87 75.96,160.07 75.7,160.32 75.7,160.5 75.91,160.71 75.91,161.14 75.42,161.62 75.42,162.13 75.83,162.53 75.83,162.86 76.03,163.07 76.03,163.7 75.68,164.06 74.61,164.06 74.54,164.13 74.54,164.31 74.69,164.46 75.22,164.46 75.27,164.52 75.27,164.82 75.09,165 74.08,165 73.57,165.51 72.68,165.51 72.6,165.58 72.6,165.79 72.48,165.91 71.89,165.91 71.72,166.09 71.72,166.27 71.84,166.39 72.71,166.39 72.78,166.32 72.78,166.12 72.99,165.91 73.21,165.91 73.42,166.12 73.42,166.37 73.9,166.85 74.23,166.85 74.69,167.32 75.87,167.32 76.42,166.77 76.42,166.42 76.59,166.24 76.59,165.96 76.43,165.8 76.43,165.53 76.6,165.37 76.6,165.03 76.43,164.86 76.43,164.63 76.58,164.48 76.58,164.08 76.41,163.9 76.41,163.65 76.58,163.48 76.58,163.18 76.39,162.99 76.39,162.68 76.59,162.48 76.59,162.26 76.51,162.17 76.02,162.17 75.94,162.1 75.94,161.53 76.32,161.16 76.32,160.74 76.11,160.53 76.11,160.33 76.29,160.15 76.29,159.82 76.24,159.77 ; 1 cut-out
+VNN on L2: 74.41,165.68 74.41,165.55 74.79,165.17 74.92,165.17 75.3,164.79 75.3,164.66 75.73,164.23 75.73,163.34 75.87,163.2 77.14,163.2 78.85,164.92 78.85,165.55 81.52,168.22 82.28,168.22 86.22,172.16 87.24,172.16 89.39,174.32 89.39,175.84 89.01,176.22 84.95,176.22 80.5,171.78 80,171.78 75.68,167.46 73.14,167.46 72.58,166.9 72.58,166.26 72.73,166.11 73.98,166.11
+VNN on L3SGND: 75.14,163.14 75.14,163.45 74.81,163.78 74.81,163.98 75.27,164.44 75.27,165.02 74.81,165.48 74.28,165.48 74.13,165.63 74.13,166.14 74,166.27 74,166.32 73.75,166.57 73.42,166.57 73.29,166.45 73.29,165.94 72.96,165.61 72.15,165.61 72.02,165.73 72.02,166.06 72.93,166.98 74.05,166.98 74.2,166.83 74.2,166.52 74.43,166.29 74.81,166.29 74.94,166.42 74.94,167.18 75.02,167.26 76.39,167.26 76.39,167.26 76.72,167.26 76.85,167.13 76.85,164.13 76.95,164.03 76.95,163.65 77.2,163.39 77.2,163.01 76.9,162.71 75.58,162.71
+VNN on L6SGND: 76.47,166.04 74.31,166.04 73.82,165.56 72.2,165.56 71.87,165.89 71.87,166.22 71.94,166.29 73.37,166.29 73.93,166.85 74.31,166.85 74.69,167.23 75.96,167.23 76.29,166.9 76.29,166.9 76.67,166.9 76.82,166.75 76.82,166.39
+VNN on L6SGND: 76.16,161.82 76.16,161.19 76.33,161.02 76.33,160.9 76.54,160.68 76.54,160.37 76.26,160.1 76.26,159.92 76.19,159.84 76.06,159.84 75.98,159.92 75.98,160.12 75.73,160.37 75.73,160.5 75.86,160.63 75.86,160.88 75.47,161.26 75.47,162.13 75.81,162.46 75.81,162.84 76.11,163.14 76.11,163.52 76.01,163.63 74.99,163.63 74.61,164.01 74.61,164.29 74.71,164.39 75.2,164.39 75.45,164.64 75.45,165.02 75.53,165.1 75.53,165.28 75.65,165.4 76.39,165.4 76.49,165.3 76.49,165 76.41,164.92 76.41,164.46 76.74,164.13 76.74,163.19 76.85,163.09 76.85,162.51
+VNN on L7: 76.29,159.82 76.29,160.15 76.11,160.33 76.11,160.53 76.32,160.74 76.32,161.16 75.94,161.53 75.94,161.96 76.16,162.17 76.51,162.17 76.59,162.26 76.59,162.48 76.39,162.68 76.39,162.99 76.58,163.18 76.58,163.48 76.58,163.48 76.58,164.07 76.58,164.08 76.58,164.48 76.51,164.55 76.51,164.95 76.6,165.03 76.6,165.37 76.43,165.53 76.43,165.8 76.59,165.96 76.59,166.24 76.42,166.42 76.42,166.77 75.87,167.32 74.69,167.32 74.23,166.85 73.9,166.85 73.42,166.37 73.42,166.12 73.21,165.91 72.99,165.91 72.78,166.12 72.78,166.32 72.71,166.39 71.84,166.39 71.72,166.27 71.72,166.09 71.89,165.91 72.48,165.91 72.6,165.79 72.6,165.58 72.68,165.51 73.57,165.51 74.08,165 75.09,165 75.27,164.82 75.27,164.52 75.22,164.46 74.69,164.46 74.54,164.31 74.54,164.13 74.61,164.06 75.68,164.06 76.03,163.7 76.03,163.07 75.83,162.86 75.83,162.53 75.42,162.13 75.42,161.62 75.91,161.14 75.91,160.71 75.7,160.5 75.7,160.32 75.96,160.07 75.96,159.87 76.06,159.77 76.24,159.77
+VSDIO on TOP: 102.6,173.81 101.59,174.82 101.59,175.33 101.71,175.46 102.48,175.46 103.24,174.7 104.89,174.7 104.89,174.06 104.63,173.81
+VSDIO on TOP: 77.96,149.8 76.31,151.46 76.31,153.61 75.55,154.38 75.55,157.93 75.68,158.06 75.68,159.08 75.81,159.2 76.06,159.2 76.31,158.95 76.31,155.52 76.82,155.01 77.58,155.01 77.84,154.76 77.84,154.12 77.46,153.74 77.46,151.84 78.47,150.82 82.28,150.82 88.12,156.66 100.32,156.66 102.22,158.57 102.98,158.57 103.36,158.19 103.36,157.55 101.08,155.27 88.25,155.27 82.79,149.8
